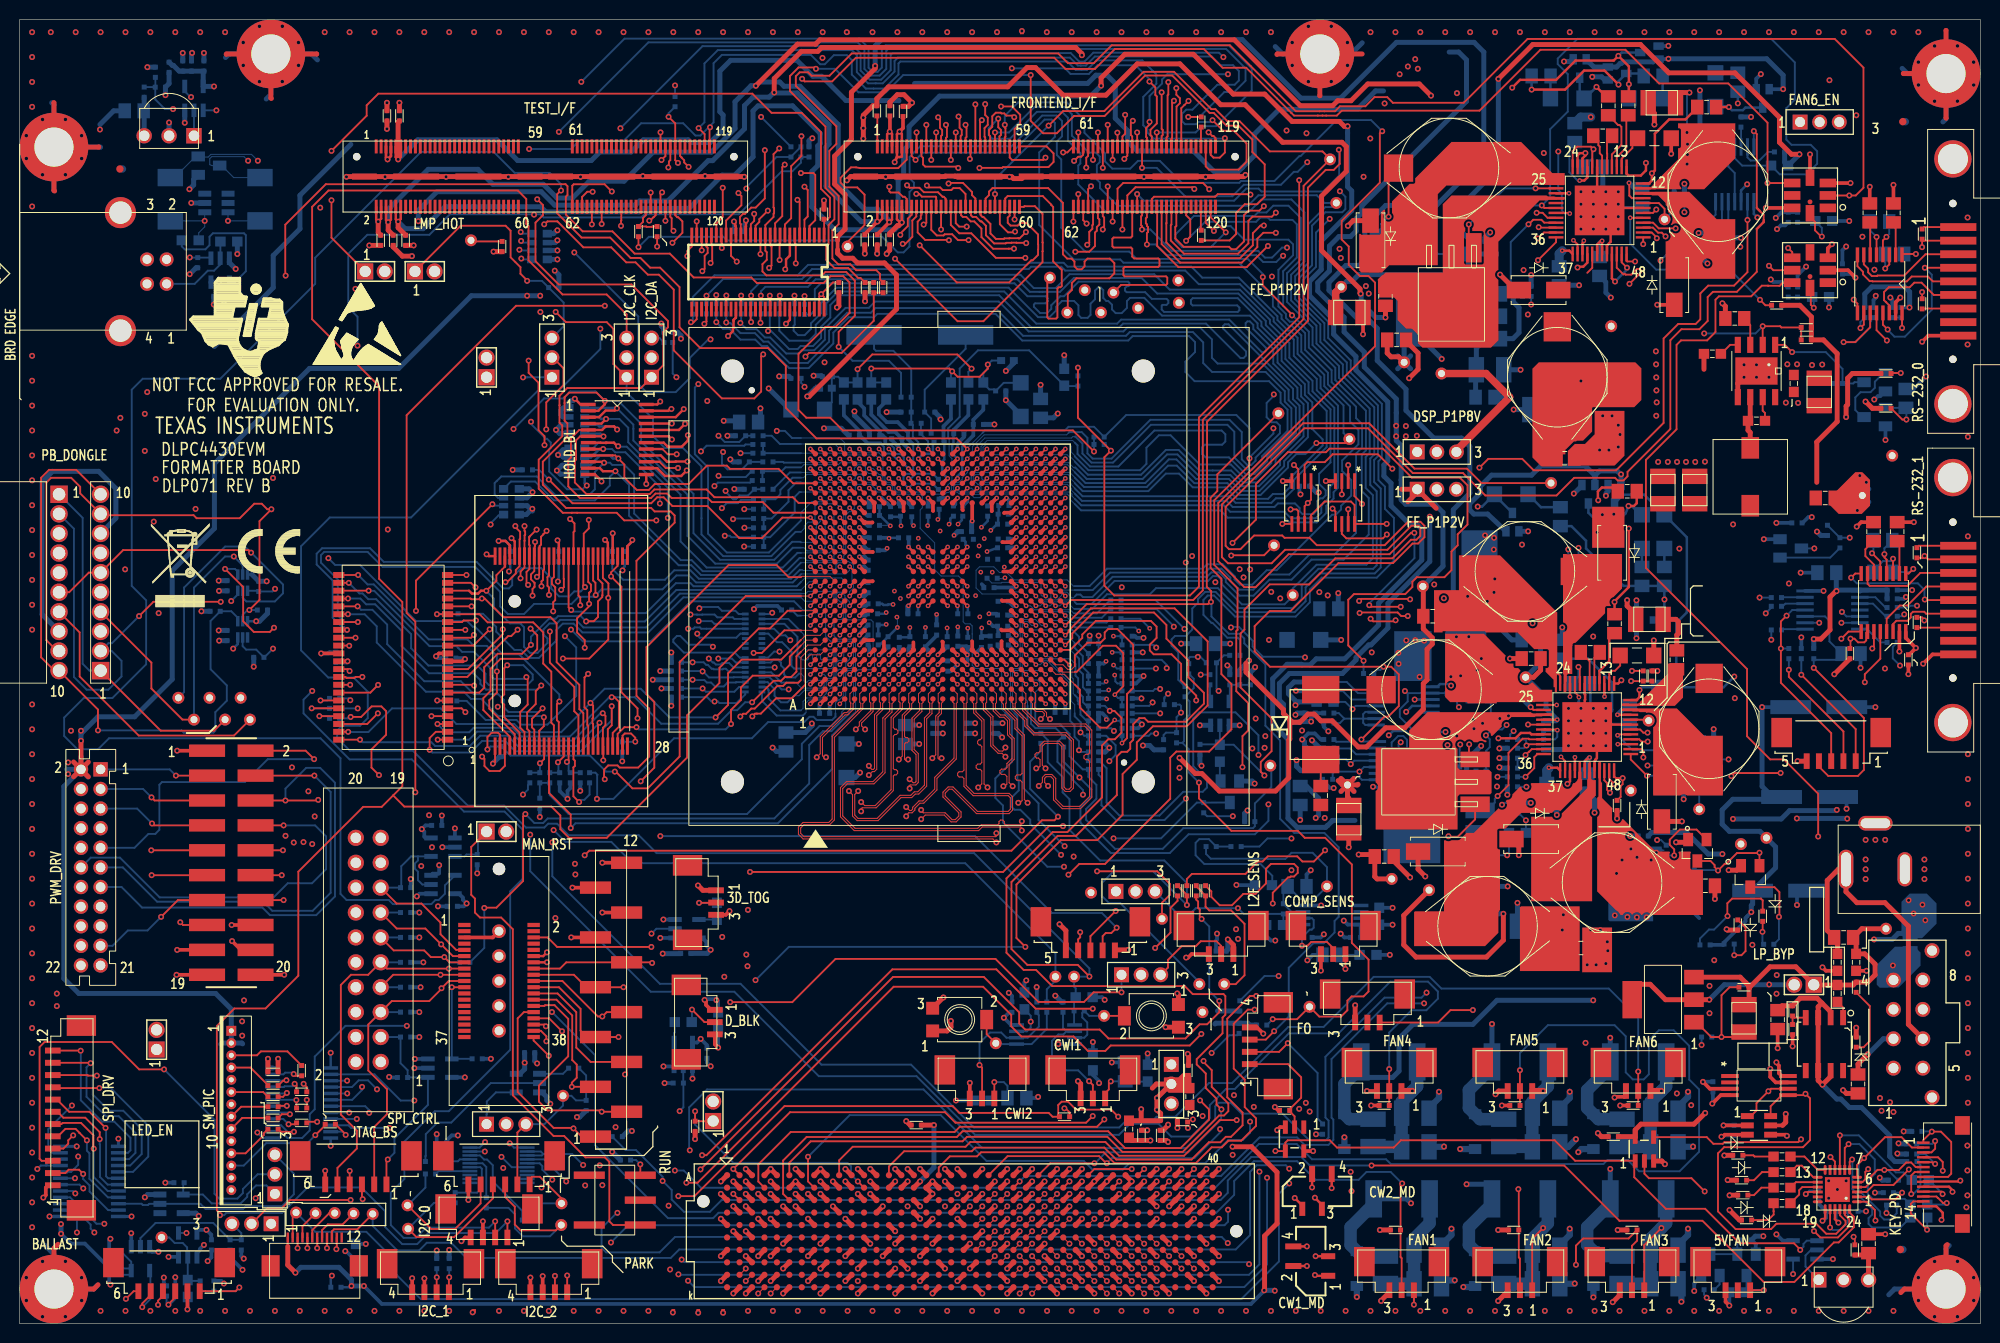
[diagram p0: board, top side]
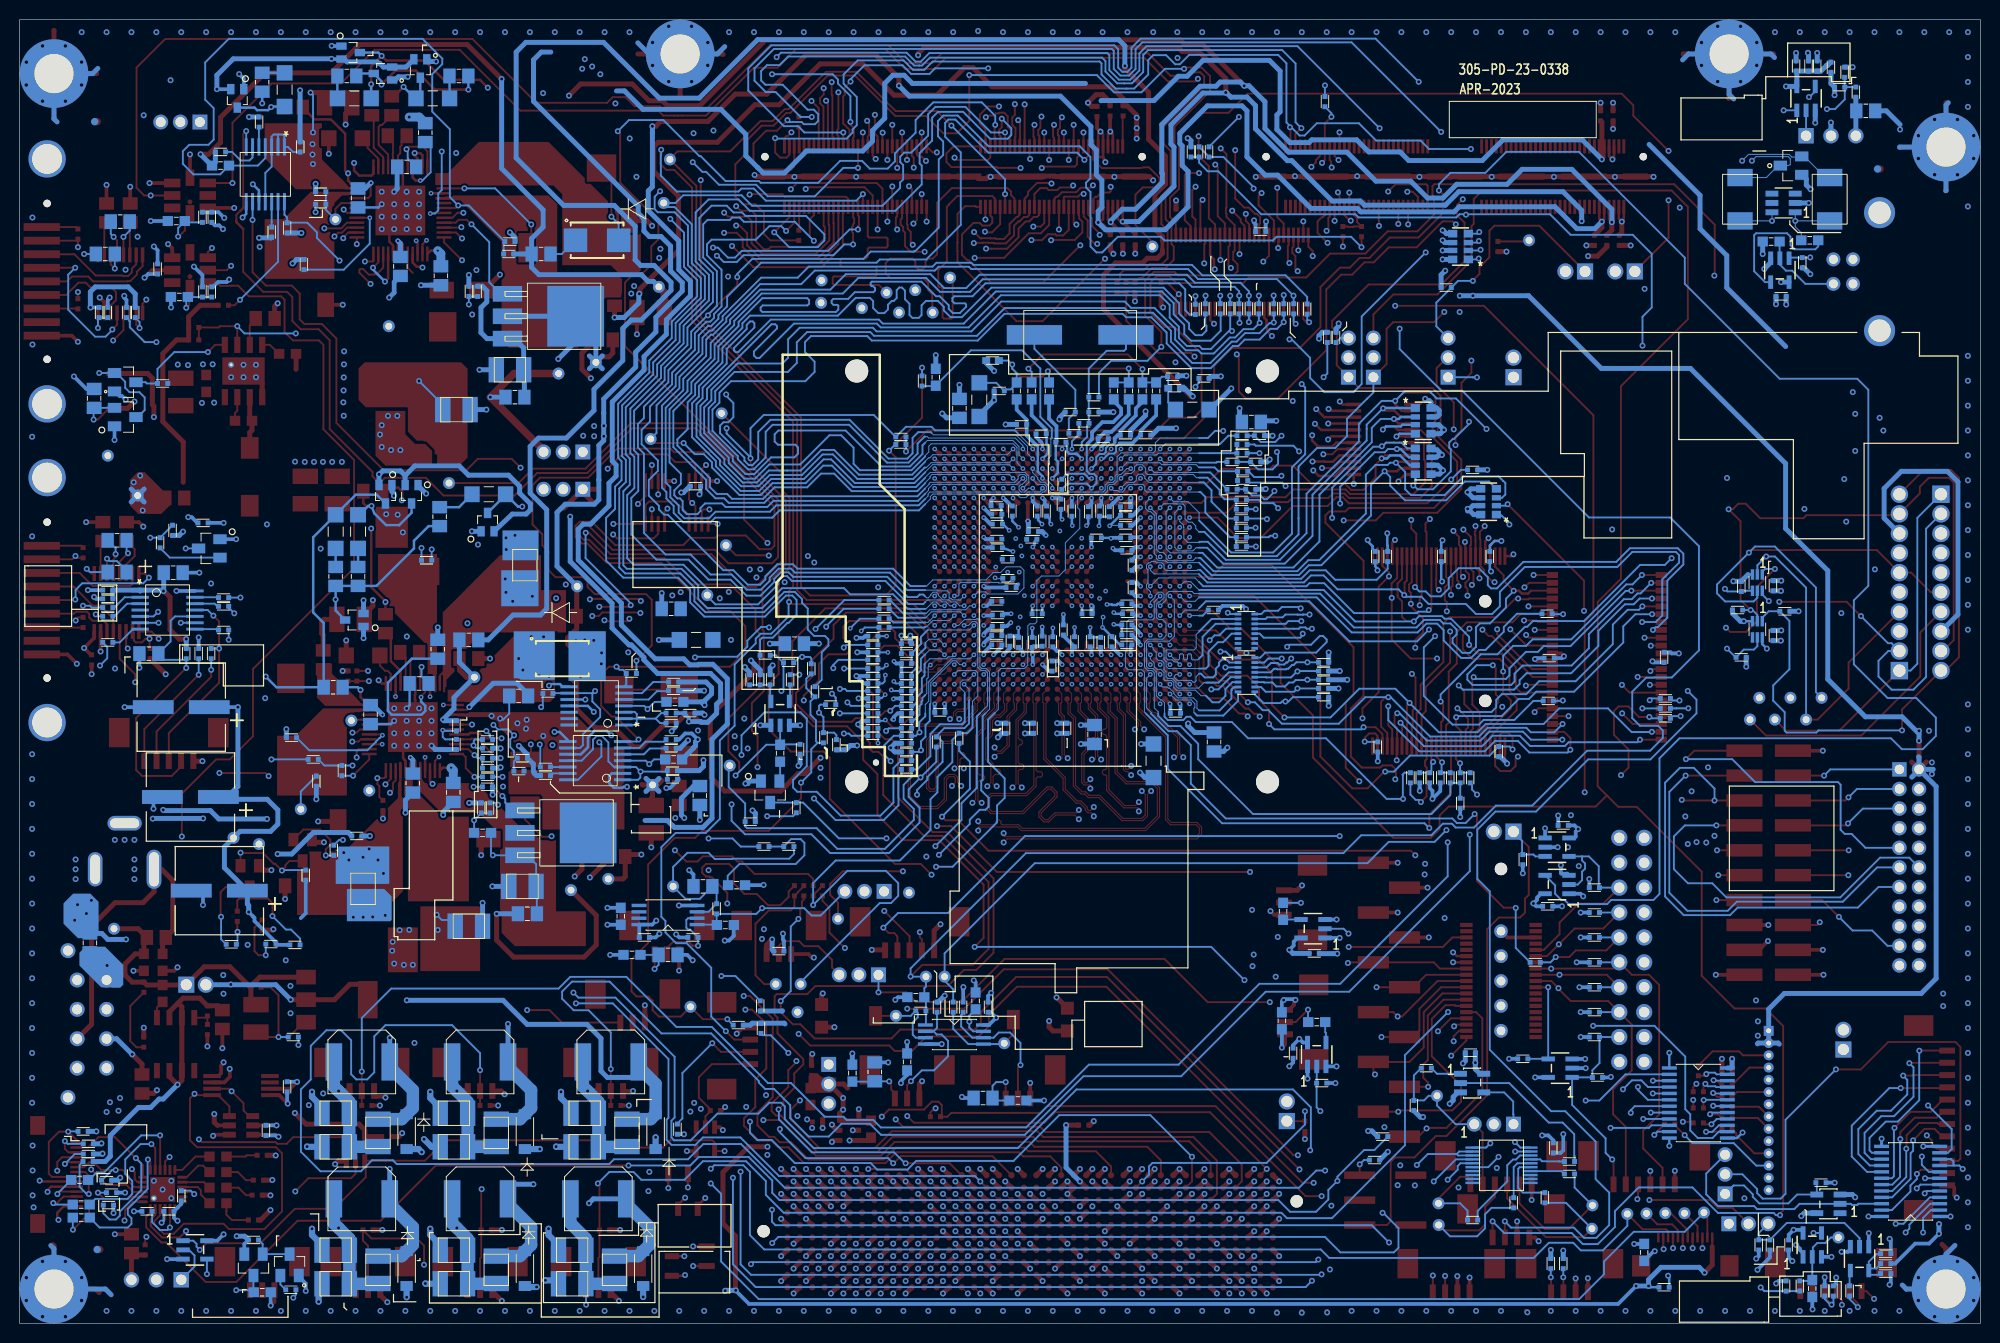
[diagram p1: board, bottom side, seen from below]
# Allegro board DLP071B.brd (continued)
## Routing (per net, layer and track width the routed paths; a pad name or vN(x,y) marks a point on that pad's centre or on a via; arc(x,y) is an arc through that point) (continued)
P5V_CONN:
  vias: v2(191.08,36.51)
P5V_IR: length 4
  BOTTOM w0.508: U1.3 12.7,123.65 C506.2 12.7,123.75 R508.1
P5V_IR_CONN: length 4.2
  TOP w0.508: U22.3 C42.2 188.4,6.97 R74.1
P12V: length 580.5
  TOP w0.203: U2.9 164.46,114.79 164.19,115.05 164.19,116.31 v1(164.16,116.34) ; U15.27 154.41,62.58 v2(154.13,62.87)
  TOP w0.254: U2.42 160.91,110.05 161.29,110.43 v1(161.42,110.43) 161.41,110.42 U2.43 ; U2.27 v1(158.04,115.29) ; U2.23 158.91,119.16 159.13,119.38 159.69,119.38 v2(159.71,119.4) 159.71,119.14 159.41,118.84 U2.22 ; U15.42 159.64,57.34 160.02,57.72 160.14,57.72 v1(160.14,57.72) ; U15.22 158.14,63.93 v1(158.14,63.93) ; U15.37 156.84,56.69 v1(155.99,56.69) ; U15.9 v1(162.98,62.08) ; U2.37 158.07,109.44 v1(157.35,109.44)
  TOP w0.381: J52.1 70.51,31.98 70.01,32.48 70.01,32.85 v2(69.87,33)
  TOP w0.508: R22.2 186.94,96.9 186.46,96.42 186.46,93.73 186.31,93.57 v2(186.31,92.46) ; v2(136.79,105.04) 136.72,105.11 136.72,105.53 132.8,109.45 132.8,115 135.32,117.53 135.32,120.04 134.88,120.49 128.83,120.49 125,124.32 122.52,124.32 118.35,128.49 114,128.49 110.81,125.3 106.43,125.3 103.62,128.11 103.27,128.11 103.26,128.11 102.75,128.11 100.79,126.15 88.64,126.15 87.44,124.95 R2.1 87.03,124.22 86.06,123.25 v2(86.06,123) v2(86.06,121.94) v2(86.06,120.87) ; v2(115.98,13.21) J63.C35 v2(115.98,11.94) ; J18.2 7.01,55.76 ; J18.2 5.5,57.27 ; J18.2 5.5,55.76 ; J18.2 7.01,57.27 ; J18.2 v2(6.26,59.44) ; v2(118.52,13.21) J63.C37 v2(117.25,11.94) ; Q5.4 164.71,33.24 164.71,34.23 165.07,34.59 166.32,34.59 167.89,33.02 Q5.2 v2(172.35,33.02) ; R16.2 v2(139.32,102.62)
  L03_SIG1 w0.508: J31.2 181.82,33.73 ; J31.2 181.82,35.36 ; J31.2 181.01,37.79 177.32,41.47 177.12,41.47 v2(176.64,41.96) ; J31.2 180.19,35.36 ; J31.2 180.19,33.73 ; v2(170.18,9.65) 170.18,15.32 169.06,16.44 169.06,22.5 v2(170.18,23.62) 170.18,30.85 v2(172.35,33.02)
  L05_SIG2 w0.508: v1(162.98,62.08) 164.38,62.08 166.21,63.91 173.17,63.91 174.22,62.87 v2(177.74,62.87) ; v2(170.18,23.62) 170.18,23.63 169.04,24.77 160.9,24.77 159.75,23.62 v2(158.12,23.62) 157.29,23.62 156.22,24.69 149.47,24.69 148.4,23.62 v2(144.78,23.62) 143.68,23.62 142.61,24.69 134.25,24.69 131.99,22.43 131.27,22.43 v2(131.2,22.5) ; 20.46,28.65 20.52,28.59 J35.2 ; J35.2 21.65,28.53 22.68,28.53 ; J35.2 J35.1 ; v2(170.18,9.65) 170.16,9.65 168.89,10.92 161.67,10.92 160.4,9.65 v2(158.12,9.65) 158.08,9.65 156.81,10.92 147.32,10.92 v2(146.05,9.65) ; v2(86.06,121.94) v2(86.06,120.87) 85.06,120.87 84.27,120.08 84.27,118.26 86.32,116.21 86.32,114.53 82.58,110.79 82.58,107.22 81.44,106.08 70.08,106.08 67.33,103.33 62.24,103.33 60.73,104.84 v2(53.1,104.84) v2(51.77,104.84)
  BOTTOM w0.381: C673.2 71.25,32.8 v2(71.07,32.98) 70.97,33.07 69.94,33.07 v2(69.87,33) ; C606.1 v2(177.74,62.87) ; DN500.2 v2(179.88,125.91) ; DN501.2 168.16,128.98 v2(168.19,129.01) ; 171.32,41.34 170.81,41.85 R691.1 ; R701.1 173.77,38.61 R700.1 173.85,38.85 176.05,41.05 176.05,41.35 176.2,41.5 176.2,41.52 v2(176.64,41.96)
  BOTTOM w0.508: 6.3,57.8 6.26,57.75 J18.2 ; v1(164.16,116.34) 164.19,116.34 164.76,115.77 C512.2 ; v2(179.88,125.91) 179.88,127.33 178.21,129.01 v2(168.19,129.01) ; v2(154.13,62.87) 151.7,65.3 149.26,65.3 148.13,64.17 R611.2 ; 178.44,54.08 177.82,53.46 174.74,53.46 173.66,52.38 173.66,50.93 174.4,50.19 177.52,50.19 TP43.1 179.11,48.6 179.11,46.48 C639.1 176.77,42.78 176.64,42.64 v2(176.64,41.96) ; 178.44,54.08 179.72,54.08 ; 178.44,54.08 177.74,54.78 v2(177.74,62.87) ; J18.2 6.26,56.45 6.98,55.72 ; J18.2 4.51,54.77 4.51,35.18 6.03,33.66 19.99,33.66 21.59,32.05 J35.1 J35.2 ; J18.2 4.83,56.52 4.83,56.52 ; C607.2 163.97,63.07 v1(162.98,62.08) ; 163.35,86.57 DN505.2 ; 163.35,86.57 v2(163.35,86.61) ; 163.35,86.57 162.95,86.96 161.16,86.96 160.68,86.49 ; 160.68,86.49 159.7,87.47 155.16,87.47 154.22,86.53 150.13,86.53 149,85.4 149,84.7 147.9,83.61 147.9,82.99 148.34,82.56 149.74,82.56 DN507.2 ; 160.68,86.49 DN506.2 ; DN508.2 v2(164.92,73.76) ; v1(161.42,110.43) 161.16,110.17 C518.2 ; DN503.2 160.58,128.17 DN502.2 162.89,128.17 163.27,128.54 163.39,128.54 163.54,128.69 166.62,128.69 166.91,128.98 DN501.2 ; v1(160.14,57.72) 160.14,57.72 159.89,57.47 C632.2 ; J31.2 173.88,34.54 v2(172.35,33.02) ; v2(139.32,102.62) 138.34,102.62 136.84,104.11 136.84,104.92 136.79,104.97 v2(136.79,105.04) ; v2(6.26,59.44) 6.26,60.15 7.98,61.88 11.73,61.88 15.56,65.71 15.56,76.79 19.87,81.09 19.87,87.72 29.57,97.42 38.66,97.42 46.08,104.84 v2(51.77,104.84) v2(53.1,104.84) ; C609.2 v2(157.35,71) ; 22.74,28.51 22.66,28.59 J35.2 ; J35.2 20.62,28.59 20.51,28.48
  BOTTOM w0.635: R747.2 169.16,8 170.18,9.02 v2(170.18,9.65) ; R749.2 145.03,8 146.05,9.02 v2(146.05,9.65) ; v2(158.12,23.62) 158.12,22.99 157.1,21.97 R719.2 ; R718.2 169.16,22.09 170.18,23.1 v2(170.18,23.62) ; v2(144.78,23.62) 144.78,22.99 143.76,21.97 R720.2 ; v2(158.12,9.65) 158.12,9.02 157.1,8 R748.2
  BOTTOM w0.914: C505.2 159.25,123.06 v2(160.26,123.06) ; v1(157.35,109.44) 157.04,109.12 C519.2 ; v1(155.99,56.69) 155.99,56.64 155.77,56.41 C633.2
  vias: v2(4.94,57.22) v2(4.94,56.04) v2(5.24,60.45) v2(6.26,60.45) v2(22.69,30.81) v2(22.7,29.35) v2(53.12,103.18) v2(130.52,21.88) v2(131.58,21.6) v2(137.32,105.82) v2(137.61,105.05) v2(166.91,99.16) v2(166.92,97.83) v2(166.94,96.5) v2(166.96,95.18) v2(166.94,92.59) v2(166.98,93.96) v2(169.04,23.46) v2(170.5,22.26) v2(172.38,34.43) v2(172.37,31.64) v2(178.46,34.57) v2(179.23,35.53) v2(179.21,33.63) v2(180.16,93.93) v2(181.41,93.9)
P12V_FIL: length 32
  TOP w0.508: R45.2 176.42,33.03 C36.1 ; R45.2 176.42,34.4 176.09,34.73 176.09,34.73 175.5,35.32 Q5.3 ; R45.2 176.47,34.29 178.55,36.38 181.18,36.38 J31.1 183.03,34.52 R47.1 187.03,34.52 R48.1 188.52,34.81 189.26,35.55 189.26,36.65 188.21,37.69 C33.2 187.32,39.07 FB1.2 187.91,40.26 TP45.1
P12V_IN: length 32.5
  TOP w0.508: J32.6 192.66,30.5 192.66,40.53 190.27,42.92 187.41,42.92 186.3,44.03 J22.P12V_IN 185.52,46.32 184.38,45.18 184.38,40.08 FB1.1 185.42,39.04 C32.2
VDD1_INDEX_SENSE: length 5.8
  TOP w0.193: v2(111.3,24.68) 111.2,24.68 111.1,24.59 111.1,23.86 110.72,23.48 J57.1
  BOTTOM w0.193: v2(111.3,24.68) 111.31,24.69 R771.1 112.8,24.66 C670.2
VDD2_INDEX_SENSE: length 6.2
  TOP w0.193: J55.1 v2(99.42,24.61)
  BOTTOM w0.193: C671.2 100.51,22.73 R772.1 100.76,24.23 100.38,24.61 v2(99.42,24.61)
VDD_TILT: length 6.6
  TOP w0.193: v2(183.83,110.87) 183.77,110.87 183.13,111.51 183.13,112.37 182.63,112.88 U3.8
  BOTTOM w0.193: v2(183.83,110.87) 183.83,111.76 183.16,112.43 R515.1 183.02,112.32 C508.2
3D_TOGGLE: length 238.3
  TOP w0.193: U11.E26 v1(84.66,89.2)
  L03_SIG1 w0.155: v2(12.76,89) 12.76,77.69 10.82,75.74 10.82,18.25 9.69,17.12 6.07,17.12 v2(5.97,17.02)
  L05_SIG2 w0.155: v2(64.45,39.76) 62.56,37.87 55.44,37.87 54.76,38.55 50.48,38.55 50.05,38.97 44.53,38.97 43.58,38.02 40.84,38.02 38.31,35.49 33.12,35.49 31.23,33.61 22.19,33.61 17.42,28.83 17.42,25.1 9.34,17.02 v2(5.97,17.02) ; v1(84.66,89.2) 84.66,90.03 82.03,92.67 78.97,92.67 77.7,93.94 71.33,93.94 70.55,93.15 69.7,93.15 67.85,95.01 64.12,95.01 63.86,94.75 60.51,94.75 59.92,95.34 55.28,95.34 54.79,94.84 15.23,94.84 14.12,95.95 12.62,95.95 12.07,95.4 12.07,89.7 v2(12.76,89)
  BOTTOM w0.193: U517.8 5.25,15.45 5.97,16.17 v2(5.97,17.02) ; U520.2 64.95,40.26 v2(64.45,39.76)
A1P8V: length 200.3
  TOP w0.381: 83.43,109.51 83.43,110.49
  TOP w0.508: 83.43,110.49 83.43,110.87 84.2,111.63 84.2,115.15 83.13,116.22 83.13,119.08 84.84,120.79 84.84,125.6 87.26,128.02 v2(87.26,128.29) ; v2(80.34,94.56) 80.53,94.56 89.44,103.47 89.44,106.96 88.21,108.18 85.45,108.18 84.98,108.66 83.95,108.66 83.43,109.17 83.43,109.51
  BOTTOM w0.508: v2(87.26,128.29) 87.26,130.33 87.9,130.96 124.71,130.96 130.68,124.99 134.75,124.99 140.44,130.68 148.36,130.68 149.35,129.69 149.35,118.9 144.5,114.05 139.34,114.05 137.22,111.92 137.22,108.49 136.65,107.93 135.28,107.93 133.56,106.2 133.56,105.39 136.6,102.35 137.63,102.35 138.48,101.5 138.48,98.22 141.41,95.29 141.41,93.13 144.23,90.31 147.07,90.31 147.93,89.46 147.93,84.7 146.24,83.01 146.24,72.9 146.88,72.26 149.67,72.26 152.21,69.72 R594.1 ; v2(80.34,94.56) 81.18,95.4 R558.1
A1P8V_SENSE: length 53.9
  TOP w0.254: U15.29 v1(156.83,61.58)
  TOP w0.508: C27.2 155.14,66.63 154.42,65.91 TP32.1
  L05_SIG2 w0.508: v2(130.14,63.07) 134.51,63.07 135.08,63.64 138.47,63.64 140.51,61.61 141.74,61.61 142.23,62.1 145.15,62.1 147.18,62.1 147.78,62.7 147.78,63.29 148.37,63.88 154.54,63.88 v1(156.83,61.58)
  BOTTOM w0.508: R610.1 156.73,61.48 v1(156.83,61.58) 155.7,62.72 155.7,63.83 TP32.1 155.14,67.44 R594.2 ; C610.2 130.47,63.4 v2(130.14,63.07) 130.14,63.51 129.42,64.23 129.42,64.86 129.99,65.43 R616.2
A_BLU_PWM: length 97
  TOP w0.193: v2(13.5,51) 13.7,50.8 J19.7
  TOP w0.254: U8.21 v2(66.52,91.8)
  L03_SIG1 w0.155: v2(30.1,51.71) 30.1,52.65 29.78,52.97 29.78,53.72 30.1,54.04 30.1,54.48 29.44,55.13 29.44,57.8 32.48,60.84 32.48,74.26 33.16,74.95 33.97,74.95 39.79,80.77 48.89,80.77 50.61,82.49 53.33,82.49 55,84.16 59.33,84.16 65.37,90.2 65.37,90.64 v2(66.52,91.8)
  L05_SIG2 w0.155: v2(13.5,51) 14.22,51.71 v2(30.1,51.71)
  BOTTOM w0.193: v2(13.5,51) 11.98,52.52 J18.5
A_GRN_PWM: length 97.5
  TOP w0.193: J19.5 13.76,53.34 v2(13.45,53.65)
  TOP w0.254: v2(67.74,93.27) 66.92,92.45 U8.22
  L03_SIG1 w0.155: v2(67.74,93.27) 66.92,92.45 66.33,92.45 64.94,91.05 64.94,90.26 59.2,84.52 54.14,84.52 53.31,83.69 51.06,83.69 49.46,82.09 40.31,82.09 37.73,79.52 36.7,79.52 32.07,74.88 32.07,60.92 29.09,57.95 29.09,54.64 v2(29.45,54.28)
  L05_SIG2 w0.155: v2(13.45,53.65) 24.36,53.65 24.98,54.28 v2(29.45,54.28)
  BOTTOM w0.193: J18.3 12.59,54.52 v2(13.45,53.65)
A_LED4_PWM: length 96.6
  TOP w0.193: J19.2 29.17,58.42 v2(30.04,57.56)
  TOP w0.254: U8.20 67.25,91.15 v2(67.88,91.77)
  L03_SIG1 w0.155: v2(30.04,57.56) 32.85,60.37 32.85,67.79 33.29,68.23 34.01,68.23 35.17,69.38 35.17,70.73 43.55,79.12 49.57,79.12 49.94,79.49 51.2,79.49 52.02,80.31 52.82,80.31 53.04,80.09 53.84,80.09 55.19,81.44 56.37,81.44 56.75,81.81 56.75,82.49 58.07,83.81 59.47,83.81 65.94,90.27 65.94,90.53 66.56,91.15 67.25,91.15 v2(67.88,91.77)
  BOTTOM w0.193: v2(30.04,57.56) 25.31,57.56 22.98,55.22 14.52,55.22 14.25,54.95 14.25,50.35 13.83,49.93 13.13,49.93 11.72,48.51 J18.9
A_LED5_PWM: length 105.2
  TOP w0.193: J19.4 v2(30.06,55.88)
  TOP w0.254: U8.19 66.21,90.5 v2(66.54,90.17)
  L03_SIG1 w0.155: v2(30.06,55.88) 35.07,60.89 35.07,64.98 34.36,65.69 34.36,67.71 35.71,69.06 35.71,70.78 43.26,78.34 46.88,78.34 47.35,77.86 48.25,77.86 48.85,78.46 49.54,78.46 50.14,79.06 54.88,79.06 57.1,81.28 57.1,82.35 58.09,83.33 59.52,83.33 66.36,90.17 v2(66.54,90.17)
  BOTTOM w0.193: v2(30.06,55.88) 31.72,54.22 31.72,43.92 29.89,42.09 25.77,42.09 24.84,43.02 14.02,43.02 10.52,46.51 J18.11
A_LED6_PWM: length 117.8
  TOP w0.193: J19.6 v2(27.11,53.34) 30.39,53.34 v2(30.46,53.4)
  TOP w0.254: U8.18 65.7,89.84 66.1,89.44 67.54,89.44 68.16,90.06 v2(68.16,90.6)
  L03_SIG1 w0.155: v2(30.46,53.4) 30.46,53.83 35.59,58.97 35.59,67.95 36.2,68.55 36.2,70.77 43.41,77.99 46.62,77.99 47.09,77.51 48.57,77.51 49.13,78.08 49.79,78.08 50.34,78.63 54.94,78.63 57.46,81.14 57.46,82.21 58.22,82.98 59.67,82.98 66.27,89.57 67.13,89.57 v2(68.16,90.6)
  BOTTOM w0.193: v2(27.11,53.34) 27.11,54.56 29.22,56.67 30.65,56.67 32.16,55.15 32.16,43.56 30.25,41.65 25.53,41.65 24.76,42.42 12.48,42.42 10.39,44.51 J18.13
A_LED7_PWM: length 114.6
  TOP w0.193: 65.57,89.19 66.1,88.66 v2(67.02,88.66) ; J19.11 v2(13.46,45.72)
  TOP w0.254: 65.57,89.19 U8.17
  L03_SIG1 w0.155: v2(67.02,88.66) 65.96,88.66 59.91,82.62 59.59,82.62 55.16,78.2 50.52,78.2 50.02,77.7 49.37,77.7 48.84,77.16 46.83,77.16 46.36,77.64 43.55,77.64 36.82,70.9 36.82,68.45 35.94,67.58 35.94,57.16 31.05,52.27 31.05,51.83 30.34,51.12 28.5,51.12 v2(27.12,49.74)
  L05_SIG2 w0.155: v2(27.12,49.74) 27.12,48.84 27.52,48.44 27.52,42.93 27.17,42.58 26.45,42.58 23.31,45.72 v2(13.46,45.72) 13.46,41.47 14.05,40.87 15.2,40.87 15.93,41.61 16.6,41.61 16.98,41.24 16.98,40.25 16.13,39.4 12.8,39.4 11.68,40.52 J18.17
A_LED8_PWM: length 102.3
  TOP w0.193: J19.13 16.14,43.18 v2(14.43,41.47)
  TOP w0.254: U8.16 65.39,88.54 66.04,87.89 66.89,87.89 66.92,87.92 v2(68.13,87.92)
  L03_SIG1 w0.155: v2(27.96,49.05) 29.47,50.56 30.28,50.56 31.41,51.69 31.41,52.12 37.17,57.89 37.17,70.76 43.7,77.29 46.1,77.29 46.75,76.63 48.91,76.63 49.6,77.32 50.25,77.32 50.7,77.76 55.3,77.76 58.05,80.51 58.05,80.59 59.73,82.27 60.06,82.27 62.7,84.9 64.11,84.9 66.51,87.3 66.51,87.5 66.93,87.92 v2(68.13,87.92)
  L05_SIG2 w0.155: v2(14.43,41.47) 15.19,42.23 27.32,42.23 27.96,42.87 v2(27.96,49.05)
  BOTTOM w0.193: v2(14.43,41.47) 13.04,40.08 11.04,40.08 9.47,38.52 J18.19
A_RED_PWM: length 91.1
  TOP w0.193: J19.3 v2(15.94,55.88)
  TOP w0.254: v2(66.48,93.28) 66.36,93.28 66.17,93.1 U8.23
  L03_SIG1 w0.155: v2(66.48,93.28) 61.96,93.28 60.17,91.49 59.73,91.49 58.45,90.21 58.45,85.23 58.09,84.87 53.82,84.87 53.07,84.12 50.88,84.12 49.3,82.55 40.16,82.55 37.55,79.95 36.64,79.95 31.71,75.01 31.71,61.2 27.77,57.27 v2(27.77,56.72)
  L05_SIG2 w0.155: v2(27.77,56.72) 26.94,55.88 v2(15.94,55.88)
  BOTTOM w0.193: v2(15.94,55.88) 15.3,56.52 J18.1
A_SPARE_1: length 37.4
  TOP w0.193: J33.2 4.65,15.33 4.99,15.67 6.06,15.67 6.39,15.34 6.39,15.33 v2(6.48,15.24)
  L03_SIG1 w0.155: J18.18 5.22,39.48 5.22,35.59 7.16,33.65 7.16,27.51 6.38,26.73 6.38,20.94 4.86,19.42 4.86,16.79 6.41,15.24 v2(6.48,15.24)
  BOTTOM w0.193: v2(6.48,15.24) 6.48,14.72 7.13,14.07 7.13,13.45 9.02,11.55 U517.23
A_SPARE_2: length 99.5
  TOP w0.193: 65.27,87.89 65.9,87.26 v2(67.15,87.26)
  TOP w0.254: 65.27,87.89 U8.15
  L03_SIG1 w0.155: v2(29.84,48.9) 31.76,50.82 31.76,51.98 37.53,57.74 37.53,70.62 43.84,76.94 45.83,76.94 46.66,76.12 48.06,76.12 49.15,75.02 49.8,75.02 50.35,75.57 50.35,76.31 51.39,77.35 55.5,77.35 58.4,80.25 58.4,80.45 59.87,81.91 60.21,81.91 62.85,84.55 64.25,84.55 66.96,87.26 v2(67.15,87.26)
  L05_SIG2 w0.155: J18.22 7.23,37.49 12.87,37.49 13.68,36.68 16.43,36.68 21.26,41.52 27.66,41.52 29.84,43.7 v2(29.84,48.9)
A_SPARE_3: length 105.8
  TOP w0.254: v2(68.04,87.01) 67.48,86.45 65.84,86.45 65.04,87.24 U8.14
  L03_SIG1 w0.155: v2(68.04,87.01) 65.89,84.86 65.07,84.86 64.26,84.05 62.93,84.05 60.43,81.55 60,81.55 58.76,80.31 58.76,80 55.75,76.99 52.76,76.99 52.18,76.4 52.18,75.91 52.47,75.61 52.47,75.11 52.91,74.67 52.91,73.99 51.47,72.56 49.67,72.56 48.45,73.79 48.45,74.74 47.5,75.68 45.06,75.68 37.97,68.59 37.97,56.14 30.13,48.31 29.43,48.31 28.95,48.79 v2(28.95,49.1)
  L05_SIG2 w0.155: J18.20 7.23,39.49 11.69,39.49 14,37.19 16.09,37.19 20.78,41.87 27.54,41.87 28.95,43.28 v2(28.95,49.1)
A_SSP0_CLK: length 66.4
  TOP w0.193: v2(119.06,42.68) R38.2 119.06,43.7 118.8,43.97 118.78,43.97 118.38,44.37 118.38,44.39 R37.2 ; U11.AD4 v1(104.66,66.2)
  BOTTOM w0.102: v1(104.66,66.2) 104.27,66.59 102.5,66.59 102.27,66.36 102.27,64 102.81,63.46 102.81,63
  BOTTOM w0.193: 102.81,63 102.81,60.75 103.35,60.21 R680.2 104.87,59.51 104.87,57.25 106.39,55.73 106.39,54.17 107.09,53.47 107.09,50.34 110.21,47.22 116.76,47.22 119.06,44.92 v2(119.06,42.68) 115.58,46.16 111.63,46.16 110.38,44.91 110.38,43.61 111.12,42.88 112.27,42.88 120.33,34.81 TP46.1
A_SSP0_RXD: length 24.3
  TOP w0.102: U11.AD5 v1(104.66,67.2)
  L05_SIG2 w0.102: 107.63,67.51 107.45,67.69 105.15,67.69 v1(104.66,67.2)
  L05_SIG2 w0.155: 107.63,67.51 108.01,67.13 108.01,66.25 110.31,63.96 110.31,63.47 110.62,63.16 112.42,63.16 113.64,64.39 115.8,64.39 117.88,62.31 v2(118.47,62.31)
  BOTTOM w0.193: R672.1 116.69,60.02 116.93,60.26 R671.1 118.01,61.85 v2(118.47,62.31) 118.47,62.99 118.34,63.12 R625.1
A_SSP0_TXD: length 52.3
  TOP w0.193: U11.AB7 v1(102.66,69.2)
  L03_SIG1 w0.155: v2(120.18,67.99) 120.55,67.99 122.47,66.07 122.82,66.07 123.85,65.04 123.85,59.56 124.7,58.71 124.7,58.24 125.65,57.28 125.65,57.17 125.69,57.14 125.69,56.46 125.66,56.44 125.66,56.21 125.02,55.57 125.02,54.31 126.31,53.02 126.31,51.55 129.73,48.14 v2(129.73,46.23)
  L05_SIG2 w0.102: 107.3,72.25 106.95,72.59 105.5,72.59 105.27,72.36 105.27,72.25 104.83,71.81 104.5,71.81 104.49,71.81 104.18,71.81 103.96,71.59 103.5,71.59 103.19,71.28 103.19,69.72 102.66,69.2 v1(102.66,69.2)
  L05_SIG2 w0.155: v2(120.18,67.99) 119.62,68.56 118.13,68.56 117.48,69.21 117.48,70.03 115.67,71.84 107.88,71.84 107.47,72.25 107.3,72.25
  BOTTOM w0.193: R623.1 119.25,67.84 119.4,67.99 v2(120.18,67.99) 120.44,67.99 R621.1
ADC_CSZ: length 196.2
  TOP w0.193: TP64.1 34.45,9.6 32.06,9.6 31.85,9.39 J54.10
  L03_SIG1 w0.155: v2(129.5,15.78) 133.42,15.78 141.04,23.39 141.04,24.13 141.83,24.92 141.83,40.39 140.54,41.68 139.77,41.68 134.21,47.24 130.5,47.24 130.33,47.07 130.33,45.98 129.98,45.63 129.48,45.63 129.13,45.98 129.13,47.76 129.13,47.76 129.13,48.12 126.14,51.12 125.88,51.37 125.88,52.84 124.66,54.06 124.66,55.83 125.31,56.47 125.31,56.58 125.33,56.61 125.33,56.99 124.34,57.98 124.34,58.34 123.49,59.19 123.49,64.78 122.64,65.64 122.15,65.64 121.01,66.78 120.51,66.78 119.21,68.08 119.21,69.59 v2(117.73,71.07)
  BOTTOM w0.193: TP64.1 36.01,9.94 38.51,7.44 40.75,7.44 41.53,8.22 44.01,8.22 45.56,6.67 66.41,6.67 67.28,7.54 124.05,7.54 125.5,9 125.5,15.45 126.18,16.13 129.15,16.13 v2(129.5,15.78) ; v2(117.73,71.07) 117.73,71.12 115.95,72.9 R597.1
ADC_RST/COMP_PWM: length 207.5
  TOP w0.193: J54.2 27.85,10.96 TP55.1
  L03_SIG1 w0.155: v2(129.5,14.27) 129.76,14.53 132.91,14.53 141.47,23.09 141.47,23.95 142.21,24.69 142.21,41.46 140.36,43.31 138.75,43.31 137.39,44.68 137.39,45.29 133.21,49.47 v2(129.73,49.47) 126.75,52.45 126.75,53.23 125.37,54.6 125.37,55.32 126.02,55.96 126.02,56.29 126.04,56.31 126.04,57.28 126.01,57.32 126.01,57.49 125.77,57.74 125.77,57.77 125.05,58.49 125.05,64.35 121.93,67.47 121.93,67.94 119.02,70.85 v2(118.82,70.85)
  BOTTOM w0.193: R694.2 126.45,48.64 127.28,49.47 v2(129.73,49.47) ; R596.1 115.87,73.79 118.81,70.85 v2(118.82,70.85) ; TP55.1 30.16,9.34 35.36,9.34 38.39,6.31 38.39,5 40.92,2.47 124.61,2.47 128.45,6.31 128.45,13.22 v2(129.5,14.27)
ADC_SCLK: length 162.5
  TOP w0.193: v2(120.54,29.52) 119.36,28.35 111.29,28.35 110.74,27.79 108.97,27.79 107.5,29.27 102.18,29.27 101.14,30.3 101.14,31.47 98.28,34.34 89.15,34.34 69.15,14.34 v2(68.01,14.34) ; J54.4 28.85,9.91 TP56.1
  L03_SIG1 w0.155: v1(115.27,70.91) 115.27,68.22 113.09,66.04 113.09,62.76 113.4,62.46 113.4,56.9 112.45,55.95 112.45,53.19 120.55,45.08 120.55,42.09 119.97,41.5 119.97,41.01 120.28,40.71 120.28,38.99 121.96,37.3 121.96,33.65 121.62,33.31 121.62,30.61 v2(120.54,29.52)
  L05_SIG2 w0.155: TP56.1 30.18,11.1 31.76,9.52 36.06,9.52 37.54,8.03 39.77,8.03 41.9,10.16 46.01,10.16 47.91,8.26 55.96,8.26 61.39,13.69 67.36,13.69 v2(68.01,14.34)
  BOTTOM w0.193: R598.1 114.3,71.88 v1(115.27,70.91)
ADC_SDIN: length 109.8
  TOP w0.193: v2(109.46,32.1) 103.64,32.1 99.62,36.12 89.02,36.12 70.06,17.15 v2(69.61,17.15) ; TP57.1 31.59,11.25 29.85,9.51 J54.6
  L03_SIG1 w0.155: J21.1 112.66,43.23 112.66,39.75 111.17,38.26 111.17,34.52 109.46,32.81 v2(109.46,32.1)
  L05_SIG2 w0.155: TP57.1 33.18,10.21 36.7,10.21 37.55,11.06 41.24,11.06 41.89,11.71 49.99,11.71 52.71,9 55.67,9 61.22,14.55 64.02,14.55 66.45,16.99 69.45,16.99 v2(69.61,17.15)
ADC_SDO: length 106
  TOP w0.193: J54.8 30.85,9.51 31.44,10.1 32.95,10.1 TP58.1 ; v2(112.39,33.77) 109.55,33.77 108.57,32.79 103.93,32.79 99.54,37.17 83.22,37.17 78.81,32.77 v2(72.48,32.77)
  L05_SIG2 w0.155: TP58.1 33.74,11.21 32.43,12.52 32.43,15.4 34.88,17.85 45.41,17.85 46.74,19.18 56.99,19.18 58.67,20.86 64.38,20.86 66.86,23.33 68.62,23.33 72.48,27.19 v2(72.48,32.77)
  BOTTOM w0.193: J29.1 v2(112.39,33.77)
AFE_CLK: length 8.1
  TOP w0.193: U11.AD12 v1(104.66,74.2)
  BOTTOM w0.102: R579.2 99.16,75.54 100.13,75.54 100.18,75.59 104.02,75.59 104.19,75.42 104.19,74.31 104.3,74.2 v1(104.66,74.2)
AFE_RSTZ: length 187.3
  TOP w0.193: R9.1 63.12,109.8 63.13,109.8 v2(63.13,109.79) ; v2(118.99,110.44) 119.4,110.86 119.4,112.62 118.99,113.04 J2.108 ; U11.AC12 v1(103.66,74.2) ; v2(126.81,106.74) 126.81,105.9 129.79,102.92 v2(129.79,102.83)
  BOTTOM w0.102: v1(103.66,74.2) 104.06,73.81 104.83,73.81 104.98,73.96 105.09,73.96 105.19,74.06 105.19,74.54 105.39,74.73 106.33,74.73 106.41,74.81 107.63,74.81
  BOTTOM w0.178: 129.84,102.83 v2(129.79,102.83)
  BOTTOM w0.193: v2(126.81,106.74) 126.81,107.06 125.27,108.59 113.93,108.59 113.19,109.34 108.79,109.34 108.73,109.39 108.64,109.39 106.25,111.78 106.25,118.74 105.8,119.19 105.8,120.57 106.33,121.1 106.33,122.66 105.77,123.22 104.3,123.22 101.17,120.09 91.87,120.09 90.78,119 90.78,116.82 91.22,116.37 91.22,115.88 90.77,115.43 90.77,109.86 90.16,109.26 89.57,109.26 87.98,110.85 83.59,110.85 83.22,110.47 72.16,110.47 71.79,110.85 64.18,110.85 v2(63.13,109.79) ; v2(118.99,110.44) 120.93,112.38 126.12,112.38 126.55,112.81 127.33,112.81 127.56,112.57 129.83,112.57 130.28,112.13 130.28,108.73 128.88,107.34 128.88,103.79 131.5,101.17 131.5,99.56 133.83,97.23 133.83,96.01 136.32,93.51 136.32,92.35 136.93,91.74 136.93,89.35 136.32,88.74 136.32,80.64 134.11,78.43 131.56,78.43 129.52,76.4 127.39,76.4 125.84,74.85 124.38,74.85 123.5,75.74 123.5,76.07 122.58,76.99 121.31,76.99 120.91,76.59 111.23,76.59 109.45,74.81 107.63,74.81
ALF_CLAMP: length 96.1
  TOP w0.193: v2(121.82,111.44) 120.99,112.27 J2.116 ; U11.AB12 v1(102.66,74.2)
  BOTTOM w0.102: v1(102.66,74.2) 102.24,74.62 101.47,74.62 101.26,74.41 98.18,74.41 97.56,75.02 97.56,76.83 97.91,77.18 99.36,77.18 99.94,76.6 100.68,76.6 101.43,75.84 106.86,75.84 107.48,75.22 107.63,75.22
  BOTTOM w0.193: 107.63,75.22 109.13,75.22 110.91,76.99 120.67,76.99 121.12,77.44 122.71,77.44 123.93,76.22 123.93,75.89 124.46,75.36 125.73,75.36 127.2,76.83 128.22,76.83 133.88,82.49 134.25,82.49 134.79,83.03 134.79,83.4 135.82,84.44 135.82,86.03 134.9,86.96 134.9,88.02 136.56,89.69 136.56,91.14 135.71,92 135.71,93.54 133.45,95.79 133.45,96.98 131.12,99.31 131.12,101.02 129.95,102.19 129.56,102.19 129.17,102.58 129.17,102.97 128.4,103.74 128.4,107.48 129.9,108.97 129.9,110.08 129.42,110.56 124.9,110.56 123.53,111.93 122.31,111.93 v2(121.82,111.44)
ALF_COAST: length 101.7
  TOP w0.193: J2.118 121.49,112.84 v2(123.03,111.3) ; U11.AC11 v1(103.66,73.2)
  BOTTOM w0.102: 107.63,74.16 107.49,74.02 107.32,74.02 107.06,74.28 107.06,74.36 106.83,74.59 106.5,74.59 106.27,74.36 106.27,74.25 105.83,73.81 105.22,73.81 105.02,73.6 104.51,73.6 104.11,73.2 v1(103.66,73.2)
  BOTTOM w0.193: 107.63,74.16 107.82,74.35 108.2,74.35 108.45,74.1 109.43,74.1 111.49,76.16 121.11,76.16 121.56,76.61 122.36,76.61 123.03,75.94 123.03,75.63 124.43,74.24 125.85,74.24 127.49,75.87 129.73,75.87 131.77,77.91 135.05,77.91 137.61,80.47 137.61,84.2 136.9,84.91 136.9,88.63 137.33,89.06 137.33,93.1 134.2,96.23 134.2,97.48 131.88,99.8 131.88,101.6 129.28,104.2 129.28,107.14 130.67,108.53 130.67,112.77 129.42,114.02 127.87,114.02 127.18,113.33 126.31,113.33 125.95,112.97 119.78,112.97 117.92,111.11 117.92,110.46 118.59,109.79 121.5,109.79 123.01,111.3 v2(123.03,111.3)
ALF_CSYNC: length 126.8
  TOP w0.193: J2.49 v2(99.49,121.49) ; U11.AE11 v1(105.66,73.2)
  BOTTOM w0.102: 107.63,72.89 107.54,72.89 106.84,73.59 106.5,73.59 106.11,73.2 v1(105.66,73.2)
  BOTTOM w0.193: 107.63,72.89 109.42,72.89 110.91,74.38 115.29,74.38 115.92,75 122.22,75 124.25,72.97 129.85,72.97 130.78,73.9 130.78,75.27 132.48,76.98 138.06,76.98 138.42,77.34 138.42,84.88 137.76,85.54 137.76,88.23 138.17,88.64 138.17,93.46 134.97,96.66 134.97,97.82 132.68,100.12 132.68,101.92 130.11,104.49 130.11,106.83 131.44,108.17 131.44,112.13 133.19,113.88 133.88,113.88 TP2.1 133.1,114.3 132.31,115.09 126.36,115.09 125.29,114.01 120.98,114.01 120.98,114.01 112,114.01 110.2,115.81 110.2,116.38 109.88,116.7 109.88,118.17 110.18,118.47 110.18,119.03 109.78,119.43 109.07,119.43 107.33,121.17 107.33,123.35 106.58,124.1 103.53,124.1 100.92,121.49 v2(99.49,121.49)
ALF_HSYNC: length 126.5
  TOP w0.193: U11.AD11 v1(104.66,73.2) ; v2(99.82,122.9) 99.82,122.02 100.1,121.74 100.1,121.24 99.94,121.09 99.94,120.12 J2.51
  BOTTOM w0.102: 107.63,73.58 107.41,73.8 106.1,73.8 105.91,73.6 105.51,73.6 105.11,73.2 v1(104.66,73.2)
  BOTTOM w0.193: 107.63,73.58 107.82,73.39 109.34,73.39 111.69,75.74 121.22,75.74 121.72,76.23 122.21,76.23 122.61,75.84 122.61,75.42 124.68,73.35 129.03,73.35 129.86,74.18 TP24.1 129.86,74.96 132.29,77.39 137.37,77.39 138.04,78.05 138.04,84.49 137.3,85.22 137.3,88.38 137.71,88.79 137.71,93.32 134.58,96.45 134.58,97.66 132.28,99.96 132.28,101.77 129.69,104.36 129.69,106.97 131.05,108.33 131.05,113.33 129.73,114.66 126.67,114.66 125.51,113.49 110.68,113.49 107.98,116.19 107.98,118.11 108.2,118.33 108.2,119.39 106.93,120.66 106.93,123 106.32,123.6 103.76,123.6 101.02,120.85 99.22,120.85 98.85,121.23 98.85,121.92 v2(99.82,122.9)
ALF_VSYNC: length 110
  TOP w0.193: U11.AF11 v1(106.66,73.2) 107.26,73.8 119.71,73.8 120.69,74.78 120.69,92.18 130.97,102.45 130.97,116.04 TP1.1 133.67,118.79 132.9,119.56 127.52,119.56 124.43,122.65 123.19,122.65 121.97,123.87 121.56,123.87 117.75,127.68 114.64,127.68 110.64,123.67 106.44,123.67 v2(104.96,122.19) ; J2.50 v2(99.49,115.21)
  BOTTOM w0.193: v2(104.96,122.19) 99.49,116.72 v2(99.49,115.21)
BLU_LED_EN: length 161
  L03_SIG1 w0.155: v2(30.66,113.82) 26.19,109.35 26.19,86.74 26.99,85.93 26.99,62.59 20.73,56.32 20.73,13.3 21.53,12.5 22.83,12.5 23.74,13.42 24.35,13.42 25.07,12.69 25.07,10.74 J40.1
  L05_SIG2 w0.155: v2(30.66,113.82) 36.16,113.82 36.54,114.2 40.36,114.2 45.08,109.47 46.96,109.47 47.91,110.42 v2(51.15,110.42) ; v2(5.64,14.8) 6.01,14.44 12.76,14.44 15.47,11.73 24.08,11.73 J40.1
  BOTTOM w0.193: RN500.3 51.32,110.25 v2(51.15,110.42) ; U517.7 v2(5.64,14.8)
BLU_PWM: length 43.3
  TOP w0.193: U11.C20 v1(82.66,83.2)
  TOP w0.254: U8.4 59.35,91.8 v2(59.82,92.27)
  BOTTOM w0.102: 79.69,78.6 82.62,78.6 83.06,79.04 83.06,82.81 v1(82.66,83.2)
  BOTTOM w0.193: v2(59.82,92.27) 61.17,92.27 62.08,91.36 62.08,89.88 67.41,84.55 67.41,79.77 70.07,77.11 77.85,77.11 79.34,78.6 79.69,78.6
  BOTTOM w0.254: v2(59.82,92.27) 59.31,92.27 59.1,92.47 RN501.2
BT656_A_CLK: length 100.3
  TOP w0.193: v2(125.55,115.15) 125.5,115.2 122.21,115.2 121.94,114.93 115.71,114.93 115.49,114.71 J2.94 ; U4.5 80.05,111.03 80.05,112.59 80.39,112.93 80.39,115.63 v2(80.05,115.96)
  L03_SIG1 w0.155: v2(80.05,115.96) 80.05,114.33 79.59,113.87 78.83,113.87 78.32,114.38 78.32,117.02 79,117.7 79,121.76 79.54,122.3 79.54,123.11 85.67,129.24 105.11,129.24 105.72,128.62 118.19,128.62 123.84,122.97 123.84,122.96 125.06,121.74 125.06,121.31 124.8,121.06 124.17,121.06 122.27,122.95 122.27,123.07 121.01,124.33 120.32,124.33 120.02,124.03 120.02,123.57 121.43,122.15 121.57,122.15 121.96,121.77 121.96,120.4 122.31,120.04 123.79,120.04 123.81,120.05 124.11,120.05 124.14,120.04 124.66,120.04 125.63,119.08 125.63,115.78 125.56,115.71 125.56,115.17 v2(125.55,115.15)
BT656_A_D0: length 100
  TOP w0.193: J2.105 118.49,123.97 118.81,124.29 118.81,124.29 v2(119.23,124.71) ; v2(68.11,108.88) 68.11,109.4 68.55,109.84 68.55,111.01 U4.28
  L03_SIG1 w0.155: v2(68.11,108.88) 68.59,108.88 68.8,108.68 70.04,108.68 70.3,108.94 70.88,108.94 71.14,108.68 72.05,108.68 72.72,109.35 73.57,109.35 74.17,108.74 74.17,107.89 73.23,106.95 71.77,106.95 70.59,105.77 67.91,105.77 67.37,105.23 67.37,104.44 68.11,103.71 72.5,103.71 72.76,103.96 72.76,105.38 73.09,105.71 74.43,105.71 75.01,106.29 75.01,108.18 74.54,108.66 74.54,109.55 75.1,110.11 77.18,110.11 77.4,110.33 77.4,110.72 76.71,111.4 76.71,111.79 76.99,112.07 77.38,112.07 78.06,111.38 78.45,111.38 80.99,113.92 80.99,117.02 81.46,117.49 81.46,123.63 85.1,127.28 88.11,127.28 89.48,128.65 104.27,128.65 104.83,128.09 117.39,128.09 119.23,126.26 v2(119.23,124.71)
BT656_A_D1: length 100.6
  TOP w0.193: v2(126.91,113.97) 126.46,113.52 125.35,113.52 124.88,113.04 124.88,110.37 124.09,109.58 123.61,109.58 123.37,109.83 118.73,109.83 117.88,110.69 117.88,111.85 117.99,111.96 J2.104 ; U4.26 69.57,111.01 v2(69.57,109.46)
  L03_SIG1 w0.155: v2(69.57,109.46) 71.02,109.46 71.38,109.11 71.87,109.11 72.22,109.46 72.22,109.9 73.7,111.38 75.47,111.38 77.28,113.18 77.28,118.16 76.85,118.59 76.85,121.77 85.05,129.97 118.17,129.97 126.91,121.23 v2(126.91,113.97)
BT656_A_D2: length 100.5
  TOP w0.193: U4.24 70.56,111.02 70.56,109.99 70.64,109.91 70.64,108.34 v2(70.48,108.18) ; v2(117.99,126.01) 117.99,125.35 118.35,124.98 118.35,124.48 118.01,124.14 118.01,120.76 117.99,120.73 J2.103
  L03_SIG1 w0.155: v2(117.99,126.01) 117.99,126.7 117.17,127.51 112.08,127.51 111.93,127.36 108.5,127.36 108.34,127.51 104.14,127.51 103.38,126.75 102.88,126.75 102.3,127.33 100.79,127.33 100.61,127.51 89.15,127.51 88.44,126.8 85.31,126.8 81.89,123.38 81.89,116.82 82.65,116.05 82.65,114.08 82.3,113.73 81.51,113.73 77.46,109.68 75.32,109.68 74.97,109.33 74.97,108.84 75.68,108.13 75.68,107.54 78.13,105.09 78.13,104.46 76.95,103.28 67.63,103.28 66.5,104.41 66.5,105.55 67.15,106.2 70.41,106.2 71.59,107.38 73.06,107.38 73.74,108.07 73.74,108.56 73.39,108.91 72.9,108.91 72.23,108.25 71.74,108.25 70.55,108.24 v2(70.48,108.18)
BT656_A_D3: length 100.4
  TOP w0.193: v2(128.14,113.31) 127.73,112.9 125.77,112.9 125.34,112.47 125.34,110.18 124.28,109.13 118.76,109.13 117.42,110.47 117.42,112.04 117.49,112.1 J2.102 ; v2(71.63,109.71) 71.63,110.12 71.6,110.14 71.6,110.98 U4.22
  L03_SIG1 w0.155: v2(128.14,113.31) 128.14,120.72 118.53,130.33 84.46,130.33 74.84,120.71 74.84,114.99 73.65,113.79 73.32,113.79 71.63,112.1 v2(71.63,109.71)
BT656_A_D4: length 101.1
  TOP w0.193: v2(73.15,108.32) 72.56,108.9 U4.20 ; J2.101 117.49,120.84 117.53,120.88 117.53,120.92 117.55,120.95 117.55,124.54 v2(117.74,124.73)
  L03_SIG1 w0.155: v2(117.74,124.73) 117.4,124.38 107.72,124.38 107.38,124.73 103.22,124.73 101.73,126.22 90.14,126.22 89.37,125.45 89.37,123.47 87.97,122.07 87.59,122.07 87.36,122.3 87.36,122.83 88.66,124.13 88.66,124.87 88.43,125.09 87.44,125.09 87.16,124.82 87.16,123.95 86.65,123.44 86.65,120.6 87.21,120.04 87.21,118.26 86.34,117.39 86.34,111.3 86.26,111.22 86.26,111.21 85.84,110.79 84.09,110.79 83.55,110.25 83.55,109.43 84.07,108.91 84.56,108.91 84.75,108.72 84.75,105.03 84.12,104.4 84.12,103.26 83.7,102.84 67.45,102.84 65.89,104.41 65.89,105.75 66.77,106.63 70.23,106.63 71.41,107.81 72.64,107.81 v2(73.15,108.32)
BT656_A_D5: length 100.6
  TOP w0.193: v2(126.91,112) 126.57,112 125.79,111.22 125.79,109.99 124.47,108.67 118.57,108.67 116.96,110.28 116.96,112.23 116.99,112.25 J2.100 ; U4.16 74.57,111.04 74.57,111.71 74.58,111.73 74.58,112.13 74.92,112.47 v2(74.92,113.18)
  L05_SIG2 w0.155: v2(126.91,112) 126.89,111.97 126.89,110.3 126.74,110.15 126.74,109.66 127.1,109.3 127.72,109.3 129.3,110.87 129.3,115.83 129.01,116.11 129.01,119.51 121.21,127.32 104.95,127.32 103.57,125.94 102.42,125.94 101.61,126.75 99.86,126.75 99.47,127.13 89.22,127.13 87.88,125.79 85.66,125.79 81.47,121.59 81.47,116.54 80.21,115.28 79.12,115.28 76.7,112.86 75.25,112.86 v2(74.92,113.18)
BT656_A_D6: length 101
  TOP w0.193: J2.99 116.99,120.98 117.1,121.09 117.1,125.28 117.17,125.36 v2(117.17,126.63) ; v2(75.57,109.08) 75.57,111.02 U4.14
  L03_SIG1 w0.155: v2(117.17,126.63) 116.38,126.63 115.38,125.63 115.07,125.63 114.74,125.96 114.36,125.96 114.03,125.63 113.77,125.63 113.49,125.9 113.49,126.82 113.22,127.1 112.83,127.1 112.55,126.82 112.55,125.9 112.28,125.63 108.13,125.63 107.85,125.9 107.85,126.82 107.58,127.1 107.19,127.1 106.91,126.82 106.91,125.9 106.64,125.63 106.25,125.63 105.97,125.9 105.97,126.82 105.7,127.1 105.31,127.1 105.03,126.82 105.03,125.9 104.76,125.63 104.15,125.63 103.39,126.39 102.74,126.39 102.15,126.98 100.64,126.98 100.46,127.16 89.53,127.16 88.66,126.29 88.66,126.26 85.53,126.26 84.23,124.96 84.23,118.58 84.98,117.83 84.98,115.93 84.49,115.44 84.06,115.44 83.6,115.9 83.6,123.29 83.25,123.65 82.82,123.65 82.38,123.22 82.38,121.9 83.05,121.24 83.05,113.98 82.45,113.37 81.81,113.37 78.66,110.22 78.66,109.99 78.88,109.78 79.21,109.78 82.36,112.93 82.66,112.93 82.82,112.78 82.82,112.4 79.5,109.08 v2(75.57,109.08)
BT656_A_D7: length 100.2
  TOP w0.193: v2(128.14,111.25) 126.85,111.25 126.25,110.65 126.25,109.8 124.66,108.21 118.38,108.21 116.49,110.11 J2.98 ; v2(76.45,107.68) 76.7,107.92 76.7,109.84 76.56,109.97 U4.12
  L05_SIG2 w0.155: v2(76.45,107.68) 76.45,109.45 76.91,109.91 78.4,109.91 82.81,114.32 82.81,122.37 85.88,125.44 88.02,125.44 89.34,126.76 99.35,126.76 99.7,126.41 101.45,126.41 102.28,125.59 103.72,125.59 105.1,126.97 113.12,126.97 115.1,124.99 116.73,124.99 117.07,125.33 122.49,125.33 128.66,119.15 128.66,115.97 128.82,115.81 128.82,112.56 128.14,111.88 v2(128.14,111.25)
BT656_A_D8: length 100.7
  TOP w0.193: v2(116.49,125.59) 116.49,121.85 116.6,121.74 116.6,121.24 116.49,121.13 J2.97 ; U4.10 77.55,111.02 77.55,110.17 77.52,110.14 v2(77.52,108.48)
  L03_SIG1 w0.155: v2(116.49,125.59) 116.1,125.2 103.43,125.2 102.01,126.62 100.49,126.62 100.46,126.65 89.71,126.65 88.79,125.73 85.81,125.73 84.92,124.84 84.92,123.16 85.44,122.65 85.44,120.64 86.58,119.51 86.58,118.44 85.91,117.77 85.91,115.12 85.63,114.85 84.44,114.85 84.16,114.57 84.16,114.18 84.44,113.91 85.63,113.91 85.91,113.63 85.91,113.24 85.63,112.97 84.44,112.97 84.16,112.69 84.16,112.3 84.44,112.03 85.63,112.03 85.91,111.75 85.91,111.35 85.7,111.14 83.94,111.14 83.2,110.4 83.2,109.28 84.32,108.16 84.32,107.43 84.04,107.16 83.18,107.16 82.9,107.43 82.9,108.28 82.63,108.56 82.24,108.56 81.96,108.28 81.96,107.43 81.69,107.16 81.3,107.16 81.02,107.43 81.02,108.28 80.75,108.56 80.36,108.56 80.08,108.28 80.08,107.43 79.81,107.16 79.1,107.16 78.83,106.88 78.83,106.49 79.1,106.22 84.04,106.22 84.32,105.94 84.32,105.21 83.6,104.5 82.67,104.5 81.45,103.28 79.31,103.28 79.16,103.43 79.16,103.89 79.39,104.11 80.22,104.11 80.66,104.55 80.66,105.04 80.22,105.49 78.42,105.49 77.7,106.21 77.7,106.73 77.9,106.93 78.34,106.93 78.69,107.28 78.69,107.78 78.31,108.15 77.84,108.15 v2(77.52,108.48)
BT656_A_D9: length 101
  TOP w0.193: v2(79.17,108.14) 79.17,110.08 79.09,110.15 79.09,111 U4.7 ; v2(127.33,109.91) 127.32,109.91 125.17,107.75 118.19,107.75 116.03,109.92 116.03,113.86 J2.96
  L05_SIG2 w0.155: v2(127.33,109.91) 127.33,111.57 127.51,111.75 127.51,119.14 122.55,124.1 115.43,124.1 114.16,125.37 104,125.37 103.86,125.24 102.13,125.24 101.29,126.08 89.16,126.08 88.17,125.09 87.81,125.09 87.64,124.91 86.04,124.91 83.44,122.32 83.44,116.26 83.72,115.99 85.46,115.99 85.74,115.71 85.74,115.32 85.46,115.05 83.72,115.05 83.44,114.77 83.44,113.61 80.68,110.85 80.68,110.46 81.62,109.53 81.62,109.14 81.34,108.86 80.95,108.86 80.01,109.8 79.62,109.8 79.17,109.34 v2(79.17,108.14)
BT656_B_CLK: length 27.3
  TOP w0.193: v2(79.69,117.35) 80.96,117.35 81.15,117.15 81.15,112.54 80.56,111.95 U4.4 ; J1.94 v2(64.37,115.36)
  L05_SIG2 w0.155: v2(79.69,117.35) 78.69,117.35 78.36,117.02 76.77,117.02 75.93,117.86 72.12,117.86 68.77,114.5 68.14,114.5 67.7,114.95 66.73,114.95 66.28,114.5 65.23,114.5 v2(64.37,115.36)
BT656_B_D0: length 27.5
  TOP w0.193: J1.105 67.37,119.1 67.51,118.96 67.51,118.93 67.79,118.66 67.79,118.43 v2(68.24,117.98) ; U4.27 v2(69.06,112.42)
  L03_SIG1 w0.155: v2(69.06,112.42) 69.06,115.72 68.05,116.74 64.52,116.74 63.32,115.54 63.32,114.53 62.74,113.94 62.1,113.94 61.29,114.76 61.29,116.21 63.47,118.39 64.85,118.39 65.97,117.27 67.53,117.27 v2(68.24,117.98)
BT656_B_D1: length 27.9
  TOP w0.193: U4.25 70.06,109.84 70.18,109.72 70.18,109.21 69.87,108.9 69.87,107.58 v2(69.63,107.34) ; J1.104 66.87,113.15 66.88,113.14 66.88,113.04 67.08,112.84 67.18,112.84 67.6,112.42 67.6,111.25 v2(66.59,110.24)
  L05_SIG2 w0.155: v2(69.63,107.34) 66.46,104.17 63.14,104.17 61.06,106.25 61.06,108.92 61.23,109.09 65.44,109.09 v2(66.59,110.24)
BT656_B_D2: length 33.2
  TOP w0.193: v2(71.72,115.85) 71.72,112.86 71.06,112.2 U4.23 ; J1.70 v2(58.37,112.12) ; v2(66.19,123.09) 66.87,122.41 J1.103 66.87,118.66 v2(67.14,118.39)
  L03_SIG1 w0.155: v2(71.72,115.85) 71.72,116.6 69.56,118.76 67.51,118.76 v2(67.14,118.39) 66.15,119.38 63.3,119.38 59.81,115.89 59.81,113.55 v2(58.37,112.12)
  BOTTOM w0.193: v2(66.19,123.09) 66.19,123.46 R503.1
BT656_B_D3: length 27.6
  TOP w0.193: U4.21 72.06,112.51 73.62,114.07 73.62,115.01 v2(73.32,115.31) ; J1.102 66.37,112.89 66.51,112.74 66.51,111.63 v2(66.69,111.46)
  L03_SIG1 w0.155: v2(66.69,111.46) 66.03,110.79 64.03,110.79 63.12,111.71 63.12,113.11 64.19,114.17 65.72,114.17 68.1,111.79 69.41,111.79 69.81,112.19 69.81,114.4 70.4,114.99 71.7,114.99 72.02,115.31 v2(73.32,115.31)
BT656_B_D4: length 27.2
  TOP w0.193: v2(76.01,119.68) 76.01,114.76 75.08,113.83 74.62,113.83 73.98,113.18 73.77,113.18 73.47,112.88 73.47,112.23 73.56,112.14 U4.18 ; J1.101 66.37,118.67 66.23,118.53 66.23,117.98 v2(66.17,117.92)
  L05_SIG2 w0.155: v2(76.01,119.68) 72.53,123.16 69.35,123.16 67.33,121.14 67.33,120.81 66.83,120.31 66.5,120.31 66.15,119.96 66.15,117.93 v2(66.17,117.92)
BT656_B_D5: length 27.2
  TOP w0.193: v2(76.31,113.51) 75.45,112.64 75.45,112.36 75.06,111.98 U4.15 ; J1.100 v2(65.87,112.48)
  L05_SIG2 w0.155: v2(65.87,112.48) 66.7,113.31 69.39,113.31 69.88,113.8 70.33,113.8 70.82,113.31 71.27,113.31 71.76,113.8 72.21,113.8 72.7,113.31 73.8,113.31 74.16,113.66 74.16,114.27 73.79,114.64 73.37,114.64 73.36,114.66 73.06,114.66 72.33,115.39 72.33,116.61 72.63,116.92 73.12,116.92 73.67,116.37 76.09,116.37 76.38,116.08 77.64,116.08 77.86,115.85 77.86,115.06 v2(76.31,113.51)
BT656_B_D6: length 59.2
  TOP w0.193: v2(83.54,99.62) 83.54,101.14 85.19,102.79 85.19,106.38 84.31,107.26 82.19,107.26 81.84,106.91 76.17,106.91 75.77,107.31 75.77,108.05 76.21,108.5 76.21,109.28 76.06,109.43 U4.13 76.06,112.04 76.9,112.88 76.9,113.19 76.96,113.25 76.96,113.78 76.9,113.84 76.9,119.28 v2(77.48,119.86) ; v2(65.47,118.68) 65.87,119.08 J1.99
  L05_SIG2 w0.155: v2(77.48,119.86) 73.66,123.69 68.63,123.69 65.47,120.52 v2(65.47,118.68)
  BOTTOM w0.193: R557.1 89.9,96.96 88.67,98.2 84.96,98.2 v2(83.54,99.62)
BT656_B_D7: length 28.1
  TOP w0.193: U4.11 77.06,112.23 77.79,112.95 77.79,117.96 v2(78.04,118.21) ; J1.98 65.37,115.22 v2(65.53,115.38)
  L05_SIG2 w0.155: v2(78.04,118.21) 76.91,118.21 76.32,118.8 75.91,118.8 74.02,120.69 71.54,120.69 71.26,120.41 71.26,119.93 70.99,119.65 70.6,119.65 70.32,119.93 70.32,120.41 70.05,120.69 69.63,120.69 68.92,119.98 68.92,117.58 68.47,117.12 66.61,117.12 65.53,116.04 v2(65.53,115.38)
BT656_B_D8: length 28.8
  TOP w0.193: v2(79.74,121.11) 79.74,119.1 78.7,118.05 78.7,116.93 78.7,116.93 78.7,112.75 78.06,112.11 U4.9 ; J1.97 v2(65.37,121.5)
  L05_SIG2 w0.155: v2(65.37,121.5) 66.36,122.49 66.5,122.49 68.04,124.03 76.77,124.03 77.4,123.4 77.45,123.4 v2(79.74,121.11)
BT656_B_D9: length 28.4
  TOP w0.193: J1.96 64.87,113.05 64.66,112.84 64.65,112.84 64.3,112.5 v2(64.22,112.5) ; v2(79.34,114.62) 79.56,114.4 U4.6
  L05_SIG2 w0.155: v2(64.22,112.5) 63.77,112.95 63.13,112.95 62.83,112.65 62.83,111.23 63.23,110.82 65.06,110.82 66.33,112.09 67.06,112.09 67.82,111.33 77.76,111.33 79.34,112.9 v2(79.34,114.62)
BT656_CLK: length 2.2
  TOP w0.193: U4.52 v2(80.06,104.8)
  BOTTOM w0.193: R537.2 80.07,104.79 v2(80.06,104.8)
BT656_D0: length 2.7
  TOP w0.193: v2(68.47,102.13) 68.75,102.13 69.06,102.44 U4.30
  BOTTOM w0.193: R547.2 68.67,102.32 v2(68.47,102.13)
BT656_D1: length 2.7
  TOP w0.193: U4.32 70.06,102.19 v2(69.84,101.97)
  BOTTOM w0.193: R546.2 70.04,102.17 v2(69.84,101.97)
BT656_D2: length 2.3
  TOP w0.193: U4.34 71.06,104.9 v2(71.06,104.9)
  BOTTOM w0.193: R545.2 v2(71.06,104.9)
BT656_D3: length 2.2
  TOP w0.193: v2(72.09,104.86) 72.06,104.83 U4.36
  BOTTOM w0.193: v2(72.09,104.86) 72.07,104.84 R544.2
BT656_D4: length 2.2
  TOP w0.193: U4.39 73.56,104.81 v2(73.6,104.84)
  BOTTOM w0.193: v2(73.6,104.84) 73.6,104.84 R543.2
BT656_D5: length 2.2
  TOP w0.193: v2(74.61,102.15) 74.56,102.2 U4.41
  BOTTOM w0.193: R542.2 v2(74.61,102.15)
BT656_D6: length 2.3
  TOP w0.193: v2(75.57,102.07) 75.57,103.47 U4.43
  BOTTOM w0.193: v2(75.57,102.07) 75.57,102.92 R541.2
BT656_D7: length 2.2
  TOP w0.193: U4.45 76.56,104.8 v2(76.52,104.84)
  BOTTOM w0.193: R540.2 v2(76.52,104.84)
BT656_D8: length 2.2
  TOP w0.193: U4.47 77.56,104.81 v2(77.53,104.84)
  BOTTOM w0.193: R539.2 v2(77.53,104.84)
BT656_D9: length 2.2
  TOP w0.193: v2(79.03,104.84) 79.06,104.81 U4.50
  BOTTOM w0.193: v2(79.03,104.84) 79.06,104.81 R538.2
BUS_SELECT: length 210.1
  TOP w0.193: v2(182.2,13.19) 182.41,13.4 U21.16 ; J2.89 v2(114.49,117.88)
  L03_SIG1 w0.155: v2(137.77,120.88) 137.15,121.5 134.38,121.5 v2(131.34,118.46) ; v2(187.35,123.25) 187.35,110.01 185.31,107.98 185.31,103.03 186.64,101.7 186.64,96.19 185.16,94.71 185.16,89.44 178.25,82.54 178.25,81.27 179.87,79.65 183.31,79.65 183.66,79.3 183.66,77.37 181.02,74.73 181.02,72.13 180.79,71.91 180.79,69.59 182.36,68.02 182.69,68.02 184.05,66.66 184.05,38.9 185.19,37.77 185.19,27.55 182.75,25.11 182.75,13.74 v2(182.2,13.19)
  L05_SIG2 w0.155: v2(187.35,123.25) 187.35,123.3 185.59,125.05 173.31,125.05 172.52,124.26 158.52,124.26 156.16,126.62 153.85,126.62 148.11,120.88 139.87,120.88 v2(137.77,120.88)
  BOTTOM w0.193: v2(131.34,118.46) 130.36,117.47 129.97,117.47 128.66,116.16 124.87,116.16 123.69,114.98 118.88,114.98 115.98,117.88 v2(114.49,117.88) ; v2(182.2,13.19) 182.55,13.54 R745.1
COMP_SENSE_INPUT: length 8.6
  TOP w0.193: v2(130.8,38.53) 131.37,38.53 131.75,38.91 133.35,38.91 133.98,38.28 J26.2
  BOTTOM w0.193: v2(130.8,38.53) 130.8,38.53 R704.1 131.59,40.17 131.8,40.17 132,40.36 132,41.15 131.82,41.33 U512.2
COMP_SENSE_VDD: length 5
  TOP w0.193: J26.1 v2(135.23,36.15)
  BOTTOM w0.193: v2(135.23,36.15) 134.82,36.57 R703.1 C649.2
COMP_SENSOR: length 17.8
  BOTTOM w0.193: J21.3 118.29,41.61 119.22,41.61 119.97,42.35 v2(124.27,42.35) 124.85,41.77 R705.1 128.91,40.67 ; 128.91,40.67 128.92,40.68 U512.1 ; 128.91,40.67 R706.1
CSZ5_DAD2: length 10.2
  TOP w0.193: R65.1 107.1,21.52 106.69,21.94 v2(106.57,21.94) ; J63.B28 v2(107.09,14.48)
  L03_SIG1 w0.155: v2(106.57,21.94) 106.86,21.64 106.86,16.94 107.7,16.11 107.7,15.09 v2(107.09,14.48)
CW_INDEX1: length 244.6
  TOP w0.193: U11.AF7 v1(106.66,69.2) 107.37,69.91 107.37,70.38 109.5,72.52 115.7,72.52 116.97,71.25 116.97,69.85 119.21,67.61 119.21,65.92 120.8,64.33 120.8,63.22 118.96,61.38 115.1,61.38 114.74,61.74 114.21,61.74 113.58,61.12 113.58,59.53 113.28,59.23 113.28,58.62 112.97,58.31 112.4,58.31 111.92,57.82 111.92,53.9 107.75,49.73 105.88,49.73 101.17,45.02 101.17,38.19 102.79,36.57 107.93,36.57 v2(109.12,35.38) ; v2(61.34,111.96) 61.34,112.48 61.37,112.51 J1.82
  L03_SIG1 w0.155: v2(59.23,101.47) 61.34,103.58 v2(61.34,111.96)
  BOTTOM w0.193: v2(59.23,101.47) 59.23,99.4 54.97,95.14 52.85,95.14 39.92,82.21 31.63,82.21 28.7,79.28 28.7,68.66 31.47,65.89 34.06,65.89 35.51,64.44 35.51,61.75 34.72,60.96 32.87,60.96 32.38,60.48 32.38,59.72 33.68,58.42 40.11,58.42 45.71,52.82 49.41,52.82 51.65,50.58 53.52,50.58 53.91,50.97 54.83,50.97 56.01,49.79 63.15,49.79 64.97,47.97 97.36,47.97 109.12,36.21 v2(109.12,35.38) 109.11,35.37 TP61.1 107.56,34.35 107.72,34.18 R750.1 107.56,33.11 R751.1 107.56,30.49 U519.1
CW_INDEX2: length 123.8
  L03_SIG1 w0.155: v2(54.47,50.32) 54.17,50.62 54.17,53.78 57.51,57.12 57.51,63.54 59.73,65.76 59.73,67.64 59.99,68.03 60.87,68.91 60.87,70.47 70,79.59 72.58,79.59 73.5,80.52 74.42,80.52 75.44,81.53 75.44,87 73.66,88.77 v2(73.53,88.77)
  L05_SIG2 w0.155: v2(103.13,30.78) 104.15,30.78 106.36,32.99 106.36,34.66 TP60.1
  BOTTOM w0.193: R753.1 104.78,34.08 105.65,34.95 TP60.1 105.65,37.74 96.45,46.94 62.52,46.94 60.35,49.12 55.67,49.12 v2(54.47,50.32) ; v2(73.53,88.77) R568.2 ; R755.1 103.13,31.39 v2(103.13,30.78) 103.13,30.18 102.74,29.79 U519.7
CW_PWM1: length 67.5
  TOP w0.193: U11.AD8 v1(104.66,70.2) ; R32.1 v2(164.46,66.56)
  L03_SIG1 w0.155: v1(104.66,70.2) 105.14,69.72 107.63,69.72 107.81,69.55 112.13,69.55 113.75,71.17 114.37,71.17 116.24,73.04 120.93,73.04 122.97,71 v2(123.56,71)
  L05_SIG2 w0.155: v2(131.11,67.94) 131.11,68 132.03,68.91 135.71,68.91 136,69.2 140.98,69.2 141.68,68.51 162.51,68.51 164.45,66.56 v2(164.46,66.56)
  BOTTOM w0.193: v2(123.56,71) 123.61,71.05 124.37,71.05 125.77,69.65 125.77,69.04 126.81,68.01 131.05,68.01 v2(131.11,67.94)
CW_PWM2/SPD4: length 250.7
  TOP w0.193: U11.H26 v1(87.66,89.2)
  L03_SIG1 w0.102: 79.85,81.81 84.83,81.81 85.27,82.25 85.27,83.36 85.5,83.59 85.61,83.59 86.06,84.04 86.06,85.44 86.42,85.8 86.82,85.8 87.07,86.05 87.07,86.45 87.27,86.65 87.27,87.36 87.5,87.59 87.61,87.59 88.06,88.04 88.06,88.36 87.66,88.76 v1(87.66,89.2)
  L03_SIG1 w0.155: v2(35.66,21.48) 40.53,21.48 45.36,26.31 45.36,31.01 48.11,33.75 49.16,33.75 50.52,35.12 50.52,40.12 53.81,43.4 53.81,46.04 60.16,52.39 60.16,54.04 59.09,55.11 59.09,55.2 59.09,55.2 59.09,55.75 59.44,56.1 59.98,56.1 60.39,55.69 60.96,55.69 61.31,56.04 61.31,56.54 60.87,56.97 60.87,61.19 61.82,62.13 61.82,66.77 62.08,67.04 62.08,67.17 63.05,68.14 63.05,69.69 70.51,77.16 73.75,77.16 78.41,81.82 79.84,81.82 79.85,81.81
  L05_SIG2 w0.155: v2(169.81,113.36) 169.81,111.19 169.39,110.77 168.83,110.77 168.48,111.12 168.48,111.13 168.13,111.48 167.01,111.48 163.66,114.83 158.72,114.83 158.2,114.31 157.13,114.31 156.67,114.77 154.9,114.77 150.47,110.34 134.16,110.34 132.07,108.25 127.64,108.25 126.32,109.57 126.32,119.39 122.04,123.67 115.36,123.67 114.17,124.86 99.29,124.86 98.5,125.66 89.23,125.66 88.31,124.74 88.08,124.74 87.6,124.27 87.6,123.78 87.28,123.46 87.28,113.99 83.5,110.2 83.5,104.72 82.73,103.96 82.73,103.55 81.51,102.33 81.51,97.8 81.65,97.65 81.65,95.21 v1(87.66,89.2)
  BOTTOM w0.193: R517.1 v2(169.81,113.36) ; U515.7 35.25,22.15 35.66,21.75 v2(35.66,21.48)
CWCTR1: length 141.3
  TOP w0.254: J58.1 132.2,4.85 v2(132.13,4.93) ; v2(163.38,65.6) 163.06,65.28 U15.13
  L03_SIG1 w0.254: v2(163.38,65.6) 163.38,67.27 166.22,70.1 166.22,72.29 v2(167.78,73.85) ; v2(132.13,4.93) 131.09,4.93 129.82,6.19 129.82,8.73 131.08,9.99 135.73,9.99 146.63,20.89 146.63,47.12 141.17,52.58 141.17,56.72 139.76,58.13 139.76,59.2 140.36,59.8 140.36,62.47 141.12,63.23 141.48,63.23 141.73,62.99 142.61,62.99 143.57,63.96 143.57,66.61 145.38,68.42 145.38,73.87 v2(145.28,73.97)
  L05_SIG2 w0.254: v2(167.78,73.85) 164.9,76.72 148.03,76.72 v2(145.28,73.97)
  BOTTOM w0.254: 167.77,73.86 C549.1 C550.1 163.6,75.23 159.78,79.06 159.78,79.84 158.29,81.33 C551.1 ; 167.77,73.86 v2(167.78,73.85) ; 167.77,73.86 167.77,72.72 DN508.3
CWCTR2: length 219
  TOP w0.254: v2(130.06,12.79) 130.83,12.02 J56.1 ; v2(165.89,118.39) 165.89,117.62 165.37,117.09 164.11,117.09 163.92,117.29 U2.13 ; v2(154.23,125.86) 157.64,125.86 159.58,127.8 161.67,127.8 v2(163.09,126.38)
  L03_SIG1 w0.254: v2(175.26,124.46) 175.26,123.82 173.9,122.46 167.9,122.46 165.82,124.54 164.93,124.54 v2(163.09,126.38) 162.75,126.03 162.75,121.53 v2(165.89,118.39) ; v2(130.06,12.79) 126.42,12.79 125.31,13.89 125.31,18.65 127.09,20.42 131.49,20.42 133.73,22.67 133.73,37.88 127.83,43.79 127.83,43.82 126.23,45.42 126.23,46.82 122.12,50.93 122.12,52.53 122.94,53.36 122.94,53.37 122.99,53.42 122.99,57.5 122.94,57.56 122.94,57.56 122.01,58.49 122.01,63.07 120.46,64.62 120.35,64.62 119.21,65.76 119.21,66.64 117.06,68.8 117.06,69.41 116.46,70.01 116.46,71.57 117.11,72.22 119.49,72.22 123,68.71 123.94,68.71 124.62,69.38 124.62,72.26 124.3,72.58 123.54,73.34 123.54,77.37 125.64,79.48 125.64,83.44 126.72,84.52 126.72,96.88 127.54,97.69 127.54,104.31 127.64,104.42 127.94,104.71 127.94,104.71 128.5,105.27 128.5,107.02 126.13,109.38 126.13,110.66 126.69,111.21 127.08,111.21 127.76,111.89 128.86,111.89 129.43,112.46 129.43,116.1 129.38,116.15 129.38,116.16 129.31,116.23 129.31,120.95 129.23,121.02 v2(129.23,121.69)
  L05_SIG2 w0.254: v2(154.23,125.86) 148.49,120.12 135.07,120.12 134.7,120.49 130.43,120.49 v2(129.23,121.69)
  BOTTOM w0.254: v2(163.09,126.38) 163.09,126.72 DN502.3 165.4,127.51 C501.1 ; C502.1 v2(154.23,125.86) ; C500.1 v2(175.26,124.46)
CWY1A: length 131.2
  TOP w0.254: J58.4 v2(131.31,7.85)
  L03_SIG1 w0.254: v2(131.31,7.85) 135.28,7.85 138.79,11.36 160.96,11.36 164.59,15 164.59,24.28 160.75,28.12 160.75,29.61 170.27,39.13 170.27,46.86 171.43,48.03 171.43,49.74 175.19,53.49 175.56,53.49 178.37,56.3 178.37,63.13 175.67,65.83 175.06,65.83 v2(174.9,65.98)
  BOTTOM w0.254: v2(174.9,65.98) 173.81,64.9 R609.2 168.99,71.45 170.06,72.52 170.06,80.2 R576.2 165.71,84.54 163.58,84.54 DN505.3
CWY1B: length 136.9
  TOP w0.254: v2(164.11,83.39) 164.67,83.39 164.95,83.67 R25.2 ; J58.3 v2(132.19,6.85)
  L03_SIG1 w0.254: v2(132.19,6.85) 135.17,6.85 139.18,10.86 161.17,10.86 165.1,14.79 165.1,24.55 161.26,28.39 161.26,29.4 170.78,38.91 170.78,46.5 171.94,47.67 171.94,49.53 175.22,52.81 175.6,52.81 178.88,56.09 178.88,63.34 174.78,67.44 v2(174.78,81.51)
  L05_SIG2 w0.254: v2(164.11,83.39) 172.9,83.39 v2(174.78,81.51)
  BOTTOM w0.254: R577.2 165.34,82.49 164.44,83.39 v2(164.11,83.39) 163.82,82.64 162.62,81.44 161.27,81.44 160.02,82.69 DN506.3
CWY1C: length 126.6
  TOP w0.254: J58.2 v2(131.31,5.85) ; v2(164.14,81.09) 164.14,75.12 162.69,73.66 v2(162.69,73.59) R28.2
  L03_SIG1 w0.254: v2(148.73,83.32) 148.54,83.32 146.82,81.61 146.82,74.55 145.88,73.62 145.88,68.21 144.34,66.66 144.34,63.73 141.8,61.2 141.8,54.39 145.11,51.08 145.11,49.43 145.48,49.06 146.75,49.06 147.52,48.29 147.52,19.27 140.35,12.1 138.55,12.1 135.45,9 131.1,9 130.46,8.36 130.46,6.69 v2(131.31,5.85)
  L05_SIG2 w0.254: v2(148.73,83.32) 148.76,83.35 159.13,83.35 161.01,81.47 163.76,81.47 v2(164.14,81.09)
  BOTTOM w0.254: DN507.3 150.43,84.52 R563.2 149.17,83.32 v2(148.73,83.32)
CWY2A: length 160
  TOP w0.254: v2(133.84,13.79) J56.4 ; R7.2 174.36,124.08 174.37,124.08 v2(174.35,124.08)
  L03_SIG1 w0.254: v2(133.84,13.79) 134.95,12.68 136.98,12.68 145.52,21.22 145.52,46.54 140,52.05 140,55.26 138.38,56.88 138.38,63.16 140.84,65.62 140.84,66.32 142.15,67.63 142.55,67.63 143.93,69.02 143.93,72.82 141.92,74.83 141.92,78.92 148.27,85.27 148.27,87.56 148.58,87.87 148.58,98.97 148.46,99.1 148.46,116.26 160.08,127.89 161.12,127.89 161.38,127.63 165.23,127.63 168.78,124.08 v2(174.35,124.08)
  BOTTOM w0.254: DN500.3 176.03,124.03 175.77,123.77 174.66,123.77 v2(174.35,124.08) 174.28,124.14 R500.2
CWY2B: length 192
  TOP w0.254: J56.3 132.83,12.1 v2(132.12,12.82) ; v2(152.25,126.06) 153.05,126.86 156.73,126.86 158.7,128.83 162.6,128.83 v2(163.08,129.3) 164.15,128.23 v2(164.15,126.41) 164.15,125.23 R5.2
  L03_SIG1 w0.254: v2(132.12,12.82) 131.49,12.82 130.78,13.52 126.4,13.52 125.82,14.1 125.82,18.25 126.58,19.01 130.87,19.01 134.24,22.39 134.24,38.75 133.68,39.31 133.68,40.17 133.24,40.61 131.75,40.61 126.73,45.63 126.73,47.03 122.62,51.14 122.62,52.32 123.44,53.15 123.44,53.16 123.5,53.21 123.5,57.71 123.44,57.77 123.44,57.77 122.52,58.7 122.52,63.28 120.67,65.13 120.59,65.13 119.84,65.88 119.84,66.76 117.56,69.03 117.56,69.62 116.99,70.19 116.99,71.23 117.47,71.7 119.05,71.7 122.56,68.2 124.15,68.2 125.13,69.18 125.13,75.11 126.38,76.35 126.38,83.34 127.23,84.19 127.23,96.63 128.15,97.56 128.15,104.21 129.14,105.2 129.14,107.14 126.64,109.63 126.64,110.23 127.02,110.61 128.63,110.61 130.31,112.29 130.31,115.97 130.28,115.99 130.26,115.99 129.89,116.36 129.89,120.03 v2(131.26,121.41)
  L05_SIG2 w0.254: v2(152.25,126.06) 148.78,122.59 137.32,122.59 136.14,121.41 v2(131.26,121.41)
  BOTTOM w0.254: DN501.3 163.42,129.64 v2(163.08,129.3) ; v2(164.15,126.41) R501.2
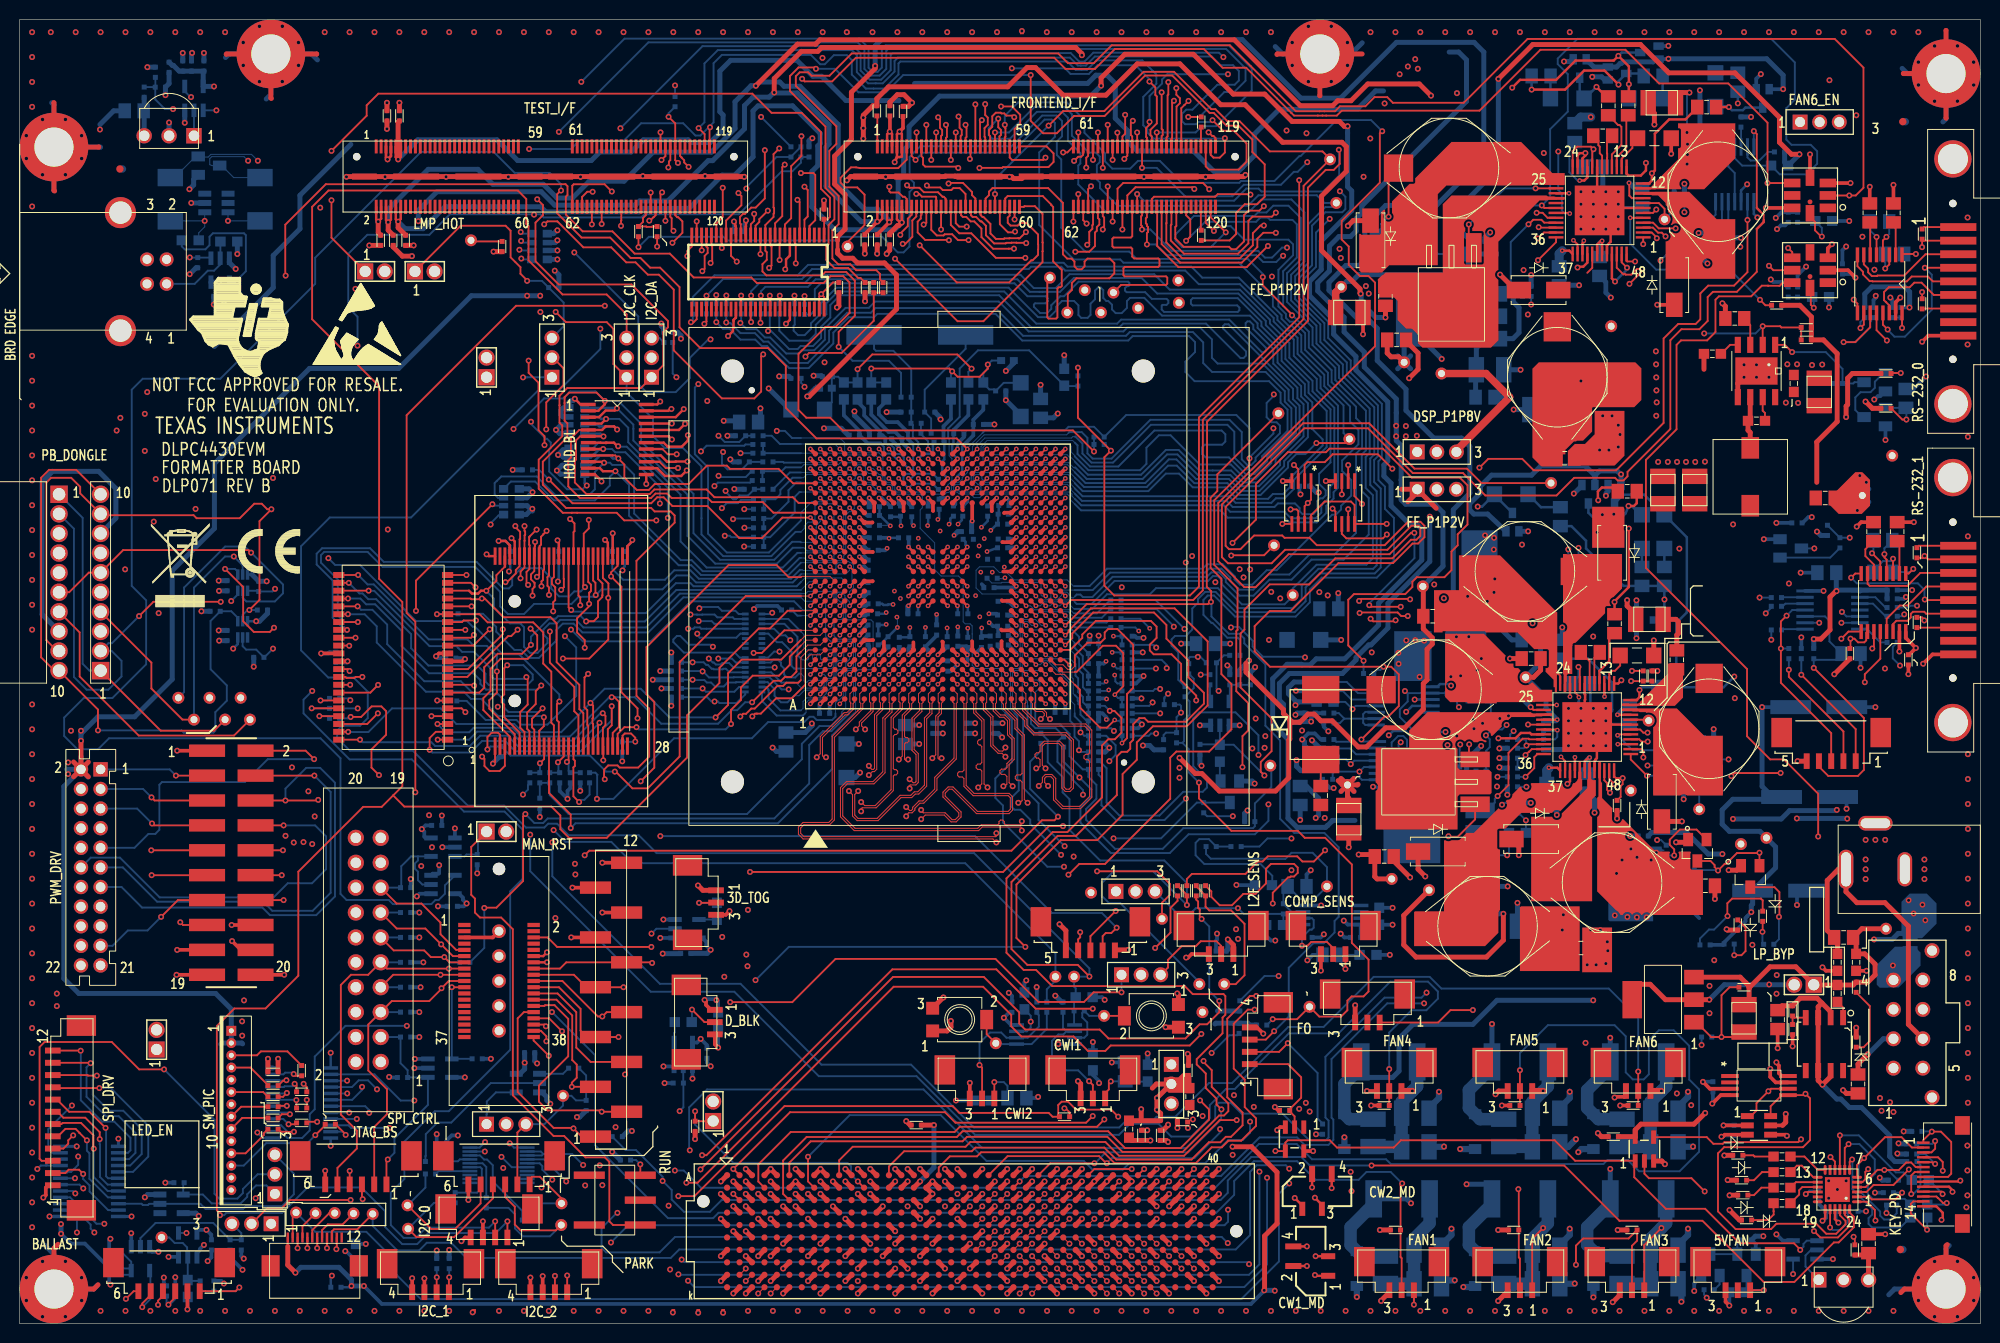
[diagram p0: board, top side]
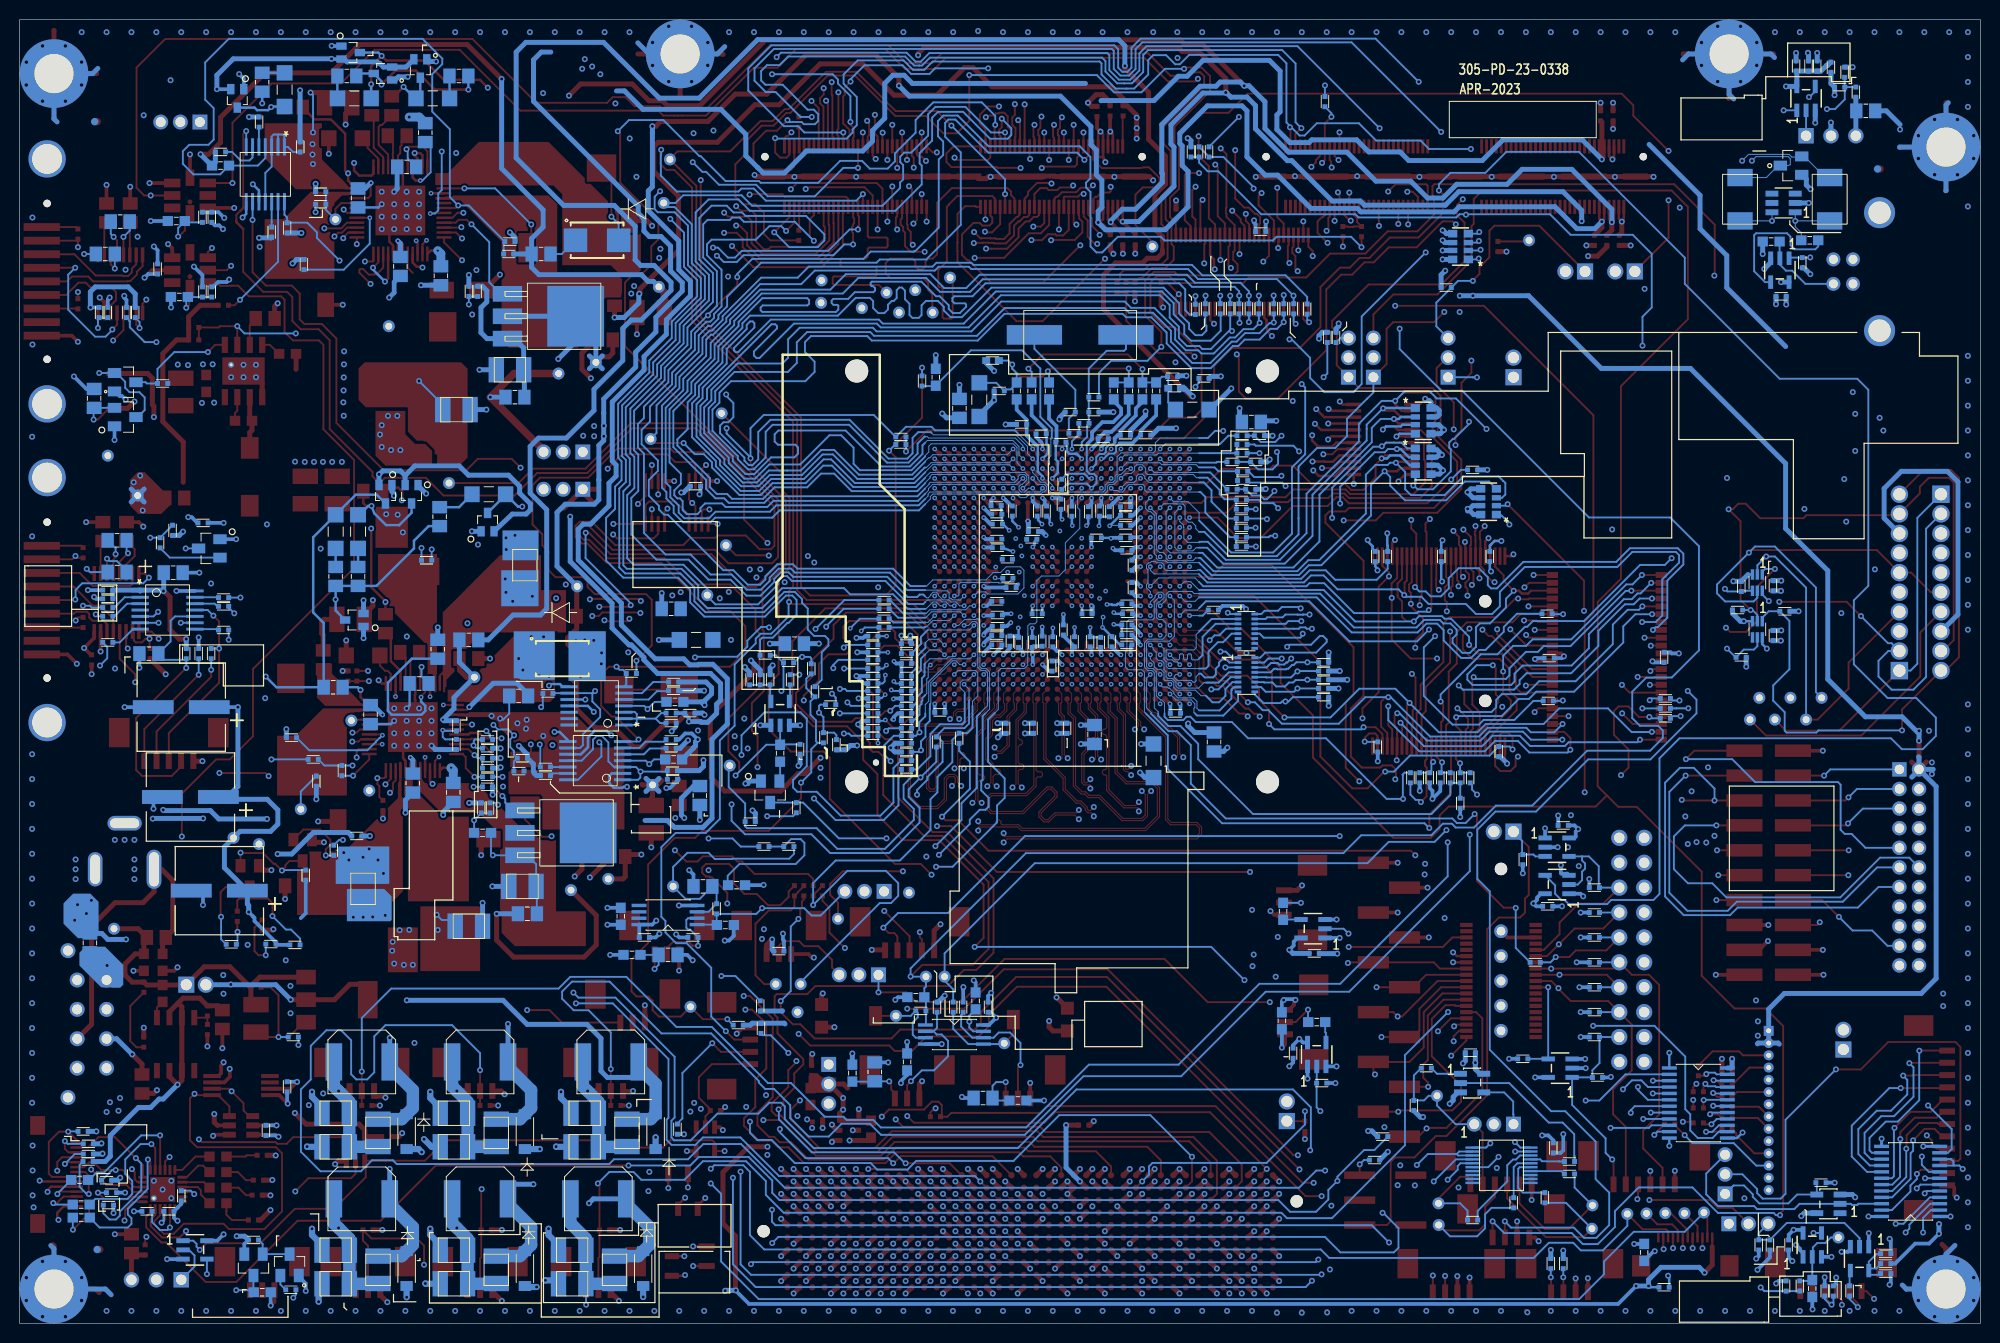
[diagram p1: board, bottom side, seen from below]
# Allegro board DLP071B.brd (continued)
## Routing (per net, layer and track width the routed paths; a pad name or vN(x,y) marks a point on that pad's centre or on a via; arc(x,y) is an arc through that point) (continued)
CWY2C: length 144.1
  TOP w0.254: v2(160.84,126.14) 161.81,125.17 R4.2 ; v2(131.83,13.87) J56.2
  L03_SIG1 w0.254: v2(131.83,13.87) 132.47,13.87 134.46,11.88 136.9,11.88 146.02,21 146.02,46.93 140.51,52.45 140.51,55.95 139.02,57.43 139.02,60.26 139.34,60.58 139.34,62.17 141.04,63.87 141.57,63.87 142.16,64.47 142.16,66.23 142.63,66.69 142.94,66.69 144.87,68.63 144.87,73.48 144.64,73.71 144.64,74.23 145.99,75.58 145.99,81.66 147.9,83.58 147.9,83.59 148.27,83.96 148.28,83.96 149.69,85.36 149.69,98.59 149.05,99.23 149.05,114.35 v2(160.84,126.14)
  BOTTOM w0.254: DN503.3 159.13,125.41 R502.2 159.67,124.97 v2(160.84,126.14)
DA0: length 17.6
  TOP w0.193: U11.AB8 v1(102.66,70.2)
  L05_SIG2 w0.102: 107.63,69.89 106.92,70.59 105.38,70.59 105.12,70.33 105.12,69 104.85,68.73 102.53,68.73 102.27,68.99 102.27,69.79 102.65,70.18 102.65,70.19 v1(102.66,70.2)
  L05_SIG2 w0.155: v1(111.7,66.13) 111.7,66.12 111.28,66.54 110.34,66.54 109.09,67.78 109.09,68.43 107.63,69.89
  BOTTOM w0.193: R628.1 C615.1 111.97,65.28 111.76,65.49 111.76,66.05 111.7,66.11 v1(111.7,66.13)
DA1: length 14.2
  TOP w0.102: U11.AF4 106.42,66.44 107.6,66.44 107.63,66.47
  TOP w0.193: 107.63,66.47 107.82,66.47 110.48,69.13 111.83,69.13 112.57,68.39 112.57,64.99 111.72,64.14 111.7,64.14 111.7,64.13 v1(111.71,64.13)
  BOTTOM w0.193: R629.1 C616.1 112.42,63.78 112.06,63.78 111.71,64.13 v1(111.71,64.13)
DA2: length 24.2
  TOP w0.102: 105.65,67.21 105.67,67.19 106.43,67.19 106.9,66.72 107.3,66.72 107.63,67.04
  TOP w0.193: U11.AE5 105.65,67.21 ; v1(112.45,59.19) 112.95,59.7 112.95,64.2 113.58,64.82 113.58,69.23 111.98,70.83 111.03,70.83 110.68,70.49 110.68,69.87 110.25,69.44 108.93,69.44 107.63,68.14 107.63,67.04
  BOTTOM w0.193: v1(112.45,59.19) R673.1 C618.1
DA3: length 9.8
  TOP w0.193: U11.AD6 v1(104.66,68.2)
  BOTTOM w0.102: 107.63,67.32 107.16,67.8 105.48,67.8 105.28,68 104.86,68 v1(104.66,68.2)
  BOTTOM w0.193: C621.1 R635.1 108.84,62.99 108.46,63.37 108.46,63.91 107.97,64.4 107.97,65.8 107.7,66.07 107.7,67.26 107.63,67.32
DADADD0: length 93.5
  TOP w0.193: v2(126.14,33.4) 125.5,33.4 123.18,31.08 123.18,23.07 124.74,21.5 124.74,20.21 123.56,19.03 123.03,19.03 122.48,18.47 121.31,18.47 119.54,16.71 111.86,16.71 110.64,17.93 97.5,17.93 97.12,17.56 90.22,17.56 88.67,16.01 J63.A14
  L03_SIG1 w0.155: v2(126.14,33.4) 126.14,41.35 123.51,43.98 123.51,46.78 120.12,50.18 120.12,54.44 119.51,55.05 119.51,57.9 117.42,59.99 117.42,63.11 116.33,64.2 v2(116.33,64.72)
  BOTTOM w0.193: v2(116.33,64.72) 115.81,64.72 115.61,64.52 R628.2
DADADD1: length 88.3
  TOP w0.193: J63.A18 93.75,15.91 94.88,17.04 97.65,17.04 98.07,17.45 110.58,17.45 111.68,16.35 119.98,16.35 121.58,17.96 122.62,17.96 123.29,18.63 124.6,18.63 126.11,20.14 126.11,20.91 124.96,22.06 124.96,24.87 123.84,25.99 123.84,30.57 125.27,32 v2(125.97,32)
  L03_SIG1 w0.155: v2(115.57,63.35) 116.41,63.35 116.93,62.82 116.93,59.97 119.04,57.86 119.04,54.85 119.71,54.18 119.71,50.09 123.13,46.68 123.13,43.24 123.64,42.73 123.64,41.95 125.54,40.05 125.54,32.43 v2(125.97,32)
  BOTTOM w0.193: R629.2 115.21,62.99 v2(115.57,63.35)
DADADD2: length 73.9
  TOP w0.193: J63.A22 100.78,17.06 110.11,17.06 110.83,16.33 v2(110.9,16.33)
  L03_SIG1 w0.155: v2(115.93,60.17) 115.93,58.17 117.12,56.97 117.12,50.05 121.58,45.6 121.58,42.06 121.85,41.79 121.85,40.38 121.45,39.98 121.45,39.58 123.78,37.25 123.78,25.5 121.85,23.57 121.85,20.97 122.45,20.37 v2(122.45,19.82)
  BOTTOM w0.193: v2(122.45,19.82) 122.48,19.79 122.48,19.5 119.83,16.86 111.42,16.86 v2(110.9,16.33) ; R673.2 115.18,59.94 115.4,60.17 v2(115.93,60.17)
DADADD3: length 92.9
  TOP w0.193: v2(122.59,21.83) 122.09,22.33 122.09,22.91 120.99,24.01 120.99,25.49 120.07,26.42 120.07,26.95 122.7,29.59 122.7,31.2 122.99,31.48 122.99,33.39 122.79,33.59 119.66,33.59 118.84,34.41 105.32,34.41 103.68,36.05 102.42,36.05 100.66,37.81 100.66,45.39 105.38,50.12 106.88,50.12 110.41,53.65 110.41,58.95 111.04,59.59 111.72,59.59 112.38,60.25 112.38,61.78 111.68,62.48 111.19,62.48 111.19,62.49 v2(111.19,62.49) ; J63.A26 105.13,16.33 v2(109.63,16.33)
  BOTTOM w0.193: R635.2 110.69,62.99 v2(111.19,62.49) ; v2(122.59,21.83) 122.56,21.8 122.56,20.81 119.19,17.44 110.8,17.44 109.69,16.33 v2(109.63,16.33)
DADINTZ: length 120.9
  TOP w0.193: v2(80.42,16.99) 80.42,14.48 J63.B08
  L03_SIG1 w0.155: v2(115.94,68.94) 115.94,68.43 116.93,67.44 117.25,67.44 117.6,67.09 117.6,66.17 119.35,64.43 119.35,63.1 119.55,62.9 119.55,59.7 122.17,57.07 122.17,53.76 121.21,52.8 121.21,50.63 125.41,46.43 125.41,43.84 129.14,40.11 129.14,36.16 v2(128.42,35.44) 128.24,35.26 128.24,33.59 129.79,32.05 129.79,29.03 130.22,28.6 130.22,25.2 125.6,20.58 v2(125.51,20.58)
  BOTTOM w0.193: R595.2 115.66,69.22 v2(115.94,68.94) ; v2(125.51,20.58) 125.51,19.44 124.78,18.71 123.29,18.71 120.92,16.35 113.2,16.35 112.52,15.68 109.44,15.68 108.54,16.57 98.62,16.57 93.95,21.24 84.67,21.24 v2(80.42,16.99) ; R713.2 126.99,35.44 v2(128.42,35.44)
DADMD0: length 101.7
  TOP w0.193: J63.A06 78.51,16.39 80.69,18.57 96.18,18.57 96.64,19.03 110.95,19.03 112.49,17.49 118.64,17.49 122.35,21.2 122.85,21.2 123.29,21.64 123.29,22.43 121.6,24.12 121.6,25.83 120.76,26.66 v2(120.76,26.76)
  L03_SIG1 w0.155: v1(111.09,64.62) 110.55,64.62 109.78,63.84 109.78,55.31 110.72,54.36 110.72,52.47 117.5,45.69 117.5,40.34 117.71,40.13 117.71,37.39 118.79,36.31 118.79,30.57 117.98,29.76 117.98,27.74 118.96,26.76 v2(120.76,26.76)
  BOTTOM w0.193: v1(111.09,64.62) 110.99,64.52 R634.2
DADMD1: length 100.8
  TOP w0.193: J63.A10 83.59,16.63 84.97,18.01 96.48,18.01 96.97,18.5 110.75,18.5 112.15,17.1 118.77,17.1 122.41,20.74 v2(124.14,20.74)
  L03_SIG1 w0.155: v2(115.91,66.8) 117.81,64.9 117.81,60.1 119.95,57.96 119.95,56.61 120.9,55.65 120.9,53.87 120.5,53.47 120.5,50.34 124.71,46.12 124.71,43.29 126.61,41.39 126.61,39.46 126.61,39.46 126.61,38.87 126.61,38.41 127.19,37.83 127.19,33.16 128.59,31.76 128.59,29.25 127.36,28.02 127.36,24.43 124.14,21.22 v2(124.14,20.74)
  BOTTOM w0.193: R627.2 v2(115.91,66.8)
DADOEZ: length 106.2
  TOP w0.193: v2(110.64,20.8) 109.89,20.05 95.9,20.05 95.37,19.52 78.65,19.52 75.34,16.21 75.34,14.47 J63.B04
  L03_SIG1 w0.155: v1(110.83,65.49) 111.56,65.49 112.37,64.68 112.37,63.73 111.83,63.19 111.06,63.19 110.31,62.45 110.31,56.3 111.07,55.55 111.07,52.61 118.02,45.66 118.02,40.42 118.06,40.38 118.06,39.25 119.63,37.68 119.63,36.49 119.14,36 119.14,30.2 118.73,29.79 118.73,28.77 119.91,27.59 v2(121.59,27.59)
  L05_SIG2 w0.155: v2(121.59,27.59) 120.87,28.31 117.01,28.31 114.05,25.34 114.05,24.37 110.64,20.96 v2(110.64,20.8)
  BOTTOM w0.193: R633.2 110.61,65.28 110.87,65.54 110.87,65.49 v1(110.83,65.49) ; R714.2 124.2,29.39 123.39,29.39 v2(121.59,27.59)
DADSEL0: length 83.1
  TOP w0.193: v2(113.44,15.75) 109.63,15.75 J63.A30
  L03_SIG1 w0.155: v2(125.89,22.08) 128.07,24.26 128.07,28.17 129.16,29.25 129.16,32.06 127.61,33.61 127.61,37.92 127.02,38.51 127.02,41.72 125.06,43.67 125.06,46.28 120.85,50.49 120.85,53.19 121.69,54.03 121.69,57.02 119.08,59.64 119.08,62.66 118.83,62.91 118.83,64.44 117.01,66.27 v2(117.01,66.84)
  L05_SIG2 w0.155: v2(125.89,22.08) 124.9,21.09 124.9,14.58 122.82,12.5 116.8,12.5 116.53,12.77 116.53,13.55 116.34,13.74 115.68,13.74 115.35,14.08 115.35,14.84 115.13,15.05 114.64,15.05 113.95,15.75 v2(113.44,15.75)
  BOTTOM w0.193: R626.2 116.48,67.69 117.01,67.17 v2(117.01,66.84)
DADSEL1: length 65.6
  TOP w0.193: J63.A34 v2(114.71,15.75)
  L03_SIG1 w0.155: v2(116.34,62.23) 116.34,61.71 116.54,61.52 116.54,58.13 117.5,57.16 117.5,50.22 121.93,45.79 121.93,42.21 122.32,41.82 122.32,40.85 122.73,40.44 122.73,39.5 122.65,39.41 122.65,38.92 122.99,38.57 123.11,38.57 124.14,37.54 124.14,25.17 123.95,24.98 123.95,23.37 v2(123.87,23.28)
  L05_SIG2 w0.155: v2(114.71,15.75) 115.42,16.46 116.06,16.46 116.55,15.97 116.55,14.24 116.89,13.9 121.31,13.9 122.95,15.53 122.95,19.06 123.38,19.5 123.38,21.28 123.87,21.76 v2(123.87,23.28)
  BOTTOM w0.193: R630.2 v2(116.34,62.23)
DADSTB: length 55.9
  TOP w0.193: J63.A38 v2(119.79,15.75)
  L03_SIG1 w0.155: v2(120.66,21.15) 120.66,21.17 121.15,21.65 121.15,24.95 122.81,26.61 122.81,28.04 121.97,28.88 120.2,28.88 119.92,29.16 119.92,31.02 TP47.1 120.65,33.55 121.28,34.18 121.28,37.02 119.6,38.71 119.6,39.17 119.12,39.65 119.12,41.62 119.8,42.3 119.8,44.87 111.77,52.9 111.77,59.77 111.62,59.91 v2(111.62,60.43)
  L05_SIG2 w0.155: v2(120.66,21.15) 120.56,21.05 120.56,19.15 119.79,18.37 v2(119.79,15.75)
  BOTTOM w0.193: v2(111.62,60.43) 111.35,60.71 R636.2
DB/RED_PWM: length 235.2
  TOP w0.193: v2(59.69,94.11) 58.84,94.95 56.05,94.95 55.59,94.49 55.59,94.41 55.59,94.41 55.59,93.88 55.59,93.88 55.59,92.09 55.87,91.81 55.87,90.41 53.37,87.9 53.37,85.55 55.73,83.19 64.41,83.19 64.77,82.83 66.4,82.83 66.81,82.41 66.81,81.68 62.92,77.79 62.92,64.02 64.21,62.72 64.21,57.82 63.09,56.7 61.2,56.7 60.98,56.92 60.04,56.92 59.61,56.49 59.61,55.54 59.65,55.51 v2(59.68,55.51) ; U11.B19 v1(81.66,82.2)
  TOP w0.254: U8.2 59.03,93.1 59.69,93.76 v2(59.69,94.11)
  L03_SIG1 w0.155: v2(50.38,91.24) 52.7,93.57 52.7,100.98 53.27,101.54 53.27,101.54 53.62,101.89 53.98,102.26 53.98,108.46 v2(51.11,111.34) ; v2(67.32,21.65) 67.32,18.51 63.86,15.05 63.86,10.63 60.48,7.25 56.26,7.25 51.7,11.81 44.93,11.81 37.13,19.61 37.13,20.18 37.89,20.95 42.11,20.95 46.76,25.6 46.76,31.68 48.47,33.39 49.35,33.39 51.21,35.25 51.21,40.3 54.16,43.26 54.16,45.82 60.51,52.16 60.51,54.2 59.68,55.02 v2(59.68,55.51)
  BOTTOM w0.102: 79.69,79.67 80.85,79.67 81.25,80.07 81.25,81.2 81.27,81.22 81.27,81.41 81.66,81.81 v1(81.66,82.2)
  BOTTOM w0.193: v2(50.38,91.24) 53.49,94.35 55.44,94.35 56.17,95.08 58.72,95.08 v2(59.69,94.11) 61.06,94.11 63.39,91.78 63.39,89.97 68.73,84.63 68.73,80.61 71.45,77.9 76.97,77.9 78.8,79.73 79.64,79.73 79.69,79.67 ; U521.2 67.69,24.52 R757.2 67.7,22.03 v2(67.32,21.65) ; v2(51.11,111.34) 51.12,111.34 51.29,111.17 RN500.4
DINTZ: length 12.1
  TOP w0.193: U11.AC8 v1(103.66,70.2)
  L05_SIG2 w0.102: 107.63,71.48 107.3,71.81 105.11,71.81 104.9,71.59 104.5,71.59 104.06,71.15 104.06,71.04 103.66,70.64 v1(103.66,70.2)
  L05_SIG2 w0.155: 107.63,71.48 107.7,71.4 110.27,71.4 v1(111.57,70.1)
  BOTTOM w0.193: R595.1 C578.1 v1(111.57,70.1)
DM0: length 8.2
  TOP w0.193: U11.AE6 v1(105.66,68.2)
  BOTTOM w0.102: 107.63,68.24 107.18,68.7 106.16,68.7 v1(105.66,68.2)
  BOTTOM w0.193: C620.1 R634.1 108.84,64.52 108.46,64.9 108.46,66.23 108.07,66.62 108.07,67.8 107.63,68.24
DM1: length 13.3
  TOP w0.193: U11.AD7 v1(104.66,69.2)
  L05_SIG2 w0.102: v1(104.66,69.2) 104.66,69.21 104.27,69.61 104.27,70.46 104.42,70.6 104.91,70.6 105.11,70.81 107.2,70.81 107.2,70.79 107.45,70.54 107.63,70.54
  L05_SIG2 w0.155: 107.63,70.54 108.08,70.1 108.08,70.05 110.28,67.85 110.28,67.32 110.6,67.01 111.44,67.01 v1(111.58,67.15)
  BOTTOM w0.193: v1(111.58,67.15) 111.93,66.8 R627.1 C614.1
DMD_P3P3V: length 24.8
  TOP w0.508: v2(117.14,20.27) 117.14,20.21 116.64,19.7 C35.2 ; FB3.1 118.91,24.42 J46.2 117.43,24.42 ; R66.1 v2(68.9,18.8) ; 115.54,24 115.96,24.42 117.43,24.42 ; 117.43,24.42 v2(116,22.99) v2(116,21.79) 116.38,21.41 116.38,20.68 114.4,20.68 ; v2(114.4,21.84) 114.4,20.68 ; 114.4,20.68 FB2.1
  L07_PWR w0.508: 115.97,24.24 117.3,24.24 J46.2 118.66,23.23
  BOTTOM w0.508: R712.1 125.46,30.43 125.27,30.62 R714.1 122.01,30.62 121.93,30.54 ; 122.2,31.88 122.21,31.86 R713.1
DMDP3P3VA: length 0.9
  TOP w0.508: J63.C39 v2(121.06,13.21)
  vias: v2(119.16,19.93) v2(119.68,20.81)
DMDP3P3VB: length 3.2
  TOP w0.508: FB2.2 113.45,18.66 C34.2 v2(115.34,18.66) ; J63.D38 v2(119.79,11.94)
DMDSPARE0: length 8.5
  TOP w0.508: J63.B16 v2(91.85,14.48) ; R44.1 v2(93.26,20.22)
  BOTTOM w0.508: v2(91.85,14.48) 93.26,15.89 v2(93.26,20.22)
DOEZ: length 7.8
  TOP w0.193: U11.AE7 v1(105.66,69.2)
  BOTTOM w0.102: v1(105.66,69.2) 106.25,69.79 107.25,69.79 107.61,69.43
  BOTTOM w0.193: R633.1 C619.1 109.02,66.37 108.44,66.94 108.44,68.08 107.61,68.91 107.61,69.43
DRV_RST/SSP2_CSZ_1: length 109.2
  TOP w0.193: U11.K22 v1(89.66,85.2)
  L03_SIG1 w0.102: 79.69,77.63 79.83,77.77 85.79,77.77 86.06,78.04 86.06,78.46 87.6,80.01 87.6,82.44 88.53,83.36 89.01,83.36 89.25,83.6 89.91,83.6 90.26,83.95 90.26,84.45 89.66,85.04 v1(89.66,85.2)
  L03_SIG1 w0.155: 79.69,77.63 78.64,76.58 75.52,73.46 74.58,73.46 74.3,73.18 74.3,70.3 75.81,68.79 75.81,68 74.96,67.15 74.96,64.58 76.45,63.08 76.45,61.55 78.68,59.31 78.68,52.36 76.99,50.66 76.99,41.97 72.98,37.96 72.98,34.94 71.72,33.68 71.72,32.65 67.34,28.27 67.34,23.96 64.6,21.22 64.6,19.64 61.07,16.12 v2(59.17,16.12)
  L05_SIG2 w0.155: v2(59.17,16.12) 58.34,15.28 55.47,15.28 55.04,14.86 55.04,14.42 53.84,13.21 52.92,13.21 v2(49.15,16.98)
  BOTTOM w0.193: v2(49.15,16.98) 50.2,15.93 U516.6
DS0: length 13.9
  TOP w0.193: U11.AC7 v1(103.66,69.2)
  L05_SIG2 w0.102: 107.2,71.3 107.2,71.3 107.12,71.3 106.83,71.59 105.45,71.59 105.06,71.2 105.06,71.04 104.83,70.81 104.24,70.81 104.06,70.62 104.06,69.59 v1(103.66,69.2)
  L05_SIG2 w0.155: 107.2,71.3 107.53,70.97 110.09,70.97 111.04,70.03 111.04,69.71 111.44,69.3 v1(111.44,68.45)
  BOTTOM w0.193: v1(111.44,68.45) C613.1 R626.1
DS1: length 11.9
  TOP w0.102: U11.AE4 105.2,66.7 105.69,66.22 106.57,66.22 107.63,65.16
  TOP w0.193: v1(111.7,61.55) 110.92,60.77 110.21,60.77 108.15,62.83 108.15,64.64 107.63,65.16
  BOTTOM w0.193: R630.1 C617.1 111.79,61.47 111.7,61.55 v1(111.7,61.55)
DSP_P1P8V: length 194.7
  TOP w0.254: J1.6 37.37,112.55 v2(37.59,112.33) 37.87,112.61 J1.8 ; J2.8 88.99,112.61 v2(88.71,112.33) 88.49,112.55 J2.6
  TOP w0.381: v2(88.71,112.33) 87.48,111.1 C13.1
  TOP w0.508: v2(37.59,112.33) 37.59,111.52 C10.1 ; v2(75.09,126.25) 79.34,130.5 81.19,130.5 81.63,130.94 123.91,130.94 130.63,124.22 133.94,124.22 134.44,124.73 135.8,124.73 137.51,126.44 142.78,126.44 v2(143.97,125.25)
  L03_SIG1 w0.508: v2(143.97,125.25) 145.95,123.27 145.95,99 146.58,98.36 146.58,95.76 144.56,93.74 J12.2
  BOTTOM w0.508: v2(88.71,112.33) 88.71,112.47 87.52,113.66 86.18,113.66 83.44,116.4 83.44,117.28 83.5,117.35 83.5,122.3 79.59,126.2 77.97,126.2 77.53,126.64 75.48,126.64 v2(75.09,126.25) 74.6,126.25 72.97,124.63 72.97,121.9 70.56,119.48 64.61,119.48 61.65,116.52 58.1,116.52 56.38,114.8 54.81,114.8 53.41,116.21 48.27,116.21 46.74,117.73 41.67,117.73 37.59,113.65 v2(37.59,112.33)
DSTB: length 8.5
  TOP w0.193: U11.AF5 106.56,67.7 v1(107.1,67.17)
  BOTTOM w0.102: v1(107.1,67.17) 107.1,67.17 107.33,66.95 107.33,65.88 107.47,65.74 107.47,64.25 107.63,64.09
  BOTTOM w0.193: 107.63,64.09 107.92,63.8 107.92,63.51 108,63.43 108,63.18 108.21,62.97 108.21,62.1 108.84,61.47 C622.1 R636.1
DYN_BLK_BUF: length 2.1
  BOTTOM w0.193: R756.2 66.83,29.69 66.75,29.61 U521.4
EXT_ARSTZ: length 434.9
  TOP w0.193: TP4.1 46.15,110.38 R8.2 ; U11.T24 v1(96.66,87.2) ; J63.A02 v2(72.8,15.75) 78.59,21.54 94.38,21.54 95.46,20.47 108.78,20.47 v2(109.46,21.15) ; R10.1 v2(65.02,109.86)
  L03_SIG1 w0.155: TP4.1 46.04,90.53 29.13,73.63 29.13,61.53 28.55,60.95 24.32,56.72 24.32,22.25 30.13,16.43 30.13,14.74 31.06,13.81 31.06,10.28 31.81,9.53 37.23,9.53 38.08,8.68 40.31,8.68 41.3,9.66 45.77,9.66 46.55,8.89 53.19,8.89 56,6.08 61.65,6.08 66.2,10.63 v2(66.2,12) ; v2(65.02,109.86) 64.13,108.96 64.13,104.4 65.31,103.22 65.82,103.22 69.22,99.83 69.22,97.49 75.67,91.05 v2(77.23,91.05)
  L05_SIG2 w0.155: v2(109.46,21.15) 112.1,23.79 112.1,26.92 114.56,29.39 118.23,29.39 119.2,30.35 125.42,30.35 126.75,31.67 128.08,31.67 128.63,31.13 128.63,29.41 128.33,29.11 128.33,27.94 129.24,27.03 174.9,27.03 176.99,24.94 190.83,24.94 196.95,18.82 196.95,15.35 192.42,10.82 192.42,6.61 188.42,2.62 v2(172.09,2.62) ; v2(66.2,12) 67.27,12 68.61,13.33 68.61,15.77 69.19,16.36 72.18,16.36 v2(72.8,15.75) ; v2(65.02,109.86) 64.49,110.39 58.16,110.39 55.74,112.81 53.82,112.81 52.2,114.43 52.2,117.41 52.99,118.2 52.99,120.36 52.24,121.1 50.39,121.1 46.04,116.75 TP4.1
  BOTTOM w0.102: v1(96.66,87.2) 96.66,86.79 96.15,86.28 96.15,86.13 95.83,85.81 95.42,85.81 95.07,85.45 95.07,85.22 95.06,85.21 95.06,85.04 94.78,84.76 94.56,84.76 94.39,84.59 93.16,84.59 92.95,84.81 91.83,84.81 91.83,84.81 91.5,84.81 91.5,84.81 89.5,84.81 89.27,85.04 89.27,85.51 88.98,85.8 88.49,85.8 88.26,86.02 88.26,86.45 88.06,86.65 88.06,88.4 87.65,88.81 84.37,88.81 84.15,89.03 84.15,89.84 83.67,90.32 82.95,90.32 79.69,90.32
  BOTTOM w0.193: 79.69,90.32 78.79,90.32 78.06,91.05 v2(77.23,91.05) ; R767.1 171.82,2.93 172.09,2.67 v2(172.09,2.62)
EXT_CLK: length 69.5
  TOP w0.193: J2.52 99.99,112.13 100.82,111.3 101.46,111.3 v2(101.54,111.38)
  L03_SIG1 w0.102: 107.43,81.03 107.21,80.81 106.45,80.81 106.27,80.98 106.27,86.16 106.26,86.17 106.26,86.45 105.9,86.81 105.5,86.81 105.5,86.81 104.39,86.81 104.27,86.68 104.27,80.72 104.14,80.6 103.19,80.6 103.07,80.47 103.07,76.6 102.54,76.07 100.52,76.07 v1(100.51,76.06)
  L03_SIG1 w0.155: 107.43,81.03 109.08,81.03 114.24,86.19 114.24,93.74 114,93.98 113.55,93.98 113.12,94.4 112.08,94.4 111.9,94.58 111.9,95.62 111.54,95.99 111.54,99.58 110.28,100.83 109.26,100.83 108.56,101.53 107.82,102.27 106.52,102.27 106.02,102.77 106.02,102.97 105.92,103.07 105.92,104.16 104.22,105.87 104.22,107.58 104,107.8 104,108.55 103.13,109.42 102.42,109.42 102.05,109.78 102.05,110.87 v2(101.54,111.38)
  BOTTOM w0.102: R579.1 100.39,75.95 v1(100.51,76.06)
FAN1_LOCKD: length 309.9
  TOP w0.193: v2(53.51,112.12) 53.51,112.09 53.84,112.42 54.85,112.42 57.5,109.77 60.34,109.77 61.87,108.24 62.82,108.24 64.08,106.98 65.2,106.98 66.72,105.46 66.72,99.27 71.63,94.36 74.94,94.36 75.63,95.06 75.63,98.64 v2(75.85,98.86) ; J59.2 140.97,6.65 140.86,6.77 R71.1 140.86,14.1 v2(141.02,14.27) ; U11.B24 v1(81.66,87.2)
  L03_SIG1 w0.155: v2(53.51,112.12) 52.53,112.12 51.62,113.03 32.44,113.03 26.54,107.13 26.54,86.89 27.34,86.09 27.34,62.32 22.89,57.87 v2(22.89,32.95) ; v1(81.66,87.2) 81.16,87.71 81.16,89.39 75.81,94.74 75.81,98.82 v2(75.85,98.86)
  L05_SIG2 w0.155: v2(22.89,32.95) 25.19,30.64 37.61,30.64 39.8,28.45 50.46,28.45 53.77,31.76 v2(54.3,31.76)
  BOTTOM w0.193: v2(141.02,14.27) 139.85,15.45 137.39,15.45 136.58,14.65 132.19,14.65 130.3,16.54 125.9,16.54 123.89,14.52 123.89,13.11 122.06,11.28 71.29,11.28 70.74,10.73 66.13,10.73 58.69,18.17 58.69,27.36 v2(54.3,31.76)
FAN1_SW: length 86
  TOP w0.254: U15.40 v1(158.64,57.75)
  L03_SIG1 w0.508: v1(158.64,57.75) 158.62,57.73 158.68,57.73 159.96,56.45 159.96,53.02 159.51,52.58 159.51,45.34 155.96,41.78 155.96,30.73 161.42,25.27 161.42,20.96 163.7,18.67 163.7,15.37 160.59,12.25 v2(141.93,12.25)
  BOTTOM w0.508: v2(141.93,12.25) 141.48,12.7 L505.2
  BOTTOM w1.27: R770.1 136.91,6.86 D507.1 135.76,8 135.76,9.82 138.12,12.18 L505.2
FAN2_LOCKD: length 148.4
  TOP w0.193: v2(152.87,13.69) 152.92,13.65 R72.1 152.92,6.72 153.03,6.61 J60.2 ; U11.D21 v1(83.66,84.2)
  L03_SIG1 w0.155: v2(128.59,73.96) 128.54,73.96 128.54,57.89 131.37,55.06 131.58,55.06 134.95,51.69 135.88,51.69 139.09,48.48 139.09,48.02 141.24,45.87 141.24,44.83 144.54,41.53 144.54,32.39 143.09,30.95 143.09,22.79 v2(135.77,15.46)
  L05_SIG2 w0.102: v1(83.66,84.2) 84,84.2 84.61,83.59 84.83,83.59 85.06,83.36 85.06,83.14 85.61,82.59 85.83,82.59 86.06,82.36 86.06,82.07 88.49,79.63 88.6,79.63 89.38,78.85 89.38,78.64 90.34,77.69 96.73,77.69 97.06,77.36 97.06,76.65 98.67,75.04 99.2,75.04 99.43,74.81 107.15,74.81
  L05_SIG2 w0.155: v2(135.77,15.46) 136.05,15.46 136.11,15.39 151.17,15.39 v2(152.87,13.69) ; 107.15,74.81 107.93,74.81 108.49,74.25 121.84,74.25 122.12,73.96 v2(128.59,73.96)
FAN2_SW: length 60
  TOP w0.254: U15.39 158.14,55.3 v2(157.88,55.04)
  L03_SIG1 w0.508: v2(147.59,14.19) 153.8,20.4 153.8,45.21 154.56,45.97 154.56,51.72 v2(157.88,55.04)
  BOTTOM w0.508: v2(147.59,14.19) 149.61,14.19 150.19,13.61 L504.2
  BOTTOM w1.27: L504.2 150.19,12.18 147.83,9.82 147.83,8 D506.1 148.97,6.86 R769.1
FAN3_LOCKD: length 260.7
  TOP w0.102: U11.C23 v1(82.66,86.2)
  TOP w0.193: J61.2 164.47,7.91 164.99,8.44 R73.1 164.12,8.66 159.48,8.66 158.75,7.92 v2(158.75,5.98)
  L03_SIG1 w0.155: v2(40.96,46.65) 40.96,48.85 45.88,53.77 46.66,53.77 49.23,56.34 49.23,60.48 47.48,62.23 47.48,63.99 51.44,67.95 53.96,67.95 55.04,69.02 55.38,69.02 56.84,70.48 56.84,71.02 55.66,72.19 55.66,73.02 56.9,74.25 57.85,74.25 58.26,74.67 58.26,75.09 60.52,77.35 61.13,77.35 64.65,80.87 65.65,80.87 66.71,81.92 66.71,81.92 68.45,83.67 68.45,84.96 69.42,85.92 69.42,85.93 70.24,86.75 70.24,86.96 70.8,87.52 70.8,89.29 71.39,89.89 75.22,89.89 80.4,84.71 82.93,84.71 83.19,84.96 83.19,85.68 v1(82.66,86.2) ; v2(60.31,8.25) 56.35,12.21 56.35,14.77 55.87,15.26 47.38,15.26 45.8,16.84 45.8,22 49.43,25.63 49.43,27 51.24,28.81 51.24,33.44 54.65,36.85 v2(54.65,41.35)
  L05_SIG2 w0.155: v2(54.65,41.35) 54.65,42.95 53.34,44.25 47.33,44.25 46.21,45.37 42.24,45.37 v2(40.96,46.65) ; v2(158.75,5.98) 157.68,7.05 139.48,7.05 134.94,11.59 v2(123.26,11.59)
  BOTTOM w0.193: v2(60.31,8.25) 62.08,10.01 122.9,10.01 123.26,10.37 v2(123.26,11.59)
FAN3_SW: length 61.7
  TOP w0.203: v1(157.23,57.79) 157.64,57.37 U15.38
  L03_SIG1 w0.508: v2(162.25,15.75) 162.25,15.8 160.02,18.03 160.02,23.75 154.94,28.83 154.94,43.48 156.63,45.17 156.63,50.08 157.73,51.18 157.73,52.45 158.9,53.62 158.9,55.6 157.23,57.28 v1(157.23,57.79)
  BOTTOM w0.508: L503.2 v2(162.25,15.75)
  BOTTOM w1.27: R768.1 161.04,6.86 D505.1 159.89,8 159.89,9.82 162.25,12.18 L503.2
FAN4_LOCKD: length 174.9
  TOP w0.193: R57.1 139.7,22.24 J37.2 v2(139.7,25.94)
  L03_SIG1 w0.155: v2(52.08,49.86) 52.42,50.2 52.42,54.47 54.44,56.5 55.88,56.5 56.57,57.18 56.57,63.6 59.02,66.06 59.02,67.85 59.3,68.28 59.3,68.53 60.16,69.39 60.16,70.77 60.2,70.81 62.02,72.63 62.02,72.63 70.56,81.17 v2(73.93,81.17)
  BOTTOM w0.193: v2(73.93,81.17) 73.95,81.15 R581.2 ; v2(52.08,49.86) 52.08,46.13 64.38,33.83 72.9,33.83 81.52,25.21 91.48,25.21 97.46,19.23 112.14,19.23 113.26,20.36 116.17,20.36 117.47,19.06 119.51,19.06 121.4,20.95 121.4,22.26 123.05,23.91 123.96,23.91 124.61,24.57 124.61,24.73 129.46,29.58 134.53,29.58 139.81,34.86 143.66,34.86 144.67,33.85 144.67,33.12 143.48,31.94 141.97,31.94 139.7,29.67 v2(139.7,25.94)
FAN4_SW: length 145.7
  TOP w0.254: U2.40 159.91,108.21 159.49,107.8 159.06,107.8 159.05,107.79 158.98,107.79 v2(158.91,107.72)
  L03_SIG1 w0.508: v2(175.51,109.83) 174.47,108.79 174.47,86.62 173.68,85.82 173.68,65.54 174.31,64.9 174.91,64.9 176.64,63.18 176.64,61.64 177.19,61.09 177.19,56.38 175.2,54.38 174.82,54.38 170.55,50.11 170.55,48.41 168.55,46.41 168.55,40.99 v2(160.51,32.96)
  L05_SIG2 w0.508: v2(158.91,107.72) 158.94,107.68 162.56,107.68 163.44,106.81 171.99,106.81 175.01,109.83 v2(175.51,109.83)
  BOTTOM w0.508: v2(160.51,32.96) 150.69,32.96 148.24,30.5 142.13,30.5 140.7,29.07 140.7,25.74 140.05,25.09 137.33,25.09 136.85,25.57 136.85,26.15
  BOTTOM w1.27: R734.1 135.64,20.83 D504.1 135.13,24.43 136.85,26.15 L502.2
FAN5_LOCKD: length 302.2
  TOP w0.193: R58.1 153.03,22.24 J38.2 v2(153.03,25.83)
  L03_SIG1 w0.155: v2(66.84,15.59) 66.84,14.2 65.31,12.67 65.31,10.9 61.07,6.66 56.2,6.66 53.21,9.66 46.85,9.66 45.91,10.6 38.63,10.6 38.03,10.01 33.64,10.01 33.09,10.56 33.09,12.35 32.53,12.91 32.53,18.47 31.61,19.39 31.61,24.11 32.93,25.44 33.82,25.44 34.29,24.96 34.29,24.29 34.06,24.05 32.9,24.05 32.61,23.75 32.61,23.15 32.9,22.86 34.57,22.86 34.86,23.14 37.92,23.14 40.22,25.44 40.79,25.44 41.78,26.42 41.78,36.7 43.14,38.06 43.39,38.06 44.58,39.25 44.58,43.03 45.46,43.92 49.36,43.92 50.92,45.48 50.92,50.76 49.85,51.83 49.85,53.85 52.12,56.12 52.12,59.44 54.07,61.39 54.07,63.77 58.31,68.01 58.31,68.23 58.59,68.51 58.59,68.82 59.45,69.68 59.45,71.07 60.71,72.33 70.93,82.55 71.95,82.55 72.45,83.06 v2(73.91,83.06)
  BOTTOM w0.193: v2(153.03,25.83) 153.03,27.57 155.89,30.42 162.69,30.42 163.83,29.28 163.83,25.61 164.55,24.89 165.66,24.89 166.19,25.41 166.19,28.88 167.21,29.9 168.72,29.9 170.3,28.31 170.3,24.87 171.31,23.86 171.31,17.51 169.32,15.51 165.18,15.51 164.05,16.64 161.94,16.64 161.55,16.25 139.86,16.25 139.38,16.74 131.82,16.74 130.27,18.29 126.41,18.29 121.95,13.83 69.5,13.83 67.74,15.59 v2(66.84,15.59) ; R567.2 v2(73.91,83.06)
FAN5_SW: length 152.2
  TOP w0.254: U2.39 159.41,110.17 159.5,110.26 159.5,110.4 v1(159.55,110.45)
  L03_SIG1 w0.508: v2(153.41,107.45) 151.21,105.26 151.21,83.82 148.53,81.13 148.53,71.38 148.7,71.21 148.7,69.76 145.23,66.29 145.23,63.36 144.71,62.84 144.71,62.84 142.69,60.83 142.69,54.75 150.19,47.26 v2(150.19,30.54)
  L05_SIG2 w0.508: J3.1 181.2,122.56 175.11,116.46 175.11,112.33 176.53,110.91 176.53,109.52 172.53,105.52 164.76,105.52 164.52,105.29 163.89,105.29 163.66,105.52 160.53,105.52 159.38,106.67 158.75,106.67 158.13,106.05 153.81,106.05 153.33,106.53 153.33,107.37 v2(153.41,107.45) 153.33,107.53 153.33,108.82 154.09,109.58 154.81,109.58 155.17,109.22 155.19,109.22 155.76,108.65 157.91,108.65 159.55,110.29 v1(159.55,110.45)
  BOTTOM w0.508: L501.2 v2(150.19,30.54)
  BOTTOM w1.27: L501.2 150.19,26.15 147.83,23.79 147.83,21.97 D503.1 148.97,20.83 R733.1
FAN6_LOCKD: length 183.5
  TOP w0.193: v2(165.1,25.69) J39.2 165.1,22.24 R59.1
  L03_SIG1 w0.155: v2(54.33,49.07) 54.65,49.07 55.48,49.9 55.48,51.06 55.12,51.41 55.12,53.73 58.35,56.95 58.35,61.96 59.31,62.92 59.31,63.63 60.44,64.77 60.44,67.34 60.71,67.6 60.71,67.74 61.58,68.62 61.58,70.18 70.05,78.65 72.88,78.65 73.48,79.25 v2(73.9,79.25)
  BOTTOM w0.193: v2(54.33,49.07) 54.33,45.61 65.3,34.64 73.54,34.64 81.78,26.39 90.93,26.39 97.34,19.98 112.16,19.98 112.93,20.75 115.64,20.75 115.97,21.08 117.88,21.08 121.31,24.51 123.67,24.51 129.4,30.24 133.01,30.24 138.11,35.35 143.83,35.35 145.02,34.15 162.1,34.15 165.1,31.15 v2(165.1,25.69) ; R583.2 v2(73.9,79.25)
FAN6_SW: length 120.8
  L03_SIG1 w0.508: J3.3 185.61,119.2 183.07,116.66 183.07,109.66 183.77,108.96 183.77,100.43 184.76,99.44 184.76,97.16 183.56,95.96 183.56,91.39 175.91,83.74 175.91,67.56 180.39,63.09 180.39,55.39 175.65,50.66 174.94,50.66 172.83,48.55 172.83,47.14 172,46.32 172,38.88 162.25,29.13 v2(162.25,29.13)
  BOTTOM w0.508: L500.2 v2(162.25,29.13)
  BOTTOM w1.27: L500.2 162.25,26.15 159.89,23.79 159.89,21.97 D502.1 161.04,20.83 R732.1
FAN6_SW_JUMP: length 33.8
  TOP w0.203: U2.38 158.91,110.07 v1(158.5,110.49)
  L03_SIG1 w0.508: J3.2 182.44,123.72 180.4,123.72 173.9,117.22 168.77,117.22 165.2,113.66 165.2,112.69 162.24,109.73 159.26,109.73 v1(158.5,110.49)
FE_P1P2V: length 199.7
  TOP w0.254: J2.2 v2(87.49,112.4) 87.7,112.4 87.99,112.69 J2.4 ; J1.4 36.87,112.69 v2(36.58,112.4) 36.37,112.6 J1.2
  TOP w0.381: C12.1 86.21,111.12 v2(87.49,112.4)
  TOP w0.508: v2(108.35,129.37) 108.35,129.53 107.72,130.16 81.82,130.16 81.41,129.76 79.74,129.76 76.97,127 v2(76.97,125.57) ; C9.1 36.58,111.26 v2(36.58,112.4)
  L03_SIG1 w0.508: v2(146.61,125.5) 146.61,124.82 146.98,124.45 146.98,99.68 147.95,98.71 147.95,88.13 146.84,87.02 145.15,87.02 144.56,86.43 J13.2
  L05_SIG2 w0.508: v2(36.58,112.4) 36.58,112.51 37.37,113.3 39.8,113.3 v2(40.67,112.44) ; v2(108.35,129.37) 108.46,129.48 121.43,129.48 121.98,130.03 123.34,130.03 129.74,123.63 144.74,123.63 v2(146.61,125.5)
  BOTTOM w0.508: 76.93,125.57 76.45,125.09 74.8,125.09 73.94,124.23 73.94,121.87 70.69,118.62 70.23,118.62 66.12,114.5 63.25,114.5 62.82,114.07 54.57,114.07 53.2,115.45 42.57,115.45 40.67,113.55 v2(40.67,112.44) ; 76.93,125.57 v2(76.97,125.57) ; 76.93,125.57 76.98,125.52 79.31,125.52 82.56,122.27 82.56,120.3 82.25,120 82.25,116 85.85,112.4 v2(87.49,112.4)
FE_RST: length 11.6
  TOP w0.193: U18.2 130.05,21.12 129.55,21.62 R56.2 129.55,21.85 130.72,23.01 130.72,25.11 129.38,26.45 J36.1
FIELD: length 168.8
  TOP w0.193: U11.AF9 v1(106.66,71.2) 108.83,73.37 121.2,73.37 121.43,73.6 v2(121.52,73.6) 121.54,73.62 121.54,74.69 121.1,75.14 121.1,84.33 121.12,84.35 121.12,91.98 131.41,102.27 131.41,115.86 133.22,117.67 134.04,117.67 134.65,118.29 134.65,119.64 v2(134.56,119.73) ; J36.3 127.11,28.95 v2(127.97,29.8) ; v2(113.99,115.21) 113.99,114.24 J2.88
  L03_SIG1 w0.155: v1(106.66,71.2) 109.37,71.2 109.73,71.56 114.09,71.56 116.13,73.6 v2(121.52,73.6)
  BOTTOM w0.193: v2(127.97,29.8) 129.46,31.3 129.46,36.28 131.96,38.78 133.03,38.78 134.13,39.88 134.13,41.05 134.55,41.47 134.55,48.57 133.09,50.03 130.02,50.03 128.57,51.47 128.57,59.47 127.07,60.97 127.07,67.22 124.92,69.37 124.92,69.86 124.42,70.35 123.33,70.35 121.57,72.12 121.57,73.55 v2(121.52,73.6) ; v2(134.56,119.73) 134.56,119.21 134.59,119.18 134.59,117.09 132.97,115.47 126.67,115.47 126.37,115.77 125.11,115.77 123.88,114.53 114.66,114.53 v2(113.99,115.21)
FLASH_A19_A21: length 3.9
  TOP w0.193: U14.11 53.49,57.56 v2(53.07,57.14)
  BOTTOM w0.193: v2(53.07,57.14) 53.07,56.19 R687.2 R689.2
FLASH_A21_VPP: length 4.1
  TOP w0.193: v2(54.91,57.24) 55.49,57.82 U14.15
  BOTTOM w0.193: v2(54.91,57.24) 54.93,57.24 54.96,57.21 54.96,56.31 R685.1 R686.2
FLASH_CSSZ: length 4.2
  TOP w0.254: v2(60.49,80.6) 60.49,78.27
  BOTTOM w0.254: v2(60.49,80.6) 60.49,79.38 60.45,79.34 R585.2
FLASH_CSZ: length 31.9
  TOP w0.193: U11.E12 v1(84.66,74.2)
  BOTTOM w0.102: 79.69,76.87 79.86,76.87 79.92,76.81 83.05,76.81 83.27,77.03 83.27,77.36 83.5,77.59 84.01,77.59 84.15,77.73 84.55,77.73 84.69,77.59 84.83,77.59 85.06,77.36 85.06,77.04 84.9,76.88 84.9,75.52 85.06,75.36 85.06,75.04 84.66,74.64 v1(84.66,74.2)
  BOTTOM w0.193: R585.1 60.45,76.97 61.56,75.86 65.81,75.86 66.78,76.82 68.42,76.82 69.28,75.96 78.67,75.96 79.58,76.87 79.69,76.87
FLASH_RSTZ: length 192.3
  TOP w0.193: v2(55.05,63.44) 54.8,63.18 54.8,61.53 55,61.34 U14.14 ; v2(27.13,106.89) 27.09,106.93 27.09,112.08 31.23,116.21 55.68,116.21 55.88,116.01 55.88,115.1 55.71,114.94 55.71,113.12 57.43,111.4 60.46,111.4 62.74,109.13 66.32,109.13 68.76,106.7 74.63,106.7 75.2,106.13 82,106.13 82.71,106.83 84,106.83 84.66,106.18 84.66,103.09 83.22,101.65 82.2,101.65 79.44,98.89 79.44,93.19 80.24,92.39 82.68,92.39 83.97,91.1 107.44,91.1 v2(109.59,88.94)
  L03_SIG1 w0.155: v2(31.49,78.06) 31.49,100.62 34.84,103.97 34.84,105.78 33.74,106.89 v2(27.13,106.89)
  BOTTOM w0.193: v2(31.49,78.06) 32.18,77.37 34.71,77.37 40.43,71.65 45.64,71.65 46.22,71.07 46.44,71.07 49.26,68.25 50.95,68.25 55.05,64.15 v2(55.05,63.44) ; v2(109.59,88.94) R553.1 R552.1
FREQ_SENSOR: length 9.1
  TOP w0.193: J29.3 117.13,36.3 117.13,37.08 118.53,38.48 119.97,38.48 120.48,38.99 122.08,38.99 122.56,38.51 J25.2
GPIO_12: length 54.6
  TOP w0.193: U11.B22 v1(81.66,85.2)
  L03_SIG1 w0.102: 81.67,90.08 82.06,89.7 82.06,85.61 81.66,85.22 v1(81.66,85.2)
  L03_SIG1 w0.155: 81.67,90.08 77.43,94.32 77.43,95.31 76.57,96.17 76.57,99.05 76.16,99.45 70.1,99.45 65.97,103.58 65.46,103.58 64.77,104.27 64.77,107.05 68.08,110.36 68.99,110.36 73.05,114.43 73.66,114.43 74.13,114.9 v2(74.13,115.77)
  BOTTOM w0.193: R513.1 78.68,119.01 R514.1 77.2,118.99 74.13,115.91 v2(74.13,115.77)
GPIO_13: length 59
  TOP w0.193: R14.1 R13.1 87.12,102.28 83.84,99 80.53,99 v2(80.16,98.63) ; U11.C21 v1(82.66,84.2)
  L05_SIG2 w0.155: v2(69.23,95.82) 69.23,97.31 71.84,99.92 78.06,99.92 79.35,98.63 v2(80.16,98.63)
  BOTTOM w0.102: 79.69,81.91 79.69,82.71 80.8,83.82 81.49,83.82 81.5,83.81 81.83,83.81 81.84,83.82 82.28,83.82 v1(82.66,84.2)
  BOTTOM w0.193: 79.69,81.91 76.43,78.64 72.13,78.64 70.22,80.56 70.22,87.32 68.87,88.66 68.87,95.47 v2(69.23,95.82)
GPIO_21: length 56.4
  TOP w0.193: U11.E20 v1(84.66,83.2)
  TOP w0.254: U8.10 59.52,87.89 v2(59.62,87.8)
  BOTTOM w0.102: v1(84.66,83.2) 84.06,82.59 84.06,78.97 83.73,78.64 83.34,78.64 83.06,78.36 83.06,78.04 82.83,77.81 80.31,77.81 80.03,78.08 79.69,78.08
  BOTTOM w0.193: 79.69,78.08 79.56,78.08 78.21,76.73 69.67,76.73 68.54,77.86 67.43,77.86 62.68,82.61 62.68,86.58 61.69,87.57 60.45,87.57 60.22,87.8 v2(59.62,87.8) 58.67,86.86 58.67,85.09 58.08,84.5 54.65,84.5 52.74,86.4 49.13,86.4 48.68,85.95 48.67,85.95 48.45,85.73 48.45,84.55 48.79,84.22 RN503.3
GPIO_23: length 55
  TOP w0.193: U11.E21 v1(84.66,84.2)
  TOP w0.254: v2(60.77,86.93) 59.5,86.93 59.19,87.24 U8.11
  BOTTOM w0.102: v1(84.66,84.2) 85.14,83.72 85.14,83.12 84.83,82.81 84.62,82.81 84.26,82.45 84.26,78.51 84.06,78.3 84.06,78.04 83.83,77.81 83.11,77.81 82.91,77.6 79.69,77.6
  BOTTOM w0.193: 79.69,77.6 78.44,76.35 69.5,76.35 68.5,77.34 67.22,77.34 62.16,82.4 62.16,85.54 v2(60.77,86.93) 60.2,86.36 60.2,85.47 58.69,83.96 54.49,83.96 52.58,85.88 50.11,85.88 RN503.4
GPIO_24: length 40.3
  TOP w0.193: v2(53.72,91.2) 53.72,93.96 55.47,95.71 55.47,97.44 54.39,98.52 J9.2 ; U11.B26 v1(81.66,89.2)
  L05_SIG2 w0.155: v2(53.72,91.2) 54.56,92.04 58.49,92.04 58.9,91.63 60.13,91.63 60.37,91.87 61.11,91.87 61.78,91.19 66.53,91.19 67.72,90 68.41,90 68.84,90.44 69.99,90.44 70.71,91.15 72.89,91.15 73.39,91.65 77.64,91.65 78.77,90.52 80.34,90.52 v1(81.66,89.2)
GPIO_26: length 118.3
  TOP w0.193: J40.2 25.28,11.78 26.77,11.78 27.57,12.58 v2(33.76,12.58) ; U11.D24 v1(83.66,87.2)
  L03_SIG1 w0.102: 79.69,83.28 79.98,83.28 80.01,83.25 81.06,83.25 81.5,82.81 84.01,82.81 84.27,83.07 84.27,83.36 84.5,83.59 84.69,83.59 85.06,83.96 85.06,86.64 84.89,86.81 84.06,86.81 v1(83.66,87.2)
  L03_SIG1 w0.155: v2(33.76,12.58) 35.06,13.88 35.06,21.76 35.37,22.07 38.58,22.07 40.46,23.95 41.08,23.95 43.66,26.53 43.66,31.28 46.14,33.75 46.14,39.03 52.2,45.09 52.2,47.85 54.05,49.7 54.7,49.7 55.07,50.06 55.07,50.76 54.66,51.17 54.66,53.76 57.89,57 57.89,62.12 58.82,63.05 58.82,64.35 60.09,65.62 60.09,67.49 60.35,67.75 60.35,67.89 61.23,68.76 61.23,70.33 61.27,70.37 62.33,71.44 70.02,79.12 72.72,79.12 73.68,80.09 74.67,80.09 77.86,83.28 79.69,83.28
GPIO_30: length 7.7
  TOP w0.193: U11.D25 v1(83.66,88.2)
  BOTTOM w0.102: 79.69,87.81 83.27,87.81 v1(83.66,88.2)
  BOTTOM w0.193: 79.69,87.81 77.95,87.81 77.87,87.88 R564.2
GPIO_32: length 9.4
  TOP w0.193: U11.E24 v1(84.66,87.2)
  BOTTOM w0.102: v1(84.66,87.2) 84.27,86.81 79.69,86.81
  BOTTOM w0.193: 79.69,86.81 78.56,86.81 R565.2
GPIO_33: length 9.1
  TOP w0.193: U11.D26 v1(83.66,89.2)
  BOTTOM w0.102: v1(83.66,89.2) 83.15,89.71 79.69,89.71
  BOTTOM w0.193: 79.69,89.71 77.55,89.71 76.71,90.55 R560.2
GPIO_40: length 130.4
  TOP w0.193: U11.T23 v1(96.66,86.2)
  BOTTOM w0.102: v1(96.66,86.2) 96.66,86.07 96.19,85.59 95.5,85.59 95.27,85.36 95.27,85.04 95.5,84.81 95.64,84.81 95.83,84.62 96.4,84.62 96.42,84.6 97,84.6 97.36,84.24 97.94,84.24 98.3,84.6 99.41,84.6 101.28,84.6 101.28,84.6 106.86,84.6 107.11,84.35 107.11,84.1 107.63,83.57
  BOTTOM w0.193: R547.1 68.67,104.71 70.87,106.92 79.36,106.92 80.42,107.98 102.71,107.98 102.93,108.2 106.48,108.2 106.88,107.8 119.51,107.8 120.63,106.68 124.36,106.68 128.3,102.74 128.3,102.36 129.38,101.28 129.61,101.28 130.35,100.54 130.35,98.9 132.7,96.55 132.7,95.4 134.48,93.62 134.48,86.11 134.48,85.25 134.03,84.8 134.03,84.14 133.28,83.4 133.28,82.68 132.32,81.71 129.54,81.71 129.06,82.19 123.22,82.19 122.48,82.94 108.27,82.94 107.63,83.57
GPIO_41: length 124.9
  TOP w0.193: U11.R22 v1(95.66,85.2)
  BOTTOM w0.102: v1(95.66,85.2) 95.81,85.06 95.81,84.93 95.91,84.82 96.48,84.82 96.5,84.81 97.14,84.81 97.38,84.57 97.95,84.57 98.18,84.81 99.5,84.81 99.5,84.81 101.19,84.81 101.19,84.81 107.14,84.81 107.34,84.61 107.34,84.41 107.63,84.11
  BOTTOM w0.193: 107.63,84.11 108.29,83.46 122.82,83.46 123.48,82.8 129.01,82.8 129.67,82.14 132.2,82.14 132.77,82.71 132.77,83.43 133.63,84.29 133.63,85.31 134.1,85.79 134.1,93.4 132.31,95.19 132.31,96.36 129.97,98.7 129.97,100.37 129.86,100.48 129.5,100.85 129.28,100.85 127.91,102.21 127.91,102.57 124.47,106.02 120.28,106.02 118.89,107.4 106.65,107.4 106.26,107.79 103.17,107.79 102.93,107.55 80.82,107.55 79.8,106.53 71.76,106.53 v2(70.06,104.84) 70.04,104.82 R546.1
GPIO_42: length 116
  TOP w0.193: U11.U26 v1(97.66,89.2)
  BOTTOM w0.102: v1(97.66,89.2) 97.66,89.54 98.44,90.32 107.28,90.32 107.43,90.46 107.63,90.46
  BOTTOM w0.193: R545.1 71.06,102.15 v2(71.06,102.14) 71.74,101.46 72.43,101.46 73.53,100.36 75.03,100.36 75.69,99.7 76.24,99.7 78.49,97.45 80.49,97.45 83,99.96 83,101.07 84.57,102.64 87.14,102.64 87.49,102.99 99.54,102.99 102.27,100.26 113.08,100.26 113.53,100.72 119.28,100.72 119.89,100.11 119.89,99.09 118.91,98.11 118.91,97.06 119.85,96.12 127.44,96.12 128.62,94.94 128.62,93.93 129.33,93.22 129.33,91.05 126.74,88.46 126.74,88.14 125.72,87.12 125.12,87.12 123.9,88.34 123.9,90.96 123.19,91.67 115.39,91.67 111.53,87.81 109.33,87.81 108.41,88.74 108.41,89.76 107.7,90.46 107.63,90.46
GPIO_43: length 118.7
  TOP w0.193: U11.U25 v1(97.66,88.2)
  BOTTOM w0.102: v1(97.66,88.2) 98.07,88.6 98.07,89.45 98.68,90.06 107.41,90.06 107.63,89.84
  BOTTOM w0.193: 107.63,89.84 107.91,89.57 107.91,88.69 109.18,87.41 112.08,87.41 115.75,91.08 122.61,91.08 122.99,90.7 122.99,89.97 122.66,89.64 120.88,89.64 120.6,89.36 120.6,88.72 120.98,88.35 123.35,88.35 125.06,86.64 125.95,86.64 127.26,87.94 127.26,88.46 129.72,90.92 129.72,93.36 129.05,94.03 129.05,95.1 127.09,97.06 121.63,97.06 120.73,97.97 120.73,100.08 119.67,101.13 113.23,101.13 112.85,100.75 102.35,100.75 99.52,103.58 87.31,103.58 86.83,103.1 84.4,103.1 82.56,101.27 82.56,100.15 80.4,97.98 78.53,97.98 76.36,100.15 75.87,100.15 75,101.02 73.53,101.02 72.51,102.03 72.15,102.03 v2(72.07,102.11) R544.1
GPIO_44: length 114.1
  TOP w0.193: U11.U24 v1(97.66,87.2)
  BOTTOM w0.102: 107.63,88.43 107.63,88.52 107.26,88.89 107.26,89.48 107.02,89.72 98.63,89.72 98.27,89.36 98.27,87.81 v1(97.66,87.2)
  BOTTOM w0.193: R543.1 73.6,102.14 v2(73.52,102.06) 74.15,101.43 75.17,101.43 76.02,100.57 76.56,100.57 78.19,98.94 79.45,98.94 79.78,99.27 81.05,99.27 82.14,100.36 82.14,101.46 82.15,101.47 82.15,101.49 84.25,103.6 86.62,103.6 87.26,104.24 99.87,104.24 102.92,101.2 112.59,101.2 112.96,101.57 120.43,101.57 121.62,100.39 121.62,98.5 122.2,97.92 126.77,97.92 129.44,95.25 129.44,94.18 130.18,93.44 130.18,90.82 127.67,88.31 127.67,87.76 126.09,86.17 124.99,86.17 123.54,87.62 120.38,87.62 117.4,90.6 116.2,90.6 114.94,89.33 114.94,87.68 114.29,87.03 109.03,87.03 107.63,88.43
GPIO_45: length 118.9
  TOP w0.193: U11.U23 v1(97.66,86.2)
  BOTTOM w0.102: v1(97.66,86.2) 98.27,85.59 106.86,85.59 107.3,85.16 107.3,84.98 107.63,84.65 107.63,84.64
  BOTTOM w0.193: R542.1 v2(74.61,104.84) 74.61,105.29 75.48,106.16 80.11,106.16 80.92,106.97 102.09,106.97 103.44,105.62 105.68,105.62 107.1,107.03 115.73,107.03 117.3,105.46 124.47,105.46 127.53,102.39 127.53,102 129.51,100.02 129.51,98.51 131.88,96.15 131.88,95.08 133.71,93.25 133.71,87.83 132.55,86.67 132.55,85.65 133.22,84.97 133.22,84.47 132.91,84.16 132.65,84.16 132.37,83.88 132.37,82.97 131.96,82.55 130.87,82.55 130.56,82.86 130.56,83.17 130.09,83.65 128.35,83.65 127.99,83.29 123.74,83.29 123.11,83.91 108.36,83.91 107.63,84.64
GPIO_46: length 116.2
  TOP w0.193: U11.T22 v1(96.66,85.2)
  BOTTOM w0.102: v1(96.66,85.2) 97.1,85.2 97.4,84.9 97.4,84.9 97.5,84.81 97.83,84.81 98.06,85.04 98.06,85.36 97.83,85.59 97.73,85.59 97.51,85.81 97.5,85.81 97.27,86.04 97.27,86.36 97.5,86.59 97.95,86.59 98.15,86.39 98.15,86.16 98.27,86.04 98.27,86.04 98.5,85.81 98.5,85.81 98.51,85.8 107.12,85.8 107.22,85.7 107.22,85.61 107.63,85.2 107.63,85.17
  BOTTOM w0.193: R541.1 75.6,104.05 v2(75.6,104.84) 75.6,105.28 76.07,105.74 80.41,105.74 81.18,106.51 101.77,106.51 103.05,105.23 104.03,105.23 106.12,105.23 107.53,106.65 114.45,106.65 116.03,105.06 124.31,105.06 127.11,102.26 127.11,101.84 129.11,99.84 129.11,98.38 131.48,96.01 131.48,94.92 133.32,93.08 133.32,89.39 129.98,86.05 129.98,85.13 129.02,84.17 128.14,84.17 127.68,83.71 124.04,83.71 123.37,84.38 108.42,84.38 107.63,85.17
GPIO_47: length 115.5
  TOP w0.193: U11.V26 v1(98.66,89.2)
  BOTTOM w0.102: v1(98.66,89.2) 99.24,88.62 106.83,88.62 107.15,88.3 107.28,88.3 107.63,87.95 107.63,87.91
  BOTTOM w0.193: 107.63,87.91 108.96,86.58 114.39,86.58 116.92,89.1 118.22,89.1 120.32,87.01 121.7,87.01 123.57,87.01 124.79,85.79 126.25,85.79 128.11,87.65 128.11,88.18 130.56,90.62 130.56,93.61 129.89,94.28 129.89,95.34 123.31,101.92 122.92,101.92 122.75,101.74 122.75,101.5 125.1,99.15 125.1,98.74 124.85,98.48 124.53,98.48 121.01,101.99 112.55,101.99 112.16,101.6 103.19,101.6 99.92,104.88 83.68,104.88 82.69,103.89 82.69,102.61 81.75,101.68 81.75,100.53 80.93,99.7 79.66,99.7 79.36,99.4 78.48,99.4 76.65,101.23 v2(76.34,101.23) 76.52,101.41 R540.1
GPIO_48: length 114.9
  TOP w0.193: U11.V25 v1(98.66,88.2)
  BOTTOM w0.102: v1(98.66,88.2) 99.06,87.8 107.01,87.8 107.51,87.3 107.63,87.3
  BOTTOM w0.193: 107.63,87.3 107.69,87.3 108.85,86.14 114.54,86.14 117.04,88.65 118.1,88.65 120.2,86.55 123.49,86.55 124.64,85.4 126.41,85.4 128.57,87.55 128.57,88.09 130.96,90.48 130.96,93.76 130.34,94.39 130.34,95.45 127.88,97.91 127.88,99.4 125.84,101.44 125.84,101.86 125.49,102.22 125.23,102.22 125.06,102.04 125.06,101.59 127.13,99.51 127.13,99.26 126.95,99.08 126.7,99.08 123.39,102.4 112.36,102.4 111.95,101.99 103.7,101.99 100.43,105.27 83.48,105.27 82.29,104.08 82.29,102.94 81.21,101.86 81.21,100.94 80.52,100.25 78.5,100.25 77.49,101.26 77.49,102.94 R539.1
GPIO_49: length 115.2
  TOP w0.193: U11.V24 v1(98.66,87.2)
  BOTTOM w0.102: v1(98.66,87.2) 99.06,87.6 106.87,87.6 107.63,86.84 107.63,86.82
  BOTTOM w0.193: R538.1 79.06,101.88 78.95,101.77 78.95,101.26 79.4,100.81 80.07,100.81 80.72,101.46 80.72,102.02 81.73,103.03 81.73,104.07 83.31,105.66 100.87,105.66 103.89,102.65 105.04,102.65 105.73,103.34 105.73,103.7 106.33,104.31 107.55,104.31 108,103.86 108,102.86 108.29,102.58 108.93,102.58 109.23,102.87 109.23,104.02 109.69,104.48 109.69,105.36 110,105.67 110.28,105.67 110.54,105.41 110.54,104.6 110.83,104.31 111.04,104.31 111.43,103.92 111.43,103.44 111.8,103.06 112.41,103.06 112.94,103.59 112.94,104.3 113.27,104.62 114.72,104.62 116.53,102.8 125.49,102.8 126.28,102.02 126.28,101.56 128.31,99.53 128.31,98.02 130.72,95.61 130.72,94.56 131.41,93.86 131.41,90.4 128.98,87.98 128.98,87.44 126.46,84.92 124.57,84.92 123.35,86.14 119.99,86.14 117.99,88.14 117.22,88.14 114.81,85.73 108.72,85.73 107.63,86.82
GPIO_50: length 126.9
  TOP w0.193: U11.V23 v1(98.66,86.2)
  BOTTOM w0.102: 107.63,85.7 107.63,85.75 107.13,86.25 107.13,86.4 106.93,86.6 105.91,86.6 105.91,86.6 105.41,86.6 103.91,86.6 103.91,86.6 103.41,86.6 99.07,86.6 v1(98.66,86.2)
  BOTTOM w0.193: 107.63,85.7 108.44,84.9 115.13,84.9 116.92,86.69 118.26,86.69 119.66,85.29 122.99,85.29 124.16,84.12 127.34,84.12 127.83,84.61 128.88,84.61 129.58,85.31 129.58,86.22 132.91,89.55 132.91,90.18 131.86,91.23 131.86,93.95 131.1,94.71 131.1,95.82 128.73,98.19 128.73,99.68 126.66,101.74 126.66,102.17 124.24,104.59 119.66,104.59 119.47,104.4 119.47,104.02 119.65,103.85 124.2,103.85 124.42,103.63 124.42,103.36 124.24,103.18 116.74,103.18 116.49,103.43 116.49,103.81 116.58,103.9 116.99,103.9 117.17,104.09 117.17,104.34 117,104.51 115.49,104.51 114.81,105.2 112.91,105.2 112.75,105.36 112.75,105.61 112.95,105.81 113.09,105.81 113.2,105.91 113.2,106.15 113.07,106.27 108.02,106.27 106.52,104.78 106.14,104.78 105.23,103.86 105.23,103.49 104.81,103.08 104.09,103.08 103.45,103.71 103.45,103.94 103.58,104.06 104.64,104.06 104.86,104.28 104.86,104.58 104.66,104.78 102.8,104.78 101.48,106.1 81.72,106.1 81.11,105.49 81.11,103.35 80.68,102.92 R537.1
GPIO_54: length 185.8
  TOP w0.193: U11.F26 v1(85.66,89.2)
  L03_SIG1 w0.155: v2(57.85,85.47) 42.04,85.47 v2(37.55,80.99) ; v2(5.84,9.27) 6.61,10.04 7.9,10.04 8.46,9.48 8.96,9.48 9.58,10.1 9.58,10.95 15.34,16.72 15.34,76.15 17.95,78.75 v2(17.95,83.08)
  L05_SIG2 w0.102: v1(85.66,89.2) 85.62,89.2 85.23,88.81 84.5,88.81 84.26,89.05 84.26,89.53 83.62,90.17
  L05_SIG2 w0.155: v2(52.16,91.98) 52.52,92.35 52.53,92.35 54.15,93.96 55.2,93.96 56.18,94.94 59.81,94.94 60.36,94.39 64.46,94.39 64.72,94.64 67.71,94.64 69.56,92.79 70.69,92.79 71.35,93.46 73.78,93.46 74.49,92.74 78.28,92.74 78.79,92.24 81.96,92.24 83.62,90.58 83.62,90.17 ; v2(37.55,80.99) 26.84,80.99 25.08,82.74 25.08,84.36 26.44,85.71 26.44,86.49 26.09,86.83 21.7,86.83 v2(17.95,83.08)
  BOTTOM w0.193: v2(57.85,85.47) 57.78,85.47 57.4,85.09 55.83,85.09 54.02,86.9 54.02,89.17 54.18,89.33 54.18,89.86 53.8,90.24 53.67,90.24 52.16,91.75 v2(52.16,91.98) ; v2(5.84,9.27) 5.84,10.76 5.05,11.55 U517.2
  BOTTOM w0.254: RN502.4 57.63,85.69 v2(57.85,85.47)
GPIO_60: length 16.9
  TOP w0.193: U11.H22 v1(87.66,85.2)
  BOTTOM w0.102: v1(87.66,85.2) 87.07,85.8 86.32,85.8 86.09,86.02 86.09,86.38 85.84,86.63 85.48,86.63 85.23,86.38 85.23,86.21 84.82,85.8 79.69,85.8
  BOTTOM w0.193: R581.1 R580.1 76.71,82.11 78.43,83.82 78.43,85 79.22,85.8 79.69,85.8
GPIO_61: length 16.2
  TOP w0.193: U11.H23 v1(87.66,86.2)
  BOTTOM w0.102: v1(87.66,86.2) 87.16,86.7 86.61,86.7 86.27,87.04 86.27,87.37 86.05,87.59 85.5,87.59 85.15,87.24 85.15,86.79 84.96,86.6 80.29,86.6 79.96,86.27 79.69,86.27
  BOTTOM w0.193: 79.69,86.27 78.84,86.27 77.6,85.03 77.6,84.58 77.09,84.07 75.96,84.07 R566.1 R567.1
GPIO_62: length 14.2
  TOP w0.193: U11.H24 v1(87.66,87.2)
  BOTTOM w0.102: 79.69,87.33 79.72,87.33 80,87.6 83.51,87.6 83.71,87.8 87.07,87.8 v1(87.66,87.2)
  BOTTOM w0.193: 79.69,87.33 78.12,87.33 77.72,86.93 R569.1 R570.1
GPIO_63: length 13.7
  TOP w0.193: U11.H25 v1(87.66,88.2)
  BOTTOM w0.102: 79.69,88.77 83.85,88.77 84.02,88.59 87.27,88.59 v1(87.66,88.2)
  BOTTOM w0.193: 79.69,88.77 R568.1 R561.1
GPIO_65: length 18.4
  TOP w0.193: U11.J22 v1(88.66,85.2)
  BOTTOM w0.102: v1(88.66,85.2) 88.43,84.96 87.98,84.96 87.83,84.81 87.5,84.81 87.27,85.04 87.27,85.15 86.83,85.59 85.45,85.59 85.23,85.38 85.23,85 85.04,84.81 79.69,84.81
  BOTTOM w0.193: R583.1 R582.1 76.54,80.2 79.06,82.72 79.06,84.32 79.55,84.81 79.69,84.81
GPIO_74: length 40.5
  TOP w0.193: U11.AE10 v1(105.66,72.2)
  L03_SIG1 w0.102: 107.63,65.23 107.63,65.53 105.36,67.8 103.41,67.8 103.1,68.11 103.1,71.4 103.38,71.68 105.14,71.68 v1(105.66,72.2)
  L03_SIG1 w0.155: 107.63,65.23 108.19,64.67 108.19,61.69 106.7,60.2 106.7,59.43 106.41,59.15 106.41,53.92 108.62,51.72 108.62,48.73 v2(107.51,47.62)
  L05_SIG2 w0.155: v2(107.51,47.62) 110.27,47.62 J21.2
GPIO_75: length 50.8
  L03_SIG1 w0.155: J29.2 114.39,40.9 116.98,43.48 116.98,44.66 116.52,45.12 109.55,45.12 109.31,45.36 109.31,46.66 109.97,47.32 109.97,47.34 109.99,47.36 109.99,52.06 109.74,52.32 109.23,52.83 109.23,54.08 108.75,54.56 108.75,57.16 108.04,57.87 107.81,57.87 107.46,58.22 107.46,58.71 107.89,59.14 108.61,59.14 108.98,59.5 108.98,64.72 110.28,66.02 110.28,68.1 111.26,69.07 112.59,69.07 v1(114.15,70.63)
  BOTTOM w0.193: R599.1 113.79,70.99 v1(114.15,70.63)
GPIO_81: length 41.5
  TOP w0.102: U11.AB10 v1(102.66,72.2)
  TOP w0.193: J24.4 107.97,39.17 108.18,39.38 v2(108.18,39.9)
  L03_SIG1 w0.102: v1(102.66,72.2) 102.11,71.65 102.11,68.1 102.61,67.59 105.28,67.59 107.11,65.76 107.11,64.8 107.37,64.54
  L03_SIG1 w0.155: 107.37,64.54 107.37,61.54 106.35,60.53 106.35,59.58 106.06,59.29 106.06,53.07 107.98,51.16 107.98,48.92 106.92,47.86 106.92,47.19 107.62,46.48 107.62,45.03 107.29,44.7 107.29,40.79 v2(108.18,39.9)
GPIOX_11: length 4.1
  TOP w0.193: U21.12 183.42,15.65 182.05,17.02 R67.1
GPIOX_12: length 3.5
  TOP w0.193: R68.1 181.29,16.08 181.79,16.08 182.97,14.9 U21.13
GPIOX_13: length 3
  TOP w0.193: R69.1 181.19,14.4 U21.14
GPIOX_14: length 3.7
  TOP w0.193: R70.1 181.52,13.14 181.52,13.58 181.84,13.9 U21.15
GPIOX_INT: length 203.5
  TOP w0.193: v2(137.9,16.1) 157.55,16.1 163.19,10.46 171.65,10.46 177.9,4.22 181.03,4.22 185.06,8.26 185.55,8.26 187.1,9.8 187.1,10.87 186.67,11.3 U21.24 ; U11.E3 v1(84.66,65.2)
  L03_SIG1 w0.102: v1(84.66,65.2) 84.32,65.2 83.92,64.81 83.25,64.81 83.13,64.68 83.13,63.92 82.87,63.67 82.36,63.67 82.06,63.36 82.06,63.04 81.4,62.38 81.4,62.23
  L03_SIG1 w0.155: 81.4,62.23 81.4,60.86 80.67,60.13 80.67,50.01 79.16,48.5 79.16,39.95 74.4,35.19 74.4,30.24 71.2,27.05 71.2,25.12 68.3,22.22 68.3,18.59 65.58,15.87 v2(65.58,14.53)
  BOTTOM w0.193: v2(137.9,16.1) 131.59,16.1 130.73,16.97 125.63,16.97 123.23,14.57 123.23,13.31 122.5,12.58 71.61,12.58 70.41,11.38 67.76,11.38 66.51,12.63 66.51,13.6 v2(65.58,14.53) 65.58,14.96 62.87,17.68 61.81,17.68 R737.1
GPIOX_RST: length 177.5
  TOP w0.193: U21.20 v2(184.67,9.78) ; U11.G22 v1(86.66,85.2)
  L03_SIG1 w0.155: v2(127.67,74.62) 127.67,73.82 128.06,73.42 128.06,57.76 131.28,54.54 131.38,54.54 134.93,51 135.96,51 138.44,48.52 138.44,48.12 140.86,45.7 140.86,44.6 144.11,41.35 144.11,32.44 142.66,31 142.66,23.28 135.13,15.75 135.13,14.21 v2(135.86,13.49)
  L05_SIG2 w0.102: 106.83,75.59 101.14,75.59 100.83,75.28 98.72,75.28 97.5,76.51 97.5,77.63 97.12,78.01 97.12,78.01 97.12,78.39 96.85,78.66 96.78,78.66 96.64,78.79 90.26,78.79 89.14,79.91 89.14,80.28 88.87,80.54 88.51,80.54 86.98,82.08 86.98,83.96 87.06,84.04 87.06,84.36 86.66,84.76 v1(86.66,85.2)
  L05_SIG2 w0.155: 106.83,75.59 106.97,75.73 120.94,75.73 122.05,74.62 v2(127.67,74.62) ; v2(135.86,13.49) 135.95,13.39 143.71,13.39 144.77,12.33 180.96,12.33 183.51,9.78 v2(184.67,9.78)
  BOTTOM w0.193: v2(184.67,9.78) 184.67,9.77 184.91,9.53 185.69,9.53 186.49,10.32 R744.1
GRN_LED_EN: length 171.8
  TOP w0.193: U11.C25 v1(82.66,88.2) ; v2(53.54,89.6) 53.54,90.5 52.92,91.12 52.92,95.96 51.92,96.97 v2(51.92,98.21)
  L03_SIG1 w0.155: v2(50.98,109.52) 51.19,109.52 52.36,108.35 52.36,101.74 51.92,101.3 v2(51.92,98.21) ; v2(6.49,13.77) 6.57,13.84 6.91,13.84 11.24,18.17 11.24,75.4 13.68,77.85 v2(13.68,81.79)
  L05_SIG2 w0.155: v2(13.68,81.79) 21.22,89.33 53.27,89.33 v2(53.54,89.6) 53.73,89.79 59.74,89.79 60.01,90.07 64.77,90.07 66.77,88.07 67.39,88.07 67.98,88.65 68.3,88.65 69.37,89.73 70.87,89.73 71,89.86 77.45,89.86 78.64,88.67 82.19,88.67 82.66,88.2 v1(82.66,88.2)
  BOTTOM w0.193: v2(6.49,13.77) 6.1,14.15 U517.6 ; RN500.2 51.05,109.46 v2(50.98,109.52)
GRN_PWM: length 43.7
  TOP w0.193: U11.B20 v1(81.66,83.2)
  TOP w0.254: v2(60.92,93.34) 60.7,93.12 59.78,93.12 59.1,92.45 U8.3
  BOTTOM w0.102: v1(81.66,83.2) 82.16,82.7 82.16,79.14 81.83,78.81 80.31,78.81 79.99,79.13 79.84,79.13 79.84,79.13 79.69,79.13
  BOTTOM w0.193: v2(60.92,93.34) 60.94,93.34 62.6,91.68 62.6,91.25 62.6,90.07 68.12,84.54 68.12,80.33 70.95,77.51 77.24,77.51 78.86,79.13 79.69,79.13
  BOTTOM w0.254: RN501.1 60.88,93.39 v2(60.92,93.34)
HDMI_CEC: length 47.7
  TOP w0.193: J2.13 90.49,118.72 89.62,117.86 85.7,117.86 85.32,117.93 84.8,117.93 83.73,116.86 83.73,116.38 84.22,115.89 85.44,115.89 86.18,115.15 86.18,112.05 84.45,110.32 TP5.1 ; U11.G23 v1(86.66,86.2)
  L03_SIG1 w0.102: v1(86.66,86.2) 86.66,86.33 87.07,86.73 87.07,87.45 87.27,87.65 87.27,89.73 87.04,89.96 85.28,89.96 85.07,90.17
  L03_SIG1 w0.155: v2(82.1,98.04) 82.1,93.14 85.07,90.17
  L05_SIG2 w0.155: TP5.1 84.45,99.34 83.16,98.04 v2(82.1,98.04)
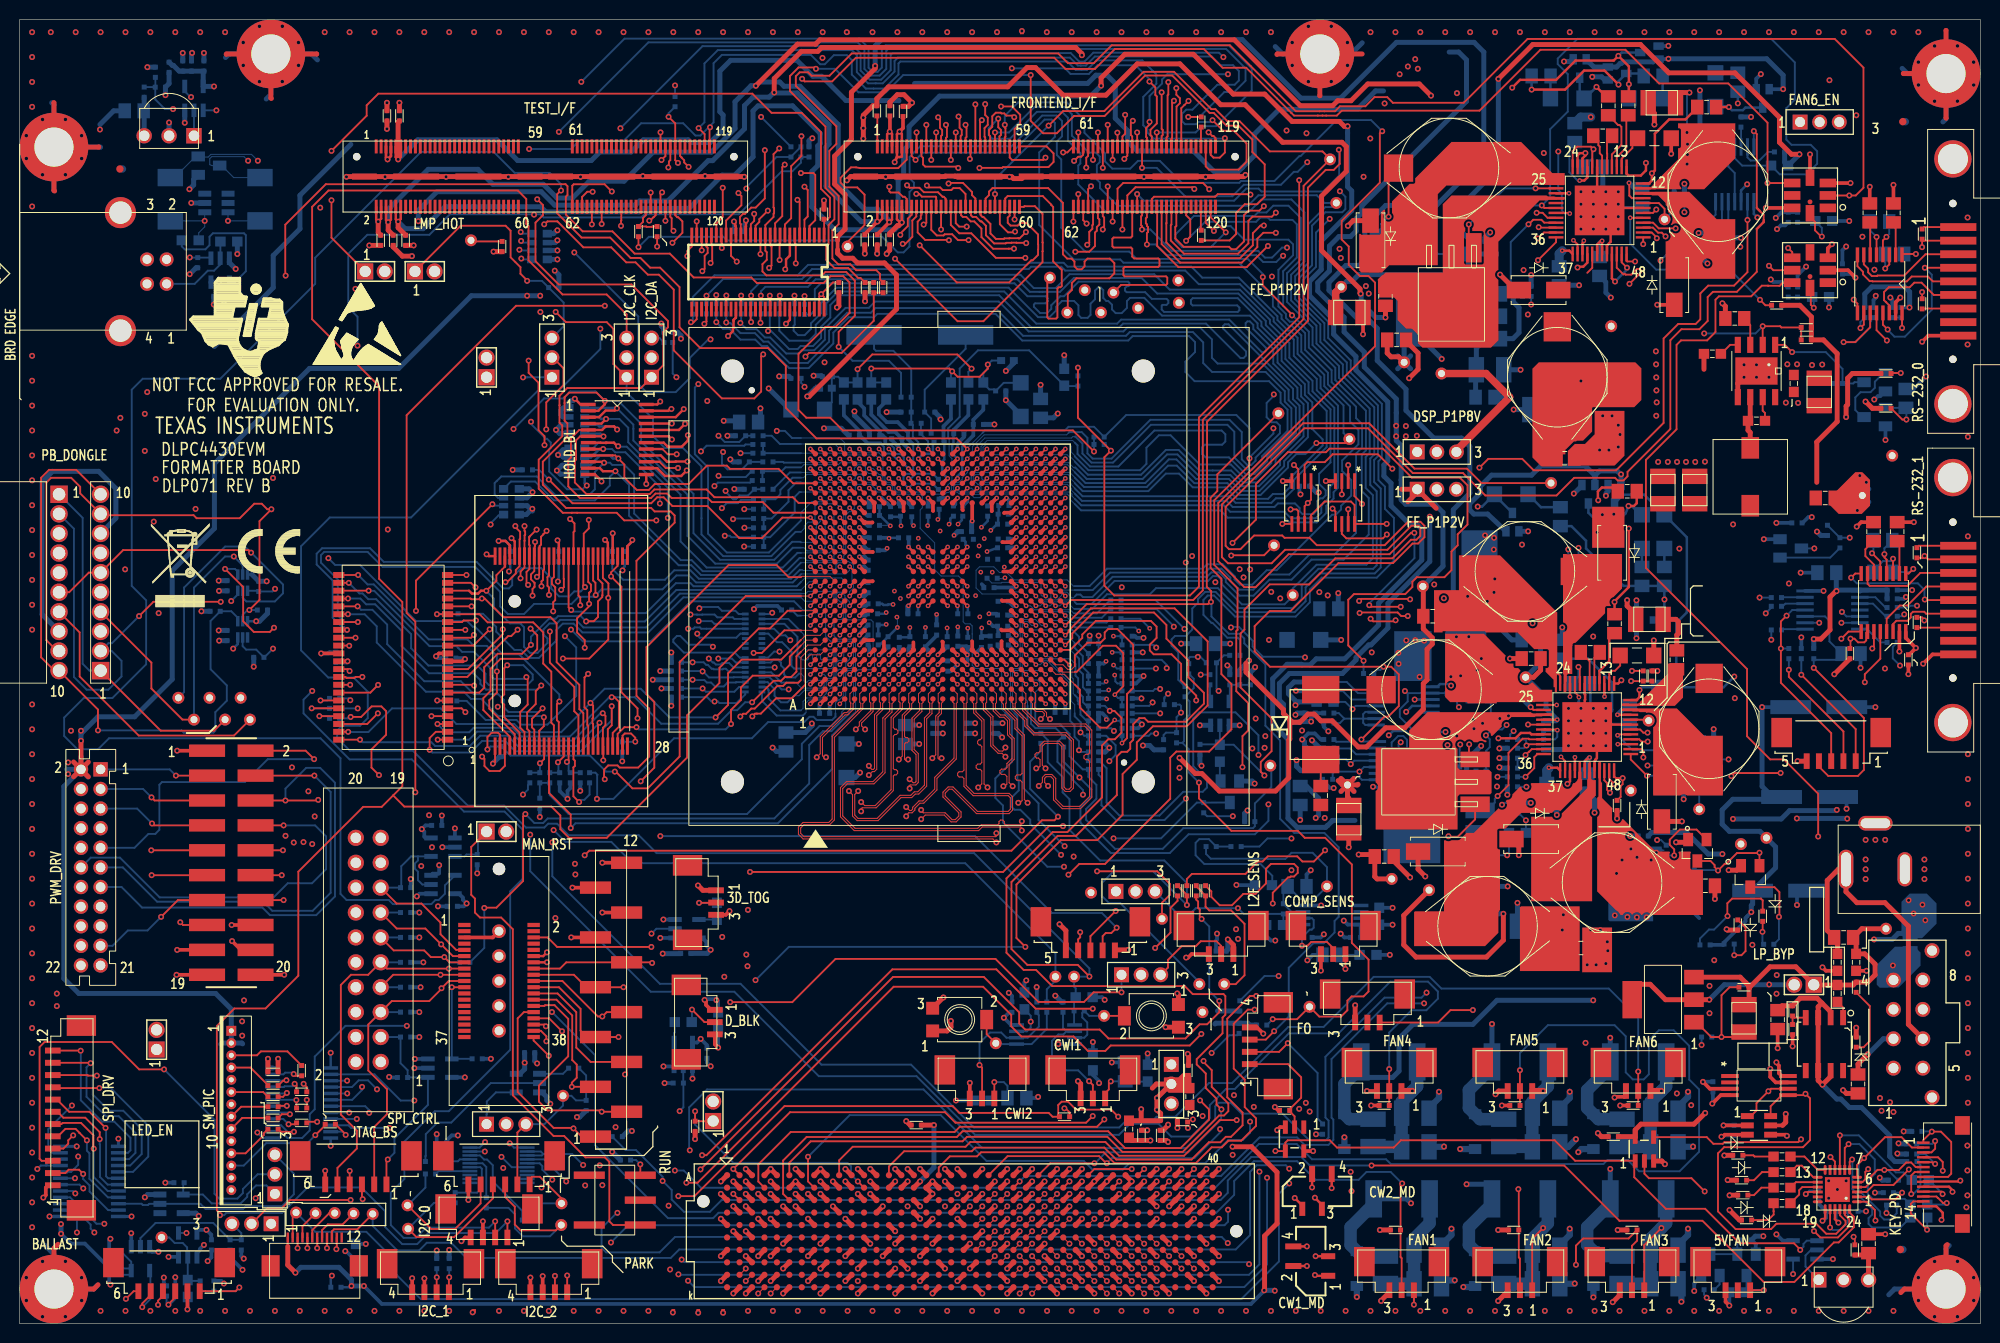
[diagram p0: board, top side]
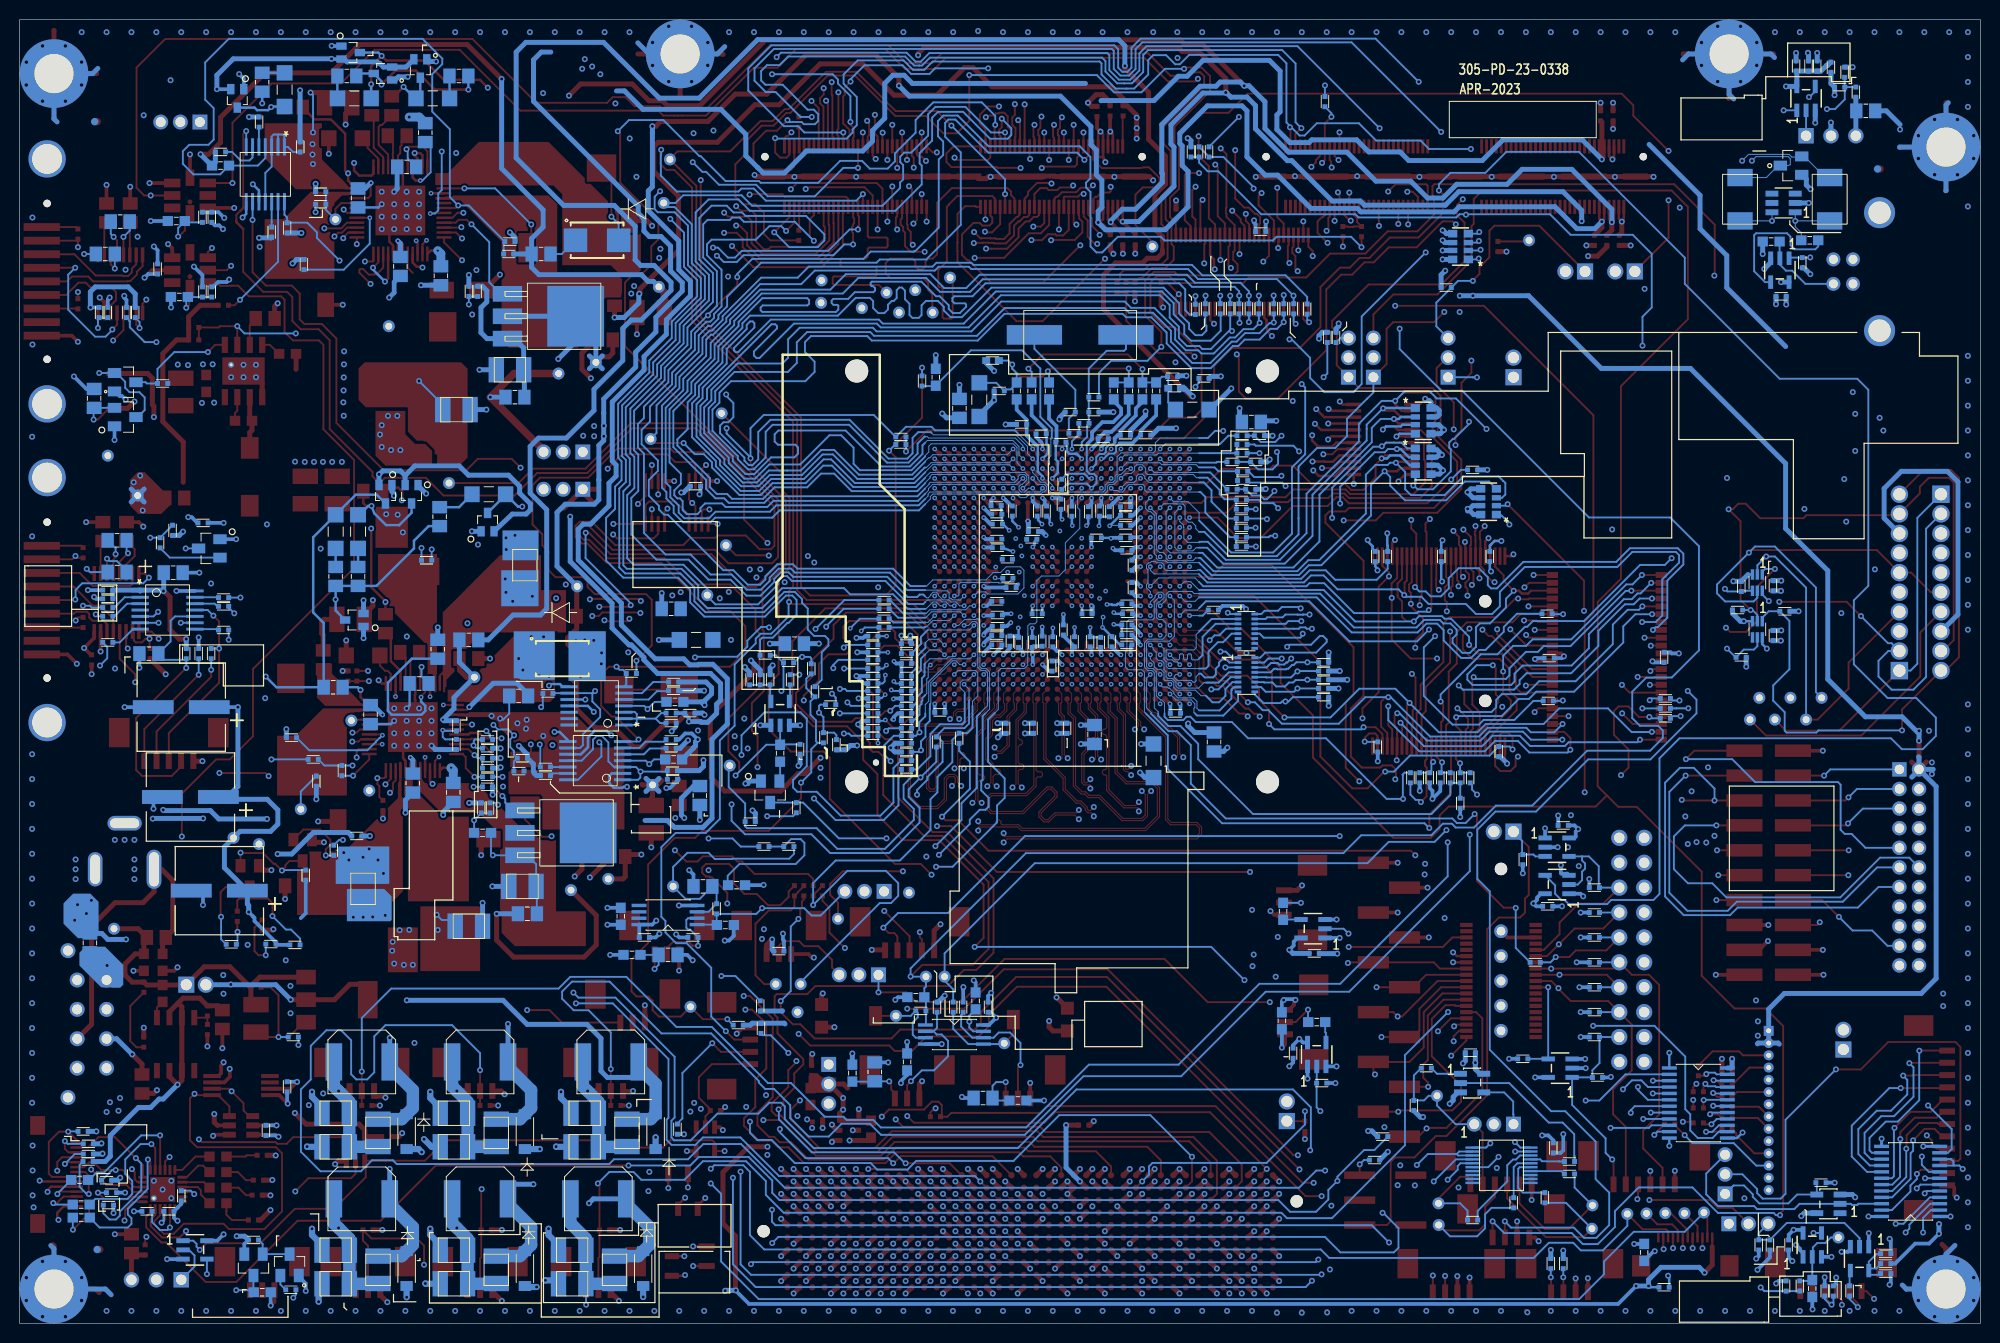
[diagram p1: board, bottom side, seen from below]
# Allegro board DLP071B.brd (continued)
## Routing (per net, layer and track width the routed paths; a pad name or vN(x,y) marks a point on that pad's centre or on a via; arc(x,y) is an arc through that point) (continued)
HDMI_HPD: length 194
  TOP w0.193: J2.90 114.49,113.03 114.39,112.93 114.39,112.02 114.49,111.92 v2(114.49,111.59) ; U21.10 185.17,16.51 v2(184.71,16.97)
  L03_SIG1 w0.155: v2(187.97,110.86) 187.97,110.03 185.74,107.79 185.74,103.65 186.99,102.39 186.99,95.55 185.67,94.23 185.67,89.34 178.6,82.27 178.6,81.42 179.93,80.09 183.37,80.09 184.01,79.45 184.01,76.92 181.43,74.34 181.43,71.93 181.14,71.64 181.14,69.73 182.42,68.45 183.71,68.45 185.7,66.46 185.7,56.15 184.5,54.95 184.5,39.07 185.54,38.03 185.54,27.26 183.3,25.02 183.3,18.37 v2(184.71,16.97) ; v2(134.64,109.62) 134.51,109.74 v2(129.28,109.74)
  L05_SIG2 w0.155: v2(187.97,110.86) 184.77,110.86 184.02,110.11 183.08,110.11 182.4,110.79 179,110.79 173.38,105.17 172.88,104.67 166.97,104.67 166.35,104.05 157.02,104.05 155.89,105.18 140.14,105.18 135.71,109.62 v2(134.64,109.62)
  BOTTOM w0.193: v2(129.28,109.74) 128.77,109.74 127.75,108.73 127.02,108.73 126.33,109.42 117.52,109.42 115.34,111.59 v2(114.49,111.59)
HDMI_INT: length 158
  TOP w0.193: v2(106.98,45.77) 108.08,46.87 110.71,46.87 117.36,53.52 117.36,57.71 117.99,58.33 121.33,58.33 123.61,60.61 123.61,65.21 122.58,66.24 122.58,75.98 121.48,77.08 121.48,84.22 122.17,84.91 122.17,86.61 TP18.1 ; v2(115.26,122.57) 115.26,122.3 114.9,121.94 114.9,121.04 114.99,120.96 J2.91 ; U11.AB13 v1(102.66,75.2)
  L03_SIG1 w0.155: v2(106.98,45.77) 106.23,45.77 105.64,46.36 105.64,48.7 107.11,50.17 107.11,51.36 105.52,52.95 105.52,59.43 105.94,59.85 105.94,62.61 106.22,62.89 106.22,65.89 105.4,66.71 101.42,66.71 101.13,67 101.13,68.51 101.05,68.59 101.05,74.34 101.37,74.66 102.24,74.66 102.66,75.08 v1(102.66,75.2) ; v2(123.25,127.43) 128.13,122.56 131.05,122.56 132.01,121.61 132.01,120.69 130.58,119.25 130.58,117.51 131.12,116.97 131.12,111.02 130.95,110.85 129.53,110.85 128.28,109.6 128.28,108.66 129.66,107.28 129.66,105.05 128.65,104.05 128.65,97.04 128.79,96.91 128.79,96.41 128.65,96.28 128.65,93.94 128.4,93.68 TP18.1
  BOTTOM w0.193: v2(115.26,122.57) 115.26,125.21 116.53,126.48 116.53,126.89 117.07,127.43 v2(123.25,127.43)
HOLD_BOOTZ: length 50.9
  TOP w0.193: U11.F24 v1(85.66,87.2)
  L05_SIG2 w0.102: 85.37,90.17 86.06,89.48 86.06,88.04 85.66,87.64 v1(85.66,87.2)
  L05_SIG2 w0.155: J8.1 48.23,97.13 51.82,97.13 53.59,95.35 54.72,95.35 55.06,95.69 60.19,95.69 60.8,95.08 63.58,95.08 63.9,95.4 65.87,95.4 v2(66.99,96.52) 66.99,96.41 69.9,93.5 70.39,93.5 71.22,94.33 77.92,94.33 78.78,93.46 79.15,93.1 82.44,93.1 85.37,90.17
  BOTTOM w0.193: R548.2 66.61,96.9 v2(66.99,96.52)
I2C_BUSY: length 104.9
  TOP w0.193: U11.G24 v1(86.66,87.2) ; v2(129.35,28.58) 128.47,27.7 J36.2
  L05_SIG2 w0.155: v2(106.53,46.58) 106.15,46.21 106.15,45.73 111.16,40.72 111.16,40.2 112.44,38.92 122.22,38.92 129.92,31.23 129.92,29.14 v2(129.35,28.58)
  BOTTOM w0.102: 100.52,62.28 100.18,62.63 100.18,66.56 99.93,66.81 97.5,66.81 97.17,67.14 97.17,69.29 97.16,69.29 97.16,69.65 97.17,69.65 97.17,70.33 97.16,70.33 97.16,71.15 96.95,71.37 96.45,71.37 96.24,71.57 96.24,75.76 95.76,76.24 93.99,76.24 93.33,76.9 93.33,79.63 92.37,80.59 91.86,81.09 91.86,81.14 91.86,81.14 91.86,82.99 92.08,83.21 92.08,84.4 91.89,84.59 89.33,84.59 89.06,84.86 89.06,85.36 88.83,85.59 88.37,85.59 88.06,85.9 88.06,86.36 87.83,86.59 87.66,86.59 87.06,87.2 v1(86.66,87.2)
  BOTTOM w0.193: 100.52,62.28 101.22,61.58 101.22,57.29 99.52,55.6 99.52,53.61 100.3,52.83 100.3,51.11 104.83,46.58 v2(106.53,46.58) ; R735.2 132.91,20.4 132.39,20.91 132.39,25.54 v2(129.35,28.58)
ICE_RSTZ: length 23.7
  TOP w0.193: J27.9 44.52,38.1 42.93,39.7 42.93,40.88 40.99,42.82 38.46,42.82 J23.15
  BOTTOM w0.193: 40.63,47.64 40.63,47.22 40.32,46.92 40.32,46.38 40.63,46.08 40.63,45.21 41.07,44.77 U510.2 ; 40.63,47.64 39.93,47.64 38.93,46.63 38.93,44.53 R697.1 J23.15 ; 40.63,47.64 U511.4
ICTSEN: length 24.2
  TOP w0.193: U11.M24 v1(91.66,87.2)
  L03_SIG1 w0.102: 91.07,90.17 91.27,89.97 91.27,87.59 v1(91.66,87.2)
  L03_SIG1 w0.155: v2(80.06,95.54) 80.06,96.84 81.86,98.64 82.48,98.64 82.7,98.42 82.7,93.83 86.21,90.32 90.93,90.32 91.07,90.17
  BOTTOM w0.193: R559.1 79.71,95.95 80.06,95.6 v2(80.06,95.54)
INDEX1_SENSE_INPUT: length 13.1
  TOP w0.193: J57.2 109.47,24.31 v2(109.09,24.7)
  BOTTOM w0.193: 106.78,29.79 106.46,29.47 105.95,29.47 105.3,28.82 105.3,27.24 106.74,25.81 107.98,25.81 v2(109.09,24.7) ; 106.78,29.79 U519.2 ; 106.78,29.79 106.43,30.14 R752.1
INDEX2_SENSE_INPUT: length 14.5
  TOP w0.193: v2(97.91,26.35) 98.17,26.09 J55.2
  BOTTOM w0.193: R754.1 103.76,31.63 103.96,31.43 103.96,30.27 102.83,29.14 U519.6 100.66,29.14 100.12,29.67 98.98,29.67 97.91,28.6 v2(97.91,26.35)
IR0: length 113.9
  TOP w0.193: U11.C26 v1(82.66,89.2)
  L03_SIG1 w0.155: v2(17.48,125.1) 15.96,125.1 14.05,123.19 14.05,120.33 7.45,113.73 7.45,100.56 v2(13.01,95.01)
  L05_SIG2 w0.155: v1(82.66,89.2) 80.91,90.95 78.85,90.95 77.78,92.02 73.82,92.02 73.18,92.67 71.57,92.67 70.99,92.09 68.82,92.09 68.35,92.56 60.37,92.56 60.07,92.86 54.45,92.86 52.24,90.65 17.37,90.65 v2(13.01,95.01)
  BOTTOM w0.193: U500.4 16.84,125.69 17.43,125.1 v2(17.48,125.1)
IR1: length 272.8
  TOP w0.193: U11.E23 v1(84.66,86.2)
  L03_SIG1 w0.155: v2(42.06,48.57) 42.06,49.24 46.1,53.28 47.06,53.28 49.61,55.83 49.61,60.88 48.13,62.36 48.13,64.01 51.56,67.44 54.01,67.44 55.24,68.67 55.5,68.67 57.19,70.36 57.19,71.17 57,71.36 57,72.02 57.55,72.56 58.14,72.56 59.35,73.78 59.35,74.19 59.98,74.82 60.45,74.82 68.8,83.16 68.8,84.8 70.59,86.6 70.59,86.81 71.15,87.37 71.15,89.15 71.5,89.49 74.9,89.49 80.64,83.75 83.86,83.75 84.12,84.01 84.12,85.66 v1(84.66,86.2) ; v2(60.98,11.28) 59.5,11.28 56.78,13.99 56.78,15.22 54.32,17.68 48.72,17.68 47.94,16.9 47.11,16.9 46.36,17.65 46.36,21.95 50,25.59 50,26.96 51.67,28.63 51.67,33.1 55.24,36.68 55.24,44.35 v2(56.69,45.8)
  L05_SIG2 w0.155: v2(123.23,8.19) 127.61,8.19 128.01,8.59 135.74,8.59 138.95,5.38 180.55,5.38 v2(180.9,5.03) ; v2(42.06,48.57) 42.77,47.87 43.38,47.87 43.91,48.39 49.91,48.39 52.5,45.8 v2(56.69,45.8)
  BOTTOM w0.193: v2(123.23,8.19) 122.61,8.82 66.85,8.82 65.28,7.24 59.82,7.24 59.35,7.71 59.35,9.72 60.91,11.28 v2(60.98,11.28) ; U518.4 v2(180.9,5.03)
KEYPD_DOWN: length 14
  TOP w0.193: J47.4 195.68,16.94 196.16,16.46 v2(196.16,15.57) ; v2(192.02,13.33) 191.33,12.64 188.92,12.64 188.66,12.9 U21.2
  L05_SIG2 w0.155: v2(192.02,13.33) 194.26,15.57 v2(196.16,15.57)
  BOTTOM w0.193: v2(192.02,13.33) 191.97,13.33 191.97,13.33 R731.1
KEYPD_LED_HOT: length 12.8
  TOP w0.193: U21.9 185.67,19.17 v2(185.67,19.18)
  BOTTOM w0.193: v2(185.67,19.18) 187.6,19.18 191.38,15.4 192.15,15.4 192.92,14.63 R725.2
KEYPD_LED_LMP: length 14.7
  TOP w0.193: v2(186.56,18.29) 186.17,17.9 U21.8
  BOTTOM w0.193: R741.2 192.28,12.7 189.01,12.7 188.52,13.19 188.52,14.53 189.23,15.24 189.23,16.72 187.67,18.29 v2(186.56,18.29)
KEYPD_LED_PWR: length 13.6
  TOP w0.193: U21.7 186.67,16.46 v2(186.92,16.71)
  BOTTOM w0.193: v2(186.92,16.71) 186.94,16.69 186.94,13.72 187.24,13.42 187.24,13.4 188.96,11.67 188.96,11.1 188.59,10.73 188.59,10.15 188.96,9.78 191.84,9.78 R742.2
KEYPD_LEFT: length 12.7
  TOP w0.193: v2(192.71,15.7) 191.13,14.11 189.1,14.11 188.39,13.4 U21.3 ; v2(195.39,16.27) 195.24,16.27 195.07,16.44 J47.5
  L05_SIG2 w0.155: v2(192.71,15.7) 193.28,16.27 195.35,16.27 195.35,16.27 v2(195.39,16.27)
  BOTTOM w0.193: R729.1 194.38,17.27 v2(195.39,16.27)
KEYPD_PWR: length 108.5
  TOP w0.193: v2(171.88,13.46) 170.54,14.81 166.19,14.81 165.73,15.27 U19.2 ; J47.7 193.31,15.44 192.95,15.08 v2(192.95,13.19)
  L03_SIG1 w0.155: v2(193.54,73.21) 193.27,72.94 193.27,70.29 192.58,69.6 192.58,68.42 192.01,67.85 191.54,67.85 191.09,67.4 191.09,66.71 193.98,63.82 193.98,60.25 198.02,56.21 198.02,20.35 196.39,18.72 196.39,18.71 194.01,16.33 194.01,14.25 v2(192.95,13.19)
  L05_SIG2 w0.155: v2(192.95,13.19) 192.95,12.5 190.33,9.88 188.25,9.88 184.22,13.92 172.34,13.92 v2(171.88,13.46)
  BOTTOM w0.193: v2(193.54,73.21) 192.84,73.21 192.65,73.03 R588.1 ; v2(192.95,13.19) 193.16,13.19 193.88,13.92 193.88,16.16 R727.1
KEYPD_PWR_BUF: length 30.9
  TOP w0.193: v2(189.3,10.49) 189.24,10.56 189.24,11.58 188.41,12.4 U21.1 ; v2(181.71,18.77) 181.43,18.49 173.9,18.49 173.72,18.32 172.77,18.32 172.09,19 U19.4
  L05_SIG2 w0.155: v2(181.71,18.77) 184.78,15.7 186.01,15.7 189.3,12.4 v2(189.3,10.49)
KEYPD_RIGHT: length 10.2
  TOP w0.193: J47.6 193.41,15.94 192.94,16.41 192.44,16.41 191.68,15.64 v2(190.21,15.64) 190.19,15.66 189.51,15.66 188.92,15.07 188.86,15.01 188.86,14.47 188.3,13.9 U21.4
  BOTTOM w0.193: v2(190.21,15.64) 190.56,15.64 191.6,14.61 R730.1
KEYPD_SEL: length 19.6
  TOP w0.193: U21.6 187.42,16.13 v2(188.14,16.86) 190.28,18.99 191.96,18.99 193.01,17.94 J47.2
  BOTTOM w0.193: R743.1 191.47,11.23 190.83,10.59 190.17,10.59 189.78,10.99 189.78,11.41 187.59,13.59 187.59,16.31 v2(188.14,16.86)
KEYPD_UP: length 14.8
  TOP w0.193: v2(195.39,18.59) 195.39,17.82 195.01,17.44 J47.3 ; U21.5 187.97,14.4 188.26,14.7 188.26,15.44 v2(188.55,15.73)
  L05_SIG2 w0.155: v2(188.55,15.73) 188.55,16.12 191.41,18.97 195.01,18.97 v2(195.39,18.59)
  BOTTOM w0.193: v2(195.39,18.59) 195.11,18.31 R728.1
LAMPLITZ: length 55.8
  TOP w0.193: v2(22.41,3.66) 22.03,3.28 18.96,3.28 J48.1 ; J33.4 4.46,17.83 4.95,18.33 4.95,18.67 v2(5.46,19.18)
  L03_SIG1 w0.155: v2(22.41,3.66) 22.39,3.66 21.39,4.66 17.57,4.66 16.99,4.08 12.35,4.08 8.6,7.82 6.45,7.82 5.08,9.19 5.08,13.5 5.78,14.21 5.89,14.21 6.33,14.64 6.72,14.64 7.07,14.99 7.07,15.49 6.19,16.36 5.78,16.36 5.23,16.92 5.23,18.95 v2(5.46,19.18)
  L05_SIG2 w0.155: v2(5.46,19.18) 13.97,27.69 J34.1
  BOTTOM w0.193: v2(22.41,3.66) 22.04,3.29 R774.1 R775.1
LAMPLITZ_FLTR: length 7.7
  BOTTOM w0.193: TP63.1 15.25,8.76 15.81,8.2 16.63,8.2 17.08,7.75 17.08,6.85 U522.2 C675.2 17.23,4.33 R775.2
LED1_GRN: length 3.1
  TOP w0.193: R68.2 177.74,15.43 176.91,14.61 D14.2
LED1_RED: length 3.2
  TOP w0.193: R67.2 176.97,17.02 176.84,17.15 D15.2
LED2_GRN: length 3.6
  TOP w0.193: D12.2 178.36,10.54 178.92,11.1 178.92,11.44 178.9,11.46 R70.2
LED2_RED: length 2.9
  TOP w0.193: D13.2 176.91,13.08 177.67,13.84 R69.2
LED4_PWM: length 40.6
  TOP w0.193: U11.A20 76.89,82.7 75.81,83.78 70.61,83.78 70.19,84.2 66.5,84.2 66.05,84.65 64.86,84.65 64.41,84.2 57.14,84.2 55.96,85.38 55.96,88.06 56.23,88.33 56.23,90.29 57.08,91.15 U8.5
  TOP w0.254: v2(60.94,91.19) 60.63,91.5 59.77,91.5 59.42,91.15 U8.5
  BOTTOM w0.254: v2(60.94,91.19) 60.63,91.5 59.12,91.5 58.95,91.68 RN501.3
LED5_PWM: length 35.2
  TOP w0.193: U8.6 58,90.49 57.17,90.49 56.75,90.08 56.75,88.12 56.63,88 56.63,85.78 57.81,84.61 64.28,84.61 64.75,85.07 70.08,85.07 70.87,84.28 78.86,84.28 79.44,83.7 U11.A21
  TOP w0.254: U8.6 59.54,90.5 v2(59.55,90.48)
  BOTTOM w0.254: v2(59.55,90.48) 59.55,90.45 59.24,90.76 RN501.4
LED6_PWM: length 34.3
  TOP w0.193: U11.B21 v1(81.66,84.2)
  TOP w0.254: v2(61.05,89.48) 60.98,89.48 60.62,89.84 59.84,89.84 59.82,89.82 59.8,89.82 59.79,89.83 59.28,89.83 59.26,89.84 U8.7
  L05_SIG2 w0.102: 79.69,83.49 80.95,83.49 v1(81.66,84.2)
  L05_SIG2 w0.155: 79.69,83.49 75.23,83.49 74.17,82.42 73.51,82.42 73.15,82.78 72.58,82.78 71.97,82.17 v2(66.12,82.17)
  BOTTOM w0.193: RN502.1 58.47,89.26 59.04,89.84 60.63,89.84 60.98,89.48 v2(61.05,89.48) 61.1,89.43 61.93,89.43 66.12,85.24 v2(66.12,82.17)
LED7_PWM: length 29.6
  TOP w0.193: U11.A22 v1(80.66,85.2)
  TOP w0.254: U8.8 v2(59.52,89.19)
  L05_SIG2 w0.102: 79.69,85.2 v1(80.66,85.2)
  L05_SIG2 w0.155: 79.69,85.2 74.06,85.2 73.24,84.38 72.31,84.38 72.06,84.13 71.02,84.13 70.53,83.64 v2(65.3,83.64)
  BOTTOM w0.193: v2(59.52,89.19) 60.42,89.19 60.75,88.86 61.78,88.86 65.3,85.34 v2(65.3,83.64)
  BOTTOM w0.254: RN502.2 58.28,88.35 59.13,89.19 v2(59.52,89.19)
LED8_PWM: length 31.2
  TOP w0.178: 61.07,88.22 v2(61.07,88.23)
  TOP w0.193: 60.49,88.54 60.75,88.54 61.07,88.22 61.07,88.22 61.68,87.6 61.68,86.28 62.94,85.03 64.18,85.03 64.78,85.63 68.23,85.63 70.11,87.5 72.14,87.5 72.47,87.17 77.42,87.17 78.89,85.7 U11.A23
  TOP w0.254: 60.49,88.54 U8.9
  BOTTOM w0.254: RN502.3 58.2,87.55 59.2,88.54 60.2,88.54 60.51,88.23 v2(61.07,88.23)
LED_DIN: length 18.2
  TOP w0.193: J44.3 50.77,19.47 J43.2
  BOTTOM w0.193: J44.3 53.52,20.32 55.42,22.22 TP50.1 56.27,23.22 56.74,22.75 R721.1 57.78,25.29 R722.2
LED_DIR: length 15.4
  TOP w0.193: J43.5 47.02,12.24 44.41,9.63 41.98,9.63 TP51.1
  BOTTOM w0.193: R739.2 41.39,13.86 TP51.1
LED_DOUT: length 19.9
  TOP w0.193: TP53.1 54.7,9.49 51.1,9.49 50.51,10.08 50.51,11.9 49.52,12.89 J43.3
  BOTTOM w0.193: R759.2 49.86,11.78 50.52,11.12 50.52,9.69 51.33,8.88 54.09,8.88 TP53.1
LED_EN: length 49.4
  TOP w0.193: J33.3 2.25,16.58 2.03,16.79 2.03,28.19 2.54,28.7 9.4,28.7 12.19,25.91 v2(14.73,25.91)
  BOTTOM w0.193: J41.2 24.28,15.21 22.77,13.7 22.77,13.29 22.21,12.73 20.36,12.73 19.87,13.22 19.87,20.77 v2(14.73,25.91)
LED_OE: length 18
  TOP w0.193: J43.4 48.27,12.75 44.32,8.8 40.48,8.8 TP52.1
  BOTTOM w0.193: R761.2 42.27,12.29 TP52.1
LED_SCLK: length 9.5
  TOP w0.193: J43.1 52.02,14.7 52.27,14.95 53.06,14.95 55.27,12.74 TP54.1
  BOTTOM w0.193: TP54.1 53.06,12.24 52.31,11.49 R758.2
LMP_HOT: length 26.5
  TOP w0.193: v2(51.76,106.35) 51.76,106.4 51.09,107.08 51.09,107.75 50.55,108.28 50.08,108.76 50.08,111.46 49.56,111.98 44.99,111.98 J6.1
  BOTTOM w0.193: v2(51.76,106.35) 53.27,106.35 R528.2 55.49,104.13 55.49,101.72 J9.3
LMP_TXD: length 14.5
  BOTTOM w0.193: J40.3 22.61,9.21 R763.1 R764.2 19.74,10.24 13.86,10.24 12.32,8.7 U524.2
LMP_TXD_BUF: length 3.5
  TOP w0.193: v2(12.5,1.65) 12.5,2.03 13.37,2.89 J48.5
  BOTTOM w0.193: v2(12.5,1.65) 12.51,1.65 12.51,1.65 13.34,2.48 R778.1
LMPCTRL: length 380.2
  TOP w0.193: U11.AC9 v1(103.66,71.2) ; v2(126.97,55.89) 126.6,56.27 126.6,57.27 127.7,58.37 127.7,61.71 124.53,64.88 124.53,66.67 124.53,66.89 124.53,70.37 124.94,70.78 124.94,72.81 127.51,75.39 131.54,75.39 134.2,78.04 140.02,78.04 141.92,79.94 142.47,79.94 142.87,80.34 142.87,81.18 142.68,81.37 141.97,81.37 139.51,78.92 129.08,78.92 127.71,77.55 123.25,77.55 122.64,78.16 122.64,83.54 130.92,91.83 137.65,91.83 142.28,87.19 147.64,87.19 149.11,85.72 TP22.1
  L03_SIG1 w0.155: v2(143.51,33.74) 143.51,41.34 140.74,44.11 139.51,44.11 139.1,44.52 139.1,44.94 138.1,45.95 138.1,47.9 138.01,47.99 138.01,48.35 135.79,50.57 131.7,50.57 131.22,51.05 131.22,51.61 130.87,51.96 130.86,51.96 126.97,55.85 v2(126.97,55.89) ; v2(68.36,17.66) 68.66,17.35 68.66,13.49 67.72,12.55 67.72,10.6 60.18,3.06 28.78,3.06 27.22,4.63 22.37,4.63 21.63,5.37 11.67,5.37 7.77,9.27 v2(7.62,9.27)
  L05_SIG2 w0.155: v2(126.97,55.89) 126.97,55.22 126.55,54.8 126.55,52.08 123.16,48.68 v2(106.59,48.68)
  BOTTOM w0.102: v1(103.66,71.2) 103.22,71.2 102.83,71.59 102.5,71.59 102.27,71.36 102.27,66.94 101.92,66.59 101.5,66.59 101.27,66.36 101.27,63.01 102.05,62.23
  BOTTOM w0.193: v2(126.97,55.89) 123.83,59.03 R668.2 ; v2(7.62,9.27) 7.24,9.65 7.24,10.07 5.11,12.2 U517.3 ; v2(143.51,33.74) 143,33.23 139.22,33.23 133.19,27.2 133.19,21 133.52,20.68 133.52,18.96 133.23,18.67 131.55,18.67 128.82,21.39 124.65,21.39 123.53,22.51 122.32,22.51 121.95,22.14 121.95,20.83 119,17.88 98.18,17.88 92.2,23.86 70.12,23.86 68.29,22.03 68.29,17.72 v2(68.36,17.66) ; R668.2 122.39,59.07 R670.1 ; R668.2 U508.2 ; 102.05,62.23 102.36,61.92 102.36,54.62 103.93,53.05 103.93,51.34 v2(106.59,48.68)
LMPCTRL_BUF: length 195.8
  TOP w0.193: J48.6 11.62,3.28 10.84,2.5 v2(10.84,2.5)
  L03_SIG1 w0.155: v2(126.46,15.48) 126.46,17.51 127.5,18.54 132.83,18.54 134.71,20.43 134.71,34.79 135.83,35.91 135.83,36.4 134.71,37.52 134.71,38.94 134.15,39.5 134.15,40.36 133.43,41.08 131.95,41.08 127.2,45.83 127.2,47.23 123.1,51.33 123.1,52.14 123.91,52.95 123.91,52.96 123.96,53.02 123.96,57.91 123.91,57.96 123.91,57.96 123.1,58.78 123.1,58.78 122.99,58.89 122.99,64.68 122.46,65.21 121.44,65.21 v2(120.47,66.18)
  L05_SIG2 w0.155: v2(10.84,2.5) 11.54,3.21 16.34,3.21 16.83,2.72 64.92,2.72 v2(67.2,5)
  BOTTOM w0.193: v2(126.46,15.48) 126.46,6.02 125.39,4.95 67.24,4.95 v2(67.2,5) ; R622.1 v2(120.47,66.18)
LMPCTRL_Z: length 179
  TOP w0.193: J48.4 14.61,2.82 14.12,2.32 v2(14.12,1.89)
  L03_SIG1 w0.155: v2(127.24,14.85) 127.24,17.56 127.87,18.19 133.14,18.19 135.14,20.19 135.14,34.61 136.26,35.73 136.26,39.08 134.99,40.35 134.78,40.35 133.61,41.51 132.37,41.51 128.37,45.52 128.37,47.12 v2(123.75,51.74)
  L05_SIG2 w0.155: v2(14.12,1.89) 14.82,2.6 15.82,2.6 16.29,2.14 65.97,2.14 v2(68.18,4.34)
  BOTTOM w0.193: R669.1 121.12,51.74 v2(123.75,51.74) ; v2(127.24,14.85) 127.24,6.02 124.92,3.7 68.82,3.7 v2(68.18,4.34)
LMPSTAT: length 177.4
  TOP w0.193: v2(102.59,38.41) 101.68,39.32 101.68,44.77 106.21,49.3 109.93,49.3 112.51,51.88 112.51,56.04 113.96,57.49 113.96,59.27 115.6,60.91 119.05,60.91 121.18,63.04 121.18,69.57 117.81,72.94 109.27,72.94 107,70.67 107,70.54 v1(106.66,70.2) U11.AF8
  L03_SIG1 w0.155: v2(75.06,35.01) 75.06,30.3 72.06,27.3 72.06,20 70.39,18.33 70.39,13.54 71.02,12.91 71.02,11.99 66.35,7.33 v2(66.35,5.5)
  L05_SIG2 w0.155: v2(66.35,5.5) 64.57,3.72 51.45,3.72 49.29,5.88 26.24,5.88 23.4,8.71 17.52,8.71 v2(17.02,9.22)
  BOTTOM w0.193: v2(75.06,35.01) 78.46,38.41 v2(102.59,38.41) ; U522.4 v2(17.02,9.22)
LP_DRIVE: length 12.9
  L03_SIG1 w0.155: v2(186.68,80.15) 186.68,76.85 186.06,76.23 186.06,75.66 186.31,75.41 186.31,73.01 v2(185.88,72.59)
  BOTTOM w0.193: R575.1 R574.1 v2(186.68,80.15) ; U505.5 186.34,72.12 v2(185.88,72.59)
LP_IR0: length 251.8
  L03_SIG1 w0.155: v2(191.81,67.1) 192.73,67.1 194.16,68.53 194.16,69.81 193.7,70.27 193.7,72.25 195.06,73.61 195.06,76.53 193.67,77.93 193.67,80.59 194.35,81.27 194.35,94.14 193.83,94.67 193.83,98.79 195.09,100.04 195.09,109.89 194.3,110.68 194.3,120.07 187.54,126.82 v2(184.61,126.82)
  L05_SIG2 w0.155: v2(184.61,126.82) 179.6,126.82 178.36,125.58 172.72,125.58 171.91,124.76 158.98,124.76 156.64,127.1 151.92,127.1 147.88,123.06 129.28,123.06 123.9,128.44 103.38,128.44 102.02,129.79 37.66,129.79 29.03,121.16 U1.1
  BOTTOM w0.193: v2(191.81,67.1) 191.07,67.84 191.07,69.01 R590.1 ; U500.2 U1.1
LP_IR1: length 78.7
  L03_SIG1 w0.155: v2(178.68,69.74) 178.68,68.98 179.41,68.25 180.08,68.25 181.14,67.19 181.14,65.92 182.85,64.21 182.85,50.93 182.52,50.6 182.52,36.82 184.13,35.2 184.13,30.46 177.79,24.11 177.79,13.06 180.8,10.04 180.8,7.16 U22.1
  BOTTOM w0.193: U518.2 182.73,7.49 182.16,6.93 182.16,5.8 U22.1 ; R593.1 v2(178.68,69.74)
LP_P1_0: length 3.2
  BOTTOM w0.193: U505.2 189.29,74.07 190.33,73.03 R588.2
LP_P1_5: length 3.3
  BOTTOM w0.193: R590.2 189.79,69.47 188.44,70.82 U505.7
LP_P1_6: length 2.4
  BOTTOM w0.193: U505.8 179.8,70.82 R593.2
LP_P2_6: length 2.4
  BOTTOM w0.193: U505.13 179.75,74.07 R591.2
LP_P2_7: length 2.5
  BOTTOM w0.193: U505.12 180.12,73.42 179.85,73.15 R592.2
LP_P3P3V: length 322.3
  L03_SIG1 w0.508: v2(19.82,126.19) 19.57,126.44 12.91,126.44 10.19,123.73 10.19,118.1 2.54,110.45 2.54,23.07 3.17,22.43 3.17,12.4 2.27,11.49 2.27,9.49 3.63,8.13 5.08,8.13 6.05,7.16 8.37,7.16 12.39,3.14 21.02,3.14 22.13,2.04 133.68,2.04 137.12,5.48 153.84,5.48 156.15,3.18 159.3,3.18 160.79,4.67 174.78,4.67 v2(179.2,9.08)
  BOTTOM w0.381: v2(179.2,9.08) 179.84,8.43 U518.5
  BOTTOM w0.508: R505.1 15.57,128.33 15.68,128.33 16.27,127.75 C504.2 R504.1 C503.2 18.72,127.67 U500.5 v2(19.82,126.19)
LP_TA0: length 3.3
  BOTTOM w0.193: R589.2 190.33,72.14 189.04,73.42 U505.3
LP_TCK: length 12.8
  TOP w0.193: J17.2 186.03,60.38 180.47,65.95 v2(180.47,66.68)
  BOTTOM w0.193: R608.1 v2(180.47,66.68)
LP_TDO_TDI: length 29
  TOP w0.193: J17.4 183.53,56.8 184.49,55.85 187.51,55.85 188.12,56.46 188.12,61.76 183.02,66.87 v2(183.01,66.87)
  BOTTOM w0.193: v2(183.01,66.87) R606.1 183.12,67.69 185.29,67.69 185.85,68.25 C605.2 184.6,69.57 184.6,71.67 184.16,72.12 U505.10
LP_TEST_VPP: length 20.1
  TOP w0.193: J17.3 184.78,60.22 179.65,65.35 v2(179.65,68.85) 179.65,71.61 v2(180.24,72.19)
  BOTTOM w0.193: v2(180.24,72.19) 180.81,72.77 U505.11 ; R608.2 v2(179.65,68.85)
M_DCLKA_N: length 99.1
  TOP w0.108: J63.K05 v2(76.61,3.05)
  TOP w0.193: U11.V3 v1(98.66,65.2)
  L05_SIG2 w0.102: 82.29,62.54 82.29,62.57 82.26,62.6 82.26,66.4 82.46,66.6 83.91,66.6 84.26,66.95 84.26,67.41 84.45,67.6 93.93,67.6 94.93,66.6 97.84,66.6 98.06,66.37 98.06,65.84 98.3,65.6 98.67,65.6 98.78,65.5 98.78,65.31 v1(98.66,65.2)
  L05_SIG2 w0.105: v2(76.61,3.05) 76.48,2.92 76.24,2.92 76.1,3.06 76.1,3.5 75.78,3.81 73.57,3.81 72.65,4.72 72.65,7.48 73.55,8.38 74.88,8.38 76.1,9.6 76.1,16.39 77.4,17.69 77.4,31.25 77.68,31.53 78.08,31.53 78.33,31.28 78.33,28.53 78.68,28.18 79.2,28.18 79.58,28.56 79.58,58.74 82.29,61.44 82.29,62.54
M_DCLKA_P: length 99.1
  TOP w0.108: J63.K04 v2(75.34,3.05)
  TOP w0.193: U11.V4 v1(98.66,66.2)
  L05_SIG2 w0.102: v1(98.66,66.2) 98.66,65.9 98.56,65.8 98.39,65.8 98.27,65.92 98.27,66.45 97.92,66.8 95.01,66.8 94.01,67.81 84.37,67.81 84.06,67.49 84.06,67.03 83.82,66.8 82.38,66.8 82.06,66.48 82.06,62.6 82.03,62.57 82.03,62.54
  L05_SIG2 w0.105: v2(75.34,3.05) 75.74,3.05 75.84,3.15 75.84,3.39 75.68,3.56 73.46,3.56 72.4,4.62 72.4,7.59 73.45,8.64 74.78,8.64 75.84,9.71 75.84,16.5 77.14,17.8 77.14,31.35 77.58,31.79 78.18,31.79 78.58,31.39 78.58,28.64 78.78,28.44 79.1,28.44 79.33,28.67 79.33,58.84 82.03,61.55 82.03,62.54
M_DCLKB_N: length 95.8
  TOP w0.108: J63.J03 v2(74.07,4.32) ; U11.J4 v1(88.66,66.2)
  L05_SIG2 w0.102: v1(88.66,66.2) 88.66,65.9 88.56,65.8 88.42,65.8 88.26,65.96 88.26,66.58 88.04,66.8 84.42,66.8 84.06,66.45 84.06,66 83.86,65.8 83.4,65.8 83.06,65.46 83.06,62.49 83.04,62.47 83.04,62.44
  L05_SIG2 w0.105: v2(74.07,4.32) 74.07,4.66 73.96,4.76 73.61,4.76 73.16,5.21 73.16,7.27 73.7,7.8 76.16,7.8 77.67,9.32 77.67,10.61 77.06,11.22 77.06,12.49 78.38,13.81 78.38,26.8 78.77,27.2 79.44,27.2 79.83,26.81 79.83,18.18 79.98,18.03 80.27,18.03 80.48,18.24 80.48,58.39 83.04,60.95 83.04,62.44
M_DCLKB_P: length 95.8
  TOP w0.108: J63.J02 v2(74.07,5.59) ; U11.J3 v1(88.66,65.2)
  L05_SIG2 w0.102: v1(88.66,65.2) 88.77,65.2 88.88,65.3 88.88,65.46 88.74,65.6 88.33,65.6 88.06,65.87 88.06,66.5 87.96,66.6 84.5,66.6 84.27,66.36 84.27,65.92 83.95,65.6 83.48,65.6 83.27,65.38 83.27,62.49 83.29,62.47 83.29,62.44
  L05_SIG2 w0.105: 83.29,62.44 83.29,60.85 80.73,58.29 80.73,18.13 80.38,17.78 79.88,17.78 79.58,18.08 79.58,26.7 79.34,26.94 78.88,26.94 78.63,26.7 78.63,13.71 77.31,12.39 77.31,11.33 77.92,10.72 77.92,9.21 76.26,7.55 73.8,7.55 73.41,7.16 73.41,5.31 73.71,5.01 74.09,5.01 74.26,5.18 74.26,5.42 74.1,5.59 v2(74.07,5.59)
M_DDA00_N: length 99.1
  TOP w0.108: J63.D21 v2(98.2,11.94)
  TOP w0.193: U11.P3 v1(93.66,65.2)
  L05_SIG2 w0.102: v1(93.66,65.2) 93.71,65.25 93.71,65.51 93.56,65.67 93.42,65.67 93.26,65.51 93.26,64.72 93.29,64.7 93.29,64.67
  L05_SIG2 w0.105: v2(98.2,11.94) 97.79,11.94 97.69,12.04 97.69,16.68 95.79,18.58 95.79,20.67 94.25,22.21 94.25,25.68 93.46,26.46 93.46,32.55 93.12,32.89 92.6,32.89 92.3,32.59 92.3,27.34 92.1,27.14 91.74,27.14 91.59,27.29 91.59,33.16 91.96,33.52 92.89,33.52 93.2,33.83 94.62,33.83 95.47,34.68 95.47,45.95 95.22,46.21 94.57,46.21 94.32,45.95 94.32,35.13 94.15,34.96 93.8,34.96 93.68,35.08 93.68,55.63 94.92,56.88 94.92,58.17 93.62,59.48 93.62,63.13 93.29,63.47 93.29,64.67
M_DDA00_P: length 99.1
  TOP w0.108: J63.D20 v2(96.93,11.94)
  TOP w0.193: U11.P4 v1(93.66,66.2)
  L05_SIG2 w0.102: v1(93.66,66.2) 93.06,65.6 93.06,64.72 93.03,64.7 93.03,64.67
  L05_SIG2 w0.105: 93.03,64.67 93.03,63.36 93.37,63.02 93.37,59.37 94.67,58.07 94.67,56.98 93.42,55.74 93.42,34.97 93.69,34.7 94.25,34.7 94.57,35.02 94.57,45.85 94.68,45.95 95.11,45.95 95.22,45.85 95.22,34.79 94.52,34.09 93.1,34.09 92.79,33.78 91.85,33.78 91.34,33.26 91.34,27.19 91.64,26.89 92.2,26.89 92.55,27.23 92.55,32.48 92.71,32.64 93.02,32.64 93.21,32.45 93.21,26.36 94,25.57 94,22.11 95.54,20.57 95.54,18.47 97.43,16.58 97.43,12.04 97.33,11.94 v2(96.93,11.94)
M_DDA01_N: length 100.1
  TOP w0.102: 94.03,63.26 94.16,63.4 U11.P1
  TOP w0.108: J63.C23 v2(100.74,13.21) ; v2(94.04,57.66) 93.94,57.55 93.79,57.55 93.68,57.67 93.68,61.86 94.03,62.21 94.03,63.26
  L03_SIG1 w0.105: v2(100.74,13.21) 100.74,13.17 100.63,13.07 100.24,13.07 100.08,13.22 100.08,13.46 100.23,13.61 100.23,19.17 95.37,24.03 95.37,29.99 95.08,30.28 94.58,30.28 94.22,29.92 94.22,23.19 94.08,23.05 93.73,23.05 93.57,23.21 93.57,33.54 94.67,34.64 94.67,37.37 96.23,38.94 96.23,40.75 97.15,41.67 97.15,44.27 95.9,45.53 95.48,45.53 95.08,45.13 95.08,44.74 96.03,43.79 96.03,42.15 95.08,41.21 95.08,39.42 93.95,38.29 93.73,38.29 93.5,38.53 93.5,38.76 94.47,39.73 94.47,41.46 95.25,42.24 95.25,43.69 94.91,44.03 94.41,44.03 94.08,43.71 94.08,42.68 93.91,42.5 93.62,42.5 93.47,42.65 93.47,44.41 95.38,46.32 95.38,55.57 95.6,55.79 96.84,55.79 97.19,56.14 97.19,56.67 96.86,57.01 93.85,57.01 93.7,57.16 93.7,57.6 93.83,57.72 93.97,57.72 v2(94.04,57.66)
M_DDA01_P: length 100.1
  TOP w0.102: 93.8,63.26 93.8,63.27 93.8,63.28 ; 93.8,63.29 93.7,63.39 93.7,64.24 U11.P2
  TOP w0.108: 93.8,63.28 93.8,63.29 ; v2(93.1,57.66) 93.45,58 93.45,61.95 93.8,62.3 93.8,63.26 ; J63.C22 v2(99.47,13.21)
  L03_SIG1 w0.105: v2(99.47,13.21) 99.97,13.72 99.97,19.07 95.12,23.92 95.12,29.88 94.98,30.02 94.68,30.02 94.47,29.82 94.47,23.09 94.18,22.79 93.62,22.79 93.31,23.11 93.31,33.65 94.41,34.75 94.41,37.48 95.97,39.04 95.97,40.85 96.9,41.78 96.9,44.16 95.79,45.27 95.59,45.27 95.34,45.02 95.34,44.84 96.28,43.9 96.28,42.04 95.34,41.1 95.34,39.32 94.06,38.04 93.63,38.04 93.24,38.42 93.24,38.87 94.21,39.84 94.21,41.57 94.99,42.35 94.99,43.59 94.8,43.78 94.51,43.78 94.34,43.6 94.34,42.57 94.01,42.25 93.51,42.25 93.22,42.54 93.22,44.51 95.13,46.43 95.13,55.68 95.49,56.04 96.74,56.04 96.94,56.24 96.94,56.57 96.75,56.75 93.74,56.75 93.44,57.05 93.44,57.31 v2(93.1,57.66)
M_DDA02_N: length 100.1
  TOP w0.108: J63.H23 v2(100.74,6.86)
  TOP w0.193: U11.R3 v1(95.66,65.2)
  L03_SIG1 w0.102: v1(95.66,65.2) 96.26,65.8 96.26,66.44 95.9,66.8 95.04,66.8 94.04,67.8 86.4,67.8 86.06,67.46 86.06,64.66
  L03_SIG1 w0.105: v2(100.74,6.86) 100.34,6.86 100.23,6.75 100.23,6.57 99.76,6.1 94.93,6.1 93.66,7.37 88.39,7.37 84.73,11.02 84.73,48.16 87.36,50.78 87.36,59.94 87.84,60.42 88.67,60.42 88.98,60.74 88.98,64.26 88.79,64.46 87.95,64.46 87.7,64.21 87.7,61.54 87.29,61.13 86.35,61.13 86.03,61.45 86.03,64.64 86.06,64.66
M_DDA02_P: length 100.1
  TOP w0.108: J63.H22 v2(99.47,6.86)
  TOP w0.193: U11.R4 v1(95.66,66.2)
  L03_SIG1 w0.102: 86.26,64.74 86.26,64.74 86.26,67.38 86.48,67.6 93.96,67.6 94.95,66.6 95.82,66.6 96.06,66.36 96.06,65.95 95.91,65.8 95.58,65.8 95.48,65.9 95.48,66.07 95.6,66.2 v1(95.66,66.2)
  L03_SIG1 w0.105: 86.26,64.74 86.28,64.72 86.29,64.64 86.29,64.22 86.44,64.07 86.64,64.07 86.79,63.91 86.79,63.69 86.64,63.54 86.44,63.54 86.29,63.39 86.29,61.55 86.45,61.38 87.18,61.38 87.45,61.65 87.45,64.32 87.84,64.71 88.89,64.71 89.24,64.37 89.24,60.63 88.78,60.17 87.95,60.17 87.61,59.84 87.61,50.67 84.99,48.05 84.99,11.12 88.49,7.62 90.68,7.62 90.83,7.77 90.83,7.93 90.99,8.08 91.29,8.08 91.46,7.92 91.46,7.72 91.56,7.62 93.77,7.62 95.03,6.35 99.66,6.35 99.89,6.59 99.89,6.93 99.79,7.04 99.57,7.04 99.47,6.93 v2(99.47,6.86)
M_DDA03_N: length 100.1
  TOP w0.102: U11.R1 95.16,63.39 95.31,63.25
  TOP w0.108: J63.G22 v2(99.47,8.13) ; v2(90.43,52.67) 90.79,52.32 90.94,52.32 91.09,52.46 91.09,52.64 91.74,53.3 92.13,53.3 93.34,54.51 93.34,55.7 95.31,57.67 95.31,63.25
  L03_SIG1 w0.105: v2(90.43,52.67) 90.06,52.3 89.62,52.3 89.31,51.99 89.31,49.72 86.92,47.33 86.92,17.81 87.27,17.45 87.71,17.45 88.05,17.78 88.05,30.05 88.18,30.19 88.51,30.19 88.67,30.02 88.67,17.48 87.27,16.08 87.27,11.3 88.67,9.91 90.65,9.91 90.76,9.8 90.76,9.69 90.86,9.58 91.19,9.58 91.31,9.7 91.31,9.8 91.42,9.91 93.46,9.91 96.05,7.31 98.47,7.31 98.96,7.8 98.96,8.02 99.06,8.13 v2(99.47,8.13)
M_DDA03_P: length 100.1
  TOP w0.102: U11.R2 95.64,64.22 95.64,63.35 95.54,63.25
  TOP w0.108: v2(90.43,51.73) 90.43,51.82 90.7,52.09 91.04,52.09 91.32,52.37 91.32,52.55 91.84,53.07 92.22,53.07 93.57,54.41 93.57,55.6 95.54,57.57 95.54,63.25 ; J63.G21 v2(98.2,8.13)
  L03_SIG1 w0.105: v2(90.43,51.73) 90.43,51.89 90.27,52.05 89.72,52.05 89.56,51.89 89.56,49.61 87.17,47.22 87.17,17.91 87.38,17.7 87.61,17.7 87.79,17.89 87.79,30.16 88.07,30.44 88.61,30.44 88.93,30.12 88.93,17.37 87.53,15.98 87.53,11.41 88.78,10.16 93.56,10.16 96.15,7.57 98.37,7.57 98.7,7.9 98.7,8.02 98.6,8.13 v2(98.2,8.13)
M_DDA04_N: length 100.1
  TOP w0.108: J63.H26 v2(103.28,6.86)
  TOP w0.193: U11.T3 v1(96.66,65.2)
  L03_SIG1 w0.102: v1(96.66,65.2) 97.26,65.8 97.26,66.47 96.93,66.8 96.48,66.8 96.26,67.02 96.26,67.46 95.92,67.8 95.24,67.8 94.23,68.81 85.39,68.81 85.06,68.47 85.06,64.64 85.04,64.62 85.04,64.59
  L03_SIG1 w0.105: v2(103.28,6.86) 102.51,6.1 100.52,6.1 99.25,4.83 93.97,4.83 92.7,6.1 87.65,6.1 83.46,10.29 83.46,48.14 86.48,51.16 86.48,54.18 84.54,56.13 84.54,61.73 85.04,62.23 85.04,64.59
M_DDA04_P: length 100.1
  TOP w0.108: J63.H25 v2(102.01,6.86)
  TOP w0.193: U11.T4 v1(96.66,66.2)
  L03_SIG1 w0.102: v1(96.66,66.2) 96.53,66.07 96.53,65.9 96.63,65.8 96.91,65.8 97.06,65.95 97.06,66.39 96.85,66.6 96.4,66.6 96.06,66.94 96.06,67.37 95.84,67.6 95.15,67.6 94.15,68.6 85.48,68.6 85.27,68.39 85.27,64.64 85.29,64.62 85.29,64.59
  L03_SIG1 w0.105: 85.29,64.59 85.29,62.12 84.8,61.63 84.8,58.52 84.9,58.41 85.09,58.41 85.28,58.23 85.28,57.97 85.09,57.79 84.92,57.79 84.8,57.67 84.8,56.23 86.74,54.29 86.74,51.05 83.72,48.03 83.72,10.39 87.76,6.35 92.81,6.35 94.08,5.08 97.89,5.08 98,5.18 98,5.33 98.19,5.52 98.45,5.52 98.62,5.35 98.62,5.18 98.73,5.08 99.15,5.08 100.42,6.35 102.28,6.35 102.52,6.59 102.52,6.86 102.36,7.03 102.14,7.03 102.01,6.9 v2(102.01,6.86)
M_DDA05_N: length 100.1
  TOP w0.102: 96.32,63.23 96.16,63.39 U11.T1
  TOP w0.108: 96.32,63.23 96.32,56.43 96.16,56.28 95.83,56.28 95.67,56.12 95.67,55.89 95.83,55.74 96.16,55.74 96.32,55.58 96.32,54.78 97.26,53.84 100.84,53.84 101.05,53.62 101.05,52.45 100.83,52.23 97.7,52.23 95.21,54.72 94.71,54.72 94.18,54.19 94.18,53.7 95.8,52.08 95.8,51.75 95.43,51.39 95.11,51.39 94.41,52.08 92.17,52.08 91.96,52.3 v2(91.96,52.38) ; J63.G25 v2(103.28,8.13)
  L03_SIG1 w0.105: v2(103.28,8.13) 103.13,7.98 102.93,7.98 102.77,8.14 102.77,8.45 102.35,8.87 101.74,8.87 101.5,9.11 101.5,9.78 101.12,10.16 96.89,10.16 96.42,10.64 96.42,12.26 95.98,12.7 90.56,12.7 90.07,13.19 90.07,16.09 91.26,17.29 91.26,21.2 90.83,21.63 90.83,45.54 91.89,46.6 91.89,47.11 91.59,47.41 91.08,47.41 89.69,46.02 89.69,44.61 89.48,44.4 89.17,44.4 88.96,44.61 88.96,46.41 92.77,50.22 92.77,51.71 92.44,52.04 92.06,52.04 91.96,52.14 v2(91.96,52.38)
M_DDA05_P: length 100.1
  TOP w0.102: 96.55,63.25 96.64,63.34 96.64,64.22 U11.T2
  TOP w0.108: v2(91.96,51.43) 92.38,51.85 94.32,51.85 95.01,51.16 95.53,51.16 96.03,51.66 96.03,52.17 94.41,53.79 94.41,54.1 94.81,54.49 95.11,54.49 97.61,52 100.93,52 101.28,52.36 101.28,53.71 100.93,54.06 97.36,54.06 96.55,54.87 96.55,63.25 ; J63.G24 v2(102.01,8.13)
  L03_SIG1 w0.105: v2(102.01,8.13) 102.41,8.13 102.51,8.23 102.51,8.34 102.24,8.61 101.64,8.61 101.24,9 101.24,9.68 101.02,9.91 96.79,9.91 96.16,10.53 96.16,12.16 95.88,12.45 90.45,12.45 89.81,13.09 89.81,16.2 91.01,17.39 91.01,21.09 90.58,21.52 90.58,45.65 91.64,46.71 91.64,47 91.49,47.16 91.19,47.16 89.95,45.91 89.95,44.51 89.59,44.15 89.06,44.15 88.7,44.51 88.7,46.52 92.51,50.33 92.51,51.61 92.34,51.79 92.1,51.79 91.96,51.64 v2(91.96,51.43)
M_DDA06_N: length 99.1
  TOP w0.108: J63.D24 v2(102.01,11.94)
  TOP w0.193: U11.U3 v1(97.66,65.2)
  L05_SIG2 w0.102: v1(97.66,65.2) 97.7,65.24 97.7,65.57 97.6,65.67 97.42,65.67 97.26,65.51 97.26,64.77 97.29,64.75 97.29,64.72
  L05_SIG2 w0.105: v2(102.01,11.94) 101.6,11.94 101.5,12.04 101.5,12.37 101.17,12.7 99.22,12.7 98.96,12.96 98.96,16.26 99.83,17.13 99.83,18.65 98.52,19.96 98.52,23.46 98.19,23.79 97.64,23.79 97.37,23.52 97.37,19.46 98.69,18.13 98.69,17.83 98.51,17.65 98.2,17.65 96.69,19.15 96.69,22.78 96.21,23.26 96.21,29.92 95.89,30.25 95.4,30.25 95.08,29.93 95.08,26.85 94.88,26.64 94.54,26.64 94.33,26.85 94.33,31.66 96.35,33.68 96.35,51.14 96.03,51.46 95.53,51.46 95.18,51.11 95.18,47.62 94.94,47.37 94.71,47.37 94.55,47.53 94.55,55.19 95.88,56.52 95.88,60.03 95.44,60.47 95.19,60.47 94.93,60.73 94.93,61.51 95.14,61.72 95.67,61.72 96.04,62.09 96.04,62.89 95.64,63.28 94.49,63.28 94.27,63.5 94.27,63.87 94.47,64.07 96.9,64.07 97.29,64.46 97.29,64.72
M_DDA06_P: length 99.1
  TOP w0.108: J63.D23 v2(100.74,11.94)
  TOP w0.193: U11.U4 v1(97.66,66.2)
  L05_SIG2 w0.102: v1(97.66,66.2) 97.06,65.6 97.06,64.77 97.03,64.75 97.03,64.72
  L05_SIG2 w0.105: v2(100.74,11.94) 101.14,11.94 101.24,12.04 101.24,12.27 101.07,12.45 99.11,12.45 98.7,12.86 98.7,16.36 99.57,17.23 99.57,18.54 98.27,19.85 98.27,23.35 98.08,23.54 97.74,23.54 97.62,23.42 97.62,19.56 98.95,18.23 98.95,17.73 98.61,17.39 98.09,17.39 96.44,19.05 96.44,22.67 95.96,23.15 95.96,29.82 95.78,29.99 95.5,29.99 95.33,29.82 95.33,26.74 94.98,26.39 94.43,26.39 94.08,26.74 94.08,31.77 96.09,33.78 96.09,51.03 95.92,51.21 95.63,51.21 95.43,51 95.43,47.51 95.04,47.12 94.61,47.12 94.3,47.43 94.3,55.3 95.63,56.63 95.63,59.93 95.34,60.22 95.08,60.22 94.67,60.62 94.67,61.62 95.03,61.97 95.57,61.97 95.79,62.19 95.79,62.78 95.54,63.03 94.38,63.03 94.02,63.39 94.02,63.98 94.37,64.33 96.79,64.33 97.03,64.57 97.03,64.72
M_DDA07_N: length 99.1
  TOP w0.102: 97.31,63.22 97.16,63.37 U11.U1
  TOP w0.108: 97.31,63.22 97.31,62.28 98.14,61.46 98.14,59.7 97.98,59.54 97.87,59.54 97.71,59.38 97.71,59.16 97.87,59 97.98,59 98.14,58.84 98.14,57.21 97.98,57.05 97.73,57.05 97.57,56.9 97.57,56.67 97.73,56.52 97.98,56.52 98.14,56.36 98.14,55.03 v2(97.78,54.67) ; J63.H29 v2(108.36,5.59)
  L05_SIG2 w0.105: v2(108.36,5.59) 108.18,5.42 107.89,5.42 107.76,5.55 107.76,5.9 107.95,6.1 111.23,6.1 111.66,6.52 111.66,8.58 113,9.92 113,10.93 111.78,12.16 110.35,12.16 109.81,12.7 104.27,12.7 104.04,12.93 104.04,16.11 103.47,16.68 103.47,20.23 102.23,21.47 102.23,23.45 98.1,27.59 98.1,37.16 99.96,39.03 99.96,47.87 99.63,48.2 99.16,48.2 98.82,47.86 98.82,39.47 98.6,39.25 98.31,39.25 98.12,39.44 98.12,52.18 96.54,53.76 96.54,54.64 97.18,55.28 97.97,55.28 98.11,55.15 98.11,54.72 98,54.62 97.84,54.62 v2(97.78,54.67)
M_DDA07_P: length 99.1
  TOP w0.102: U11.U2 97.64,64.22 97.64,63.34 97.54,63.24
  TOP w0.108: 97.54,63.24 97.54,62.38 98.37,61.55 98.37,55.03 v2(98.72,54.67) ; J63.H28 v2(107.09,5.59)
  L05_SIG2 w0.105: v2(98.72,54.67) 98.36,55.04 98.36,55.25 98.08,55.54 97.08,55.54 96.28,54.74 96.28,53.66 97.87,52.07 97.87,39.34 98.21,39 98.7,39 99.07,39.37 99.07,47.75 99.26,47.94 99.53,47.94 99.71,47.76 99.71,39.13 97.84,37.27 97.84,27.48 101.98,23.35 101.98,21.36 103.21,20.13 103.21,16.57 103.78,16 103.78,12.82 104.16,12.45 109.7,12.45 110.24,11.9 111.67,11.9 112.75,10.83 112.75,10.03 111.4,8.68 111.4,6.63 111.13,6.35 107.85,6.35 v2(107.09,5.59)
M_DDA08_N: length 99.1
  TOP w0.108: J63.G28 v2(107.09,6.86)
  TOP w0.193: U11.W3 v1(99.66,65.2)
  L05_SIG2 w0.102: v1(99.66,65.2) 99.69,65.23 99.69,65.57 99.58,65.68 99.43,65.68 99.27,65.52 99.27,64.76 99.29,64.73 99.29,64.71
  L05_SIG2 w0.105: 99.29,64.71 99.29,64.46 98.06,63.22 97.58,63.22 96.91,62.56 96.91,59.68 97.66,58.93 97.66,57.73 96.77,56.84 96.77,56.11 95.42,54.76 95.42,52.66 95.71,52.37 96.39,52.37 97.23,51.54 97.23,33.23 96.05,32.05 96.05,31.36 97.23,30.19 97.23,26 99.4,23.83 99.4,20.33 100.75,18.97 100.75,17.54 100.91,17.39 101.29,17.39 101.4,17.5 101.4,19.2 100.04,20.56 100.04,23.28 100.34,23.58 100.87,23.58 101.19,23.26 101.19,21.01 102.56,19.65 102.56,16.76 102.06,16.27 100.44,16.27 100.23,16.05 100.23,14.21 100.47,13.97 102.37,13.97 102.77,13.57 102.77,11.69 103.03,11.43 111.33,11.43 111.66,11.1 111.66,9.89 110.39,8.62 110.39,7.75 110.01,7.37 106.83,7.37 106.58,7.11 106.58,6.96 106.68,6.86 v2(107.09,6.86)
M_DDA08_P: length 99.1
  TOP w0.108: J63.G27 v2(105.82,6.86)
  TOP w0.193: U11.W4 v1(99.66,66.2)
  L05_SIG2 w0.102: 99.04,64.71 99.04,64.73 99.06,64.76 99.06,65.6 v1(99.66,66.2)
  L05_SIG2 w0.105: v2(105.82,6.86) 106.22,6.86 106.32,6.96 106.32,7.22 106.73,7.62 109.9,7.62 110.13,7.85 110.13,8.73 111.4,10 111.4,10.99 111.22,11.18 102.92,11.18 102.51,11.58 102.51,13.46 102.26,13.72 100.37,13.72 99.97,14.11 99.97,16.16 100.34,16.52 101.96,16.52 102.3,16.86 102.3,19.55 100.94,20.91 100.94,23.15 100.76,23.32 100.44,23.32 100.3,23.18 100.3,20.67 101.66,19.31 101.66,17.4 101.4,17.13 100.8,17.13 100.5,17.43 100.5,18.87 99.14,20.23 99.14,23.72 96.97,25.89 96.97,30.09 95.8,31.26 95.8,32.16 96.97,33.33 96.97,51.43 96.29,52.12 95.61,52.12 95.17,52.56 95.17,54.86 96.52,56.21 96.52,56.95 97.41,57.84 97.41,58.83 96.66,59.57 96.66,62.66 97.47,63.48 97.95,63.48 99.04,64.56 99.04,64.71
M_DDA09_N: length 100.1
  TOP w0.102: U11.W1 99.16,63.37 99.31,63.22
  TOP w0.108: 99.31,63.22 99.31,62.48 99.96,61.83 100.4,61.83 100.77,61.47 100.77,60.03 101.22,59.58 101.22,57.62 100.7,57.11 100.7,56.7 100.54,56.54 100.15,56.54 99.99,56.38 99.99,56.16 100.15,56 100.49,56 100.7,55.79 100.7,55.01 100.49,54.8 v2(100.34,54.8) ; J63.D27 v2(105.82,11.94)
  L03_SIG1 w0.105: v2(105.82,11.94) 105.68,11.8 105.42,11.8 105.31,11.9 105.31,12.3 104.91,12.69 104.33,12.69 104.04,12.99 104.04,13.53 103.6,13.97 103.06,13.97 102.77,14.26 102.77,16.55 102.88,16.66 102.98,16.66 103.09,16.77 103.09,17.07 102.97,17.19 102.87,17.19 102.77,17.29 102.77,19.9 97.18,25.49 97.18,31.06 96.51,31.72 96.51,36.43 98.22,38.14 98.22,40.12 98.98,40.88 98.98,43.23 99.17,43.41 99.54,43.41 99.83,43.12 99.83,40.77 98.92,39.86 98.92,37.91 97.14,36.12 97.14,32.07 98.65,30.56 99.14,30.56 99.55,30.97 99.55,31.47 98.33,32.69 98.33,35.6 100.2,37.48 100.2,39.53 101,40.32 101,43.57 99.59,44.98 99.59,45.61 99.1,46.1 97.87,46.1 97.27,46.7 97.27,53.32 97.61,53.66 99.26,53.66 99.64,54.04 99.64,54.93 99.28,55.29 99.28,55.69 99.48,55.89 100.52,55.89 100.73,55.69 100.73,54.82 100.61,54.7 100.44,54.7 v2(100.34,54.8)
M_DDA09_P: length 100.1
  TOP w0.102: 99.64,63.32 99.64,64.22 U11.W2
  TOP w0.108: J63.D26 v2(104.55,11.94) ; 99.64,63.32 99.53,63.22 99.53,62.58 100.05,62.06 100.5,62.06 101,61.56 101,60.13 101.45,59.68 101.45,57.53 100.93,57.01 100.93,55.16 v2(101.29,54.8)
  L03_SIG1 w0.105: v2(101.29,54.8) 100.98,55.11 100.98,55.79 100.63,56.14 99.37,56.14 99.02,55.8 99.02,55.19 99.38,54.82 99.38,54.15 99.15,53.91 97.51,53.91 97.02,53.42 97.02,46.6 97.77,45.84 98.99,45.84 99.33,45.51 99.33,44.87 100.74,43.46 100.74,40.43 99.95,39.63 99.95,37.58 98.07,35.71 98.07,32.59 99.29,31.37 99.29,31.07 99.04,30.82 98.75,30.82 97.39,32.18 97.39,36.02 99.17,37.8 99.17,39.75 100.08,40.66 100.08,43.23 99.64,43.67 99.06,43.67 98.73,43.34 98.73,40.99 97.97,40.23 97.97,38.25 96.26,36.54 96.26,31.62 96.92,30.96 96.92,25.39 102.51,19.79 102.51,14.16 102.96,13.72 103.49,13.72 103.78,13.43 103.78,12.88 104.23,12.44 104.8,12.44 105.05,12.19 105.05,12.04 104.95,11.94 v2(104.55,11.94)
M_DDA10_N: length 100.1
  TOP w0.102: 100.35,63.17 100.16,63.36 U11.Y1
  TOP w0.108: v2(101.87,53.11) 102.04,53.11 102.25,53.32 102.25,55.21 102.06,55.41 101.72,55.41 101.56,55.57 101.56,55.79 101.72,55.95 102.09,55.95 102.25,56.11 102.25,59.93 101.52,60.67 101.52,61.52 100.35,62.69 100.35,63.17 ; J63.C27 v2(105.82,13.21)
  L03_SIG1 w0.105: v2(101.87,53.11) 101.95,53.03 102.11,53.03 102.21,53.13 102.21,53.77 102.04,53.94 101.26,53.94 100.97,53.65 100.97,52.48 100.47,51.99 98.25,51.99 98.15,51.88 98.15,51.49 98.28,51.36 99.1,51.36 99.41,51.05 99.41,50.62 99.02,50.23 98.29,50.23 98.15,50.08 98.15,47.17 98.34,46.97 99.04,46.97 99.22,47.15 100.03,47.15 100.67,46.51 100.67,46.05 100.47,45.85 100.47,45.32 101.95,43.85 101.95,39.98 101.11,39.15 101.11,37.03 99.26,35.17 99.26,33.01 100.21,32.05 100.94,32.05 101.34,31.64 101.34,31.42 101.55,31.21 101.85,31.21 102.29,31.65 103.84,31.65 104.34,31.15 104.34,27.85 103.93,27.44 103.31,27.44 102.94,27.82 102.94,29.69 102.73,29.9 102.25,29.9 102.1,29.75 102.1,23.9 101.76,23.56 101.27,23.56 100.91,23.92 100.91,29.86 100.7,30.07 100.19,30.07 99.57,29.45 98.91,29.45 98.68,29.69 98.26,29.69 98.05,29.48 98.05,27.8 98.26,27.59 99.89,27.59 100.25,27.23 100.25,26.72 99.89,26.36 98.95,26.36 98.74,26.15 98.74,25.86 98.95,25.65 99.81,25.65 100.24,25.22 100.24,23.71 104.04,19.91 104.04,17.64 104.14,17.53 104.24,17.53 104.4,17.37 104.4,17.1 104.23,16.93 104.14,16.93 104.04,16.82 104.04,14.26 104.33,13.96 104.86,13.96 105.31,13.51 105.31,13.16 105.43,13.04 105.65,13.04 v2(105.82,13.21)
M_DDA10_P: length 100.1
  TOP w0.102: 100.64,63.3 100.64,64.22 U11.Y2
  TOP w0.108: v2(102.81,53.11) 102.48,53.44 102.48,60.03 101.75,60.76 101.75,61.62 100.58,62.79 100.58,63.24 100.64,63.3 ; J63.C26 v2(104.55,13.21)
  L03_SIG1 w0.105: v2(104.55,13.21) 104.95,13.21 105.05,13.31 105.05,13.41 104.75,13.71 104.23,13.71 103.78,14.15 103.78,19.8 99.98,23.6 99.98,25.12 99.71,25.39 98.85,25.39 98.49,25.75 98.49,26.26 98.85,26.62 99.78,26.62 99.99,26.83 99.99,27.13 99.78,27.34 98.15,27.34 97.79,27.7 97.79,29.58 98.15,29.94 98.78,29.94 99.02,29.71 99.47,29.71 100.08,30.32 100.81,30.32 101.17,29.96 101.17,24.02 101.38,23.81 101.65,23.81 101.85,24.01 101.85,29.86 102.15,30.16 102.83,30.16 103.19,29.8 103.19,27.92 103.41,27.7 103.83,27.7 104.09,27.96 104.09,31.05 103.73,31.4 102.4,31.4 101.95,30.96 101.45,30.96 101.09,31.32 101.09,31.54 100.83,31.8 100.11,31.8 99,32.9 99,35.27 100.86,37.13 100.86,39.25 101.69,40.08 101.69,43.74 100.22,45.22 100.22,45.96 100.41,46.15 100.41,46.4 99.92,46.9 99.32,46.9 99.15,46.72 98.24,46.72 97.9,47.06 97.9,50.19 98.19,50.48 98.91,50.48 99.15,50.72 99.15,50.94 99,51.1 98.18,51.1 97.89,51.39 97.89,51.99 98.15,52.25 100.37,52.25 100.71,52.59 100.71,53.75 101.16,54.2 102.14,54.2 102.47,53.87 102.47,53.45 v2(102.81,53.11)
M_DDA11_N: length 99.1
  TOP w0.108: J63.H32 v2(112.17,5.59)
  TOP w0.193: U11.Y3 v1(100.66,65.2)
  L05_SIG2 w0.102: v1(100.66,65.2) 100.7,65.23 100.7,65.56 100.59,65.67 100.42,65.67 100.26,65.51 100.26,64.8 100.29,64.78 100.29,64.75
  L05_SIG2 w0.105: 100.29,64.75 100.29,63.48 100.57,63.2 102.33,63.2 102.68,62.85 102.68,62.14 102.32,61.78 99.05,61.78 98.6,61.32 98.6,57.09 99.72,55.96 99.72,53.76 100.19,53.3 100.19,50.81 100.96,50.04 100.96,38.71 99.03,36.79 99.03,33.65 99.23,33.46 99.86,33.46 100.04,33.64 100.04,36.57 101.61,38.15 101.61,39.41 102.07,39.87 102.94,39.87 103.4,39.41 103.4,38.03 101.73,36.35 101.73,32.9 101.05,32.21 99.44,32.21 98.99,31.77 98.99,30.59 99.47,30.11 99.98,30.11 100.67,29.42 100.67,26.31 103.22,23.76 103.22,21.76 104.35,20.63 104.35,17.31 105.31,16.36 105.31,14.26 105.6,13.97 109.76,13.97 111.04,12.69 112.05,12.69 113.58,11.15 113.58,9.24 112.93,8.58 112.93,6.43 112.59,6.09 111.98,6.09 111.66,5.77 111.66,5.69 111.76,5.59 v2(112.17,5.59)
M_DDA11_P: length 99.1
  TOP w0.108: J63.H31 v2(110.9,5.59)
  TOP w0.193: U11.Y4 v1(100.66,66.2)
  L05_SIG2 w0.102: 100.04,64.75 100.04,64.78 100.06,64.8 100.06,65.6 v1(100.66,66.2)
  L05_SIG2 w0.105: 100.04,64.75 100.04,63.38 100.46,62.95 102.23,62.95 102.43,62.74 102.43,62.24 102.22,62.03 98.95,62.03 98.34,61.42 98.34,56.98 99.47,55.86 99.47,53.66 99.93,53.19 99.93,50.71 100.71,49.94 100.71,38.82 98.78,36.89 98.78,33.55 99.12,33.21 99.96,33.21 100.29,33.54 100.29,36.47 101.87,38.04 101.87,39.31 102.18,39.62 102.83,39.62 103.15,39.3 103.15,38.14 101.47,36.46 101.47,33 100.94,32.47 99.34,32.47 98.74,31.87 98.74,30.49 99.36,29.86 99.88,29.86 100.42,29.32 100.42,26.2 102.96,23.66 102.96,21.66 104.1,20.53 104.1,17.21 105.05,16.25 105.05,14.16 105.49,13.72 109.65,13.72 110.94,12.43 111.94,12.43 113.33,11.05 113.33,9.34 112.67,8.69 112.67,6.54 112.48,6.34 111.87,6.34 111.4,5.87 111.4,5.69 111.3,5.59 v2(110.9,5.59)
M_DDA12_N: length 100.1
  TOP w0.102: U11.AA1 101.16,63.38 101.32,63.23
  TOP w0.108: 101.32,63.23 101.32,62.67 102.52,61.47 102.52,60.93 103.43,60.03 106.67,60.03 107.26,59.44 107.26,54.7 107.05,54.49 106.75,54.49 106.53,54.71 106.53,58.94 106.09,59.39 104.5,59.39 104.08,58.97 104.08,58.37 103.93,58.21 103.73,58.21 103.57,58.05 103.57,57.83 103.73,57.67 103.93,57.67 104.08,57.51 104.08,56.83 103.87,56.62 v2(103.7,56.62) ; J63.G31 v2(110.9,6.86)
  L03_SIG1 w0.105: v2(110.9,6.86) 110.89,6.86 110.89,6.97 110.79,7.08 110.49,7.08 110.38,6.97 110.38,6.56 110.6,6.35 112.43,6.35 112.67,6.59 112.67,9.28 112.57,9.39 112.46,9.39 112.32,9.53 112.32,9.68 112.47,9.83 112.57,9.83 112.67,9.93 112.67,10.88 110.9,12.66 109.84,12.66 108.78,13.72 106.76,13.72 106.32,14.15 106.32,16.29 105.96,16.65 105.96,20.8 104.84,21.92 104.84,22.37 105.36,22.9 105.36,23.42 104.87,23.91 104.87,26.19 106.19,27.52 108.43,27.52 108.72,27.8 108.72,28.24 108.42,28.53 107.03,28.53 106.46,29.1 106.46,31.33 104.64,33.15 102.44,33.15 101.78,33.81 101.78,35.48 102.36,36.07 103.3,36.07 104.52,37.29 104.52,38.46 103.44,39.54 103.44,42.28 104.17,43 104.17,43.8 102.33,45.64 102.33,47.31 100.33,49.31 100.33,50.88 101.71,52.26 102.81,52.26 103.39,52.84 103.39,53.71 103.09,54.01 103.09,55.4 103.44,55.75 103.94,55.75 104.04,55.85 104.04,56.6 103.94,56.71 103.79,56.71 v2(103.7,56.62)
M_DDA12_P: length 100.1
  TOP w0.102: U11.AA2 101.64,64.22 101.64,63.33 101.55,63.24
  TOP w0.108: 101.55,63.24 101.55,62.77 102.75,61.56 102.75,61.03 103.52,60.26 106.76,60.26 107.49,59.53 107.49,54.61 107.15,54.26 106.65,54.26 106.3,54.61 106.3,58.84 105.99,59.16 104.6,59.16 104.31,58.87 104.31,56.95 v2(104.64,56.62) ; J63.G30 v2(109.63,6.86)
  L03_SIG1 w0.105: v2(104.64,56.62) 104.3,56.27 104.3,55.75 104.04,55.49 103.54,55.49 103.34,55.29 103.34,54.12 103.64,53.81 103.64,52.74 102.91,52 101.81,52 100.59,50.78 100.59,49.41 102.58,47.42 102.58,45.75 104.42,43.91 104.42,42.89 103.7,42.17 103.7,39.65 104.78,38.57 104.78,37.18 103.41,35.81 102.47,35.81 102.03,35.38 102.03,33.92 102.54,33.41 104.74,33.41 106.71,31.44 106.71,29.21 107.14,28.79 108.53,28.79 108.97,28.34 108.97,27.7 108.53,27.26 106.3,27.26 105.12,26.08 105.12,24.02 105.61,23.52 105.61,22.79 105.09,22.27 105.09,22.03 106.22,20.9 106.22,16.75 106.58,16.39 106.58,14.25 106.86,13.97 108.89,13.97 109.95,12.91 111,12.91 112.93,10.99 112.93,6.49 112.53,6.1 110.39,6.1 v2(109.63,6.86)
M_DDA13_N: length 99.1
  TOP w0.108: J63.H35 v2(115.98,5.59)
  TOP w0.193: U11.AA3 v1(101.66,65.2)
  L05_SIG2 w0.102: v1(101.66,65.2) 101.7,65.23 101.7,65.56 101.59,65.67 101.42,65.67 101.26,65.51 101.26,64.66 101.29,64.63 101.29,64.61
  L05_SIG2 w0.105: v2(115.98,5.59) 115.57,5.59 115.47,5.69 115.47,9.09 114.23,10.33 114.23,11.41 112.93,12.71 112.93,13.52 112.48,13.97 111.79,13.97 111.66,14.1 111.66,14.87 111.29,15.24 106.74,15.24 106.58,15.4 106.58,16.63 105.31,17.9 105.31,20.93 104.78,21.46 104.78,23.9 101.74,26.93 101.74,30.91 102.83,32 103.3,32 104.58,33.28 104.58,39.75 103.59,40.74 103.59,48.46 103.25,48.8 102.8,48.8 102.46,48.45 102.46,41.03 102.25,40.83 102,40.83 101.83,40.99 101.83,48.72 103.24,50.13 103.24,51.65 102.76,52.13 101.89,52.13 101.29,52.73 101.29,53.44 102.15,54.3 102.15,55.31 99.75,57.71 99.75,60.11 99.99,60.34 103.14,60.34 103.6,60.79 103.6,63.6 103.05,64.15 101.58,64.15 101.29,64.45 101.29,64.61
M_DDA13_P: length 99.1
  TOP w0.108: J63.H34 v2(114.71,5.59)
  TOP w0.193: U11.AA4 v1(101.66,66.2)
  L05_SIG2 w0.102: 101.04,64.61 101.04,64.63 101.06,64.66 101.06,65.6 v1(101.66,66.2)
  L05_SIG2 w0.105: 101.04,64.61 101.04,64.34 101.48,63.9 102.94,63.9 103.34,63.5 103.34,60.9 103.04,60.6 99.89,60.6 99.5,60.21 99.5,57.6 101.89,55.21 101.89,54.4 101.03,53.54 101.03,52.63 101.78,51.88 102.65,51.88 102.99,51.54 102.99,50.23 101.58,48.82 101.58,40.89 101.9,40.57 102.35,40.57 102.71,40.93 102.71,48.35 102.91,48.55 103.14,48.55 103.34,48.35 103.34,40.64 104.33,39.65 104.33,33.39 103.19,32.25 102.72,32.25 101.49,31.02 101.49,26.83 104.52,23.79 104.52,21.36 105.05,20.83 105.05,17.8 106.32,16.52 106.32,15.29 106.63,14.99 111.18,14.99 111.4,14.76 111.4,14 111.69,13.72 112.38,13.72 112.67,13.42 112.67,12.61 113.97,11.31 113.97,10.22 115.21,8.98 115.21,5.69 115.11,5.59 v2(114.71,5.59)
M_DDA14_N: length 100.1
  TOP w0.102: U11.AB1 102.16,63.38 102.32,63.23
  TOP w0.108: J63.G34 v2(114.71,6.86) ; v2(103.96,54.83) 104.33,55.2 104.33,55.7 104.62,56 105.29,56 105.68,55.6 105.68,53.49 106.44,52.74 108.12,52.74 109.13,53.75 109.13,57.35 108.98,57.51 108.72,57.51 108.56,57.66 108.56,57.89 108.72,58.05 108.98,58.05 109.13,58.2 109.13,60.43 108.64,60.92 103.91,60.92 102.32,62.51 102.32,63.23
  L03_SIG1 w0.105: v2(103.96,54.83) 104.2,54.83 104.3,54.72 104.3,52.32 104.18,52.2 104.06,52.2 103.91,52.05 103.91,51.83 104.06,51.68 104.2,51.68 104.3,51.57 104.3,46.36 106.25,44.42 106.25,42.2 105.21,41.16 105.21,40.3 106.67,38.85 108.85,38.85 109.14,38.56 109.14,38.1 108.75,37.71 107.92,37.71 107.58,37.37 107.58,36.7 107.92,36.35 109.05,36.35 109.79,35.61 109.79,34.54 108.34,33.09 108.34,31.43 109.49,30.28 111.32,30.28 112.12,29.48 112.12,26.17 111.69,25.74 107.61,25.74 107.08,25.21 107.08,24.25 107.69,23.65 109.4,23.65 109.72,23.33 109.72,22.29 109.47,22.04 108.91,22.04 108.48,21.6 108.48,20.34 111.4,17.41 111.4,14.1 111.79,13.72 112.41,13.72 112.67,13.45 112.67,12.84 116.48,9.03 116.48,6.62 116.22,6.35 114.29,6.35 114.17,6.47 114.17,6.97 114.28,7.07 114.57,7.07 114.71,6.93 v2(114.71,6.86)
M_DDA14_P: length 100.1
  TOP w0.102: 102.55,63.24 102.64,63.33 102.64,64.22 U11.AB2
  TOP w0.108: 102.55,63.24 102.55,62.6 104,61.15 108.74,61.15 109.36,60.52 109.36,53.66 108.21,52.51 106.35,52.51 105.46,53.4 105.46,55.5 105.19,55.77 104.72,55.77 104.56,55.61 104.56,55.17 v2(104.9,54.83) ; J63.G33 v2(113.44,6.86)
  L03_SIG1 w0.105: v2(113.44,6.86) 113.93,6.36 113.93,6.35 114.19,6.1 116.32,6.1 116.74,6.51 116.74,9.13 112.93,12.94 112.93,13.55 112.51,13.97 111.89,13.97 111.66,14.2 111.66,17.51 108.73,20.44 108.73,21.49 109.02,21.78 109.58,21.78 109.98,22.18 109.98,23.43 109.5,23.9 107.79,23.9 107.34,24.36 107.34,25.1 107.72,25.48 111.79,25.48 112.37,26.06 112.37,29.58 111.43,30.53 109.59,30.53 108.59,31.53 108.59,32.98 110.04,34.43 110.04,35.72 109.16,36.61 108.03,36.61 107.83,36.8 107.83,37.26 108.03,37.46 108.85,37.46 109.39,38 109.39,38.66 108.95,39.1 106.77,39.1 105.46,40.41 105.46,41.06 106.51,42.1 106.51,44.52 104.56,46.47 104.56,54.48 v2(104.9,54.83)
M_DDA15_N: length 99.1
  TOP w0.102: U11.AC1 103.16,63.38 103.31,63.23
  TOP w0.108: v2(104.16,61.65) 104.52,62.01 104.52,62.21 104.3,62.43 103.65,62.43 103.31,62.76 103.31,63.23 ; J63.H38 v2(119.79,5.59)
  L05_SIG2 w0.105: v2(119.79,5.59) 119.56,5.82 119.29,5.82 119.15,5.67 119.15,5.32 119.27,5.19 119.27,5.19 119.38,5.09 120.13,5.09 120.29,5.24 120.29,7.78 116.89,11.18 115.66,11.18 114.58,12.26 114.58,13.52 113.94,14.16 113.94,14.79 113.75,14.99 113.12,14.99 112.65,15.45 112.65,16.94 111.98,17.6 107.74,17.6 107.28,18.06 107.28,18.68 107.68,19.08 111.45,19.08 111.69,19.32 111.69,19.66 111.46,19.9 108.12,19.9 107.25,20.76 107.25,23.7 103.62,27.33 103.62,28.54 104.3,29.23 105.36,29.23 111.08,34.96 111.08,38.66 110.09,39.65 110.09,40.51 105.1,45.5 105.1,53.72 105.51,54.13 105.51,55.63 105.4,55.73 105.22,55.73 105.09,55.86 105.09,56.06 105.22,56.19 105.4,56.19 105.51,56.29 105.51,57.46 106.53,58.49 106.53,60.58 106.32,60.79 105.93,60.79 105.73,60.6 105.73,58.71 104.67,57.65 103.5,57.65 103.11,58.04 103.11,58.62 103.5,59.01 104.26,59.01 104.51,59.26 104.51,59.94 104.4,60.04 104.22,60.04 104.07,60.19 104.07,60.41 104.22,60.56 104.4,60.56 104.51,60.67 104.51,61.58 104.4,61.69 104.2,61.69 v2(104.16,61.65)
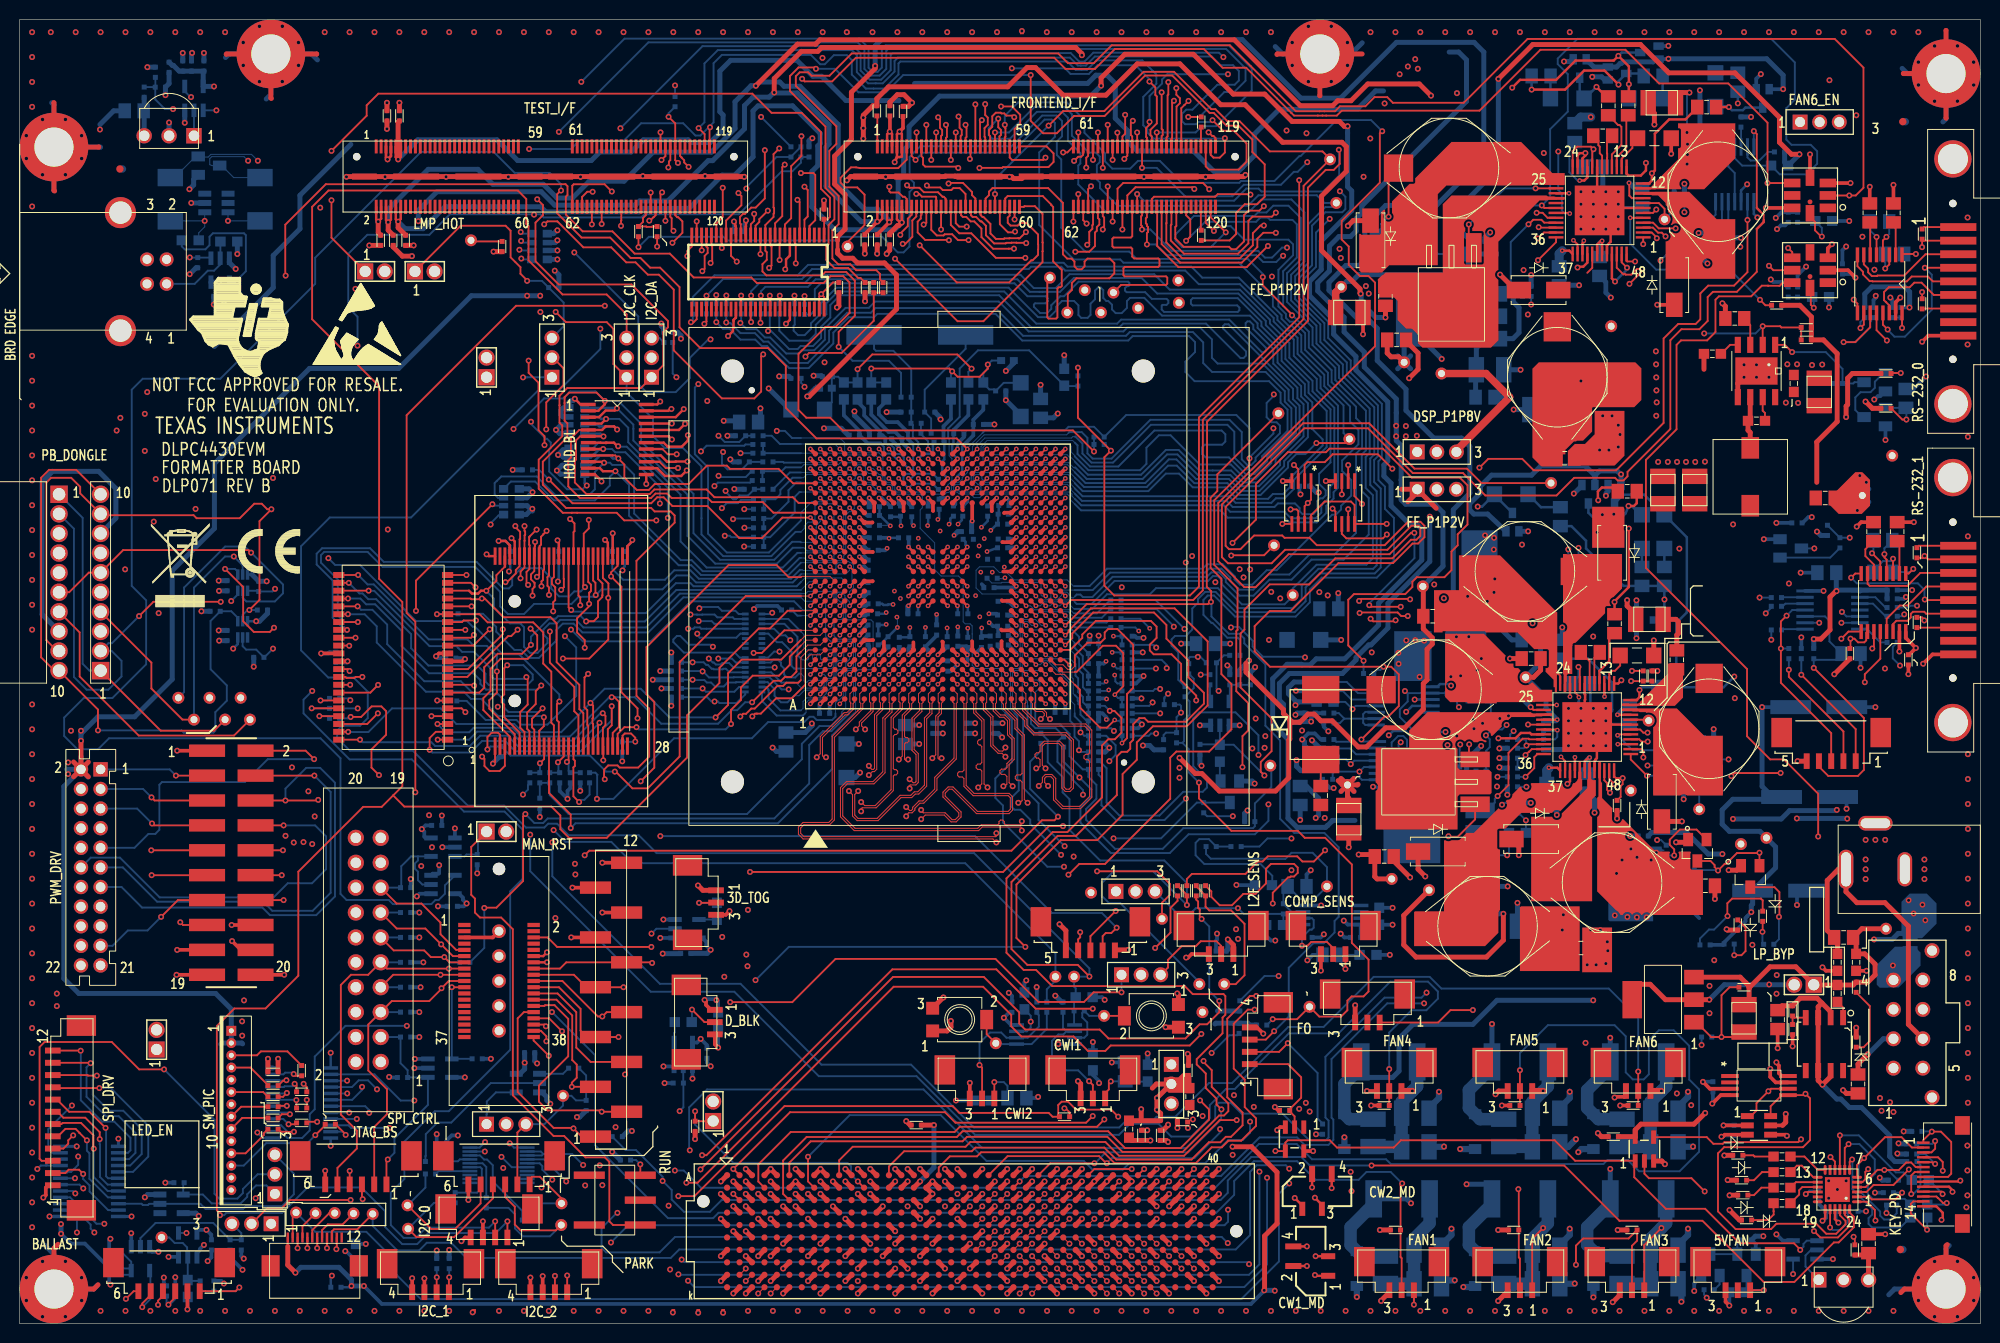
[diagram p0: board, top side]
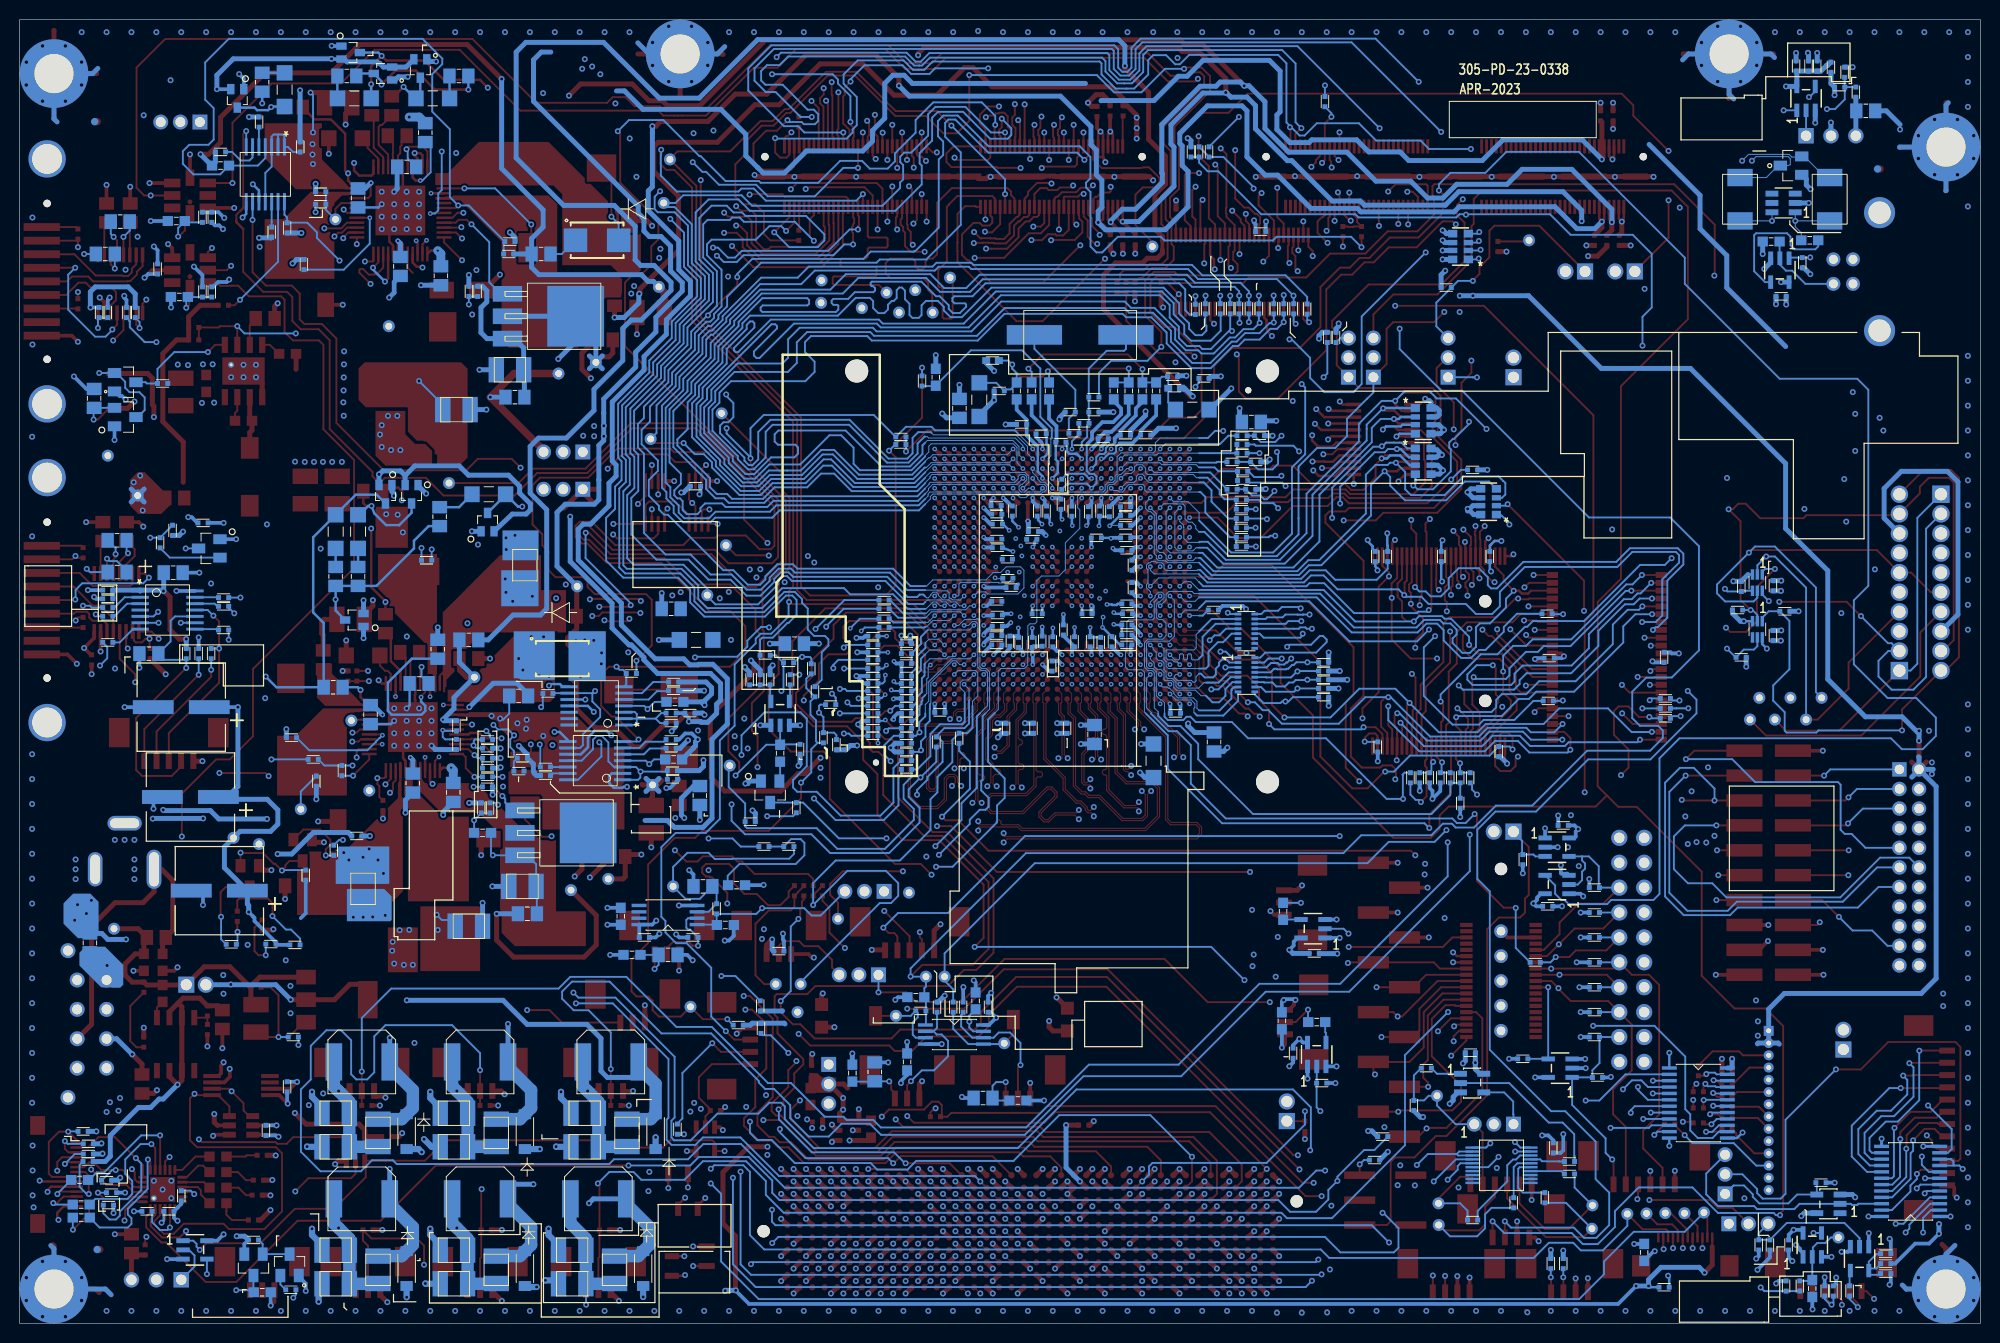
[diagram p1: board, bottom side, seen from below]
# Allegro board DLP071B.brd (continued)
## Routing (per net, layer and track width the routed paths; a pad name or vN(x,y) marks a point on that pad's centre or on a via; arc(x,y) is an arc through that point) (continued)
M_DDA15_P: length 99.1
  TOP w0.102: U11.AC2 103.64,64.22 103.64,63.37 103.55,63.28
  TOP w0.108: v2(105.11,61.65) 105,61.65 104.75,61.91 104.75,62.3 104.4,62.65 103.74,62.65 103.55,62.85 103.55,63.28 ; J63.H37 v2(118.52,5.59)
  L05_SIG2 w0.105: v2(105.11,61.65) 104.76,61.3 104.76,59.15 104.36,58.76 103.61,58.76 103.37,58.51 103.37,58.14 103.61,57.9 104.56,57.9 105.48,58.81 105.48,60.7 105.82,61.05 106.42,61.05 106.79,60.68 106.79,58.38 105.76,57.35 105.76,54.02 105.35,53.62 105.35,45.61 110.35,40.61 110.35,39.75 111.34,38.76 111.34,34.85 105.46,28.97 104.41,28.97 103.87,28.44 103.87,27.44 107.5,23.81 107.5,20.87 108.22,20.15 111.56,20.15 111.95,19.77 111.95,19.22 111.56,18.83 107.78,18.83 107.54,18.58 107.54,18.16 107.84,17.86 112.07,17.86 112.91,17.03 112.91,15.56 113.22,15.24 113.85,15.24 114.2,14.89 114.2,14.26 114.83,13.63 114.83,12.36 115.76,11.43 117,11.43 120.55,7.88 120.55,5.14 120.24,4.83 119.27,4.83 119.02,5.08 119.02,5.09 v2(118.52,5.59)
M_DDB00_N: length 96.8
  TOP w0.102: U11.N2 92.69,64.23 92.69,63.41 92.83,63.27 92.83,63.27
  TOP w0.108: v2(85.53,54.31) 85.18,53.96 85.18,51.85 85.52,51.52 87.46,51.52 89.81,53.87 90.9,53.87 91.26,54.23 91.62,54.23 92.29,54.9 92.29,61.77 92.83,62.31 92.83,63.27 ; J63.K26 v2(103.28,3.05)
  L03_SIG1 w0.105: v2(85.53,54.31) 85.2,53.97 85.2,53.77 83.22,51.79 83.22,50.87 81.94,49.59 81.94,23.86 81.44,23.36 80.46,23.36 79.95,22.85 79.95,19.14 81.18,17.91 81.18,10.18 83.07,8.28 83.07,6.74 84.74,5.08 86.11,5.08 87.38,3.81 93.68,3.81 94.53,2.96 96.41,2.96 97.26,3.81 102.42,3.81 102.79,3.44 102.79,3.15 102.89,3.05 v2(103.28,3.05)
M_DDB00_P: length 96.8
  TOP w0.102: U11.N1 93.16,63.37 93.06,63.27
  TOP w0.108: 93.06,63.27 93.06,62.21 92.52,61.67 92.52,54.81 91.71,54 91.36,54 90.99,53.64 89.91,53.64 87.56,51.29 85.42,51.29 84.96,51.76 84.96,53.94 v2(84.59,54.31) ; J63.K25 v2(102.01,3.05)
  L03_SIG1 w0.105: v2(84.59,54.31) 84.65,54.37 84.84,54.37 84.95,54.26 84.95,53.87 82.97,51.9 82.97,50.97 81.69,49.69 81.69,23.96 81.34,23.61 80.35,23.61 79.69,22.95 79.69,19.03 80.92,17.8 80.92,10.07 82.82,8.18 82.82,6.64 84.63,4.83 86,4.83 87.27,3.56 93.57,3.56 94.43,2.7 96.51,2.7 97.37,3.56 102.31,3.56 102.53,3.33 102.53,3.06 102.38,2.91 102.15,2.91 v2(102.01,3.05)
M_DDB01_N: length 96.8
  TOP w0.108: J63.J25 v2(103.28,5.59) ; U11.N4 v1(92.66,66.2)
  L03_SIG1 w0.102: 92.04,64.59 92.04,64.61 92.06,64.64 92.06,65.53 92.33,65.8 92.69,65.8 92.79,65.9 92.79,66.07 v1(92.66,66.2)
  L03_SIG1 w0.105: 92.04,64.59 92.04,64.2 93.19,63.06 98.37,63.06 98.98,62.45 98.98,58.75 98.12,57.89 96,57.89 95.2,58.69 92.55,58.69 92.04,58.18 92.04,57.21 94.26,54.99 94.26,46.79 92.33,44.86 92.33,42.16 93.08,41.41 93.08,40.09 92.34,39.35 92.34,38.08 93.49,36.93 93.49,35.13 92.33,33.98 92.33,22.85 93.29,21.89 95.06,21.89 98.7,18.24 98.7,12.75 99.01,12.45 102.22,12.45 102.51,12.15 102.51,11.62 102.96,11.18 103.51,11.18 103.78,10.9 103.78,10.19 104.07,9.91 107.06,9.91 107.59,9.37 107.59,5.28 107.4,5.08 102.85,5.08 102.74,5.19 102.74,5.51 102.82,5.59 v2(103.28,5.59)
M_DDB01_P: length 96.8
  TOP w0.108: J63.J24 v2(102.01,5.59) ; U11.N3 v1(92.66,65.2)
  L03_SIG1 w0.102: v1(92.66,65.2) 92.66,65.5 92.56,65.6 92.42,65.6 92.27,65.45 92.27,64.64 92.29,64.61 92.29,64.59
  L03_SIG1 w0.105: v2(102.01,5.59) 102.77,4.83 107.5,4.83 107.85,5.17 107.85,9.47 107.16,10.16 104.17,10.16 104.04,10.29 104.04,11.01 103.61,11.43 103.06,11.43 102.77,11.72 102.77,12.26 102.33,12.7 99.12,12.7 98.96,12.86 98.96,18.35 95.16,22.14 93.4,22.14 92.59,22.96 92.59,33.87 93.74,35.03 93.74,37.03 92.59,38.18 92.59,39.24 93.33,39.99 93.33,41.52 92.59,42.27 92.59,44.76 94.52,46.69 94.52,55.1 92.29,57.32 92.29,58.07 92.66,58.44 95.09,58.44 95.89,57.64 98.22,57.64 99.24,58.65 99.24,62.56 98.48,63.31 93.29,63.31 92.29,64.31 92.29,64.59
M_DDB02_N: length 96.8
  TOP w0.102: U11.M1 92.16,63.37 92.03,63.24
  TOP w0.108: J63.F23 v2(100.74,9.4) ; 92.03,63.24 92.03,62.43 91.24,61.64 91.24,58.55 91.66,58.13 91.66,55.17 91.42,54.92 90.84,54.92 90.71,54.79 90.71,54.64 v2(90.78,54.57)
  L03_SIG1 w0.105: v2(90.78,54.57) 90.78,54.8 90.89,54.9 91.23,54.9 91.71,54.42 91.71,53.48 91.05,52.81 91.05,50.13 87.8,46.88 87.8,31.35 88.08,31.06 88.66,31.06 88.94,31.34 88.94,43.08 89.12,43.26 89.4,43.26 89.57,43.09 89.57,17.1 88.36,15.88 88.36,12.76 89.94,11.18 93.67,11.18 96.21,8.64 99.89,8.64 100.23,8.98 100.23,9.29 100.33,9.4 v2(100.74,9.4)
M_DDB02_P: length 96.8
  TOP w0.102: 91.8,63.24 91.8,63.25 91.69,63.36 91.69,64.22 U11.M2
  TOP w0.108: v2(90.78,55.51) 91.14,55.15 91.32,55.15 91.43,55.26 91.43,58.03 91.02,58.45 91.02,61.73 91.8,62.52 91.8,63.24 ; J63.F22 v2(99.47,9.4)
  L03_SIG1 w0.105: v2(99.47,9.4) 99.87,9.4 99.97,9.29 99.97,9.08 99.78,8.89 96.31,8.89 93.77,11.43 90.05,11.43 88.61,12.86 88.61,15.78 89.82,16.99 89.82,43.19 89.5,43.52 89.02,43.52 88.68,43.18 88.68,31.44 88.56,31.32 88.19,31.32 88.05,31.45 88.05,46.78 91.3,50.03 91.3,52.71 91.97,53.37 91.97,54.53 91.34,55.16 91.14,55.16 v2(90.78,55.51)
M_DDB03_N: length 95.8
  TOP w0.108: U11.M4 v1(91.66,66.2) ; J63.E22 v2(99.47,10.67)
  L05_SIG2 w0.102: 92.29,64.67 92.29,64.7 92.26,64.72 92.26,65.6 v1(91.66,66.2)
  L05_SIG2 w0.105: v2(99.47,10.67) 99.06,10.67 98.96,10.77 98.96,11.09 98.63,11.42 96.66,11.42 96.42,11.66 96.42,16.34 95.89,16.87 95.13,16.87 94.8,17.2 94.8,20.12 93.22,21.7 93.22,25.46 92.61,26.08 91.22,26.08 90.7,26.6 90.7,49.39 90.9,49.59 91.28,49.59 91.5,49.38 91.5,34.77 91.86,34.41 92.43,34.41 92.78,34.77 92.78,56.64 92.4,57.02 92.4,58.42 92.61,58.62 92.61,61.79 92.29,62.11 92.29,64.67
M_DDB03_P: length 95.8
  TOP w0.108: U11.M3 v1(91.66,65.2) ; J63.E21 v2(98.2,10.67)
  L05_SIG2 w0.102: 92.03,64.67 92.03,64.7 92.06,64.72 92.06,65.52 91.98,65.6 91.67,65.6 91.55,65.48 91.55,65.31 v1(91.66,65.2)
  L05_SIG2 w0.105: 92.03,64.67 92.03,62.01 92.35,61.69 92.35,58.73 92.15,58.52 92.15,56.92 92.53,56.53 92.53,34.88 92.32,34.67 91.96,34.67 91.75,34.87 91.75,49.48 91.39,49.84 90.79,49.84 90.45,49.5 90.45,26.5 91.12,25.82 92.5,25.82 92.97,25.36 92.97,21.59 94.54,20.02 94.54,17.09 95.02,16.61 95.79,16.61 96.16,16.24 96.16,11.56 96.56,11.16 98.52,11.16 98.7,10.98 98.7,10.77 98.6,10.67 v2(98.2,10.67)
M_DDB04_N: length 96.8
  TOP w0.102: U11.L2 90.69,64.22 90.69,63.32 90.78,63.23
  TOP w0.108: v2(89.68,57.52) 90.03,57.87 90.03,62.05 90.78,62.8 90.78,63.23 ; J63.F26 v2(104.55,9.4)
  L03_SIG1 w0.105: v2(89.68,57.52) 90.07,57.14 90.07,56.81 90.69,56.2 91.81,56.2 92.61,55.4 92.61,52.75 93.38,51.97 93.38,49.74 92.06,48.42 92.06,47.83 92.37,47.52 93.15,47.52 93.33,47.34 93.33,47.13 91.46,45.25 91.46,41.79 92.17,41.08 92.17,40.6 91.45,39.89 91.45,37.63 92.51,36.57 92.51,35.51 91.46,34.45 91.46,21.92 92.36,21.01 93.77,21.01 94.16,20.63 94.16,19.63 94.69,19.1 96.53,19.1 96.74,18.89 96.74,18.59 96.6,18.45 92.36,18.45 92,18.09 92,17.59 92.31,17.28 97.67,17.28 97.82,17.13 97.82,16.79 97.61,16.58 91.58,16.58 91.08,16.09 91.08,14.08 91.45,13.72 97.22,13.72 97.43,13.5 97.43,11.59 97.85,11.18 102.23,11.18 102.51,10.9 102.51,9.08 102.95,8.65 103.79,8.65 v2(104.55,9.4)
M_DDB04_P: length 96.8
  TOP w0.102: U11.L1 91.16,63.39 90.99,63.21 90.99,62.69 90.96,62.66
  TOP w0.108: J63.F25 v2(103.28,9.4) ; 90.96,62.66 90.26,61.96 90.26,59.87 90.37,59.77 90.54,59.77 90.7,59.61 90.7,59.38 90.55,59.23 90.37,59.23 90.26,59.12 90.26,57.55 90.37,57.45 90.55,57.45 v2(90.63,57.52)
  L03_SIG1 w0.105: v2(90.63,57.52) 90.58,57.57 90.43,57.57 90.33,57.47 90.33,56.91 90.79,56.45 91.91,56.45 92.86,55.5 92.86,54.64 93.01,54.48 93.15,54.48 93.31,54.33 93.31,54.11 93.15,53.96 93.01,53.96 92.86,53.8 92.86,52.85 93.64,52.08 93.64,49.63 92.32,48.31 92.32,47.94 92.48,47.78 93.26,47.78 93.59,47.45 93.59,47.02 91.71,45.14 91.71,41.89 92.42,41.18 92.42,40.5 91.71,39.78 91.71,37.74 92.76,36.68 92.76,35.4 91.71,34.35 91.71,22.03 92.47,21.27 93.88,21.27 94.41,20.73 94.41,19.73 94.8,19.35 96.64,19.35 96.99,18.99 96.99,18.48 96.7,18.19 92.47,18.19 92.26,17.98 92.26,17.69 92.42,17.53 97.78,17.53 98.07,17.24 98.07,16.69 97.71,16.33 91.69,16.33 91.34,15.98 91.34,14.19 91.56,13.97 97.32,13.97 97.69,13.6 97.69,11.7 97.96,11.43 102.34,11.43 102.77,11 102.77,9.18 103.05,8.9 103.69,8.9 103.84,9.05 103.84,9.38 103.66,9.55 103.43,9.55 v2(103.28,9.4)
M_DDB05_N: length 95.8
  TOP w0.108: U11.L4 v1(90.66,66.2) ; J63.E25 v2(103.28,10.67)
  L05_SIG2 w0.102: v1(90.66,66.2) 90.06,65.6 90.06,64.78 90.03,64.75 90.03,64.73
  L05_SIG2 w0.105: v2(103.28,10.67) 102.51,9.91 95.34,9.91 94.89,10.35 94.89,12.57 93.62,13.84 93.62,18.1 93.32,18.41 92.7,18.41 92.42,18.13 92.42,16.79 92.05,16.42 91.29,16.42 90.94,16.76 90.94,18.42 91.97,19.45 91.97,24.63 91.76,24.84 91.46,24.84 91.25,24.63 91.25,19.76 90.78,19.28 89.97,19.28 89.55,19.7 89.55,47.04 89.34,47.25 88.91,47.25 88.66,47 88.66,44.73 88.3,44.38 87.67,44.38 87.3,44.74 87.3,47.76 91.03,51.49 91.03,52.96 91.44,53.37 91.44,56.03 91.25,56.22 91.25,57.79 90.03,59 90.03,64.73
M_DDB05_P: length 95.8
  TOP w0.108: J63.E24 v2(102.01,10.67) ; U11.L3 v1(90.66,65.2)
  L05_SIG2 w0.102: v1(90.66,65.2) 90.77,65.2 90.87,65.3 90.87,65.54 90.71,65.7 90.45,65.7 90.26,65.51 90.26,64.78 90.29,64.75 90.29,64.73
  L05_SIG2 w0.105: 90.29,64.73 90.29,59.11 91.5,57.89 91.5,56.33 91.69,56.13 91.69,53.26 91.29,52.85 91.29,51.38 87.56,47.66 87.56,44.85 87.78,44.63 88.19,44.63 88.4,44.84 88.4,47.11 88.8,47.51 89.45,47.51 89.8,47.15 89.8,19.81 90.07,19.54 90.68,19.54 91,19.86 91,24.74 91.36,25.1 91.87,25.1 92.22,24.74 92.22,19.34 91.2,18.32 91.2,16.87 91.39,16.68 91.94,16.68 92.17,16.9 92.17,18.24 92.59,18.66 93.42,18.66 93.88,18.21 93.88,13.94 95.15,12.67 95.15,10.45 95.44,10.16 102.41,10.16 102.64,10.39 102.64,10.56 102.4,10.8 102.14,10.8 v2(102.01,10.67)
M_DDB06_N: length 96.8
  TOP w0.102: U11.K2 89.69,64.22 89.69,63.42
  TOP w0.108: v2(85.84,53.18) 86.2,52.82 87.27,52.82 88.89,54.44 88.89,61.83 89.81,62.75 89.81,63.3 89.69,63.42 ; J63.K29 v2(107.09,4.32)
  L03_SIG1 w0.105: v2(85.84,53.18) 85.51,52.85 85.2,52.85 84.09,51.73 84.09,50.42 82.59,48.91 82.59,20.25 82.38,20.04 82.03,20.04 81.8,20.27 81.8,22.35 81.44,22.71 80.94,22.71 80.58,22.35 80.58,19.75 82.19,18.14 82.19,9.84 87.21,4.83 92.64,4.83 93.28,4.18 94,4.18 94.69,3.49 96.18,3.49 96.88,4.18 99.71,4.18 100.36,4.83 101.15,4.83 101.77,4.21 103.09,4.21 103.74,3.56 106.3,3.56 107.06,4.32 v2(107.09,4.32)
M_DDB06_P: length 96.8
  TOP w0.102: U11.K1 90.16,63.39 90.04,63.27
  TOP w0.108: 90.04,63.27 90.04,62.65 89.12,61.73 89.12,60.77 89.28,60.61 89.43,60.61 89.59,60.45 89.59,60.23 89.43,60.07 89.28,60.07 89.12,59.91 89.12,56.6 89.23,56.49 89.4,56.49 89.56,56.33 89.56,56.11 89.4,55.95 89.23,55.95 89.12,55.84 89.12,54.35 87.36,52.59 85.95,52.59 85.8,52.45 85.8,52.27 v2(85.84,52.24) ; J63.K28 v2(105.82,4.32)
  L03_SIG1 w0.105: v2(85.84,52.24) 85.86,52.26 85.86,52.49 85.76,52.6 85.31,52.6 84.34,51.63 84.34,50.31 82.84,48.81 82.84,20.14 82.48,19.79 81.92,19.79 81.55,20.16 81.55,22.25 81.34,22.46 81.04,22.46 80.83,22.25 80.83,19.86 82.45,18.24 82.45,9.94 87.31,5.08 92.74,5.08 93.39,4.43 94.1,4.43 94.79,3.74 96.08,3.74 96.77,4.43 99.61,4.43 100.25,5.08 101.25,5.08 101.87,4.46 103.19,4.46 103.84,3.81 106.19,3.81 106.39,4 106.39,4.34 106.24,4.49 105.92,4.49 105.82,4.38 v2(105.82,4.32)
M_DDB07_N: length 96.8
  TOP w0.108: J63.J28 v2(105.82,5.59) ; U11.K4 v1(89.66,66.2)
  L03_SIG1 w0.102: 90.29,64.73 90.29,64.75 90.27,64.78 90.27,65.53 89.99,65.8 89.76,65.8 89.66,65.9 v1(89.66,66.2)
  L03_SIG1 w0.105: v2(105.82,5.59) 105.31,6.1 105.31,7.19 104.88,7.62 99.15,7.62 98.42,6.9 95.8,6.9 93.8,8.89 88.88,8.89 86.26,11.51 86.26,47.79 88.56,50.09 88.56,57.23 90.91,59.59 92.77,59.59 92.95,59.41 95.58,59.41 96.16,58.83 97.95,58.83 98.5,59.38 98.5,61.7 97.79,62.41 92.37,62.41 90.29,64.49 90.29,64.73
M_DDB07_P: length 96.8
  TOP w0.108: U11.K3 v1(89.66,65.2) ; J63.J27 v2(104.55,5.59)
  L03_SIG1 w0.102: 90.04,64.73 90.04,64.75 90.06,64.78 90.06,65.44 89.91,65.6 89.66,65.6 89.53,65.46 89.53,65.3 89.63,65.2 v1(89.66,65.2)
  L03_SIG1 w0.105: v2(104.55,5.59) 104.82,5.59 105.05,5.82 105.05,7.08 104.77,7.37 99.25,7.37 98.53,6.64 95.69,6.64 93.7,8.64 88.77,8.64 86,11.4 86,47.9 88.3,50.2 88.3,57.33 90.81,59.84 92.87,59.84 93.05,59.66 95.69,59.66 96.26,59.09 97.84,59.09 98.24,59.49 98.24,61.59 97.68,62.15 92.27,62.15 90.04,64.38 90.04,64.73
M_DDB08_N: length 95.8
  TOP w0.102: U11.H2 87.7,64.23 87.7,63.41 87.8,63.31
  TOP w0.108: v2(86.62,56.87) 86.62,56.82 86.92,56.52 87.09,56.52 87.2,56.62 87.2,62.09 87.8,62.69 87.8,63.31 ; J63.F29 v2(108.36,8.13)
  L05_SIG2 w0.105: v2(108.36,8.13) 107.6,8.88 106.75,8.88 105.05,7.18 105.05,6.61 104.79,6.35 93.88,6.35 89.48,10.75 88.14,10.75 87.53,11.37 87.53,16.92 86.8,17.65 86.8,28.61 86.44,28.96 85.93,28.96 85.58,28.61 85.58,23.28 85.34,23.05 84.94,23.05 84.74,23.25 84.74,49.97 86.68,51.91 86.68,54.55 87.71,55.58 87.71,56.2 87.33,56.58 86.92,56.58 v2(86.62,56.87)
M_DDB08_P: length 95.8
  TOP w0.102: U11.H1 88.16,63.38 88.03,63.25
  TOP w0.108: v2(86.62,55.93) 86.98,56.29 87.19,56.29 87.43,56.53 87.43,62 88.03,62.6 88.03,63.25 ; J63.F28 v2(107.09,8.13)
  L05_SIG2 w0.105: v2(107.09,8.13) 107.09,8.03 107.19,7.92 107.48,7.92 107.59,8.03 107.59,8.49 107.46,8.63 106.86,8.63 105.31,7.08 105.31,6.51 104.9,6.1 99,6.1 98.9,5.99 98.9,5.88 98.73,5.72 98.4,5.72 98.24,5.88 98.24,5.99 98.14,6.1 93.77,6.1 89.37,10.5 88.04,10.5 87.27,11.26 87.27,16.81 86.55,17.54 86.55,28.5 86.34,28.71 86.04,28.71 85.83,28.5 85.83,23.17 85.45,22.79 84.84,22.79 84.48,23.15 84.48,50.07 86.43,52.01 86.43,54.65 87.46,55.68 87.46,56.09 87.23,56.32 86.72,56.32 86.58,56.18 86.58,55.97 v2(86.62,55.93)
M_DDB09_N: length 95.8
  TOP w0.108: U11.H4 v1(87.66,66.2) ; J63.E28 v2(107.09,10.67)
  L05_SIG2 w0.102: 87.03,64.56 87.03,64.58 87.06,64.61 87.06,65.6 v1(87.66,66.2)
  L05_SIG2 w0.105: v2(107.09,10.67) 106.58,10.17 106.58,10.16 106.33,9.91 104.25,9.91 104.04,9.69 104.04,9.08 103.59,8.64 95.2,8.64 93.62,10.21 93.62,10.99 91.99,12.62 91.25,12.62 89.81,14.06 89.81,17.45 88.57,18.69 88.57,43.26 88.37,43.46 87.93,43.46 87.67,43.21 87.67,35.74 87.32,35.39 86.69,35.39 86.3,35.78 86.3,48.88 89.56,52.15 89.56,56.46 88.84,57.17 88.84,62.18 87.03,63.99 87.03,64.56
M_DDB09_P: length 95.8
  TOP w0.108: U11.H3 v1(87.66,65.2) ; J63.E27 v2(105.82,10.67)
  L05_SIG2 w0.102: v1(87.66,65.2) 87.76,65.2 87.86,65.3 87.86,65.55 87.72,65.69 87.44,65.69 87.26,65.51 87.26,64.61 87.29,64.58 87.29,64.56
  L05_SIG2 w0.105: 87.29,64.56 87.29,64.1 89.1,62.29 89.1,57.28 89.81,56.56 89.81,52.04 86.55,48.78 86.55,35.88 86.79,35.64 87.22,35.64 87.42,35.84 87.42,43.32 87.82,43.72 88.47,43.72 88.83,43.36 88.83,18.79 90.07,17.55 90.07,14.16 91.36,12.87 92.1,12.87 93.88,11.09 93.88,10.32 95.31,8.89 103.49,8.89 103.78,9.19 103.78,9.8 104.15,10.16 106.22,10.16 106.33,10.26 106.33,10.67 106.11,10.89 105.92,10.89 105.82,10.78 v2(105.82,10.67)
M_DDB10_N: length 95.8
  TOP w0.102: 86.82,63.28 86.69,63.42 86.69,64.22 U11.G2
  TOP w0.108: v2(85.29,60.6) 85.65,60.95 85.65,61.34 86.82,62.51 86.82,63.28 ; J63.K32 v2(112.17,3.05)
  L05_SIG2 w0.105: v2(85.29,60.6) 85.49,60.6 85.61,60.72 85.61,61.06 85.41,61.26 84.58,61.26 84.18,60.86 84.18,58.21 82.79,56.83 82.79,17.31 82.96,17.15 83.24,17.15 83.43,17.33 83.43,18.34 83.77,18.68 84.23,18.68 84.56,18.35 84.56,16.8 83.72,15.96 83.72,10.06 89.96,3.81 111.32,3.81 111.64,3.5 111.64,3.12 111.7,3.05 v2(112.17,3.05)
M_DDB10_P: length 95.8
  TOP w0.102: U11.G1 87.16,63.38 87.05,63.27
  TOP w0.108: J63.K31 v2(110.9,3.05) ; v2(86.24,60.6) 85.88,60.95 85.88,61.25 87.05,62.42 87.05,63.27
  L05_SIG2 w0.105: v2(110.9,3.05) 110.9,2.99 111.02,2.87 111.27,2.87 111.38,2.98 111.38,3.39 111.22,3.56 89.86,3.56 83.46,9.95 83.46,16.06 84.31,16.91 84.31,18.24 84.13,18.43 83.88,18.43 83.68,18.23 83.68,17.23 83.35,16.89 82.85,16.89 82.54,17.2 82.54,56.93 83.93,58.32 83.93,60.96 84.48,61.51 85.51,61.51 85.86,61.16 85.86,60.63 85.97,60.53 86.17,60.53 v2(86.24,60.6)
M_DDB11_N: length 96.8
  TOP w0.108: U11.G4 v1(86.66,66.2) ; J63.J31 v2(110.9,4.32)
  L03_SIG1 w0.102: 94.37,64.76 94.37,64.78 94.35,64.81 94.35,66.38 93.92,66.8 87.36,66.8 87.06,66.51 87.06,65.95 86.91,65.8 86.76,65.8 86.66,65.9 v1(86.66,66.2)
  L03_SIG1 w0.105: 94.37,64.76 94.37,64.61 94.54,64.44 101.05,64.44 101.69,63.8 101.69,57.43 101.03,56.77 99.08,56.77 96.3,53.99 96.3,46.39 98.11,44.58 98.11,41.35 97.34,40.58 97.34,38.66 95.63,36.95 95.63,31.36 96.24,30.75 96.24,24.39 101.5,19.13 101.5,14.25 101.78,13.97 102.33,13.97 102.77,13.53 102.77,13 103.07,12.7 103.59,12.7 104.04,12.25 104.04,11.73 104.33,11.43 109.97,11.43 110.39,11.02 110.39,7.79 109.97,7.37 109.3,7.37 109.12,7.18 109.12,5.32 109.37,5.07 110.15,5.07 v2(110.9,4.32)
M_DDB11_P: length 96.8
  TOP w0.108: U11.G3 v1(86.66,65.2) ; J63.J30 v2(109.63,4.32)
  L03_SIG1 w0.102: 94.12,64.76 94.12,64.78 94.14,64.81 94.14,66.3 93.84,66.6 87.44,66.6 87.26,66.42 87.26,65.87 86.99,65.6 86.66,65.6 86.56,65.5 86.56,65.3 v1(86.66,65.2)
  L03_SIG1 w0.105: 94.12,64.76 94.12,64.5 94.43,64.19 100.95,64.19 101.44,63.7 101.44,57.54 100.92,57.02 98.97,57.02 96.04,54.1 96.04,46.29 97.86,44.48 97.86,41.46 97.09,40.68 97.09,38.77 95.38,37.06 95.38,31.25 95.99,30.64 95.99,24.28 101.24,19.02 101.24,14.14 101.67,13.72 102.22,13.72 102.51,13.42 102.51,12.89 102.96,12.45 103.49,12.45 103.78,12.15 103.78,11.62 104.23,11.18 109.87,11.18 110.13,10.91 110.13,7.89 109.86,7.62 109.19,7.62 108.86,7.29 108.86,5.21 109.26,4.81 109.93,4.81 110.13,4.61 110.13,4.42 110.03,4.32 v2(109.63,4.32)
M_DDB12_N: length 96.8
  TOP w0.102: 85.46,62.46 85.48,62.48 85.5,62.48 85.8,62.78 85.8,63.25 85.69,63.37 85.69,64.22 U11.F2
  TOP w0.108: 85.46,62.46 82.88,59.88 82.88,51.45 82.53,51.1 79.9,51.1 79.44,50.63 79.44,49.9 79.92,49.42 99.27,49.42 v2(99.63,49.06) ; J63.F32 v2(112.17,8.13)
  L03_SIG1 w0.105: v2(99.63,49.06) 99.63,49.19 99.45,49.37 99.29,49.37 99.02,49.11 99.02,48.66 99.66,48.02 100.67,48.02 101.58,47.11 101.58,45.52 102.82,44.28 102.82,39.55 101.98,38.71 101.98,36.57 100.21,34.79 100.21,33.37 100.55,33.03 101.67,33.03 102.16,32.53 104.35,32.53 105.32,31.56 105.32,27.6 103,25.28 103,22.74 105.31,20.43 105.31,14.26 105.6,13.97 106.14,13.97 106.58,13.53 106.58,12.95 106.83,12.7 108.2,12.7 108.76,12.14 110.54,12.14 111.66,11.02 111.66,8.64 v2(112.17,8.13)
M_DDB12_P: length 96.8
  TOP w0.102: U11.F1 86.16,63.38 86.01,63.22 86.01,62.7 85.64,62.33 85.64,62.31 85.62,62.3
  TOP w0.108: J63.F31 v2(110.9,8.13) ; 85.62,62.3 83.11,59.78 83.11,51.35 82.62,50.87 80,50.87 79.67,50.54 79.67,49.99 80.01,49.65 99.57,49.65 99.68,49.76 99.68,49.96 v2(99.63,50.01)
  L03_SIG1 w0.105: v2(110.9,8.13) 110.9,8.01 111,7.9 111.36,7.9 111.48,8.02 111.48,8.46 111.4,8.53 111.4,10.92 110.44,11.88 108.66,11.88 108.1,12.45 106.72,12.45 106.32,12.85 106.32,13.43 106.03,13.72 105.49,13.72 105.05,14.16 105.05,20.33 102.75,22.64 102.75,25.38 105.07,27.7 105.07,31.45 104.25,32.28 102.06,32.28 101.56,32.77 100.45,32.77 99.96,33.26 99.96,34.9 101.73,36.67 101.73,38.82 102.57,39.65 102.57,44.17 101.33,45.41 101.33,47.01 100.56,47.77 99.55,47.77 98.77,48.55 98.77,49.21 99.18,49.63 99.57,49.63 99.7,49.76 99.7,49.94 v2(99.63,50.01)
M_DDB13_N: length 95.8
  TOP w0.108: U11.F4 v1(85.66,66.2) ; J63.E31 v2(110.9,10.67)
  L05_SIG2 w0.102: v1(85.66,66.2) 85.06,65.6 85.06,64.65 85.04,64.63 85.04,64.6
  L05_SIG2 w0.105: v2(110.9,10.67) 109.76,9.54 107.04,9.54 106.14,8.64 104.33,8.64 104.04,8.34 104.04,7.7 103.7,7.37 94.9,7.37 92.61,9.65 91.52,9.65 88.08,13.09 88.08,17.24 87.61,17.71 87.61,34.19 87.4,34.4 86.99,34.4 86.75,34.16 86.75,30.08 86.33,29.66 85.74,29.66 85.37,30.03 85.37,49.45 88.48,52.56 88.48,56.3 87.75,57.03 87.75,61.31 85.04,64.02 85.04,64.6
M_DDB13_P: length 95.8
  TOP w0.108: J63.E30 v2(109.63,10.67) ; U11.F3 v1(85.66,65.2)
  L05_SIG2 w0.102: 85.29,64.6 85.29,64.63 85.27,64.65 85.27,65.52 85.42,65.67 85.75,65.67 85.87,65.55 85.87,65.3 85.76,65.2 v1(85.66,65.2)
  L05_SIG2 w0.105: v2(109.63,10.67) 109.8,10.84 110.06,10.84 110.22,10.68 110.22,10.35 109.66,9.79 106.93,9.79 106.03,8.89 104.23,8.89 103.78,8.45 103.78,7.81 103.6,7.62 95,7.62 92.72,9.91 91.62,9.91 88.33,13.2 88.33,17.35 87.87,17.82 87.87,34.29 87.51,34.65 86.88,34.65 86.5,34.27 86.5,30.18 86.23,29.91 85.85,29.91 85.62,30.14 85.62,49.35 88.73,52.46 88.73,56.4 88,57.13 88,61.42 85.29,64.13 85.29,64.6
M_DDB14_N: length 95.8
  TOP w0.102: U11.E2 84.69,64.22 84.69,63.41 84.78,63.32 ; 84.78,63.23 84.78,63.24
  TOP w0.108: v2(81.31,57.75) 81.66,58.11 81.66,59.86 84.11,62.3 84.37,62.3 84.78,62.71 84.78,63.23 ; 84.78,63.24 84.78,63.32 ; J63.K35 v2(115.98,3.05)
  L05_SIG2 w0.105: v2(115.98,3.05) 115.2,2.27 88.69,2.27 86.17,4.79 86.17,5.9 82.19,9.87 82.19,16.06 81.65,16.6 81.65,57.41 v2(81.31,57.75)
M_DDB14_P: length 95.8
  TOP w0.102: U11.E1 85.16,63.38 85.01,63.23
  TOP w0.108: 85.01,63.23 85.01,62.61 84.47,62.08 84.2,62.08 81.89,59.77 81.89,57.9 82.04,57.75 v2(82.25,57.75) ; J63.K34 v2(114.71,3.05)
  L05_SIG2 w0.105: v2(82.25,57.75) 82.16,57.84 82.01,57.84 81.9,57.74 81.9,16.71 82.45,16.16 82.45,9.98 86.43,6 86.43,4.89 88.79,2.52 94.62,2.52 94.74,2.65 94.74,2.78 94.87,2.91 95.27,2.91 95.39,2.79 95.39,2.65 95.51,2.53 106.79,2.53 106.91,2.65 106.91,2.81 107.04,2.93 107.4,2.93 107.55,2.77 107.55,2.63 107.66,2.52 115.09,2.52 115.22,2.65 115.22,3.14 115.09,3.27 114.81,3.27 114.71,3.17 v2(114.71,3.05)
M_DDB15_N: length 95.8
  TOP w0.108: J63.J34 v2(114.71,4.32) ; U11.D2 v1(83.66,64.2)
  L05_SIG2 w0.105: v1(83.66,64.2) 83.66,63.93 83.77,63.83 84.29,63.83 87.12,60.99 87.12,59.01 83.82,55.71 83.82,19.72 83.99,19.55 84.38,19.55 84.59,19.76 84.59,21.52 84.94,21.87 85.43,21.87 85.77,21.53 85.77,17.15 86.26,16.66 86.26,10.08 89.86,6.48 91.12,6.48 92.52,5.08 113.94,5.08 114.7,4.32 v2(114.71,4.32)
M_DDB15_P: length 95.8
  TOP w0.108: J63.J33 v2(113.44,4.32) ; U11.D1 v1(83.66,63.2)
  L05_SIG2 w0.105: v1(83.66,63.2) 83.66,63.47 83.77,63.57 84.18,63.57 86.87,60.89 86.87,59.12 83.56,55.81 83.56,19.62 83.88,19.3 84.49,19.3 84.84,19.65 84.84,21.41 85.05,21.61 85.32,21.61 85.52,21.42 85.52,17.04 86,16.55 86,9.98 89.75,6.23 91.02,6.23 92.42,4.83 113.83,4.83 114,4.65 114,4.37 113.87,4.24 113.51,4.24 v2(113.44,4.32)
M_SCTRLA_N: length 99.1
  TOP w0.102: U11.V1 98.16,63.37 98.31,63.23
  TOP w0.108: v2(100.55,57.8) 100.2,58.15 99.81,58.15 99.05,58.91 99.05,61.82 98.31,62.57 98.31,63.23 ; J63.G37 v2(118.52,6.86)
  L05_SIG2 w0.105: v2(118.52,6.86) 118.41,6.96 118.12,6.96 117.99,6.83 117.99,6.42 117.67,6.11 116.88,6.11 116.48,6.5 116.48,8.74 114.95,10.27 114.95,11.07 113.96,12.06 113.96,13.41 113.66,13.72 113.11,13.72 112.67,14.15 112.67,14.7 112.37,15 112.04,15 111.51,15.53 109.33,15.53 108.52,16.34 107.77,16.34 105.95,18.15 105.95,21.25 105.6,21.6 105.6,24.01 102.36,27.25 102.36,29.37 103.1,30.11 104.9,30.11 110.13,35.34 110.13,38.14 109.02,39.25 109.02,40.3 105.96,43.37 105.63,43.37 105.34,43.08 105.34,42.68 107.43,40.59 107.43,38.3 107.88,37.85 109.04,37.85 109.5,37.4 109.5,36.89 108.88,36.27 107.53,36.27 106.03,37.77 106.03,39.54 104.21,41.37 104.21,53.21 103.1,54.32 103.1,55.32 102.32,56.11 102.32,57.48 101.65,58.15 100.61,58.15 100.51,58.04 100.51,57.85 v2(100.55,57.8)
M_SCTRLA_P: length 99.1
  TOP w0.102: U11.V2 98.64,64.22 98.64,63.36 98.53,63.26
  TOP w0.108: 98.53,63.26 98.53,62.66 99.28,61.91 99.28,59 99.91,58.38 100.26,58.38 100.55,58.67 v2(100.55,58.75) ; J63.G36 v2(117.25,6.86)
  L05_SIG2 w0.105: v2(100.55,58.75) 100.9,58.4 101.75,58.4 102.57,57.59 102.57,56.21 103.36,55.43 103.36,54.43 104.47,53.32 104.47,41.47 106.29,39.65 106.29,37.87 107.63,36.53 108.77,36.53 109.24,36.99 109.24,37.29 108.94,37.6 107.77,37.6 107.17,38.2 107.17,40.49 105.09,42.57 105.09,43.18 105.52,43.62 106.07,43.62 109.28,40.41 109.28,39.35 110.39,38.24 110.39,35.23 105.01,29.86 103.21,29.86 102.62,29.26 102.62,27.36 105.86,24.12 105.86,21.71 106.21,21.35 106.21,18.26 107.87,16.59 108.63,16.59 109.43,15.79 111.62,15.79 112.15,15.26 112.48,15.26 112.93,14.8 112.93,14.26 113.22,13.97 113.76,13.97 114.22,13.52 114.22,12.17 115.21,11.18 115.21,10.37 116.74,8.84 116.74,6.61 116.98,6.36 117.57,6.36 117.73,6.53 117.73,6.69 117.57,6.86 v2(117.25,6.86)
M_SCTRLB_N: length 96.8
  TOP w0.102: 88.75,63.27 88.69,63.33 88.69,64.22 U11.J2
  TOP w0.108: 88.75,63.27 88.75,62.46 88.04,61.75 88.04,56.27 87.04,55.27 84.33,55.27 83.73,54.66 83.73,51.67 85.13,50.27 97.82,50.27 98.19,50.63 102.12,50.63 102.22,50.53 v2(102.22,50.28) ; J63.F35 v2(115.98,8.13)
  L03_SIG1 w0.105: v2(115.98,8.13) 115.47,8.64 115.47,9.18 110.95,13.7 110.64,13.7 110.39,13.95 110.39,17.38 107.76,20 107.76,22.62 106.3,24.08 106.3,25.72 106.95,26.37 110.06,26.37 110.99,27.3 110.99,28.8 110.13,29.66 108.46,29.66 107.7,30.42 107.7,32.63 106.07,34.26 105.5,34.26 104.74,35.01 104.74,35.89 105.2,36.35 106.15,36.35 106.7,36.89 106.7,37.93 104.58,40.04 104.58,41.43 105.53,42.38 105.53,44.26 103.66,46.13 103.66,47.62 101.48,49.8 101.48,50.41 101.69,50.62 101.88,50.62 v2(102.22,50.28)
M_SCTRLB_P: length 96.8
  TOP w0.102: U11.J1 89.16,63.4 88.98,63.22
  TOP w0.108: 88.98,63.22 88.98,62.36 88.27,61.65 88.27,56.17 87.13,55.04 84.43,55.04 83.95,54.56 83.95,51.77 85.22,50.5 97.73,50.5 98.09,50.86 99.79,50.86 99.9,50.97 99.9,51.19 100.05,51.34 100.28,51.34 100.44,51.19 100.44,50.97 100.54,50.86 102.12,50.86 102.22,50.97 v2(102.22,51.22) ; J63.F34 v2(114.71,8.13)
  L03_SIG1 w0.105: v2(114.71,8.13) 114.79,8.05 115.09,8.05 115.19,8.15 115.19,9.09 110.85,13.44 110.53,13.44 110.13,13.84 110.13,17.28 107.51,19.9 107.51,22.52 106.05,23.98 106.05,25.83 106.84,26.62 109.96,26.62 110.74,27.41 110.74,28.69 110.03,29.41 108.36,29.41 107.44,30.32 107.44,32.52 105.96,34.01 105.39,34.01 104.49,34.91 104.49,35.99 105.1,36.6 106.05,36.6 106.44,37 106.44,37.82 104.33,39.94 104.33,41.54 105.28,42.48 105.28,44.16 103.4,46.03 103.4,47.52 101.22,49.7 101.22,50.51 101.58,50.87 102.12,50.87 102.22,50.98 v2(102.22,51.22)
MAN_RSTZ: length 57.7
  TOP w0.193: J20.1 46.06,48.6 46.06,43.72 46.44,43.33 46.44,41.91 46.95,41.4 49.11,41.4 50.31,40.21 50.31,23.27 54.46,19.11 55.54,19.11 57.72,16.93 59.69,16.93 60.15,16.47 60.15,10.41 60.53,10.03 SW1.3
  BOTTOM w0.193: J20.1 47.62,50.1 46.75,49.23 46.75,47.9 R696.1 45.58,47.83 45.39,47.64 U511.3
MC_VCC: length 15.4
  TOP w0.508: v2(183.01,69.81) 183.73,69.81 184.66,70.75 184.66,74.1 185.33,74.76 v2(185.33,74.7)
  BOTTOM w0.508: R587.2 C574.2 187.79,74.8 U505.1 187.62,74.8 185.43,74.8 v2(185.33,74.7) 185.31,74.72 C547.1 ; R606.2 v2(183.01,69.81)
MODEB: length 24.6
  TOP w0.193: J45.1 70.73,20.62 R66.2 v2(68.9,21.63) ; J63.B12 v2(85.5,14.48)
  BOTTOM w0.193: v2(85.5,14.48) 84.8,15.17 84.8,16.01 84.44,16.37 72.8,16.37 68.9,20.28 v2(68.9,21.63)
MTR_ARSTZ: length 156.4
  TOP w0.193: v2(164.78,108.33) 163.98,108.33 163.92,108.39 U2.48 ; U15.48 162.65,55.81 162.83,55.63 v2(163.51,55.63) 163.51,55.01 163.31,54.81 163.31,53.71 162.95,53.35 R36.2 ; U11.T25 v1(96.66,88.2)
  L03_SIG1 w0.155: v2(164.78,108.33) 164.9,108.21 164.9,104.28 TP15.1 163.94,100.13 163.94,85.57 163.37,85 163.37,68.38 162.79,67.79 162.79,65.35 164.18,63.96 164.18,56.3 v2(163.51,55.63)
  L05_SIG2 w0.155: v2(127.93,94.77) 127.93,94.91 128.57,95.55 128.57,103.22 132.13,106.78 135.42,106.78 135.8,106.41 135.8,105.02 139.09,101.73 TP15.1
  BOTTOM w0.102: 106.98,90.83 106.79,90.65 98.38,90.65 97.2,89.46 97.2,88.74 v1(96.66,88.2)
  BOTTOM w0.193: v2(127.93,94.77) 127.93,94.63 127.2,93.9 127.2,92.44 127.71,91.93 128.21,91.93 128.55,91.59 128.55,90.8 126.07,88.32 126.07,88 125.63,87.56 125.24,87.56 124.66,88.14 124.66,90.93 123.41,92.18 115.34,92.18 111.38,88.22 109.45,88.22 108.92,88.75 108.92,90.34 108.34,90.92 107.07,90.92 106.98,90.83
Net_305: length 0.7
  TOP w0.193: 81.16,75.7 v1(80.66,75.2)
OCLKA: length 74.3
  TOP w0.193: v2(166.05,60.26) 165.62,60.26 165.3,60.58 U15.6 ; U2.6 166.6,113.29 v2(166.94,113.63)
  L03_SIG1 w0.155: v2(169.3,79.03) 169.3,63.37 166.19,60.26 v2(166.05,60.26) ; v2(159.01,79.11) 160.01,80.11 160.01,93.99 158.37,95.63 158.37,104.24 166.35,112.21 166.35,113.03 v2(166.94,113.63)
  L05_SIG2 w0.155: v2(159.01,79.11) 169.22,79.11 v2(169.3,79.03)
  BOTTOM w0.193: R578.1 v2(159.01,79.11)
OCLKA_RES: length 77.4
  TOP w0.193: v2(120.01,63.55) 120.01,64.04 118.47,65.59 118.47,67.28 117.5,68.25 115.67,68.25 115.28,68.65 115.28,69.24 115.97,69.93 115.97,71.08 115.39,71.66 109.77,71.66 108.39,70.28 108.39,69.93 107.16,68.7 U11.AF6
  L03_SIG1 w0.155: v2(157.97,78.95) 157.97,72.61 v2(160.51,70.07)
  L05_SIG2 w0.155: v2(160.51,70.07) 160.3,70.28 148.43,70.28 148.06,70.66 146.33,70.66 145.98,70.31 138.55,70.31 138.25,70.01 137.36,70.01 136.96,70.41 133.32,70.41 133.07,70.15 131.81,70.15 128.82,67.16 127.08,67.16 123.47,63.55 v2(120.01,63.55)
  BOTTOM w0.193: R578.2 v2(157.97,78.95)
OUT1A: length 3.7
  TOP w0.254: U15.12 164.93,63.59 165.23,63.88 v2(165.23,64.62)
  BOTTOM w0.254: R609.1 165.51,64.9 v2(165.23,64.62)
OUT1A_SNUB: length 1.9
  BOTTOM w0.254: R576.1 C549.2
OUT1B: length 25.2
  TOP w0.254: v1(161.66,63.94) 161.64,63.96 U15.15 ; R25.1 162.99,84.89 162.61,85.27 161.39,85.27 160.99,84.86 160.99,84 v2(161.02,83.97)
  L03_SIG1 w0.254: v2(161.02,83.97) 161.05,83.97 160.74,83.6 160.74,82.01 161.66,81.08 v1(161.66,63.94)
OUT1B_SNUB: length 1.9
  BOTTOM w0.254: R577.1 C550.2
OUT1C: length 5.8
  TOP w0.254: U15.16 161.14,66.56 162.14,67.55 162.14,69.86 R28.1
OUT1C_SNUB: length 3.8
  BOTTOM w0.254: R563.1 155.18,83.26 157.16,83.26 C551.2
OUT2A: length 11.4
  TOP w0.254: U2.12 166.2,116.29 166.5,116.59 v2(166.5,117.32) 166.8,117.62 166.8,121.37 168.26,122.82 169.92,122.82 171.12,124.02 R7.1
OUT2A_SNUB: length 2.3
  BOTTOM w0.254: R500.1 175.25,127.57 C500.2
OUT2B: length 5.7
  TOP w0.193: R5.1 163.89,123.04 163.89,119.94 162.91,118.97 U2.15
OUT2B_SNUB: length 2.3
  BOTTOM w0.254: C501.2 167.59,124.98 R501.1
OUT2C: length 6.3
  TOP w0.193: R4.1 163.04,122.26 163.19,122.26 163.39,122.06 163.39,120.22 162.41,119.25 U2.16
OUT2C_SNUB: length 2.3
  BOTTOM w0.254: R502.1 156.15,127.24 C502.2
P1_A0: length 77.8
  TOP w0.193: J2.85 113.49,121.09 113.35,121.23 113.35,122.48 v2(113.55,122.68) ; U11.AE12 v1(105.66,74.2)
  L03_SIG1 w0.102: v1(105.66,74.2) 106.2,73.66 106.82,73.66 107.15,73.33 107.63,73.33
  L03_SIG1 w0.155: 107.63,73.33 113.28,73.33 124.52,84.58 124.52,91.8 123.94,92.38 123.94,94.05 125.62,95.73 125.62,102.01 124.57,103.06 124.57,114.25 124.19,114.63 124.19,114.69 123.97,114.91 123.97,116.64 123.08,117.53 122.04,117.53 121.69,117.88 121.69,118.07 121.56,118.19 121.56,118.86 118.49,121.93 116.4,121.93 116.27,122.06 116.27,122.38 116.4,122.51 117.43,122.51 117.56,122.64 117.56,122.86 117.23,123.19 114.49,123.19 113.98,122.68 v2(113.55,122.68)
P1_A1: length 78.5
  TOP w0.193: J2.84 112.99,115.07 113.82,115.9 119.65,115.9 v2(119.82,115.73) ; U11.AF12 v1(106.66,74.2)
  L03_SIG1 w0.102: 107.63,73.76 107.1,73.76 v1(106.66,74.2)
  L03_SIG1 w0.155: 107.63,73.76 113.21,73.76 124.17,84.72 124.17,91.47 123.51,92.13 123.51,94.23 125.26,95.98 125.26,101.86 124.13,102.99 124.13,109.2 123.28,110.06 123.28,110.55 124.13,111.41 124.13,114.08 123.92,114.29 123.75,114.29 123.53,114.07 123.53,112.31 123.41,112.19 123.15,112.19 123.02,112.31 123.02,114.42 123.54,114.94 123.54,116.46 122.9,117.1 121.86,117.1 121.13,117.83 121.13,118.56 120.77,118.92 120.25,118.92 119.87,118.54 119.87,115.78 v2(119.82,115.73)
P1_A2: length 78
  TOP w0.193: U11.AF13 v1(106.66,75.2) ; v2(112.68,118.79) 112.68,118.8 112.67,118.8 112.99,119.12 J2.83
  L03_SIG1 w0.102: v1(106.66,75.2) 107.08,75.2 107.45,74.83
  L03_SIG1 w0.155: 107.45,74.83 110.5,74.83 111.37,75.69 113.63,75.69 120.05,82.12 120.05,82.12 121.66,83.72 123.1,85.17 123.1,90.66 121.38,92.39 121.38,93.29 122.21,94.12 122.21,94.81 123.02,95.62 123.02,100.38 122.36,101.04 122.36,101.54 122.97,102.14 122.97,102.65 122.68,102.94 121.94,102.94 121.78,103.1 121.78,103.33 121.94,103.5 122.68,103.5 122.84,103.66 122.84,103.89 122.68,104.06 121.94,104.06 121.78,104.22 121.78,104.45 121.94,104.61 122.68,104.61 122.84,104.78 122.84,105.29 121.82,106.31 121.82,109.99 120.79,111.02 120.79,112.32 121.4,112.93 121.4,114.12 120.97,114.54 119.55,114.54 118.79,115.3 118.79,119.08 119.12,119.41 119.12,119.99 118.65,120.46 115.13,120.46 114.74,120.85 113.59,120.85 113.29,121.15 113.29,121.45 113.11,121.63 112.85,121.63 112.7,121.47 112.7,121.17 112.53,121 112.53,120.38 112.7,120.21 113.29,120.21 113.45,120.05 113.45,119.82 113.29,119.65 112.7,119.65 112.53,119.49 112.53,118.94 v2(112.68,118.79)
P1_A3: length 77.9
  TOP w0.193: U11.AF14 v1(106.66,77.2) ; J2.82 v2(112.49,111.59)
  L03_SIG1 w0.102: 107.63,76.56 107.41,76.33 106,76.33 105.83,76.5 105.83,76.65 106.38,77.2 v1(106.66,77.2)
  L03_SIG1 w0.155: v2(112.49,111.59) 112.08,112 112.08,112.65 112.41,112.97 113.21,112.97 113.24,113 113.62,113 113.72,113.1 113.72,113.38 113.59,113.51 112.22,113.51 112.05,113.68 112.05,114.9 112.98,115.83 116.94,115.83 117.07,115.7 117.07,115.26 116.8,115 114.63,115 114.23,114.61 113.74,114.61 113.74,114.61 112.83,114.61 112.7,114.49 112.7,114.15 112.83,114.03 114.53,114.03 114.76,114.26 114.78,114.26 114.94,114.42 117.12,114.42 117.29,114.26 118.42,113.12 118.42,112.37 117.89,111.84 117.89,109.98 118.55,109.32 119.58,109.32 120.05,108.85 120.05,102.39 120.94,101.5 120.94,100.45 121.11,100.28 121.11,96.27 120.47,95.63 120.47,94.82 119.65,94 119.65,91.67 120.47,90.85 120.47,85.79 120.13,85.45 119.69,85.45 118.33,84.09 118.33,82.59 112.85,77.11 110.22,77.11 109.66,76.56 107.63,76.56
P1_A4: length 79.6
  TOP w0.193: U11.AC13 v1(103.66,75.2) ; J2.81 112.49,121.08 112.76,121.36 v2(112.76,123.29)
  L03_SIG1 w0.102: 107.61,72.8 105.51,72.8 105.27,73.04 105.27,73.14 105.06,73.35 105.06,73.36 104.83,73.59 104.82,73.59 104.6,73.81 104.5,73.81 104.27,74.04 104.27,74.53 103.66,75.14 v1(103.66,75.2)
  L03_SIG1 w0.155: v2(112.76,123.29) 113.98,123.29 114.29,123.6 117.44,123.6 121.02,120.02 121.02,120.01 121.92,119.1 122.16,119.1 124.43,116.82 124.43,116.78 124.63,116.59 124.63,114.81 125,114.43 125,107.75 126.04,106.71 126.04,85.6 113.22,72.77 107.63,72.77 107.61,72.8
P1_A5: length 78.6
  TOP w0.193: U11.AD13 v1(104.66,75.2) ; J2.80 111.99,115.76 112.57,116.34 120.7,116.34 v2(121.34,115.7)
  L03_SIG1 w0.102: v1(104.66,75.2) 104.9,75.2 105.5,74.6 106.95,74.6 107.32,74.23 107.35,74.23 107.47,74.12
  L03_SIG1 w0.155: v2(121.34,115.7) 121.27,115.76 121.27,116.27 121.54,116.53 122.85,116.53 123.11,116.28 123.11,115.2 122.59,114.68 122.59,112.22 122.42,112.05 122.42,110.91 122.84,110.49 122.84,109.88 122.68,109.72 122.68,106.67 122.81,106.54 123.07,106.54 123.2,106.67 123.2,109.02 123.38,109.21 123.52,109.21 123.7,109.02 123.7,102.92 124.91,101.71 124.91,96.28 123.08,94.45 123.08,92.02 123.81,91.29 123.81,84.87 113.06,74.12 107.47,74.12
P1_A6: length 78.4
  TOP w0.193: U11.AE13 v1(105.66,75.2) ; J2.79 111.99,121.46 v2(111.97,121.47)
  L03_SIG1 w0.102: v1(105.66,75.2) 105.66,75.12 105.98,74.8 107.08,74.8 107.41,74.47
  L03_SIG1 w0.155: 107.41,74.47 112.91,74.47 123.46,85.02 123.46,90.92 121.81,92.56 121.81,93.11 122.64,93.94 122.64,94.63 123.38,95.36 123.38,100.46 123.91,100.99 123.91,102.2 123.27,102.84 123.27,105.86 123.14,106 122.74,106 122.25,106.49 122.25,109.9 122.28,109.93 122.28,110.13 121.22,111.2 121.22,112.14 121.43,112.35 121.94,112.35 122.15,112.56 122.15,114.78 121.85,115.08 119.63,115.08 119.23,115.48 119.23,115.97 119.23,115.98 119.23,118.77 119.69,119.23 119.69,120.1 118.89,120.9 115.74,120.9 115.53,121.11 115.25,121.11 114.27,122.09 113.74,122.09 113.72,122.07 112.78,122.07 112.17,122.69 112.17,123.52 111.99,123.69 111.74,123.69 111.57,123.52 111.57,122.53 111.58,122.52 111.58,122.37 111.89,122.07 111.89,121.55 v2(111.97,121.47)
P1_A7: length 77.8
  TOP w0.193: J2.78 v2(111.49,112.4) ; U11.AE14 v1(105.66,77.2)
  L03_SIG1 w0.102: v1(105.66,77.2) 105.66,77.02 105.44,76.8 104.89,76.8 104.74,76.64 104.74,76.28 104.9,76.12 107.63,76.12
  L03_SIG1 w0.155: 107.63,76.12 109.87,76.12 110.5,76.76 113.11,76.76 118.76,82.41 118.76,83.91 119.87,85.02 120.45,85.02 120.91,85.47 120.91,91.03 120.08,91.85 120.08,93.82 120.91,94.64 120.91,95.45 121.54,96.09 121.54,100.35 121.3,100.6 121.3,101.75 120.48,102.56 120.48,109.03 119.76,109.75 118.73,109.75 118.39,110.09 118.39,110.69 118.75,111.05 119.11,111.05 119.47,111.41 119.47,112.68 117.97,114.18 117.5,114.66 117.5,116.1 117.33,116.26 116.12,116.26 115.99,116.39 115.99,116.69 116.12,116.82 117.33,116.82 117.5,116.98 117.5,117.21 117.33,117.38 116.49,117.38 116.33,117.54 116.33,117.77 116.49,117.94 117.33,117.94 117.5,118.1 117.5,118.55 117.12,118.92 116.56,118.92 116.08,118.45 116.08,118.44 115.73,118.09 115.73,118.09 115.28,117.64 115.28,116.72 114.93,116.37 114.43,116.37 114.43,116.38 112.88,116.38 111.62,115.11 111.62,113.13 111.49,113 v2(111.49,112.4)
P1_A8: length 77.4
  TOP w0.193: J2.77 v2(111.49,118.69) ; U11.AE15 v1(105.66,78.2)
  L03_SIG1 w0.102: v1(105.66,78.2) 105.68,78.2 106.08,77.81 107.42,77.81 107.47,77.85 107.63,77.85
  L03_SIG1 w0.155: 107.63,77.85 112.32,77.85 117.46,82.99 117.46,84.45 119.61,86.6 119.61,90.49 119.44,90.66 119.2,90.66 119.05,90.51 119.05,87.59 118.92,87.46 118.62,87.46 118.49,87.59 118.49,91.02 118.79,91.31 118.79,94.36 119.61,95.18 119.61,95.99 120.25,96.62 120.25,100.14 120.23,100.16 120.23,100.99 119.19,102.03 119.19,107.46 117.03,109.62 117.03,110.5 116.58,110.95 115.4,110.95 115.35,111 113.88,111 112.89,110.01 112.48,110.01 112.36,109.88 110.6,109.88 109.18,111.3 109.18,111.69 109.46,111.97 109.46,112.96 109.18,113.23 109.18,114.94 108.3,115.81 108.3,116.06 108.9,116.66 110.53,116.66 111.32,117.45 111.32,117.94 110.84,118.42 110.84,120.22 111.05,120.43 111.4,120.43 111.65,120.19 111.65,118.85 v2(111.49,118.69)
P1_A9: length 78.6
  TOP w0.102: U11.AD15 v1(104.66,78.2)
  TOP w0.193: v2(110.99,115.98) 110.99,114.17 J2.76
  L05_SIG2 w0.102: 107.63,77.6 107.11,77.6 106.91,77.8 104.99,77.8 104.66,78.13 v1(104.66,78.2)
  L05_SIG2 w0.155: 107.63,77.6 116.28,77.6 124.85,86.17 124.85,88.72 125.36,89.23 125.36,91.31 124.37,92.3 124.37,94.6 125.97,96.2 125.97,101.23 125.84,101.36 125.84,105.55 125.84,105.85 125.5,106.2 125.5,106.98 125.5,108.89 125.25,109.13 125.25,110.74 125.25,111.31 125.25,111.45 122.03,114.67 120.91,114.67 120.45,115.13 119.57,115.13 119.23,115.48 119.23,116.58 115.9,119.9 111.42,119.9 110.93,120.39 110.15,120.39 109.89,120.13 109.89,119.5 110.15,119.25 110.15,118.51 109.88,118.24 109.88,117.65 110.24,117.28 110.76,117.28 110.99,117.06 v2(110.99,115.98)
P1_B0: length 79.6
  TOP w0.193: U11.AD14 v1(104.66,77.2) ; J2.75 v2(110.99,122.27)
  L03_SIG1 w0.102: 107.45,75.26 107,75.72 104.51,75.72 104.36,75.87 103.8,75.87 103.27,76.4 103.27,77.36 103.5,77.59 103.83,77.59 104.22,77.2 v1(104.66,77.2)
  L03_SIG1 w0.155: 107.45,75.26 110.35,75.26 111.14,76.05 113.48,76.05 119.62,82.19 119.62,82.19 122.75,85.32 122.75,90.41 120.95,92.21 120.95,93.46 121.77,94.29 121.77,95.09 122.36,95.68 122.36,100.54 122.01,100.9 122.01,102.26 121.76,102.51 121.76,102.51 121.35,102.92 121.35,109.85 120.36,110.84 120.36,112.5 120.88,113.02 120.88,113.82 120.59,114.11 119.37,114.11 118.36,115.12 118.36,119.3 117.65,120.01 114.54,120.01 113.6,119.08 113.58,119.08 113.28,118.78 113.28,118.54 112.93,118.19 112.33,118.19 112.08,118.44 112.08,120.51 111.37,121.22 111.37,121.28 111.34,121.31 111.34,121.92 v2(110.99,122.27)
P1_B1: length 78.3
  TOP w0.193: U11.AC14 v1(103.66,77.2) ; J2.74 110.49,112.95 110.62,112.81 110.62,111.9 110.49,111.76 v2(110.49,111.59)
  L03_SIG1 w0.102: 107.49,75.69 107.33,75.85 107.15,75.85 107.08,75.92 104.61,75.92 104.43,76.1 104.13,76.1 103.66,76.56 v1(103.66,77.2)
  L03_SIG1 w0.155: 107.49,75.69 110.1,75.69 110.81,76.4 113.33,76.4 119.19,82.26 119.19,83.73 120.04,84.58 120.89,84.58 122.39,86.08 122.39,90.15 120.52,92.03 120.52,93.64 121.34,94.47 121.34,95.27 121.98,95.91 121.98,100.42 121.65,100.75 121.65,102.01 120.91,102.74 120.91,109.67 119.93,110.66 119.93,112.68 120.35,113.1 120.35,113.5 120.17,113.68 119.19,113.68 119,113.87 118.97,113.87 118.27,114.57 118.27,114.6 117.93,114.94 117.93,118.94 117.44,119.43 114.78,119.43 113.11,117.76 112.25,117.76 111.71,117.22 111.71,115.83 111.19,115.31 111.19,113.77 110.58,113.16 110.58,112.04 110.49,111.95 v2(110.49,111.59)
P1_B2: length 77.4
  TOP w0.193: U11.AF15 v1(106.66,78.2) ; J2.73 v2(110.49,117.88)
  L03_SIG1 w0.155: v2(110.49,117.88) 110.49,118.11 110.27,118.33 110.27,120.51 110.64,120.88 110.64,121.78 110.39,122.02 110.39,123.56 110.26,123.69 109.8,123.69 109.43,123.31 109.43,122.83 109.68,122.59 109.68,122.05 109.31,121.69 109.31,121.18 108.85,120.72 108.85,118.96 108.03,118.13 108.03,117.56 107.39,116.93 107.39,114.96 108.08,114.26 108.08,112.16 107.88,111.95 107.88,111.16 108.37,110.67 108.9,110.67 108.94,110.63 109.15,110.63 109.5,110.28 109.5,110.07 110.12,109.45 110.99,109.45 112.54,109.45 112.56,109.48 113.31,109.48 113.62,109.79 113.62,110.09 113.94,110.41 114.19,110.41 114.33,110.27 114.33,109.66 114.52,109.48 114.74,109.48 114.74,109.47 115.4,109.47 115.62,109.7 115.62,110.28 115.77,110.43 116.33,110.43 116.59,110.17 116.59,109.44 117.29,108.75 117.29,103.64 118.44,102.49 118.44,102.16 119.82,100.79 119.82,96.8 119.18,96.17 119.18,95.36 118.36,94.54 118.36,91.49 118.06,91.19 118.06,87.41 118.19,87.28 118.19,85.79 117.03,84.63 117.03,83.21 112.02,78.2 v1(106.66,78.2)
P1_B3: length 79
  TOP w0.193: J2.72 109.99,112.76 110.13,112.61 110.13,112.1 109.88,111.85 109.88,111.47 109.69,111.28 109.69,109.91 109.11,109.32 v2(107.68,109.32) ; U11.AF16 v1(106.66,79.2)
  L03_SIG1 w0.155: v1(106.66,79.2) 111.59,79.2 111.59,79.22 116.02,83.66 116.02,83.99 115.85,84.17 115.59,84.17 111.05,79.63 110.73,79.63 110.58,79.78 110.58,79.98 115.55,84.96 116.04,84.96 117.12,86.04 117.12,91.32 116.97,91.47 116.79,91.47 116.61,91.29 116.61,87.54 116.48,87.41 116.17,87.41 116.04,87.54 116.04,91.8 116.34,92.1 116.34,95.43 117.21,96.3 117.21,97.22 117.64,97.65 117.64,101.69 117.58,101.74 117.58,102.12 116.48,103.22 116.48,108.22 116.12,108.59 112.9,108.59 112.89,108.59 110.96,108.59 110.5,108.13 110.5,107.57 109.97,107.04 109.23,107.04 108.8,107.47 108.8,108.2 v2(107.68,109.32)
P1_B4: length 79.9
  TOP w0.193: J2.71 v2(109.99,121.49) ; U11.AE16 v1(105.66,79.2)
  L05_SIG2 w0.102: v1(105.66,79.2) 105.37,79.2 104.98,79.59 103.48,79.59 103.21,79.32 103.21,78.09 103.5,77.81 103.66,77.81 104.27,77.2 104.27,77.04 104.5,76.81 104.66,76.81 104.74,76.73 107.22,76.73
  L05_SIG2 w0.155: 107.22,76.73 116.42,76.73 126.43,86.74 126.43,88.86 126.17,89.12 126.17,95.06 126.68,95.57 126.68,101.53 126.56,101.65 126.56,105.26 126.56,106.14 126.21,106.49 126.21,109.18 125.96,109.43 125.96,111.96 121.56,116.36 120.66,116.36 116.14,120.88 112.22,120.88 112.22,120.88 111.72,120.88 111.11,121.49 v2(109.99,121.49)
P1_B5: length 78.8
  TOP w0.193: J2.70 109.49,112.1 109.42,112.04 109.42,111.67 109.11,111.35 109.11,110.24 v2(108.9,110.03) ; U11.AD16 v1(104.66,79.2)
  L03_SIG1 w0.102: 107.28,78.64 105.39,78.64 105.21,78.46 105.21,77.95 105.06,77.8 104.34,77.8 104.17,77.98 104.17,78.55 104.04,78.67 103.4,78.67 103.27,78.8 103.27,79.49 103.44,79.67 104.2,79.67 v1(104.66,79.2)
  L03_SIG1 w0.155: 107.28,78.64 111.85,78.64 116.6,83.39 116.6,84.81 117.76,85.97 117.76,87.1 117.63,87.23 117.63,91.39 117.92,91.69 117.92,94.72 118.75,95.54 118.75,96.34 119.39,96.98 119.39,100.55 119.15,100.79 118.92,100.79 118.67,100.54 118.67,97.2 118.21,96.74 118.21,95.88 117.4,95.07 117.4,92.28 117.27,92.16 116.9,92.16 116.77,92.28 116.77,95.26 117.64,96.12 117.64,97.04 118.07,97.47 118.07,101.86 118.01,101.92 118.01,102.3 116.92,103.39 116.92,108.42 116.31,109.02 112.72,109.02 112.71,109.02 109.57,109.02 108.9,109.69 v2(108.9,110.03)
P1_B6: length 77.7
  TOP w0.193: J2.69 v2(109.49,118.69) ; U11.AC16 v1(103.66,79.2)
  L05_SIG2 w0.102: v1(103.66,79.2) 103.66,78.78 104.01,78.44 104.01,78.41 104.06,78.36 104.06,77.84 104.3,77.59 106.83,77.59 107.25,77.17 107.63,77.17
  L05_SIG2 w0.155: v2(109.49,118.69) 109.29,118.89 109.29,120.6 109.58,120.89 111.08,120.89 111.64,120.33 116.08,120.33 120.74,115.67 120.74,115.45 121.09,115.1 122.21,115.1 125.61,111.71 125.61,111.46 125.61,109.28 125.85,109.03 125.85,106.34 126.2,106 126.2,105.41 126.2,101.51 126.33,101.38 126.33,96.01 125.82,95.5 125.82,89.27 125.82,88.94 126.05,88.71 126.05,86.86 116.35,77.17 107.63,77.17
P1_B7: length 77.3
  TOP w0.193: v2(109.28,116) 108.99,115.71 J2.68 ; U11.AC15 v1(103.66,78.2)
  L03_SIG1 w0.102: v1(103.66,78.2) 103.66,78.09 104.15,77.6 106.98,77.6 107.15,77.43 107.63,77.43
  L03_SIG1 w0.155: v2(109.28,116) 109.46,115.82 110.21,115.82 110.58,115.45 110.58,114.96 110.15,114.52 110.15,112.22 110.06,112.13 110.06,112.01 109.89,111.84 109.89,111.35 110.8,110.44 112.71,110.44 113.58,111.31 113.58,111.58 114.66,112.66 116.75,112.66 116.88,112.79 116.88,113.07 116.75,113.2 114.9,113.2 114.77,113.34 114.77,113.65 114.94,113.83 117.11,113.83 117.85,113.08 117.85,112.41 117.46,112.02 115.84,112.02 115.71,111.89 115.71,111.51 115.84,111.38 117.28,111.38 117.46,111.21 117.46,109.8 119.62,107.64 119.62,102.21 120.58,101.24 120.58,100.31 120.68,100.21 120.68,96.45 120.04,95.81 120.04,95 119.22,94.18 119.22,91.49 120.04,90.67 120.04,86.42 117.89,84.27 117.89,82.79 112.59,77.48 107.68,77.48 107.63,77.43
P1_B8: length 79.7
  TOP w0.193: v2(108.8,117.91) 108.8,118.91 108.99,119.1 J2.67 ; U11.AB18 v1(102.66,81.2)
  L05_SIG2 w0.102: 107.63,78.03 107.39,78.03 106.83,78.59 106.28,78.59 106.06,78.82 106.06,79.36 105.83,79.59 105.69,79.59 105.68,79.6 105.42,79.6 105.22,79.8 103.51,79.8 103.27,80.04 103.27,80.31 102.66,80.92 v1(102.66,81.2)
  L05_SIG2 w0.155: v2(108.8,117.91) 109.26,117.45 109.26,117.09 110.39,115.96 110.39,115.74 110.74,115.39 111.23,115.39 111.58,115.74 111.58,115.75 111.88,116.04 111.88,117.46 112.4,117.99 112.95,117.99 113.51,118.54 116.65,118.54 118.79,116.4 118.79,115.3 119.4,114.7 120.27,114.7 120.74,114.24 121.62,114.24 124.85,111 124.85,108.99 125.14,108.7 125.14,106.84 125.14,106.05 125.35,105.84 125.49,105.7 125.49,101.21 125.62,101.08 125.62,96.37 123.94,94.69 123.94,92.12 124.83,91.23 124.83,89.41 124.5,89.08 124.5,86.32 116.21,78.03 107.63,78.03
P1_B9: length 78.1
  TOP w0.193: U11.AF18 v1(106.66,81.2) ; v2(108.83,112.2) 108.49,112.54 J2.66
  L05_SIG2 w0.102: 107.57,79.33 107.36,79.54 107.36,80.99 107.15,81.2 v1(106.66,81.2)
  L05_SIG2 w0.155: 107.57,79.33 116,79.33 119.19,82.52 119.19,83.73 120.07,84.61 121.28,84.61 123.43,86.76 123.43,89.71 123.51,89.79 123.51,90.72 123.39,90.83 123.19,90.83 122.87,90.51 122.87,87.17 122.69,87 122.42,87 122.24,87.17 122.24,89.03 122.39,89.19 122.39,89.68 122.24,89.83 122.24,91.99 121.81,92.41 121.81,93.07 122.64,93.91 122.64,95.1 123.56,96.01 123.56,96.33 123.94,96.72 123.94,108.18 122.41,109.7 122.41,109.81 121.89,110.33 121.89,110.49 121.22,111.16 121.22,111.29 121.21,111.29 121.21,112.64 120.91,112.94 120.2,112.94 119.78,113.36 118.88,113.36 117.51,114.73 117.51,114.76 117.5,114.76 117.5,115.67 117.13,116.04 115.96,116.04 115.42,115.51 115.16,115.51 114.19,114.54 112.62,114.54 112.17,114.09 112.1,114.09 112.06,114.05 110.93,114.05 110.73,113.84 109.19,113.84 108.83,113.48 v2(108.83,112.2)
P1_C0: length 78.8
  TOP w0.193: J2.65 108.49,119.52 108.48,119.51 108.48,119.21 108.28,119.01 107.98,119.01 v2(107.56,118.59) ; U11.AE18 v1(105.66,81.2)
  L05_SIG2 w0.102: 107.63,78.89 107.33,78.89 107.08,79.14 107.08,80.41 106.9,80.59 105.98,80.59 105.66,80.91 v1(105.66,81.2)
  L05_SIG2 w0.155: 107.63,78.89 116.07,78.89 119.62,82.45 119.62,83.55 120.25,84.18 121.35,84.18 123.78,86.61 123.78,89.58 123.99,89.78 123.99,90.85 123.08,91.76 123.08,94.92 124.42,96.26 124.42,96.26 124.91,96.75 124.91,100.79 124.43,101.27 124.43,108.24 124.4,108.27 124.4,108.33 122.42,110.3 122.42,112.42 121.47,113.37 120.38,113.37 119.96,113.79 119.08,113.79 117.93,114.94 117.93,115.97 116.93,116.97 116.22,116.97 115.19,115.94 114.1,115.94 113.74,116.3 113.74,116.32 113.53,116.53 113.04,116.53 112.86,116.34 112.86,115.39 111.99,114.52 110.8,114.52 110.65,114.37 107.89,114.37 107.39,114.87 107.39,115.53 108.18,116.32 108.18,117.96 107.56,118.59 v2(107.56,118.59)
P1_C1: length 79
  TOP w0.193: U11.AC19 v1(103.66,82.2) ; J2.64 v2(107.99,115.21)
  L05_SIG2 w0.102: 107.63,78.46 107.24,78.46 106.91,78.8 106.46,78.8 106.26,79 106.26,79.59 106.04,79.81 105.5,79.81 105.27,80.04 105.27,80.16 104.81,80.62 104.33,80.62 104.06,80.89 104.06,81.68 103.66,82.08 v1(103.66,82.2)
  L05_SIG2 w0.155: v2(107.99,115.21) 110.31,115.21 110.56,114.95 111.81,114.95 112.43,115.57 112.43,117.23 112.7,117.51 113.72,117.51 113.96,117.26 113.96,116.73 114.32,116.37 115.01,116.37 115.35,116.71 115.35,117.47 115.53,117.65 116.93,117.65 118.36,116.22 118.36,115.12 119.22,114.27 120.09,114.27 120.56,113.8 121.54,113.8 123.72,111.63 123.72,110.99 123.28,110.55 123.28,109.95 124.75,108.48 124.75,108.43 124.79,108.4 124.79,106.69 124.79,101.41 125.26,100.94 125.26,96.57 124.7,96.01 123.58,94.89 123.58,94.82 123.51,94.74 123.51,91.94 124.42,91.03 124.42,89.62 124.14,89.34 124.14,86.46 121.42,83.75 120.43,83.75 120.05,83.37 120.05,82.38 116.14,78.46 107.63,78.46
P1_C2: length 77.8
  TOP w0.193: U11.AF20 v1(106.66,83.2) ; J2.63 v2(107.99,121.49)
  L05_SIG2 w0.155: v1(106.66,83.2) 106.66,82.89 107.01,82.54 107.94,82.54 108.71,81.77 108.71,80.97 108.93,80.76 109.9,80.76 110.1,80.96 110.1,81.41 110.57,81.87 116.93,81.87 117.89,82.83 117.89,84.27 120.83,87.21 120.83,88.54 120.48,88.89 120.48,89.19 120.48,89.98 120.83,90.33 120.83,91.56 120.52,91.88 120.52,93.61 121.35,94.44 121.35,96.11 122.87,97.64 122.87,99.53 121.65,100.75 121.65,101.83 122.11,102.29 122.11,108.17 119.92,110.36 119.92,111.35 119.65,111.62 119.35,111.62 118.73,111 118.24,111 117.89,111.35 117.89,111.84 117.92,111.87 117.92,112.49 116.37,114.03 115.51,114.03 114.73,113.25 113.3,113.25 112.34,112.29 112.33,112.29 110.77,110.74 107.31,110.74 106.54,111.51 106.54,112.32 106.53,112.33 106.53,117.98 106.01,118.5 106.01,119.04 105.84,119.21 105.84,119.7 106.19,120.05 106.75,120.05 107.99,121.29 v2(107.99,121.49)
P1_C3: length 78.1
  TOP w0.193: J2.62 v2(107.49,112.4) ; U11.AF19 v1(106.66,82.2)
  L05_SIG2 w0.155: v2(107.49,112.4) 107.49,111.96 108.28,111.17 109.28,111.17 109.94,111.83 109.94,112.74 110.11,112.91 111.02,112.91 111.29,113.18 112.33,113.18 112.33,113.18 112.48,113.18 112.98,113.68 114.55,113.68 115.38,114.51 116.51,114.51 118.52,112.5 119.41,112.5 120.35,111.56 120.35,110.54 122.52,108.38 122.52,102.2 122.01,101.69 122.01,100.9 123.23,99.67 123.23,97.01 122.52,96.3 122.52,96.29 121.78,95.55 121.78,94.26 120.95,93.43 120.95,92.05 121.19,91.81 121.19,90.18 120.84,89.83 120.84,89.04 121.19,88.69 121.19,85.82 120.85,85.48 119.72,85.48 118.33,84.09 118.33,82.66 117.1,81.44 110.75,81.44 110.62,81.31 110.62,80.91 110.75,80.79 115.9,80.79 116.1,80.59 116.1,80.43 115.85,80.19 108.5,80.19 108.26,80.43 108.26,81.41 107.63,82.04 107.63,82.09 107.52,82.2 v1(106.66,82.2)
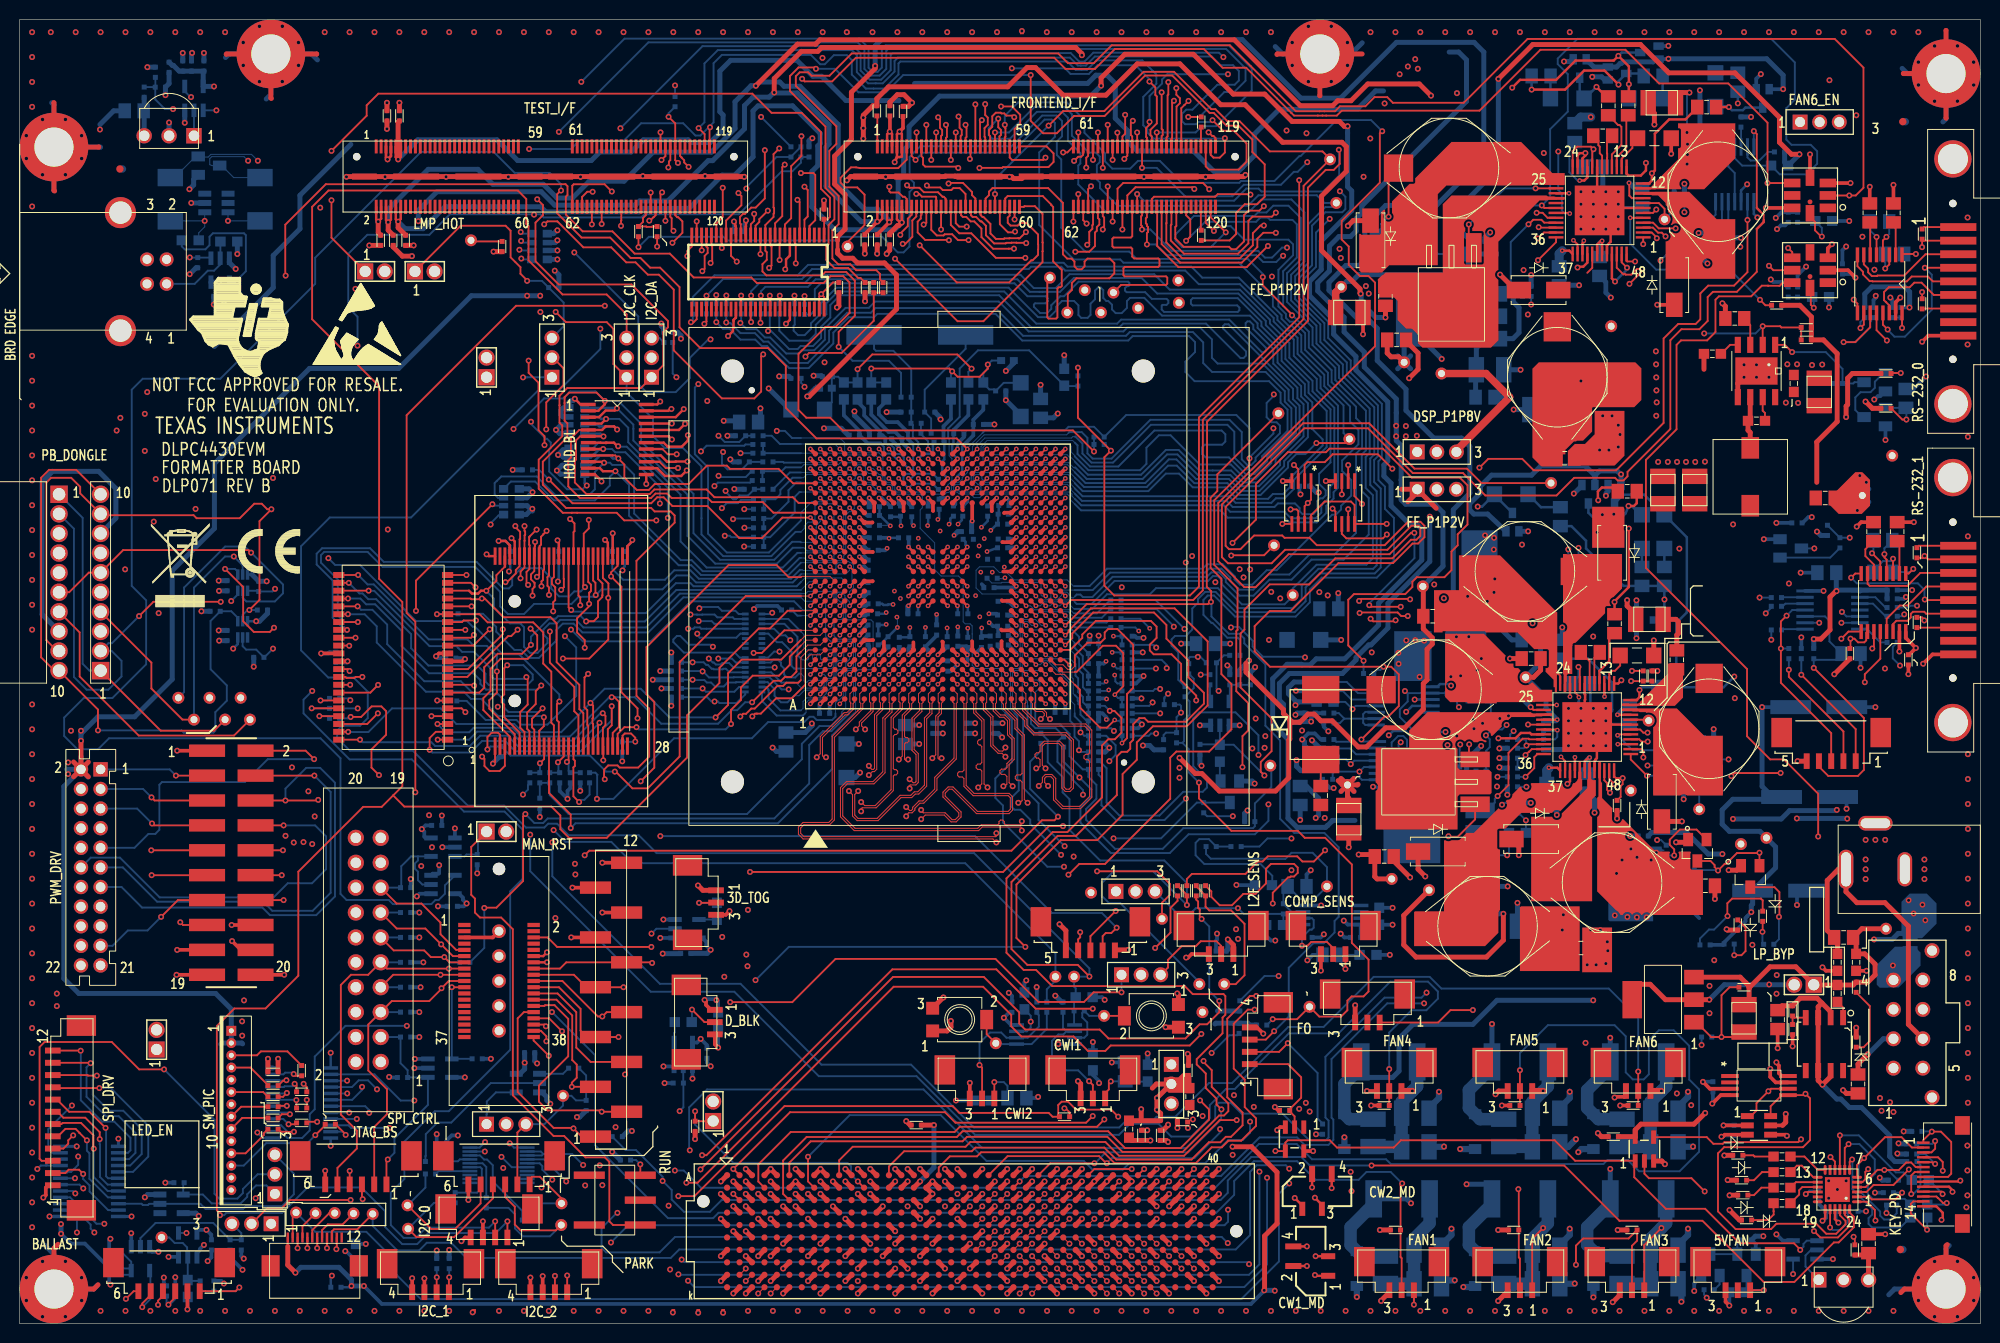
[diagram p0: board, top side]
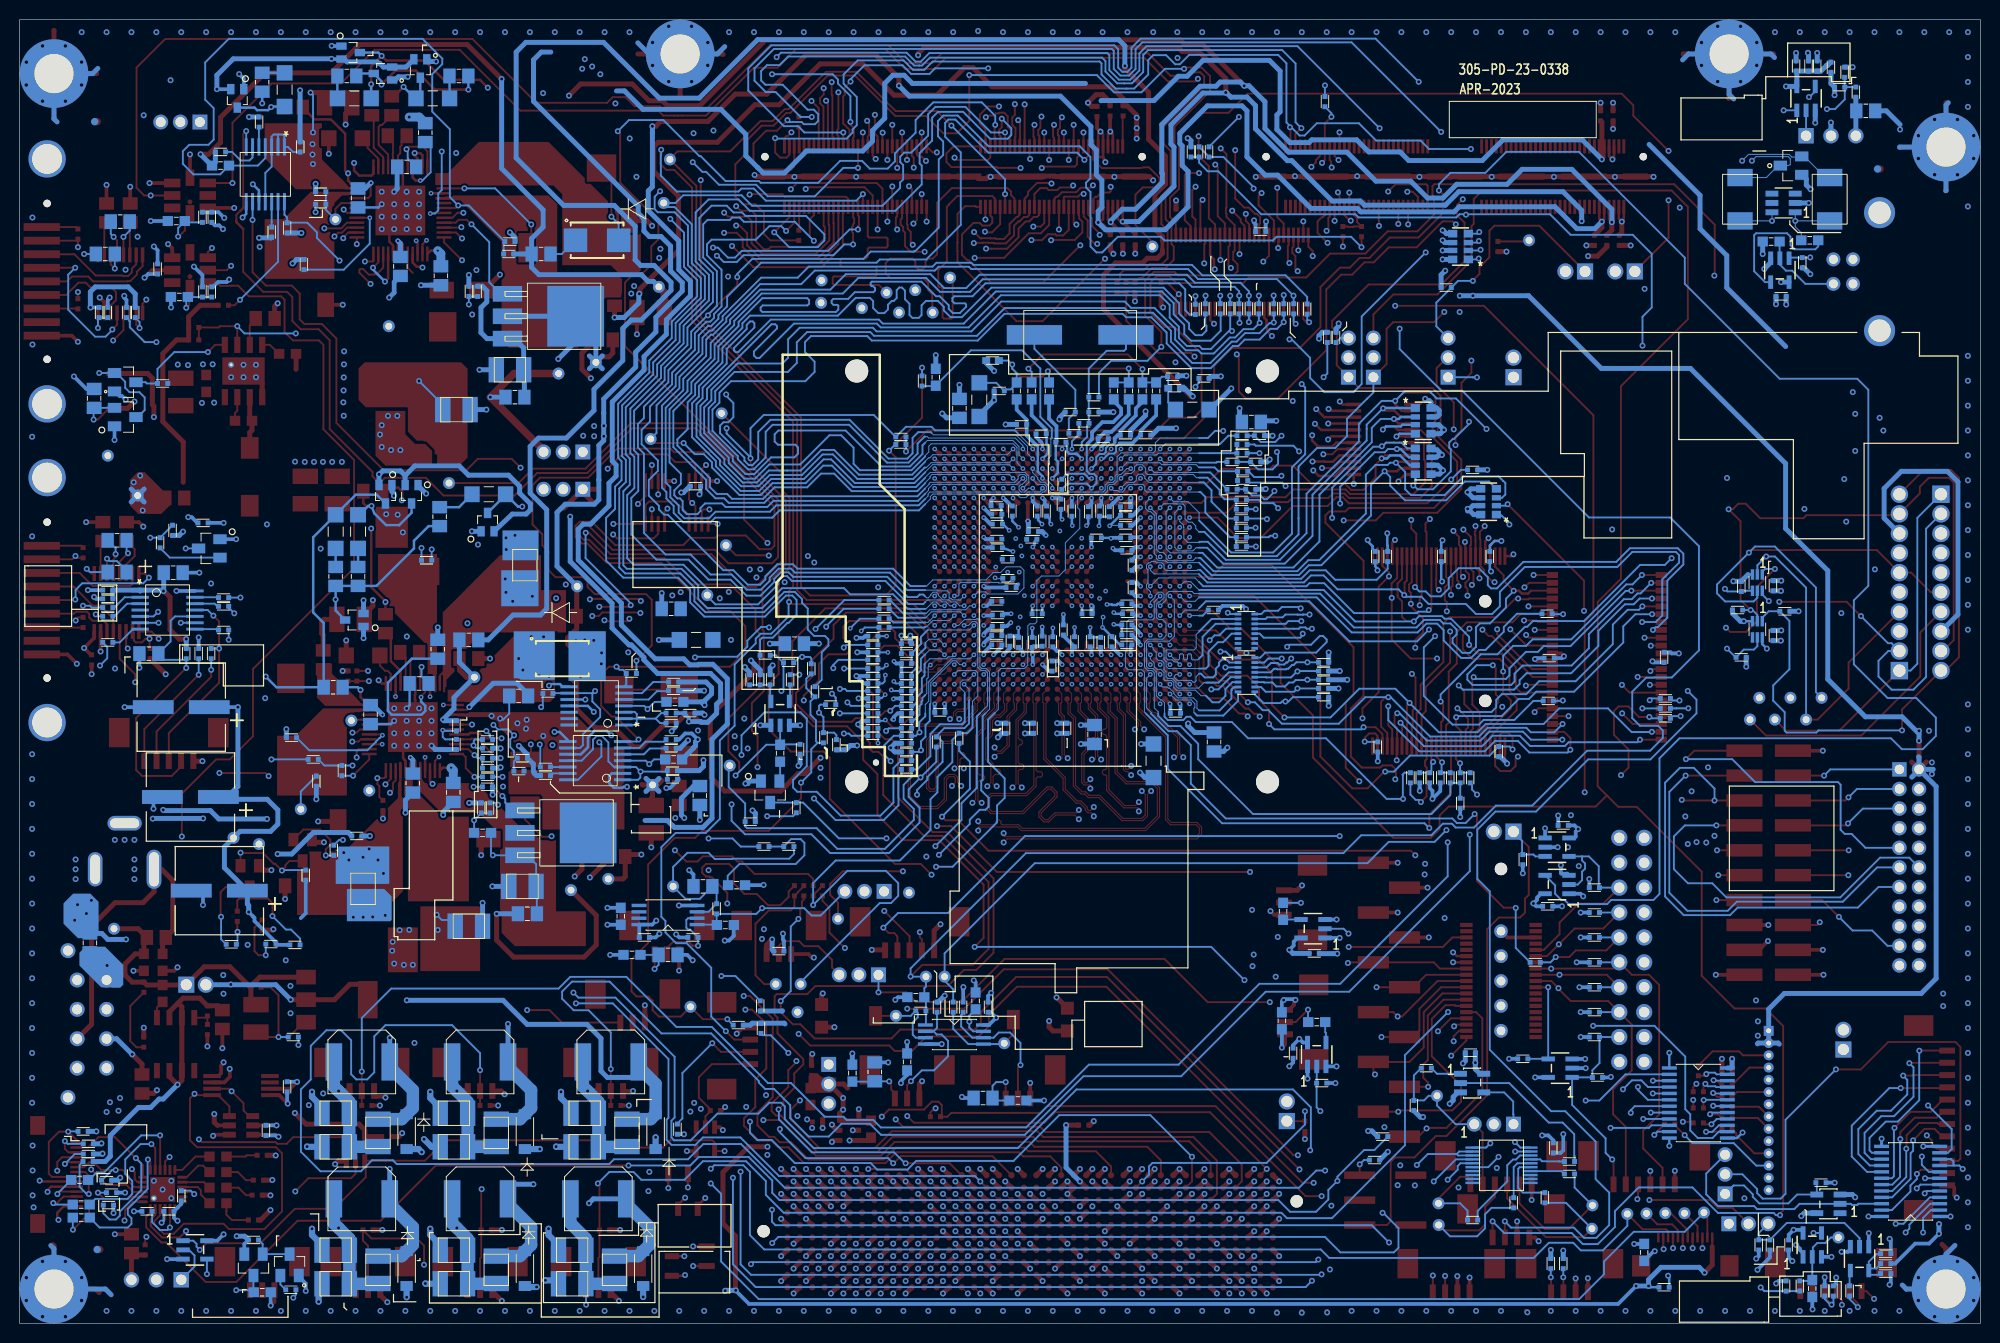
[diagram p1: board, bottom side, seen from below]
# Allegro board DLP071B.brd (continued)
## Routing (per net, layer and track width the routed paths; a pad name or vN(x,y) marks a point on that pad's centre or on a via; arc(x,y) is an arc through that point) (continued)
P1_C4: length 78.4
  TOP w0.193: v2(106.44,119.46) 106.87,119.46 J2.61 ; U11.AE19 v1(105.66,82.2)
  L05_SIG2 w0.155: v2(106.44,119.46) 106.44,118.68 107.75,117.37 107.75,116.5 106.96,115.71 106.96,114.42 107.53,113.84 107.84,113.84 108.23,113.45 108.23,111.95 108.58,111.6 109.08,111.6 109.46,111.98 109.46,113.25 109.62,113.41 110.91,113.41 111.11,113.61 112.3,113.61 112.8,114.11 114.37,114.11 115.33,115.07 115.6,115.07 116.13,115.61 116.76,115.61 117.07,115.3 117.07,114.56 118.7,112.93 119.59,112.93 120.01,112.51 120.51,112.51 120.78,112.24 120.78,110.72 122.87,108.63 122.87,102.05 122.36,101.54 122.36,101.04 123.57,99.84 123.57,96.85 122.87,96.15 122.87,95.94 122.21,95.28 122.21,94.09 121.38,93.25 121.38,92.3 121.6,92.08 121.6,90.09 121.2,89.68 121.2,89.19 121.55,88.84 121.55,85.67 120.97,85.09 119.94,85.09 118.76,83.91 118.76,82.59 115.92,79.76 108.01,79.76 107.83,79.94 107.83,81.23 107.43,81.64 106.08,81.64 105.66,82.06 v1(105.66,82.2)
P1_C5: length 77.6
  TOP w0.193: U11.AD19 v1(104.66,82.2) ; v2(89.29,108.61) 95.67,102.23 98.31,102.23 104.34,108.27 104.34,109.36 104.35,109.37 104.35,110.26 104.34,110.27 104.34,113.19 103.56,113.97 102.5,113.97 102.43,113.9 J2.60
  L05_SIG2 w0.102: 89.02,90.17 89.26,89.93 89.26,89.04 89.5,88.81 89.92,88.81 90.27,88.46 90.27,88.04 90.5,87.81 90.92,87.81 91.27,87.46 91.27,87.04 91.5,86.81 92.83,86.81 92.93,86.91 93.25,86.91 93.86,86.29 93.86,85.44 94.5,84.81 94.92,84.81 95.27,84.46 95.27,84.04 95.5,83.81 96.21,83.81 96.42,83.6 96.98,83.6 98.2,82.38 100.81,82.38 101.38,81.81 101.86,81.81 102.27,82.22 102.27,82.36 102.5,82.59 103.83,82.59 104.22,82.2 v1(104.66,82.2)
  L05_SIG2 w0.155: v2(89.29,108.61) 88.66,107.98 86.5,107.98 85.52,106.99 85.52,106.37 85.8,106.1 86.89,106.1 87.17,105.82 87.17,105.43 86.89,105.16 85.8,105.16 85.52,104.88 85.52,101.82 85.8,101.54 86.49,101.54 86.77,101.27 86.77,98.63 86.18,98.04 86.18,94.7 87.31,93.57 87.31,93.49 87.31,93.49 87.31,92.18 86.71,91.58 86.71,91.16 87.17,90.7 88.49,90.7 89.02,90.17
P1_C6: length 77.6
  TOP w0.193: v2(97.9,117.87) 98.01,117.87 98.02,117.88 100.24,117.88 100.32,117.96 104.95,117.96 105.47,118.48 105.47,119.35 104.75,120.07 J2.59 ; U11.AF21 v1(106.66,84.2)
  L05_SIG2 w0.102: v1(106.66,84.2) 106.36,84.2 105.76,83.6 104.42,83.6 104.06,83.96 104.06,84.36 103.62,84.8 101.39,84.8 101.06,84.46 101.06,84.04 100.83,83.81 100.2,83.81 100,83.6 98.7,83.6 98.27,84.04 98.27,84.17 98.07,84.38 98.07,85.38 97.84,85.6 97.42,85.6 97.07,85.95 97.07,86.38 96.84,86.6 96.42,86.6 96.19,86.83 95.85,86.83 95.83,86.81 95.5,86.81 95.27,87.04 95.27,87.46 94.84,87.89 94.84,88.99 94.22,89.61 94.1,89.61 94.05,89.67 94.04,89.67 93.89,89.81 93.73,89.81 93.58,89.96 93.53,89.96 93.32,90.17
  L05_SIG2 w0.155: 93.32,90.17 92.69,90.17 92.38,90.48 92.38,92.85 93.33,93.8 93.33,95.07 93.84,95.58 93.84,98.31 94.28,98.75 95.83,98.75 97.38,100.3 97.38,100.84 97.65,101.11 98.87,101.11 99.14,101.39 99.14,101.77 98.87,102.05 97.65,102.05 97.38,102.33 97.38,102.71 97.65,102.99 98.87,102.99 99.14,103.27 99.14,103.65 98.87,103.93 97.65,103.93 97.38,104.21 97.38,104.59 97.65,104.87 98.87,104.87 99.14,105.14 99.14,105.53 98.87,105.81 97.65,105.81 97.38,106.08 97.38,106.62 96.89,107.1 96.49,107.1 96.49,107.13 96.2,107.41 96.2,108.49 96.12,108.57 96.12,108.61 95.29,109.44 94.38,109.44 93.76,110.07 93.76,110.66 93.27,111.15 93.27,112.01 94.15,112.89 94.15,113.37 94.91,114.12 95.46,114.12 96.71,115.37 96.71,116.67 v2(97.9,117.87)
P1_C7: length 77.5
  TOP w0.193: U11.AE21 v1(105.66,84.2) ; J2.58 v2(101.49,112.62)
  L05_SIG2 w0.102: 95.38,89.74 95.7,89.74 96.07,89.37 96.07,88.48 96.27,88.27 96.27,88.04 96.5,87.81 96.92,87.81 97.27,87.46 97.27,87.04 97.5,86.81 97.92,86.81 98.27,86.46 98.27,86.04 98.5,85.81 98.92,85.81 99.27,85.46 99.27,85.04 99.5,84.81 99.83,84.81 100.27,85.25 100.27,85.36 100.51,85.6 100.91,85.6 101.26,85.95 101.26,86.35 101.5,86.59 105.16,86.59 105.26,86.49 105.26,85.76 105.06,85.56 105.06,85.04 104.83,84.81 104.5,84.81 104.27,84.58 104.27,84.04 104.5,83.81 104.83,83.81 105.22,84.2 v1(105.66,84.2)
  L05_SIG2 w0.155: v2(101.49,112.62) 102.18,113.31 102.18,115.57 102.05,115.7 100.54,115.7 100.41,115.57 100.41,115.21 100.58,115.04 101.43,115.04 101.6,114.88 101.6,114.65 101.43,114.49 100.58,114.49 100.41,114.32 100.41,114.09 100.58,113.93 101.43,113.93 101.6,113.76 101.6,113.53 101.43,113.37 100.58,113.37 100.41,113.2 100.41,111.41 100.24,111.23 100.24,111.22 99.48,110.46 99.48,109.15 100.04,108.59 100.51,108.59 100.98,108.12 100.98,106.03 102.92,104.09 102.92,103.06 102.84,102.98 102.84,102.34 102.98,102.19 102.98,97.43 103.11,97.3 103.39,97.3 103.51,97.43 103.51,101.1 103.66,101.25 103.93,101.25 104.1,101.08 104.1,97.58 104.34,97.34 104.34,96.54 104.18,96.39 103.7,96.39 103.47,96.15 103.47,95.06 103.24,94.83 101.29,94.83 100.99,95.13 100.83,95.13 100.43,95.13 99.41,96.15 98.21,96.15 97.97,95.91 97.97,95.62 97.74,95.39 96.5,95.39 95.42,94.31 95.42,93.79 95.06,93.43 94.75,93.43 94.4,93.08 94.4,92.66 94.74,92.32 94.74,90.38 95.38,89.74
P1_C8: length 78.4
  TOP w0.193: v2(100.1,124.15) 101.22,124.15 102.06,123.3 102.06,122.41 101.49,121.84 J2.57 ; U11.AE20 v1(105.66,83.2)
  L05_SIG2 w0.102: v1(105.66,83.2) 105.31,83.2 104.91,82.8 104.36,82.8 104.2,82.95 104.2,83.22 103.83,83.59 102.5,83.59 102.06,83.15 102.06,83.04 101.83,82.81 100.35,82.81 100.34,82.79 98.37,82.79 97.25,83.9 97.25,84.19 96.84,84.6 96.42,84.6 96.21,84.81 95.5,84.81 95.27,85.04 95.27,85.46 94.92,85.81 94.5,85.81 94.27,86.04 94.27,86.46 93.25,87.48 93.25,87.7 93.15,87.81 91.5,87.81 91.27,88.04 91.27,88.65 91.11,88.81 90.5,88.81 90.27,89.04 90.27,89.66
  L05_SIG2 w0.155: 90.27,89.66 90.27,92.46 89.74,93 89.74,95.7 90.6,96.57 90.6,97.03 90.33,97.31 89.86,97.31 89.58,97.58 89.58,97.97 89.86,98.25 90.33,98.25 90.6,98.52 90.6,98.91 90.33,99.19 89.86,99.19 89.58,99.46 89.58,99.85 89.86,100.13 90.33,100.13 90.6,100.4 90.6,100.79 90.33,101.07 89.86,101.07 89.58,101.34 89.58,101.73 89.86,102.01 90.33,102.01 90.6,102.28 90.6,103.97 90.33,104.24 90.1,104.24 89.82,104.52 89.82,104.91 90.1,105.18 90.33,105.18 90.6,105.46 90.6,105.85 90.33,106.12 90.1,106.12 89.82,106.4 89.82,106.79 90.1,107.06 90.33,107.06 90.6,107.34 90.6,107.75 90.87,108.01 90.87,115.6 91.12,115.85 91.12,115.98 91.24,116.1 91.24,117.15 90.31,118.08 90.31,121.3 90.35,121.33 90.35,122.92 90.92,123.49 91.45,123.49 91.91,123.95 96.48,123.95 96.51,123.93 96.84,123.6 97.54,123.6 97.72,123.78 98.82,123.78 99.17,124.13 100.1,124.13 100.1,124.14 v2(100.1,124.15)
P1_C9: length 78.8
  TOP w0.193: U11.AD20 v1(104.66,83.2) ; J2.56 100.99,113.01 100.79,112.81 100.79,112.28 101.07,111.99 101.81,111.99 102.08,112.26 102.08,112.27 102.7,112.27 103.88,111.09 103.88,110.08 103.89,110.07 103.89,109.56 103.88,109.55 103.88,109 103.33,108.45 103.2,108.45 100.95,106.2 95.59,106.2 v2(91.81,109.98)
  L05_SIG2 w0.102: v1(104.66,83.2) 104.53,83.2 103.92,83.81 102.24,83.81 102.04,83.6 101.48,83.6 101.04,83.16 100.42,83.16 100.25,82.99 98.45,82.99 97.46,83.99 97.46,84.27 96.92,84.81 96.5,84.81 96.27,85.04 96.27,85.38 96.05,85.6 95.42,85.6 95.07,85.95 95.07,86.38 94.84,86.6 94.42,86.6 93.92,87.1 93.92,87.86 94.06,88 94.06,88.36 93.82,88.6 92.42,88.6 92.21,88.81 91.5,88.81 91.27,89.04 91.27,89.15 90.7,89.72
  L05_SIG2 w0.155: 90.7,89.72 90.7,92.78 90.31,93.17 90.31,95.16 91.25,96.1 91.25,96.27 91.53,96.55 92.42,96.55 92.69,96.83 92.69,97.21 92.42,97.49 91.53,97.49 91.25,97.76 91.25,98.15 91.53,98.43 92.42,98.43 92.69,98.7 92.69,99.09 92.42,99.37 91.53,99.37 91.25,99.64 91.25,100.03 91.53,100.31 92.42,100.31 92.69,100.58 92.69,100.97 92.42,101.25 91.53,101.25 91.25,101.52 91.25,101.91 91.53,102.19 92.42,102.19 92.69,102.46 92.69,102.85 92.42,103.13 91.53,103.13 91.25,103.4 91.25,103.79 91.53,104.07 92.42,104.07 92.69,104.34 92.69,104.73 92.42,105.01 91.53,105.01 91.25,105.28 91.25,105.67 91.53,105.95 92.42,105.95 92.69,106.22 92.69,106.61 92.42,106.89 91.53,106.89 91.25,107.16 91.25,107.55 91.53,107.83 92.42,107.83 92.69,108.1 92.69,108.49 92.42,108.77 91.53,108.77 91.25,109.04 91.25,109.43 v2(91.81,109.98)
P1_HSYNC: length 78.8
  TOP w0.193: U11.AD21 v1(104.66,84.2) ; TP10.1 112.35,105.94 116.94,105.94 117.06,106.07 117.06,106.68 116.94,106.81 112.72,106.81 112.59,106.93 112.59,107.64 112.72,107.77 116.14,107.77 116.27,107.9 116.27,108.51 116.14,108.64 113.68,108.64 113.49,108.83 113.49,109.63 113.36,109.75 111.59,109.75 111.46,109.88 111.46,110.65 111.59,110.77 113.36,110.77 113.49,110.9 J2.86
  L05_SIG2 w0.102: v1(104.66,84.2) 105.26,84.8 105.26,85.47 105.39,85.6 105.93,85.6 106.06,85.72 106.06,86.44 106.16,86.54 106.16,87.27 106.48,87.59 106.83,87.59 106.85,87.57 107.45,87.57
  L05_SIG2 w0.155: 107.45,87.57 107.63,87.75 108.41,87.75 109.22,86.94 113.09,86.94 113.34,87.18 113.34,91.94 113.63,92.23 113.91,92.23 114.16,91.97 114.16,88.11 114.54,87.73 114.77,87.73 114.93,87.89 114.93,94.88 115.35,95.3 116.5,95.3 116.83,95.63 116.83,100.1 115.3,101.63 113.21,101.63 112.22,102.62 112.22,103.69 111.87,104.04 109.81,104.04 109.64,104.21 109.64,105.6 109.76,105.72 110.22,105.72 110.35,105.6 110.35,104.81 110.47,104.69 111.1,104.69 TP10.1
P1_VSYNC: length 77.7
  TOP w0.193: v2(104.64,118.92) 104.41,118.69 101.23,118.69 100.99,118.94 J2.55 ; U11.AC20 v1(103.66,83.2)
  L05_SIG2 w0.102: 107.63,83.31 107.29,83.31 106.95,83.66 106.56,83.66 106.27,83.36 106.27,83.22 105.64,82.59 104.27,82.59 104,82.87 104,82.88 103.68,83.2 v1(103.66,83.2)
  L05_SIG2 w0.155: v2(104.64,118.92) 106.01,117.56 106.01,117.02 106.11,116.92 106.11,111.21 107.34,109.97 108.12,109.97 108.66,109.44 110.08,109.44 111.65,111 114.73,111 114.74,111 116.79,111 117.16,110.63 117.16,107.44 TP12.1 118.82,107.02 118.82,109.15 119.21,109.55 120,109.55 120.87,108.69 120.87,101.55 120.1,100.79 120.1,87.09 116.33,83.31 107.63,83.31
P1P1V: length 98.4
  TOP w0.254: 97.11,69.63 97.16,69.58 ; U11.L11 v1(90.66,73.2) ; 91.17,69.48 91.16,69.47 ; U11.T11 v1(96.66,73.2) ; U11.T16 v1(96.66,79.2) ; U11.L16 v1(90.66,79.2)
  TOP w0.381: v1(92.66,84.2) U11.N21 93.16,82.9 93.18,82.88 ; v1(85.66,72.2) U11.F10 86.94,72.7 86.94,72.7 ; 90.17,82.86 90.16,82.86 U11.K21 v1(89.66,84.2) ; 91.16,69.47 U11.L6 v1(90.66,68.2) ; 100.16,69.58 U11.Y6 v1(100.66,68.2) ; 94.11,69.56 94.16,69.51 U11.P6 v1(93.66,68.2) ; v1(97.66,68.2) U11.U6 97.16,69.58 ; 96.22,82.95 96.16,83.01 U11.T21 v1(96.66,84.2) ; 100.24,79.71 100.25,79.7 U11.AA17 v1(101.66,80.2) ; v1(85.66,82.2) U11.F19 86.97,81.7 86.99,81.71 ; 99.15,82.86 99.16,82.87 U11.W21 v1(99.66,84.2) ; 100.11,70.78 100.19,70.7 U11.AA8 v1(101.66,70.2) ; v1(87.66,68.2) U11.H6 88.16,69.54 ; v1(85.66,79.2) U11.F16 87.01,78.7 87.02,78.69 ; 87.04,69.7 87.04,69.7 U11.F7 v1(85.66,69.2) ; v1(101.66,73.2) U11.AA11 100.25,73.7 100.18,73.77 ; 100.41,82.66 100.45,82.7 U11.AA20 v1(101.66,83.2) ; v1(101.66,77.2) U11.AA14 100.33,76.7 ; v1(85.66,75.2) U11.F13 86.99,75.7 87.02,75.72 ; v1(86.66,84.2) U11.G21 87.16,82.83 87.15,82.82
  TOP w0.508: 134.78,54.27 TP35.1 ; TP35.1 136.11,55.59 ; TP35.1 136.11,54.27 ; TP35.1 136.46,54.93 136.53,54.99 ; TP35.1 134.78,55.59 ; TP35.1 135.45,53.72 135.57,53.59 ; TP35.1 134.94,54.93 134.49,55.37 ; 140.97,85.09 J13.1 ; J13.1 142.56,84.77 141.6,83.82 ; J13.1 144.49,83.16
  L07_PWR w0.508: 133.87,56.49 133.88,56.49 TP35.1 ; 141.74,84.28 J13.1 ; J13.1 141.74,85.9 ; J13.1 143.37,84.28 ; J13.1 143.37,85.9 ; TP35.1 136.18,55.66 136.2,55.66 ; TP35.1 136.67,53.7 136.71,53.7 ; TP35.1 134.18,53.67 134.15,53.67
  BOTTOM w0.254: C588.1 96.72,73.14 v1(96.66,73.2) ; v1(96.66,79.2) 96.48,79.38 96.48,79.73 96.24,79.97 C559.1
  BOTTOM w0.381: v1(90.66,68.2) 90.66,68.87 C594.1 ; v1(93.66,68.2) 94.04,68.58 94.18,68.58 C590.1 ; C566.1 89.66,83.58 v1(89.66,84.2) ; C601.1 86.28,72.2 v1(85.66,72.2) ; C563.1 92.67,84.12 92.66,84.13 v1(92.66,84.2) ; v1(87.66,68.2) 87.77,68.2 C596.1 ; v1(85.66,69.2) 85.85,69.39 85.85,69.55 C599.1 ; v1(101.66,83.2) 101.51,83.05 101.51,83.04 101.02,82.55 C553.1 ; C583.1 101.14,70.76 101.25,70.76 101.66,70.35 v1(101.66,70.2) ; C565.1 90.69,79.23 v1(90.66,79.2) ; C581.1 99.81,69.05 v1(100.66,68.2) ; C571.1 86.2,79.2 v1(85.66,79.2) ; v1(97.66,68.2) 97.66,68.5 C586.1 ; v1(99.66,84.2) 99.5,84.04 99.48,84.04 98.83,83.39 C558.1 ; C569.1 86.46,81.41 v1(85.66,82.2) ; v1(101.66,73.2) 101.31,73.2 C579.1 ; C554.1 101.47,80.01 v1(101.66,80.2) ; v1(85.66,75.2) 86.04,75.58 C602.1 ; R664.2 132.73,59.56 132.11,60.18 131.44,60.18 v2(130.82,59.56) ; v1(96.66,84.2) 96.66,83.85 C561.1
  BOTTOM w0.508: 134.78,55.59 TP35.1 ; TP35.1 136.11,54.27 ; TP35.1 136.11,55.59 ; TP35.1 134.78,54.27 ; C635.1 131.25,54.81 132.5,53.57 132.5,51.85 v2(132.21,51.56) ; v1(90.66,73.2) 90.6,73.14 C593.1 ; C544.1 86.66,84.2 v1(86.66,84.2) ; C634.2 131.25,58.7 131.25,58.74 131.06,58.93 131.06,59.32 v2(130.82,59.56) ; v2(100.6,97.16) 101.41,97.97 R536.1
  vias: v1(100.44,77.15) v2(112.42,75.1) v2(118.95,77.62) v2(119.59,78.28) v2(124.44,76.94) v2(124.84,76.1) v2(125.52,76.91) v2(127.44,69.72) v2(130.81,60.48) v2(132.58,74.6) v2(133.12,51.56) v2(133.43,74.26) v2(150.7,54.76)
P1P2V_PMD2: length 112.9
  TOP w0.508: v2(150.84,126.95) 154.35,130.46 165.33,130.46 168.22,127.57 174.97,127.57 179.51,123.03 179.51,120.48 180.72,119.27 v2(181.55,119.27)
  TOP w0.762: C15.2 134.24,105.18 TP14.1
  L05_SIG2 w0.508: TP14.1 134.8,104.72 134.24,104.17 134.24,95.48 137.67,92.05 137.67,86.96 141.22,83.41 144.88,83.41 J13.3
  BOTTOM w0.508: R527.2 R525.2 ; R527.2 147.78,107.73 147.03,106.98 136.59,106.98 135.9,106.3 135.36,106.3 TP14.1 ; R527.2 147.78,110.67 146.6,111.84 146.6,113.58 150.84,117.82 v2(150.84,126.95) ; v2(181.55,119.27) 180.39,118.11 C510.2 180.04,118.45 R509.2
P1P8V: length 118.9
  TOP w0.193: 85.66,67.23 v1(85.66,67.2)
  TOP w0.381: U11.M5 v1(91.66,67.2) ; U11.W6 v1(99.66,68.2) ; U11.C1 v1(82.66,63.2) ; v1(96.66,68.2) U11.T6 ; v1(101.66,67.2) U11.AA5 ; v1(105.66,63.2) U11.AE1 ; v1(92.66,68.2) U11.N6 ; U11.H5 v1(87.66,67.2) ; U11.G6 v1(86.66,68.2) ; U11.F5 86.14,67.7 85.66,67.23 ; U11.AA13 v1(101.66,75.2) ; U11.F14 v1(85.66,77.2) ; U11.U21 v1(97.16,81.84) ; v1(96.66,67.2) U11.T5 ; U11.P21 v1(94.66,84.2) ; U11.P5 v1(93.66,67.2) ; U11.K6 v1(89.66,68.2) ; U11.H21 v1(87.66,84.2)
  TOP w0.508: TP40.1 141.19,41.62 141.19,38.61 142.43,37.36 149.62,37.36 151.35,39.09 v2(151.35,41.78)
  L03_SIG1 w0.508: TP40.1 143.76,44.24 144.38,44.86 144.38,46.49 137.29,53.59 137.29,55.06 137.43,55.2 137.43,59.04 137.63,59.25 137.63,64.22 139.9,66.5 139.9,68.06 139.52,68.45 139.52,74.1 140.63,75.2 140.63,85.5 142.56,87.43 J12.1
  L07_PWR w0.508: J12.1 143.37,88.09 ; J12.1 141.74,89.71 ; J12.1 143.37,89.71 ; J12.1 141.74,88.09
  BOTTOM w0.381: v1(96.66,67.2) v1(96.66,68.2) 96.71,68.25 C587.1 96.58,69.08 C589.1 ; v1(85.66,77.2) 86.17,77.2 C572.1 ; v1(93.66,67.2) 94.04,67.58 C626.1 ; v1(99.66,68.2) 99,68.87 C584.1 ; C600.1 86.66,69.09 v1(86.66,68.2) ; v1(82.66,63.2) 82.63,63.16 C628.1 ; C585.1 99.4,75.07 101.53,75.07 v1(101.66,75.2) ; C623.1 105.61,63.15 v1(105.66,63.2) ; v1(89.66,68.2) 89.73,68.26 C595.1 ; v1(92.66,68.2) 92.66,68.74 C592.1 93.54,70.15 C591.1 ; v1(94.66,84.2) 93.9,84.2 C542.1 ; v1(87.66,84.2) 87.91,84.2 88.44,83.67 88.49,83.67 C567.1
  BOTTOM w0.508: C627.1 v2(94.17,61.23) ; C624.1 v2(100.25,61.23) ; C637.1 v2(85.61,59.11) ; C560.1 97.1,81.79 v1(97.16,81.84) ; v2(80.8,61.19) 80.81,61.19 80.8,61.2 80.84,61.2 80.84,60.98 80.13,60.27 C638.1 ; R702.1 v2(151.35,41.78) ; C636.1 v2(91.76,61.04) ; C625.1 v2(97.46,61.23)
P1P8V_PMD2: length 17.3
  TOP w0.762: J12.3 146.56,89.06 v2(151.99,94.49) 149.57,96.9 TP17.1
  BOTTOM w0.508: R551.1 v2(151.99,94.49)
P2_A0: length 78
  TOP w0.193: J2.45 98.49,120.98 98.42,121.05 98.42,121.93 98.76,122.27 98.76,123.01 98.49,123.28 v2(98.49,124.38) ; U11.AB19 v1(102.66,82.2)
  L05_SIG2 w0.102: 88.39,90.17 89.06,89.51 89.06,88.96 89.42,88.6 89.84,88.6 90.07,88.38 90.07,87.95 90.42,87.6 90.84,87.6 91.07,87.38 91.07,86.95 91.42,86.6 92.91,86.6 93.01,86.7 93.17,86.7 93.66,86.21 93.66,85.36 94.42,84.6 94.84,84.6 95.07,84.38 95.07,83.95 95.42,83.6 96.13,83.6 96.33,83.4 96.89,83.4 98.11,82.18 100.72,82.18 101.3,81.6 101.94,81.6 102.54,82.2 v1(102.66,82.2)
  L05_SIG2 w0.155: 88.39,90.17 88.23,90.34 87.03,90.34 86.63,90.74 85.9,91.47 85.9,92.08 86.07,92.26 86.65,92.26 86.95,92.56 86.95,92.84 86.96,92.84 86.96,93.34 86.95,93.34 86.95,93.42 86.53,93.85 83.98,93.85 83.41,94.41 83.41,96.29 85,97.88 85.16,97.88 85.97,98.7 85.97,99.09 85.17,99.9 85.17,107.14 86.87,108.84 86.87,112.63 87.7,113.47 87.7,123.33 88.97,124.6 89.02,124.6 89.54,125.12 97.57,125.12 98.31,124.38 v2(98.49,124.38)
P2_A1: length 78.3
  TOP w0.193: U11.AE23 v1(105.66,86.2) ; v2(102.64,111.33) 102,110.69 101.88,110.69 101.87,110.71 100.98,110.71 100.97,110.69 100.45,110.69 100.39,110.63 99.59,110.63 99.02,111.19 99.02,112.16 98.31,112.87 98.21,112.87 98.03,113.05 98.03,113.15 97.99,113.2 J2.44
  L03_SIG1 w0.102: 107.15,79.61 105.37,79.61 105.06,79.93 105.06,85.57 105.66,86.17 v1(105.66,86.2)
  L03_SIG1 w0.155: 107.15,79.61 109.6,79.61 115.37,85.39 115.86,85.39 116.39,85.91 116.39,86.58 115.61,87.36 115.61,91.98 115.91,92.28 115.91,95.61 116.78,96.48 116.78,97.4 117.15,97.77 117.15,101.94 115.75,103.34 115.75,105.87 116.05,106.17 116.05,107.76 115.66,108.16 113.07,108.16 113.07,108.15 111.75,108.15 111.54,107.95 111.54,106.78 112.47,105.85 112.47,104.51 111.31,103.35 111.31,102.58 110.93,102.2 109.87,102.2 108.87,103.2 108.87,103.29 108.17,103.99 108.05,103.99 107.48,104.56 107.47,104.56 106.67,105.36 106.67,105.38 106.4,105.64 106.4,107.33 105.37,108.36 105.37,109.5 105.37,109.5 105.37,110.82 104.86,111.33 v2(102.64,111.33)
P2_A2: length 79.5
  TOP w0.193: v2(98.15,122.75) 98.15,122.74 97.96,122.56 97.96,120.86 97.99,120.84 J2.43 ; U11.AD22 v1(104.66,85.2)
  L05_SIG2 w0.102: 94.34,90.17 95.27,89.24 95.27,88.04 95.5,87.81 96.21,87.81 96.42,87.6 96.84,87.6 97.07,87.38 97.07,86.95 97.42,86.6 97.84,86.6 98.07,86.38 98.07,85.95 98.42,85.6 98.84,85.6 99.07,85.38 99.07,84.95 99.41,84.6 99.91,84.6 100.11,84.81 100.83,84.81 101.06,85.04 101.06,85.46 101.4,85.81 102.83,85.81 102.85,85.83 103.19,85.83 103.42,85.59 103.83,85.59 104.22,85.2 v1(104.66,85.2)
  L05_SIG2 w0.155: 94.34,90.17 94.31,90.2 94.31,90.83 93.33,91.81 93.33,92.52 94.91,94.1 94.91,94.52 96.3,95.91 97.18,95.91 97.35,96.09 97.64,96.09 98.06,96.51 99.67,96.51 100.69,95.49 101.14,95.49 101.37,95.26 102.83,95.26 103.04,95.47 103.04,96.77 102.55,97.25 102.55,102.01 102.41,102.16 102.41,103.99 100.44,105.96 100.44,107.57 99.05,108.97 99.05,110.73 99.98,111.66 99.98,114.24 99.79,114.43 99.07,114.43 98.86,114.23 98.86,113.54 97.3,111.97 97.3,110.85 97.39,110.76 97.39,110.09 97.19,109.89 96.57,109.89 95.58,110.89 95.58,113.02 97.57,115.01 97.57,116.08 98.93,117.44 98.93,120.23 99.58,120.88 99.75,120.88 99.91,121.05 100.8,121.05 100.92,121.17 100.92,121.54 100.8,121.66 100.22,121.66 99.74,122.14 98.83,122.14 98.22,122.75 v2(98.15,122.75)
P2_A3: length 77.3
  TOP w0.193: J2.42 97.49,114.76 97.15,115.1 97.15,115.42 96.22,116.34 94.81,116.34 v2(94.75,116.28) ; U11.AC21 v1(103.66,84.2)
  L05_SIG2 w0.102: 92.51,89.74 92.64,89.61 93.81,89.61 94.5,88.92 94.5,87.83 94.73,87.6 94.84,87.6 95.07,87.38 95.07,86.95 95.42,86.6 95.93,86.6 96.27,86.27 96.27,86.04 96.5,85.81 96.92,85.81 97.27,85.46 97.27,85.04 97.86,84.44 97.86,84.16 98.62,83.4 100.08,83.4 100.29,83.6 100.91,83.6 101.26,83.95 101.26,84.35 101.5,84.59 102.3,84.59 102.32,84.58 102.49,84.58 102.5,84.59 102.83,84.59 103.22,84.2 v1(103.66,84.2)
  L05_SIG2 w0.155: v2(94.75,116.28) 94.75,117.55 93.61,118.69 93.61,118.92 93.83,119.14 94.49,119.14 94.71,119.35 95.69,119.35 95.82,119.48 95.82,119.91 95.69,120.04 94.54,120.04 94.23,119.73 93.81,119.73 93.61,119.93 93.61,120.18 93.87,120.43 94.23,120.43 94.52,120.72 95.85,120.72 95.98,120.85 96.23,120.85 96.48,120.6 96.48,119.38 96.27,119.18 96.27,118.18 96.34,118.12 96.34,117.62 96.27,117.55 96.27,115.55 95.33,114.6 94.78,114.6 93.72,113.54 93.72,113.07 92.81,112.16 92.81,110.97 93.33,110.45 93.33,109.89 94.2,109.01 95.18,109.01 95.85,108.34 95.85,107.02 96.12,106.75 96.75,106.75 97.02,106.47 97.02,106.08 96.75,105.81 96.12,105.81 95.85,105.53 95.85,105.14 96.12,104.87 96.75,104.87 97.02,104.59 97.02,104.2 96.75,103.93 96.12,103.93 95.85,103.65 95.85,103.26 96.12,102.99 96.75,102.99 97.02,102.71 97.02,102.32 96.75,102.05 96.12,102.05 95.85,101.77 95.85,101.38 96.12,101.11 96.75,101.11 97.02,100.83 97.02,100.44 96.75,100.17 96.12,100.17 95.85,99.89 95.85,99.59 95.37,99.1 93.88,99.1 93.48,98.71 93.48,95.73 92.98,95.22 92.98,94.25 91.95,93.22 91.95,90.3 92.51,89.74
P2_A4: length 79.6
  TOP w0.193: U11.AB20 v1(102.66,83.2) ; J2.41 v2(97.49,124.36)
  L05_SIG2 w0.102: 89.73,89.94 89.73,89.7 90.06,89.37 90.06,88.96 90.42,88.6 90.82,88.6 91.07,88.35 91.07,87.95 91.42,87.6 92.84,87.6 94.07,86.38 94.07,85.95 94.42,85.6 94.82,85.6 95.07,85.35 95.07,84.95 95.42,84.6 96.09,84.6 96.27,84.42 96.27,84.04 96.5,83.81 97.06,83.81 98.28,82.59 100.42,82.59 100.44,82.6 101.92,82.6 102.52,83.2 v1(102.66,83.2)
  L05_SIG2 w0.155: 89.73,89.94 89.73,91.91 89.13,92.5 89.13,94.56 88.86,94.84 87.78,94.84 87.51,95.11 87.51,95.5 87.78,95.78 88.86,95.78 89.13,96.05 89.13,96.44 88.86,96.72 87.78,96.72 87.51,96.99 87.51,97.38 87.78,97.66 88.86,97.66 89.13,97.93 89.13,98.32 88.86,98.6 87.78,98.6 87.51,98.87 87.51,99.26 87.78,99.54 88.86,99.54 89.13,99.81 89.13,107.15 89.94,107.97 89.94,109.42 89.24,110.13 89.24,111.29 89.39,111.44 89.39,112.74 89.93,113.28 89.93,115.85 89.88,115.9 89.88,120.63 89.58,120.94 89.3,120.94 89.09,120.72 89.09,119.16 88.96,119.03 88.67,119.03 88.54,119.16 88.54,120.94 88.15,121.33 88.15,121.83 88.81,122.49 88.81,123.34 89.71,124.24 90.47,124.24 90.78,123.93 91.28,123.93 91.81,124.46 96.58,124.46 96.69,124.36 v2(97.49,124.36)
P2_A5: length 77.7
  TOP w0.193: U11.AD23 v1(104.66,86.2) ; J2.40 96.99,113.55 97.03,113.51 97.03,113.05 97.21,112.87 97.56,112.87 98.02,112.42 98.12,112.42 98.56,111.97 98.56,111.01 99.4,110.17 100.58,110.17 100.64,110.23 101.15,110.23 101.17,110.25 101.68,110.25 101.7,110.23 102.64,110.23 v2(102.67,110.2)
  L03_SIG1 w0.102: v1(104.66,86.2) 105.06,86.59 105.83,86.59 106.06,86.36 106.06,80.83 106.29,80.6 106.94,80.6 107.06,80.48 107.06,80.33 107.35,80.05
  L03_SIG1 w0.155: 107.35,80.05 109.42,80.05 115.37,85.99 115.37,86.99 115.18,87.18 115.18,92.16 115.48,92.46 115.48,94.7 115.26,94.92 113.93,94.92 112.48,96.38 112.48,98.18 113.54,99.24 116.44,99.24 116.72,99.51 116.72,101.76 115.32,103.16 115.32,107.02 115.19,107.14 112.98,107.14 112.85,107.02 112.85,104.28 111.74,103.17 111.74,102.4 111.11,101.77 109.65,101.77 108.19,103.23 108.19,103.24 107.3,104.13 107.29,104.13 106.24,105.18 106.24,105.2 105.97,105.46 105.97,107 105.83,107.15 105.83,107.19 105.18,107.83 105.18,107.94 104.94,108.19 104.94,109 104.48,109.46 104.48,109.6 103.88,110.2 v2(102.67,110.2)
P2_A6: length 78.4
  TOP w0.193: v2(96.93,118.79) 96.93,118.86 96.99,118.92 J2.39 ; U11.AC22 v1(103.66,85.2)
  L05_SIG2 w0.102: 93.88,90.15 94.16,89.86 94.16,89.84 94.19,89.81 94.35,89.81 95.07,89.09 95.07,87.95 95.42,87.6 96.1,87.6 96.27,87.44 96.27,87.04 96.5,86.81 96.92,86.81 97.27,86.46 97.27,86.04 97.5,85.81 97.92,85.81 98.27,85.46 98.27,85.04 98.5,84.81 98.92,84.81 99.27,84.46 99.27,84.04 99.5,83.81 99.83,83.81 100.06,84.04 100.06,84.35 100.31,84.6 100.91,84.6 101.27,84.96 101.27,85.36 101.5,85.59 102.83,85.59 103.22,85.2 v1(103.66,85.2)
  L05_SIG2 w0.155: v2(96.93,118.79) 96.93,121.18 97.05,121.31 97.37,121.31 97.5,121.43 97.5,121.83 97.63,121.96 98.37,121.96 98.5,121.83 98.5,117.62 97.14,116.26 97.14,115.19 95.64,113.69 95.09,113.69 94.58,113.19 94.58,111.14 94.19,110.74 94.19,110.25 94.54,109.9 95.95,109.9 96.39,109.46 97.37,109.46 97.82,109.91 97.82,111.88 98.3,112.36 99.01,112.36 99.35,112.02 99.35,111.66 98.54,110.85 98.54,108.91 98.62,108.83 98.62,108.74 100.01,107.35 100.01,105.78 101.97,103.81 101.97,101.98 102.12,101.83 102.12,98.2 101.81,97.89 101.47,97.89 101.26,97.68 101.26,97 101.69,96.57 102.29,96.57 102.46,96.4 102.46,95.96 102.25,95.75 101.38,95.75 101.29,95.84 100.94,95.84 99.92,96.86 97.92,96.86 97.49,96.44 97.1,96.44 97.08,96.42 96.27,96.42 95.66,95.81 94.83,95.81 94.34,95.33 94.34,94.03 92.92,92.61 92.92,91.55 93.88,90.59 93.88,90.15
P2_A7: length 77.4
  TOP w0.193: U11.AB21 v1(102.66,84.2) ; J2.38 96.49,115.21 95.88,115.82 95.23,115.82 95.04,115.62 94.16,115.62 93.9,115.88 92.74,115.88 v2(92.54,116.08)
  L05_SIG2 w0.102: v1(102.66,84.2) 102.22,84.2 101.83,83.81 101.4,83.81 100.99,83.4 100.37,83.4 100.17,83.2 98.53,83.2 97.66,84.07 97.66,84.36 97.07,84.95 97.07,85.38 96.84,85.6 96.42,85.6 96.21,85.81 95.5,85.81 95.27,86.04 95.27,86.46 94.92,86.81 94.5,86.81 94.2,87.1 94.2,87.86 94.26,87.92 94.26,88.45 93.9,88.81 92.5,88.81 92.27,89.04 92.27,89.42 91.52,90.17
  L05_SIG2 w0.155: 91.52,90.17 91.52,93.54 92.48,94.51 92.48,95.55 93.11,96.18 93.11,99.18 93.38,99.46 95.22,99.46 95.49,99.74 95.49,100.12 95.22,100.4 93.38,100.4 93.11,100.67 93.11,101.06 93.38,101.34 95.27,101.34 95.49,101.56 95.49,102 95.22,102.28 93.38,102.28 93.11,102.55 93.11,102.94 93.38,103.22 95.22,103.22 95.49,103.49 95.49,103.88 95.22,104.16 93.38,104.16 93.11,104.43 93.11,104.82 93.38,105.1 95.22,105.1 95.49,105.37 95.49,105.76 95.22,106.04 93.38,106.04 93.11,106.31 93.11,106.7 93.38,106.98 95.22,106.98 95.49,107.25 95.49,107.64 95.22,107.92 93.38,107.92 93.11,108.19 93.11,109.5 92.89,109.71 92.89,110.27 92.37,110.79 92.37,111.09 91.61,111.85 91.61,112.56 91.84,112.79 92.74,112.79 93.18,113.23 93.18,113.72 94.52,115.06 94.52,115.58 94.16,115.95 94.16,116.53 94.23,116.6 94.23,117.44 93.7,117.96 92.8,117.96 92.59,117.75 92.59,116.12 v2(92.54,116.08)
P2_A8: length 77.4
  TOP w0.193: J2.37 96.49,120.94 96.59,121.04 96.59,121.95 96.49,122.05 v2(96.49,122.27) ; U11.AD25 v1(104.66,88.2)
  L03_SIG1 w0.102: 101.45,90.02 101.27,89.84 101.27,89.04 101.5,88.81 101.64,88.81 102.06,88.39 102.06,87.94 102.39,87.6 103.54,87.6 103.75,87.81 104.27,87.81 v1(104.66,88.2)
  L03_SIG1 w0.155: 101.45,90.02 101.45,90.09 101.57,90.22 101.57,90.49 102.17,91.09 102.17,91.46 102.41,91.7 104.58,91.7 105.21,91.07 105.21,90.99 105.61,90.59 107.1,90.59 108.11,89.58 108.11,87.13 108.39,86.85 111.39,86.85 111.91,87.37 111.91,89.69 111.83,89.78 111.25,89.78 110.85,90.18 110.85,92.27 109.3,93.82 109.3,98.2 108.91,98.59 108.15,98.59 107.99,98.76 106.71,100.04 105.59,100.04 103.69,101.94 103.69,103.23 101.04,105.88 101.04,106.92 99.48,108.49 99.48,109.19 99.04,109.63 99.04,111.13 99.59,111.67 99.59,112.24 100.03,112.68 100.03,113.22 100.93,114.12 103.07,114.12 103.32,114.38 103.32,116.3 102.43,117.2 102.43,119.03 102.3,119.16 100.82,119.16 100.69,119.29 100.69,119.66 100.82,119.79 102.3,119.79 102.43,119.91 102.43,120.28 102.03,120.68 100.32,120.68 100.11,120.46 99.03,120.46 98.21,121.28 96.83,121.28 96.58,121.53 96.58,122.17 v2(96.49,122.27)
P2_A9: length 77.8
  TOP w0.193: v2(101.42,109.64) 100.9,109.64 100.89,109.63 99.3,109.63 98.11,110.82 98.11,111.68 97.37,112.42 97.02,112.42 96.56,112.87 96.21,112.87 96.03,113.05 96.03,113.86 J2.36 ; U11.AD26 v1(104.66,89.2)
  L05_SIG2 w0.102: v1(104.66,89.2) 104.68,89.2 105.06,88.83 105.06,87.93 104.93,87.8 104.27,87.8 104.15,87.93 104.15,88.65 104.02,88.78 103.4,88.78 103.27,88.65 103.27,88.24 103.19,88.16 103.19,88.04 102.74,87.59 101.5,87.59 101.27,87.36 101.27,86.94 100.92,86.59 100.5,86.59 100.27,86.36 100.27,86.08 99.99,85.81 99.5,85.81 99.27,86.04 99.27,86.46 98.92,86.81 98.5,86.81 98.27,87.04 98.27,87.46 97.92,87.81 97.5,87.81 97.27,88.04 97.27,89.5 97.05,89.72 96.62,89.72
  L05_SIG2 w0.155: 96.62,89.72 95.76,90.58 95.76,91.75 95.95,91.94 95.95,92.85 96.59,93.49 96.59,93.87 97,94.29 97.36,94.29 97.57,94.5 99.66,94.5 100,94.16 100,93.93 100.35,93.58 101.17,93.58 101.33,93.42 101.89,93.42 102.38,93.92 103.26,93.92 103.85,93.34 105.57,93.34 105.64,93.41 105.94,93.41 106.05,93.52 106.05,94.04 105.96,94.13 105.96,94.62 106.51,95.18 106.51,97.96 105.96,98.52 105.96,99.02 106.31,99.36 106.34,99.36 106.52,99.54 106.52,100.41 106.29,100.64 105.94,100.64 105.82,100.52 105.82,99.66 105.47,99.31 105.47,98.23 106,97.7 106,95.47 105.47,94.94 105.47,94.08 105.33,93.94 105.08,93.94 104.95,94.08 104.95,95.1 105.42,95.57 105.42,97.48 104.96,97.94 104.96,99.65 105.25,99.94 105.25,101.39 104.72,101.92 104.72,103.52 102.81,105.43 102.81,107.69 102.55,107.95 102.02,107.95 101.83,108.14 101.83,108.94 102.12,109.23 102.12,109.91 102.07,109.96 102.07,110.49 101.85,110.71 101.11,110.71 100.92,110.52 100.92,109.86 101.14,109.64 v2(101.42,109.64)
P2_B0: length 78.1
  TOP w0.193: U11.AC24 v1(103.66,87.2) ; v2(95.77,123.11) 95.88,123.01 95.88,121.96 96.1,121.74 96.1,121.24 95.99,121.13 J2.35
  L03_SIG1 w0.102: 102.51,90.16 102.06,89.71 102.06,88.85 102.27,88.64 102.27,88.04 102.5,87.81 102.83,87.81 103.09,88.06 103.09,88.23 103.45,88.6 104.84,88.6 105.08,88.35 105.08,87.94 104.75,87.6 104.07,87.6 v1(103.66,87.2)
  L03_SIG1 w0.155: v2(95.77,123.11) 96.49,123.11 97.08,122.52 97.08,122.3 97.67,121.72 98.49,121.72 98.89,121.32 98.89,121.24 99.24,120.9 99.93,120.9 100.14,121.11 102.57,121.11 102.86,120.82 102.86,117.38 103.76,116.48 103.76,113.93 103.51,113.69 102.05,113.69 102.04,113.69 101.11,113.69 100.46,113.05 100.46,112.5 100.02,112.06 100.02,111.49 99.48,110.95 99.48,109.81 99.91,109.37 99.91,108.78 100.66,108.03 101.18,108.03 102.41,106.8 102.41,105.12 104.12,103.41 104.12,102.12 105.77,100.47 106.89,100.47 108.21,99.15 108.33,99.02 109.36,99.02 109.73,98.65 109.73,95.21 110.06,94.89 110.06,93.67 111.21,92.52 111.91,92.52 112.34,92.08 112.34,86.96 111.74,86.36 108.21,86.36 107.68,86.89 107.68,89.4 106.92,90.16 102.51,90.16
P2_B1: length 77.6
  TOP w0.193: J2.34 95.49,112.24 95.84,111.89 v2(96.6,111.89) ; U11.AC25 v1(103.66,88.2)
  L05_SIG2 w0.102: 95.56,90.17 96.27,89.46 96.27,89.04 96.5,88.81 96.83,88.81 97.07,88.57 97.07,87.95 97.42,87.6 97.84,87.6 98.07,87.37 98.07,86.95 98.42,86.6 98.84,86.6 99.07,86.38 99.07,85.95 99.42,85.6 99.72,85.6 99.73,85.59 100.08,85.59 100.3,85.81 100.83,85.81 101.06,86.04 101.06,86.44 101.42,86.8 105.13,86.8 105.26,86.92 105.26,87.47 105.13,87.59 103.83,87.59 103.7,87.73 103.7,88.17 v1(103.66,88.2)
  L05_SIG2 w0.155: v2(96.6,111.89) 97.95,113.23 97.95,113.53 98.43,114.01 98.43,115.54 99.26,116.37 99.26,116.55 99.79,117.08 99.79,119.67 100.24,120.11 100.75,120.11 101.19,119.67 101.19,118.03 100.37,117.21 100.37,116.71 100.7,116.37 102.02,116.37 102.66,115.74 102.66,112.38 102.21,111.94 101.82,111.94 101.78,111.98 101.29,111.98 100.94,111.63 100.94,111.31 99.91,110.28 99.91,109.32 100.22,109.02 101.07,109.02 101.4,108.69 101.4,107.96 102.38,106.98 102.38,105.24 104.17,103.45 104.17,103.13 104,102.97 103.43,102.97 103.27,102.8 103.27,102.57 103.43,102.41 104,102.41 104.17,102.24 104.17,101.62 104.53,101.26 104.53,97.76 104.99,97.3 104.99,95.75 104.51,95.27 104.51,94.44 104.18,94.11 103.68,94.11 103.32,94.47 101.15,94.47 100.84,94.78 100.39,94.78 100,94.78 99.81,94.96 96.95,94.96 96,94.01 96,93.41 95.59,93 95.59,92.09 95.27,91.76 95.27,90.46 95.56,90.17
P2_B2: length 79.9
  TOP w0.193: U11.AB23 v1(102.66,86.2) ; J2.33 v2(95.49,121.49)
  L03_SIG1 w0.102: v1(102.66,86.2) 102.41,86.2 101.97,86.64 101.31,86.64 101.1,86.84 101.1,87.33 100.84,87.6 100.29,87.6 100.1,87.8 99.5,87.8 99.27,88.03 99.27,88.04 99.27,88.36 99.27,88.36 99.27,89.04 99.27,89.04 99.27,89.36 99.27,89.36 99.27,89.96 99.06,90.17
  L03_SIG1 w0.155: v2(95.49,121.49) 95.53,121.45 95.53,120.1 95.29,119.86 93.56,119.86 93.21,119.51 93.21,119.31 93.58,118.94 93.58,118.44 93.39,118.25 93.39,117.68 94.19,116.88 95,116.88 95.05,116.83 96.86,116.83 97.19,116.5 97.19,114.53 97.43,114.28 98.07,114.28 98.22,114.14 98.22,113.31 97.42,112.51 97.03,112.51 97,112.48 96.36,112.48 96.01,112.13 96.01,110.45 96.55,109.91 96.95,109.91 97.23,109.63 97.23,109.07 97.38,108.91 97.38,108.68 97.16,108.46 96.88,108.46 96.75,108.59 96.75,108.75 96.52,108.98 96.21,108.98 95.98,108.76 95.98,108.21 96.4,107.79 97.73,107.79 99.24,106.28 99.24,105.24 101.96,102.52 101.96,101.23 101.63,100.9 101.63,98.04 101.76,97.92 101.99,97.92 102.12,98.04 102.12,100.16 102.36,100.41 102.78,100.41 103.51,99.68 103.51,96.7 103.66,96.55 103.91,96.55 104.05,96.69 104.05,98.54 104.24,98.73 104.46,98.73 104.66,98.53 104.66,97.99 104.84,97.81 104.84,95.1 104.46,94.72 103.51,94.72 103.22,95.01 103.22,96.03 103.08,96.17 103.08,99.35 102.96,99.48 102.68,99.48 102.55,99.35 102.55,94.91 100.86,93.21 98.55,93.21 98.34,92.99 98.34,92.21 98.83,91.71 98.83,91.46 99.01,91.28 99.01,90.22 99.06,90.17
P2_B3: length 77.7
  TOP w0.193: U11.AC26 v1(103.66,89.2) ; J2.32 94.99,112.06 95.84,111.2 97.07,111.2 99.58,108.7 v2(102.59,108.7)
  L05_SIG2 w0.102: v1(103.66,89.2) 103.39,89.2 102.79,88.59 102.5,88.59 102.27,88.36 102.27,88.24 101.84,87.81 101.42,87.81 101.06,87.44 101.06,87.01 100.84,86.8 100.42,86.8 100.21,86.59 99.42,86.59 99.07,86.95 99.07,87.47 98.93,87.6 98.42,87.6 98.06,87.96 98.06,89.36 97.5,89.92 97.03,89.92 96.78,90.17
  L05_SIG2 w0.155: v2(102.59,108.7) 102.55,108.73 102.55,109.4 102.69,109.54 103.25,109.54 103.4,109.39 103.4,108.71 103.53,108.59 103.53,107.85 103.24,107.56 103.24,105.61 104.06,104.8 104.79,104.8 105.16,104.43 105.16,102.1 106.04,101.21 107.65,101.21 108.15,100.72 108.15,98.34 107.92,98.11 107.82,98.11 107.63,98.29 107.63,100.48 107.51,100.61 107.14,100.61 107.02,100.48 107.02,99.15 107.15,99.02 107.15,98.52 107.06,98.43 107.06,98.13 107.3,97.89 107.3,96.98 106.95,96.63 106.95,94.82 107.15,94.62 107.15,94.13 106.95,93.92 106.95,92.92 107.11,92.75 107.34,92.75 107.53,92.94 107.53,96.57 107.74,96.78 107.85,96.78 108.09,96.54 108.09,93.86 108.96,92.99 108.96,92.38 108.74,92.17 105.71,92.17 105.66,92.22 105.64,92.22 105.3,92.57 105.3,92.59 104.98,92.9 103.67,92.9 103.09,93.48 102.56,93.48 101.79,92.72 101.33,92.72 100.82,93.23 100.2,93.23 99.64,93.78 99.64,93.91 99.48,94.07 98.39,94.07 98.38,94.06 97.74,94.06 97.11,93.43 97.11,93.28 96.88,93.05 96.65,93.05 96.3,92.7 96.3,91.79 96.27,91.76 96.27,90.68 96.78,90.17
P2_B4: length 77.5
  TOP w0.193: J2.31 v2(94.99,118.69) ; U11.AB24 v1(102.66,87.2)
  L03_SIG1 w0.102: 101.06,90.13 101.06,88.91 101.27,88.7 101.27,88.04 101.5,87.81 101.9,87.81 102.51,87.2 v1(102.66,87.2)
  L03_SIG1 w0.155: v2(94.99,118.69) 95.68,118.69 96.61,119.63 96.61,120.69 96.78,120.85 98.03,120.85 99.02,119.85 99.5,119.85 100.22,119.13 100.22,119.11 100.66,118.68 101.7,118.68 102,118.38 102,117.02 102.85,116.16 102.85,114.8 102.61,114.56 100.75,114.56 99.59,113.4 99.59,112.86 99.15,112.41 99.15,111.85 98.51,111.2 98.51,109.55 99.05,109.01 99.05,108.31 100.61,106.74 100.61,105.7 103.26,103.06 103.26,101.76 105.95,99.07 105.95,98.54 105.96,98.53 105.96,98.52 106.32,98.16 108.67,98.16 108.87,97.96 108.87,96.9 108.71,96.74 107.4,96.74 107.24,96.57 107.24,96.34 107.4,96.18 108.71,96.18 108.87,96.01 108.87,95.78 108.71,95.62 107.4,95.62 107.24,95.46 107.24,95.22 107.4,95.06 108.71,95.06 108.87,94.9 108.87,93.64 110.32,92.18 110.32,90.07 110.64,89.76 110.64,88.52 110.85,88.31 111.3,88.31 111.43,88.17 111.43,87.67 111.04,87.28 108.87,87.28 108.54,87.61 108.54,89.76 107.28,91.02 105.76,91.02 104.57,92.21 102.27,92.21 101.09,91.03 101.09,90.17 101.06,90.13
P2_B5: length 79.4
  TOP w0.193: v2(90.52,116.1) 90.77,115.85 91.78,115.85 92.23,115.4 93.67,115.4 94.14,114.93 94.27,114.93 94.44,114.75 94.44,114.62 94.49,114.58 J2.30 ; U11.AA22 v1(101.66,85.2)
  L03_SIG1 w0.102: v1(101.66,85.2) 101.66,85.09 101.23,84.66 101.23,84.42 101.06,84.25 101.06,84.04 100.83,83.81 94.3,83.81 94.01,84.1 94.01,86.37 94.23,86.59 95.83,86.59 96.06,86.82 96.06,87.6 95.85,87.81 94.7,87.81 94.54,87.97 94.54,88.91 94.67,89.03 94.75,89.03 94.88,89.16 94.88,89.45 94.22,90.11
  L03_SIG1 w0.155: 94.22,90.11 94.12,90.11 92.85,91.38 87.79,91.38 87.37,91.81 87.37,93.55 87.66,93.85 89.51,93.85 89.78,94.11 89.78,94.28 89.61,94.44 88.77,94.44 88.6,94.6 88.6,94.84 88.77,95 89.61,95 89.78,95.16 89.78,95.4 89.61,95.56 88.77,95.56 88.6,95.72 88.6,95.95 88.77,96.12 89.61,96.12 89.78,96.28 89.78,96.51 89.61,96.68 88.77,96.68 88.6,96.84 88.6,97.07 88.77,97.24 89.61,97.24 89.78,97.4 89.78,97.63 89.61,97.79 88.77,97.79 88.6,97.96 88.6,98.19 88.77,98.35 89.61,98.35 89.78,98.52 89.78,98.82 89.56,99.04 88.88,99.04 88.66,99.25 88.66,102.61 88.92,102.87 89.29,102.87 89.52,103.1 89.52,107.66 89.69,107.66 90.25,108.22 90.25,108.48 90.34,108.58 90.34,108.73 91.21,109.6 91.21,110.23 91.22,110.24 91.22,110.55 90.83,110.93 90.83,111.17 90.36,111.64 86.9,111.64 86.77,111.77 86.77,117.09 86.9,117.22 87.51,117.22 87.64,117.09 87.64,115.4 87.77,115.28 89.94,115.28 90.07,115.4 90.07,115.97 90.2,116.1 v2(90.52,116.1)
P2_B6: length 78
  TOP w0.193: v2(94.49,122.27) 94.49,122.05 94.59,121.95 94.59,121.04 94.49,120.94 J2.29 ; U11.AB25 v1(102.66,88.2)
  L03_SIG1 w0.102: v1(102.66,88.2) 102.47,88.39 102.47,88.83 102.27,89.04 102.27,89.47 102.5,89.7 106.76,89.7 107.08,89.38 107.08,88.94 107.26,88.76 107.26,86.52 107.63,86.14
  L03_SIG1 w0.155: v2(94.49,122.27) 94.49,123.35 95.04,123.91 96.48,123.91 97.06,123.33 97.1,123.33 97.55,122.89 97.55,122.5 97.9,122.15 98.5,122.15 98.75,122.4 99.42,122.4 100.28,121.54 102.89,121.54 103.29,121.14 103.29,117.69 104.26,116.72 104.26,113.84 104.72,113.39 104.72,112.56 104.5,112.35 103.27,112.35 103.19,112.43 102.32,112.43 102.11,112.64 102.11,113.02 101.86,113.26 101.28,113.26 100.89,112.87 100.89,112.19 100.51,111.81 100.51,111.31 100.22,111.02 99.95,110.75 99.95,109.94 100.34,109.55 100.34,109.01 100.79,108.56 101.26,108.56 102.85,106.98 102.85,105.3 104.55,103.59 104.55,102.3 105.95,100.9 107.06,100.9 108.13,99.83 108.51,99.46 109.69,99.46 110.16,98.98 110.16,95.42 110.53,95.05 110.53,94.01 111.51,93.03 112.32,93.03 112.78,92.57 112.78,86.67 112.02,85.92 107.86,85.92 107.63,86.14
P2_B7: length 79.1
  TOP w0.193: U11.AA23 v1(101.66,86.2) ; J2.28 v2(93.99,111.59)
  L03_SIG1 w0.102: v1(101.66,86.2) 101.26,86.2 100.66,86.81 99.5,86.81 99.27,87.04 99.27,87.45 98.92,87.81 98.5,87.81 98.27,88.04 98.27,89.92 98.02,90.17
  L03_SIG1 w0.155: 98.02,90.17 97.79,90.4 97.21,90.4 96.79,90.83 96.79,91.49 97.25,91.95 97.25,91.96 97.5,92.21 97.5,92.7 97.25,92.95 97.25,93.76 96.92,94.1 96.92,96.73 96.5,97.15 96.5,97.64 96.85,97.99 97.16,97.99 97.16,99.33 96.43,100.06 96.43,100.69 95.96,101.16 95.96,101.66 96.99,102.69 96.99,104.44 97.12,104.56 97.4,104.56 97.53,104.44 97.53,102.53 97.16,102.16 97.16,101.16 97.12,101.12 97.12,100.31 97.36,100.06 97.68,100.06 97.81,99.94 97.81,97.13 97.47,96.8 97.47,94.45 97.75,94.17 99.02,94.17 99.21,94.36 99.21,94.89 99.07,95.03 98.37,95.03 98.02,95.38 98.02,96.22 98.26,96.46 98.95,96.46 99.21,96.72 99.21,97 98.99,97.22 98.5,97.22 98.15,97.57 98.15,98.06 98.6,98.51 98.6,100.4 98.38,100.61 97.77,100.61 97.55,100.84 97.55,101.83 97.79,102.08 98.37,102.08 98.6,102.31 98.6,102.96 98.96,103.33 98.96,104.27 98.4,104.84 97.96,104.84 97.36,105.44 97.36,106.58 97.03,106.91 96.65,106.91 96.52,106.79 96.52,104.46 96.4,104.34 95.99,104.34 95.87,104.46 95.87,106.79 95.74,106.91 95.17,106.91 94.39,107.7 94.39,110.05 94.19,110.25 94.19,110.74 94.63,111.18 94.63,112.66 95.18,113.22 95.18,114.67 94.89,114.96 94.89,115.4 94.69,115.6 94.44,115.6 94.25,115.42 94.25,113.44 94.02,113.21 94.02,111.62 v2(93.99,111.59)
P2_B8: length 79.7
  TOP w0.193: v2(93.69,123.04) 93.88,122.85 93.88,121.96 94.1,121.74 94.1,121.24 93.99,121.13 J2.27 ; U11.AB26 v1(102.66,89.2)
  L03_SIG1 w0.102: 107.58,83.8 107.06,84.33 107.06,88.63 106.88,88.81 103.5,88.81 103.11,89.2 v1(102.66,89.2)
  L03_SIG1 w0.155: v2(93.69,123.04) 93.69,123.6 94.43,124.34 96.66,124.34 97.24,123.76 99.64,123.76 99.86,123.55 100.13,123.55 100.85,122.83 100.85,122.75 101.08,122.52 101.08,122.33 101.44,121.98 103.31,121.98 103.73,121.56 103.73,117.87 104.7,116.89 104.7,114.23 105.24,113.69 105.24,112.11 104.98,111.84 103.16,111.84 103.01,112 101.56,112 101.54,111.98 101.29,111.98 100.94,111.63 100.94,111.13 100.77,110.96 100.77,109.28 101.06,108.99 101.44,108.99 103.28,107.16 103.28,105.48 104.98,103.77 104.98,102.48 106.13,101.33 107.24,101.33 108.44,100.14 108.69,99.89 109.9,99.89 110.6,99.19 110.6,95.6 110.96,95.23 110.96,94.19 111.69,93.46 112.53,93.46 113.3,92.7 113.3,86.58 110.52,83.8 107.58,83.8
P2_B9: length 77.4
  TOP w0.193: U11.Y22 v1(100.66,85.2) ; J2.26 93.49,114.88 93.43,114.94 92.04,114.94 91.76,115.22 v2(91.47,115.22)
  L03_SIG1 w0.102: v1(100.66,85.2) 100.22,85.2 99.62,84.6 94.65,84.6 94.25,85 94.25,85.69 94.37,85.81 97.04,85.81 97.21,85.98 97.21,86.7 97.12,86.79 96.43,86.79 96.26,86.95 96.26,87.74 96.06,87.95 96.06,88.64 95.91,88.79 95.47,88.79 95.27,88.59 95.27,88.34 95.14,88.21 94.94,88.21 94.81,88.34 94.81,88.68 95.11,88.99 95.12,88.99 95.12,89.7 94.42,90.4
  L03_SIG1 w0.155: v2(91.47,115.22) 91.73,115.49 91.73,117.65 91.35,118.03 90.11,118.03 89.92,117.85 89.92,117.35 90.12,117.15 91.02,117.15 91.15,117.03 91.15,115.89 90.75,115.48 90.75,114.71 87.52,114.71 87.4,114.58 87.4,114.27 87.52,114.15 90.6,114.15 90.72,114.02 90.72,113.73 90.6,113.6 87.51,113.6 87.38,113.47 87.38,113.23 87.61,113 90.39,113 90.75,112.64 90.75,111.86 91.26,111.34 91.26,111.11 91.8,110.58 92.06,110.58 92.41,110.23 92.41,109.73 92.3,109.63 92.3,109.61 91.77,109.07 91.46,109.07 91.11,108.72 91.11,108.69 90.6,108.18 90.6,108.07 90.01,107.47 90.01,102.42 89.83,102.25 89.35,102.25 89.12,102.02 89.12,100.99 89.38,100.73 90.36,100.73 90.54,100.56 90.54,100.23 90.37,100.07 89.42,100.07 89.26,99.9 89.26,99.67 89.42,99.51 90.37,99.51 90.54,99.34 90.54,93.89 90.18,93.53 90.18,92.36 90.81,91.74 93.06,91.74 94.4,90.4 94.42,90.4
P2_C0: length 78
  TOP w0.193: J2.25 v2(93.49,121.49) ; U11.AA24 v1(101.66,87.2)
  L03_SIG1 w0.102: v1(101.66,87.2) 101.53,87.2 100.92,87.81 100.45,87.81 100.06,88.2 100.06,89.73 99.71,90.07
  L03_SIG1 w0.155: 99.71,90.07 99.71,90.77 100.23,91.28 100.23,91.94 102.58,94.29 103.92,94.29 104.21,94 104.21,93.26 104.4,93.07 104.8,93.07 105.3,92.58 105.3,92.57 105.64,92.22 105.65,92.22 105.99,91.88 107.64,91.88 108.82,90.7 109.08,90.7 109.44,91.07 109.44,91.84 108.26,93.03 108.21,93.03 107.46,93.78 107.24,93.78 107.05,93.59 107.05,92.62 106.9,92.46 106.65,92.46 106.51,92.6 106.51,93.57 106.27,93.81 105.01,93.81 104.84,93.99 104.84,94.25 105.08,94.49 105.79,94.49 106.37,95.08 106.37,96.88 106.18,97.08 105.98,97.08 105.83,96.93 105.83,95.38 105.7,95.26 105.47,95.26 105.34,95.38 105.34,97.91 105.09,98.17 105.09,98.71 102.39,101.41 102.39,102.7 99.72,105.37 99.72,106.41 98.18,107.95 98.18,108.65 97.58,109.26 97.58,111.5 98.29,112.21 98.29,112.77 98.73,113.21 98.73,113.76 98.84,113.87 98.84,117.08 98.66,117.26 98.35,117.26 98.19,117.1 98.19,115.06 98.03,114.89 97.8,114.89 97.63,115.06 97.63,117.1 97.47,117.26 95.49,117.26 95.15,117.6 95.15,117.68 94.39,118.44 94.39,118.94 94.74,119.29 95.47,119.29 96.08,119.9 96.08,121.74 95.73,122.09 95.15,122.09 94.73,121.67 93.67,121.67 v2(93.49,121.49)
P2_C1: length 79.1
  TOP w0.193: J2.24 92.99,111.55 93.55,110.98 94.24,110.98 94.36,111.11 95.11,111.11 95.71,110.51 v2(96.79,110.51) ; U11.AA25 v1(101.66,88.2)
  L05_SIG2 w0.102: v1(101.66,88.2) 101.47,88.01 101.34,88.01 100.92,87.59 100.5,87.59 100.27,87.36 100.27,87.07 99.99,86.8 99.76,86.8 99.75,86.81 99.5,86.81 99.27,87.04 99.27,87.55 99.01,87.81 98.5,87.81 98.27,88.04 98.27,89.54 97.64,90.17
  L05_SIG2 w0.155: 97.64,90.17 97.64,90.17 97.46,90.35 97.21,90.35 96.79,90.77 96.79,91.32 97.14,91.67 97.15,91.67 97.9,92.42 97.9,92.97 98.57,93.63 99.29,93.63 100.05,92.87 100.57,92.87 101.32,92.11 103.65,92.11 104.01,92.47 104.9,92.47 104.94,92.44 104.94,92.42 105.5,91.86 105.51,91.86 105.64,91.73 109.16,91.73 109.57,92.14 109.57,93.32 109.34,93.55 109.02,93.55 108.59,93.97 108.59,100.89 107.83,101.65 106.22,101.65 105.59,102.27 105.59,104.99 105.34,105.23 104.27,105.23 103.68,105.83 103.68,107.25 104.18,107.75 104.18,108.55 103.84,108.89 103.84,109.6 103.44,109.99 103.44,115.82 101.62,117.64 101.62,120.25 101.29,120.59 100.09,120.59 99.36,119.86 99.36,117.26 98,115.9 98,114.83 96.01,112.84 96.01,111.3 v2(96.79,110.51)
P2_C2: length 78.1
  TOP w0.193: J2.23 v2(92.99,118.69) ; U11.AA26 v1(101.66,89.2)
  L05_SIG2 w0.102: v1(101.66,89.2) 101.66,89.21 101.28,89.59 100.5,89.59 100.26,89.35 100.26,88.03 100.04,87.81 99.3,87.81 99.06,88.05 99.06,89.36 98.54,89.88
  L05_SIG2 w0.155: 98.54,89.88 98.54,92.05 98.34,92.25 98.34,92.79 98.69,93.14 98.73,93.14 98.8,93.2 99.13,93.2 99.81,92.52 100.31,92.52 100.7,92.13 100.7,91.72 101,91.41 101.37,91.41 101.71,91.76 102.5,91.76 102.77,91.49 103.64,91.49 104.19,92.04 104.8,92.04 105.54,91.3 109.52,91.3 110.11,91.89 110.11,94.02 109.94,94.19 109.24,94.19 109.02,94.4 109.02,101.11 108.06,102.08 106.4,102.08 105.97,102.5 105.97,103.43 106.03,103.49 106.03,105.33 105.69,105.66 104.45,105.66 104.15,105.96 104.15,107.07 104.7,107.62 104.7,107.62 104.88,107.8 104.88,108.45 104.27,109.07 104.27,109.78 103.87,110.17 103.87,116 102.05,117.82 102.05,119.86 103.59,121.4 103.59,123.2 102.97,123.82 100.65,123.82 100.32,123.49 99.57,123.49 99.42,123.34 97.9,123.34 97.08,122.53 97.08,122.02 96.73,121.67 96.15,121.67 95.73,122.09 95.15,122.09 93.96,120.9 93.5,120.9 92.98,120.37 92.98,118.7 v2(92.99,118.69)
P2_C3: length 77.8
  TOP w0.193: U11.W22 v1(99.66,85.2) ; v2(92.21,112.1) 92.27,112.15 92.36,112.15 92.49,112.28 J2.22
  L03_SIG1 w0.102: 95.28,90.17 96.27,89.18 96.27,88.04 96.5,87.81 96.92,87.81 97.27,87.46 97.27,86.98 97.47,86.78 97.88,86.78 98.07,86.59 98.07,85.76 97.89,85.59 95.2,85.59 95.07,85.47 95.07,84.93 95.2,84.81 98.93,84.81 99.07,84.95 99.07,85.59 99.2,85.72 99.51,85.72 99.64,85.59 99.64,85.22 v1(99.66,85.2)
  L03_SIG1 w0.155: v2(92.21,112.1) 92.61,112.49 92.61,114.79 92.49,114.91 92.32,114.91 92.2,114.79 92.2,112.98 92.08,112.86 91.87,112.86 91.74,112.98 91.74,114.38 91.61,114.5 91.41,114.5 91.2,114.28 91.2,112.24 92.21,111.23 92.21,111.04 92.84,110.41 92.84,110.22 92.89,110.17 92.89,109.71 92.98,109.63 92.98,107.92 92.74,107.68 91.9,107.68 91.78,107.55 91.78,106.71 91.65,106.58 91.34,106.58 91.21,106.71 91.21,107.55 91.08,107.68 90.79,107.68 90.48,107.37 90.48,102.71 90.61,102.58 91.04,102.58 91.17,102.71 91.17,105.55 91.29,105.67 91.65,105.67 91.85,105.47 91.85,102.21 91.7,102.06 91.23,102.06 91.04,101.88 91.04,95.09 91.17,94.97 91.5,94.97 91.62,95.09 91.62,98.83 91.78,98.98 91.78,98.99 92.02,98.99 92.25,98.77 92.25,95.23 92.52,94.95 93.17,94.95 93.3,94.82 93.3,94.56 93.17,94.43 91.09,94.43 90.97,94.31 90.97,94.07 91.09,93.94 93.23,93.94 93.36,93.81 93.36,91.93 95.11,90.17 95.28,90.17
P2_C4: length 77.9
  TOP w0.193: U11.Y23 v1(100.66,86.2) ; J2.21 v2(92.49,122.27)
  L03_SIG1 w0.102: 96.28,90.17 96.72,90.17 97.05,89.84 97.83,89.84 98.07,89.6 98.07,89.31 98.06,89.3 98.06,88.88 97.88,88.71 97.45,88.71 97.27,88.52 97.27,88.04 97.5,87.81 97.91,87.81 98.27,87.45 98.27,87.04 98.71,86.59 99.83,86.59 99.83,86.59 100.01,86.59 100.4,86.2 v1(100.66,86.2)
  L03_SIG1 w0.155: v2(92.49,122.27) 91.83,122.27 91.67,122.43 91.67,122.66 92.66,123.66 92.9,123.66 93.09,123.47 93.09,122.79 93.18,122.7 93.18,122.04 92.69,121.55 92.69,121.17 92.97,120.9 93.73,120.9 93.84,121 94.86,121 95.06,120.8 95.06,120.48 94.8,120.23 93,120.23 92.38,119.6 92.38,118.4 92.75,118.03 92.75,117.67 93.75,116.67 93.75,113.89 93.58,113.73 93.58,112.04 93.39,111.84 93.39,111.17 93.76,110.81 93.76,110.07 93.84,109.99 93.84,106.56 94.2,106.2 94.2,102.36 93.72,101.88 93.72,100.64 94.58,99.77 94.58,98.87 94.21,98.49 94.21,97.97 94.46,97.72 94.65,97.72 94.91,97.98 95.17,97.98 95.44,97.72 95.65,97.72 95.82,97.89 95.82,99.04 95.22,99.64 95.22,100.06 94.34,100.95 94.34,101.59 94.87,102.13 94.87,106.23 95.06,106.41 95.24,106.41 95.42,106.23 95.42,104.22 96.47,103.17 96.47,102.77 95.53,101.84 95.53,100.98 96,100.51 96,99.88 96.61,99.27 96.61,98.25 96.15,97.79 96.15,97 96.49,96.66 96.49,93.97 95.95,93.43 95.95,92.29 95.46,91.8 95.46,91.6 95.62,91.44 95.74,91.44 96.05,91.75 96.26,91.75 96.43,91.57 96.43,91.39 95.91,90.86 95.91,90.55 96.28,90.17
P2_C5: length 78.8
  TOP w0.193: v2(94.79,110.5) 94.75,110.53 92.36,110.53 91.6,111.29 91.6,112.39 91.92,112.71 91.92,113.01 91.99,113.08 J2.20 ; U11.Y24 v1(100.66,87.2)
  L03_SIG1 w0.102: v1(100.66,87.2) 100.24,87.2 99.85,87.59 99.42,87.59 99.07,87.95 99.07,89.68 98.58,90.17
  L03_SIG1 w0.155: 98.58,90.17 98.58,90.25 98.25,90.57 98.25,91.72 97.85,92.12 97.85,92.85 97.83,92.87 97.83,93.53 98,93.7 99.49,93.7 99.65,93.86 99.65,96.67 99.78,96.8 100.09,96.8 100.21,96.67 100.21,94.96 100.39,94.78 100.86,94.78 101.17,94.46 101.44,94.46 102.07,95.09 102.07,96.32 101.84,96.55 101.67,96.55 101.53,96.42 101.53,95.26 101.4,95.14 101.15,95.14 101.05,95.24 101.05,96.59 101.2,96.74 101.2,96.99 101.2,96.99 101.2,97.57 101.2,99.69 101.04,99.86 100.8,99.86 100.64,99.69 100.64,98.04 100.48,97.88 100.25,97.88 100.08,98.04 100.08,100.25 100.25,100.42 101.04,100.42 101.2,100.58 101.2,101.1 101.4,101.3 101.4,102.47 100.92,102.95 100.15,102.95 99.64,102.44 99.64,98.57 99.52,98.45 99.26,98.45 99.13,98.57 99.13,102.78 99.51,103.16 99.51,104.36 98.81,105.06 98.81,106.11 97.55,107.36 95.23,107.36 94.74,107.85 94.74,108.09 94.99,108.34 95.42,108.34 95.61,108.52 95.61,108.93 95.47,109.07 94.93,109.07 94.74,109.25 94.74,109.41 95.55,110.22 95.55,112.29 96.23,112.97 96.87,112.97 97.21,113.31 97.21,113.9 96.75,114.35 96.75,116.2 96.55,116.4 96.3,116.4 96.17,116.27 96.17,113.6 95.06,112.48 95.06,110.77 v2(94.79,110.5)
P2_C6: length 77.5
  TOP w0.193: U11.Y25 v1(100.66,88.2) ; v2(95.75,117.87) 95.66,117.87 95.52,118.01 92.37,118.01 92.15,118.23 92.15,118.91 91.99,119.07 J2.19
  L03_SIG1 w0.102: 100.66,90.05 100.3,89.69 100.3,89.39 100.27,89.36 100.27,89.04 100.3,89.01 100.3,88.54 100.64,88.2 v1(100.66,88.2)
  L03_SIG1 w0.155: 100.66,90.05 100.66,91.66 102.74,93.74 103.5,93.74 103.76,93.48 103.76,92.95 104.06,92.64 104.67,92.64 105.86,91.45 107.46,91.45 108.97,89.94 108.97,87.96 109.22,87.71 109.92,87.71 110.21,88 110.21,89.58 109.89,89.89 109.89,92 108.44,93.46 108.39,93.46 106.8,95.05 106.8,97.06 105.52,98.34 105.52,98.89 102.82,101.58 102.82,102.88 100.18,105.52 100.18,106.56 100.15,106.59 98.62,108.13 98.62,108.83 98.01,109.44 98.01,111.32 98.72,112.03 98.72,112.59 99.16,113.03 99.16,113.58 100.57,114.99 102.19,114.99 102.41,115.21 102.41,115.93 101.57,116.78 101.57,117.93 101.25,118.25 100.73,118.25 100.37,117.89 100.37,116.43 100.5,116.3 101.33,116.3 101.45,116.17 101.45,115.82 101.33,115.69 99.92,115.69 99.79,115.82 99.79,118.95 99.32,119.42 97.83,119.42 97.61,119.2 97.61,118.51 97.22,118.13 96.01,118.13 v2(95.75,117.87)
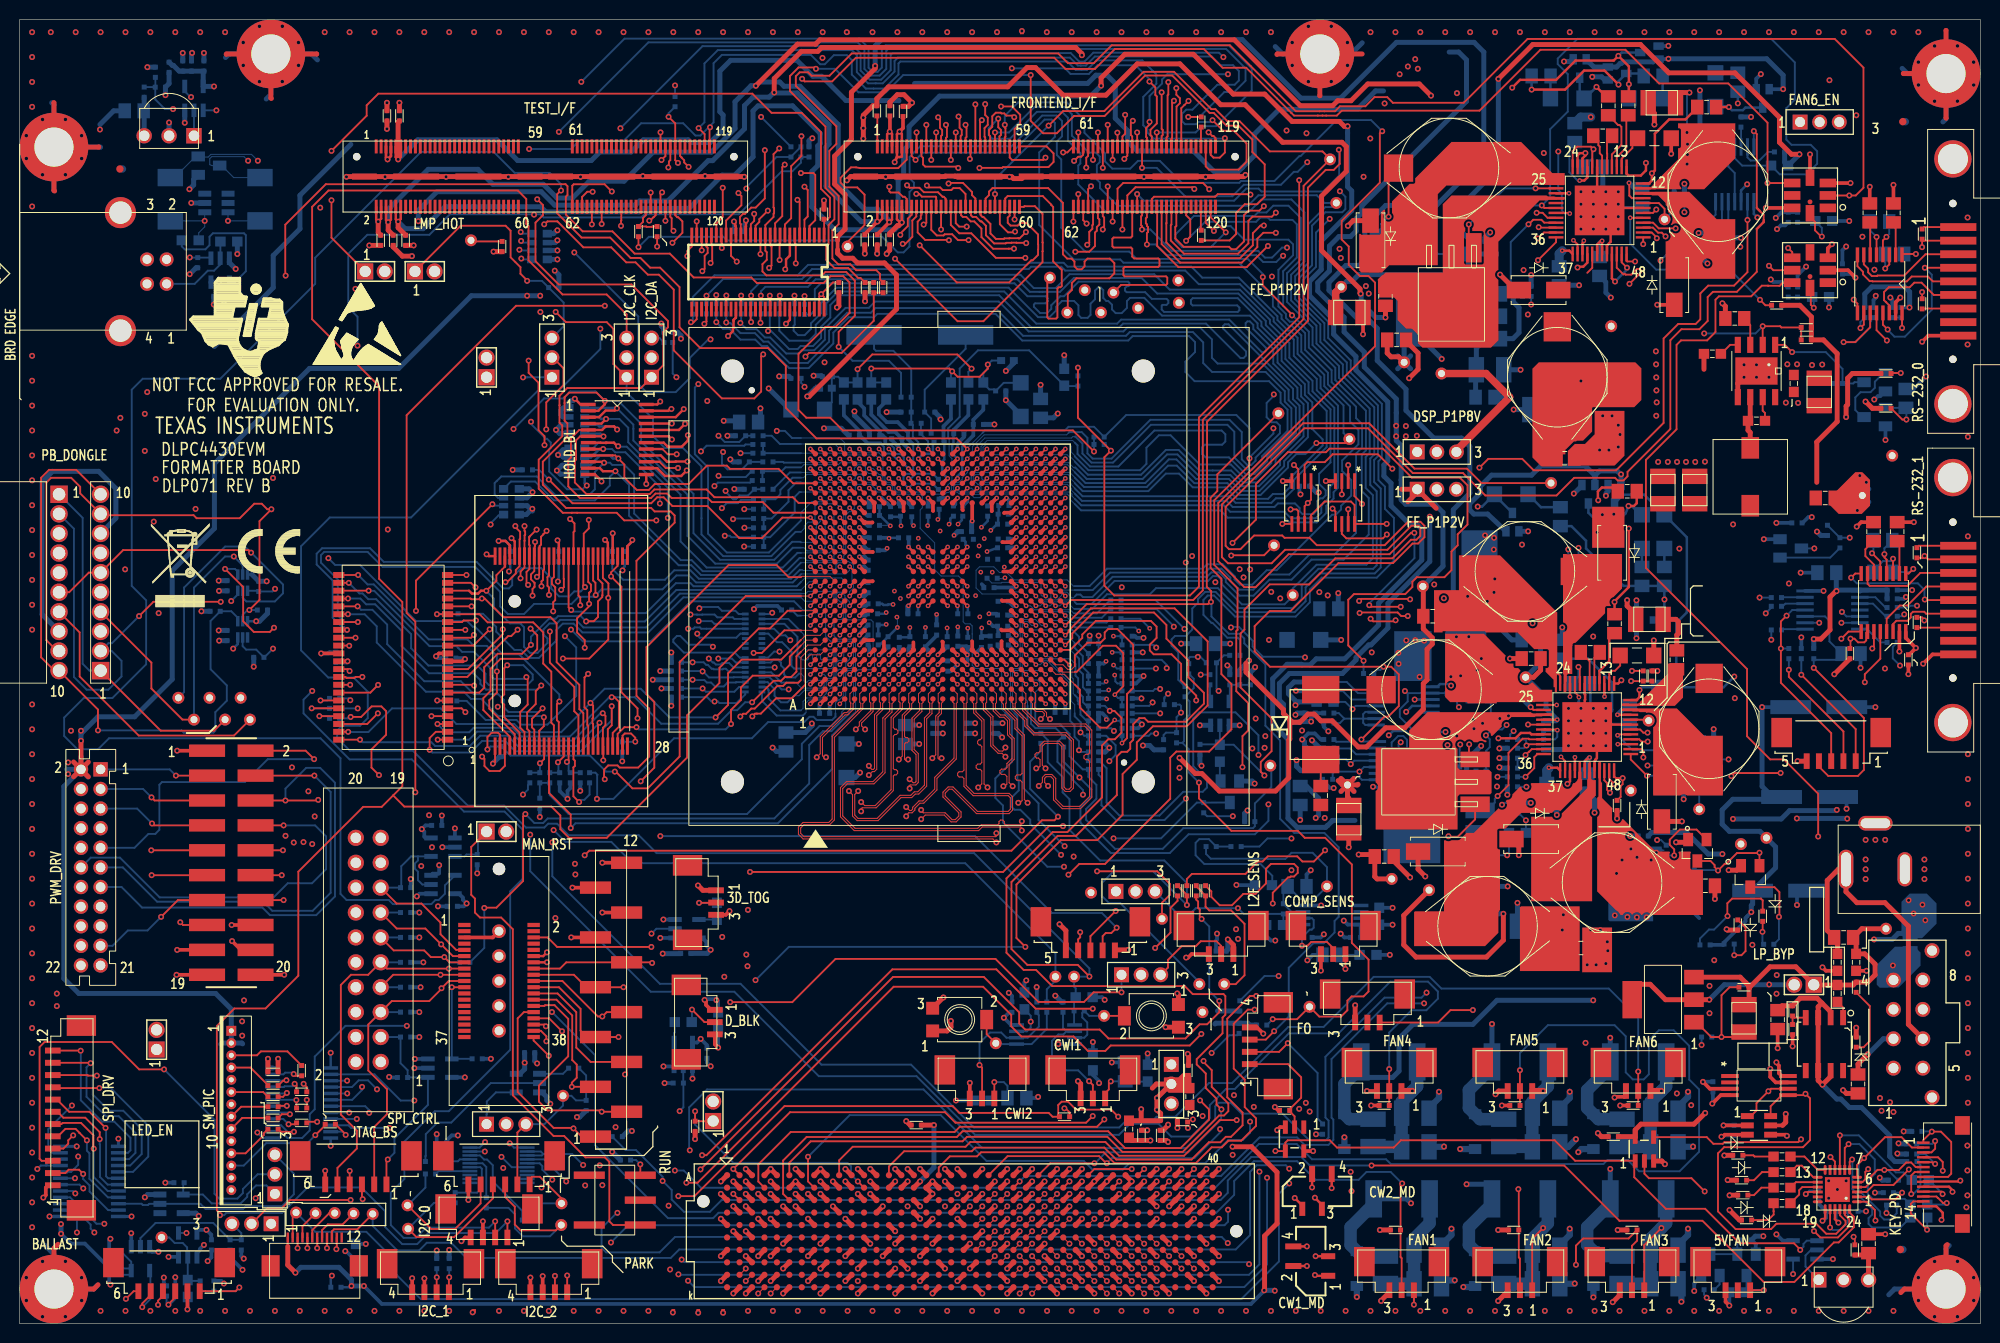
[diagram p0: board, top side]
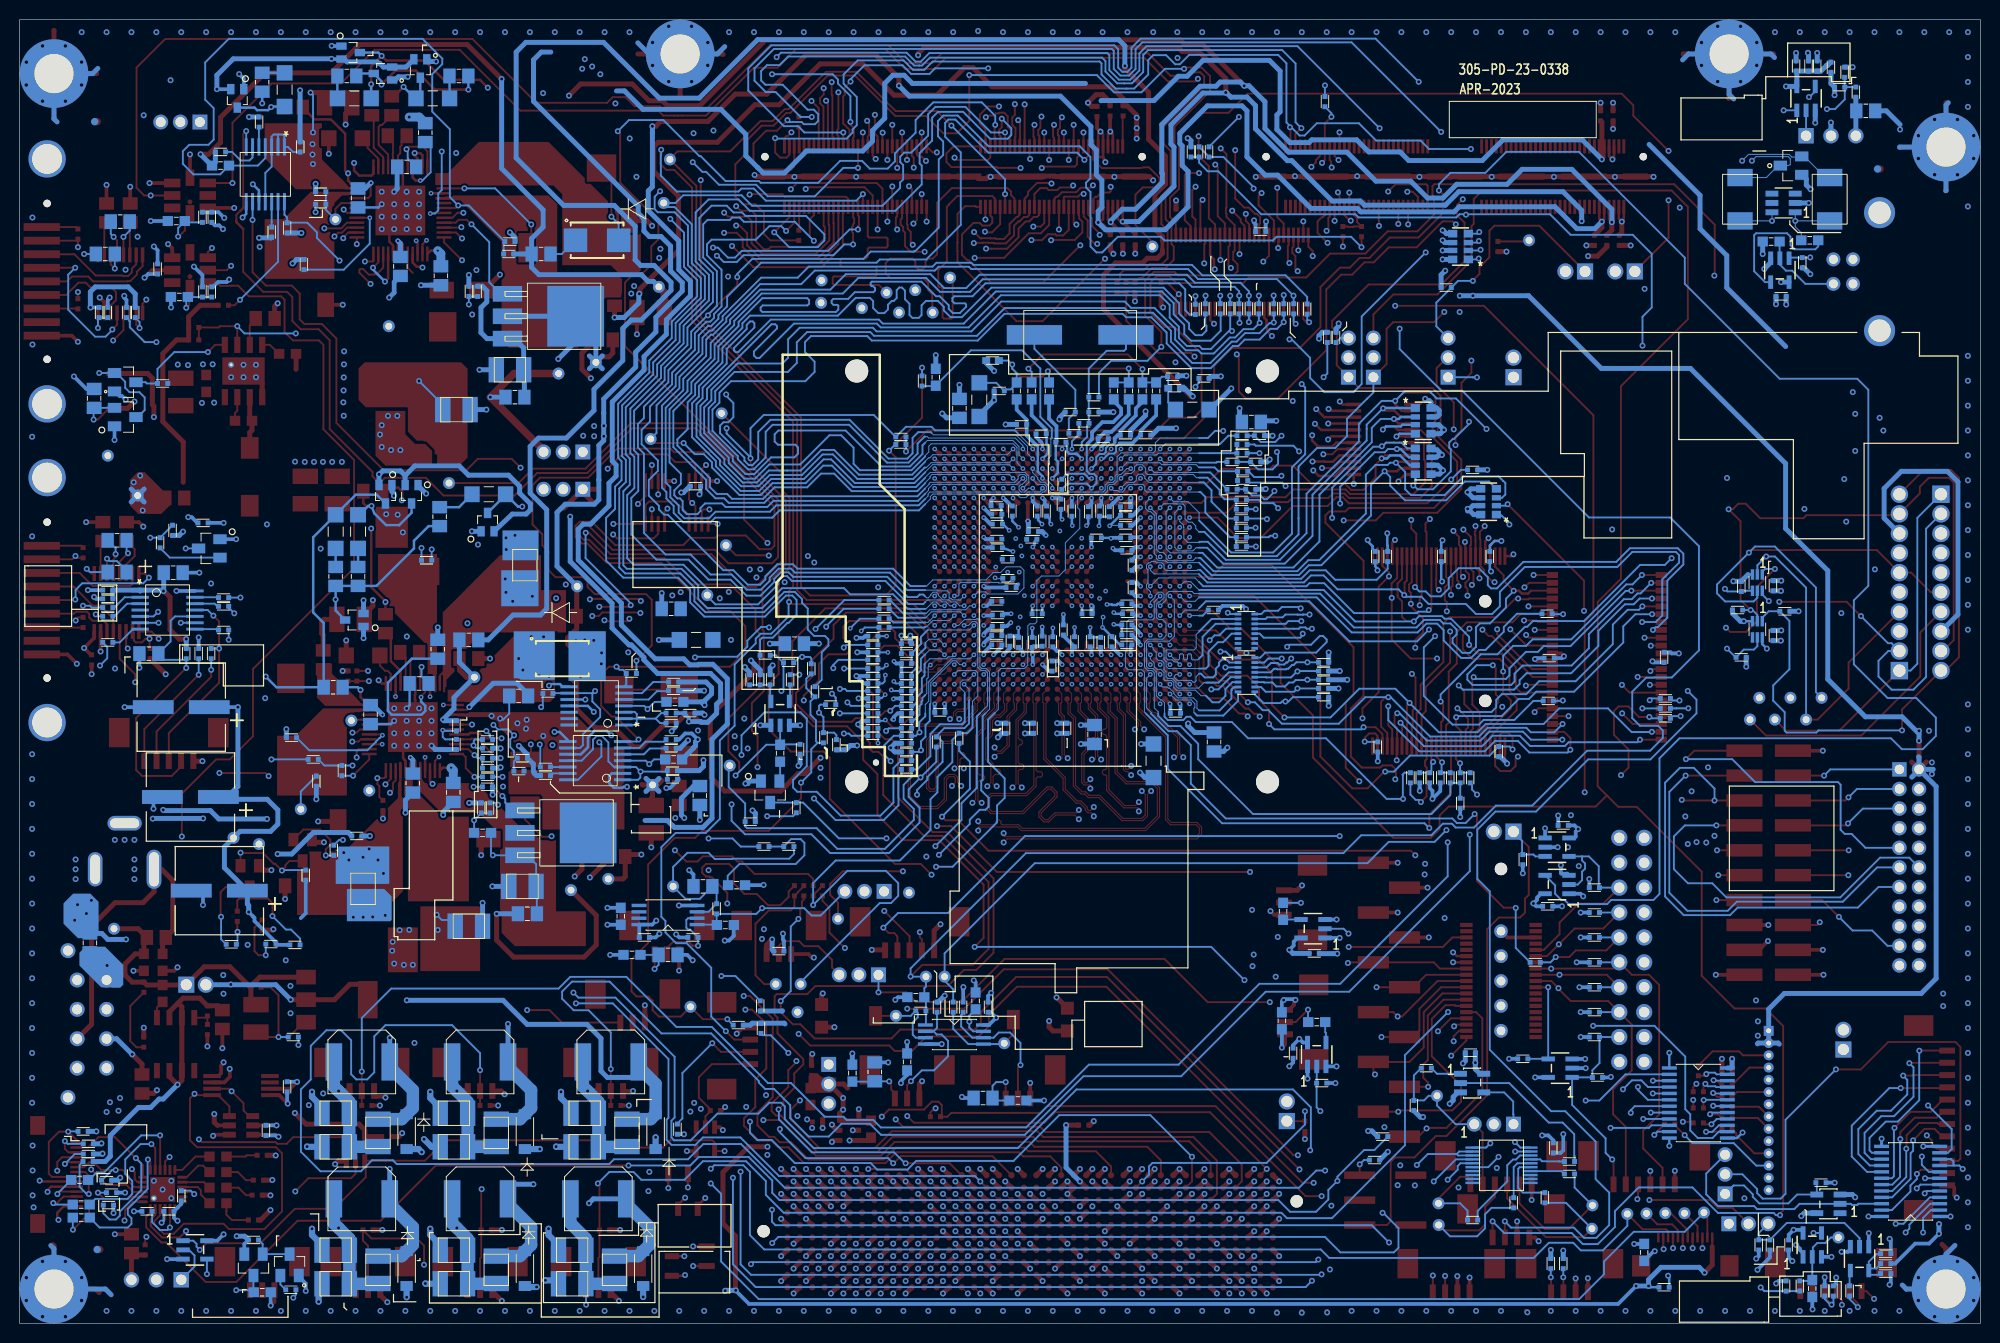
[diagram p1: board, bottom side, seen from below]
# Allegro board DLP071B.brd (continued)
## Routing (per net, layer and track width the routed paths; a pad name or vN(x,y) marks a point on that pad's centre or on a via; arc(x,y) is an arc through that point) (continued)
P2_C7: length 77.4
  TOP w0.193: U11.Y26 v1(100.66,89.2) ; v2(90.08,110.13) 90.34,110.13 91.05,110.84 91.05,112.51 91.46,112.92 91.46,113.2 91.49,113.23 J2.18
  L03_SIG1 w0.102: 92.69,90.17 93.11,89.76 93.69,89.76 94.06,89.39 94.06,87.33 93.59,86.86 93.59,83.64 94.12,83.11 100.7,83.11 101.19,83.59 102.1,83.59 102.27,83.76 102.27,85.36 102.5,85.59 102.61,85.59 103.06,86.04 103.06,86.36 102.83,86.59 102.71,86.59 102.06,87.25 102.06,87.36 101.83,87.59 101.42,87.59 101.06,87.96 101.06,88.36 100.66,88.76 v1(100.66,89.2)
  L03_SIG1 w0.155: 92.69,90.17 92.38,90.48 91.31,90.48 91.12,90.67 86.36,90.67 83.05,93.98 83.05,98.57 82.63,99 82.15,99 81.92,99.23 80.97,99.23 80.69,99.51 80.69,99.88 80.42,100.15 80.03,100.15 79.75,99.88 79.75,99.51 79.48,99.23 78.41,99.23 78.28,99.36 77.99,99.36 77.61,99.74 77.61,100.68 78.03,101.1 78.9,101.1 79.25,101.45 79.25,102.14 79.6,102.49 80.03,102.49 80.31,102.21 80.31,101.69 80.58,101.41 80.97,101.41 81.25,101.69 81.25,102.21 81.52,102.49 81.91,102.49 82.19,102.21 82.19,101.69 82.46,101.41 82.85,101.41 83.13,101.69 83.13,102.21 83.4,102.49 83.85,102.49 84.48,103.11 84.48,104.25 85.1,104.88 85.1,108.65 85.37,108.92 85.37,109.71 86.83,111.17 88.85,111.17 89.04,110.97 89.04,110.32 89.27,110.09 90.04,110.09 v2(90.08,110.13)
P2_C8: length 77.4
  TOP w0.193: J2.17 v2(91.49,121.49) ; U11.V22 v1(98.66,85.2)
  L03_SIG1 w0.102: v1(98.66,85.2) 98.66,85.64 98.27,86.04 98.27,86.36 98.27,86.36 98.27,86.73 98.06,86.94 98.06,87.36 97.82,87.6 97.42,87.6 97.07,87.95 97.07,89.35 96.78,89.64 96.31,89.64 95.78,90.17
  L03_SIG1 w0.155: v2(91.49,121.49) 92,120.98 92,118.07 92.14,117.93 92.14,117.85 92.16,117.83 92.16,117.47 93.15,116.48 93.15,112.24 92.81,111.9 92.81,111.15 93.33,110.63 93.33,109.89 93.41,109.81 93.41,107.25 93.24,107.08 92.45,107.08 92.29,106.92 92.29,99.43 92.68,99.04 92.68,95.66 92.8,95.53 93.13,95.53 93.26,95.66 93.26,99.48 92.85,99.89 92.85,106.36 93.01,106.52 93.24,106.52 93.41,106.36 93.41,106.16 93.64,105.93 93.64,102.41 93.28,102.06 93.28,100.57 94.23,99.63 94.23,99.01 93.79,98.57 93.79,93.06 93.99,92.86 94.24,92.86 94.4,93.01 94.4,93.29 94.64,93.53 95.03,93.53 95.39,93.89 95.39,94.37 95.13,94.62 94.55,94.62 94.32,94.85 94.32,95.22 94.6,95.49 95.24,95.49 95.39,95.65 95.39,96.38 95.59,96.58 95.95,96.58 96.13,96.4 96.13,94.12 95.59,93.58 95.59,92.43 95.11,91.95 95.11,90.84 95.78,90.17
P2_C9: length 77.4
  TOP w0.193: U11.W23 v1(99.66,86.2) ; J2.16 90.99,113.09 90.6,112.7 90.6,111.95 89.83,111.18 v2(89.83,111.04)
  L03_SIG1 w0.102: 93.19,90.17 93.69,90.17 93.79,90.07 93.79,90 94.3,89.49 94.3,87.76 94.47,87.59 95.08,87.59 95.2,87.47 95.2,86.93 95.08,86.8 94.12,86.8 93.8,86.47 93.8,83.89 94.37,83.32 100.63,83.32 101.1,83.8 101.91,83.8 102.07,83.95 102.07,85.45 101.86,85.65 99.89,85.65 99.66,85.87 v1(99.66,86.2)
  L03_SIG1 w0.155: 93.19,90.17 92.34,91.03 86.68,91.03 85.81,91.9 85.81,92.8 85.96,92.94 85.96,93.47 85.48,93.95 84.35,93.95 83.41,94.89 83.41,95.32 83.69,95.59 84.6,95.59 84.87,95.87 84.87,96.26 84.6,96.53 83.69,96.53 83.41,96.81 83.41,98.71 82.77,99.35 82.3,99.35 82.06,99.59 81.68,99.59 81.36,99.9 81.36,100.37 81.5,100.5 81.5,100.86 81.81,101.17 82.2,101.17 82.31,101.06 83.04,101.06 84.2,99.9 84.2,97.86 84.37,97.69 84.77,97.69 84.96,97.88 85.16,97.88 85.49,98.22 86.03,98.22 86.3,98.49 86.3,98.88 86.03,99.16 85.28,99.16 85,99.43 85,100.65 84.73,100.92 84.12,100.92 83.84,101.2 83.84,101.59 84.11,101.86 84.73,101.86 85,102.14 85,104.28 85.46,104.73 85.46,107.22 86.87,108.63 86.87,109.75 87.35,110.24 88.39,110.24 89.1,109.53 90.33,109.53 90.68,109.88 90.68,110.37 90.23,110.82 89.96,110.82 89.83,110.95 v2(89.83,111.04)
P2_HSYNC: length 77.4
  TOP w0.193: TP7.1 106.91,103.17 106.91,105 107.33,105.42 107.33,106.14 107.8,106.61 111.15,106.61 111.66,107.12 111.66,108.17 111.21,108.62 108.93,108.62 108.62,108.32 108.62,107.83 108.32,107.53 107.9,107.53 107.6,107.83 107.6,108.32 107.29,108.62 106.85,108.62 106.42,109.06 106.42,114.31 104.91,115.82 99.23,115.82 98.88,115.46 98.88,115.1 98.53,114.75 98.53,113.95 J2.46 ; U11.W26 v1(99.66,89.2)
  L05_SIG2 w0.102: 99.66,89.6 v1(99.66,89.2)
  L05_SIG2 w0.155: TP7.1 106.87,103.13 106.87,105.47 106.99,105.6 107.59,105.6 107.71,105.47 107.71,105.02 107.71,105.02 107.71,103.47 108.42,102.77 108.42,102.35 109.46,101.3 109.46,94.88 109.59,94.75 109.84,94.75 109.97,94.88 109.97,100.25 110.15,100.43 110.33,100.43 110.54,100.23 110.54,91.71 109.66,90.82 105.47,90.82 104.68,91.61 104.37,91.61 103.5,90.74 103.01,90.74 102.36,91.4 101.86,91.4 101.31,90.85 100.8,90.85 100.69,90.96 100.69,91.16 100.39,91.46 100.07,91.46 99.57,90.96 99.24,90.96 99.01,90.73 99.01,90.25 99.66,89.6
P2_VSYNC: length 119.9
  TOP w0.193: J2.15 90.99,119.1 v2(91.39,118.69) ; v2(132.28,89.81) 135.23,89.81 TP19.1 ; U11.U22 v1(97.66,85.2)
  BOTTOM w0.102: 107.63,86.26 107.63,86.3 107.12,86.81 105.83,86.81 105.83,86.81 105.5,86.81 105.5,86.81 103.83,86.81 103.83,86.81 103.5,86.81 103.5,86.81 97.42,86.81 97.07,86.45 97.07,86.24 97.06,86.24 97.06,85.8 v1(97.66,85.2)
  BOTTOM w0.193: TP19.1 135.04,90.83 135.04,93.65 133.08,95.61 133.08,96.77 130.73,99.11 130.73,100.8 129.77,101.76 129.45,101.76 128.72,102.49 128.72,102.86 127.83,103.75 127.83,104.73 124.36,108.21 112.59,108.21 112.27,108.53 107.52,108.53 104,112.06 104,119.45 105.6,121.05 105.6,122.48 105.27,122.81 104.55,122.81 101.18,119.43 92.13,119.43 v2(91.39,118.69) ; 107.63,86.26 108.57,85.32 114.97,85.32 117.14,87.5 118.03,87.5 119.82,85.71 123.2,85.71 124.4,84.51 126.58,84.51 129.38,87.31 129.38,87.84 130.21,88.68 131.14,88.68 v2(132.28,89.81)
P2P5V: length 244.4
  TOP w0.254: J2.10 89.49,112.63 89.81,112.31 v2(89.99,112.31) J2.12 ; J1.10 38.37,112.63 v2(38.61,112.4) 38.87,112.66 J1.12
  TOP w0.508: C11.1 38.61,111.77 v2(38.61,112.4) ; TP39.1 138.47,45.34 138.23,45.58 R41.1 138.02,47.83 v2(136.58,47.83) ; v2(110.31,126.26) 110.31,127.05 112.73,129.47 119.73,129.47 123.79,125.41 127,125.41 129.79,122.62 134.62,122.62 135.12,122.12 v2(135.46,122.12) ; v2(89.99,112.31) 89.66,111.99 89.54,111.99 88.75,111.19 C14.1
  BOTTOM w0.508: v2(135.46,122.12) 135.46,121.44 135.46,121.44 135.46,115.95 135.87,115.53 135.87,113.52 132.77,110.42 132.77,107.5 131.58,106.31 131.58,104.84 134.03,102.38 134.03,101.95 134.03,100.9 136.31,98.63 136.31,97.25 139.55,94 139.55,87.96 139.16,87.57 139.16,86.44 139.89,85.71 139.89,83.41 141.76,81.53 142.51,81.53 143.02,81.03 143.02,77.88 138.62,73.47 138.62,71.25 135.17,67.79 132.26,67.79 131.65,67.18 130.8,67.18 130.75,67.23 129.29,67.23 127.81,65.76 127.81,61.14 129.37,59.58 129.37,51.53 130.3,50.6 133.21,50.6 133.41,50.8 133.44,50.8 133.88,51.25 133.88,51.27 133.92,51.31 136.21,51.31 ; v2(110.31,126.26) 109.25,125.2 93.83,125.2 90.72,122.09 90.72,120.24 90.17,119.68 90.17,117.17 89.61,116.61 89.61,113.83 89.99,113.45 v2(89.99,112.31) 89.25,111.57 83.15,111.57 80.82,113.9 80.82,117.52 81.41,118.11 81.41,120.12 81.66,120.37 81.66,121.39 78.84,124.21 75.32,124.21 74.81,123.7 74.81,119 72.94,117.14 71.67,117.14 68.28,113.74 63.53,113.74 63.17,113.39 53.68,113.39 53.16,113.91 43.39,113.91 41.16,111.68 39.33,111.68 v2(38.61,112.4)
  vias: v2(159.89,36.58) v2(160.26,40.14) v2(160.81,36.58) v2(161.24,40.11) v2(161.8,36.7) v2(161.95,38.93) v2(162,38.01)
P2P5V_CONN: length 137.5
  TOP w0.508: R20.2 141.43,100.2 142.65,98.98 142.65,97.33 v2(141.73,96.42) ; R41.2 140.16,47.17 v2(141.83,45.49)
  L03_SIG1 w0.508: v2(141.83,45.49) 141.83,46.12 140.95,47 140.95,47.58 136.01,52.51 135.06,52.51 133.27,54.29 133.27,58.03 136.78,61.53 136.78,64.64 138.04,65.91 138.04,66.99 138.76,67.7 138.76,73.92 138.15,74.53 138.15,94.61 139.96,96.42 v2(141.73,96.42)
  L05_SIG2 w0.508: v2(141.83,45.49) 141.83,45.44 141.1,44.7 141.1,41.63 150.54,32.19 166.58,32.19 172.92,38.53 174.33,38.53 176.77,40.98 178.35,40.98 178.77,40.56 186.64,40.56 187.5,41.41 190.97,41.41 192.86,39.52 192.86,36.31 194.13,35.04 J32.8
P2P5V_PMD2: length 24.8
  TOP w0.508: R20.1 139.5,98.99 139.88,98.6 140.67,98.6 TP16.1
  BOTTOM w0.508: Q500.4 141.22,100.69 TP16.1 ; Q500.4 143.28,100.16 v2(145.06,98.38) ; Q500.4 Q500.2 ; TP16.1 141.89,97.38 ; TP16.1 140.56,97.38 ; TP16.1 141.89,98.71 ; TP16.1 140.56,98.71
  vias: v2(161.16,89.09) v2(161.48,92.58) v2(162.12,89.09) v2(162.43,92.58) v2(163.07,91.63) v2(163.07,89.41) v2(163.25,90.68)
P3P3V: length 263
  TOP w0.254: J2.7 88.99,121.34 v2(88.75,121.58) 88.49,121.32 J2.5 ; 55,78.27 55,79.75 v2(54.86,79.88) ; v2(74.08,112.52) 74.08,111.91 74.06,111.89 U4.17 ; v2(65.34,94.04) 65.04,93.74 U8.24 ; J27.14 53.78,36.83 v2(53.78,36.84) ; v2(185.52,10.27) 185.17,10.63 U21.21 ; J27.12 53.4,37.47 v2(53.78,37.85) ; U11.AE26 v1(105.66,89.2)
  TOP w0.279: J1.7 37.87,119.09 v2(37.53,118.75) 37.37,118.9 J1.5
  TOP w0.381: v2(180.27,19.13) 180.15,19.24 U20.4 ; U11.L21 v1(90.66,84.2) ; J49.3 v2(47.25,10.4) ; v2(128.04,22.07) 128.39,21.72 R56.1 ; R58.2 v2(151.19,22.23) ; U16.8 179.75,25.23 179.45,25.53 179.45,26.29 179.2,26.54 v2(179.2,26.63) ; U13.33 v2(30.75,68.34) ; U11.F20 v1(85.66,83.2) ; U13.11 45.21,67.55 v2(45.43,67.77) ; U12.16 192.39,69.92 v2(193.42,68.9) 192.74,68.21 C30.2 ; v2(171.7,24.64) 172.41,23.93 U16.3 ; U3.4 v2(182.63,119.25) ; v1(85.66,80.2) U11.F17 ; U11.AA16 v1(101.66,79.2) ; v1(101.66,72.2) U11.AA10 ; C4.1 88.77,121.6 v2(88.75,121.58) ; R59.2 v2(163.26,22.23) ; J51.3 v2(53.35,4.82) ; U18.5 v2(131.94,17.58) ; R57.2 v2(137.86,22.23) ; U11.F8 v1(85.66,70.2) ; U20.3 173.93,19.24 173.73,19.04 v2(173.59,19.04) ; v1(101.66,82.2) U11.AA19 ; U11.AA7 v1(101.66,69.2) ; U20.5 179.83,20.19 ; v1(100.66,84.2) U11.Y21 ; v1(85.66,73.2) U11.F11 ; U11.R21 v1(95.66,84.2) ; J50.3 v2(41.28,4.58)
  TOP w0.508: v2(94.23,33.25) 94.21,33.25 93.13,32.17 VR1.3 ; v2(83.36,103.64) 83.4,103.64 83.4,103.6 83.57,103.77 R11.1 ; C2.1 v2(37.47,121.86) ; R12.1 v2(86.23,104.27) ; v2(180.15,21.36) 180.15,20.51 179.83,20.19 ; R34.2 v2(185.1,66.22) ; R23.2 188.99,93.34 188.29,94.04 188.29,94.04 v2(188.29,94.04) ; R72.2 v2(150.81,9.53) ; C38.2 v2(25.32,26.99) ; D14.1 174.24,14.61 v2(174.22,14.63) ; v2(174.41,11.56) 175.43,10.54 D12.1 ; R42.2 v2(172.92,43.29) ; v2(186,23.79) 186.33,23.46 R61.1 ; R36.1 v2(162.94,51.5) ; R71.2 v2(138.75,9.53) ; R73.2 v2(163,9.53) ; R8.1 v2(48.34,109.33) ; VR2.3 v2(116.89,30.21) ; v2(173.88,17.12) 173.9,17.15 D15.1 ; v2(113.08,38.1) 111.77,38.1 J24.1 ; R1.1 v2(82.04,114.55) ; J25.1 123.8,38.6 v2(123.24,39.17) ; v2(174.41,13.06) 174.43,13.08 D13.1
  L05_SIG2 w0.381: 86.51,72.97 86.29,73.2 v1(85.66,73.2) ; v1(101.66,69.2) 100.59,69.2 100.57,69.19 ; 100.97,71.59 101.59,72.2 v1(101.66,72.2)
  L07_PWR w0.508: 38.55,26.61 38.49,26.67 J23.1 ; J23.2 35.15,25.81 ; J23.2 35.15,27.53 ; J23.2 33.43,27.53 ; J23.2 33.43,25.81 ; 174.87,48.19 TP42.1 ; TP42.1 174.87,49.6 ; TP42.1 176.28,48.19 ; TP42.1 176.28,49.6 ; J23.1 36.83,25.3 36.63,25.1 ; J23.1 36.83,27.89 ; 116.66,25.6 J46.1 ; J46.1 118.29,25.6 ; J46.1 116.66,27.23 ; J46.1 118.29,27.23 ; 109.16,69.34 109.14,69.35 v2(109.14,70.15)
  BOTTOM w0.203: U504.6 22.25,74.35 v2(21.58,73.69) ; U516.20 46.91,17.93 v2(47.47,18.49)
  BOTTOM w0.254: R584.1 61.72,77.23 61.5,77.01 v2(61.5,76.82) ; v2(21.78,68.83) 22.25,69.3 U506.6 ; R586.1 50.04,76.84 v2(49.91,76.71) ; C573.2 54.99,79.76 v2(54.86,79.88) ; C660.2 185.31,10.49 185.52,10.27 v2(185.52,10.27)
  BOTTOM w0.305: U517.24 v2(11.41,10.9)
  BOTTOM w0.381: R716.2 v2(40.77,31.75) ; R703.2 131.9,37.59 v2(131.35,37.04) ; C653.2 171.72,24.65 v2(171.7,24.64) ; v2(135.06,41.08) 135.47,40.68 U512.8 136.79,40.65 C650.2 ; v2(190.82,104.65) 190.82,104.65 191.01,104.46 R533.2 ; C597.1 86.33,73.2 v1(85.66,73.2) ; R776.1 v2(15.88,4.7) ; v1(85.66,83.2) 86.44,82.42 C568.1 ; R684.1 56.17,54.61 55.89,54.33 v2(55.89,53.51) 55.09,54.31 R685.2 ; R706.2 127.15,39.54 127.63,39.05 v2(128.08,39.05) ; C520.2 73.93,112.14 74.08,112.3 v2(74.08,112.52) ; R709.2 v2(40.77,39.37) ; v1(101.66,69.2) 101.66,69.4 101.25,69.81 101.21,69.81 C580.1 ; C582.1 100.85,72.2 v1(101.66,72.2) ; C665.2 19.55,8.53 19.55,9.04 v2(19.05,9.54) 18.2,9.54 18.08,9.43 U522.5 ; R715.2 v2(40.89,34.29) ; v2(74.9,72.86) 75.23,73.19 77.3,73.19 R601.1 ; C564.1 90.66,83.66 v1(90.66,84.2) ; R681.1 v2(61.47,57.34) ; U519.8 101.13,30.44 v2(100.39,31.18) 100.95,31.74 C662.2 ; R704.2 132.72,39.37 v2(133.03,39.69) ; v2(173.59,19.04) 173.73,19.04 173.85,19.16 C655.2 ; C629.2 45.33,67.87 v2(45.43,67.77) ; U520.5 69.65,39.32 70.04,38.93 70.04,38.54 v2(70.48,38.1) ; U511.5 41.41,49.52 41.27,49.66 41.27,50.17 v2(41.02,50.42) 41.4,50.8 C646.2 ; R763.2 22.61,6.86 v2(22.86,6.6) ; v2(20.83,4.06) 20.56,4.33 R774.2 ; R723.2 v2(48.07,26.99) ; R520.1 184.57,103.65 v2(184.56,103.64) ; v2(110.68,33.01) 110.41,33.27 R750.2 ; C556.1 100.84,79.17 101.63,79.17 v1(101.66,79.2) ; R717.2 v2(40.77,29.21) ; R772.2 103.82,22.99 103.82,23.1 v2(103.89,23.1) ; C515.2 185.93,109.47 v2(186.31,109.86) ; v1(85.66,70.2) 85.66,70.33 85.88,70.55 85.88,70.59 C598.1 ; R771.2 v2(111.41,26.62) ; C659.2 43.56,18.67 44.07,19.18 44.69,19.18 v2(44.7,19.17) ; C540.1 100.91,83.95 v1(100.66,84.2) ; C555.1 100.95,81.53 101.57,82.15 101.61,82.15 v1(101.66,82.2) ; R765.1 9.13,8.5 v2(9.26,8.62) ; C562.1 95.44,83.58 95.44,83.98 v1(95.66,84.2) ; C663.2 33.3,7.36 v2(33.21,7.36) ; C674.2 70.1,28.38 v2(69.47,29.02) 69.1,28.65 U521.5 ; R697.2 v2(39.89,45.33) ; v1(85.66,80.2) 86.6,80.2 C570.1 ; R731.2 v2(189.25,13.34) ; U514.5 v2(45.42,25.1) ; R743.2 v2(190.42,11.25) ; R754.2 103.76,34.04 103.74,34.06 v2(103.74,34.31) ; R735.1 v2(132.23,19.29) ; v2(102.68,34.99) 102.49,34.8 R755.2 ; R710.2 v2(41.18,36.83) ; R708.2 v2(40.77,41.91) ; C661.2 v2(109.47,28.7) ; R696.2 v2(46.67,45.91) ; C630.2 31.61,68.47 31.49,68.34 v2(30.75,68.34) ; v2(179.26,111.63) 179.64,112.01 180.09,112.01 180.39,112.32 C509.2 ; U510.5 44.82,43.83 45.21,43.43 45.21,43.22 v2(45.59,42.84) 45.3,42.55 C652.2 ; R515.2 v2(186.63,112.46) ; v2(14.86,14.35) R740.2 ; C648.2 v2(140.04,40.67)
  BOTTOM w0.508: v2(17.34,107.04) 17.99,107.68 R530.2 ; C603.2 v2(20.33,74.73) ; R639.1 v2(64.58,65.66) ; C538.1 75.56,92.19 v2(75.56,93.34) ; U515.24 25.45,26.05 25.32,26.18 v2(25.32,26.99) ; R760.1 v2(43.81,7.49) ; v2(109.14,70.15) 109.14,69.47 R600.2 ; R522.1 171.76,108.53 v2(172.16,108.13) ; R737.2 62.06,19.63 v2(62.45,19.63) ; R504.2 17.53,129.61 17.59,129.67 v2(17.59,129.6) ; U503.5 v2(20.34,106.22) ; v2(67.46,100.46) 67.46,100.78 67.13,101.1 R548.1 ; v2(123.19,67.12) 123.19,67.12 123.44,66.87 R620.1 ; DN504.3 17.75,116.7 17.75,116.13 v2(17.31,115.7) ; v2(65.34,66.55) 65.34,66.55 R638.1 ; R728.2 191.71,18.31 v2(191.66,18.36) ; U523.5 17.97,11.24 v2(18.27,10.95) ; R549.1 65.72,101.47 65.45,101.74 v2(65.45,102) ; C664.2 70.13,37.74 v2(70.48,38.1) ; R507.2 v2(13.03,128.16) ; R672.2 115.71,58.51 115.27,58.95 v2(114.58,58.95) ; R654.1 151.11,58.67 151.09,58.65 v2(150.94,58.65) ; R656.1 151.17,56.64 151.09,56.72 150.94,56.72 v2(150.94,56.72) ; R640.1 v2(65.47,64.77) ; RN503.5 51.97,85.13 v2(52.31,84.79) 51.75,84.22 RN503.6 ; R641.1 v2(66.47,63) ; v2(151.75,53.92) R658.1 ; R762.1 v2(42.55,7.43) ; C604.2 v2(20.35,69.65) ; v2(80.86,120.9) 80.77,120.9 80.52,120.65 R512.1 ; R649.2 v2(169.74,53.47) ; R637.1 v2(66.47,68.44) ; R675.2 110.69,59.18 v2(111.15,58.72) 110.72,58.29 R676.2 ; R729.2 191.59,17.27 v2(191.54,17.32) ; v2(105.89,92.82) 105.46,92.38 C526.1 ; R752.2 106.29,32.78 v2(105.64,33.43) ; C654.1 51.51,27.6 v2(51.51,26.59) 51.51,25.93 51.04,25.46 U513.5 ; v2(189.74,14.86) 189.99,14.61 R730.2 ; C521.2 v2(19.8,103.94) ; R693.2 124.96,52.03 v2(125.25,52.32) ; v2(123.24,39.17) 123.24,38.14 C651.2 ; R726.2 v2(192.18,19.58) ; v2(54.58,107.39) 55,106.97 R528.1 ; C577.1 v2(118.48,69.34) ; RN503.8 51.68,82.51 52.29,83.12 v2(52.29,83.1) 52.29,82.89 51.76,83.42 RN503.7 ; R647.1 v2(172.8,60.62)
P3P3V_CONN: length 100.7
  TOP w0.508: v2(188.51,27.44) 187.52,26.45 R61.2
  L03_SIG1 w0.508: v2(188.51,27.44) 187.83,27.44 187.73,27.53 186.87,27.53 186.37,28.03 186.37,38.55 185.02,39.9 185.02,48.84 185.36,49.18 v2(185.36,52.38)
  L05_SIG2 w0.508: v2(174.77,51.46) 173.36,50.04 168.23,44.92 161.09,44.92 159.09,46.92 146.53,46.92 140.93,52.52 135.62,52.52 134.04,54.11 v2(134.04,54.61) 134.03,54.61 134.03,59.86 v2(133.49,60.4)
  BOTTOM w0.381: R667.2 132.78,55.5 133.67,54.61 v2(134.04,54.61) ; v2(133.49,60.4) 133.02,60.87 R615.2
  BOTTOM w0.508: v2(188.51,27.44) 188.51,27.44 190.1,29.03 J32.2 ; v2(185.36,52.38) 185.29,52.31 180.54,52.31 179.69,51.46 v2(174.77,51.46)
P3P3V_EX: length 132.2
  L03_SIG1 w0.762: TP23.1 188.65,83.77 188.65,80.7 188.06,80.11 188.06,72.49 189.89,70.66 189.89,68.38 189.26,67.74 189.26,65.32 190.32,64.26 190.32,57.87 196.5,51.69 196.5,25.68 195.33,24.51 193.9,24.51 192.37,22.98
  L05_SIG2 w0.762: 178.03,20.35 175.72,18.03 172.49,18.03 171.07,19.46 166.33,19.46 165.43,20.35 130.09,20.35 129.33,21.11 129.33,22.87 128.57,23.63 126.41,23.63 124.85,25.19 123.06,25.19
  BOTTOM w0.508: TP23.1 188.62,85.12 ; TP23.1 187.3,85.12 ; TP23.1 187.3,83.79 ; TP23.1 188.62,83.79
  vias: v2(187.45,82.93) v2(187.71,86.49) v2(188.37,85.8) v2(189.76,22.99) v2(189.92,21.69) v2(190.79,22.56) v2(191.13,21.56)
P3P3V_LP: length 540.2
  TOP w0.508: 183.84,32.68 183.34,33.17 181.62,33.17 R46.1 179.77,32.4 C37.2 ; 183.84,32.68 183.46,32.3 U17.3 U17.6 183.46,24.79 v2(183.9,24.35) 184.73,25.18 U17.7 ; 183.84,32.68 184.73,31.79 U17.2 ; C41.2 164.74,19.05 U19.5 164.8,19.74 165.38,20.32 170.79,20.32 v2(171.93,21.46)
  L03_SIG1 w0.508: v2(139.23,124.45) 139.23,128.21 141.36,130.34 165.07,130.34 168.04,127.36 169.82,127.36 v2(171.39,125.79) 172.39,125.79 175.55,128.96 180.57,128.96 184.1,125.43 187.16,125.43 192,120.59 192,108.2 192.6,107.6 192.6,103.81 v2(192.77,103.63) 192.77,101.86 192.78,101.86 192.78,101.23 192.28,100.74 192.28,98.15 192.76,97.67 192.76,93.58 191.23,92.05 191.23,88.89 191.01,88.67 TP20.1 192.21,87.32 192.21,77.33 191.82,76.94 191.82,74.68 192.4,74.1 v2(192.41,74.1) ; v2(183.9,24.35) 184.48,24.93 187.61,24.93 189.48,26.81 189.48,28.3 188.67,29.11 188.67,30.53 187.4,31.8 187.4,43.13 187.51,43.24 187.51,48.58 186.42,49.67 v2(186.42,51.49) 187.36,52.43 187.36,53.15 186.54,53.98 186.54,66.78 184.27,69.05 182.67,69.05 v2(181.74,69.98) 181.74,71 182.99,72.25 182.99,74.98 185.13,77.12 185.13,79.82 184.18,80.77 v2(183.33,80.77) 180.09,80.77 v2(179.2,81.66)
  L05_SIG2 w0.508: v2(181.74,69.98) 181.74,70.89 183.45,72.61 184.51,72.61 186.01,74.1 v2(192.41,74.1) ; v2(143.84,82.3) 140.03,82.3 136.53,85.8 134.57,85.8 133.53,84.76 v2(132.51,84.76) ; v2(139.23,124.45) 130.48,124.45 124.08,130.86 36.73,130.86 30.25,124.38 21.48,124.38 20.85,125 19.41,125 18.04,126.37 15.95,126.37 v2(14.87,125.3) ; v2(181.28,51.51) 180.5,50.73 177.37,50.73 176.8,50.17 176.8,48.5 175.97,47.67 173.9,47.67 v2(173.69,47.88) 172.87,47.88 168.64,43.65 159.38,43.65 157.44,45.59 146.58,45.59 140.96,51.21 134.72,51.21 130.25,55.68 v2(130.25,57.45) 131.29,57.45 132.62,58.78 132.62,60.51 v2(131.74,61.39) ; v2(183.9,24.35) 183.9,23.9 182.51,22.52 173.9,22.52 172.85,21.46 v2(171.93,21.46)
  BOTTOM w0.381: C548.2 v2(179.2,81.66) ; v2(131.74,61.39) 131.74,61.75 132.16,62.17 C611.2 R614.2 ; v2(192.41,74.1) 192.21,73.91 R587.1 ; v2(192.77,103.63) 192.77,103.64 R532.2 ; R607.1 v2(181.74,69.98)
  BOTTOM w0.508: v2(143.84,82.3) 143.84,77.72 139.57,73.46 139.57,70.94 137.84,69.21 137.6,69.21 136.32,67.93 136.32,67.69 134.92,66.29 129.51,66.29 128.5,65.28 128.5,63.58 128.91,63.17 128.91,62.23 129.82,61.32 130.45,61.32 130.53,61.39 v2(131.74,61.39) ; v2(132.51,84.76) 132.28,84.76 131.64,85.41 C539.2 ; v2(171.39,125.79) 171.39,120.54 R511.2 ; R727.2 191.28,16.51 190.78,17.01 190.78,17.04 190.75,17.07 190.75,19.15 187.88,22.02 186.64,22.02 185.78,22.89 185.36,22.89 v2(183.9,24.35) ; C640.2 166.48,50.07 170.04,50.07 172.24,47.88 v2(173.69,47.88) ; v2(183.33,80.77) 183.73,80.38 R575.2 ; v2(181.28,51.51) 186.4,51.51 v2(186.42,51.49) ; v2(130.25,57.45) 130.25,56.82 130.68,56.39 R666.2 ; v2(14.87,125.3) R506.2 15.24,126.48 R505.2 ; v2(192.77,103.63) 192.79,103.65 192.79,105.23 192.28,105.74 188.93,105.74 188.21,105.03 R535.2
P_CLK1: length 77.6
  TOP w0.193: J2.54 100.53,113.95 100.53,114.75 100.78,115 104.36,115 105.23,114.13 105.23,114.09 105.42,113.89 105.42,108.34 106.13,107.63 106.16,107.63 106.3,107.48 106.3,105.83 106.17,105.7 105.98,105.7 105.85,105.57 105.85,102.63 105.73,102.5 104.95,102.5 104.82,102.63 104.82,106.55 104.95,106.68 TP6.1 ; U11.AE22 v1(105.66,85.2)
  L05_SIG2 w0.102: v1(105.66,85.2) 105.89,85.2 106.27,85.58 106.27,86.36 106.71,86.81 107.63,86.81
  L05_SIG2 w0.155: TP6.1 111.82,106.68 113.16,105.35 113.16,103.01 113.6,102.57 115.69,102.57 117.87,100.39 117.87,89.71 117.59,89.43 117.16,89.43 116.9,89.69 116.9,94.06 116.62,94.34 116.09,94.34 115.87,94.12 115.87,87.34 114.54,86 108.83,86 108.02,86.81 107.63,86.81
P_CLK2: length 79.7
  TOP w0.193: v2(88.71,115.95) 88.71,115.49 88.84,115.37 89.66,115.37 90.09,114.93 90.27,114.93 90.49,114.71 J2.14 ; U11.W25 v1(99.66,88.2)
  L03_SIG1 w0.155: v2(88.71,115.95) 88.98,116.22 88.98,117.39 88.52,117.86 88.52,118.83 90.55,120.86 90.55,122.87 92.95,125.28 101.34,125.28 102.83,123.79 106.99,123.79 107.33,123.45 107.33,119.21 106.94,118.83 106.94,117.91 106.45,117.41 106.45,114.57 106.89,114.13 106.89,112.16 106.94,112.1 106.94,109.91 106.74,109.71 106.74,108.93 107.78,107.9 107.78,106.28 TP8.1
  L05_SIG2 w0.102: v1(99.66,88.2) 99.66,88.64 100.06,89.04 100.06,89.36 100.05,89.37 100.05,89.7
  L05_SIG2 w0.155: 100.05,89.7 100.4,90.05 107.47,90.05 107.63,89.88 110.17,89.88 111.49,91.21 111.49,101.1 110.41,102.18 109.91,102.18 109.36,102.73 109.36,103.16 108.65,103.86 108.65,105.4 TP8.1
P_CLK3: length 79.4
  TOP w0.193: J2.119 121.99,120.79 121.98,120.8 121.98,120.94 121.78,121.13 121.65,121.13 v2(121.27,121.5) ; U11.AF23 v1(106.66,86.2)
  L05_SIG2 w0.155: v1(106.66,86.2) 107.8,85.06 114.97,85.06 118.81,88.9 118.81,100.77 116,103.58 TP11.1 114.1,104.57 114.11,104.58 114.11,105.74 112.15,107.7 107.12,107.7 105.21,109.61 105.21,110.17 104.81,110.56 104.81,116.39 103.09,118.11 103.09,119.57 104.29,120.78 105.04,120.78 108.19,123.92 113.3,123.92 114.15,123.08 114.15,122.66 114.83,121.98 115.5,121.98 115.72,122.2 117.6,122.2 118.29,121.5 v2(121.27,121.5)
P_DATAEN1: length 78.1
  TOP w0.193: J2.87 v2(113.99,121.49) ; U11.AF22 v1(106.66,85.2)
  L05_SIG2 w0.155: v1(106.66,85.2) 106.69,85.17 106.69,84.84 107.41,84.12 107.51,84.12 107.76,83.87 115.28,83.87 119.75,88.34 119.75,101.55 120.36,102.16 120.36,104.88 119.88,105.36 119.49,105.36 TP13.1 117.34,104.11 116.8,104.65 116.8,109.13 116.46,109.47 114.44,109.47 113.55,110.36 111.98,110.36 110.33,108.71 107.45,108.71 106.52,109.64 106.52,110.18 106.15,110.56 105.75,110.95 105.75,116.77 105.56,116.97 105.56,117.16 104.4,118.33 104.39,118.33 104.04,118.68 104.04,119.2 104.66,119.81 105.4,119.81 108.5,122.91 112.3,122.91 113.13,122.09 113.39,122.09 v2(113.99,121.49)
P_DATAEN2: length 77.5
  TOP w0.193: U11.W24 v1(99.66,87.2) ; v2(101.45,123.05) 101.29,123.21 100.66,123.21 100.43,123.43 100.15,123.43 100.07,123.51 99.57,123.51 99.21,123.15 99.21,122.08 98.88,121.74 98.88,121.24 98.99,121.13 J2.47
  L03_SIG1 w0.155: TP9.1 110.33,103.16 110.33,104.53 110.52,104.72 110.52,106.18 110.39,106.3 109.72,106.3 109.59,106.18 109.59,104.92 109.09,104.42 108.23,104.42 107.66,104.99 107.65,104.99 107.1,105.54 107.1,105.55 106.84,105.82 106.84,107.51 105.8,108.54 105.8,109.32 105.8,109.32 105.8,113.89 105.51,114.18 105.51,117.81 105.84,118.14 105.84,120.15 103.14,122.85 101.65,122.85 v2(101.45,123.05)
  L05_SIG2 w0.102: 107.45,88.18 107.07,87.8 106.33,87.8 106.15,87.62 105.49,87.62 105.26,87.85 105.26,89.49 105.12,89.62 102.48,89.62 102.2,89.34 102.2,88.87 101.94,88.62 101.53,88.62 101.27,88.36 101.27,88.23 100.84,87.8 100.42,87.8 99.82,87.2 v1(99.66,87.2)
  L05_SIG2 w0.155: TP9.1 110.32,103.14 111.48,103.14 111.74,102.89 111.74,102.21 112.45,101.5 112.72,101.5 113.03,101.19 115.12,101.19 115.82,100.5 115.82,99.91 115.29,99.38 113.18,99.38 112.45,98.64 112.45,96.38 114.44,94.39 114.44,93.24 114.06,92.86 113.12,92.86 112.76,92.51 112.76,87.73 112.44,87.41 109.36,87.41 108.59,88.18 107.45,88.18
P_INTZ: length 61.8
  TOP w0.193: v2(154.88,108.46) 156.72,110.3 U2.36
  L03_SIG1 w0.155: v2(154.88,108.46) 155.21,108.13 155.21,106.52 154.88,106.19 154.88,75.1 150.3,70.53 150.3,66.15 147.62,63.47 147.62,60.17 148.47,59.33 148.47,57.24 149.95,55.75 v2(150.75,55.75)
  BOTTOM w0.193: R657.1 v2(150.75,55.75)
PACKET_RDY: length 133.9
  TOP w0.193: J14.9 3.83,68.59 2.72,69.7 2.72,85.78 3.2,86.26 5.26,86.26 6.17,85.34 6.17,84.67 J15.9 8.39,82.45 17.74,82.45 18.05,82.14 22.45,82.14 23.93,83.62 24.69,83.62 25.26,83.05 v2(25.68,83.05) 24.46,81.84 24.46,73.8 v2(23.43,72.77) ; U11.F25 v1(85.66,88.2)
  L03_SIG1 w0.155: v2(23.43,72.77) 23.26,72.6 23.26,64.53 TP30.1
  L05_SIG2 w0.102: 80.07,87.42 80.45,87.81 84.83,87.81 85.22,88.2 v1(85.66,88.2)
  L05_SIG2 w0.155: 80.07,87.42 77.34,87.42 75.27,89.49 71.36,89.49 68.29,86.42 66.7,86.42 64.29,88.83 60.82,88.83 60.59,88.6 56.07,88.6 55.46,89.21 54.55,89.21 54.17,88.82 31.45,88.82 v2(25.68,83.05)
  BOTTOM w0.193: U506.2 22.75,72.27 23.24,72.77 v2(23.43,72.77) R603.2
PB_INDEX: length 246.3
  TOP w0.193: TP21.1 126.94,78.36 123.59,78.36 v2(123.59,78.33) ; J15.10 5.77,87.07 3,87.07 2.18,86.26 2.18,67.95 3.54,66.59 J14.10 7.99,62.62 v2(7.99,60.49) ; J24.2 110.47,39.5 110.79,39.82 111.36,39.82 v2(111.9,40.36) ; U11.AE9 v1(105.66,71.2)
  L03_SIG1 w0.102: 107.35,67.86 106.56,68.65 104.59,68.65 104.14,69.1 104.14,70.54 104.34,70.74 105.2,70.74 v1(105.66,71.2) 106.27,71.81 107.63,71.81
  L03_SIG1 w0.155: 107.35,67.86 108.59,66.63 108.59,61.59 107.05,60.06 107.05,59.29 106.76,59 106.76,54.07 109.09,51.74 109.09,47.9 107.97,46.78 107.97,44.89 107.91,44.83 107.91,42.61 110.16,40.36 v2(111.9,40.36) ; 107.63,71.81 107.74,71.91 113.94,71.91 116.24,74.21 119.43,74.21 123.59,78.36 v2(123.59,78.33)
  L05_SIG2 w0.155: v2(65.35,49.71) 63.94,51.13 54.06,51.13 53.72,50.79 51.57,50.79 49.73,52.63 45.85,52.63 43.33,55.14 33.36,55.14 28.01,60.49 v2(7.99,60.49)
  BOTTOM w0.193: v2(111.9,40.36) 110.4,41.86 105.3,41.86 97.45,49.71 v2(65.35,49.71) ; U506.1 22.25,71.99 21.59,72.64 R605.2 19.47,71.66 19.47,66.73 21.13,65.08 21.13,63.52 19.96,62.35 19.96,60.45 19.77,60.27 16.73,60.27 16.51,60.49 v2(7.99,60.49)
PB_IR_ENABLE: length 45
  TOP w0.193: J24.3 109.22,39.49 v2(111.8,42.07) ; U11.AD9 v1(104.66,71.2)
  L05_SIG2 w0.155: v2(111.8,42.07) 110.47,43.4 110.47,44.51 108.24,46.74 107.29,46.74 106.23,47.8 v2(106.23,47.8)
  BOTTOM w0.102: v1(104.66,71.2) 104.22,71.2 103.62,71.8 102.48,71.8 102.41,71.87 102.26,71.87 102.06,71.66 102.06,71.04 102.04,71.02 102.04,70.38 102.06,70.36 102.06,67.01 101.84,66.8 101.42,66.8 101.07,66.45 101.07,62.65 101.49,62.23
  BOTTOM w0.193: v2(106.23,47.8) 103.08,50.94 103.08,51.38 102.07,52.4 101.48,52.4 101.16,52.72 101.16,53.62 101.91,54.37 101.91,55.31 101.77,55.46 101.77,61.95 101.49,62.23
PGOOD: length 58.9
  TOP w0.193: U2.35 155.48,111.29 v2(154.88,110.68)
  L03_SIG1 w0.155: v2(150.94,57.66) 150.25,58.36 150.25,60.28 150.04,60.49 150.04,65.05 150.74,65.75 150.74,70.01 155.31,74.58 155.31,105.7 155.63,106.03 155.63,109.92 v2(154.88,110.68)
  BOTTOM w0.483: v2(150.94,57.66) 151.09,57.66 151.09,57.66 R655.1
PIPESTAT0: length 76.5
  TOP w0.193: J27.38 52.43,28.85 v2(53.98,27.31)
  L03_SIG1 w0.155: v2(69.27,71.64) 69.2,71.57 67.16,71.57 64.62,69.04 64.62,67.49 63.65,66.52 63.65,66.38 63.39,66.12 63.39,64.27 63.65,64.02 63.91,63.76 63.91,62.91 64.49,62.33 64.49,62.15 65.28,61.36 65.28,60.82 65.28,54.58 64.87,54.17 64.2,54.17 63.77,53.75 63.77,51.21 63.44,50.88 62.77,50.88 62.52,50.63 62.52,46.31 62.35,46.14 61.31,46.14 61.14,45.96 61.14,45.63 61.31,45.45 62.36,45.45 62.54,45.27 62.54,44.94 62.36,44.77 61.25,44.77 61.07,44.59 61.07,44.26 61.25,44.08 62.35,44.08 62.52,43.91 62.52,38.72 62.35,38.55 62.04,38.55 61.84,38.75 61.84,43.14 61.67,43.3 61.22,43.3 61.01,43.09 61.01,41.3 60.03,40.32 60.03,36.3 55.39,31.66 55.39,31.16 54.73,30.5 54.73,28.84 53.98,28.09 v2(53.98,27.31)
  BOTTOM w0.193: RN504.14 70.87,71.36 70.59,71.64 v2(69.27,71.64)
PIPESTAT0R: length 12.4
  TOP w0.193: U11.C6 v1(82.66,68.2)
  BOTTOM w0.102: 79.69,67.82 79.82,67.69 80.37,67.69 80.47,67.79 80.47,68.2 80.57,68.3 80.78,68.3 80.88,68.2 80.88,67.79 80.98,67.69 81.18,67.69 81.29,67.79 81.29,68.2 81.39,68.3 81.59,68.3 81.69,68.2 81.69,67.79 81.79,67.69 82.15,67.69 v1(82.66,68.2)
  BOTTOM w0.193: 79.69,67.82 79.34,68.17 79.34,70.03 78.01,71.36 RN504.3
PIPESTAT1: length 78.3
  TOP w0.193: J27.36 53.17,29.85 53.73,29.29 v2(53.73,28.78)
  L03_SIG1 w0.155: v2(68.43,72.31) 68.37,72.26 67.23,72.26 64.19,69.22 64.19,67.67 64.19,67.67 63.22,66.7 63.22,66.56 62.96,66.3 62.96,64.1 63.47,63.58 63.47,62.63 64.85,61.25 64.85,58.27 64.67,58.09 63.65,58.09 63.47,57.91 63.47,57.58 63.65,57.4 64.67,57.4 64.85,57.22 64.85,56.89 64.67,56.72 63.65,56.72 63.47,56.54 63.47,56.21 63.65,56.03 64.67,56.03 64.85,55.85 64.85,55.25 64.48,54.88 63.77,54.88 63.6,54.7 63.54,54.7 63.34,54.51 63.34,51.58 63.22,51.46 62.83,51.46 62.7,51.58 62.7,54.87 62.58,55 62.19,55 62.06,54.87 62.06,50.3 61.89,50.12 60.93,50.12 60.76,49.94 60.76,49.61 60.93,49.44 61.89,49.44 62.06,49.26 62.06,48.93 61.89,48.75 60.5,48.75 60.37,48.62 60.37,48.19 60.5,48.06 61.89,48.06 62.06,47.89 62.06,47 61.87,46.81 60.69,46.81 60.42,46.54 60.42,41.65 59.45,40.68 59.45,36.93 54.98,32.46 54.98,31.6 54.29,30.91 54.29,29.34 v2(53.73,28.78)
  BOTTOM w0.193: v2(68.43,72.31) 69.08,72.31 69.1,72.29 69.63,72.29 69.64,72.31 70.88,72.31 71.17,72.03 72.74,72.03 72.91,71.86 RN504.15
PIPESTAT1R: length 12.6
  TOP w0.193: U11.B5 v1(81.66,67.2)
  BOTTOM w0.102: v1(81.66,67.2) 81.95,67.49 82.24,67.49 82.44,67.69 82.87,67.69 83.07,67.89 83.07,68.64 82.99,68.71 80.2,68.71 79.99,68.92 79.99,70.28 79.69,70.57
  BOTTOM w0.193: RN504.2 78.4,71.86 79.69,70.57
PIPESTAT2: length 76.6
  TOP w0.193: J27.34 53.5,30.48 v2(53.68,30.3)
  L03_SIG1 w0.155: v2(69.33,72.95) 67.29,72.95 63.76,69.41 63.76,67.85 62.79,66.88 62.79,66.74 62.53,66.48 62.53,63.92 62.77,63.68 62.77,62.83 64.38,61.21 64.38,59.06 63.99,58.66 63.25,58.66 62.83,58.23 62.83,55.97 62.37,55.52 61.79,55.52 61.46,55.18 61.46,50.94 61.09,50.57 60.66,50.57 59.67,49.58 59.67,48.26 59.49,48.08 58.81,48.08 58.31,47.57 58.31,46.37 58.65,46.02 59.49,46.02 59.67,45.84 59.67,45.05 58.61,43.99 58.61,37.44 58.42,37.26 58.1,37.26 57.92,37.43 57.92,44.57 57.8,44.7 57.41,44.7 57.24,44.52 57.24,36.54 53.68,32.97 v2(53.68,30.3)
  BOTTOM w0.193: RN504.16 73.34,72.36 73.01,72.69 71.63,72.69 71.25,73.08 69.5,73.08 69.38,72.95 v2(69.33,72.95)
PIPESTAT2R: length 14.7
  TOP w0.193: U11.A4 v1(80.66,66.2)
  L03_SIG1 w0.155: v2(76.76,72.49) 76.9,72.36 76.9,68.29 77.67,67.52 77.67,64.45 78.07,64.05 78.81,64.05 79.57,64.81 79.57,65.44 80.33,66.2 v1(80.66,66.2)
  BOTTOM w0.193: v2(76.76,72.49) 76.72,72.45 76.72,72.45 76.63,72.36 RN504.1
PLLD_VAD: length 10.3
  TOP w0.381: U11.K25 v1(89.66,88.2)
  BOTTOM w0.203: v1(89.66,88.2) 89.43,88.2 88.89,88.73 88.36,88.73 88.16,88.93 88.16,89.42 87.8,89.78
  BOTTOM w0.381: FB506.2 84.07,92.63 85.66,91.04 C535.1 86.5,89.78 87.8,89.78
PLLD_VDD: length 16.5
  TOP w0.381: U11.L22 v1(90.66,85.2)
  BOTTOM w0.102: 91.15,89.66 91.09,89.72
  BOTTOM w0.203: 91.15,89.66 91.15,86.97 90.84,86.66 90.43,86.66 90.16,86.39 90.16,85.71 v1(90.66,85.2) 91.13,85.66 93.12,85.66 C543.1
  BOTTOM w0.381: 91.09,89.72 90.61,90.2 90.61,90.89 89.56,91.94 88.45,91.94 87.65,92.74 87.65,93.33 88.39,94.08 FB503.2
PLLM1_VAD: length 10.5
  TOP w0.381: U11.L24 v1(90.66,87.2)
  BOTTOM w0.203: 88.29,89.88 88.51,89.66 88.84,89.66 89.2,89.3 89.2,88.89 89.41,88.69 89.85,88.69 90.18,88.36 90.18,87.68 v1(90.66,87.2)
  BOTTOM w0.381: 88.29,89.88 88.29,90.31 88.01,90.6 C534.1 87.73,91.03 86.15,92.62 86.15,93.34 85.47,94.01 FB505.2
PLLM1_VDD: length 7.7
  TOP w0.381: U11.L26 v1(90.66,89.2)
  BOTTOM w0.381: FB504.2 86.87,92.71 88.63,90.94 89.3,90.94 C533.1 89.99,89.87 v1(90.66,89.2)
PLLM2_VAD: length 7.7
  TOP w0.381: U11.R25 v1(95.66,88.2)
  BOTTOM w0.254: v1(95.66,88.2) 95.12,88.74 95.12,89.62 95.25,89.75 95.25,90.72 C530.1
  BOTTOM w0.381: FB501.2 96.77,92.65 95.28,91.15 C530.1
PLLM2_VDD: length 9.4
  TOP w0.381: v1(94.66,86.2) U11.P23
  BOTTOM w0.254: C541.1 94.31,88.13 94.11,87.93 94.11,86.75 v1(94.66,86.2)
  BOTTOM w0.381: FB502.2 95,92.28 94.24,91.52 94.24,89.96 C541.1
PLLS_VAD: length 9.9
  TOP w0.381: U11.R23 v1(95.66,86.2)
  BOTTOM w0.254: v1(95.66,86.2) 95.66,86.42 96.15,86.9 96.15,89.45 96.37,89.68
  BOTTOM w0.381: FB500.2 98.3,93.2 97.28,92.18 C529.1 97.28,90.58 96.37,89.68
PLUG_DETECT: length 146.3
  TOP w0.193: J14.7 6.12,70.48 6.12,65.99 12.14,59.97 21.87,59.97 TP31.1 ; U11.F23 v1(85.66,86.2)
  L03_SIG1 w0.155: TP31.1 25.84,63.94 v2(25.84,68.83) 26.65,69.63 26.65,85.44 v2(25.84,86.24) ; J15.7 5.77,76.09 5.77,74.24 4.11,72.59 J14.7
  L05_SIG2 w0.102: v1(85.66,86.2) 85.41,86.2 85.01,85.8 79.94,85.8
  L05_SIG2 w0.155: 79.94,85.8 78.68,87.06 71.05,87.06 69.05,85.06 66.14,85.06 64.89,86.31 59.77,86.31 59.58,86.51 58.71,86.51 58.36,86.16 54.74,86.16 54.22,86.67 52.6,86.67 52.32,86.4 47.11,86.4 38.01,77.3 23.98,77.3 22.94,78.33 22.94,83.34 v2(25.84,86.24)
  BOTTOM w0.193: v2(25.84,68.83) 24.96,67.95 R646.2 24.13,68.73 23.1,68.73 22.75,69.09 U506.5
PM_ADR_0: length 63.8
  TOP w0.193: v2(45.47,62.36) 45.08,62.75 U13.5 ; 61,78.27 61,77.28 60.33,76.61 v2(60.33,76.2) 61.38,75.15 61.38,64.38 63.03,62.74 v2(63.03,61.73) ; U11.C7 v1(82.66,69.2)
  L05_SIG2 w0.155: v2(45.47,62.36) 46.43,61.4 51.07,61.4 52.65,59.81 59.75,59.81 61.67,61.73 v2(63.03,61.73) 70.23,61.73 70.74,61.22 71.24,61.22 71.58,61.57 71.58,62.29 72.19,62.9 72.19,63.29 73.48,64.58 76.38,64.58 81,69.2 v1(82.66,69.2)
PM_ADR_1: length 51.9
  TOP w0.102: 79.69,69.15 80.25,69.7 U11.A7
  TOP w0.193: U13.4 v2(42.01,61.95) ; 79.69,69.15 78.56,68.02 78.56,67.18 77.45,66.07 74.77,66.07 73.57,64.87 73.57,63.59 72.56,62.58 v2(72.56,61.15) ; U14.26 61,60.13 61.69,60.82 v2(62.92,60.82)
  L05_SIG2 w0.155: v2(42.01,61.95) 44.22,61.95 45.21,60.96 50.61,60.96 52.24,59.33 59.99,59.33 61.48,60.82 v2(62.92,60.82)
  BOTTOM w0.193: v2(62.92,60.82) 63.14,60.6 72.01,60.6 v2(72.56,61.15)
PM_ADR_2: length 54.4
  TOP w0.102: U11.B7 81.66,69.2 80.39,69.2 79.69,68.51
  TOP w0.193: 79.69,68.51 79.24,68.05 79.24,66.48 78.69,65.94 78.05,65.94 77.67,65.55 76.91,65.55 v2(74.72,63.36) ; U13.3 v2(42.62,61.14) ; v2(60.39,63.88) 60.67,63.88 61.13,63.42 61.13,60.87 60.49,60.24 U14.25
  BOTTOM w0.193: v2(42.62,61.14) 43.46,60.3 45.85,60.3 46.31,60.76 50.25,60.76 51.14,59.87 56.13,59.87 60.14,63.88 v2(60.39,63.88) 62.74,63.88 65.44,61.17 71.24,61.17 72.62,62.55 73.19,62.55 74,63.36 v2(74.72,63.36)
PM_ADR_3: length 56.6
  TOP w0.193: U14.24 60,60.61 60.39,61.01 v2(60.39,62.96) ; U11.C8 v1(82.66,70.2) ; v2(41.82,58.51) 41.82,59.71 42.45,60.35 U13.2
  L05_SIG2 w0.102: v1(82.66,70.2) 79.96,70.2
  L05_SIG2 w0.155: 79.96,70.2 78.86,69.09 78.17,69.09 78.02,69.24 77.41,69.24 77.4,69.24 77.25,69.24 73.82,65.8 71.53,65.8 70.61,64.88 70.61,64.38 70.05,63.82 67.86,63.82 67.5,64.17 65.72,64.17 65.45,63.91 61.34,63.91 v2(60.39,62.96)
  BOTTOM w0.193: v2(41.82,58.51) 42.1,58.24 46,58.24 47.17,59.41 49.51,59.41 50.56,58.36 57.22,58.36 60.39,61.53 v2(60.39,62.96)
PM_ADR_4: length 55.3
  TOP w0.193: U11.D8 v1(83.66,70.2) ; U13.1 v2(42.64,59.54) ; v2(59.48,62.24) 59.76,61.97 59.76,61.02 59.49,60.76 U14.23 59.53,58.85 v2(59.53,57.44)
  L05_SIG2 w0.102: 81.83,68.75 82.85,68.75 83.22,69.11 83.22,69.52 83.66,69.97 v1(83.66,70.2)
  L05_SIG2 w0.155: 81.83,68.75 81.34,68.75 77.42,64.83 77.15,64.83 76.36,64.04 74.48,64.04 71.94,61.5 71.94,61.42 71.17,60.65 64.06,60.65 63.75,60.34 63.4,60 62.09,60 v2(59.53,57.44)
  BOTTOM w0.193: v2(59.48,62.24) 59.25,62.24 56.45,59.45 50.99,59.45 50.07,60.37 46.65,60.37 45.83,59.54 v2(42.64,59.54)
PM_ADR_5: length 60
  TOP w0.102: 79.69,70.7 79.77,70.7 U11.A8
  TOP w0.193: v2(74.87,68.39) 75.7,68.39 78.01,70.7 79.69,70.7 ; U13.44 v2(34.72,59.54) ; U14.22 59,61.12 v2(59.15,61.27)
  L05_SIG2 w0.155: v2(74.87,68.39) 72.63,66.16 71.29,66.16 70.26,65.13 70.26,64.52 69.91,64.17 68.14,64.17 66.88,65.43 65.2,65.43 64.65,64.89 60.56,64.89 58.83,63.15 58.83,61.59 v2(59.15,61.27)
  BOTTOM w0.193: v2(59.15,61.27) 56.76,58.88 50.82,58.88 49.75,59.95 46.97,59.95 45.93,58.9 42.38,58.9 42,59.28 34.98,59.28 v2(34.72,59.54)
PM_ADR_6: length 64.8
  TOP w0.102: U11.B8 81.66,70.19 80.17,70.19 79.69,69.72
  TOP w0.193: U13.43 v2(33.51,60.35) ; v2(58.22,63.3) 58.23,63.3 58.49,63.03 58.49,61.78 58.43,61.72 58.43,61.22 58.49,61.15 U14.21 ; 79.69,69.72 77.69,67.71 73.65,67.71 72.26,66.32 72.26,63.09 v2(70.99,61.82)
  BOTTOM w0.193: v2(33.51,60.35) 33.53,60.33 35.57,60.33 37.99,62.74 42.96,62.74 44.55,61.15 50.45,61.15 51.29,60.31 55.23,60.31 v2(58.22,63.3) 59.67,64.74 63.35,64.74 66.28,61.82 v2(70.99,61.82)
PM_ADR_7: length 70.6
  TOP w0.193: U14.20 58,60.96 57.9,61.05 57.9,62.56 57.61,62.85 57.61,65.89 v2(57.99,66.26) ; U13.42 35.45,61.14 v2(36.54,62.23) ; U11.C9 v1(82.66,71.2)
  L05_SIG2 w0.102: 79.69,72.49 80.37,71.81 81.15,71.81 81.36,71.6 81.91,71.6 82.31,71.2 v1(82.66,71.2)
  L05_SIG2 w0.155: v2(36.54,62.23) 37.26,62.95 47.66,62.95 48.31,62.3 48.32,62.31 49.02,62.31 49.37,62.66 49.37,64.09 48.08,65.37 48.08,66.76 49.27,67.94 49.78,67.94 51.19,66.53 51.94,66.53 52.2,66.26 v2(57.99,66.26) 59.28,67.55 62.72,67.55 65.05,69.88 66.53,69.88 67.42,68.99 69.69,68.99 71.9,71.2 76.02,71.2 76.29,71.47 77.09,71.47 78.11,72.49 79.69,72.49
PM_ADR_8: length 67.8
  TOP w0.193: U14.10 53,60.45 53.47,60.92 53.47,61.83 v2(53.47,61.83) ; U11.D9 v1(83.66,71.2) ; U13.28 v2(33.48,72.34)
  L05_SIG2 w0.102: 80.18,69.81 82.83,69.81 83.07,70.05 83.07,70.45 83.66,71.04 v1(83.66,71.2)
  L05_SIG2 w0.155: 80.18,69.81 78.21,67.84 76.93,67.84 74.54,65.45 71.79,65.45 70.97,64.62 70.97,64.2 71.48,63.69 71.48,63.19 71.13,62.84 67.87,62.84 66.97,63.74 65.96,63.74 64.97,62.76 61.47,62.76 59.39,60.68 54.64,60.68 53.47,61.85 53.47,61.83 v2(53.47,61.83)
  BOTTOM w0.193: v2(53.47,61.83) 53.35,61.95 48.83,61.95 47.08,63.7 46.04,63.7 45.3,64.44 41.44,64.44 36.42,69.46 36.42,71.11 35.19,72.34 33.49,72.34 v2(33.48,72.34)
PM_ADR_9: length 71.1
  TOP w0.193: U11.E9 v1(84.66,71.2) ; U14.9 52.49,60.56 52.26,60.8 52.26,61.68 53.34,62.76 v2(53.34,62.74) ; U13.27 v2(34.47,73.14)
  L05_SIG2 w0.102: 80.37,69.26 80.71,69.6 82.91,69.6 83.27,69.96 83.27,70.36 83.5,70.59 84.06,70.59 v1(84.66,71.2)
  L05_SIG2 w0.155: v2(53.34,62.74) 53.34,62.76 52.85,62.26 52.85,61.49 54.09,60.24 59.57,60.24 61.65,62.32 69.55,62.32 69.71,62.49 71.28,62.49 71.84,63.05 71.84,63.55 73.33,65.04 76.16,65.04 80.37,69.26
  BOTTOM w0.193: v2(53.34,62.74) 53.34,62.76 52.95,62.37 49.87,62.37 49.38,62.85 49.38,63.61 48.81,64.19 46.32,64.19 45,65.51 41.27,65.51 37.49,69.29 37.49,71.29 35.98,72.8 34.82,72.8 v2(34.47,73.14)
PM_ADR_10: length 64.6
  TOP w0.193: U14.8 52,60.42 51.77,60.65 51.77,62.31 52.64,63.18 52.64,64.51 v2(53.21,65.07) ; U11.A9 v1(80.66,71.2) ; U13.26 v2(33.5,73.94)
  L05_SIG2 w0.155: v2(53.21,65.07) 59.04,65.07 60.44,66.47 63.19,66.47 64.78,68.05 65.79,68.05 66,67.84 67.96,67.84 68.19,68.07 69.2,68.07 70.04,67.22 71.51,67.22 74.77,70.49 76.31,70.49 76.51,70.68 77.3,70.68 78.17,71.54 79.69,71.54 80.03,71.2 v1(80.66,71.2)
  BOTTOM w0.193: v2(53.21,65.07) 52.78,64.65 47.57,64.65 47,65.23 47,65.61 46.29,66.32 41.74,66.32 38.96,69.1 38.96,70.65 36.26,73.36 35.34,73.36 34.75,73.94 v2(33.5,73.94)
PM_ADR_11: length 65.7
  TOP w0.193: v2(51.69,65.93) 51.82,65.8 51.82,63.13 51.06,62.36 51.06,60.77 51.49,60.34 U14.7 ; U13.25 v2(35.6,74.75) ; U11.B9 v1(81.66,71.2)
  L05_SIG2 w0.102: v1(81.66,71.2) 81.33,71.2 80.92,71.6 80.14,71.6 79.69,72.05
  L05_SIG2 w0.155: v2(51.69,65.93) 51.84,65.78 53.34,65.78 53.52,65.61 58.8,65.61 60.21,67.02 62.69,67.02 65.19,69.52 66.38,69.52 67.27,68.63 70.26,68.63 70.46,68.43 71.65,68.43 74.06,70.84 76.16,70.84 76.45,71.13 77.25,71.13 78.18,72.05 79.69,72.05
  BOTTOM w0.193: v2(51.69,65.93) 51.51,65.75 48.39,65.75 48.04,66.1 48.04,66.82 46.35,68.5 45.13,68.5 44.75,68.88 44.75,68.88 44.55,69.09 41.81,69.09 36.17,74.73 35.62,74.73 v2(35.6,74.75)
PM_ADR_12: length 79.6
  TOP w0.193: U14.6 51,60.26 49.43,61.83 49.43,63.11 49.17,63.37 49.17,63.91 49.43,64.17 49.43,66.84 v2(49.73,67.14) ; U13.24 v2(33.57,75.54) ; U11.C10 v1(82.66,72.2)
  L05_SIG2 w0.102: v1(82.66,72.2) 82.66,71.76 83.06,71.36 83.06,71.04 82.83,70.81 79.92,70.81 79.69,71.04
  L05_SIG2 w0.155: 79.69,71.04 78.16,71.04 77.26,70.13 74.92,70.13 71.66,66.87 70.86,66.87 69.91,65.91 69.41,65.91 69.06,66.26 67.09,66.26 65.64,67.71 65.04,67.71 63.19,65.85 60.43,65.85 59.82,65.24 59.06,64.47 51.75,64.47 50.86,65.36 50.86,66.01 v2(49.73,67.14)
  BOTTOM w0.193: v2(49.73,67.14) 51.39,67.14 52.33,66.2 52.33,65.66 51.8,65.13 47.86,65.13 47.52,65.47 47.52,66.27 46.68,67.11 41.69,67.11 39.93,68.87 39.93,69.9 39.93,69.9 39.93,70.31 36.37,73.88 35.56,73.88 34.97,74.47 34.65,74.47 33.57,75.54 v2(33.57,75.54)
PM_ADR_13: length 73.6
  TOP w0.193: v2(48.68,66.51) 48.68,64.35 47.9,63.57 47.9,62.71 50.49,60.12 U14.5 ; U11.D10 v1(83.66,72.2) ; U13.23 v2(34.53,76.35)
  L05_SIG2 w0.102: v1(83.66,72.2) 83.66,71.76 83.27,71.36 83.27,70.94 82.92,70.59 82.5,70.59 82.31,70.41 82.01,70.41 81.83,70.59 79.69,70.59
  L05_SIG2 w0.155: 79.69,70.59 78.22,70.59 77.3,69.67 75.15,69.67 71.99,66.51 71.01,66.51 70.05,65.56 69.39,65.56 68.89,65.06 67.78,65.06 65.7,67.14 65.09,67.14 63.27,65.32 60.49,65.32 59.21,64.04 57.66,64.04 56.45,62.84 54.25,62.84 53.59,63.5 52.11,63.5 49.1,66.51 v2(48.68,66.51)
  BOTTOM w0.193: v2(48.68,66.51) 48.68,68.09 47.66,69.11 46.33,69.11 45.67,69.77 41.73,69.77 36.11,75.39 35.48,75.39 v2(34.53,76.35)
PM_ADR_14: length 75.9
  TOP w0.193: v2(52.11,70.88) 52.79,70.2 52.79,68.76 51.82,67.79 49.05,67.79 48.04,66.78 48.04,64.52 47.29,63.78 47.29,62.56 50,59.86 U14.4 ; U11.E10 v1(84.66,72.2) ; U13.22 v2(45.57,76.35)
  L05_SIG2 w0.102: 79.69,75.82 83.95,75.82 84.2,75.56 84.2,72.66 v1(84.66,72.2)
  L05_SIG2 w0.155: v2(45.57,76.35) 46.21,76.35 47.23,75.33 47.85,75.33 47.86,75.33 47.86,75.33 48.21,74.98 48.21,73.93 46.65,72.36 45.98,72.36 44.85,71.23 44.85,70.47 45.74,69.59 46.79,69.59 47.37,70.17 51.41,70.17 v2(52.11,70.88) 53.07,70.88 53.37,71.18 55.73,71.18 56.01,71.46 56.41,71.46 56.9,70.97 59.48,70.97 63.41,74.9 68.48,74.9 68.61,74.76 78.58,74.76 79.63,75.82 79.69,75.82
PM_ADR_15: length 80.4
  TOP w0.193: v2(47.17,57.82) 47.41,57.58 47.41,56.86 47.92,56.35 48.97,56.35 49.49,56.88 U14.3 ; U13.21 46.03,75.54 46.49,75.09 v2(46.5,75.09) ; U11.C11 v1(82.66,73.2)
  L03_SIG1 w0.155: v2(46.5,75.09) 44.76,73.35 44.76,60.22 v2(47.17,57.82)
  L05_SIG2 w0.102: 79.76,73.31 80.26,72.81 81.83,72.81 82.22,73.2 v1(82.66,73.2)
  L05_SIG2 w0.155: v2(46.5,75.09) 46.5,75.01 43.93,72.44 43.93,72.2 43.56,71.83 43.56,68.45 44.88,67.13 46.44,67.13 48.35,69.04 50.46,69.04 51.55,67.95 54.2,67.95 54.67,68.42 56.25,68.42 57.37,69.55 63.7,69.55 64.82,70.66 67.06,70.66 67.96,69.76 69.37,69.76 71.52,71.91 75.29,71.91 76.7,73.31 79.69,73.31 79.69,73.31 79.76,73.31
PM_ADR_16: length 55.2
  TOP w0.193: v2(47.61,74.74) 48.63,75.76 48.63,76.33 49.2,76.9 49.2,76.9 49.49,77.19 ; U13.20 45.84,74.75 ; U11.D11 v1(83.66,73.2)
  TOP w0.254: 49.49,78.27 49.49,77.19 ; v2(47.61,74.74) 47.6,74.75 47.06,74.75 46.77,74.45 46.13,74.45 45.84,74.75
  BOTTOM w0.102: 79.69,74.44 80.18,74.44 80.41,74.67 82.76,74.67 83.07,74.36 83.07,73.8 v1(83.66,73.2)
  BOTTOM w0.193: 79.69,74.44 67.34,74.44 63.89,70.99 57.51,70.99 56.73,71.76 55.14,71.76 54.78,71.4 54.04,71.4 53.43,70.79 53.43,70.28 53.84,69.87 53.84,69.41 52.83,68.4 52.06,68.4 51.45,69.01 51.45,71.02 51.06,71.41 50.02,71.41 48.39,73.04 48.39,73.93 47.6,74.71 47.6,74.74 v2(47.61,74.74)
PM_ADR_17: length 74.8
  TOP w0.193: U14.19 57.49,62.26 57.09,62.66 57.09,65.14 54.78,67.45 54.78,71.41 54.15,72.04 49.34,72.04 47.44,73.94 v2(47.15,73.94) 47.1,73.94 47.03,73.87 46.07,73.87 46,73.94 U13.19 ; U11.A11 v1(80.66,73.2)
  L05_SIG2 w0.155: v1(80.66,73.2) 80.15,73.71 76.59,73.71 75.15,72.26 70.73,72.26 69.51,71.04 68.85,71.04 66.91,72.98 63.32,72.98 60.66,70.32 60.24,69.9 57.22,69.9 56.22,68.9 54.49,68.9 53.98,68.39 52.16,68.39 52.16,68.38 51.62,68.38 51.23,68.77 50.61,69.39 48.2,69.39 47.29,68.48 45.14,68.48 43.99,69.63 43.99,71.65 44.36,72.03 44.36,72.26 46.05,73.94 v2(47.15,73.94)
PM_ADR_18: length 61
  TOP w0.193: v2(54.08,70.58) 54.08,67.41 56.57,64.92 56.57,62.45 57,62.02 U14.18 ; U13.18 v2(46.09,73.14) ; U11.B11 v1(81.66,73.2)
  L05_SIG2 w0.102: v1(81.66,73.2) 81.63,73.2 81.02,73.81 80.5,73.81 80.24,74.07
  L05_SIG2 w0.155: v2(46.09,73.14) 44.42,71.47 44.42,70.03 45.37,69.09 47.18,69.09 47.85,69.75 51.73,69.75 52.03,70.05 53.56,70.05 v2(54.08,70.58) 55.41,69.25 56.06,69.25 57.06,70.26 60.09,70.26 60.3,70.46 63.9,74.07 80.24,74.07
PM_ADR_19: length 58.1
  TOP w0.193: U11.C12 v1(82.66,74.2)
  L05_SIG2 w0.155: v2(51.34,53.94) 53.2,53.94 54.56,52.59 57.97,52.59 v2(58.88,53.5)
  BOTTOM w0.102: 83.22,62.23 83.22,63.31 83.5,63.59 83.61,63.59 84.06,64.04 84.06,66.49 84.36,66.8 84.82,66.8 85.06,67.04 85.06,69.36 84.83,69.59 82.71,69.59 82.21,70.09 82.21,73.75 v1(82.66,74.2)
  BOTTOM w0.193: R682.1 58.73,56.18 58.94,55.97 58.91,55.93 58.91,53.52 v2(58.88,53.5) 60.56,53.5 66.75,59.69 74.69,59.69 76.35,61.34 80.03,61.34 80.57,61.88 80.97,61.88 81.3,61.55 82.87,61.55 83.22,61.89 83.22,62.23 ; R689.1 52.04,55.09 51.85,54.9 51.85,54.45 v2(51.34,53.94)
PM_ADR_20: length 62.3
  TOP w0.193: U14.12 54,54.12 56.21,51.9 v2(56.21,50.53) ; U11.D12 v1(83.66,74.2)
  BOTTOM w0.102: 85.12,62.23 85.27,62.38 85.27,66.42 85.52,66.68 86.94,66.68 87.19,66.93 87.19,68.46 87.06,68.6 87.06,71.56 86.85,71.77 84.46,71.77 84.27,71.96 84.27,73.59 v1(83.66,74.2)
  BOTTOM w0.193: v2(56.21,50.53) 56.7,51.02 77.35,51.02 82.89,56.56 82.89,59.99 85.12,62.23
PM_ADR_21: length 58.6
  TOP w0.193: U11.E11 v1(84.66,73.2)
  BOTTOM w0.102: 83.86,62.23 83.86,62.39 84.26,62.78 84.26,66.35 84.5,66.59 84.9,66.59 85.26,66.95 85.26,69.45 84.91,69.8 83.42,69.8 83.07,70.15 83.07,71.45 83.42,71.8 83.82,71.8 84.06,72.04 84.06,73.36 83.83,73.59 83.71,73.59 83.27,74.04 83.27,74.36 83.5,74.59 83.83,74.59 84.18,74.24 84.18,74.08 84.66,73.59 v1(84.66,73.2)
  BOTTOM w0.193: R688.1 R687.1 R686.1 54.07,53.88 55.99,51.96 74.2,51.96 79.79,57.55 79.79,59.13 81.59,60.93 82.82,60.93 83.86,61.98 83.86,62.23
PM_ADR_22: length 53.3
  TOP w0.102: v1(80.66,74.2) 79.69,74.2
  TOP w0.193: 79.69,74.2 74.07,74.2 67.32,67.45 67.32,57.83 64.07,54.58 62.5,54.58 60.8,56.29 v2(60.71,56.29) ; v2(47.72,58.55) 47.71,58.55 47.71,59.82 48.15,60.25 48.8,60.25 49,60.06 U14.2 ; U11.A12 v1(80.66,74.2)
  BOTTOM w0.193: v2(60.71,56.29) 59.82,56.29 58.18,57.92 50.06,57.92 R690.1 48.02,58.85 47.71,58.55 v2(47.72,58.55)
PM_BLS0: length 58.5
  TOP w0.102: 79.69,65.63 79.69,67.94 80.46,68.7 U11.A6
  TOP w0.193: v2(73.51,61.91) 73.79,62.19 74.1,62.19 74.63,62.72 74.98,62.72 77.29,65.03 77.88,65.03 78.2,65.35 79.42,65.35 79.69,65.63
  L05_SIG2 w0.155: v2(73.51,61.91) 73.51,61.19 72.16,59.84 64.3,59.84 62.66,58.2 61.28,58.2 59.77,56.7 59.2,56.7 57.54,58.36 52.12,58.36 49.98,60.49 37.43,60.49 35.07,62.86 35.07,63.33 34.82,63.57 v2(33.73,63.57)
  BOTTOM w0.193: v2(33.73,63.57) 33.55,63.75 R643.1
PM_BLS0S: length 2.9
  TOP w0.193: U13.39 v2(30.69,63.55)
  BOTTOM w0.193: v2(30.69,63.55) 31.4,63.55 R643.2
PM_BLS1: length 59.3
  TOP w0.102: U11.B6 81.66,68.2 80.66,68.2 80.11,67.65 80.11,65.12
  TOP w0.193: v2(74.74,61.92) 75.01,62.2 75.2,62.2 75.21,62.21 75.61,62.21 77.17,63.77 78.75,63.77 80.11,65.12
  L05_SIG2 w0.155: v2(34.48,62.74) 37.26,59.96 41.33,59.96 42.34,58.95 43.13,58.95 43.38,59.2 50.57,59.2 51.87,57.9 57.24,57.9 58.91,56.23 59.81,56.23 60.46,56.88 61.08,56.88 61.34,56.62 61.81,56.62 64.6,59.41 72.33,59.41 73.94,61.02 73.94,61.13 v2(74.74,61.92)
  BOTTOM w0.193: R644.1 v2(34.48,62.74)
PM_BLS1S: length 4.6
  TOP w0.193: U13.40 v2(29.79,62.75)
  BOTTOM w0.193: v2(29.79,62.75) 31.01,62.75 31.02,62.74 R644.2
PM_DAT_0: length 53.7
  TOP w0.193: v2(57.78,71.61) 57.81,71.63 58.57,71.63 59,72.06 59,73.67 59.43,74.1 59.43,74.26 59.45,74.28 59.45,75.48 59,75.94 59,78.27 ; U11.B13 v1(81.66,75.2) ; v2(52.15,69.22) 51.24,68.31 48.76,68.31 47.38,66.93 47.38,64.85 46.88,64.35 U13.7
  BOTTOM w0.102: v1(81.66,75.2) 81.2,75.66 80.54,75.66 79.7,74.82 79.69,74.82
  BOTTOM w0.193: v2(52.15,69.22) 52.15,70.05 53.99,71.89 54.66,71.89 54.93,72.15 57.24,72.15 57.78,71.6 v2(57.78,71.61) 57.79,71.6 63.77,71.6 66.98,74.82 79.69,74.82
PM_DAT_1: length 55.7
  TOP w0.193: 58,78.27 58,75.64 58.28,75.36 58.28,74.72 58.12,74.56 58.12,74.55 58.09,74.51 v2(58.09,73.41) 58.09,73.16 56.86,71.93 56.86,70.48 57.64,69.7 v2(57.64,68.93) ; U13.8 46.27,65.14 v2(46.36,65.06) ; U11.C14 v1(82.66,77.2)
  L05_SIG2 w0.155: v2(58.09,73.41) 57.98,73.41 57.98,73.39 58.95,73.39 59.44,73.88 59.44,74.3 60.02,74.88 61.78,74.88 62.67,75.76 68.84,75.76 69.11,75.49 78.22,75.49 79.37,76.64 81.98,76.64 82.54,77.2 v1(82.66,77.2) ; v2(46.36,65.06) 46.36,66.54 48.49,68.68 50.31,68.68 51.71,67.28 52.83,67.28 52.94,67.17 55.89,67.17 v2(57.64,68.93)
PM_DAT_2: length 51.6
  TOP w0.193: 57,78.27 57,74.24 57.19,74.05 v2(57.19,73.26) ; v2(50.79,70.76) 50.15,70.12 49.83,70.12 45.66,65.95 U13.9 ; U11.D14 v1(83.66,77.2)
  L05_SIG2 w0.155: v1(83.66,77.2) 83.66,77.19 82.73,76.25 79.48,76.25 78.36,75.13 68.85,75.13 68.66,75.33 62.85,75.33 60.01,72.49 57.95,72.49 v2(57.19,73.26) 56.86,72.93 56.86,72.36 56.32,71.82 55.87,71.82 55.83,71.79 55.2,71.79 55.03,71.61 53.19,71.61 53.06,71.47 51.87,71.47 51.2,70.8 50.79,70.8 v2(50.79,70.76)
PM_DAT_3: length 52.4
  TOP w0.193: U11.E13 v1(84.66,75.2) ; U13.10 45.73,66.75 49.28,70.3 v2(49.28,70.8) ; v2(56.26,72.77) 56,73.04 56,78.27
  L05_SIG2 w0.155: v2(56.26,72.77) 56.26,72.66 55.81,72.22 55.02,72.22 54.85,72.04 52.92,72.04 52.78,71.9 51.69,71.9 51.15,71.37 50.45,71.37 49.88,70.8 v2(49.28,70.8)
  BOTTOM w0.102: v1(84.66,75.2) 83.82,76.05 80.11,76.05 79.69,75.63
  BOTTOM w0.193: v2(56.26,72.77) 56.43,72.61 57.33,72.61 57.48,72.46 63.89,72.46 66.93,75.51 68.43,75.51 68.74,75.2 79.26,75.2 79.69,75.63
PM_DAT_4: length 47.3
  TOP w0.193: 54.49,78.27 54.49,76.14 54.29,75.94 54.29,75.43 54.63,75.09 54.63,75.08 54.63,73.77 54.42,73.57 v2(54.42,72.64) ; U13.13 46.28,69.14 v2(47.94,70.8) ; U11.A14 v1(80.66,77.2)
  L05_SIG2 w0.155: v1(80.66,77.2) 80.6,77.13 79.23,77.13 77.94,75.84 69.36,75.84 69.02,76.19 62.49,76.19 61.61,75.31 58.93,75.31 58.02,74.39 57.15,74.39 56.12,73.37 56.01,73.37 55.66,73.02 55.66,72.91 55.39,72.64 v2(54.42,72.64) 52.91,72.64 52.6,72.34 51.51,72.34 50.9,71.72 50.3,71.72 50.29,71.72 49.27,71.72 48.36,70.8 v2(47.94,70.8)
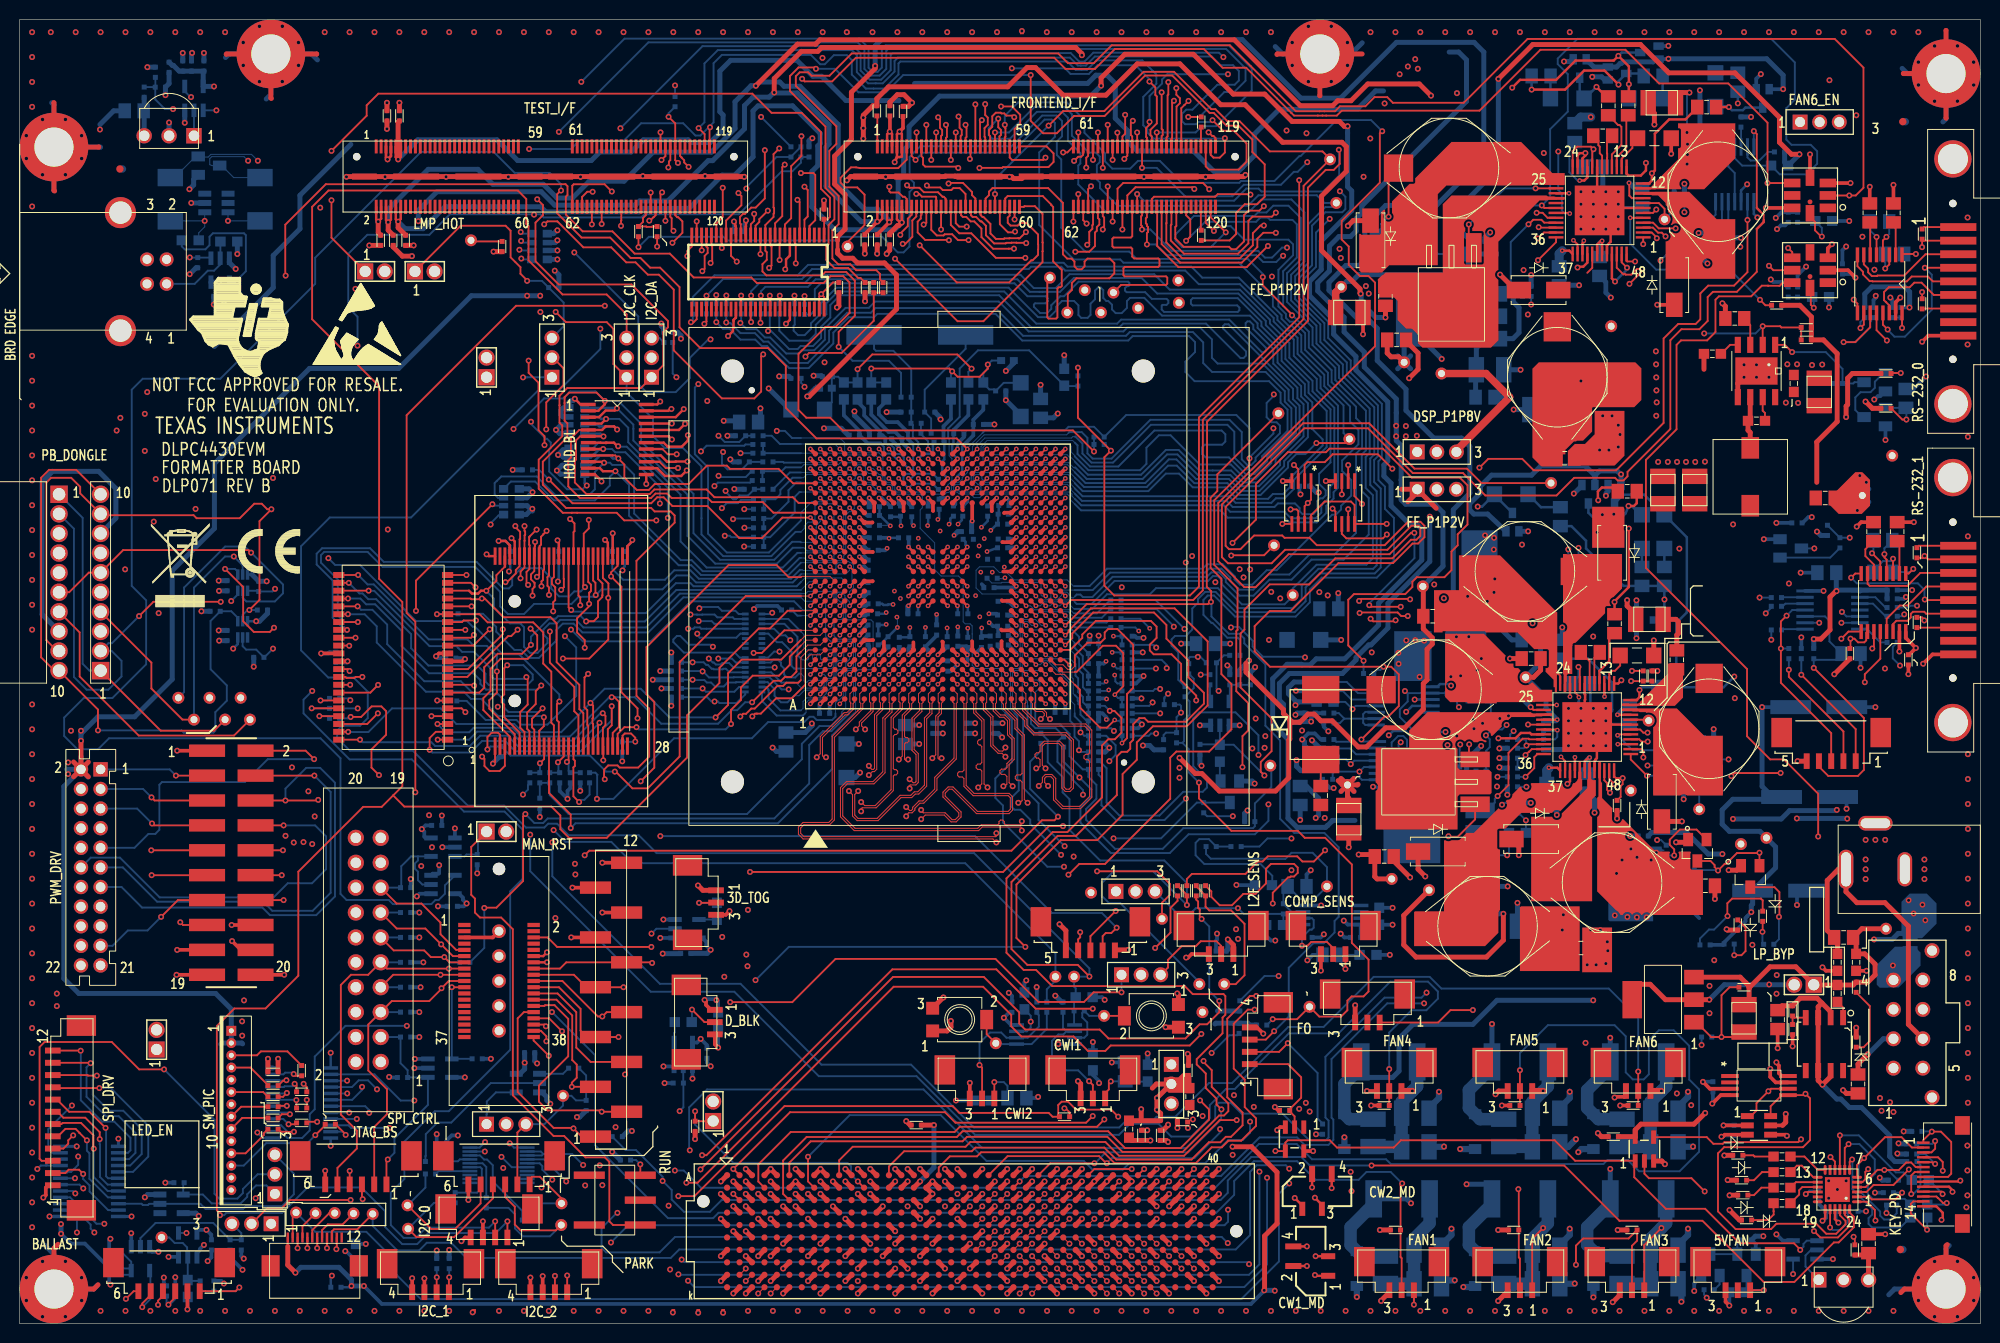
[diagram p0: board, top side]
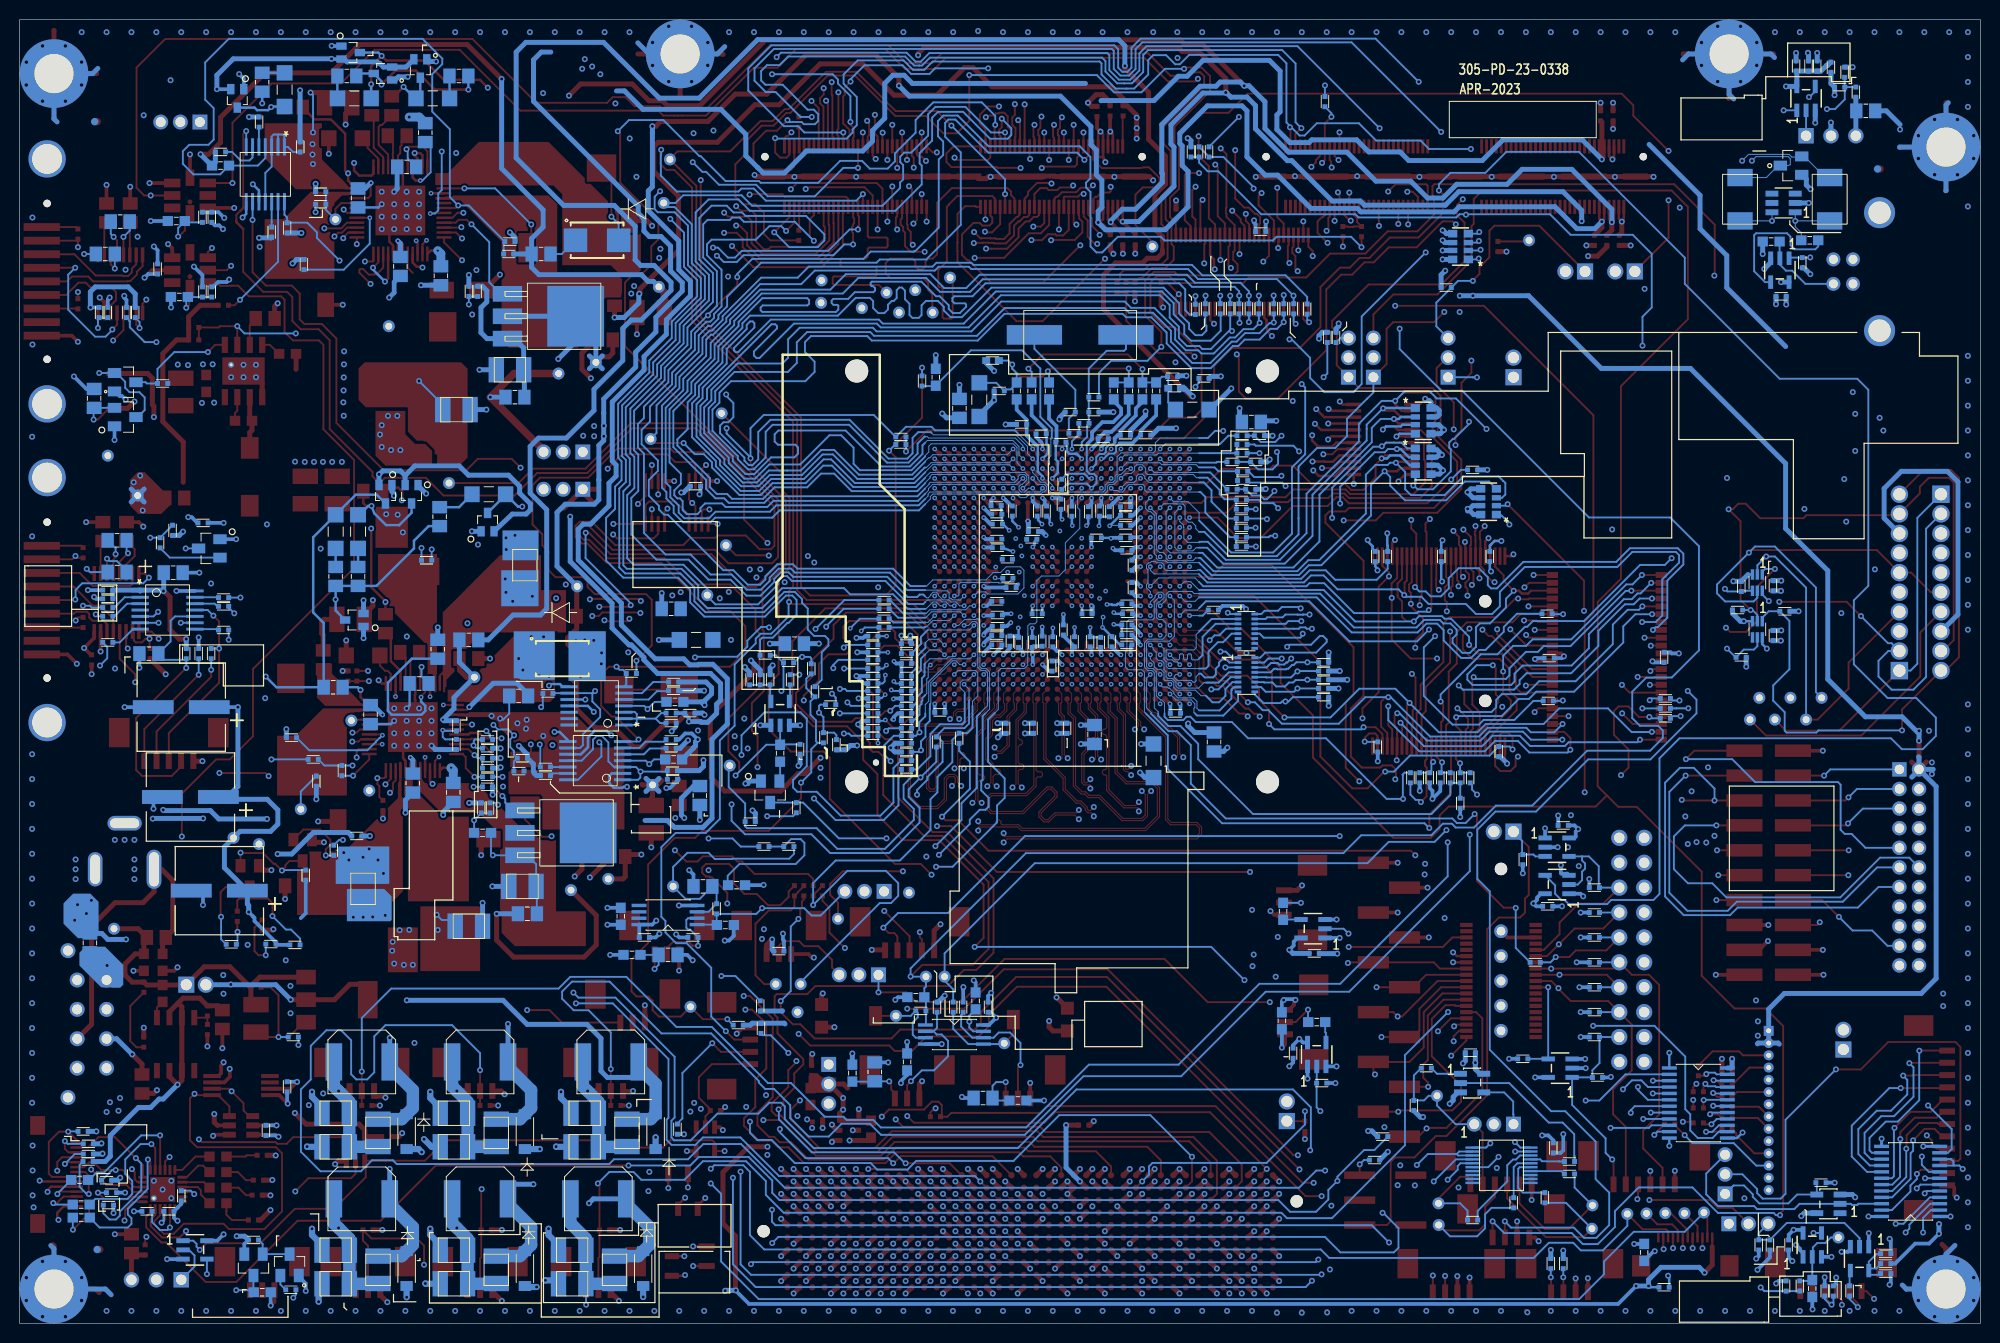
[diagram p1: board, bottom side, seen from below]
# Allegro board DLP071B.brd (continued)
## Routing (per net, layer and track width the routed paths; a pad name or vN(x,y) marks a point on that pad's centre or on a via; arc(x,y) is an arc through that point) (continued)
PM_DAT_5: length 49.8
  TOP w0.193: v2(53.23,75.19) 53.23,75.69 53.38,75.84 53.38,76.79 53.49,76.9 53.49,78.27 ; U13.14 46.04,69.94 v2(46.33,70.23) ; U11.B14 v1(81.66,77.2)
  L05_SIG2 w0.102: 79.69,77.53 80.11,77.53 80.27,77.69 81.19,77.69 81.66,77.21 v1(81.66,77.2)
  L05_SIG2 w0.155: v2(46.33,70.23) 46.47,70.23 48.4,72.15 50.72,72.15 51.33,72.77 52.34,72.77 52.91,73.34 52.91,74.88 v2(53.23,75.19) 53.4,75.02 53.4,73.93 53.85,73.48 55.62,73.48 57.07,74.93 57.07,75.65 58.4,76.98 60.48,76.98 61.33,76.13 61.82,76.13 62.31,76.62 69.2,76.62 69.62,76.2 77.61,76.2 78.94,77.53 79.69,77.53
PM_DAT_6: length 49.5
  TOP w0.193: v2(52.32,74.24) 52.32,74.92 52.49,75.1 52.49,75.11 52.52,75.14 52.52,75.55 52.52,75.55 52.16,75.9 52.16,76.41 52.49,76.74 52.49,78.27 52.54,78.31 52.54,79.29 52.57,79.32 v2(52.57,79.72) ; U13.15 v2(45.46,70.75) ; U11.C15 v1(82.66,78.2)
  L05_SIG2 w0.102: v1(82.66,78.2) 82.47,78.2 81.91,78.76 81.46,78.76 81.41,78.81 80.34,78.81 80.29,78.85 79.69,78.85
  L05_SIG2 w0.155: v2(52.32,74.24) 51.91,74.24 51.31,74.84 50.12,74.84 49.21,73.93 49.21,73.53 46.75,71.07 45.78,71.07 v2(45.46,70.75) ; 79.69,78.85 78.15,78.85 76.56,77.27 70.22,77.27 69.57,77.92 62.93,77.92 62.49,78.36 53.93,78.36 v2(52.57,79.72)
PM_DAT_7: length 53.5
  TOP w0.193: v2(51.49,81.34) 51.49,80.85 51.56,80.79 51.56,80.44 51.51,80.39 51.51,79.85 51.49,79.83 51.49,77.1 51.09,76.69 v2(51.09,76.01) ; U11.D15 v1(83.66,78.2) ; U13.16 45.12,71.54 45.29,71.71 v2(46.55,71.71)
  L05_SIG2 w0.102: 79.69,81.6 80.82,81.6 80.88,81.54 81.45,81.54 81.5,81.59 81.83,81.59 82.06,81.36 82.06,80.77 82.23,80.59 82.83,80.59 83.06,80.36 83.06,80.2 83.67,79.59 83.83,79.59 84.06,79.36 84.06,79.04 83.66,78.64 v1(83.66,78.2)
  L05_SIG2 w0.155: v2(46.55,71.71) 46.63,71.71 48.86,73.94 48.86,74.42 49.47,75.02 49.8,75.02 49.97,75.2 50.29,75.2 v2(51.09,76.01) ; 79.69,81.6 76.79,81.6 75.76,80.57 73.68,80.57 73.17,81.09 64.34,81.09 62.13,83.3 55.96,83.3 54.97,82.31 53.14,82.31 52.85,82.01 52.3,82.01 51.81,81.52 51.67,81.52 v2(51.49,81.34)
PM_DAT_8: length 76.3
  TOP w0.193: U11.E14 v1(84.66,77.2) ; U13.29 v2(34.5,71.54) ; 58.49,78.27 58.49,75.79 58.73,75.55 58.73,74.33 v2(58.77,74.3)
  BOTTOM w0.102: v1(84.66,77.2) 84.66,76.84 84.28,76.45 79.73,76.45 79.69,76.42
  BOTTOM w0.193: 79.69,76.42 78.86,75.59 69,75.59 68.28,76.3 66.99,76.3 65.57,74.88 60.11,74.88 60.11,74.89 60.1,74.88 59.35,74.88 v2(58.77,74.3) 58.59,74.12 57.02,74.12 56.29,73.4 52.48,73.4 51.45,72.36 49.8,72.36 49.01,73.15 49.01,74.62 46.47,77.17 37.03,77.17 35.49,78.7 31.07,78.7 30.73,78.37 30.73,77.6 32.45,75.89 32.45,72.21 33.11,71.55 34.49,71.55 v2(34.5,71.54)
PM_DAT_9: length 77.8
  TOP w0.193: v2(57.67,75.11) 57.49,75.28 57.49,78.27 57.54,78.31 57.54,80.57 58.05,81.09 v2(58.05,81.97) ; U11.C16 v1(82.66,79.2) ; U13.30 v2(33.39,70.75)
  L05_SIG2 w0.102: v1(82.66,79.2) 82.22,79.2 81.82,79.6 81.42,79.6 81.22,79.8 80.44,79.8 80.09,80.15
  L05_SIG2 w0.155: v2(58.05,81.97) 58.82,81.2 62.25,81.2 64.24,79.21 70.08,79.21 70.67,78.62 76.07,78.62 77.59,80.15 80.09,80.15
  BOTTOM w0.193: v2(57.67,75.11) 57.23,74.67 56.57,74.67 56.07,74.17 55.02,74.17 54.22,74.97 54.22,76.03 53.21,77.04 51.15,77.04 50.24,76.13 50.24,75.31 49.91,74.98 49.32,74.98 46.61,77.69 37.14,77.69 35.75,79.08 30.85,79.08 30.29,78.52 30.29,77.41 31.93,75.78 31.93,72 32.89,71.03 33.11,71.03 v2(33.39,70.75)
PM_DAT_10: length 68.4
  TOP w0.193: v2(56.15,82.05) 56.6,81.61 56.6,80.82 56.49,80.72 56.49,78.27 ; U13.31 v2(34.26,69.94) ; U11.D16 v1(83.66,79.2)
  L03_SIG1 w0.155: v2(56.15,82.05) 52.63,82.05 52.09,81.51 52.09,81.1 51.69,80.7 49.92,80.7 49.64,80.42 39.93,80.42 34.11,74.59 33.3,74.59 32.89,74.18 32.89,72.09 34.26,70.72 v2(34.26,69.94)
  L05_SIG2 w0.102: 79.87,80.58 79.94,80.52 80.42,80.52 80.5,80.59 80.83,80.59 81.06,80.36 81.06,80.25 81.5,79.81 82.61,79.81 83.22,79.2 v1(83.66,79.2)
  L05_SIG2 w0.155: v2(56.15,82.05) 56.66,82.56 61.54,82.56 64.37,79.73 70.39,79.73 70.94,79.18 72.99,79.18 73.65,79.84 76.54,79.84 77.27,80.58 79.87,80.58
PM_DAT_11: length 63
  TOP w0.193: v2(55.24,74.83) 55.51,75.11 55.51,75.94 55.49,75.95 55.49,78.27 ; v2(33.62,69.13) 33.6,69.14 U13.32 ; U11.B15 v1(81.66,78.2)
  L05_SIG2 w0.102: v1(81.66,78.2) 81.22,78.2 80.83,78.59 80.5,78.59 80.33,78.42 79.72,78.42
  L05_SIG2 w0.155: v2(33.62,69.13) 35.15,69.13 42.54,76.52 42.54,77.28 44.46,79.2 51.16,79.2 53.18,77.19 53.2,77.19 54.31,76.07 54.31,75.44 54.91,74.83 v2(55.24,74.83) 55.5,75.09 55.5,75.47 57.96,77.92 62.2,77.92 62.64,77.49 69.45,77.49 70.03,76.91 76.95,76.91 78.44,78.4 79.69,78.4 79.72,78.42
PM_DAT_12: length 65.3
  TOP w0.193: v2(54,74.32) 54,75.08 53.84,75.24 53.84,76.12 54,76.28 54,78.27 ; U13.35 33.46,66.75 v2(33.66,66.55) ; U11.A15 v1(80.66,78.2)
  L05_SIG2 w0.155: v1(80.66,78.2) 80.44,78.2 80.21,77.97 78.69,77.97 77.28,76.56 69.87,76.56 69.37,77.06 62.4,77.06 61.95,77.5 58.27,77.5 56.55,75.78 56.55,75.02 55.44,73.91 54.4,73.91 v2(54,74.32) 54,75.14 53.87,75.26 53.87,75.9 53.02,76.75 53,76.75 51.39,78.37 48.53,78.37 48.02,77.86 47.2,77.86 46.68,78.38 44.85,78.38 42.94,76.46 42.94,74.79 41.1,72.95 41.1,72.46 35.19,66.55 v2(33.66,66.55)
PM_DAT_13: length 63.5
  TOP w0.193: v2(52.77,76.16) 53,76.38 53,79.1 53.03,79.13 53.03,79.29 53.18,79.44 53.18,80.24 53.42,80.48 53.42,80.52 v2(53.75,80.84) ; U13.36 33.23,65.95 33.34,65.84 34.15,65.84 34.25,65.95 v2(34.96,65.95) ; U11.A16 v1(80.66,79.2)
  L05_SIG2 w0.155: v2(53.75,80.84) 53.75,79.95 54.91,78.79 62.67,78.79 63.11,78.35 69.63,78.35 70.36,77.62 76.33,77.62 78,79.29 80.15,79.29 80.23,79.2 v1(80.66,79.2) ; v2(34.96,65.95) 35.23,65.95 41.53,72.25 41.53,72.77 42.14,73.37 42.99,73.37 43.48,73.86 43.48,76.39 45.03,77.94 46.5,77.94 47.02,77.43 48.28,77.43 48.71,77.87 51.06,77.87 52.77,76.16 v2(52.77,76.16)
PM_DAT_14: length 66.6
  TOP w0.193: v2(51.87,75.34) 51.7,75.5 51.7,76.66 52,76.95 52,78.27 52.02,78.29 52.02,79.38 51.96,79.44 51.96,80.2 52.02,80.25 52.02,80.27 52.72,80.98 v2(52.73,80.98) ; U11.B16 v1(81.66,79.2) ; U13.37 v2(33.71,65.14)
  L05_SIG2 w0.102: v1(81.66,79.2) 81.22,79.2 80.83,79.59 80.25,79.59 80.12,79.72 79.69,79.72
  L05_SIG2 w0.155: v2(33.71,65.14) 33.76,65.19 35.54,65.19 41.97,71.62 41.97,72.59 42.32,72.94 43.21,72.94 44,73.73 44,76.3 45.21,77.51 46.32,77.51 46.9,76.94 48.64,76.94 49.13,77.42 50.79,77.42 51.87,76.35 v2(51.87,75.34) ; v2(52.73,80.98) 53.04,80.98 53.5,81.44 54.74,81.44 56.96,79.22 62.89,79.22 63.32,78.78 69.86,78.78 70.43,78.21 76.21,78.21 77.72,79.72 79.69,79.72
PM_DAT_15: length 67.6
  TOP w0.193: v2(36.56,65.13) 35.78,64.35 U13.38 ; U11.C17 v1(82.66,80.2) ; v2(50.56,81.34) 50.56,81.24 51.05,80.75 51.05,80.04 51,79.98 51,77.24 50.61,76.86 50.61,76.5 49.72,75.62 v2(49.55,75.62)
  L05_SIG2 w0.102: v1(82.66,80.2) 82.22,80.2 81.61,80.81 80.23,80.81 79.87,81.17
  L05_SIG2 w0.155: 79.87,81.17 77.08,81.17 76.11,80.2 73.4,80.2 72.95,79.75 71.28,79.75 70.73,80.3 64.51,80.3 61.9,82.92 56.17,82.92 55.12,81.87 53.32,81.87 53.02,81.57 52.48,81.57 52.13,81.22 52.13,81.08 51.79,80.74 51.24,80.74 50.64,81.34 v2(50.56,81.34) ; v2(49.55,75.62) 49.43,75.74 47.49,75.74 46.29,76.94 45.25,76.94 44.43,76.12 44.43,73.55 43.5,72.62 43.5,72.38 42.52,71.41 42.52,71.09 v2(36.56,65.13)
PM_OESZ: length 46.8
  TOP w0.193: 59.49,78.27 59.49,76.04 60.06,75.48 60.06,74.03 v2(60.04,74.01) 60.04,69.75 58.11,67.82 v2(55.42,67.82) ; U13.41 v2(30.57,61.95)
  L03_SIG1 w0.155: v2(48.77,62.9) 48.77,63.85 51.75,66.84 54.43,66.84 v2(55.42,67.82)
  L05_SIG2 w0.155: v2(30.57,61.95) 32.79,64.16 35.86,64.16 36.22,63.8 36.95,63.8 37.57,64.42 44.43,64.42 44.8,64.05 47.62,64.05 v2(48.77,62.9)
  BOTTOM w0.193: R645.2 31.58,61.95 v2(30.57,61.95)
PM_OEZ: length 81.5
  TOP w0.102: 79.69,76.13 79.77,76.21 82.66,76.21 U11.C13
  TOP w0.193: v2(33.76,61.86) 34.83,61.86 35.9,62.94 36.89,62.94 37.38,62.46 37.38,60.04 35.89,58.55 35.89,56.7 v2(36.65,55.93) ; v2(63.35,55.3) 64.74,56.69 64.74,63.4 63.94,64.2 63.94,68.98 72.31,77.35 77.21,77.35 78.44,76.13 79.69,76.13 ; U11.C13 v1(82.66,75.2)
  L05_SIG2 w0.155: v2(36.65,55.93) 44.89,55.93 47.62,53.2 53.04,53.2 54.36,51.88 60.13,51.88 63.35,55.1 v2(63.35,55.3)
  BOTTOM w0.193: v2(33.76,61.86) 33.64,61.86 33.5,61.72 R645.1
PM_SRAM_CSSZ: length 2
  TOP w0.193: U13.6 v2(42.59,63.55)
  BOTTOM w0.193: R642.2 42.64,63.5 v2(42.59,63.55)
PM_SRAM_CSZ: length 51.8
  TOP w0.193: U11.D13 v1(83.66,75.2)
  L05_SIG2 w0.155: v1(83.66,75.2) 83.66,75.15 83.19,74.68 79.15,74.68 78.89,74.42 63.75,74.42 59.94,70.61 56.93,70.61 56.42,70.1 v2(55.62,70.1)
  BOTTOM w0.193: R642.1 45.59,63.5 47.54,61.56 50.67,61.56 51.15,61.08 53.84,61.08 56.77,64.01 56.77,68.95 v2(55.62,70.1)
PM_WESZ: length 24.8
  TOP w0.193: U14.13 54.49,61.01 54.23,61.28 54.23,66.49 53.4,67.31 53.4,70.49 52.38,71.52 47.74,71.52 46.91,72.34 46.82,72.34 46.81,72.35 46.28,72.35 46.28,72.34 U13.17 v2(42.56,72.34)
  BOTTOM w0.193: v2(42.56,72.34) 43.63,72.34 R602.2
PM_WEZ: length 44.1
  TOP w0.193: U11.B12 v1(81.66,74.2)
  BOTTOM w0.102: v1(81.66,74.2) 81.12,73.66 80.1,73.66 79.69,74.06
  BOTTOM w0.193: 79.69,74.06 67.7,74.06 64.12,70.48 57.4,70.48 56.51,71.38 55.4,71.38 54.74,70.72 54.74,69.66 52.96,67.88 51.95,67.88 51.14,68.7 50.47,68.7 48.61,70.56 48.61,71.04 47.26,72.39 R602.1
PMD1K2_CP1: length 3.5
  TOP w0.193: U2.18 161.41,119.13 161.18,119.36 161.18,120.05 161.04,120.19 161.04,120.64 C6.1
PMD1K2_CP2: length 3.4
  TOP w0.193: U2.17 161.91,118.89 161.93,118.91 161.93,119.35 161.91,119.37 161.91,120.63 C6.2
PMD1K2_FB_P2P5V: length 25.3
  TOP w0.193: U2.46 162.91,107.69 163.62,106.99 ; R24.1 156.64,91.17 L3.2 ; 163.71,107.1 163.82,106.99 164.39,106.99 164.97,107.57 165.23,107.57 165.35,107.44 165.35,107.19 v2(164.21,106.05)
  L03_SIG1 w0.155: v2(159.26,96.14) 159.26,100.33 164.21,105.28 v2(164.21,106.05)
  BOTTOM w0.193: v2(159.26,96.14) 156.84,93.73 C524.2
PMD1K2_GD_CORE: length 13
  TOP w0.193: U2.26 v2(154.63,115.79) ; Q1.1 147.82,110.25 v2(147.82,112.11)
  BOTTOM w0.193: v2(154.63,115.79) 151.5,115.79 v2(147.82,112.11)
PMD1K2_VCP: length 6.7
  TOP w0.254: U2.21 159.91,116.9 159.6,116.59 v1(159.13,116.59)
  BOTTOM w0.193: C505.1 158.08,119.96 158.08,117.43 158.92,116.59 v1(159.13,116.59)
PMD1K2_VREG: length 37.7
  TOP w0.193: U2.47 163.41,108.24 v2(163.96,107.7) ; U2.20 160.41,119.78 v2(160.54,119.78) 160.28,120.04 158.87,120.04 158.41,119.58 U2.24 ; U2.31 158.05,113.29 v1(158.12,113.22)
  TOP w0.254: U2.45 162.41,106.61 v2(162.74,106.28)
  L05_SIG2 w0.155: v2(163.96,107.7) 163.96,111.71 163.41,112.26 159.01,112.26 158.12,113.15 v1(158.12,113.22) ; v2(156.95,119.55) 156.95,119.63 157.32,120 160.33,120 v2(160.54,119.78)
  BOTTOM w0.193: C513.1 160.41,118.83 160.41,119.78 v2(160.54,119.78) ; v2(156.95,119.55) 156.95,115.62 157.3,115.26 157.3,113.55 157.63,113.22 v1(158.12,113.22)
  BOTTOM w0.254: v2(163.96,107.7) 163.96,107.5 v2(162.74,106.28)
PMD1K_CP1: length 3.5
  TOP w0.193: U15.18 160.14,67.56 C28.1
PMD1K_CP2: length 3.4
  TOP w0.193: U15.17 160.64,65.89 160.63,65.9 160.63,67.91 C28.2
PMD1K_FB_LIN1: length 33.3
  TOP w0.193: U15.31 156.78,60.58 v1(156.84,60.52)
  L05_SIG2 w0.155: v1(156.84,60.52) 155.54,60.52 153.04,63.02 148.89,63.02 146.89,61.02 137.6,61.02 v2(135.95,62.66)
  BOTTOM w0.193: R610.2 156.77,60.44 v1(156.84,60.52) 156.84,59.82 156.6,59.58 R651.1 ; U507.4 136.28,62.99 v2(135.95,62.66) 135.22,63.4 C610.1
PMD1K_FB_MOT2: length 8.7
  TOP w0.193: U2.11 166.83,115.79 167.52,116.48
  TOP w0.508: C1.2 168.94,124.55 168.94,125.3 169.21,125.56 v2(170.33,125.56)
  BOTTOM w0.193: v2(170.33,125.56) 170.08,125.31 v2(170.08,121.49)
  vias: v2(170.13,120.3) v2(170.12,119.24) v2(170.08,118.27)
PMD1K_FB_P2P5V: length 19.3
  TOP w0.193: U15.46 161.64,55.4 161.93,55.12 161.93,54.43 v2(162.22,54.13)
  L03_SIG1 w0.155: v2(162.22,54.13) 162.22,46.44 v2(157.47,41.68)
  BOTTOM w0.193: v2(157.47,41.68) 156.93,41.15 156.21,41.15 C647.2
  vias: v2(157.35,40.13)
PMD1K_FB_P3P3V:
  vias: v2(162.89,45.9) v2(163.45,47.27) v2(164.35,48.4) v2(164.97,47.55) v2(166.42,47.27) v2(166.94,48.02)
PMD1K_FB_P5V: length 1.3
  TOP w0.193: 156.79,66.42 157.14,66.07 U15.24
  vias: v2(147.7,74.17) v2(149.71,73.66) v2(150.39,74.57) v2(150.47,75.95)
PMD1K_GD_CORE: length 34.1
  TOP w0.193: v2(145.75,49.7) 145.75,49.64 146.69,49.64 148.46,51.41 Q2.1 ; U15.26 v1(156.78,63.08)
  L05_SIG2 w0.155: v2(145.75,49.7) 145.82,49.63 153.89,49.63 154.82,50.56 154.82,53.28 154.22,53.88 153.71,53.88 153.01,54.58 153.01,56.27 156.26,59.52 158.39,59.52 158.64,59.78 158.64,61.66 158.24,62.06 157.8,62.06 v1(156.78,63.08)
PMD1K_GM_IN1: length 9.2
  TOP w0.193: U15.8 166.08,61.58 TP33.1 ; v2(164.37,65.52) R32.2 C29.2
  L03_SIG1 w0.155: v2(164.37,65.52) 165.18,65.52 166.17,64.53 TP33.1
PMD1K_GM_IN2: length 6.7
  TOP w0.193: U2.8 167.2,114.29 167.79,113.7 TP3.1
  BOTTOM w0.193: TP3.1 168.77,113.61 R517.2 C511.2
PMD1K_SENSE_MOT1: length 3.5
  TOP w0.193: R31.1 163.26,67.1 162.73,66.57 162.46,66.57 162.14,66.26 U15.14
PMD1K_SENSE_MOT2: length 3.6
  TOP w0.193: U2.14 163.41,118.82 164.51,119.91 164.51,120.37 R6.1
PMD1K_VCP: length 16.3
  TOP w0.193: v1(159.05,63.88) 159.05,63.96 158.64,64.37 U15.21
  BOTTOM w0.254: C609.1 160,67.81 162.43,65.37 162.43,62.62 162.43,62.61 162.43,62.47 162.06,62.1 158.99,62.1 158.62,62.47 158.62,63 159.05,63.43 v1(159.05,63.88)
PMD1K_VREG: length 20.4
  TOP w0.193: v2(162.69,54.99) 162.14,55.53 U15.47 ; v2(159,66.96) 159.14,66.83 U15.20
  L03_SIG1 w0.155: v2(159,66.96) 159,65.65 161.31,63.34 162.69,63.34 163.64,62.39 163.64,57.79 162.69,56.84 v2(162.69,54.99)
  BOTTOM w0.193: v2(159,66.96) 159,65.99 C608.1
PMD_INTZ: length 95
  TOP w0.193: U11.AE8 v1(105.66,70.2) ; v2(153.61,55.75) 154.5,56.64 154.5,57.76 154.82,58.08 U15.36
  L03_SIG1 w0.155: v2(154.32,71.42) 154.32,69.1 152.45,67.23 152.45,64.04 153.09,63.4 153.09,58.96 152.8,58.68 152.8,56.56 v2(153.61,55.75)
  L05_SIG2 w0.102: 107.63,69.26 107.08,69.81 106.5,69.81 106.11,70.2 v1(105.66,70.2)
  L05_SIG2 w0.155: v2(154.32,71.42) 153.92,71.02 148.67,71.02 148.35,71.33 146.03,71.33 145.83,71.13 138.4,71.13 138.2,70.93 137.41,70.93 137.25,71.08 133.03,71.08 132.78,70.84 131,70.84 128.38,68.21 122.82,68.21 121.57,66.96 119.26,66.96 117.62,65.32 111.74,65.32 111,66.07 109.82,66.07 108.66,67.23 108.66,68.23 107.63,69.26 ; v2(153.61,55.75) 153.7,55.66 v2(153.7,54.74) 154.86,54.74 156.4,53.2 163.14,53.2 v2(167.03,49.31)
  BOTTOM w0.193: v2(167.03,49.31) 167.04,49.32 167.41,49.32 R692.1 ; R658.2 v2(153.7,54.74) ; R657.2 v2(153.61,55.75)
POSENSE: length 175.7
  TOP w0.193: v2(107.95,97.5) 107.95,92.39 v2(111.32,89.03) 110.64,88.35 110.64,75.26 111.65,74.26 119.38,74.26 120.29,75.17 120.29,92.41 130.52,102.64 v2(130.52,116.63) ; v2(153.71,58.95) 153.73,58.98 153.73,58.99 153.82,59.08 154.75,59.08 154.75,59.08 U15.34
  L03_SIG1 w0.155: v2(153.71,58.95) 155.6,60.85 155.6,72.21 157.26,73.86 157.26,81.88 157.75,82.38 157.75,93.16 156.69,94.22 156.69,118.17 v2(155.47,119.39)
  L05_SIG2 w0.155: v2(155.47,119.39) 152.22,116.14 131.01,116.14 v2(130.52,116.63)
  BOTTOM w0.193: v2(111.32,89.03) 110.68,89.66 R553.2 ; R653.2 153.55,59.56 153.67,59.44 153.67,58.98 v2(153.71,58.95) 153.43,58.67 R654.2 ; R554.1 v2(107.95,97.5)
POSENSE_FIL: length 28.1
  TOP w0.254: v1(94.66,85.2) U11.P22
  BOTTOM w0.102: 94.81,90.26 94.81,88.51 95.09,88.22 95.09,85.95 94.66,85.51 v1(94.66,85.2)
  BOTTOM w0.193: 94.81,90.26 94.71,90.35 94.71,91.3 95.88,92.47 95.88,97.4 97.75,99.26 102.97,99.26 106.55,95.68 C525.2 106.59,95.62 R554.2
PSENS: length 58.2
  TOP w0.193: U2.34 154.99,111.79 v2(154.95,111.83)
  L03_SIG1 w0.155: v2(152.39,60.43) 152.52,60.55 152.52,62.6 151.35,63.77 151.35,69.52 156.67,74.84 156.67,83.35 157.19,83.87 157.19,91.92 156.26,92.85 156.26,110.52 v2(154.95,111.83)
  BOTTOM w0.193: v2(152.39,60.43) 152.04,60.08 152.04,59.81 151.79,59.56 R653.1
PWR_OFF_RDY: length 270.8
  TOP w0.193: U11.B23 v1(81.66,86.2)
  L03_SIG1 w0.155: v1(81.66,86.2) 79.74,86.2 68.33,97.61 68.33,98.15 64.44,102.03 61.57,102.03 60.2,100.66 58.88,100.66 57.78,101.76 57.78,113.53 59.08,114.83 59.08,119.72 v2(61.28,121.92) ; v2(190.27,66.8) 190.27,67.51 191,68.24 191,68.8 192.84,70.63 192.84,73.61 193.95,74.73 193.95,77.08 193.2,77.84 193.2,80.88 193.81,81.49 193.81,93.52 193.45,93.89 193.45,104.68 193.19,104.94 193.19,108.32 192.72,108.79 192.72,120.87 187.46,126.14 184.3,126.14 179.5,130.94 141.03,130.94 134.68,124.59 129.31,124.59 124.72,129.18 v2(122.79,129.18)
  L05_SIG2 w0.155: v2(190.27,66.8) 190.27,68.41 187.81,70.87 184.16,70.87 v2(183.57,71.47)
  BOTTOM w0.193: v2(122.79,129.18) 122.33,129.63 109.52,129.63 108.61,128.72 108.08,128.72 107.21,129.59 89.04,129.59 88.85,129.4 88.85,127.85 87.88,126.88 86.71,126.88 85.78,127.81 85.78,129.57 85.05,130.29 69.65,130.29 v2(61.28,121.92) ; U505.9 v2(183.57,71.47)
PWR_ON_AC: length 79.2
  TOP w0.193: J30.1 144.68,30.69 145.95,31.96 v2(148.24,31.96)
  L03_SIG1 w0.155: v2(172.85,37.04) 174.92,39.1 174.92,46.76 176.83,48.68 176.83,49.74 182.02,54.92 182.02,63.66 177.73,67.94 177.73,72.06 v2(178.11,72.43)
  L05_SIG2 w0.155: v2(148.24,31.96) 148.65,31.54 167.36,31.54 v2(172.85,37.04)
  BOTTOM w0.193: v2(178.11,72.43) 178.11,72.45 178.68,73.01 R592.1
PWR_ON_RDY: length 272.3
  TOP w0.193: U11.C22 v1(82.66,85.2)
  L03_SIG1 w0.102: v1(82.66,85.2) 82.26,85.6 82.26,90.16
  L03_SIG1 w0.155: v2(185.83,71.47) 185.28,72.02 185.28,73.22 185.96,73.9 185.96,75.2 185.67,75.49 185.67,76.34 186.08,76.74 186.08,81.12 186.23,81.27 186.23,86.74 187.63,88.14 187.63,94.59 188.75,95.71 188.75,101.92 186.49,104.19 186.49,104.79 187.26,105.56 189.16,105.56 191.18,107.58 191.18,114.13 189.71,115.6 189.71,121.76 186.85,124.63 183.93,124.63 180.52,128.04 175.99,128.04 172.87,124.93 169.2,124.93 165.86,128.27 162.62,128.27 161.2,129.69 141.87,129.69 139.98,127.8 139.98,124.3 139.02,123.34 128.82,123.34 123.93,128.23 121.91,128.23 119.07,131.08 68.03,131.08 56.36,119.41 56.36,109.46 v2(56.58,109.25) ; v2(70.47,100.38) 71.36,100.38 71.73,100.01 76.36,100.01 79.07,97.29 79.07,93.43 82.26,90.25 82.26,90.16
  BOTTOM w0.193: v2(70.47,100.38) 70.25,100.38 68.37,98.5 68.37,96.45 66.92,95 63.94,95 63.1,95.83 63.1,102.72 v2(56.58,109.25) ; U505.6 v2(185.83,71.47)
PWRGOOD: length 533.7
  TOP w0.193: v2(128.09,17.58) U18.4 129.11,18.44 129.35,18.68 133.63,18.68 134.38,17.93 140.15,17.93 140.9,18.68 156.58,18.68 158.67,16.59 164.77,16.59 U19.1 164.69,16.46 164.69,14.91 167.92,11.68 171.93,11.68 175.45,8.17 180.98,8.17 181.63,7.53 v2(181.63,7.49) ; U15.35 154.25,58.58 153.98,58.32 153.95,58.32 153.61,57.98 v2(153.61,57.98) ; v2(125.45,88.24) 125.45,87.56 121.85,83.96 121.85,77.39 124.23,75 124.23,70.75 124.1,70.62 124.1,64.49 125.31,63.29 125.31,60.48 124.73,59.91 124.73,56.75 v2(124.73,56.74) ; U11.T26 v1(96.66,89.2) 95.58,90.28 81.27,90.28 78.15,93.4 78.15,97.68 76.33,99.5 69.43,99.5 67.31,101.61 67.31,105.72 65.33,107.7 64.31,107.7 63.32,108.69 62.32,108.69 60.24,110.77 57.32,110.77 54.83,113.26 54.83,115.19 55.21,115.57 v2(55.22,115.57) ; U9.7 131.07,83.37 v2(131.39,83.69) 131.72,84.02 U9.1 ; U10.7 v2(135.52,83.05) ; v2(136.93,83.59) 136.93,83.62 136.14,84.4 136.14,85.91 U10.1
  L03_SIG1 w0.155: v2(128.09,17.58) 129.4,17.58 130.48,16.5 133.5,16.5 140.61,23.6 140.61,24.31 141.26,24.96 141.26,38.46 139.42,40.3 139.42,40.56 134.11,45.87 132.77,45.87 132.09,45.2 129.41,45.2 128.78,45.83 128.78,47.87 125.96,50.69 124.31,52.34 124.31,52.87 124.31,52.87 124.31,56.33 v2(124.73,56.74) ; v2(20.07,123.75) 20.52,123.29 55.16,123.29 55.7,122.76 55.7,121.11 55.22,120.63 v2(55.22,115.57)
  L05_SIG2 w0.155: v2(127.89,91.31) 131.39,87.81 v2(131.39,83.69) 132.71,82.38 134.84,82.38 v2(135.52,83.05) 136.39,83.05 v2(136.93,83.59) ; v2(124.73,56.74) 124.73,56.74 124.83,56.65 125.98,56.65 131.39,62.07 132.96,62.07 134.89,60.13 134.89,56.78 137.9,53.77 144.04,53.77 147.6,50.21 153.86,50.21 154.24,50.59 154.24,51.57 152.57,53.24 152.57,56.94 v2(153.61,57.98)
  BOTTOM w0.102: v1(96.66,89.2) 96.66,89.29 98.21,90.83
  BOTTOM w0.193: v2(127.89,91.31) 127.89,90.78 125.45,88.34 ; U518.1 182.29,8.43 181.96,8.1 181.96,7.82 v2(181.63,7.49) ; v2(20.07,123.75) U500.1 ; v2(153.61,57.98) 153.29,57.66 R655.2 R656.2 ; 125.45,88.34 v2(125.45,88.24) ; 125.45,88.34 125.45,91.32 124.1,92.67 112.87,92.67 R552.2 109.59,91.46 106.99,91.46 106.62,91.1 98.48,91.1 98.21,90.83 ; v2(55.22,115.57) 55.22,116.21 54.07,117.37 50.49,117.37 48.35,119.51 40.94,119.51 30.14,108.72 30.14,106.04 20.47,96.37 12.55,96.37 11.43,95.24 11.43,75.23 12.9,73.76 12.9,67.24 9.46,63.79 6.54,63.79 4.54,61.79 4.54,59.92 5.89,58.57 8,58.57 9.12,59.69 30.69,59.69 32.73,57.65 32.73,43.81 33.34,43.19 37.65,43.19 38.07,42.77 41.99,42.77 42.41,43.19 42.74,43.19 43.38,43.83 43.38,44.68 U510.4
REAL_CWTACH1: length 11.3
  TOP w0.193: v1(162.99,60) 163.08,60.08 U15.5
  BOTTOM w0.193: R647.2 170.47,58.47 164.52,58.47 163.66,59.33 163.66,59.35 163.28,59.72 163.27,59.72 v1(162.99,60)
REAL_CWTACH2: length 11.8
  TOP w0.193: U2.5 v1(164.29,112.79)
  BOTTOM w0.193: v1(164.29,112.79) 164.29,110.15 166.94,107.49 R522.2
RED_LED_EN: length 146.3
  L03_SIG1 w0.155: v2(5.68,13.26) 5.76,13.17 6.74,13.17 11.59,18.02 11.59,75.16 14.27,77.85 14.27,85.74 v2(13.88,86.13) ; v2(51.35,96.5) 51.17,96.68 v2(51.17,108.63)
  L05_SIG2 w0.155: v2(13.88,86.13) 11.72,88.29 11.72,95.54 12.48,96.3 14.74,96.3 15.72,95.32 50.17,95.32 v2(51.35,96.5)
  BOTTOM w0.193: U517.5 5.43,13.5 v2(5.68,13.26) ; J9.1 51.76,96.52 51.74,96.5 v2(51.35,96.5) ; v2(51.17,108.63) 51.26,108.54 RN500.1
RTCK: length 13.4
  TOP w0.193: J27.13 43.85,36.83 v2(43.32,37.37) 41.94,37.37 41.26,38.05 38.15,38.05 J23.11
  BOTTOM w0.193: R707.1 43.85,36.83 v2(43.32,37.37) ; R709.1 J23.11
RTCKR: length 63.6
  TOP w0.193: v2(47.39,42.38) 47.42,42.41 48.63,42.41 51.35,45.13 51.35,51.73 v2(51.58,51.96) ; U11.E4 v1(84.66,66.2)
  BOTTOM w0.102: 84.58,62.23 84.58,62.33 85.06,62.81 85.06,65.8 v1(84.66,66.2)
  BOTTOM w0.193: R707.2 47.39,38.3 v2(47.39,42.38) ; 84.58,62.23 84.58,62.19 82.8,60.41 81.95,60.41 80.54,59 80.54,55.07 76.97,51.51 53.86,51.51 53.4,51.04 52.5,51.04 v2(51.58,51.96)
SCL: length 132.2
  TOP w0.193: J1.115 69.87,121.32 v2(69.26,121.94) ; v2(121.68,122.75) 122.76,121.67 123.85,121.67 125.15,120.37 125.15,118.49 124.36,117.7 121.31,117.7 120.99,118.03 J2.115
  L03_SIG1 w0.155: J10.2 59.9,98.52 57.4,101.02 57.4,116.08 57.91,116.59 57.91,119.75 60.8,122.63 65.35,122.63 66.05,121.94 v2(69.26,121.94)
  BOTTOM w0.193: v2(121.68,122.75) 121.49,122.56 120.24,122.56 120.02,122.34 118.87,122.34 118.55,122.66 118.55,123.37 118.99,123.82 119.63,123.82 122.17,126.36 123.93,126.36 124.37,126.79 124.37,127.76 123.77,128.36 122.5,128.36 121.62,129.24 109.67,129.24 108.76,128.32 108.24,128.32 107.94,128.32 107.14,129.13 89.59,129.13 89.24,128.78 89.24,127.7 88.04,126.51 87.33,126.51 86.54,126.51 86.33,126.71 85.39,127.65 85.39,129.39 84.89,129.89 71.22,129.89 69.85,128.53 69.85,122.53 v2(69.26,121.94)
SCL0: length 552.3
  TOP w0.102: 79.69,72.7 U11.A10
  TOP w0.193: 79.69,72.7 78.34,72.7 76.53,70.89 75.39,70.89 71.38,66.88 71.38,65.33 68.08,62.03 68.08,57.72 59.89,49.53 56.04,49.53 55.15,50.42 55.15,51.81 54.24,52.72 39.24,52.72 38.1,53.86 ; J49.1 v2(49.75,10.4) ; J10.3 61.91,102.93 59.87,104.97 55.38,104.97 51.9,108.44 51.9,111.94 51.68,112.17 51.68,114.71 50.81,115.57 31.5,115.57 29.83,113.9 29.83,102.44 36.66,95.61 36.66,75.96 39.03,73.59 39.03,54.8 38.1,53.86 ; U16.6 178.63,23.93 v2(178.38,23.68) 177.16,22.46 177.16,21.72 176.59,21.14 U20.1 ; 38.1,53.86 36.93,52.69 35.04,52.69 28.42,46.08 28.42,35.46 25.08,32.12 21.9,32.12 20.12,30.34 20.12,11.52 20.43,11.21 v2(20.43,11.03) ; U5.6 178.88,107.44 v2(178.44,107.89) ; U21.23 186.17,11.06 186.63,10.6 186.63,9.92 185.47,8.76 183.68,8.76 v2(183.03,9.41) ; U11.A10 v1(80.66,72.2)
  L03_SIG1 w0.155: v2(153.84,102.92) 153.84,96.18 153.25,95.58 v2(153.25,79.44) 153.25,74.32 149.73,70.8 149.73,66.31 146.81,63.39 v2(146.81,62.87) ; v2(183.03,9.41) 178.38,14.06 v2(178.38,23.68) 184.49,29.79 184.49,37 183.21,38.28 182.86,38.63 182.86,50.35 183.31,50.8 183.31,65.63 182.1,66.84 182.1,67.55 179.64,70 179.64,74.65 v2(180.47,75.48)
  L05_SIG2 w0.102: 107.63,65.86 106.79,66.7 103.44,66.7 103.16,66.98 103.16,67.41 102.83,67.74 102.25,67.74 102.07,67.92 102.07,71.16 102.5,71.59 102.8,71.59 103.06,71.85 103.06,72.36 102.83,72.59 99.47,72.59 99.21,72.86 97.94,72.86 97.05,73.75 93.83,73.75 92.89,74.69 90.25,74.69 89.61,75.33 86.57,75.33 85.94,74.71 85.44,74.71 85.15,74.42 85.15,71.98 84.98,71.81 84.5,71.81 84.27,72.04 84.27,72.15 83.83,72.59 82.42,72.59 82.17,72.34 82.17,72.01 81.97,71.81 81.5,71.81 81.11,72.2 v1(80.66,72.2)
  L05_SIG2 w0.155: v2(146.81,62.87) 141.86,62.87 141.67,63.06 140.35,63.06 138.96,64.44 131.13,64.44 130.57,63.88 126.33,63.88 121.33,58.88 121.33,53.3 119.93,51.89 109.46,51.89 107.87,53.49 107.87,54.18 108.22,54.53 108.65,54.53 110.25,56.13 110.25,63.03 109.95,63.33 109.95,63.54 107.63,65.86 ; v2(153.84,102.92) 165.33,102.92 165.94,102.31 172.85,102.31 v2(178.44,107.89) ; v2(153.25,79.44) 154.33,78.36 166.96,78.36 171.87,73.44 178.44,73.44 v2(180.47,75.48)
  BOTTOM w0.102: 79.69,72.2 v1(80.66,72.2)
  BOTTOM w0.193: v2(20.43,11.03) 20.85,11.03 21.08,11.26 26.76,11.26 29.37,13.87 34.85,13.87 37.27,11.44 37.27,9.83 39.02,8.08 40.55,8.08 41.68,9.21 48.56,9.21 v2(49.75,10.4) ; R612.2 146.63,62.87 v2(146.81,62.87) ; R601.2 79.33,72.2 79.69,72.2
SCL1: length 346
  TOP w0.193: v2(43.81,4.7) 43.79,4.67 J50.1 ; v2(54.68,103.18) 55.72,102.14 59.88,102.14 60.56,101.46 60.56,97.87 J10.1 ; U11.D20 v1(83.66,83.2) ; J2.95 v2(115.99,121.49)
  L03_SIG1 w0.155: v2(57.29,126.66) 57.29,121.49 55.88,120.08 55.88,104.39 v2(54.68,103.18) ; v2(43.81,4.7) 42.18,6.33 25.77,6.33 24.19,7.92 22.28,7.92 19.41,10.79 19.41,62.59 20.83,64.01 20.83,66.44 22.37,67.99 22.37,73.56 22.77,73.96 22.77,80.67 12.35,91.08 v2(9.89,91.08)
  L05_SIG2 w0.155: v2(9.89,91.08) 9.89,91.11 9.68,91.32 9.68,94.49 17.11,101.92 56.51,101.92 J10.1
  BOTTOM w0.102: 79.69,80.74 80.04,81.09 80.04,81.36 80.42,81.74 80.8,81.74 81.13,82.07 81.13,83.37 81.35,83.59 81.93,83.59 81.95,83.61 83.29,83.61 83.66,83.24 v1(83.66,83.2)
  BOTTOM w0.193: v2(57.29,126.66) 61.7,131.06 85.65,131.06 86.59,130.13 86.59,128.09 87.01,127.68 87.51,127.68 87.95,128.11 87.95,129.99 88.34,130.38 123.32,130.38 125.68,128.02 125.68,125.77 122.04,122.13 120.59,122.13 119.95,121.49 v2(115.99,121.49) ; 79.69,80.74 79.15,80.74 76.67,78.27 71.76,78.27 69.55,80.48 69.55,82.13 69.55,82.13 69.55,87.41 67.66,89.3 65.81,89.3 64.6,90.51 64.6,92.27 63.71,93.17 63.71,93.18 62.54,94.34 62.53,94.34 61.91,94.96 J10.1 ; R760.2 v2(43.81,4.7)
SCL2: length 287.7
  TOP w0.193: R3.1 v2(119.2,123.08) ; v2(55.85,4.88) J51.1
  L03_SIG1 w0.155: v2(55,121.55) 54.17,120.72 54.17,114.8 v2(52.47,113.11) ; v2(55.85,4.88) 52.67,8.06 46.35,8.06 45.37,9.04 42.25,9.04 41.28,8.06 36.29,8.06 35.52,8.83 30.8,8.83 29.15,10.48 29.15,16.63 23.97,21.81 23.97,57.37 28.55,61.96 28.55,74.11 32.09,77.64 32.09,97.36 v2(34.46,99.74)
  BOTTOM w0.193: 52.47,113.15 43.89,113.15 41.8,111.05 35.46,111.05 33.52,109.11 33.52,103.63 34.46,102.69 v2(34.46,99.74) ; 52.47,113.15 v2(52.47,113.11) ; 52.47,113.15 53.12,113.15 53.44,112.82 63.42,112.82 63.74,113.15 73.35,113.15 77.74,117.53 78.82,117.53 79.69,118.41 R513.2 R512.2 ; v2(119.2,123.08) 120.35,123.08 122.89,125.62 123.89,125.62 125.04,126.77 125.04,128.03 123.06,130.01 88.59,130.01 88.4,129.82 88.4,127.97 87.72,127.3 86.84,127.3 86.17,127.97 86.17,129.99 85.48,130.68 64.13,130.68 v2(55,121.55)
SCL2_C: length 2
  TOP w0.193: R3.2 120.5,122.01 120.5,120.08 J2.113
SCL_VMON: length 89.1
  TOP w0.193: v2(148.9,87.29) 149.8,88.19 153.27,88.19 154.43,87.03 162.86,87.03 167.69,91.86 167.69,100.47 169.18,101.96 170.96,101.96 171.43,102.43 171.43,105.06 172.24,105.87 174.87,105.87 176.24,107.24 v2(176.24,112.57)
  L03_SIG1 w0.155: v2(141.31,64.51) 141.31,66.13 142.34,67.16 142.74,67.16 144.4,68.82 144.4,73.29 144.17,73.51 144.17,73.9 144.17,74.44 144.87,75.13 144.87,81.22 148.9,85.26 v2(148.9,87.29)
  BOTTOM w0.193: R612.1 145.56,64.29 U507.9 141.52,64.29 ; 141.52,64.29 v2(141.31,64.51) ; 141.52,64.29 141.59,64.23 141.59,63.44 140.78,62.64 140.78,61.85 142.54,60.09 142.54,58.99 142.83,58.7 U509.9 ; U501.9 v2(176.24,112.57)
SDA: length 134
  TOP w0.193: J1.117 70.37,121.97 v2(70.42,122.02) ; J2.117 121.49,119.21 121.78,118.92 122.42,118.92 122.94,119.44 v2(122.94,120.91)
  L05_SIG2 w0.155: v2(51.97,119.8) 51.19,119.03 51.19,113.09 51.76,112.52 51.76,107.73 50.38,106.35 50.38,103.65 51.73,102.31 62.04,102.31 63.29,101.06 63.29,99.68 J11.2
  BOTTOM w0.193: v2(122.94,120.91) 122.9,120.87 115.65,120.87 115.03,121.48 115.03,121.8 114.61,122.23 114.61,125.12 115.95,126.46 115.95,127.41 114.51,128.84 109.84,128.84 108.87,127.88 108.31,127.88 107.72,127.88 106.87,128.73 89.84,128.73 89.64,128.53 89.64,127.41 88.2,125.97 87.1,125.97 86.31,125.97 84.88,127.4 84.88,128.87 84.37,129.38 83.05,129.38 82.12,128.45 81.66,128.45 80.7,129.4 71.63,129.4 70.78,128.56 70.78,122.52 70.42,122.16 v2(70.42,122.02) 70.28,122.02 69.44,121.18 68.93,121.18 67.68,122.43 63.39,122.43 61.63,120.66 57.1,120.66 56.24,119.8 v2(51.97,119.8)
SDA0: length 543.8
  TOP w0.193: U11.B10 v1(81.66,72.2) ; J49.2 v2(48.5,10.4) ; v2(123.72,79.62) 123.63,79.52 123.63,79.52 126.1,82 126.1,85.62 129.36,88.87 133.25,88.87 133.61,89.24 139.05,89.24 142.01,86.28 146.91,86.28 147.69,85.5 147.69,81.5 146.69,80.5 146.69,79.38 146.05,78.74 146.05,76.84 145.34,76.12 142.52,76.12 142.06,75.66 142.06,75.12 141.34,74.4 136.1,74.4 135.52,73.82 135.52,69.16 v2(137.08,67.6) ; U21.22 185.67,11.03 186.25,10.46 186.25,10.1 185.29,9.14 184.28,9.14 183.26,10.16 179.2,10.16 178.66,9.62 175.04,9.62 173.24,11.42 173.24,17.35 173.86,17.97 181.91,17.97 182.63,18.69 182.63,22.96 v2(182.16,23.42) 182.03,23.28 U16.5 179.75,23.28 178.61,22.14 U20.6 ; U5.7 179.85,106.17 179.53,105.85 178.36,105.85 178.35,105.86 177.71,105.86 176.62,104.78 173.33,104.78 172.98,104.43 172.98,101.13 172.13,100.28 169.47,100.28 169.01,99.82 169.01,91.21 165.89,88.09 165.89,77.06 176.2,66.75 176.2,59.89 178.56,57.53 179.96,57.53 183.46,54.03 v2(183.46,49.67)
  L03_SIG1 w0.102: 101.28,75.66 102.9,75.66 103.27,75.3 103.27,73.04 103.5,72.81 105.13,72.81 105.34,72.59 107.11,72.59 107.44,72.27
  L03_SIG1 w0.155: v2(183.46,49.67) 183.46,38.89 184.84,37.51 184.84,27.87 182.16,25.19 v2(182.16,23.42) ; 107.44,72.27 113.79,72.27 116.42,74.89 118.99,74.89 v2(123.72,79.62) ; 101.28,75.66 100.28,74.67 100.28,71.3 99.02,70.04 88.67,70.04 86.01,72.7 82.16,72.7 v1(81.66,72.2) ; J11.3 68.63,96.35 68.63,95.49 69.25,94.87 70.33,94.87 70.79,94.41 70.79,93.51 70.44,93.17 70.44,87.91 69.45,86.92 69.45,86.51 66.41,83.47 66.41,83.3 65.71,82.6 64.11,82.6 56.75,75.25 56.75,75 55.3,73.55 55.3,71.6 56.18,70.72 56.19,70.72 56.19,70.77 v2(56.24,70.77)
  L05_SIG2 w0.102: 79.76,72.9 80.06,72.59 81.2,72.59 81.6,72.2 v1(81.66,72.2)
  L05_SIG2 w0.155: v2(183.46,49.67) 183.46,49.67 183.66,49.87 183.66,58.14 176.48,65.32 165.02,65.32 164.47,64.77 161.93,64.77 160.66,66.04 158.24,66.04 157.1,67.18 152.78,67.18 151.51,65.91 148.34,65.91 147.57,66.68 145.16,66.68 143.76,65.28 139.71,65.28 137.4,67.6 v2(137.08,67.6) ; v2(29.84,64.52) 29.88,64.55 36.09,64.55 36.39,64.24 36.8,64.24 37.4,64.84 44.77,64.84 45.2,64.42 46.65,64.42 47.5,65.26 47.5,67.18 48.64,68.33 50.16,68.33 51.35,67.14 51.56,66.93 52.45,66.93 52.68,66.7 56.79,66.7 58.93,68.83 63.5,68.83 64.9,70.23 66.67,70.23 67.56,69.34 69.54,69.34 71.75,71.55 75.87,71.55 76.15,71.83 76.94,71.83 78.01,72.9 79.76,72.9
  BOTTOM w0.102: v1(81.66,72.2) 81.09,72.77 79.88,72.77 79.69,72.96
  BOTTOM w0.193: 79.69,72.96 78.99,73.66 68.46,73.66 64.37,69.58 57.45,69.58 56.25,70.77 v2(56.24,70.77) ; R549.2 65.27,100.52 J11.3 ; v2(48.5,10.4) 47.87,9.77 41.46,9.77 40.42,8.72 39.16,8.72 37.86,10.02 37.86,13.34 39.24,14.72 39.24,18.54 42.34,21.64 43.77,21.64 50.04,27.91 50.04,44.07 51.31,45.34 51.31,50.36 49.46,52.21 45.32,52.21 40,57.53 33.66,57.53 28.96,62.23 28.96,63.63 v2(29.84,64.52) ; R613.2 v2(137.08,67.6)
SDA1: length 342.6
  TOP w0.193: v2(64.94,81.91) 61.67,81.91 60.9,82.69 56.87,82.69 56.86,82.7 56.33,82.7 56.32,82.69 55.4,82.69 52.95,85.15 52.95,88.11 55.35,90.51 55.35,91.59 55.06,91.88 55.06,93.67 55.06,94.63 55.85,95.42 63.37,95.42 64.45,96.5 J11.1 64.45,96.55 65.65,97.74 65.65,101.13 66.13,101.62 66.13,102.25 62.4,105.99 54.99,105.99 52.62,108.36 52.62,112.29 53.38,113.06 53.38,114.09 v2(52.79,114.67) ; U11.E19 v1(84.66,82.2) ; v2(115.25,126.69) 115.85,126.09 115.85,125.32 116,125.17 116,122.41 115.35,121.76 115.35,121.23 115.49,121.09 J2.93 ; v2(42.55,4.7) 42.54,4.69 J50.2
  L03_SIG1 w0.155: v2(10.27,92.38) 10.07,92.38 9.3,91.61 9.3,90.84 9.65,90.49 12.11,90.49 19.14,83.47 19.14,72.03 18.42,71.31 18.42,62.9 18.91,62.41 18.91,10.56 21.9,7.56 24.04,7.56 25.62,5.98 41.26,5.98 v2(42.55,4.7)
  L05_SIG2 w0.102: 80.16,82.82 80.36,82.62 82.55,82.62 82.58,82.59 82.83,82.59 83.06,82.36 83.06,82.12 83.37,81.81 84.11,81.81 84.5,82.2 v1(84.66,82.2)
  L05_SIG2 w0.155: v2(10.27,92.38) 10.27,94.59 17.26,101.57 55.2,101.57 61.32,95.45 63.39,95.45 J11.1 ; v2(101.21,128.04) 100.96,128.29 88.46,128.29 87.01,126.83 82.28,126.83 81.04,125.59 78.06,125.59 76.6,127.06 69.5,127.06 67.32,124.88 63,124.88 v2(52.79,114.67) ; v2(64.94,81.91) 65.41,81.45 73.15,81.45 73.71,82 75.13,82 75.95,82.82 80.16,82.82
  BOTTOM w0.193: R762.2 v2(42.55,4.7) ; v2(115.25,126.69) 115.25,126.93 113.83,128.35 109.94,128.35 109.06,127.46 107.2,127.46 106.62,128.04 v2(101.21,128.04)
SDA2: length 330.8
  TOP w0.193: R13.2 R12.2 85.77,106.65 85.53,106.65 84.51,107.66 83.11,107.66 82.28,108.5 82.28,109.86 82.51,110.1 82.51,112.05 83.11,112.64 83.11,114.92 82.2,115.83 82.2,122.09 78.57,125.71 78.57,127.25 79.45,128.12 81.09,128.12 v2(81.23,127.99) ; R15.1 123.43,110.48 124.08,111.12 124.08,113.28 124.97,114.17 126.24,114.17 127,114.94 127,118.24 125.74,119.49 125.74,120.76 124.32,122.19 123.1,122.19 121.8,123.49 121.38,123.49 117.56,127.3 114.8,127.3 110.67,123.17 107.55,123.17 105.79,121.41 104.39,121.41 103.13,122.67 v2(103.13,127.35) ; v2(54.6,4.84) J51.2
  L03_SIG1 w0.155: v2(54.6,4.84) 52.68,6.76 28.2,6.76 27.21,7.75 27.21,17.9 23.62,21.49 23.62,58.03 27.87,62.28 27.87,99.16 v2(34.25,105.54)
  L05_SIG2 w0.155: v2(103.13,127.35) 101.39,129.09 83.74,129.09 80.86,126.21 78.21,126.21 76.86,127.56 69.51,127.56 67.18,125.23 36.29,125.23 29.81,118.75 29.81,109.98 v2(34.25,105.54)
  BOTTOM w0.193: v2(81.23,127.99) 83.17,127.99 85.57,125.59 88.37,125.59 90.12,127.35 v2(103.13,127.35)
SDA2_C: length 2.4
  TOP w0.193: R15.2 120.49,111.55 J2.114
SDA_VMON: length 173.7
  TOP w0.193: 177.2,111.65 177.2,107.27 175.16,105.23 172.72,105.23 172.19,104.7 172.19,102.26 171.35,101.42 169.51,101.42 168.38,100.29 168.38,91.24 164.01,86.87 164.01,86.41 163.59,85.99 163.01,85.99 162.74,86.26 158.57,86.26 156.76,84.46 149.51,84.46 147.22,86.75 142.1,86.75 137.53,91.32 131.03,91.32 123.01,83.3 123.01,79.32 123.36,78.98 124.53,78.98 125.92,80.37 128.79,80.37 129.02,80.14 131.56,80.14 132.31,79.39 139.24,79.39 141.63,81.77 142.88,81.77 143.3,81.36 143.3,80.2 142.65,79.56 142.08,79.56 140.09,77.56 134.52,77.56 129.63,72.67 127.52,72.67 125.97,71.13 125.97,68.55 127.54,66.99 v2(139.12,66.99) 139.9,66.99 140.68,66.21 140.68,62.98 139.6,61.9 139.2,61.9 v2(136.87,59.56) ; 177.9,112.55 177.9,113.08 177.52,113.46 ; v2(176.89,121.63) 177.2,121.32 177.2,113.79
  TOP w0.254: 177.52,113.46 177.2,113.79 ; 177.9,112.55 177.9,112.35 177.2,111.65
  BOTTOM w0.193: U507.7 138.13,65.18 R613.1 138.13,66.35 138.45,66.68 138.81,66.68 v2(139.12,66.99) ; U501.7 v2(176.89,121.63) ; v2(136.87,59.56) 137.08,59.35 U509.7
SENSE_PULSE: length 158.9
  TOP w0.193: U11.G25 v1(86.66,88.2)
  L03_SIG1 w0.155: v2(5.33,22.23) 5.33,26.73 4.45,27.61 4.45,54.49 5.5,55.53 9.16,55.53 10.29,56.66 10.29,76.45 v2(10.76,76.92)
  L05_SIG2 w0.102: v1(86.66,88.2) 86.66,87.76 86.27,87.36 86.27,86.25 85.83,85.81 85.5,85.81 85.28,85.59 80.31,85.59 80.26,85.55 79.69,85.55
  L05_SIG2 w0.155: 79.69,85.55 76.22,85.55 76.05,85.72 71.87,85.72 71.48,85.33 71.48,85.2 71.11,84.83 70.15,84.83 69.94,84.62 66.08,84.62 65.89,84.81 54.03,84.81 53.39,85.45 48.49,85.45 47.17,84.12 47.17,82.6 48.04,81.73 v2(48.04,81.5) 46.85,81.5 46.53,81.18 43.94,81.18 39.01,76.25 35.43,76.25 34.93,75.75 34.28,75.75 33.34,76.68 24.09,76.68 22.44,78.33 22.44,78.47 22.09,78.83 21.6,78.83 21.25,78.48 21.25,77.68 21.55,77.38 21.55,76.72 21.2,76.37 11.31,76.37 v2(10.76,76.92)
  BOTTOM w0.193: v2(5.33,22.23) 2.92,19.81 2.92,17.78 3.3,17.4 U517.11 ; v2(48.04,81.5) 48.04,81.62 48.84,82.42 49.28,82.42 RN503.1
SENSE_PULSE_BUF: length 76.3
  TOP w0.193: J33.12 6.21,27.83 v2(6.22,27.81) ; J19.8 v2(26.92,50.8)
  L03_SIG1 w0.155: J18.12 6.26,46.5 4.83,45.08 4.83,35.1 6.22,33.71 v2(6.22,27.81)
  BOTTOM w0.193: U517.14 11.05,17.4 11.3,17.65 11.3,18.92 9.65,20.58 8.41,20.58 6.24,22.76 6.24,27.8 v2(6.22,27.81) ; v2(26.92,50.8) 30.13,50.8 31.26,49.68 31.26,46.33 29.82,44.9 27.34,44.9 25.9,43.45 14.28,43.45 10.23,47.51 7.25,47.51 J18.12
SEQ_SYNC: length 9.7
  TOP w0.193: U11.AB9 v1(102.66,71.2)
  BOTTOM w0.102: 107.37,70.73 107.36,70.74 103.12,70.74 v1(102.66,71.2)
  BOTTOM w0.193: 107.37,70.73 108.06,70.04 108.06,69.31 109,68.38 109,68.33 R631.2 R632.2
SEQ_SYNC_DUAL: length 165.4
  L03_SIG1 w0.155: v2(127.74,106.79) 125.62,108.9 125.62,111.55 126.71,112.64 128.51,112.64 128.84,112.97 128.84,120.75 118.91,130.68 83.28,130.68 81.89,129.3 v2(81.89,129.1)
  L05_SIG2 w0.155: v2(81.89,129.1) 69.66,129.1 v2(66.85,126.29) ; v2(127.74,106.79) 127.31,106.37 127.31,95.44 126.62,94.74 126.62,91.44 127.18,90.88 127.18,82.51 126.63,81.96 126.63,78.79 128.63,76.8 135.42,76.8 138.67,73.55 138.67,71.9 138.05,71.28 137.56,71.28 137.39,71.45 132.89,71.45 132.63,71.2 130.86,71.2 128.23,68.57 122.47,68.57 121.29,67.39 119.94,67.39 119.5,67.83 111.31,67.83 110.91,68.23 110.91,69.3 v2(110.06,70.15)
  BOTTOM w0.193: v2(110.06,70.15) R600.1 R631.1 ; R503.2 v2(66.85,126.29)
SP_CLK: length 7.9
  TOP w0.193: J35.3 24.21,27.34 24.61,27.75 27.31,27.75 28.76,26.3 R53.2
SP_D0: length 4.5
  TOP w0.193: J35.4 23.54,26.09 25.32,24.32 R49.2
SP_D1: length 9
  TOP w0.193: v2(28.96,24.43) 29.29,24.11 R54.2
  L05_SIG2 w0.155: v2(28.96,24.43) 28.96,24.33 28.48,23.84 27.77,23.84 27.5,24.1 22.33,24.1 J35.5
SP_D2: length 3.9
  TOP w0.193: J35.6 24.84,23.6 R50.2
SP_D3: length 9.2
  TOP w0.193: R55.2 v2(29.29,22.8)
  L05_SIG2 w0.155: v2(29.29,22.8) 28.7,23.38 27.98,23.38 27.41,22.81 26.81,22.81 26.34,22.34 J35.7
SP_D4: length 4.1
  TOP w0.193: R51.2 22.59,22.1 J35.8
SP_D5: length 4.2
  TOP w0.193: R52.2 22.7,20.96 J35.9
SP_D6: length 10.7
  TOP w0.193: R63.2 29.4,20.56 v2(30.34,20.56)
  L05_SIG2 w0.155: v2(30.34,20.56) 28.38,18.6 J35.10
SP_D7: length 4.9
  TOP w0.193: R62.2 25.32,19.81 24.9,19.38 24.9,19.2 23.04,17.35 J35.11
SP_FB: length 11.4
  TOP w0.193: v2(30.16,19.2) 31.17,20.21 R64.2
  BOTTOM w0.193: v2(30.16,19.2) 29.34,18.38 25.15,18.38 22.86,16.09 J35.12
SP_STAT_IN: length 95
  L03_SIG1 w0.155: v2(70.87,85.42) 69.5,84.05 69.5,82.13 58.74,71.36 58.74,70.87 56.79,68.92 56.79,67.55 51.41,62.17 51.41,56.42 45.42,50.43 45.42,47.02 43.86,45.46 43.86,40.99 39.5,36.63 v2(39.5,30.35)
  BOTTOM w0.193: R570.2 74.52,85.77 71.22,85.77 v2(70.87,85.42) ; U515.14 26.67,19.55 27.32,18.91 28.81,18.91 29.59,19.69 29.59,21.34 30.1,21.84 30.1,27.21 33.24,30.35 v2(39.5,30.35)
SP_WAVE_CLK: length 103.6
  TOP w0.193: U11.G26 v1(86.66,89.2)
  L03_SIG1 w0.102: v1(86.66,89.2) 86.66,88.84 86.26,88.44 86.26,86.24 85.61,85.59 85.5,85.59 85.27,85.36 85.27,83.83 85.06,83.62 85.06,83.04 84.61,82.59 80.37,82.59
  L03_SIG1 w0.155: 80.37,82.59 78.15,82.59 73.5,77.94 70.31,77.94 62.36,69.99 62.36,68.42 61.39,67.45 61.39,67.32 61.13,67.06 61.13,62.85 60.13,61.85 60.13,57.2 59.78,56.85 59.22,56.85 58.42,56.05 58.42,54.81 59.48,53.75 59.48,52.81 53.12,46.45 53.12,43.69 49.83,40.41 49.83,37.08 49.28,36.53 48.7,36.53 46.87,34.69 46.87,33.54 44.68,31.35 44.68,26.59 40.82,22.73 v2(40.26,22.73)
  BOTTOM w0.193: v2(40.26,22.73) 38.86,22.73 36.19,25.4 U515.2
SP_WAVE_D0: length 89.5
  L03_SIG1 w0.155: v2(33.4,24.75) 32.99,24.75 32.17,23.93 32.17,22.89 32.69,22.38 34.67,22.38 35.08,22.78 38.28,22.78 40.16,24.66 40.6,24.66 42.77,26.83 42.77,32.02 45.06,34.31 45.06,39.46 46.8,41.2 46.8,42.63 47.34,43.17 49.13,43.17 51.37,45.4 51.37,51.04 50.54,51.87 50.54,54.04 52.47,55.97 52.47,57.39 55.68,60.59 55.68,64.83 58.67,67.81 58.67,68.01 58.77,68.11 58.93,68.35 58.93,68.36 58.95,68.38 58.95,68.66 59.8,69.52 59.8,70.92 59.84,70.96 61.87,72.99 70.93,82.04 v2(72.77,82.04)
  BOTTOM w0.193: U515.3 v2(33.4,24.75) ; v2(72.77,82.04) 72.83,82.11 R580.2
SP_WAVE_D1: length 84.1
  L03_SIG1 w0.155: v2(71.63,83.16) 71.05,83.16 59.09,71.21 59.09,69.89 58.24,69.04 58.24,68.68 57.95,68.4 57.95,68.23 51.76,62.04 51.76,56.27 45.78,50.28 45.78,46.87 44.2,45.29 44.2,40.83 40.09,36.72 40.09,28.17 39.07,27.14 39.07,24.98 37.97,23.88 v2(36.45,23.88)
  BOTTOM w0.193: v2(71.63,83.16) 71.63,83.19 72.12,83.67 73.25,83.67 73.59,84.01 R566.2 ; U515.4 33.9,24.1 34.58,24.79 35.53,24.79 v2(36.45,23.88)
SP_WAVE_D2: length 87.1
  L03_SIG1 w0.155: v2(71.29,86.46) 70.84,86.02 70.62,86.02 69.15,84.54 69.15,82.28 58.38,71.51 58.38,71.06 56.33,69.01 56.33,67.67 54.33,65.67 52.96,65.67 52.57,65.28 52.57,64 51.05,62.48 51.05,56.56 45.07,50.58 45.07,47.16 43.37,45.47 43.37,41 38.81,36.44 38.81,28.19 38.32,27.7 38.32,24.86 37.95,24.48 36.12,24.48 35.15,23.52 33.47,23.52 v2(33.41,23.45)
  BOTTOM w0.193: v2(71.29,86.46) 71.42,86.33 74.06,86.33 74.66,86.93 R569.2 ; U515.5 v2(33.41,23.45)
SP_WAVE_D3: length 96.9
  L03_SIG1 w0.155: v2(34.93,24.13) 35.58,24.78 35.58,27.43 36.24,28.09 37.41,28.09 38.23,28.91 38.23,49.66 45.34,56.77 47.12,56.77 47.68,57.33 47.68,57.35 48.39,58.05 48.39,59.31 46.35,61.34 46.35,62.61 45.47,63.5 45.47,65.83 50.05,70.41 50.05,70.97 50.66,71.59 51.97,71.59 54.1,73.72 54.24,73.72 54.59,74.07 54.59,74.56 54.15,75.01 54.15,76.27 54.51,76.64 56.4,76.64 59.11,79.35 59.11,80.17 60.14,81.2 60.68,81.2 63.12,83.65 64.36,83.65 65.2,84.49 66.37,84.49 68.64,86.76 68.64,87.44 69.47,88.27 69.47,88.77 69.49,88.8 v2(69.49,88.96)
  BOTTOM w0.193: v2(34.93,24.13) 34.93,23.81 33.92,22.8 U515.6 ; v2(69.49,88.96) 70.07,89.53 73.91,89.53 74.04,89.66 R561.2
SP_WAVE_D5: length 83.7
  L03_SIG1 w0.155: v2(33.61,21.5) 34.3,21.5 35.22,22.42 38.42,22.42 40.31,24.31 40.93,24.31 43.31,26.68 43.31,31.68 45.62,33.99 45.62,39.08 51.73,45.18 51.73,48.17 53.69,50.13 53.69,54.72 54.95,55.99 55.87,55.99 57.16,57.27 57.16,63.69 59.38,65.91 59.38,67.78 59.46,67.86 59.66,68.17 59.66,68.2 60.52,69.06 60.52,70.63 60.56,70.67 62.04,72.15 70.24,80.35 v2(71.92,80.35)
  BOTTOM w0.193: R582.2 72.59,80.2 72.45,80.35 v2(71.92,80.35) ; U515.8 v2(33.61,21.5)
SSI_3D_TOGGLE: length 56.7
  TOP w0.193: v2(16.38,40.92) 16.66,40.64 J19.15 ; J33.9 3.46,24 v2(8.13,24)
  L03_SIG1 w0.155: v2(8.13,24) 8.13,24.02 9.34,25.22 9.34,43.01 8.86,43.49 7.66,43.49 6.64,44.51 J18.14
  L05_SIG2 w0.155: v2(16.38,40.92) 15.39,39.93 13.51,39.93 9.93,43.5 7.27,43.5 J18.14
  BOTTOM w0.193: v2(8.13,24) 9.28,24 13.12,20.17 13.12,17.02 11.55,15.45 U517.17
SSI_STB_B: length 72.7
  TOP w0.193: J19.14 v2(26.92,43.18) ; J33.8 3.8,22.83 5.05,21.58 7.12,21.58 v2(8.76,19.94)
  L03_SIG1 w0.155: v2(8.76,19.94) 8.76,23.73 9.73,24.69 9.73,48.42 8.62,49.53 7.24,49.53 J18.8
  L05_SIG2 w0.155: J18.8 7.27,49.5 20.6,49.5 v2(26.92,43.18)
  BOTTOM w0.193: U517.18 9.02,14.8 8.82,15 8.82,19.89 v2(8.76,19.94)
SSI_STB_G: length 78.1
  TOP w0.193: v2(8.17,18.8) 8.17,19.51 6.69,20.98 4.46,20.98 3.86,21.58 J33.7 ; J19.12 v2(26.73,45.72)
  L03_SIG1 w0.155: v2(8.17,18.8) 9.17,18.8 10.42,20.05 10.42,51.73 8.66,53.49 7.25,53.49 6.27,52.52 J18.6
  L05_SIG2 w0.155: J18.6 7.26,51.51 9.79,51.51 11.39,49.92 22.53,49.92 v2(26.73,45.72)
  BOTTOM w0.193: U517.19 8.97,14.15 8.2,14.93 8.2,18.24 8.17,18.28 v2(8.17,18.8)
SSI_STB_R: length 81.1
  TOP w0.193: v2(7.56,17.82) 7.52,17.85 7.52,19.18 6.26,20.45 4.38,20.45 4.26,20.33 J33.6 ; J19.10 v2(26.86,48.26)
  L03_SIG1 w0.155: J18.4 5.2,53.46 5.2,51.97 5.67,51.49 8.66,51.49 10.07,50.08 10.07,24.32 9.36,23.43 9.36,19.56 9.14,19.35 8.51,19.35 8.3,19.56 7.81,19.56 7.57,19.31 7.57,17.83 v2(7.56,17.82)
  L05_SIG2 w0.155: J18.4 7.24,53.53 9.25,53.53 12.45,50.33 24.79,50.33 v2(26.86,48.26)
  BOTTOM w0.193: U517.20 8.98,13.5 7.56,14.93 v2(7.56,17.82)
SSI_SUBFRAME: length 60.5
  TOP w0.193: J19.9 v2(13.42,48.26) ; J33.5 3.9,19.08 4.66,19.84 5.71,19.84 6.1,19.44 6.1,19.42 v2(6.86,18.67)
  L03_SIG1 w0.155: J18.21 8.26,26.63 6.86,25.23 v2(6.86,18.67)
  L05_SIG2 w0.155: J18.21 6.99,35.25 5.42,35.25 4.83,35.84 4.83,46.79 5.58,47.54 12.7,47.54 v2(13.42,48.26)
  BOTTOM w0.193: U517.21 9,12.85 7.11,14.74 7.11,17.35 6.86,17.61 v2(6.86,18.67)
SSP0_CLK: length 162.8
  TOP w0.193: v2(166.99,110.7) 167,110.7 167,110.76 166.47,111.29 U2.2 ; v2(165.63,57.73) 165.63,58.38 165.43,58.58 U15.2 ; v2(133.16,48.26) 132.02,47.12 130.84,47.12 130.32,47.64 127.32,47.64 126.79,47.12 126.3,47.12 125.03,45.85 119.57,45.85 119.06,45.34 R38.1
  L03_SIG1 w0.155: v2(166.99,110.7) 166.99,110.5 166.1,109.6 166.1,85.75 172.13,79.71 172.13,62.12 175,59.26 175,57.37 174.56,56.94 167.42,56.94 166.63,57.73 v2(165.63,57.73)
  L05_SIG2 w0.155: v2(165.63,57.73) 166.42,57.73 169.29,54.86 178.95,54.86 182.13,51.68 182.13,50.94 175.21,44.02 172.37,44.02 171.11,42.76 157.28,42.76 156.39,43.65 147.14,43.65 141.26,49.53 134.43,49.53 v2(133.16,48.26)
SSP0_CLK_DMD: length 35.2
  TOP w0.193: J63.B32 v2(112.17,14.48) ; R37.1 118.11,43.11 117.39,42.39 117.39,39.86 v2(115.83,38.3)
  L03_SIG1 w0.155: v2(115.83,38.3) 117.87,36.25 117.87,34.52 113.12,29.77 113.12,24.17 111.26,22.31 111.26,20.81 112.46,19.61 112.46,14.78 v2(112.17,14.48)
SSP0_CLK_DUAL: length 161.5
  TOP w0.193: J1.62 56.37,116.06 56.52,116.21 59.66,116.21 v2(60.4,115.47) ; v2(40.36,54.18) 40.36,71.58 39.47,72.47 39.47,92.64 50.64,103.81 v2(59.69,103.81) ; v2(57.63,47.75) 58.1,48.22 101.17,48.22 104.27,51.32 105.55,51.32 v2(105.92,51.69)
  L03_SIG1 w0.155: v2(59.69,103.81) 60.4,104.52 v2(60.4,115.47)
  L05_SIG2 w0.155: v2(40.36,54.18) 42.34,54.18 44.5,52.02 49.6,52.02 51.35,50.27 51.35,49.65 53.25,47.75 v2(57.63,47.75)
  BOTTOM w0.193: R680.1 104.17,58.4 103.07,57.3 103.07,54.54 v2(105.92,51.69)
SSP0_CSZ0: length 39.8
  TOP w0.193: U11.AC5 v1(103.66,67.2) ; v2(109.9,46.12) 116.03,46.12 117.33,44.82 117.33,43.72 116.52,42.91 TP44.1
  L03_SIG1 w0.155: v2(109.9,46.12) 110.42,46.64 110.42,51.13 110.37,51.18 110.37,52.3 109.92,52.75 109.68,52.98 109.68,54.23 109.18,54.73 109.18,57.34 108.98,57.54 108.98,57.54 v2(108.06,58.47)
  BOTTOM w0.102: v1(103.66,67.2) 104.11,67.2 104.5,67.59 104.83,67.59 107.06,65.36 107.06,65.04 107.06,63.29 107.14,63.2 107.14,63.17
  BOTTOM w0.193: 107.14,63.17 107.14,62.71 107.16,62.69 107.16,61.46 107.6,61.02 107.6,59.84 108.06,59.38 v2(108.06,58.47) 108.23,58.29 R676.1 R677.2
SSP0_CSZ0_DAD1: length 125.1
  TOP w0.193: J63.B24 v2(102.01,14.48)
  L03_SIG1 w0.155: v2(126.37,57.98) 126.37,57.46 126.4,57.43 126.4,56.17 126.37,56.14 126.37,55.51 128.15,53.74 128.15,52.99 130.37,50.76 130.41,50.76 131.09,50.08 135.41,50.08 137.74,47.75 137.74,45.8 138.75,44.8 138.75,44.31 139.32,43.73 140.44,43.73 142.8,41.37 142.8,33.1 v2(143.26,32.64)
  BOTTOM w0.193: v2(143.26,32.64) 139.5,32.64 133.82,26.96 133.82,20.97 134,20.79 134,18.71 133.5,18.21 131.06,18.21 130.3,18.97 126.48,18.97 122.54,15.03 102.56,15.03 v2(102.01,14.48) ; v2(126.37,57.98) 126.36,57.98 126.36,60 124.03,62.33 120.33,62.33 119.71,61.71 119.71,56.85 121.11,55.45 121.11,54.66 120.68,54.23 118.69,54.23 116.26,51.8 112.19,51.8 110.87,53.12 110.87,56.64 110.11,57.4 R677.1
SSP0_CSZ1: length 32.1
  TOP w0.193: U11.AB6 v1(102.66,68.2)
  L03_SIG1 w0.155: TP37.1 108.73,44.49 108.73,46.71 109.56,47.54 109.56,51.89 107.11,54.33 107.11,58.86 107.4,59.14 107.4,59.48 v2(108.21,60.29)
  BOTTOM w0.102: v1(102.66,68.2) 103.07,67.8 104.91,67.8 107.27,65.44 107.27,63.48 107.62,63.12 107.62,62.23
  BOTTOM w0.193: 108.24,60.29 108.59,59.94 R674.2 R675.1 ; 108.24,60.29 v2(108.21,60.29) ; 108.24,60.29 108.24,61.31 107.62,61.93 107.62,62.23
SSP0_CSZ1_DMD: length 98.6
  TOP w0.193: J63.C06 77.88,13.21 77.88,16.61 80.28,19.01 95.6,19.01 96.18,19.6 111.03,19.6 112.75,17.88 118.42,17.88 121.31,20.77 121.31,21.84 v2(120.41,22.74)
  L03_SIG1 w0.155: v2(120.41,22.74) 120.41,25.08 122.2,26.87 122.2,27.92 121.75,28.37 120.09,28.37 119.48,28.98 119.48,35.61 120.05,36.17 120.05,37.76 118.42,39.39 118.42,45.76 111.42,52.76 111.42,56.57 111.16,56.84 v2(111.16,57.35)
  BOTTOM w0.193: v2(111.16,57.35) 111.79,57.99 111.79,58.98 110.83,59.94 R674.1
SSP0_CSZ2: length 112.2
  TOP w0.193: U11.AC3 v1(103.66,65.2)
  L03_SIG1 w0.155: TP41.1 174.1,55.23 174.85,55.23 176.34,56.73 176.34,59.95 174.96,61.34 v2(174.96,63.78)
  L05_SIG2 w0.155: v2(108.46,53.93) 109.79,52.61 119.25,52.61 119.67,53.02 119.67,58.01 126.82,65.16 139.06,65.16 140.38,63.84 141.63,63.84 142.17,64.39 146.57,64.39 146.88,64.69 160.07,64.69 161.42,63.34 164.8,63.34 166.14,64.68 174.05,64.68 v2(174.96,63.78)
  BOTTOM w0.102: 103.16,63.56 103.16,64.7 v1(103.66,65.2)
  BOTTOM w0.193: 103.16,63.56 103.16,61.18 103.62,60.72 105.68,60.72 106.49,59.91 R679.2 106.36,59.83 105.86,59.33 105.86,57.27 107.39,55.74 107.39,55.47 108.46,54.4 v2(108.46,53.93) ; R649.1 171.32,54.24 TP41.1
SSP0_CSZ2_PMD1: length 124.6
  TOP w0.193: v2(166.07,59.35) 165.44,59.35 165.2,59.58 U15.4
  L05_SIG2 w0.155: v2(127.38,52.95) 133.09,47.23 142.59,47.23 154.09,35.73 165.93,35.73 172.62,42.42 174.76,42.42 182.82,50.47 182.82,51.97 175.44,59.35 v2(166.07,59.35)
  BOTTOM w0.193: R679.1 106.49,57.3 v2(108.1,55.69) 109.31,54.48 109.31,53.72 108.2,52.61 108.2,51.08 111.3,47.98 117.32,47.98 119.24,49.9 126.01,49.9 127.38,51.27 v2(127.38,52.95)
SSP0_CSZ3: length 47.6
  TOP w0.193: U11.AB4 v1(102.66,66.2)
  BOTTOM w0.102: 103.6,64.2 103.6,64.38 104.07,64.85 104.07,65.37 103.8,65.63 103.23,65.63 v1(102.66,66.2)
  BOTTOM w0.193: TP34.1 127.67,56.79 127.67,54.71 126,53.03 R693.1 126,50.71 125.8,50.52 118.7,50.52 116.6,48.41 111.73,48.41 108.79,51.36 108.79,52.47 109.83,53.52 109.83,54.94 109.02,55.75 R678.2 108.44,56.52 107.1,57.85 107.1,60.14 106.12,61.12 103.84,61.12 103.6,61.36 103.6,64.2
SSP0_CSZ3_PMD2: length 136
  TOP w0.193: v2(168.92,111.71) 167.19,111.71 166.61,112.29 U2.4
  L03_SIG1 w0.155: v2(137.92,68.45) 135.85,70.52 135.85,81.76 136.17,82.08 136.17,88.87 136.8,89.5 136.8,91.32 136.17,91.95 136.17,116.05 v2(137.08,116.97)
  L05_SIG2 w0.155: v2(137.92,68.45) 137.72,68.25 133.02,68.25 130.82,66.05 127.03,66.05 118.97,57.98 v2(118.97,53.54) ; v2(137.08,116.97) 151.66,116.97 155.9,121.21 164.25,121.21 168.92,116.54 v2(168.92,111.71)
  BOTTOM w0.193: v2(118.97,53.54) 116.78,51.35 111.85,51.35 110.35,52.85 110.35,55.67 110.06,55.96 R678.1
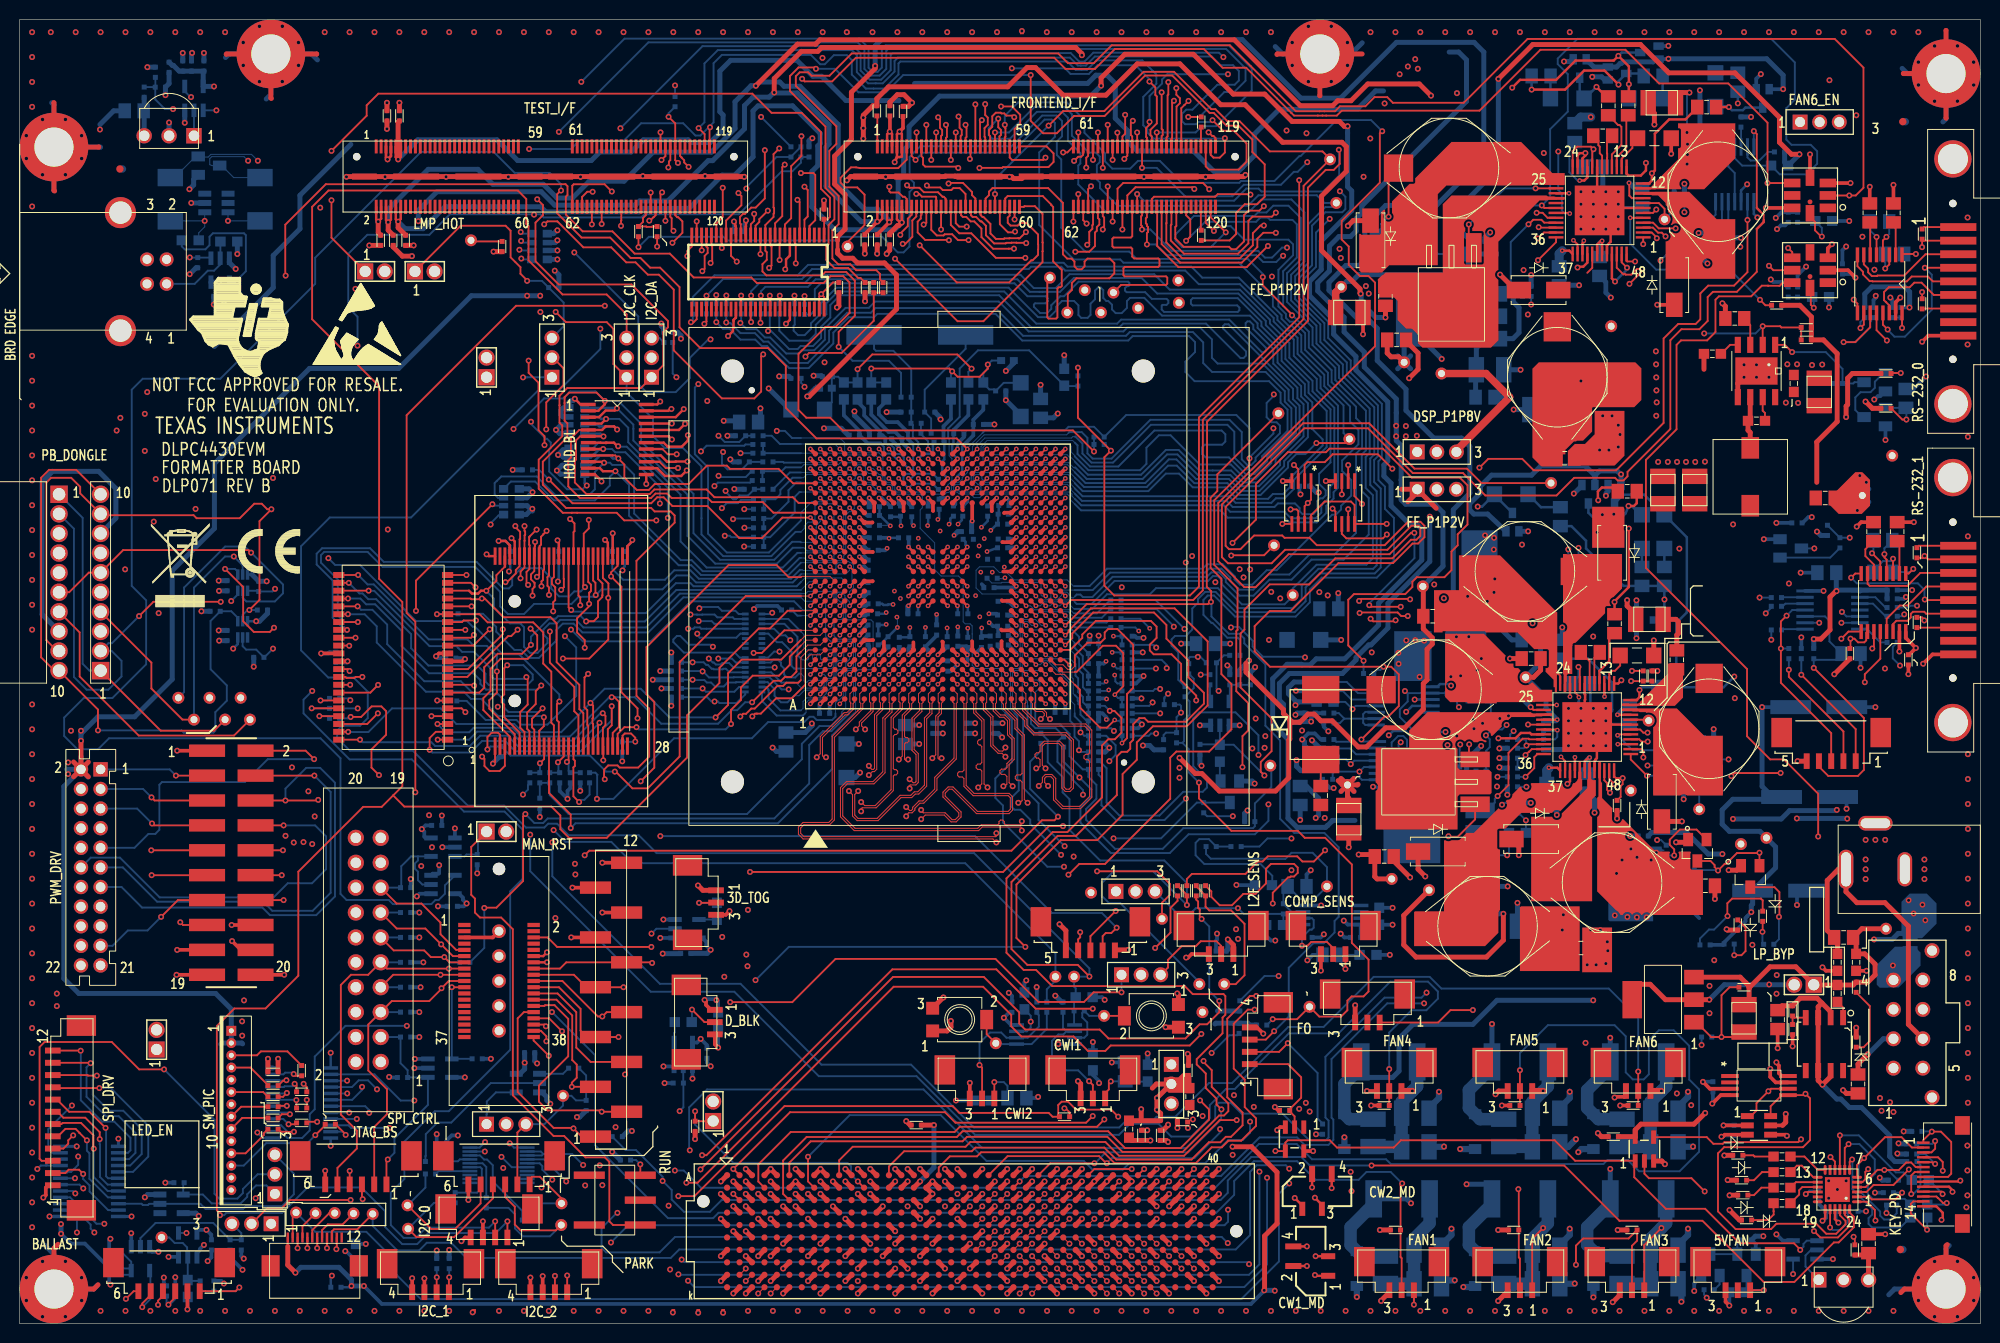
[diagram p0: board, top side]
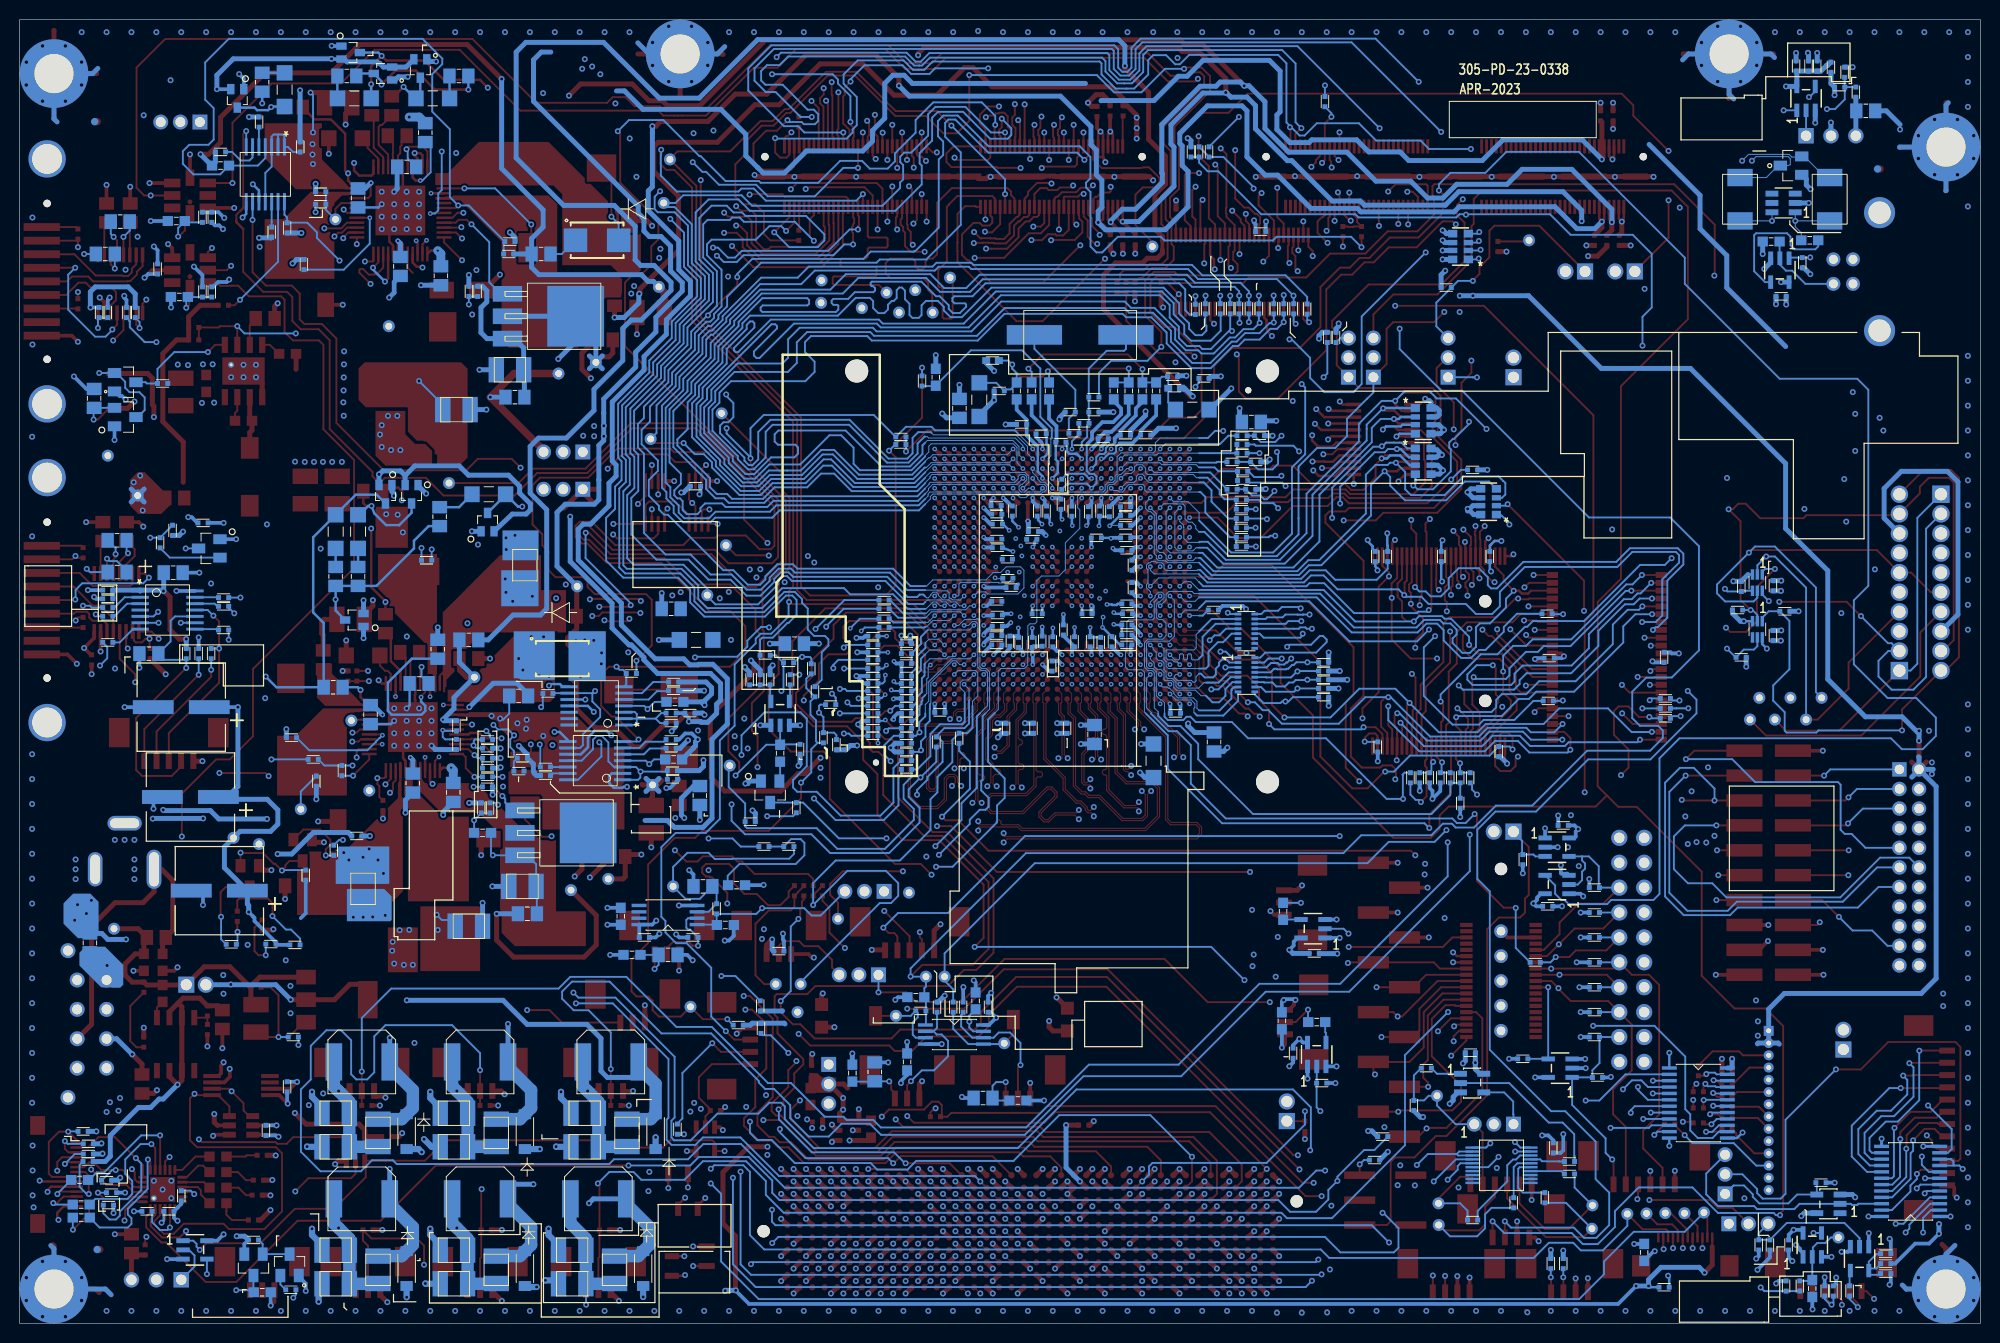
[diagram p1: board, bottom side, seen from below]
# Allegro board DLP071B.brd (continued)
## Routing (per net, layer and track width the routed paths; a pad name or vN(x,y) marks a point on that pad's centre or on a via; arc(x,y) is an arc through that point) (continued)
SSP0_CSZ5/SPD6: length 257.7
  TOP w0.193: v2(112.06,21.08) 111.34,21.81 107.75,21.81 106.94,22.62 106.29,22.62 105.94,22.27 105.94,21.21 R65.2 106.05,21.07 105.36,21.07 104.97,21.47 95.86,21.47 95.17,22.16 78.02,22.16 68.83,12.98 v2(67.19,12.98) ; U11.J23 v1(88.66,86.2)
  L03_SIG1 w0.155: v2(112.06,21.08) 113.39,19.76 113.39,17.81 114.08,17.11 114.08,12.56 115.4,11.25 116.4,11.25 117.67,9.98 122.89,9.98 124.03,11.12 124.03,15.76 124.79,16.52 124.79,18.95 126.87,21.03 128.04,21.03 130.85,23.83 130.85,28.98 130.42,29.41 130.42,32.35 129.92,32.84 129.92,39.88 125.76,44.04 125.76,46.63 121.65,50.74 121.65,52.74 122.52,53.62 122.52,57.31 121.16,58.67 121.16,63.25 120.26,64.15 120.13,64.15 118.75,65.53 118.75,66.45 116.59,68.61 116.59,69.22 115.96,69.84 115.96,71.19 115.95,71.2 115.95,71.88 116.75,72.68 120.23,72.68 122.51,70.4 123.81,70.4 124.16,70.75 124.16,71.93 121.97,74.12 v2(121.97,75.61)
  L05_SIG2 w0.102: v1(88.66,86.2) 88.68,86.2 89.15,85.72 89.15,83.96 90.69,82.42 95.63,82.42 97.28,80.77 97.28,80.52 98.3,79.5 99.06,79.5 101.09,77.47 101.09,76.84 101.73,76.2 107.19,76.2
  L05_SIG2 w0.155: v2(67.19,12.98) 66.11,12.98 60.54,7.41 47.52,7.41 45.61,9.32 42.71,9.32 40.62,7.23 37.15,7.23 35.58,8.81 30.77,8.81 29.17,10.41 29.17,14.85 31.3,16.98 31.95,16.98 34.39,19.43 v2(34.39,20.85) ; v2(121.97,75.61) 121.38,76.2 107.19,76.2
  BOTTOM w0.193: U515.9 v2(34.39,20.85)
SSP0_RXD: length 162.2
  TOP w0.193: v2(127.82,31.03) 130.31,31.03 TP49.1 132.58,31.29 134.78,31.29 135.43,31.94 135.43,32.92 135.86,33.35 137.08,33.35 137.59,33.86 137.59,37.11 135.89,38.81 135.89,46.81 133.17,49.53 131.09,49.53 130.38,50.24 123.6,50.24 120.29,53.55 v2(120.29,55.17) ; J63.B36 v2(117.25,14.48)
  L03_SIG1 w0.155: v2(159.73,28.61) 159.73,33.38 167.7,41.34 167.7,55.26 v2(166.05,56.91)
  L05_SIG2 w0.155: v2(127.82,31.03) 127.28,31.03 124.96,28.71 123.77,28.71 121.14,26.09 119.44,26.09 117.96,27.57 116.98,27.57 115.15,25.74 115.15,21.2 116.41,19.93 116.41,17.93 117.88,16.46 117.88,15.16 117.25,14.52 v2(117.25,14.48) ; v2(159.73,28.61) 158.8,27.68 146.49,27.68 145.27,28.91 145.27,33.26 143.82,34.71 142.18,34.71 138.3,30.83 133.04,30.83 TP49.1
  BOTTOM w0.193: v2(120.29,55.17) 119.25,56.21 119.25,58.57 118.61,59.22 ; v2(127.82,31.03) R712.2 ; R648.2 168.91,56.91 R650.2 v2(166.05,56.91) ; R623.2 119.27,66.26 119.76,65.76 119.76,64.81 R624.2 119.33,63.46 119.33,62.08 118.77,61.52 118.77,59.39 118.61,59.22 ; 118.61,59.22 R671.2
SSP0_RXD_DUAL: length 179.5
  TOP w0.193: J1.74 v2(59.37,112.16)
  L05_SIG2 w0.155: v2(59.37,112.16) 61.39,114.18 61.39,119.48 65.94,124.03 67.54,124.03 67.89,124.38 76.91,124.38 77.55,123.75 82.81,123.75 85.2,126.14 87.73,126.14 89.08,127.48 99.62,127.48 100.02,127.08 101.77,127.08 102.57,126.29 103.43,126.29 104.88,127.74 121.44,127.74 129.36,119.81 129.36,116.26 132.79,112.83 132.79,112.58 133.32,112.05 133.99,112.05 135.31,113.37 135.31,114.86 v2(134.67,115.49)
  BOTTOM w0.193: v2(134.67,115.49) 135.23,114.94 135.23,113.67 134.91,113.35 133.19,113.35 131.83,111.99 131.83,107.94 130.51,106.62 130.51,104.61 133.09,102.04 133.09,100.32 135.38,98.03 135.38,96.81 138.55,93.64 138.55,88.46 138.16,88.08 138.16,85.84 138.84,85.17 138.84,77.11 138.23,76.5 132.6,76.5 131.17,75.08 131.17,73.67 130.06,72.55 124.06,72.55 121.99,74.62 120.92,74.62 120.19,73.89 120.19,73.51 119.61,72.92 119.61,70.78 118.96,70.13 117.86,70.13 117.5,69.77 117.5,69.14 118.19,68.45 118.19,65.65 R624.1
SSP0_TXD: length 178.6
  TOP w0.193: v2(179.63,56.15) 179.62,56.14 174.92,56.14 v2(174.6,55.83) ; U2.3 166.6,111.79 167.12,111.27 167.51,111.27 v2(167.89,110.89) ; v2(127.82,42.83) 127.82,43.93 129.39,45.49 129.56,45.49 129.65,45.59 130,45.59 130.37,45.96 130.37,46.49 130,46.87 127.64,46.87 127.13,46.37 127.13,44.88 126.06,43.81 124.81,43.81 123.66,42.65 122.41,42.65 121.56,43.51 121.56,44.06 R40.1 ; U15.3 v1(163.02,59.08)
  L03_SIG1 w0.155: v2(167.89,110.89) 167.89,110.45 166.78,109.34 166.78,105.05 172.81,99.02 172.81,62.56 175.7,59.67 175.7,56.92 v2(174.6,55.83)
  L05_SIG2 w0.155: v2(179.63,56.15) 179.64,56.15 183.17,52.61 183.17,50.24 175.86,42.92 175.86,42.36 174.35,40.85 173.82,40.85 167.13,34.17 161.27,34.17 149.98,34.17 142.62,41.53 142.62,45.58 141.9,46.31 138.44,46.31 135.57,43.43 128.42,43.43 v2(127.82,42.83) ; v2(174.6,55.83) 171.92,58.51 163.59,58.51 v1(163.02,59.08)
SSP0_TXD_DMD: length 84.2
  TOP w0.193: v2(120.56,41.26) 120.38,41.44 120.38,42.22 120.21,42.39 120.21,42.39 120.21,43.04 120.02,43.23 R39.1 ; v2(69.45,15.7) 89.08,35.34 98.35,35.34 101.96,31.73 101.96,30.59 102.57,29.97 110.16,29.97 111.07,29.06 118.92,29.06 120.36,30.51 121.13,30.51 122.37,31.75 v2(122.37,32.88) ; J63.C02 v2(72.8,13.21)
  L05_SIG2 w0.155: v2(72.8,13.21) 72.18,13.83 72.18,14.98 71.45,15.7 v2(69.45,15.7)
  BOTTOM w0.193: v2(122.37,32.88) 121.35,33.9 121.35,40.48 v2(120.56,41.26)
SSP0_TXD_DUAL: length 165.1
  TOP w0.193: v2(58.45,115.44) 57.89,115.44 57.37,114.92 J1.66
  L05_SIG2 w0.155: v2(58.45,115.44) 58.45,117.65 65.32,124.53 67.46,124.53 67.67,124.73 77.06,124.73 77.23,124.56 83.13,124.56 85.06,126.49 87.24,126.49 88.59,127.83 99.76,127.83 100.16,127.43 102.21,127.43 102.89,126.75 103.38,126.75 104.71,128.09 121.58,128.09 129.71,119.96 129.71,116.59 v2(133.63,112.67)
  BOTTOM w0.193: R619.1 124.47,69.74 124.26,69.95 123.19,69.95 121.67,71.46 121.56,71.46 120.75,72.28 120.75,73.81 121.19,74.25 121.83,74.25 123.98,72.1 130.16,72.1 131.61,73.55 131.61,74.86 132.82,76.07 138.43,76.07 140.18,77.83 140.18,82.17 139.27,83.08 139.27,85.36 138.6,86.02 138.6,87.95 138.95,88.3 138.95,93.81 135.78,96.98 135.78,98.23 133.47,100.53 133.47,102.19 130.89,104.77 130.89,106.44 132.23,107.78 132.23,111.28 v2(133.63,112.67)
SSP1_CLK: length 112.9
  TOP w0.193: v2(23.61,78.63) 23.35,78.89 10.56,78.89 J15.6 7.05,76.59 5.05,74.59 J14.6
  L05_SIG2 w0.155: v2(71.75,88.9) 68.59,85.74 66.42,85.74 64.63,87.53 60.52,87.53 60.2,87.21 55.64,87.21 55.13,87.73 47.47,87.73 38.39,78.65 23.66,78.65 23.62,78.61 v2(23.61,78.63)
  BOTTOM w0.193: TP26.1 16.77,64.4 16.77,75.06 20.95,79.25 22.99,79.25 v2(23.61,78.63) 26.86,75.37 26.86,74.47 26.04,73.65 23.13,73.65 22.75,74.03 U504.5 ; R564.1 R572.2 73.67,87.12 72.2,87.12 71.64,87.69 71.64,88.78 v2(71.75,88.9)
SSP1_CSZ0: length 137.6
  TOP w0.193: v2(25.95,70.97) 25.51,70.54 23.89,70.54 22.8,71.63 22.8,75.12 v2(20.95,76.96) ; J15.1 14.39,60.46 19.82,60.46 TP29.1
  L03_SIG1 w0.155: v2(25.95,70.97) 25.25,70.27 25.25,65.06 21.78,61.59 TP29.1
  L05_SIG2 w0.155: v2(71.29,90.55) 70.61,90.55 70.14,90.07 69.07,90.07 68.53,89.53 66.05,89.53 65.15,90.42 60.71,90.42 60.06,91.07 55.51,91.07 54.74,90.3 20.64,90.3 13.08,82.75 13.08,81.14 17.27,76.96 v2(20.95,76.96)
  BOTTOM w0.193: J14.1 6.43,82.17 6.43,67.28 7.12,66.59 J15.1 ; R560.1 R562.2 74.04,90.55 73.41,89.92 71.92,89.92 v2(71.29,90.55) ; U504.1 22.25,76.69 21.97,76.96 v2(20.95,76.96)
SSP1_DI: length 127.7
  TOP w0.193: v2(20.51,73.61) 13.64,73.61 v2(12.18,72.15) ; U11.F22 v1(85.66,85.2)
  L03_SIG1 w0.155: v2(20.51,73.61) 20.51,72.07 19.37,70.92 TP28.1
  L05_SIG2 w0.102: 80.58,84.29 80.88,84.59 85.06,84.59 v1(85.66,85.2)
  L05_SIG2 w0.155: 80.58,84.29 79.69,84.29 79.65,84.34 75.98,84.34 75.83,84.19 74.71,84.19 74.2,83.68 72.6,83.68 72.22,83.31 72.22,82.92 71.88,82.57 71.14,82.57 70.77,82.94 66.05,82.94 65.81,82.7 63.24,82.7 62.21,83.73 55.89,83.73 54.89,82.74 52.84,82.74 52.54,82.44 52.13,82.44 51.64,81.95 50.01,81.95 48.36,80.29 44.81,80.29 38.67,74.15 35.08,74.15 34.65,74.57 26.41,74.57 v2(26.05,74.93) 21.84,74.93 v2(20.51,73.61)
  BOTTOM w0.193: J14.2 5.54,81.06 5.54,65.94 6.83,64.64 9.04,64.64 10.39,65.99 10.39,67.59 9.39,68.59 J15.2 9.06,69.39 9.42,69.39 v2(12.18,72.15) ; U504.4 24.31,74.74 R604.2 25.78,74.66 v2(26.05,74.93)
SSP1_DO: length 107.8
  TOP w0.193: J15.4 13.44,67.41 13.44,64.76 16.6,61.59 TP27.1
  L05_SIG2 w0.155: J14.4 5.99,76.61 5.99,74.85 J15.4 ; v2(72.01,84.92) 71.57,84.48 70.29,84.48 70.08,84.27 65.94,84.27 65.77,84.44 54.56,84.44 54.31,84.19 48.01,84.19 47.63,83.81 47.63,83.18 48.63,82.18 48.63,81.25 48.03,80.65 44.32,80.65 39.24,75.56 35.43,75.56 34.82,74.95 33.12,74.95 31.74,76.33 23.75,76.33 v2(21.84,78.23)
  BOTTOM w0.193: R565.1 R571.2 74.93,85.09 74.3,84.46 73.44,84.46 73.06,84.07 72.77,84.07 72.01,84.84 v2(72.01,84.92) ; U504.2 22.75,77.33 v2(21.84,78.23) 20.95,78.23 17.78,75.06 TP27.1
SSP2/LED_DIN: length 3.2
  BOTTOM w0.193: U513.1 55.42,25.46 R722.1
SSP2_CLK: length 102.3
  TOP w0.193: U11.K23 v1(89.66,86.2)
  L03_SIG1 w0.102: 79.69,78.92 79.74,78.97 80.34,78.97 80.5,78.81 85.83,78.81 86.06,79.04 86.06,79.46 87.2,80.6 87.2,82.6 88.36,83.77 88.84,83.77 89.09,84.02 89.09,84.38 89.06,84.42 89.06,85.46 89.46,85.87 89.46,86 v1(89.66,86.2)
  L03_SIG1 w0.155: v2(57.48,16.15) 58.12,16.8 60.75,16.8 63.49,19.54 63.49,21.24 66.66,24.41 66.66,28.74 70.47,32.54 70.47,34.85 70.86,35.24 70.86,37.37 75.83,42.34 75.83,51.52 77.58,53.28 77.58,58.92 75.33,61.17 75.33,62.17 74.98,62.52 74.71,62.52 73.9,63.33 73.9,69.25 73.19,69.96 73.19,73.73 73.98,74.51 75,74.51 79.41,78.92 79.69,78.92
  BOTTOM w0.193: 53.42,17.27 53.27,17.13 U516.3 ; 53.42,17.27 56.36,17.27 v2(57.48,16.15) ; 53.42,17.27 53.16,17.53 U516.2
SSP2_CSZ2/SPD7: length 104.5
  TOP w0.193: U11.J24 v1(88.66,87.2)
  L03_SIG1 w0.102: 79.69,81.47 80.01,81.47 80.13,81.59 85.61,81.59 86.1,82.08 86.1,83.79 86.27,83.96 86.27,85.36 86.5,85.59 86.9,85.59 87.27,85.96 87.27,86.36 87.5,86.59 87.76,86.59 88.37,87.2 v1(88.66,87.2)
  L03_SIG1 w0.155: 79.69,81.47 78.67,81.47 73.96,76.75 70.6,76.75 63.4,69.55 63.4,67.99 62.43,67.02 62.43,66.89 62.17,66.63 62.17,56.4 60.87,55.1 60.87,51.99 54.52,45.64 54.52,43.11 51.73,40.32 51.73,35.15 50.27,33.68 50.27,31.81 49.55,31.09 48.6,31.09 47.36,29.84 47.36,25.71 41.59,19.94 v2(37.72,19.94)
  BOTTOM w0.193: U515.10 33.54,20.2 33.81,19.94 v2(37.72,19.94)
SSP2_CSZ_0: length 102.2
  TOP w0.193: U11.J26 v1(88.66,89.2)
  L03_SIG1 w0.102: v1(88.66,89.2) 88.66,88.76 89.06,88.36 89.06,87.04 88.83,86.81 88.26,86.81 88.06,86.6 88.06,86.04 87.83,85.81 87.42,85.81 87.06,85.44 87.06,84.04 86.3,83.28 86.3,81.28 85.83,80.81 80.5,80.81 80.36,80.94 79.69,80.94
  L03_SIG1 w0.155: 79.69,80.94 78.82,80.94 74.26,76.37 73.11,76.37 71.31,74.58 71.31,69.39 72.05,68.65 72.05,62.04 71.37,61.35 71.37,59.76 70.48,58.88 70.48,54.34 72.45,52.38 72.45,43.02 71.8,42.37 71.8,41.15 69.45,38.81 69.45,35.65 65.29,31.49 65.29,27.39 64.34,26.44 64.34,23.92 60.79,20.37 v2(60.79,20.02)
  L05_SIG2 w0.155: v2(54.33,14.66) 54.33,15.6 58.76,20.02 v2(60.79,20.02)
  BOTTOM w0.193: U516.5 53.04,16.33 53.31,16.05 53.31,15.67 v2(54.33,14.66)
SSP2_DIN: length 101.2
  TOP w0.193: U11.K24 v1(89.66,87.2)
  L03_SIG1 w0.102: 79.69,80.59 86.18,80.59 86.59,81 86.59,83.19 87.1,83.69 87.1,83.77 87.27,83.94 87.27,85.36 87.5,85.59 87.91,85.59 88.27,85.95 88.27,86.36 88.5,86.59 88.9,86.59 89.51,87.2 v1(89.66,87.2)
  L03_SIG1 w0.155: J44.2 51.1,18.85 60.52,18.85 62.4,20.73 62.4,21.24 64.9,23.74 64.9,26.36 65.85,27.31 65.85,31.39 69.89,35.43 69.89,38.65 73.13,41.89 73.13,51.57 74.87,53.31 74.87,56.05 71.91,59.01 71.91,61.34 72.46,61.89 72.46,68.74 71.66,69.54 71.66,74.43 73.22,76 74.37,76 78.97,80.59 79.69,80.59
SSP2_DO: length 157.6
  TOP w0.193: U11.J25 v1(88.66,88.2)
  L03_SIG1 w0.155: v2(41.76,51.84) 45.67,55.75 47.78,55.75 48.87,56.85 48.87,59.84 47.12,61.59 47.12,62.49 47.13,62.5 47.13,62.99 47.12,63 47.12,66.04 51.23,70.15 52.35,70.15 52.96,70.76 52.96,72.07 54.25,73.36 54.61,73.36 56.4,75.15 56.4,75.63 63.77,83.01 65.63,83.01 66.02,83.39 66.02,83.58 69,86.55 69,87.02 70.08,88.1 70.08,94.04 v2(70.14,94.1) ; v2(55.75,14.48) 54.52,13.24 48.31,13.24 43.97,17.58 43.97,21.29 48.71,26.03 48.71,26.89 50.81,28.99 50.81,33.67 52.15,35.01 52.15,39.99 54.88,42.72 54.88,45.12 v2(56.64,46.88)
  L05_SIG2 w0.102: 86.56,89.64 86.78,89.64 87.16,89.26 87.16,88.78 87.27,88.67 88.19,88.67 v1(88.66,88.2)
  L05_SIG2 w0.155: v2(41.76,51.84) 44.67,48.93 50.45,48.93 52.5,46.88 v2(56.64,46.88) ; v2(70.14,94.1) 69.84,94.4 69.84,97.15 71.95,99.26 73.85,99.26 79.15,93.96 82.24,93.96 86.56,89.64
  BOTTOM w0.193: U516.4 53.5,16.73 v2(55.75,14.48)
SUBFRAME: length 153.9
  TOP w0.193: U11.D22 v1(83.66,85.2) ; v2(40.43,72.68) 40.43,75.77 v2(48.22,83.57)
  L03_SIG1 w0.155: v2(8.64,10.16) 8.64,11.39 12.83,15.59 12.83,71.11 v2(14.18,72.46)
  L05_SIG2 w0.102: 79.69,84.77 80.77,84.77 80.8,84.8 83.17,84.8 83.57,85.2 v1(83.66,85.2)
  L05_SIG2 w0.155: v2(40.43,72.68) 39.64,72.68 35.32,68.36 32.61,68.36 28.74,72.23 23.89,72.23 23.43,71.78 14.86,71.78 v2(14.18,72.46) ; v2(48.22,83.57) 48.95,82.84 50.77,82.84 51.77,83.84 54.46,83.84 54.72,84.1 62.34,84.1 63.39,83.05 65.55,83.05 65.79,83.29 70.7,83.29 71.18,83.78 72.2,83.78 72.45,84.03 73.76,84.03 74.5,84.77 79.69,84.77
  BOTTOM w0.193: v2(8.64,10.16) 7.84,10.16 5.15,12.85 U517.4 ; RN503.2 48.37,83.42 v2(48.22,83.57)
SW_EN: length 11.6
  TOP w0.193: U7.1 180.06,99.82 v2(180.8,99.09)
  BOTTOM w0.193: Q501.3 187.16,96.01 187.03,95.89 R550.2 185.94,97.37 184.23,99.09 v2(180.8,99.09)
SW_SS: length 2.1
  TOP w0.193: U7.4 174.47,99.82 173.56,98.91 C18.2
SWNODE2_CORE: length 0.8
  TOP w0.254: U2.25 156.72,117.05 156.7,117.06
SWNODE2_P2P5V: length 2.1
  TOP w0.193: 159.9,107.17 160.41,107.68 U2.41
SWNODE_CORE: length 9.8
  TOP w0.193: v2(147.86,59.07) 147.84,59.07 147.84,58.15 Q2.3
  L03_SIG1 w0.155: v2(147.86,59.07) 147.19,59.73 147.19,60.31 146.21,61.3 146.21,64.29 146.98,65.06 v2(146.98,66.06)
  vias: v2(145.99,65.97) v2(146.56,70.04) v2(147.82,70.05) v2(148.67,66.65) v2(149.1,67.82)
SWNODE_MOT: length 4
  TOP w0.193: 167.95,61.62 166.99,62.58 U15.10
SWNODE_MOT2: length 2.9
  TOP w0.193: 168.44,115.15 168.3,115.29 U2.10
TCK: length 135.5
  TOP w0.193: J42.5 32.41,15.85 34.4,17.83 34.4,19.66 32.76,21.3 32.76,34.53 33.79,35.56 35.55,35.56 36.82,36.83 J23.9 37.47,36.19 v2(43.78,36.19) 43.79,36.2 J27.15 ; U11.N24 v1(92.66,87.2)
  L03_SIG1 w0.102: 79.69,79.6 85.91,79.6 87,80.69 87,82.69 88.26,83.95 88.26,85.35 88.51,85.6 88.91,85.6 89.26,85.95 89.26,86.38 89.48,86.59 92.06,86.59 v1(92.66,87.2)
  L03_SIG1 w0.155: 79.69,79.6 79.12,79.6 74.71,75.2 73.52,75.2 72.36,74.05 72.36,69.84 73.15,69.05 73.15,63.11 74.12,62.14 74.12,59.33 75.73,57.73 75.73,52.58 75.13,51.98 75.13,43.03 v2(74.29,42.18)
  L05_SIG2 w0.155: v2(74.29,42.18) 72.81,40.7 69.89,40.7 66.09,36.91 65.39,36.91 64.94,37.36 57.81,37.36 56.65,36.2 51.91,36.2 49.58,38.52 46.12,38.52 v2(43.78,36.19)
  BOTTOM w0.193: R710.1 J23.9
TDI: length 130.7
  TOP w0.193: U11.N25 v1(92.66,88.2) ; J27.19 43.77,34.93 v2(43.03,34.19) 43.03,34.13 41.78,32.88 37.96,32.88 J23.5 35.56,30.48 35.56,25.8 37.47,23.89 37.47,21.34 36.17,20.04 J42.2
  L03_SIG1 w0.102: 79.69,79.99 80.32,79.99 80.5,79.81 85.83,79.81 86.79,80.77 86.79,82.77 88.06,84.04 88.06,85.46 88.41,85.81 88.83,85.81 89.06,86.04 89.06,86.46 89.4,86.81 91.98,86.81 92.19,87.01 92.19,87.73 v1(92.66,88.2)
  L03_SIG1 w0.155: v2(71.67,39.42) 73.66,41.41 73.66,51.57 75.31,53.22 75.31,57.58 73.3,59.59 73.3,61.25 72.8,61.75 72.8,68.91 72.01,69.7 72.01,74.29 73.33,75.61 74.51,75.61 78.89,79.99 79.69,79.99
  L05_SIG2 w0.155: v2(71.67,39.42) 70.08,39.42 66.25,35.59 58.15,35.59 56.42,33.86 45.88,33.86 44.85,34.89 43.73,34.89 v2(43.03,34.19)
  BOTTOM w0.193: R716.1 J23.5
TDO1: length 124.1
  TOP w0.193: v2(33.66,15.55) J42.4 ; U11.N23 v1(92.66,86.2)
  L03_SIG1 w0.102: 79.69,76.81 85.87,76.81 86.49,77.42 86.49,78.42 87.82,79.75 87.82,82.18 88.75,83.11 89.08,83.11 89.37,83.4 89.99,83.4 90.4,83.81 90.83,83.81 91.06,84.04 91.06,85.15 91.5,85.59 92.06,85.59 v1(92.66,86.2)
  L03_SIG1 w0.155: 79.69,76.81 79.48,76.81 79.07,76.4 75.51,72.84 75.51,69.67 76.16,69.02 76.16,67.86 75.43,67.13 75.43,64.72 76.95,63.2 76.95,61.54 79.07,59.43 79.07,51.99 77.48,50.4 77.48,41.82 73.4,37.74 73.4,31.78 67.86,26.24 67.86,23.78 65.14,21.07 65.14,19.33 61.21,15.4 59.01,15.4 v2(57.68,14.07)
  L05_SIG2 w0.155: v2(33.66,15.55) 34.84,14.37 49.55,14.37 51.17,12.76 54.27,12.76 54.93,13.41 57.02,13.41 v2(57.68,14.07)
TDO2: length 117.1
  TOP w0.193: J23.13 38.46,40.28 41.38,40.28 v2(43,38.66) 44.19,37.47 J27.11 ; U11.N22 v1(92.66,85.2)
  L03_SIG1 w0.102: 79.69,76.26 79.9,76.47 85.82,76.47 87.86,78.5 87.86,79.38 88.12,79.63 88.12,81.87 88.84,82.59 89.78,82.59 90.8,83.6 90.91,83.6 91.27,83.96 91.27,84.36 91.62,84.71 92.06,84.71 92.54,85.2 v1(92.66,85.2)
  L03_SIG1 w0.155: 79.69,76.26 76.16,72.73 76.16,70.02 76.51,69.67 76.51,67.71 76.18,67.38 76.18,64.59 77.51,63.25 77.51,61.7 79.43,59.79 79.43,51.46 77.87,49.91 77.87,41.37 v2(74.12,37.62)
  L05_SIG2 w0.155: v2(43,38.66) 45.34,41.01 49.37,41.01 51.29,39.09 55.02,39.09 55.77,38.34 61.52,38.34 65.17,41.99 71.04,41.99 72.06,43.01 74.43,43.01 74.93,42.51 74.93,38.43 v2(74.12,37.62)
  BOTTOM w0.193: R708.1 J23.13
TILT_X: length 128.4
  TOP w0.193: U3.5 v2(178.29,116.33) 178.29,122.49 174.28,126.49 167.23,126.49 163.79,129.93 155.12,129.93 148.92,123.72 134.86,123.72 134.36,123.21 133.26,123.21 132.9,123.21 132.43,123.21 129.99,123.21 129.73,123.47 129.4,123.8 128.25,124.95 125.12,128.09 122.7,128.09 120.79,130.01 111.72,130.01 109.69,127.98 106.67,127.98 105.54,129.11 85.29,129.11 82.88,126.7 80.08,126.7 v2(79.81,126.97)
  L03_SIG1 w0.155: v2(75.63,123.08) 75.93,123.08 v2(79.81,126.97)
  BOTTOM w0.193: R514.2 v2(75.63,123.08)
TILT_Y: length 162.9
  TOP w0.193: R14.2 87.76,106.5 87.76,107.06 87.38,107.44 85.33,107.44 84.72,108.05 83.49,108.05 82.9,108.64 82.9,111.5 83.54,112.14 83.54,115.02 82.6,115.96 82.6,119.61 83.31,120.33 83.31,122.11 79.17,126.25 79.17,127.23 79.57,127.63 80.43,127.63 80.78,127.28 82.6,127.28 84.88,129.55 105.94,129.55 106.93,128.56 109.57,128.56 111.39,130.39 123.45,130.39 125.56,128.28 128.44,125.4 129.85,123.99 130.18,123.66 132.61,123.66 134.17,123.66 134.68,124.16 137.27,124.16 138.2,125.1 139.5,125.1 140.08,124.52 147.3,124.52 153.81,131.03 185.15,131.03 188.08,128.11 188.08,115.85 187.29,115.06 v2(186.63,115.06) U3.2
TMS1: length 130.1
  TOP w0.193: J42.3 34.92,12.75 v2(34.99,12.67) ; v1(93.66,88.2) U11.P25
  L03_SIG1 w0.102: v1(93.66,88.2) 93.66,88.1 93.29,87.72 93.29,83.42 92.6,82.74 91.45,82.74 90.7,81.99 90.7,80.23 89.81,79.35 89.81,78.59 87.04,75.81 81.72,75.81 81.27,75.36 81.27,71.03 81.49,70.81 84.9,70.81 85.26,70.45 85.26,69.54 85.06,69.34 85.06,69.04 84.83,68.81 84.53,68.81 84.26,68.54 84.26,66.95 84.06,66.75 84.06,66.04 83.83,65.81 83.36,65.81 83.06,65.5 83.06,65.04 82.7,64.68 81.48,64.68 81.09,64.3 81.09,63.92 80.84,63.67 80.33,63.67 79.82,63.16 79.82,62.1
  L03_SIG1 w0.155: 79.82,62.1 79.82,60.93 80.22,60.53 80.22,50.41 78.71,48.9 78.71,40 73.94,35.23 73.94,31.69 69.29,27.04 69.29,24.48 66.6,21.79 66.6,18.6 62.1,14.1 v2(59.44,14.1)
  L05_SIG2 w0.155: v2(59.44,14.1) 56.63,11.29 51.58,11.29 49.05,13.82 36.13,13.82 v2(34.99,12.67)
TMS2: length 119.6
  TOP w0.102: U11.P26 v1(93.66,89.2)
  TOP w0.193: J27.17 v2(42.93,35.56) 38.1,35.56 J23.7
  L03_SIG1 w0.102: v1(93.66,89.2) 93.06,88.59 93.06,83.72 92.46,83.12 90.62,83.12 89.36,81.87 89.36,79.2 86.28,76.12 81.64,76.12 81.06,75.54 81.06,70.87 81.33,70.59 84.83,70.59 85.06,70.36 85.06,70.04 84.61,69.59 84.5,69.59 84.06,69.15 84.06,67.04 83.73,66.71 83.16,66.71 83.06,66.61 83.06,66.04 82.72,65.7 81.48,65.7 81.22,65.44 81.22,64.94 80.97,64.69 80.34,64.69 80.21,64.55 80.21,64.43 79.69,63.91
  L03_SIG1 w0.155: 79.69,63.91 79.32,63.54 79.32,60.72 79.79,60.24 79.79,51 78.23,49.45 78.23,40.43 v2(74.24,36.44)
  L05_SIG2 w0.155: v2(42.93,35.56) 44.55,35.56 45.12,36.13 50.31,36.13 50.99,35.46 56.72,35.46 57.4,36.13 66.1,36.13 69.98,40.02 72,40.02 73.17,38.84 73.17,37.51 v2(74.24,36.44)
  BOTTOM w0.193: R715.1 J23.7
TRACECLK: length 77.6
  TOP w0.193: J27.6 53.85,39.37 54.82,38.4 v2(64.43,38.4)
  L03_SIG1 w0.155: v2(64.43,38.4) 64.43,37.72 63.42,36.7 63.01,36.7 62.81,36.91 62.81,37.3 63.68,38.17 63.68,40.27 64.08,40.68 64.56,40.68 65.01,41.13 65.01,48.72 65.14,48.85 65.57,48.85 65.7,48.72 65.7,42.52 65.83,42.38 66.25,42.38 66.4,42.53 66.4,50.31 66.27,50.43 65.14,50.43 65.01,50.56 65.01,51.12 65.14,51.24 66.27,51.24 66.4,51.37 66.4,51.88 66.27,52.01 65.18,52.01 65.06,52.13 65.06,52.64 65.18,52.77 66.27,52.77 66.4,52.9 66.4,60 66.4,61.82 65.73,62.49 65.73,63.51 64.77,64.48 64.77,64.91 65.35,65.49 65.35,65.71 65.94,66.3 65.94,66.8 65.74,67 65.74,67.02 65.74,68.57 67.17,70 68.76,70 v2(69.12,70.36)
  BOTTOM w0.193: RN504.12 73.51,70.36 73.1,69.95 69.37,69.95 69.12,70.2 v2(69.12,70.36)
TRACECLKR: length 12.9
  TOP w0.193: U11.D7 v1(83.66,69.2)
  BOTTOM w0.102: v1(83.66,69.2) 83.27,68.81 83.27,67.74 83.06,67.52 83.06,67.04 82.82,66.8 80.79,66.8 80.79,66.8 79.69,66.8
  BOTTOM w0.193: RN504.5 76.37,70.36 77.24,69.49 77.77,69.49 78.73,68.53 78.73,68 78.73,67.67 78.73,67.07 79,66.8 79.69,66.8
TRACEPKT0: length 78.9
  TOP w0.193: J27.30 51.44,31.75 50.8,31.12 50.8,23.6 54.46,19.94 56.44,19.94 v2(56.49,19.89) 57.33,19.05 J28.1
  L03_SIG1 w0.155: v2(56.49,19.89) 58.8,19.89 63.82,24.91 63.82,26.57 64.75,27.5 64.75,31.53 69.06,35.85 69.06,38.99 71.32,41.24 71.32,42.69 71.84,43.21 71.84,52.27 70.08,54.03 70.08,62.64 v2(70.89,63.44)
  BOTTOM w0.193: R641.2 70.13,63.88 70.57,63.44 v2(70.89,63.44) 71.23,63.44 71.39,63.28 73.12,63.28 73.46,63.62 73.48,63.62 74.02,64.16 RN505.9
TRACEPKT0R: length 10.7
  TOP w0.193: U11.C2 v1(82.66,64.2)
  BOTTOM w0.102: 80.13,62.23 80.21,62.32 80.21,62.75 80.13,62.84 80.13,63.22 80.5,63.59 82.06,63.59 v1(82.66,64.2)
  BOTTOM w0.193: RN505.8 75.72,63.51 77.22,62.01 79.9,62.01 80.13,62.23
TRACEPKT1: length 78.8
  TOP w0.193: J28.2 v2(59.37,21.59) 59.24,21.72 53.86,21.72 52.97,22.62 52.97,24.26 55.95,27.25 55.95,31.06 54.55,32.46 53.61,32.46 53.53,32.39 J27.28
  L03_SIG1 w0.155: v2(69.66,64.77) 69.23,64.34 69.23,53.64 70.87,52 70.87,43.7 70.42,43.25 70.42,41.64 68.27,39.49 68.27,36.22 63.81,31.76 63.81,29.2 59.37,24.76 v2(59.37,21.59)
  BOTTOM w0.193: R640.2 v2(69.66,64.77) 69.99,64.43 72.9,64.43 73.38,64.92 RN505.10
TRACEPKT1R: length 11.8
  TOP w0.193: U11.D3 v1(83.66,65.2)
  BOTTOM w0.102: v1(83.66,65.2) 83.66,65.14 83.45,64.93 82.95,64.93 82.83,64.81 82.71,64.81 82.27,64.36 82.27,64.25 81.83,63.81 80.28,63.81 79.91,63.44 79.91,62.75 79.69,62.53
  BOTTOM w0.193: RN505.7 76.06,64.92 76.11,64.87 76.19,64.87 76.37,64.7 76.37,64.62 76.4,64.58 76.4,63.74 77.6,62.53 79.69,62.53
TRACEPKT2: length 77.3
  TOP w0.193: J28.3 v2(56.32,24.13) 56.32,24.56 56.83,25.06 56.83,26.4 56.36,26.86 56.36,31.41 54.75,33.02 J27.26
  L03_SIG1 w0.155: v2(56.32,24.13) 56.26,24.2 53.85,24.2 53.61,24.43 53.61,26.41 53.85,26.64 60.58,26.64 63.34,29.4 63.34,31.9 67.83,36.39 67.83,40.28 70,42.45 70,43.62 70.36,43.98 70.36,51.96 68.81,53.51 68.81,62.28 68.81,65.49 v2(68.64,65.66)
  BOTTOM w0.193: R639.2 v2(68.64,65.66) 68.68,65.63 69.85,65.63 70.1,65.38 70.53,65.38 70.92,64.98 71.82,64.98 72.2,65.35 72.2,65.38 73.05,65.38 73.09,65.42 RN505.11
TRACEPKT2R: length 14.1
  TOP w0.193: U11.E6 v1(84.66,68.2)
  BOTTOM w0.102: 78.99,64.03 79.49,64.03 80.05,64.59 82,64.59 82.27,64.86 82.27,65.36 82.5,65.59 83.17,65.59 83.27,65.69 83.27,66.39 83.59,66.72 83.99,66.72 84.27,66.99 84.27,67.36 84.66,67.76 v1(84.66,68.2)
  BOTTOM w0.193: RN505.6 76.29,65.42 77,64.7 77,64.01 77.65,63.36 78.32,63.36 78.99,64.03
TRACEPKT3: length 78.9
  TOP w0.193: J27.24 54.87,33.66 56.77,31.75 56.77,28.14 58.24,26.67 J28.4 61.91,25.56 v2(61.75,25.39)
  L03_SIG1 w0.155: v2(61.75,25.39) 61.73,25.39 60.95,24.62 60.95,24.05 61.33,23.68 61.78,23.68 62.85,24.75 62.85,26.66 64.26,28.07 64.26,31.62 68.67,36.03 68.67,39.24 70.95,41.53 70.95,43.08 71.33,43.46 71.33,52.17 69.67,53.83 69.67,63.65 70.2,64.18 71.41,64.18 71.58,64.35 71.58,64.84 71.41,65.01 70.33,65.01 70.14,65.2 70.14,65.55 70.32,65.72 71.37,65.72 71.61,65.97 71.61,66.44 71.31,66.74 69.89,66.74 v2(69.66,66.51)
  BOTTOM w0.193: R638.2 69.62,66.55 v2(69.66,66.51) 69.66,66.55 70.31,65.9 72.83,65.9 72.85,65.92 RN505.12
TRACEPKT3R: length 12.2
  TOP w0.193: U11.D5 v1(83.66,67.2)
  L03_SIG1 w0.102: v1(83.66,67.2) 83.26,67.6 81.48,67.6 81.22,67.35 81.22,66.97 80.97,66.71 79.94,66.71 79.69,66.47
  L03_SIG1 w0.155: v2(78.45,64.68) 78.2,64.68 78.05,64.83 78.05,65.98 78.2,66.13 79.36,66.13 79.69,66.47
  BOTTOM w0.193: v2(78.45,64.68) 77.72,64.68 76.48,65.92 RN505.5
TRACEPKT4: length 78
  TOP w0.193: v2(61.09,29.21) J28.5 57.86,29.21 57.22,29.85 57.22,32.09 55.01,34.29 J27.22
  L03_SIG1 w0.155: v2(61.09,29.21) 59.62,27.75 54.92,27.75 54.77,27.59 54.77,27.2 54.89,27.07 60.14,27.07 62.85,29.78 62.85,33.3 63.52,33.98 64.72,33.98 67.45,36.71 67.45,40.56 68.38,41.48 68.38,42.84 69.81,44.27 69.81,51.98 68.38,53.41 68.38,59.18 68.38,64.92 67.97,65.33 67.97,66.77 v2(68.64,67.44)
  BOTTOM w0.193: R637.2 v2(68.64,67.44) 68.65,67.44 69.76,67.44 70.03,67.18 70.19,67.18 70.59,66.78 70.75,66.78 70.81,66.72 71.72,66.72 71.78,66.78 72.04,66.78 72.4,66.42 RN505.13
TRACEPKT4R: length 13.5
  TOP w0.193: U11.E7 v1(84.66,69.2)
  BOTTOM w0.102: v1(84.66,69.2) 84.38,68.92 84.38,68.79 84.07,68.48 84.07,67.86 83.84,67.63 83.55,67.63 83.51,67.59 83.5,67.59 83.27,67.36 83.27,66.68 83.07,66.48 83.07,65.99 82.87,65.8 82.42,65.8 82.06,65.44 82.06,65.04 81.83,64.81 79.75,64.81 79.18,65.37 78.99,65.37
  BOTTOM w0.193: 78.99,65.37 77.7,65.37 76.66,66.42 RN505.4
TRACEPKT5: length 78.1
  TOP w0.193: J27.20 55.36,34.93 58.98,31.31 v2(59.44,31.31) 59.88,31.75 J28.6
  L03_SIG1 w0.155: v2(59.44,31.31) 57.45,29.32 56.8,29.32 56.06,30.06 56.06,30.43 56.34,30.71 56.71,30.71 57.03,30.4 57.37,30.4 57.56,30.58 57.56,30.97 57.22,31.31 57.22,31.62 57.5,31.9 57.96,31.9 58.26,31.6 58.55,31.6 58.81,31.86 58.81,32.15 58.46,32.5 58.46,32.86 61.28,35.68 61.28,37.02 61.46,37.2 61.94,37.2 62.13,37.02 62.13,34.95 62.32,34.76 62.72,34.76 62.95,34.98 62.95,35.74 63.19,35.99 63.62,35.99 63.82,35.79 63.82,35.35 64,35.16 64.35,35.16 64.52,35.33 64.52,35.77 64.74,35.99 65.65,35.99 66.69,37.02 66.69,41.22 67.52,42.04 67.52,44.48 68.86,45.82 68.86,51.76 67.52,53.1 67.52,59.54 67.52,63.97 66.89,64.59 66.89,65.68 67.06,65.84 67.06,67.38 68.14,68.47 69.65,68.47 v2(70.29,67.82)
  BOTTOM w0.193: v2(70.29,67.82) 70.69,67.42 70.8,67.42 71.01,67.21 71.52,67.21 71.67,67.36 72.37,67.36 72.81,66.92 RN505.14
TRACEPKT5R: length 12.4
  TOP w0.193: U11.C4 v1(82.66,66.2)
  L03_SIG1 w0.102: v1(82.66,66.2) 82.15,66.71 81.48,66.71 81.09,66.33 81.09,65.95 80.74,65.59 80.5,65.59 80.27,65.36 80.27,65.03 78.99,63.76
  L03_SIG1 w0.155: 78.99,63.76 78.87,63.63 77.84,63.63 77.01,64.46 v2(77.01,66.92)
  BOTTOM w0.193: RN505.3 v2(77.01,66.92)
TRACEPKT6: length 77.9
  TOP w0.193: J27.18 56.54,35.56 57.81,34.29 J28.7 v2(61.59,34.29)
  L03_SIG1 w0.155: v2(61.59,34.29) 60.96,34.29 60.07,33.4 60.07,30.87 58.12,28.92 55.35,28.92 55.18,28.74 55.18,28.37 55.33,28.21 58.4,28.21 61.91,31.73 61.91,32.1 61.68,32.34 61.16,32.34 60.95,32.54 60.95,33.05 61.2,33.3 62.12,33.3 63.33,34.5 64.69,34.5 67.07,36.89 67.07,40.9 67.95,41.78 67.95,44.37 69.29,45.72 69.29,51.92 67.95,53.27 67.95,59.36 67.95,64.48 67.46,64.96 67.46,65.63 67.49,65.66 67.49,67.2 68.32,68.03 69.16,68.03 70,67.19 70.63,67.19 v2(71.26,67.82)
  BOTTOM w0.193: RN505.15 73.05,67.42 72.65,67.82 v2(71.26,67.82)
TRACEPKT6R: length 10.4
  TOP w0.193: U11.B4 v1(81.66,66.2)
  BOTTOM w0.102: 79.69,66.28 80,65.97 80,65.55 80.14,65.41 80.3,65.41 80.48,65.59 81.92,65.59 82.22,65.89 82.22,66.03 82.05,66.2 v1(81.66,66.2)
  BOTTOM w0.193: RN505.2 76.6,67.42 76.92,67.73 77.33,67.73 77.65,67.41 77.65,67.12 77.98,66.8 77.98,66.19 78.28,65.89 79.11,65.89 79.49,66.28 79.69,66.28
TRACEPKT7: length 76.8
  TOP w0.193: J27.16 55.12,36.2 55.76,36.83 J28.8 64.45,36.83 v2(64.52,36.77)
  L03_SIG1 w0.155: v2(64.52,36.77) 65.61,36.77 66.32,37.48 66.32,41.48 67.08,42.24 67.08,51.11 67.26,51.28 67.56,51.28 67.75,51.09 67.75,46.03 67.99,45.79 68.23,45.79 68.46,46.02 68.46,51.39 67.08,52.76 67.08,59.71 67.08,63.78 66.38,64.48 66.38,65.78 66.62,66.02 66.62,67.56 67.13,68.06 67.13,68.41 67.54,68.82 69.35,68.82 69.54,69.01 69.54,69.66 69.72,69.84 70.16,69.84 70.33,69.67 70.33,69.2 70.5,69.02 v2(70.71,69.02)
  BOTTOM w0.193: v2(70.71,69.02) 70.5,69.23 68.27,69.23 67.38,70.13 67.04,70.13 66.68,69.76 66.68,69.51 67.76,68.43 72.94,68.43 73.45,67.92 RN505.16
TRACEPKT7R: length 12.5
  TOP w0.193: U11.E8 v1(84.66,70.2)
  L03_SIG1 w0.155: v2(77.51,68.53) 77.37,68.67 77.37,69.32 77.33,69.37 77.33,70.03 77.91,70.62 78.98,70.62 79.88,69.71 84.17,69.71 v1(84.66,70.2)
  BOTTOM w0.193: RN505.1 76.35,67.92 76.96,68.53 v2(77.51,68.53)
TRACESYNC: length 76.8
  TOP w0.193: J27.32 54.01,31.12 v2(55.33,29.8)
  L03_SIG1 w0.155: v2(55.33,29.8) 55.33,30.54 60.7,35.91 60.7,37.18 61.25,37.74 62.26,37.74 62.95,38.43 62.95,49.96 63.13,50.14 63.46,50.14 63.64,49.97 63.64,41.53 63.79,41.38 64.2,41.38 64.33,41.51 64.33,52.88 64.9,53.46 65.33,53.46 65.71,53.84 65.71,60.28 65.71,61.54 64.92,62.33 64.92,62.51 64.34,63.09 64.34,63.94 64.33,63.94 63.83,64.45 63.83,65.95 64.08,66.2 64.08,66.34 65.05,67.31 65.05,67.31 65.05,68.86 67.06,70.86 v2(68.19,70.86)
  BOTTOM w0.193: v2(68.19,70.86) 68.72,70.86 68.86,71 69.39,71 69.52,70.86 70.06,70.86 70.06,70.86 RN504.13
TRACESYNCR: length 10.4
  TOP w0.193: U11.A5 v1(80.66,67.2)
  L03_SIG1 w0.155: v1(80.66,67.2) 78.71,67.2 78.13,67.78 78.13,68.65 78.3,68.83 79.15,68.83 79.37,69.05 79.37,69.42 79.1,69.69 v2(78.61,69.69)
  BOTTOM w0.193: v2(78.61,69.69) 78.11,70.19 77.63,70.19 76.96,70.86 RN504.4
TRSTZ: length 111.9
  TOP w0.193: U11.M23 v1(91.66,86.2) ; J27.21 v2(44.08,34.29)
  L03_SIG1 w0.102: 79.69,78.24 80.05,78.6 85.91,78.6 87.4,80.09 87.4,82.52 88.45,83.56 88.93,83.56 89.17,83.81 89.83,83.81 90.06,84.04 90.06,84.36 89.83,84.59 89.6,84.59 89.27,84.92 89.27,85.37 89.67,85.78 90.93,85.78 91.36,86.2 v1(91.66,86.2)
  L03_SIG1 w0.155: v2(71.88,35.36) 71.88,37.37 76.55,42.05 76.55,51.11 78.27,52.82 78.27,59.24 76.02,61.49 76.02,62.9 74.61,64.31 74.61,67.3 75.46,68.15 75.46,68.65 73.95,70.16 73.95,73.37 74.38,73.81 75.26,73.81 76.37,74.92 78.21,76.76 79.69,78.24
  L05_SIG2 w0.155: v2(71.88,35.36) 71.53,35.01 61.06,35.01 58.85,32.8 52.86,32.8 51.18,31.12 47.25,31.12 v2(44.08,34.29)
  BOTTOM w0.193: R723.1 44.09,26.99 U514.4 v2(44.08,34.29)
TRSTZ_IN: length 21.2
  TOP w0.193: v2(37.55,16.72) 37.41,16.58 J42.1
  BOTTOM w0.193: J23.3 R717.1 38.85,26.54 39.57,25.82 R724.2 39.59,25.1 U514.1 41.64,22.29 38.23,18.87 38.23,17.4 v2(37.55,16.72)
UART0_CTSZ: length 78.5
  TOP w0.193: v2(140.02,87.19) 138.55,88.66 133.93,88.66 133.13,87.86 131.36,87.86 131.07,87.57 U9.2 ; v2(190.46,100.27) 189.41,101.32 U6.12
  L05_SIG2 w0.155: v2(190.46,100.27) 191.95,100.27 192.93,101.25 192.93,101.94 191.76,103.11 186.21,103.11 183.66,100.56 176.52,100.56 164.09,88.13 148.04,88.13 147.11,87.19 v2(140.02,87.19)
UART0_CTSZ_BUF: length 69.8
  TOP w0.193: U11.AE2 v1(105.66,64.2) ; U9.6 130.42,82.88 130.26,83.04 v2(129.64,83.04)
  L03_SIG1 w0.155: v2(127.06,59.91) 127.12,59.91 127.44,60.23 127.44,68.14 126.8,68.78 126.8,74.59 130.06,77.86 130.06,82.53 129.66,82.94 129.66,83.01 v2(129.64,83.04)
  L05_SIG2 w0.102: 107.63,64.03 106.97,64.69 106.16,64.69 v1(105.66,64.2)
  L05_SIG2 w0.155: v2(127.06,59.91) 126.93,60.04 125.25,60.04 122.19,56.98 122.19,52.96 120.27,51.03 109.11,51.03 107.15,52.99 107.15,55.58 109.16,57.59 109.16,62.57 107.7,64.03 107.63,64.03
UART0_CTSZ_CON: length 15.9
  TOP w0.193: U6.13 190.06,101.87 v2(190.54,101.39) ; v2(194.33,107.69) 197.74,107.69 J7.7
  BOTTOM w0.193: v2(190.54,101.39) 190.54,101.35 191.24,100.66 192.3,100.66 195.05,103.4 195.05,106.98 v2(194.33,107.69)
UART0_DCD_CON: length 3.8
  TOP w0.193: R18.1 194.25,111.84 J7.1
UART0_DSR_CON: length 10.1
  TOP w0.193: v2(194.06,109.79) R18.2 194.21,110.45 J7.6 ; R19.2 v2(194.06,105.21)
  L03_SIG1 w0.155: v2(194.06,105.21) 193.67,105.59 193.67,108.21 194.06,108.59 v2(194.06,109.79)
UART0_DTR_CON: length 3.7
  TOP w0.193: J7.4 194.09,103.53 R19.1
UART0_RSTZ_CON: length 10.8
  TOP w0.193: U6.14 190.71,103.85 190.38,104.18 190.38,104.18 190.18,104.38 190.18,105.21 190.67,105.71 192.8,105.71 193.26,106.17 194,106.17 195.25,104.91 J7.8
UART0_RTSZ: length 77.9
  TOP w0.193: v2(133.92,83.12) 134.22,82.83 U10.5 ; U11.AD2 v1(104.66,64.2)
  L03_SIG1 w0.155: v2(133.92,83.12) 133.74,82.94 130.86,82.94 130.03,83.77 129.4,83.77 128.81,83.18 128.81,82.39 129.53,81.67 129.53,77.83 126.32,74.62 126.32,68.55 127.1,67.78 127.1,61.87 126.47,61.24 126.47,59.24 v2(126.99,58.72)
  L05_SIG2 w0.102: v1(104.66,64.2) 104.66,64.19 105.15,63.7 107.53,63.7 107.63,63.6
  L05_SIG2 w0.155: 107.63,63.6 108.81,62.42 108.81,57.74 106.8,55.73 106.8,52.72 108.92,50.6 120.39,50.6 122.71,52.92 122.71,56.88 125.39,59.57 126.14,59.57 v2(126.99,58.72)
UART0_RTSZ_BUF: length 92.4
  TOP w0.193: U6.11 188.76,101.62 187.24,100.1 v2(186.05,100.1) ; U10.3 v2(134.87,84.57)
  L03_SIG1 w0.155: v2(186.05,100.1) 186.05,96.59 184.73,95.28 184.73,90.35 176.86,82.47 176.86,79.41 177.48,78.79 v2(177.48,74.04)
  L05_SIG2 w0.155: v2(134.87,84.57) 136.88,84.57 138.84,82.61 138.84,80.12 139.76,79.21 145.09,79.21 147.57,81.69 158.18,81.69 160.07,79.79 171.73,79.79 v2(177.48,74.04)
  BOTTOM w0.193: R534.2 188.8,102.3 188.8,102.21 188.76,102.17 188.76,101.62 187.24,100.1 v2(186.05,100.1) ; R591.1 v2(177.48,74.04)
UART0_RXD: length 112.6
  TOP w0.193: v2(187.08,104.44) 187.08,104.41 187.46,104.03 U6.9 ; U9.5 v2(128.8,81.56)
  L03_SIG1 w0.155: v2(192.24,72.33) 192.24,73.12 191.19,74.17 191.19,77.04 191.69,77.54 191.69,85.91 189.56,88.04 189.56,92.05 190.2,92.68 190.2,95.66 189.36,96.49 189.36,102.16 v2(187.08,104.44)
  L05_SIG2 w0.155: v2(192.24,72.33) 192.24,72.8 193.64,74.2 193.64,75.25 191.97,76.92 185.22,76.92 181.33,73.03 170.38,73.03 165.49,77.93 132.43,77.93 v2(128.8,81.56)
  BOTTOM w0.193: v2(192.24,72.33) 192.05,72.14 R589.1
UART0_RXD_BUF: length 73.4
  TOP w0.193: v2(129.98,87.57) 130.42,87.13 U9.3 ; U11.AD1 v1(104.66,63.2)
  L03_SIG1 w0.155: v2(125.74,58.65) 125.74,58.67 125.48,58.92 125.48,65.09 124.81,65.76 124.81,67.36 124.8,67.37 124.8,67.95 125.6,68.75 125.6,74.91 126.99,76.3 126.99,82.53 128.16,83.7 128.16,86.25 129.47,87.57 v2(129.98,87.57)
  L05_SIG2 w0.102: 107.46,62.41 107.06,62.81 106.83,62.81 105.5,62.81 105.11,63.2 v1(104.66,63.2)
  L05_SIG2 w0.155: v2(125.74,58.65) 125.77,58.65 125.77,58.62 125.76,58.62 123.14,56 123.14,52.81 120.52,50.19 108.75,50.19 106.44,52.5 106.44,55.88 107.46,56.89 107.46,62.41
UART0_RXD_CON: length 12.7
  TOP w0.193: U6.8 187.46,107.85 188.03,107.28 188.03,107.01 188.71,106.33 188.98,106.33 189.01,106.3 192.5,106.3 193,106.79 194.66,106.79 195.15,106.3 J7.3
UART0_TXD: length 80.3
  TOP w0.193: U10.2 v2(135.52,87.56) ; U11.AB3 v1(102.66,65.2)
  L03_SIG1 w0.155: v2(126.08,61.7) 126.66,62.29 126.66,67.6 125.96,68.3 125.96,74.77 128.89,77.7 128.89,80.15 128.05,80.99 128.05,82.92 132.69,87.56 v2(135.52,87.56)
  L05_SIG2 w0.102: 107.63,65.1 107.02,65.71 103.17,65.71 v1(102.66,65.2)
  L05_SIG2 w0.155: v2(126.08,61.7) 121.76,57.38 121.76,53.14 120.09,51.46 109.22,51.46 107.51,53.17 107.51,54.33 108.07,54.88 108.36,54.88 109.67,56.19 109.67,63.06 107.63,65.1
UART0_TXD_BUF: length 67.8
  TOP w0.193: U10.6 134.87,80.54 135.33,80.08 139.06,80.08 v2(139.46,80.48) ; v2(187.77,101.54) 188.11,101.88 U6.10
  L05_SIG2 w0.155: v2(139.46,80.48) 139.97,79.96 144.23,79.96 150.97,86.7 162.38,86.7 163.1,85.97 171.17,85.97 180.31,95.12 182.72,95.12 187.77,100.17 v2(187.77,101.54)
  BOTTOM w0.193: v2(187.77,101.54) 187.77,102.16 R535.1
UART0_TXD_CON: length 12.2
  TOP w0.193: U6.7 188.11,108.04 188.55,107.6 188.55,107.22 188.93,106.85 189.46,106.85 189.51,106.9 192.24,106.9 194.41,109.07 J7.2
UART1_CTSZ: length 118.1
  TOP w0.193: v2(140.35,71.73) 140.24,71.62 138.07,71.62 v2(137.8,71.88) ; v2(188.21,65.41) 188.21,66.22 189.79,67.8 U12.12 ; U11.E18 v1(84.66,81.2)
  L05_SIG2 w0.102: 107.63,72.7 107.52,72.81 99.82,72.81 98.43,74.2 98.34,74.2 96.75,75.78 89.86,75.78 86.89,78.75 86.89,79.65 86.04,80.5 85.92,80.5 85.83,80.59 85.4,80.59 84.8,81.2 v1(84.66,81.2)
  L05_SIG2 w0.155: v2(188.21,65.41) 187.7,65.41 187.67,65.43 178.46,65.43 173.03,70.85 161.18,70.85 159.87,72.16 154.23,72.16 153.62,71.56 148.62,71.56 148.47,71.72 147.14,71.72 145.91,71.71 145.76,71.56 140.52,71.56 v2(140.35,71.73) ; v2(137.8,71.88) 137.77,71.85 132.78,71.85 132.55,71.62 118.08,71.62 117.22,72.48 107.85,72.48 107.63,72.7
UART1_CTSZ_CON: length 10
  TOP w0.193: U12.13 190.44,71.88 191.79,73.23 192.56,73.23 194.5,75.17 J16.7
UART1_DCD_CON: length 4.3
  TOP w0.193: R29.1 193.72,79.33 J16.1
UART1_DSR_CON: length 13
  TOP w0.193: J16.6 194.65,77.94 v2(194.31,78.28) 194.11,78.09 R29.2 ; v2(194.29,71.71) 194.29,71.78 194.05,72.02 R30.2
  L03_SIG1 w0.155: v2(194.29,71.71) 195.55,72.98 195.55,77.04 v2(194.31,78.28)
UART1_DTR_CON: length 4.2
  TOP w0.193: R30.1 197.71,70.98 J16.4
UART1_RSTZ_CON: length 8.2
  TOP w0.193: J16.8 194.47,72.4 194.28,72.59 193.12,72.59 192.91,72.38 192.91,72.01 192.57,71.68 191.43,71.68 191.09,71.34 U12.14
UART1_RTSZ: length 152.7
  TOP w0.193: v2(141.59,72.16) 140.92,72.16 140.56,72.52 136.73,72.52 v2(136.68,72.47) ; v2(53.98,86.08) 56.39,83.67 64.42,83.67 65.03,84.27 65.69,84.27 66.58,83.38 70.14,83.38 73.41,80.11 75.72,80.11 77.81,82.2 v1(80.66,82.2) U11.A19 ; U12.11 189.14,69.01 v2(188.98,68.85)
  L05_SIG2 w0.102: v1(80.66,82.2) 81.11,82.2 81.5,81.81 82.02,81.81 82.23,81.59 82.83,81.59 83.06,81.36 83.06,80.73 83.19,80.59 84.1,80.59 84.27,80.76 84.27,81.36 84.5,81.59 84.83,81.59 85.27,81.15 85.27,81.04 85.51,80.8 86.03,80.8 87.09,79.73 87.09,79.19 87.46,78.82 87.46,78.58 90,76.04 96.78,76.04 98.42,74.4 98.55,74.4 99.36,73.59 106.83,73.59 107.27,73.15 107.63,73.15
  L05_SIG2 w0.155: 107.63,73.15 107.91,73.15 108.16,72.9 117.7,72.9 118.47,72.13 130.99,72.13 131.33,72.47 v2(136.68,72.47) ; v2(141.59,72.16) 141.62,72.13 153.58,72.13 154.13,72.68 159.96,72.68 161.2,71.44 173.4,71.44 177.02,67.82 187.95,67.82 v2(188.98,68.85)
  BOTTOM w0.193: R573.2 52.98,87.07 v2(53.98,86.08)
UART1_RXD: length 240
  TOP w0.193: v2(114.99,110.07) 114.99,111.23 115.1,111.34 115.1,111.85 114.99,111.96 114.99,112.12 114.88,112.23 114.88,112.73 114.99,112.84 J2.92 ; U11.D19 v1(83.66,82.2) ; v2(136.63,73.7) 136.84,73.91 141.79,73.91 v2(141.83,73.86) ; U12.9 186.55,70.57 v2(185.82,69.84)
  L03_SIG1 w0.155: v2(185.82,69.84) 184.73,70.94 184.73,75.89 185.72,76.88 185.72,86.92 187.25,88.44 187.25,94.95 188.37,96.06 188.37,101.78 186.08,104.07 186.08,105.05 186.95,105.92 187.62,105.92 v2(189.19,107.49) ; v2(134.76,108.69) 134.54,108.91 v2(128.88,108.91)
  L05_SIG2 w0.102: v1(83.66,82.2) 84.11,82.2 84.5,82.59 84.83,82.59 85.06,82.36 85.06,82 85.26,81.8 85.91,81.8 87.87,79.84 87.87,78.85 90.17,76.55 96.85,76.55 98.59,74.81 99.02,74.81 99.23,74.59 106.88,74.59 107.45,74.03
  L05_SIG2 w0.155: v2(185.82,69.84) 185.12,69.14 180.3,69.14 177.14,72.31 162.11,72.31 160.73,73.68 153.91,73.68 153.29,73.06 143.69,73.06 142.89,73.86 v2(141.83,73.86) ; v2(134.76,108.69) 135.83,108.69 139.88,104.65 155.21,104.65 156.24,103.62 166.49,103.62 166.8,103.31 172.03,103.31 173.03,104.31 177.64,108.93 187.75,108.93 v2(189.19,107.49) ; v2(136.63,73.7) 136.48,73.55 130.79,73.55 130.25,73.01 119.56,73.01 118.93,73.65 108.48,73.65 108.1,74.03 107.45,74.03
  BOTTOM w0.193: v2(114.99,110.07) 115.89,110.07 116.99,108.97 126.15,108.97 126.84,108.28 128.18,108.28 128.73,108.83 128.8,108.83 v2(128.88,108.91)
UART1_RXD_CON: length 13.6
  TOP w0.193: v2(186.82,76.07) 187.24,76.49 U12.8 ; v2(194.33,73.84) 194.39,73.79 J16.3
  BOTTOM w0.193: v2(194.33,73.84) 194.29,73.88 194.29,74.82 193.62,75.5 187.39,75.5 v2(186.82,76.07)
UART1_TXD: length 254.3
  TOP w0.193: v2(142.26,80.65) 141.92,80.65 139.74,78.47 129.44,78.47 126.09,75.11 124.91,75.11 122.26,77.76 122.26,83.69 138.25,99.69 138.25,106.18 137.58,106.85 136.71,106.85 135.57,107.99 135.57,109.86 134.85,110.58 134.85,112.47 138.75,116.37 138.75,121.42 138.94,121.62 v2(138.99,121.62) ; U11.C19 v1(82.66,82.2) ; J2.53 100.49,120.98 100.55,121.05 100.55,121.93 100.49,122 v2(100.49,122.27) ; U12.10 188.36,70.44 188.36,69.67 188.16,69.47 187.53,69.47 187.15,69.85 v2(186.75,69.85) 186.75,68.91 R34.1 ; v2(140.87,73.1) 137.83,73.1 v2(137.67,73.27)
  L05_SIG2 w0.102: 107.63,73.6 107.33,73.6 107.12,73.8 99.57,73.8 98.77,74.6 98.51,74.6 96.8,76.31 90.12,76.31 87.66,78.77 87.66,79.55 86.23,80.98 86.23,81.18 86.06,81.35 86.06,81.36 85.83,81.59 85.11,81.59 84.91,81.8 84.42,81.8 84.21,81.59 83.27,81.59 v1(82.66,82.2)
  L05_SIG2 w0.155: v2(186.75,69.85) 185.15,68.25 177.73,68.25 174.11,71.87 161.46,71.87 160.16,73.17 154.01,73.17 153.45,72.61 143.34,72.61 142.84,73.1 v2(140.87,73.1) ; 107.63,73.6 107.97,73.6 108.27,73.29 118.15,73.29 118.83,72.61 130.67,72.61 131.17,73.1 137.51,73.1 v2(137.67,73.27)
  BOTTOM w0.193: v2(137.67,73.27) 137.67,73.46 142.28,78.07 142.28,80.64 v2(142.26,80.65) ; v2(138.99,121.62) 137.85,122.76 134.34,122.76 130.66,119.08 130.53,119.08 127.99,116.54 124.59,116.54 124.41,116.36 118.54,116.36 116.31,118.59 114.07,118.59 113.28,117.81 111.45,117.81 110.72,118.54 110.72,119.35 108.61,121.46 108.61,122.76 106.81,124.56 101.86,124.56 100.49,123.19 v2(100.49,122.27)
UART1_TXD_CON: length 10.9
  TOP w0.193: U12.7 188.49,75.45 188.72,75.23 192.54,75.23 193.87,76.56 J16.2
USB_DAT_N: length 14.7
  L05_SIG2 w0.105: J4.2 14.1,109.43 14.1,110.3 15.1,111.29 19.83,111.29 20.22,111.69 20.22,112.34 20.35,112.47 v2(21.25,112.47)
  BOTTOM w0.108: U502.6 21.25,113.34 v2(21.25,112.47) R518.1
USB_DAT_NS: length 158
  TOP w0.193: U11.C5 v1(82.66,67.2)
  L05_SIG2 w0.102: v1(82.66,67.2) 82.99,67.2 83.11,67.32 83.11,67.47 82.98,67.6 81.51,67.6 81.27,67.36 81.27,65.96 80.91,65.6 80.15,65.6 79.82,65.27 79.82,64.68 78.8,63.66 78.76,63.66
  L05_SIG2 w0.105: v2(23.3,118.61) 23.31,118.61 23.67,118.25 23.67,112.03 16,104.37 9.33,104.37 8.02,103.06 8.02,87.18 9.55,85.65 9.55,70.76 15.05,65.26 24.57,65.26 32.75,57.07 45.27,57.07 46.57,55.77 57.29,55.77 58.37,54.69 61.66,54.69 65.22,58.25 72.96,58.25 76.16,61.46 76.16,62.2 77.62,63.66 78.76,63.66
  BOTTOM w0.108: v2(23.3,118.61) 22.88,119.03 19.6,119.03 19.39,118.82 19.39,118.21 19.62,118.11 DN504.1 20.61,118.11 21.83,116.89 R518.2
USB_DAT_P: length 17.2
  L05_SIG2 w0.105: v2(18.88,112.47) 19.86,112.47 19.97,112.37 19.97,111.79 19.72,111.55 14.99,111.55 13.85,110.4 13.85,109.4 J4.3
  BOTTOM w0.108: v2(18.88,112.47) 18.88,113.34 U502.1 ; v2(18.88,112.47) R519.1 ; v2(18.88,112.47) 18.88,111.86 18.27,111.26 R531.1
USB_DAT_PS: length 158
  TOP w0.193: U11.D6 v1(83.66,68.2)
  L05_SIG2 w0.102: v1(83.66,68.2) 83.27,67.81 81.42,67.81 81.07,67.45 81.07,66.07 81.06,66.06 81.06,66.04 80.83,65.81 80.07,65.81 79.61,65.35 79.61,64.76 78.76,63.91 78.76,63.91
  L05_SIG2 w0.105: 78.76,63.91 77.51,63.91 75.91,62.31 75.91,61.56 72.85,58.5 65.11,58.5 61.55,54.95 58.47,54.95 57.4,56.02 46.68,56.02 45.37,57.33 32.86,57.33 24.67,65.51 15.16,65.51 9.8,70.87 9.8,85.76 8.27,87.29 8.27,102.95 9.43,104.11 16.11,104.11 23.92,111.93 23.92,116.93 24.05,117.06 24.27,117.06 24.37,117.16 24.37,117.36 24.25,117.48 24.05,117.48 23.92,117.61 23.92,118.23 v2(24.3,118.61)
  BOTTOM w0.108: v2(24.3,118.61) 23.65,119.25 19.5,119.25 19.23,118.98 18.28,118.98 DN504.2 17.95,119.05 15.79,116.89 R519.2
USB_ENZ: length 102.1
  TOP w0.193: U11.E25 v1(84.66,88.2)
  L03_SIG1 w0.155: v2(12.76,92.79) 16.53,96.55 16.53,107.92 v2(17.35,108.74)
  L05_SIG2 w0.102: v1(84.66,88.2) 84.06,88.81 84.06,89.36 83.25,90.17 82.82,90.17
  L05_SIG2 w0.155: v2(12.76,92.79) 12.42,93.13 12.42,95.25 12.77,95.6 13.49,95.6 17.09,92 51.22,92 51.83,91.39 52.4,91.39 54.4,93.39 60.12,93.39 60.67,93.94 61.55,93.94 62.04,93.45 65.59,93.45 66.08,93.93 67.92,93.93 69.41,92.44 70.84,92.44 71.41,93.02 73.55,93.02 74.18,92.38 78.03,92.38 79.03,91.38 81.13,91.38 82.34,90.17 82.82,90.17
  BOTTOM w0.193: U503.1 19.45,108.72 R530.1 17.37,108.72 v2(17.35,108.74)
XTAL_IN: length 15.3
  TOP w0.193: U11.M26 v1(91.66,89.2)
  BOTTOM w0.193: X500.1 87.15,99.41 87.35,99.22 89.12,99.22 90.94,97.4 R557.2 C532.1 90.94,91.85 R556.1 91.11,91.63 91.11,90.45 91.66,89.9 v1(91.66,89.2)
XTAL_OUT: length 3.6
  TOP w0.193: U11.N26 v1(92.66,89.2)
  BOTTOM w0.193: R556.2 91.94,91.8 R555.2 91.94,90.71 92.66,89.98 v1(92.66,89.2)
N16773791: length 3.1
  TOP w0.193: R2.2 87.49,123.13 J2.1
N16781966: length 4.3
  TOP w0.193: J1.92 63.87,113.05 63.58,112.76 63.58,112.36 R9.2 63.91,111.9 63.96,111.86 64.49,111.86 64.53,111.9 R10.2
N16804199: length 2.4
  TOP w0.193: v2(177.77,39.94) 177.8,39.97 D11.2
  BOTTOM w0.193: v2(177.77,39.94) 177.77,38.79 R699.1
N16826457: length 8.7
  TOP w0.193: Q4.3 178.99,44.5 179.5,43.99 179.5,41.52 v2(179.45,41.47)
  BOTTOM w0.193: v2(179.45,41.47) 179.45,39.19 R699.2
N16826574: length 11.4
  TOP w0.193: Q4.2 v2(177.47,48.01) 177.44,47.98 175.17,47.98 174.07,46.88 173.93,46.88 v2(173.24,46.19) 172.89,46.55 172.89,46.75 172.48,47.17 Q3.3
  BOTTOM w0.193: R691.2 173.2,46.24 v2(173.24,46.19)
N16826732: length 61.1
  L03_SIG1 w0.155: v2(183.07,79.06) 178.81,74.8 178.81,70.71 178.08,69.99 178.08,68.2 182.36,63.92 182.36,51.15 175.61,44.4 175.61,33.13 171.56,29.09 v2(171.56,28.4)
  BOTTOM w0.193: v2(183.07,79.06) Q503.3 ; R711.1 v2(171.56,28.4)
N16826745: length 7.2
  TOP w0.193: v2(168.77,47.74) 168.77,48.36 168.32,48.81 168.32,49.34 169.35,50.37 171.05,50.37 Q3.2
  BOTTOM w0.193: R692.2 v2(168.77,47.74)
N16826772: length 12.7
  TOP w0.193: J17.1 187.28,60.62 v2(181.74,66.17)
  BOTTOM w0.193: R607.2 v2(181.74,66.17)
N16826808: length 13.3
  TOP w0.193: v2(173.6,29.21) 175.39,29.21 C36.2 ; v2(173.6,29.21) 173.6,33.47 174.41,34.29 R45.1 ; v2(173.6,29.21) 172.54,29.21 171.03,30.72 Q5.1
  BOTTOM w0.193: R711.2 v2(173.6,29.21)
N16827011: length 12
  BOTTOM w0.193: X500.2 96.49,99.42 92.32,95.25 C531.1 92.98,92.3 R555.1
N16827097: length 6.5
  BOTTOM w0.193: Q503.2 184.68,78.12 R574.2
N16827292: length 4
  TOP w0.193: U15.1 164.34,57.53 165.99,55.87 v2(165.99,55.87)
  BOTTOM w0.193: R650.1 165.99,55.87 v2(165.99,55.87)
N16827323: length 2.3
  TOP w0.193: U17.4 181.02,31.19 R46.2 R60.1
N16827429: length 6
  TOP w0.193: D9.1 176.05,40.37 176.05,37.97 175.63,37.56 v2(174.89,37.56)
  BOTTOM w0.193: R700.2 v2(174.89,37.56)
N16827460: length 1.8
  TOP w0.193: R47.2 186,32.21 U17.1
N16827499: length 10.7
  TOP w0.193: v2(174.22,41.55) 174.19,41.57 174.19,42.85 174.68,43.33 177.62,43.33 177.8,43.15 D11.1
  BOTTOM w0.193: v2(174.22,41.55) 172.84,40.17 172.31,40.17 171.4,39.25 R701.2
N16827743: length 7.2
  TOP w0.193: D10.1 188.09,28.17 188.72,28.8 188.72,32.37 R48.2
N16830133: length 17.8
  BOTTOM w0.193: v2(136.66,56.29) 134.04,56.29 R666.1 R667.1 ; v2(136.66,56.29) 137.13,56.75 U509.3 138.51,56.77 139.38,56.77 139.95,57.34 139.95,59.26 140.61,59.92 141.14,59.92 141.52,59.55 141.52,58.57 142.68,57.4 U509.11 ; v2(136.66,56.29) 136.69,56.26 136.69,55.68 136.91,55.45 U509.1
N16830205: length 34.9
  TOP w0.193: U15.30 153.86,61.08 v2(153.86,61.09)
  L05_SIG2 w0.155: v2(153.86,61.09) 153.82,61.05 v2(151.68,61.05) 151.2,60.58 149.22,60.58 148.46,59.81 148.46,58.82 147.93,58.3 143.19,58.3 141.41,60.07 140.8,60.07 137.77,57.05 v2(135.78,57.05)
  BOTTOM w0.193: C634.1 135.29,57.53 v2(135.78,57.05) 136.13,57.4 U509.4 ; v2(151.68,61.05) 151.21,60.58 150.16,60.58 v2(149.57,59.99) 149.96,59.6 149.96,58.78 149.6,58.42 149.6,58.33 149.58,58.31 149.58,58 R661.2 149.59,57.3 R660.1
N16830232: length 3
  BOTTOM w0.193: R611.1 150.06,62.2 150.67,61.59 150.88,61.59 v2(150.98,61.7)
  vias: v2(146.59,59.92) v2(148.29,61.58) v2(148.35,60.67) v2(149.22,61.21) v2(151.87,61.98)
N16830236: length 6.2
  TOP w0.193: D5.2 132.73,64.64 L6.2
N16830344: length 29.9
  L03_SIG1 w0.155: v2(146.94,59.05) 146.94,55.12 149.14,52.92 151.2,52.92 v2(151.21,52.91) 151.73,52.38 v2(151.73,47.75)
  BOTTOM w0.193: R659.2 151.39,53.1 v2(151.21,52.91) ; R662.2 146.89,59 v2(146.94,59.05) ; R702.2 147.24,44.5 C643.2 147.32,46.84 148.23,47.75 Q505.3 v2(151.73,47.75) 151.92,47.93 C642.2
N16830356: length 5
  BOTTOM w0.193: R616.1 135.37,65.43 136.51,64.29 U507.6
N16830372: length 2.7
  TOP w0.193: D5.1 R35.1
N16830397: length 4.9
  BOTTOM w0.193: R617.2 133.86,64.49 134.99,64.49 135.84,63.64 U507.5
N16830529: length 9.5
  BOTTOM w0.193: 137.05,61.69 135.12,61.69 ; 137.05,61.69 137.05,62.15 137.28,62.38 138.33,62.38 U507.3 ; 137.05,61.69 U507.2 ; 137.05,61.69 137.05,61.26 137.27,61.04 U507.1 ; 135.12,61.69 134.67,61.24 R615.1 ; 135.12,61.69 134.56,62.26 R614.1
N16830564: length 4.8
  BOTTOM w0.193: U509.6 136.79,58.7 136.16,59.33 134.29,59.33 R664.1
N16830576: length 38.1
  TOP w0.254: v2(150.84,59.68) 152.58,59.68 153.13,60.23 154.06,60.23 154.21,60.08 U15.32
  L05_SIG2 w0.155: v2(140.87,59.28) 142.48,57.67 148.83,57.67 149.69,58.53 149.69,59.21 150.15,59.68 v2(150.84,59.68) 150.84,59.45 150.3,58.91 150.3,57.91 149.53,57.14 149.53,52.68 150.89,51.32 v2(153.64,51.32)
  BOTTOM w0.193: U509.14 143.04,55.45 140.66,57.84 140.66,59.06 v2(140.87,59.28) ; R659.1 R652.2 v2(153.64,51.32) C642.1
N16830606: length 11.7
  TOP w0.193: U15.33 153.98,59.58 153.91,59.65 153.31,59.65 151.87,58.21 151.87,54.9 v2(150.76,53.8)
  BOTTOM w0.193: v2(150.76,53.8) 150.52,53.56 150.52,53.55 150.47,53.5 150.47,53.12 149.67,52.32 Q505.1
N16830689: length 1.8
  BOTTOM w0.193: R662.1 145.83,56.75 U509.12
N16830707: length 1.9
  BOTTOM w0.193: U509.13 145.62,56.1 R663.2
N16830891: length 4.7
  BOTTOM w0.193: U509.5 136.32,58.05 135.72,58.65 134.09,58.65 R665.2
N16832566: length 4.6
  TOP w0.508: R33.1 169.04,70.23 169.19,70.38 169.19,71.58 168.95,71.82 C26.2
N16836092: length 15.9
  TOP w0.193: J59.1 v2(142.22,1.91)
  BOTTOM w0.193: C669.2 142.22,4.02 v2(142.22,1.91)
  BOTTOM w1.27: R770.2 139.34,4.04 C669.2 R749.1 142.24,8.64 143.82,10.22 L505.1
N16836211: length 8.4
  TOP w0.193: VR2.2 TP62.1
  BOTTOM w0.193: U519.3 108.6,29.14 108.9,29.44 108.9,30.7 108.39,31.21 108.39,31.67 R751.2 109.11,31.37 TP62.1
N16862598: length 3.9
  TOP w0.193: v2(15.18,1.91) 15.18,1.96 15.87,2.64 J48.3
  BOTTOM w0.193: R776.2 15.88,2.48 15.3,1.91 v2(15.18,1.91) 14.99,2.1 R777.2
N16862628: length 2
  BOTTOM w0.193: R668.1 122.43,55.4 Q504.2
N16862652: length 1.7
  BOTTOM w0.193: U508.4 121.41,63.53 R622.2
N16862691: length 1.6
  BOTTOM w0.193: R778.2 13.34,5.31 U524.4
N16862716: length 5.6
  BOTTOM w0.193: R765.2 10.23,7.05 10.6,7.05 11.38,6.28 U524.5 ; C676.2 10.3,4.95 11.24,4.95 11.38,5.09 U524.5 ; U524.5 11.16,5.6 10.6,5.6 10.17,6.03 R766.2
N16862889: length 3.8
  BOTTOM w0.193: C612.2 R618.2 R620.2 123.44,63.53 U508.5
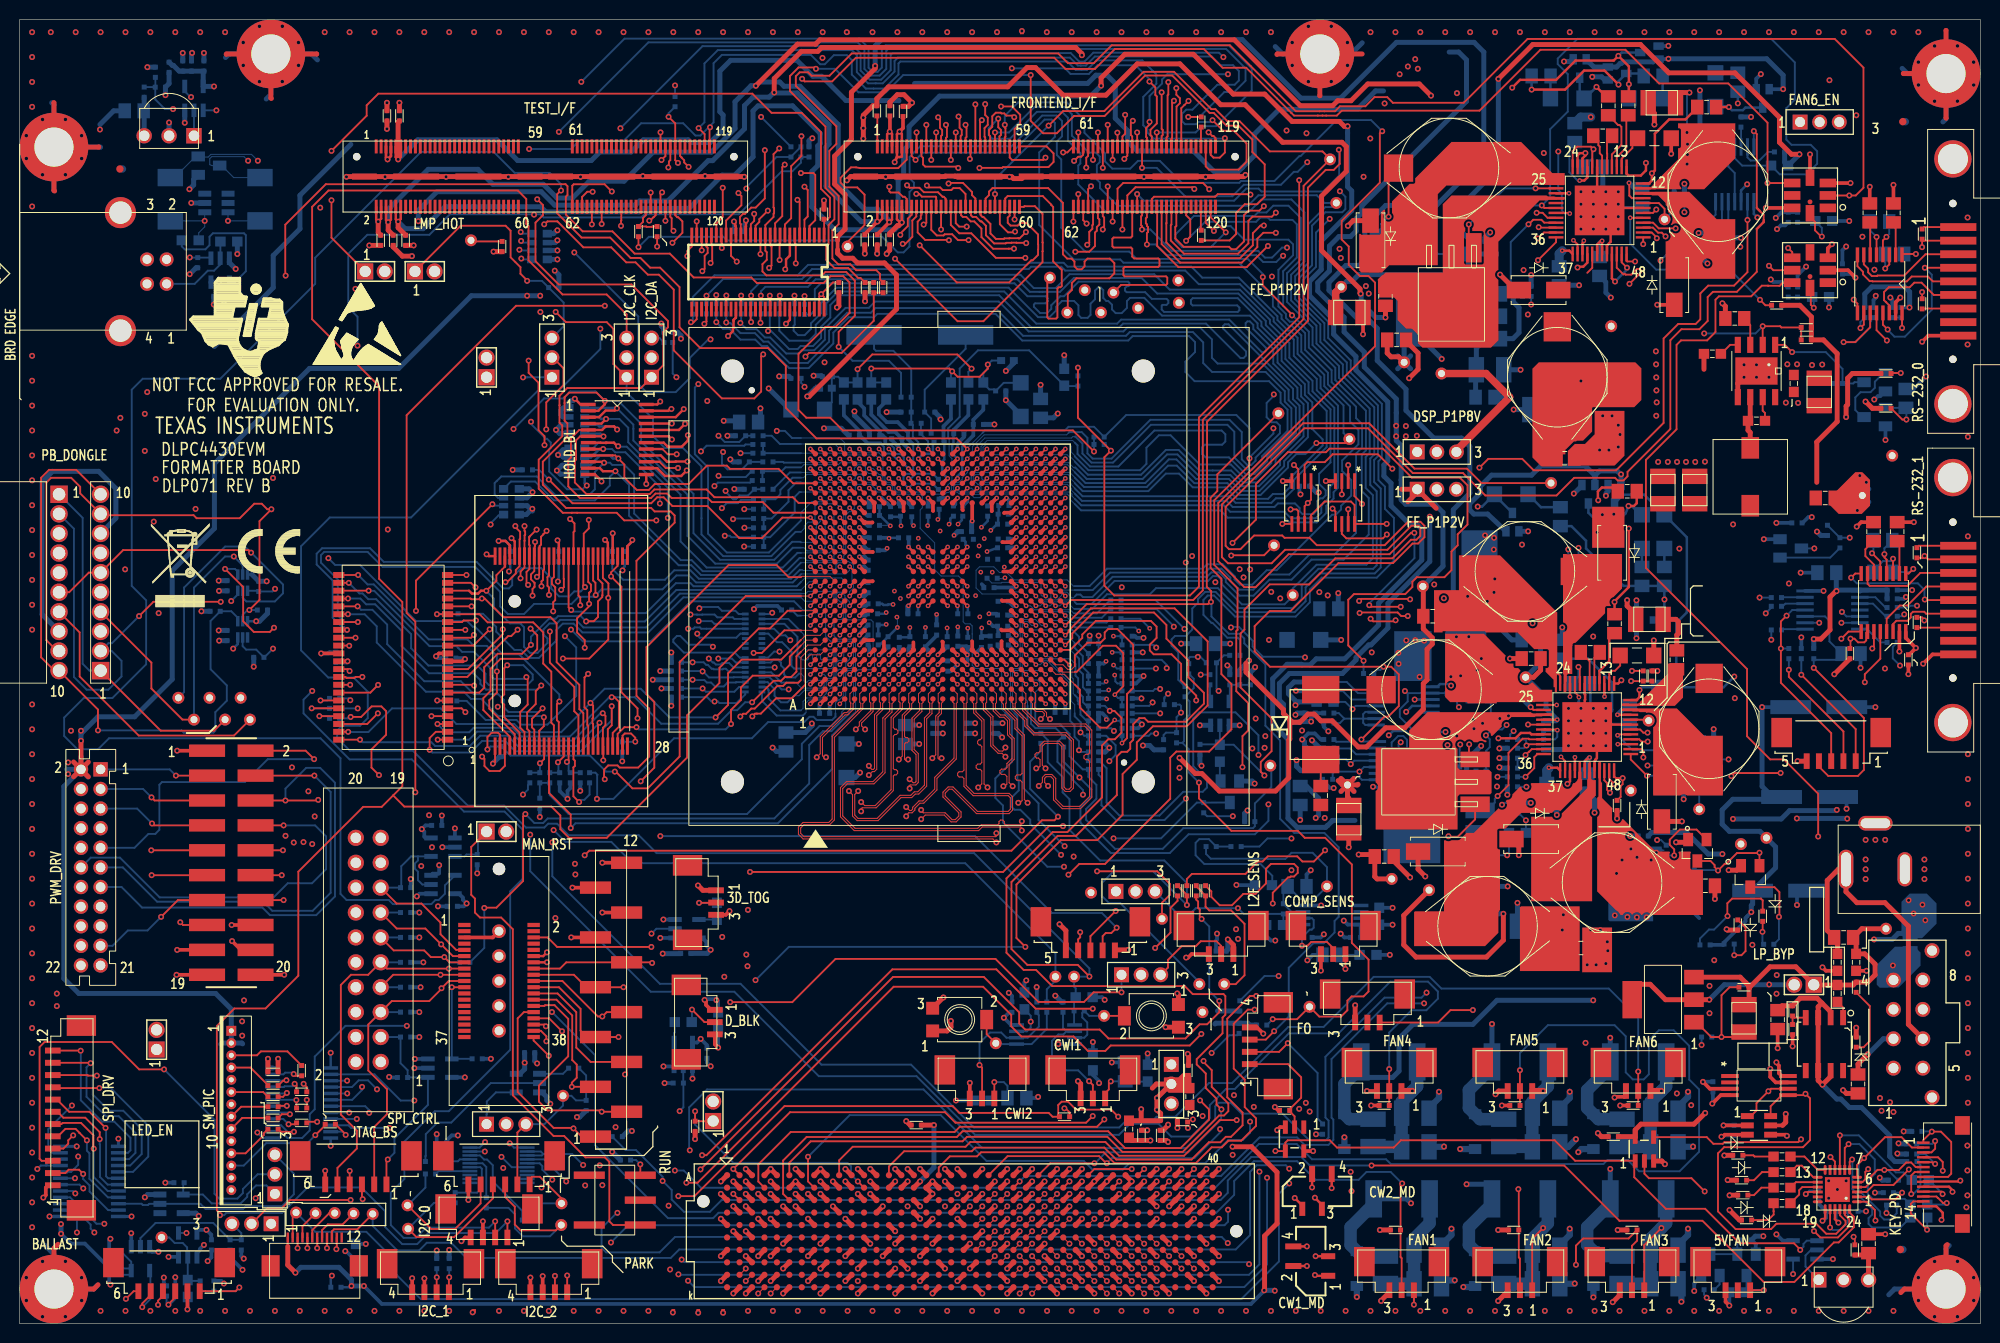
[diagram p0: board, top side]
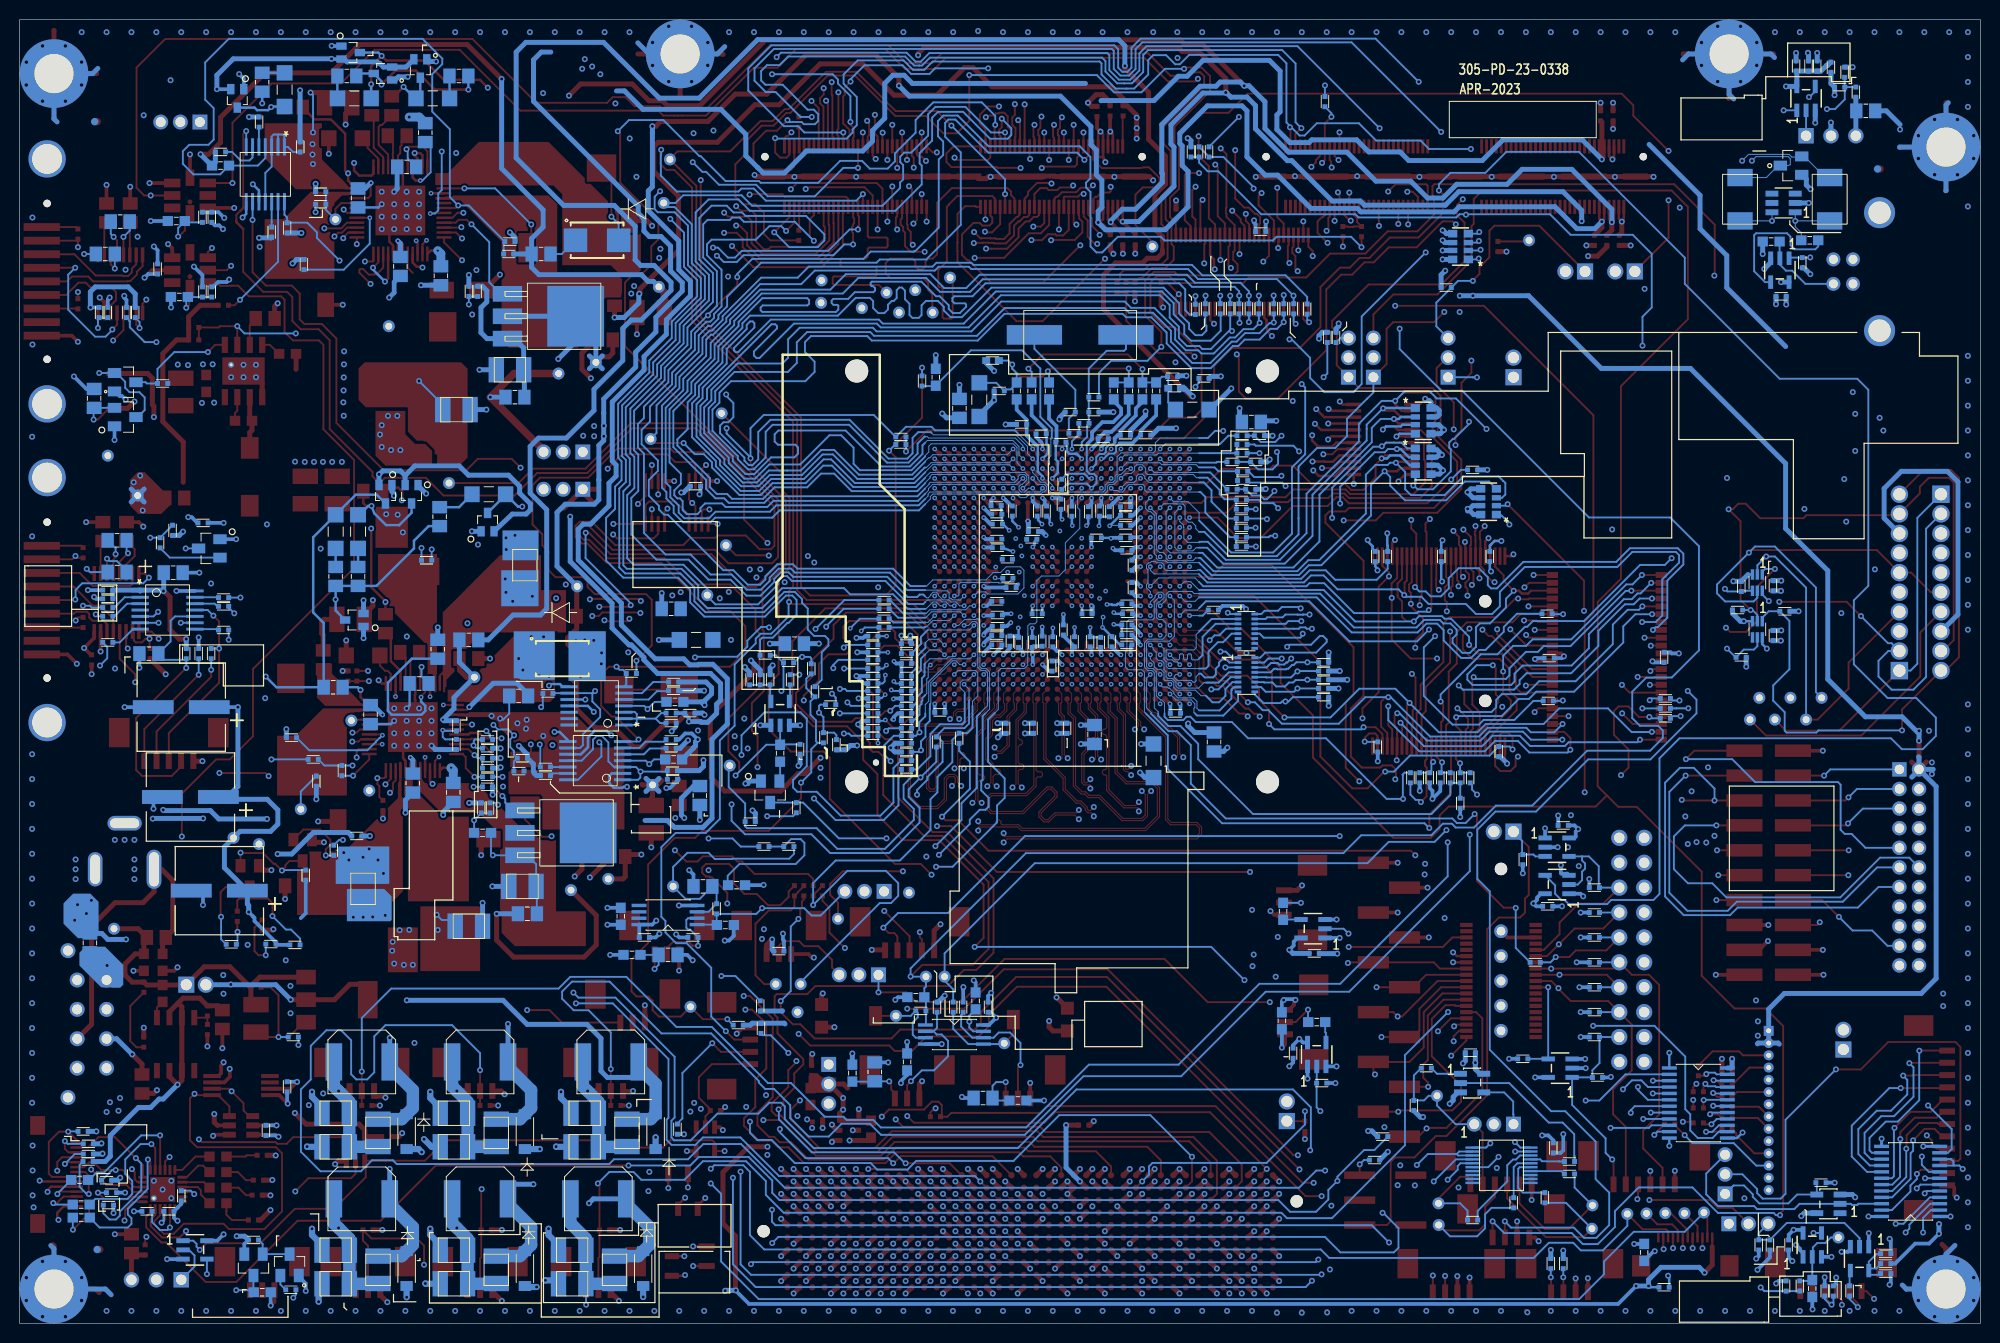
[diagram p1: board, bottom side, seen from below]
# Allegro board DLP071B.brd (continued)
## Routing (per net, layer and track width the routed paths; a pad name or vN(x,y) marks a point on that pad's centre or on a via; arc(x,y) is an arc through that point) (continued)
N16862891: length 122.9
  TOP w0.193: v2(106.43,50.72) 104.99,50.72 100.31,46.05 v2(74.5,46.05)
  L05_SIG2 w0.155: v2(106.43,50.72) 107.67,49.48 v2(111.58,49.48) ; J34.2 17.32,29.94 21.51,34.14 28.06,34.14 30.61,36.68 30.61,38.79 32.36,40.54 41.47,40.54 42.42,41.49 49.66,41.49 51.6,39.55 55.57,39.55 59.95,43.93 72.38,43.93 v2(74.5,46.05)
  BOTTOM w0.193: v2(111.58,49.48) 116.43,49.48 120.08,53.12 R669.2 Q504.3
N16869658: length 79.7
  TOP w0.193: v2(31.81,114.58) 31.81,110.75 J5.1 ; v2(31.81,119.61) 35.4,123.2 35.4,124.26 36.58,125.45 74.74,125.45 76.7,123.49 79.77,123.49 81.74,121.53 81.74,115.75 82.65,114.83 82.65,112.88 82.41,112.64 R1.2 82.06,112.62 U4.1
  L03_SIG1 w0.155: v2(31.81,114.58) v2(31.81,119.61)
N16869662: length 5.5
  TOP w0.193: R11.2 82.95,106.18 v2(81.76,105) ; v2(81.76,105) 82.06,104.7 U4.56 ; v2(81.76,105) 81.76,104.97 81.56,104.77 U4.55
N16888382: length 11.1
  TOP w0.193: J47.8 196.7,14.94 197.03,15.26 197.03,18.51 195.98,19.56 v2(195.05,19.56) 194.18,18.69 J47.1
  BOTTOM w0.193: v2(195.05,19.56) 195.02,19.58 R726.1
N16888389: length 5.9
  TOP w0.193: J47.13 193.16,12.44 192.91,12.18 192.91,11.21 v2(194.56,9.55)
  BOTTOM w0.193: R742.1 194.58,9.57 v2(194.56,9.55)
N16888395: length 4.2
  TOP w0.193: J47.11 196.07,13.44 196.15,13.36 v2(196.15,13.19)
  BOTTOM w0.193: R725.1 196.15,13.22 v2(196.15,13.19)
N16888418: length 4.7
  TOP w0.193: v2(196.57,12.27) 196.2,12.27 195.68,12.79 195.66,12.79 195.52,12.94 J47.12
  BOTTOM w0.193: v2(196.57,12.27) 196.42,12.12 R741.1
N16906032: length 3.4
  TOP w0.193: U12.2 191.74,79.58 C25.1
N16906053: length 4
  TOP w0.193: C24.1 188.27,78.97 188.27,78.28 189.14,77.41 U12.6
N16906057: length 3.2
  TOP w0.193: v2(193.16,76.97) 192.68,76.49 U12.1
  BOTTOM w0.193: v2(193.16,76.97) 192.83,76.64 C546.2
N16906061: length 4.2
  TOP w0.193: U12.3 v2(191.09,78)
  BOTTOM w0.193: v2(191.09,78) 190.85,77.76 190.07,77.76 189.09,76.78 C546.1
N16906093: length 3.8
  TOP w0.193: U12.4 190.44,77.91 190.21,78.14 v2(190.21,78.48)
  BOTTOM w0.193: C545.2 190.21,79.08 v2(190.21,78.48)
N16906098: length 3.8
  TOP w0.193: v2(188.95,78.56) 189.79,77.72 U12.5
  BOTTOM w0.193: v2(188.95,78.56) 189.09,78.7 C545.1
N16906262: length 76.3
  TOP w0.193: U9.8 131.72,82.45 133.11,83.84 135.8,83.84 136.17,83.47 U10.8 139.44,81.56 v2(139.44,81.56) ; U6.16 v2(192.01,101.55)
  L05_SIG2 w0.155: v2(139.44,81.56) 145.07,81.56 150.72,87.21 164.05,87.21 176.51,99.67 183.98,99.67 186.63,102.33 191.23,102.33 v2(192.01,101.55)
  BOTTOM w0.193: R533.1 R532.1 192.01,102.49 v2(192.01,101.55)
N16906414: length 64.4
  TOP w0.193: TP48.1 124.04,34.61 124.94,35.51 124.94,40.76 123.57,42.13 121.34,42.13 120.97,42.51 R40.2 120.61,43.97 120.61,44.01 120.02,44.6 R39.2
  L03_SIG1 w0.155: v2(117.14,64.24) 117.14,64.8 116.51,65.43 114.96,65.43 113.82,64.29 113.82,63.21 115.27,61.76 115.27,58.24 116.76,56.74 116.76,49.82 121.23,45.35 121.23,41.07 120.95,40.79 120.95,39.27 122.87,37.35 TP48.1
  L05_SIG2 w0.155: v2(117.14,64.24) 117.42,64.52 v2(122.3,64.52)
  BOTTOM w0.193: R619.2 122.85,68.15 R621.2 122.09,64.73 v2(122.3,64.52) ; v2(117.14,64.24) 116.78,63.87 116.78,63.77 116.75,63.74 R625.2
N16906499: length 3.4
  TOP w0.193: C8.1 191.36,112.09 U6.2
N16906505: length 8.6
  BOTTOM w0.193: J4.1 17.85,106.05 19.19,107.39 19.83,107.39 20.45,108.01 U503.2 20.48,108.69 R529.2
N16906696: length 3.3
  TOP w0.193: C7.1 188.76,112.28 U6.6
N16906819: length 2.6
  TOP w0.193: v2(193.42,109.09) 192.1,109.09 U6.1
  BOTTOM w0.193: C514.2 v2(193.42,109.09)
N16906911: length 3
  TOP w0.193: U6.3 190.71,108.03 v2(190.3,107.61)
  BOTTOM w0.193: C514.1 v2(190.3,107.61)
N16906913: length 14.4
  BOTTOM w0.193: U503.4 21.96,106.22 23.07,107.33 23.07,111.01 22.88,111.21 19.72,111.21 19.37,110.86 19.37,109.99 18.95,109.57 16.84,109.57 16.54,109.87 R531.2
N16907106: length 3.7
  TOP w0.193: U6.4 190.06,110.48 v2(190.42,110.84)
  BOTTOM w0.193: C507.2 190.7,111.12 v2(190.42,110.84)
N16907207: length 3.7
  TOP w0.193: U6.5 v2(189.41,110.83)
  BOTTOM w0.193: v2(189.41,110.83) 188.77,111.47 C507.1
N16910878: length 4.4
  TOP w0.254: 50,78.27 50,79.17 49.99,79.17 49.99,79.39 49.55,79.82 v2(48.86,79.82)
  BOTTOM w0.254: v2(48.86,79.82) 49.55,79.82 49.91,79.47 49.91,79.47 50.04,79.34 R586.2
N16910921: length 4
  TOP w0.193: U14.16 56,57.45 v2(55.82,57.28)
  BOTTOM w0.193: R683.1 R684.2 56,56.35 56,57.19 55.91,57.28 v2(55.82,57.28)
N16911179: length 3.3
  TOP w0.254: v2(62.5,79.91) 62.5,79.79 61.99,79.29 61.99,78.27
  BOTTOM w0.254: v2(62.5,79.91) 62.5,79.79 61.99,79.29 61.99,79.03 R584.2
N16911537: length 4.4
  TOP w0.193: v2(62.8,59.35) 62.8,59.74 62.36,60.17 61.73,60.17 61.49,59.94 U14.27
  BOTTOM w0.193: R681.2 62.77,59.32 v2(62.8,59.35)
N16912987: length 8.6
  TOP w0.193: v2(57.07,53.19) 56.48,53.77 56.48,56.72 56.64,56.87 56.64,57.4 56.49,57.55 U14.17
  BOTTOM w0.193: v2(57.07,53.19) 57.29,53.41 57.6,53.41 58.14,53.94 R682.2
N16969756: length 298.5
  TOP w0.193: R74.2 187.2,8.7 v2(187.07,8.83)
  L03_SIG1 w0.155: v2(24.07,12.76) 23.24,11.93 21.44,11.93 20.03,13.35 20.03,62.2 21.54,63.71 21.54,66.01 22.84,67.31 22.84,73.02 24.2,74.38 24.2,116.45 16.78,123.88 v2(15.65,123.88)
  L05_SIG2 w0.155: v2(67.53,6.5) 28.41,6.5 27.26,7.65 27.26,10.17 25.45,11.99 24.85,11.99 v2(24.07,12.76) ; v2(125.4,6.04) 127.22,4.22 139.48,4.22 140.27,5.01 179.62,5.01 180.45,4.19 181.46,4.19 186.1,8.83 v2(187.07,8.83)
  BOTTOM w0.193: R508.2 13.82,126.12 R506.1 ; R506.1 13.83,124.86 14.82,123.88 v2(15.65,123.88) ; R506.1 13.84,126.12 R507.1 ; v2(125.4,6.04) 125.2,6.25 67.78,6.25 v2(67.53,6.5)
N16973926: length 14.1
  TOP w0.193: U5.8 182.71,105.55 182.71,103.91 v2(183.01,103.61) ; v2(180.39,109.7) 180.81,109.28 U5.5
  L03_SIG1 w0.155: v2(180.39,109.7) 180.39,106.22 v2(183.01,103.61)
  BOTTOM w0.193: 182.83,104.7 R520.2 ; 182.83,104.7 183.01,104.52 v2(183.01,103.61) ; 182.83,104.7 C516.2 C517.2
N16985744: length 60.8
  TOP w0.193: v2(165.61,110.1) 165.61,110.22 165.61,110.23 U2.1
  L03_SIG1 w0.155: v2(174.32,57.53) 171.45,60.4 171.45,79.43 165.42,85.46 165.42,109.91 v2(165.61,110.1)
  BOTTOM w0.193: R648.1 v2(174.32,57.53)
N17028370: length 3.2
  TOP w0.193: R53.1 28.77,25.26 28.15,25.26 27.97,25.43 v2(27.95,25.43)
  BOTTOM w0.193: v2(27.95,25.43) 27.81,25.57 27.08,25.57 26.91,25.4 U515.23
N17028379: length 2.5
  TOP w0.193: R49.1 26.86,24.75 27.16,24.75 v2(27.21,24.8)
  BOTTOM w0.193: v2(27.21,24.8) 27.16,24.75 U515.22
N17028388: length 3.3
  TOP w0.193: R54.1 28.24,24.24 v2(28.05,24.43)
  BOTTOM w0.193: v2(28.05,24.43) 27.8,24.19 27.03,24.19 26.95,24.1 U515.21
N17028397: length 2.5
  TOP w0.193: v2(27.26,23.5) 26.87,23.11 R50.1
  BOTTOM w0.193: v2(27.26,23.5) 27.21,23.45 U515.20
N17028406: length 3.2
  TOP w0.193: R55.1 28.24,22.76 v2(28.22,22.78)
  BOTTOM w0.193: U515.19 28.19,22.8 28.21,22.78 v2(28.22,22.78)
N17028415: length 2.4
  TOP w0.193: v2(27.25,22.19) 26.46,22.19 R51.1
  BOTTOM w0.193: v2(27.25,22.19) 27.21,22.15 U515.18
N17028424: length 3.2
  TOP w0.193: R52.1 26.74,21.33 v2(27.57,21.33)
  BOTTOM w0.193: v2(27.57,21.33) 27.4,21.5 U515.17
N17028433: length 2.7
  TOP w0.193: R63.1 28.11,20.31 v2(27.43,20.31)
  BOTTOM w0.193: U515.16 26.89,20.85 v2(27.43,20.31)
N17028442: length 4.2
  TOP w0.193: v2(27.98,19.55) 27.86,19.55 27.84,19.53 27.31,19.53 27.29,19.55 26.63,19.55 R62.1
  BOTTOM w0.193: v2(27.98,19.55) 27.86,19.55 27.84,19.53 27.35,19.53 26.67,20.2 U515.15
N17028451: length 3.2
  TOP w0.193: R64.1 33.25,19.27 v2(33.25,19.23)
  BOTTOM w0.193: v2(33.25,19.23) 32.93,19.55 U515.11
N17035653: length 19.1
  TOP w0.193: J60.1 154.28,8.62 v2(155.4,9.73)
  BOTTOM w1.27: R769.2 151.41,4.04 C668.2 R748.1 154.31,8.64 v2(155.4,9.73) 155.88,10.22 L504.1
N17035679: length 19.3
  TOP w0.193: J61.1 165.71,7.98 v2(167.47,9.73)
  BOTTOM w1.27: L503.1 167.95,10.22 v2(167.47,9.73) 166.37,8.64 R747.1 C667.2 163.47,4.04 R768.2
N17035705: length 13.4
  TOP w0.635: J37.1 v2(142.07,23.7)
  BOTTOM w1.27: L502.1 142.55,24.19 v2(142.07,23.7) 140.97,22.61 R720.1 C658.2 138.07,18.01 R734.2
N17035724: length 13.4
  TOP w0.635: J38.1 v2(155.4,23.7)
  BOTTOM w1.27: R733.2 151.41,18.01 C657.2 R719.1 154.31,22.61 v2(155.4,23.7) 155.88,24.19 L501.1
N17035755: length 13.4
  TOP w0.635: J39.1 v2(167.47,23.7)
  BOTTOM w1.27: L500.1 167.95,24.19 v2(167.47,23.7) 166.37,22.61 R718.1 C656.2 163.47,18.01 R732.2
N17036356: length 10.4
  TOP w0.193: VR1.2 98.64,29.5 TP59.1
  BOTTOM w0.193: R753.2 104.78,30.04 103.22,28.49 U519.5 99.65,28.49 TP59.1
N17038227: length 4.1
  TOP w0.193: J52.2 69.85,30.73 v2(68.58,32)
  BOTTOM w0.193: R756.1 68.58,30.76 v2(68.58,32)
N17038557: length 3.6
  TOP w0.193: v2(69.3,42.9) 71.01,42.9 J53.2
  BOTTOM w0.193: R773.1 v2(69.3,42.9)
N17038579: length 1.8
  BOTTOM w0.193: R773.2 71.09,41.2 U520.4
N17060093: length 12.6
  BOTTOM w0.193: R511.1 172.11,119.49 172.63,120.02 U501.1 172.99,121.11 173.17,121.28 173.64,121.28 ; U501.2 173.64,121.28 ; 173.64,121.28 174.09,121.28 174.29,121.08 U501.3 174.29,118.01 174.94,117.36 U501.11
N17060097: length 75.5
  TOP w0.193: U2.30 155.52,113.79 v2(155.27,114.05)
  BOTTOM w0.193: U501.4 174.94,118.87 175.7,118.11 C510.1 179.54,117.22 182.28,117.22 183.35,118.3 183.35,119.58 182.7,120.23 180.74,120.23 180.21,120.76 180.21,123.97 181.08,124.84 181.08,128.63 178.66,131.04 158.9,131.04 156.89,129.03 156.89,128.47 157.92,127.44 157.92,123.62 156.12,121.82 156.12,114.9 v2(155.27,114.05) 154.19,114.05 150.51,110.36 R526.2 150.63,110.24 R525.1
N17060101: length 2.3
  TOP w0.254: 154.59,114.38 154.99,114.79 U2.28
N17060103: length 8.1
  TOP w0.193: v2(139.64,112.9) 139.64,116.84 L1.2
  BOTTOM w0.193: D500.2 138.9,112.16 v2(139.64,112.9)
N17060105: length 3.1
  BOTTOM w0.193: D500.1 144.69,109.09 R527.1
N17060121: length 2
  BOTTOM w0.193: R510.2 175.59,122.02 U501.5
N17060167: length 4.3
  BOTTOM w0.193: U501.6 176.24,118.95 176.56,118.63 177.45,118.63 178.33,119.51 R509.1
N17126992: length 9.1
  TOP w0.193: U11.AC10 v1(103.66,72.2)
  BOTTOM w0.102: v1(103.66,72.2) 104.06,72.59 106.97,72.59 107.58,71.99 107.63,71.99
  BOTTOM w0.193: R597.2 110.39,71.99 107.63,71.99
N17126998: length 5.8
  TOP w0.193: U11.AF10 v1(106.66,72.2)
  BOTTOM w0.102: v1(106.66,72.2) 107.35,71.51 107.63,71.51
  BOTTOM w0.193: 107.63,71.51 107.64,71.5 110.87,71.5 111.25,71.88 R598.2
N17172867: length 7.8
  TOP w0.193: U11.AD10 v1(104.66,72.2)
  BOTTOM w0.102: 107.63,71.05 107.5,71.05 106.85,71.7 105.16,71.7 v1(104.66,72.2)
  BOTTOM w0.193: 107.63,71.05 107.69,70.99 R599.2
N17173381: length 25.5
  BOTTOM w0.193: U512.3 129.74,41.98 R705.2 128.91,44.15 C644.2 129.35,44.58 130.62,43.31 132.08,43.31 TP38.1 133.35,46.55 131.89,48.01 129.73,48.01 129.1,47.37 127.32,47.37 127.28,47.4 121.5,47.4 121.02,47.89 R695.1
N17173524: length 15
  BOTTOM w0.193: R694.1 R695.2 121.3,49.4 120.33,49.4 119.95,49.02 119.95,47.75 120.84,46.86 126.57,46.86 127.77,45.66 127.77,44.74 C645.2
N17223452: length 25.3
  TOP w0.193: v2(98.75,97.82) 98.75,97.39 97.93,96.57 95.67,96.57 v2(95.12,97.12) 94.83,97.41 v2(86.87,97.41)
  BOTTOM w0.193: FB503.1 FB504.1 v2(86.87,97.41) ; C527.1 100.38,95.95 C528.1 99.4,95.28 98.91,95.28 98.3,95.89 FB500.1 98.3,96.94 98.75,97.39 v2(98.75,97.82) 99.16,98.22 R536.2 ; v2(95.12,97.12) 95,97.12 FB502.1
N17234365: length 22.2
  TOP w0.193: v2(97.1,97.39) 95.65,98.84 86.97,98.84 v2(85.47,97.35)
  BOTTOM w0.193: C537.1 82.84,93.95 R558.2 82.84,96.49 C536.1 83.49,96.57 FB506.1 FB505.1 v2(85.47,97.35) ; FB501.1 96.77,97.07 v2(97.1,97.39)
N17385870: length 10.2
  TOP w0.193: U11.AB11 v1(102.66,73.2)
  BOTTOM w0.102: v1(102.66,73.2) 103.11,73.2 103.51,72.8 107.16,72.8 107.53,72.43 107.63,72.43
  BOTTOM w0.193: 107.63,72.43 109.88,72.43 111.24,73.79 R596.2
N17410797: length 15.7
  BOTTOM w0.508: R551.2 148.51,97.21 C522.2 148.59,99.5 149.55,100.46 Q500.3 152.32,100.46 152.94,101.07 152.94,103.62 152.35,104.21 152.35,105.35 152.8,105.8 R524.2
N17410821: length 12.2
  TOP w0.193: v2(153.91,112.13) 153.91,112.11 154.39,112.58 155.23,112.58 155.52,112.29 U2.33
  BOTTOM w0.193: Q500.1 150.92,105.03 152.1,106.21 152.1,110.31 v2(153.91,112.13)
N17410829: length 15
  TOP w0.193: v2(154.74,113.3) 155.34,113.3 155.85,112.79 U2.32
  L03_SIG1 w0.155: v2(154.74,113.3) 154.24,113.3 153.32,112.37 153.32,108.65 154.77,107.2 154.77,106.7 154.18,106.11 v2(154.18,103.94)
  BOTTOM w0.193: R524.1 R523.2 v2(154.18,103.94)
N17418086: length 23.7
  BOTTOM w0.193: U517.22 12.43,12.2 12.56,12.08 13.09,12.08 13.21,12.19 U523.2 18.44,12.19 18.97,11.66 22.77,11.66 23.07,11.96 26.76,11.96 27.97,13.17 27.97,15.28 J41.3
N17418532: length 18.5
  TOP w0.193: v2(7.87,25.27) 6.97,25.27 6.92,25.33 J33.10
  BOTTOM w0.193: v2(7.87,25.27) 7.87,25.26 7.45,24.84 7.45,23.35 9.11,21.69 10.57,21.69 12.45,19.81 12.45,17.27 11.28,16.1 U517.16
N17418535: length 18
  TOP w0.193: v2(7.24,26.54) 7.2,26.58 J33.11
  BOTTOM w0.193: v2(7.24,26.54) 6.82,26.12 6.82,23.11 8.8,21.13 10.11,21.13 11.81,19.43 11.81,17.39 11.17,16.75 U517.15
N17423586: length 12.2
  BOTTOM w0.193: J41.1 25.18,14.07 24.11,14.07 23.21,13.17 23.21,12.91 22.54,12.24 19.59,12.24 18.68,13.14 U523.4 16.68,14.26 R740.1
N17451899: length 2.3
  TOP w0.193: SW1.1 v2(63.31,16.22)
  BOTTOM w0.193: R736.2 62.87,16.66 v2(63.31,16.22)
N17529082: length 1.7
  BOTTOM w0.193: R767.2 173.41,3.98 Q507.2
N17529223: length 4.4
  BOTTOM w0.193: Q507.3 Q506.1 175.21,8.09 R746.1
N17529899: length 4.9
  TOP w0.193: J62.1 v2(177.91,3.38)
  BOTTOM w0.193: v2(177.91,3.38) 176.33,3.38 176.15,3.2 ; 176.15,3.2 C666.2 ; 176.15,3.2 Q506.3
N18108465: length 16.6
  BOTTOM w0.193: U513.2 48.05,24.51 44.03,20.48 42.61,20.48 41.43,19.3 41.43,17.09 41.39,17.06 R738.2
N18206464: length 9.6
  BOTTOM w0.193: U516.18 46.95,17.13 47.37,16.71 47.68,16.71 48.26,16.13 48.26,14.48 51.27,11.47 R758.1
N18206467: length 3.6
  BOTTOM w0.193: R738.1 42.98,16.51 43,16.54 44.7,16.54 44.9,16.73 U516.17
N18206470: length 5
  BOTTOM w0.193: R759.1 47.6,15.95 47.22,16.33 U516.16
N18206473: length 6.2
  BOTTOM w0.193: U516.15 46.99,15.93 47.14,15.77 47.14,13.82 46.66,13.34 R761.1
N18206476: length 3.6
  BOTTOM w0.193: R739.1 42.72,15.53 U516.14
N18206999: length 5.7
  BOTTOM w0.193: U513.4 48.58,23.56 47.65,22.63 47.65,21.35 47.62,21.32 J44.1
N18269038: length 2.9
  TOP w0.193: C16.2 176.42,102.02 176.42,101.94 176.53,101.82 U7.3
N18269088: length 32.2
  TOP w0.193: U7.2 v2(177.8,101.73) 179.58,101.73 179.71,101.6 C17.1 R21.2
  L03_SIG1 w0.155: v2(167.37,108.42) 171.83,103.96 v2(171.83,100.99)
  BOTTOM w0.193: v2(171.83,100.99) 177.06,100.99 v2(177.8,101.73) ; v2(167.37,108.42) 169.67,110.72 169.67,111.3 170.65,112.28 R516.1 172.72,112.83 172.99,113.1 U501.14
N18269114: length 2.6
  BOTTOM w0.193: R521.1 174.29,112.4 174.29,112.4 U501.12
N18269160: length 23.1
  TOP w0.508: R17.1 181.58,103.86 182.77,102.68 C17.2 R21.1 184,100.33 185.39,98.93 185.39,92 183.31,89.92 183.31,85.8
N18269218: length 13
  TOP w0.193: v2(177.52,104.42) 178.08,103.86 R17.2
  BOTTOM w0.193: U501.13 173.64,108.3 v2(177.52,104.42)
N18269262: length 5.3
  TOP w0.193: v2(192.46,92.2) 192.04,92.2 190.9,93.34 R23.1
  BOTTOM w0.193: v2(192.46,92.2) 192.46,93.34 C523.1 Q502.2
N18269320: length 9.5
  TOP w0.193: R22.1 190.94,96.95 v2(191.88,96.95)
  BOTTOM w0.193: v2(191.88,96.95) Q501.2 190.13,96.95 189.24,96.06 189.24,95.44 188.79,95 187.78,95 187.25,94.46 187.25,93.17 187.96,92.46 Q502.3
N18269375: length 5.4
  TOP w0.508: L4.1 176.53,90.88 176.3,91.11 C21.1 176.53,92.3 U7.6
N18374429: length 2.5
  TOP w0.193: C21.2 178.03,92.88 177.8,93.1 U7.7

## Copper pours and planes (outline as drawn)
GND on TOP (solid shape): 162.43,58.29 157.35,58.29 157.35,63.37 162.43,63.37
GND on TOP (solid shape): 163.7,111 158.62,111 158.62,116.08 163.7,116.08
GND on TOP (solid shape): 179.32,95.76 175.01,95.76 175.01,98.55 179.32,98.55
GND on TOP (solid shape): 186.69,12.38 184.15,12.38 184.15,14.92 186.69,14.92
GND on TOP (solid shape): 163.61,83.27 163.65,83.17 163.7,83.08 163.7,81.35 163.63,81.09 163.7,80.83 163.7,79.12 160.4,79.12 160.4,83.31 163.61,83.31
GND on BOTTOM (solid shape): 144.02,65.53 140.21,65.53 140.21,70.61 144.02,70.61
GND on BOTTOM (solid shape): 150.75,77.85 147.07,77.85 147.07,80.9 150.75,80.9
GND on BOTTOM (solid shape): 166.62,41.02 162.18,41.02 162.05,41.15 162.05,43.56 162.81,44.32 166.62,44.32
GND on L02_GND1 (solid shape): 197.14,7.46 199.12,6.53 199.13,6.51 199.14,6.49 199.14,5.59 199.77,4.95 199.77,1.4 198.63,0.25 194.69,0.25 194.18,0.76 193.6,0.76 193.58,0.77 193.56,0.78 193.13,1.34 192.8,1.97 192.72,2.17 192.66,2.37 192.62,2.46 192.63,2.47 192.91,5.28 194.97,7.2
GND on L02_GND1 (solid shape): 5.28,7.09 7.2,5.03 7.44,2.79 6.44,0.78 6.42,0.77 6.4,0.76 5.97,0.76 5.46,0.25 1.52,0.25 0.25,1.52 0.25,5.08 0.76,5.59 0.76,6.4 0.77,6.42 0.78,6.44 1.34,6.87 1.97,7.2 2.17,7.28 2.37,7.34 2.46,7.38
GND on L02_GND1 (solid shape): 7.44,119.29 0.78,117.06 0.77,117.08 0.76,117.1 0.76,117.73 0.25,118.24 0.25,121.54 0.76,122.05 0.76,122.9 0.77,122.92 0.78,122.94 1.34,123.37 1.97,123.7
GND on L02_GND1 (solid shape): 27.81,132.08 28.67,132.08 28.69,132.08 28.71,132.06 27.7,126.07 21.92,127.97 21.85,128.17 21.78,128.37 21.75,128.46 21.75,128.47 21.71,130.36 22.55,132.06 22.56,132.08 22.58,132.08 23.24,132.08 23.88,132.72 27.18,132.72
GND on L02_GND1 (solid shape): 134.87,132.08 135.67,132.08 135.69,132.08 135.71,132.06 134.7,126.07 128.92,127.97 128.85,128.17 128.78,128.37 128.75,128.46 128.75,128.47 128.71,130.36 129.55,132.06 129.56,132.08 129.58,132.08 130.3,132.08 130.94,132.72 134.24,132.72
GND on L02_GND1 (solid shape): 197.14,131.46 199.12,130.53 199.13,130.51 199.14,130.49 199.14,129.67 199.77,129.03 199.77,125.86 199.14,125.22 199.14,124.51 199.13,124.49 199.12,124.47 195.58,123.6 192.8,125.97 192.72,126.17 192.66,126.37 192.62,126.46 192.63,126.47 192.91,129.28 194.97,131.2
GND on L04_GND2 (solid shape): 197.14,7.46 199.12,6.53 199.13,6.51 199.14,6.49 199.14,5.59 199.77,4.95 199.77,1.4 198.63,0.25 194.69,0.25 194.18,0.76 193.6,0.76 193.58,0.77 193.56,0.78 193.13,1.34 192.8,1.97 192.72,2.17 192.66,2.37 192.62,2.46 192.63,2.47 192.91,5.28 194.97,7.2
GND on L04_GND2 (solid shape): 5.28,7.09 7.2,5.03 7.44,2.79 6.44,0.78 6.42,0.77 6.4,0.76 5.97,0.76 5.46,0.25 1.52,0.25 0.25,1.52 0.25,5.08 0.76,5.59 0.76,6.4 0.77,6.42 0.78,6.44 1.34,6.87 1.97,7.2 2.17,7.28 2.37,7.34 2.46,7.38
GND on L04_GND2 (solid shape): 7.44,119.29 0.78,117.06 0.77,117.08 0.76,117.1 0.76,117.73 0.25,118.24 0.25,121.54 0.76,122.05 0.76,122.9 0.77,122.92 0.78,122.94 1.34,123.37 1.97,123.7
GND on L04_GND2 (solid shape): 27.81,132.08 28.67,132.08 28.69,132.08 28.71,132.06 27.7,126.07 21.92,127.97 21.85,128.17 21.78,128.37 21.75,128.46 21.75,128.47 21.71,130.36 22.55,132.06 22.56,132.08 22.58,132.08 23.24,132.08 23.88,132.72 27.18,132.72
GND on L04_GND2 (solid shape): 134.87,132.08 135.67,132.08 135.69,132.08 135.71,132.06 134.7,126.07 128.92,127.97 128.85,128.17 128.78,128.37 128.75,128.46 128.75,128.47 128.71,130.36 129.55,132.06 129.56,132.08 129.58,132.08 130.3,132.08 130.94,132.72 134.24,132.72
GND on L04_GND2 (solid shape): 197.14,131.46 199.12,130.53 199.13,130.51 199.14,130.49 199.14,129.67 199.77,129.03 199.77,125.86 199.14,125.22 199.14,124.51 199.13,124.49 199.12,124.47 195.58,123.6 192.8,125.97 192.72,126.17 192.66,126.37 192.62,126.46 192.63,126.47 192.91,129.28 194.97,131.2
GND on L06_GND3 (solid shape): 197.14,7.46 199.12,6.53 199.13,6.51 199.14,6.49 199.14,5.59 199.77,4.95 199.77,1.4 198.63,0.25 194.69,0.25 194.18,0.76 193.6,0.76 193.58,0.77 193.56,0.78 193.13,1.34 192.8,1.97 192.72,2.17 192.66,2.37 192.62,2.46 192.63,2.47 192.91,5.28 194.97,7.2
GND on L06_GND3 (solid shape): 5.28,7.09 7.2,5.03 7.44,2.79 6.44,0.78 6.42,0.77 6.4,0.76 5.97,0.76 5.46,0.25 1.52,0.25 0.25,1.52 0.25,5.08 0.76,5.59 0.76,6.4 0.77,6.42 0.78,6.44 1.34,6.87 1.97,7.2 2.17,7.28 2.37,7.34 2.46,7.38
GND on L06_GND3 (solid shape): 7.44,119.29 0.78,117.06 0.77,117.08 0.76,117.1 0.76,117.73 0.25,118.24 0.25,121.54 0.76,122.05 0.76,122.9 0.77,122.92 0.78,122.94 1.34,123.37 1.97,123.7
GND on L06_GND3 (solid shape): 27.81,132.08 28.67,132.08 28.69,132.08 28.71,132.06 27.7,126.07 21.92,127.97 21.85,128.17 21.78,128.37 21.75,128.46 21.75,128.47 21.71,130.36 22.55,132.06 22.56,132.08 22.58,132.08 23.24,132.08 23.88,132.72 27.18,132.72
GND on L06_GND3 (solid shape): 134.87,132.08 135.67,132.08 135.69,132.08 135.71,132.06 134.7,126.07 128.92,127.97 128.85,128.17 128.78,128.37 128.75,128.46 128.75,128.47 128.71,130.36 129.55,132.06 129.56,132.08 129.58,132.08 130.3,132.08 130.94,132.72 134.24,132.72
GND on L06_GND3 (solid shape): 197.14,131.46 199.12,130.53 199.13,130.51 199.14,130.49 199.14,129.67 199.77,129.03 199.77,125.86 199.14,125.22 199.14,124.51 199.13,124.49 199.12,124.47 195.58,123.6 192.8,125.97 192.72,126.17 192.66,126.37 192.62,126.46 192.63,126.47 192.91,129.28 194.97,131.2
GND on TOP: 199.16,18.62 199.16,11.42 199.07,11.33 198.39,11.33 198.26,11.46 198.26,13.82 198.51,14.07 198.51,14.96 198.35,15.12 198.35,18.58 198.49,18.72 199.05,18.72
GND on TOP: 166.4,85.7 172.21,85.7 172.21,93.8 174.52,96.11 175.34,96.11 175.34,97.71 175.16,97.89 170.61,97.89 169.47,96.75 169.47,90.65 166.4,87.58
GND on TOP: 0.94,132.21 198.99,132.21 199.18,132.02 199.18,122.54 198.34,121.69 195.02,121.69 191.76,124.96 191.76,130.66 191.02,131.4 138.17,131.4 137.31,130.54 137.31,127.85 134.3,124.84 130.99,124.84 127.88,127.96 127.88,130.14 126.61,131.4 32.45,131.4 30.81,129.76 30.81,126.16 29.19,124.54 20.76,124.54 19.43,125.87 19.43,130.19 18.22,131.4 2.6,131.4 1.61,130.41 1.61,125.7 1.61,125.7 2.42,124.89 6.09,124.89 8.74,122.24 8.74,117.73 6.01,115 2.6,115 1.61,114 1.61,9.4 2.58,8.43 6.23,8.43 8.3,6.36 8.3,2.4 9.04,1.66 188.05,1.66 193.38,6.99 193.42,6.99 194.78,8.35 198.45,8.35 199.09,7.7 199.09,1.24 198.62,0.77 1.35,0.77 0.78,1.34 0.78,5.65 0.8,5.68 0.8,132.08 ; 11 cut-outs
GND on TOP: 179.27,96.19 184.18,96.19 184.96,96.98 184.96,97.64 184.43,98.17 179.02,98.17 179.02,96.44
GND on TOP: 116.04,18.92 116.65,18.92 117.72,19.99 117.72,21.09 117.76,21.14 118.34,21.14 118.38,21.09 118.38,18.97 117.6,18.19 116.01,18.19 115.94,18.27 115.94,18.82
GND on TOP, BOTTOM, L03_SIG1, L05_SIG2: 198.05,58.69 198.05,21.68 198.21,21.53 198.92,21.53 199.05,21.66 199.05,58.76 198.89,58.92 198.28,58.92
GND on BOTTOM: 143.13,60.07 143.13,57.66 143.26,57.53 146.3,57.53 146.43,57.4 146.43,54.74 148.08,54.74 148.08,56.64 147.96,56.77 149.1,56.77 149.22,56.64 149.61,56.64 149.61,60.2 148.72,61.09 144.15,61.09
GND on BOTTOM: 198.05,113.75 198.05,99.48 199.11,99.48 199.11,113.75
GND on BOTTOM: 199.08,21.9 199.08,6.36 198.26,6.36 198.26,13.82 198.51,14.07 198.51,14.96 198.35,15.12 198.35,21.9
GND on BOTTOM: 0.94,132.21 198.99,132.21 199.18,132.02 199.18,122.54 198.34,121.69 195.28,121.69 191.76,125.21 191.76,130.66 191.02,131.4 138.17,131.4 137.31,130.54 137.31,127.85 134.3,124.84 130.99,124.84 127.88,127.96 127.88,130.14 126.61,131.4 32.45,131.4 30.81,129.76 30.81,126.16 29.19,124.54 20.76,124.54 19.43,125.87 19.43,130.19 18.22,131.4 2.6,131.4 1.61,130.41 1.61,125.7 1.61,125.7 2.42,124.89 6.09,124.89 8.74,122.24 8.74,117.73 6.01,115 2.6,115 1.61,114 1.61,9.4 2.58,8.43 6.23,8.43 8.3,6.36 8.3,2.4 9.04,1.66 188.05,1.66 193.38,6.99 193.42,6.99 194.78,8.35 198.45,8.35 199.09,7.7 199.09,1.24 198.62,0.77 1.35,0.77 0.78,1.34 0.78,5.65 0.8,5.68 0.8,132.08 ; 7 cut-outs
GND on BOTTOM: 160.86,118.78 162.57,118.78 163.48,117.87 163.48,115.33 164.3,114.5 166.21,114.5 166.38,114.33 166.38,113.22 166.22,113.07 163.86,113.07 163.55,112.76 163.55,111.24 163.32,111.01 158.84,111.01 158.56,111.29 158.56,115.81 159.02,116.27 160.16,116.27 160.77,116.88 160.77,118.7
GND on BOTTOM: 84.07,83.44 84.23,73.79 87.12,73.79 87.12,66.17 101.98,66.16 101.98,73.03 101.35,73.03 101.35,74.42 101.98,74.42 101.98,83.82 100.97,83.82 100.97,84.46 92.71,84.46 92.71,83.44
GND on BOTTOM: 53.6,13.47 50.47,13.47 48.92,15.02 48.92,15.93 49.15,16.16 49.45,16.16 49.97,15.64 50.98,15.64 51,15.66 52.62,15.66 52.81,15.46 52.81,15.21 53.72,14.3 53.72,13.6
GND on L02_GND1, L04_GND2, L06_GND3: 0.76,0.76 199.24,0.76 199.24,132.23 0.76,132.23 ; 5 cut-outs
GND on L03_SIG1: 0.94,132.21 198.99,132.21 199.18,132.02 199.18,122.54 198.34,121.69 192.45,121.69 191.76,122.39 191.76,130.66 191.02,131.4 138.17,131.4 137.31,130.54 137.31,127.85 134.3,124.84 130.99,124.84 127.88,127.96 127.88,130.14 126.61,131.4 32.45,131.4 30.81,129.76 30.81,126.16 29.19,124.54 20.76,124.54 19.43,125.87 19.43,130.19 18.22,131.4 2.6,131.4 1.61,130.41 1.61,125.7 1.61,125.7 2.42,124.89 6.09,124.89 8.74,122.24 8.74,117.73 6.01,115 2.6,115 1.61,114 1.61,9.4 2.58,8.43 6.23,8.43 8.3,6.36 8.3,2.4 9.04,1.66 188.05,1.66 193.38,6.99 193.42,6.99 194.78,8.35 198.45,8.35 199.09,7.71 199.09,6.13 199.09,1.24 198.62,0.77 1.35,0.77 0.78,1.34 0.78,5.65 0.8,5.68 0.8,132.08 ; 6 cut-outs
GND on L03_SIG1: 199.08,22.26 199.08,6.8 198.26,6.8 198.26,13.82 198.51,14.07 198.51,14.96 198.35,15.12 198.35,22.26
GND on L03_SIG1: 198.13,80.95 198.13,66.2 199.21,66.2 199.21,80.95
GND on L03_SIG1: 198.15,113.7 198.15,98.89 199.2,98.89 199.2,113.7
GND on L05_SIG2: 0.94,132.21 198.99,132.21 199.18,132.02 199.18,122.54 198.34,121.69 195.35,121.69 195.35,123.75 193.39,125.7 193.39,130.2 192.19,131.4 138.17,131.4 137.31,130.54 137.31,127.85 134.3,124.84 130.99,124.84 127.88,127.96 127.88,130.14 126.61,131.4 32.45,131.4 30.81,129.76 30.81,126.16 29.19,124.54 20.76,124.54 19.43,125.87 19.43,130.19 18.22,131.4 2.6,131.4 1.61,130.41 1.61,125.7 1.61,125.7 2.42,124.89 6.09,124.89 8.74,122.24 8.74,117.73 6.01,115 2.6,115 1.61,114 1.61,9.4 2.58,8.43 6.23,8.43 8.3,6.36 8.3,2.4 9.04,1.66 188.05,1.66 193.38,6.99 193.42,6.99 194.78,8.35 198.45,8.35 199.09,7.7 199.09,1.24 198.62,0.77 1.35,0.77 0.78,1.34 0.78,5.65 0.8,5.68 0.8,132.08 ; 9 cut-outs
GND on L05_SIG2: 199.05,21.84 199.05,7.27 198.26,7.27 198.26,13.82 198.51,14.07 198.51,14.96 198.35,15.12 198.35,21.84
P5V on BOTTOM (solid shape): 195.53,42.85 195.53,40.77 194.06,39.29 192.25,39.29 191.95,39.6 191.95,43 192.79,43.84 194.54,43.84
P5V on TOP: 143.81,74.19 143.99,74.37 143.99,74.94 144.1,75.04 144.61,75.04 144.71,75.14 144.71,75.74 144.63,75.83 142.92,75.83 142.76,75.67 142.76,75.67 142.38,75.29 142.38,73.68 142.27,73.56 142.27,71.81 140.41,69.95 140.41,69.17 141.12,68.45 141.12,62.39 140.08,61.35 139.12,61.35 137.14,59.37 136.86,59.37 133.28,62.95 130.61,62.95 125.59,67.97 125.12,67.97 124.84,67.69 124.84,65.33 128.29,61.87 128.29,56.41 127.57,55.69 122.4,55.69 120.04,58.04 118.23,58.04 117.65,57.46 117.65,55.53 118.11,55.07 119.87,55.07 121.64,53.31 128.48,53.31 130.41,55.24 130.41,59.2 130.96,59.76 134.47,59.76 135.89,58.33 138.31,58.33 139.83,59.85 141.43,59.85 144.74,63.16 144.74,70.22 143.81,71.14
P5V on TOP: 123.33,18.29 123.33,14.22 125.87,11.67 125.87,3.34 126.36,2.85 128.17,2.85 128.63,3.31 128.63,9.02 129.23,9.62 129.23,15.41 126.09,18.55 123.58,18.55
P5V on BOTTOM: outline of 147 points within 1.85,69.36 148.49,130.18
P5V on BOTTOM: 38.09,2.79 39.14,2.79 39.41,2.52 39.41,1.88 39.3,1.77 36.26,1.77 35.62,2.42 28.43,2.42 27.56,3.29 27.56,5.56 27.9,5.9 30.29,5.9 30.87,5.33 30.87,3.55 31.22,3.2 32.41,3.2 32.5,3.29 32.5,4.01 32.83,4.34 36.54,4.34
P5V on L03_SIG1: 140.28,89.84 143.46,89.84 144.07,90.45 144.07,94.01 144.6,94.54 144.6,98.96 145.34,99.69 145.34,123.09 143.51,124.92 143.51,126.11 144.09,126.7 144.09,128.96 143.74,129.31 142.09,129.31 140.41,127.63 140.41,124 137.59,121.18 137.59,116.66 136.55,115.62 136.55,99.49 137.64,98.4 141.55,98.4 142.16,97.79 142.16,95.68 139.32,92.84 139.32,90.81
P5V on L03_SIG1: 117.65,57.95 117.65,50.3 122.06,45.89 122.06,41.26 123.61,39.7 123.61,38.54 124.47,37.69 124.47,23.57 122.68,21.78 122.68,18.59 123.11,18.16 123.11,16.85 123.31,16.65 123.95,16.65 124.34,17.04 124.34,20.03 124.05,20.32 124.05,21.64 126.04,23.64 126.04,31.36 125.2,32.2 125.2,40.24 123.54,41.9 123.54,42.42 123.56,42.45 123.56,42.59 122.86,43.29 122.86,46.53 119.33,50.06 119.33,53.91 118.78,54.47 118.78,57.86 118.55,58.09 117.79,58.09
P5V on L03_SIG1: 3.23,71.42 3.23,69.96 4.87,68.32 4.87,65.36 3.3,63.79 3.3,23.04 3.58,22.76 3.58,8.96 3.88,8.66 4.66,8.66 4.99,8.99 4.99,15.87 4.75,16.11 4.75,25.15 4.47,25.43 4.47,60.82 7.16,63.51 7.16,71.27 6.41,72.02 3.82,72.02
P5V on L05_SIG2: 3.16,34.21 3.16,32.1 3.63,31.62 17.69,31.62 20.48,34.41 24.4,34.41 32.8,42.82 48.91,42.82 51.94,39.79 55.59,39.79 60.07,44.27 69.64,44.27 70.05,44.68 70.05,45.29 69.35,45.99 59.88,45.99 55.43,41.54 53.11,41.54 50.43,44.22 47.12,44.22 46.13,45.21 41.16,45.21 40.12,46.25 40.12,48.44 39.64,48.92 32.83,48.92 30.65,46.75 30.65,43.46 24.4,37.2 19.35,37.2 16.82,34.68 3.63,34.68
P5V on L05_SIG2: 123.3,40.66 123.3,38.6 123.9,38 126.15,38 130.79,33.36 139.42,33.36 141.23,35.17 144.04,35.17 145.87,33.34 145.87,29.89 147.34,28.42 155.22,28.42 155.89,29.09 185.9,29.09 187.88,27.11 196.38,27.11 197.54,28.27 197.54,42.21 196.84,42.91 195.03,42.91 193.49,41.37 193.49,37.64 195.27,35.86 195.27,34.19 194.77,33.68 190.51,33.68 189.67,34.53 189.67,39.43 189.21,39.89 176.89,39.89 174.38,37.38 174.38,35.76 169.81,31.19 148.26,31.19 147.44,32.02 147.44,33.66 139.28,41.81 124.45,41.81
P5V on L05_SIG2: 3.68,11.01 3.68,9.06 4.07,8.67 7.34,8.67 12.37,3.64 19.47,3.64 19.86,3.26 34.26,3.26 34.27,3.27 35.58,3.27 35.76,3.45 35.76,5.14 35.3,5.6 24.91,5.6 23.24,7.27 18.19,7.27 14.16,11.3 3.98,11.3
P5V on L05_SIG2: 192.94,40.49 195.63,40.49 197.23,42.09 197.23,56.64 194.74,59.13 194.74,62.41 195.2,62.87 195.2,64.97 198.96,68.73 198.96,78.61 194.39,83.19 194.39,94.87 195.45,95.94 195.45,98.09 198.55,101.19 198.55,111.02 195.05,114.53 195.05,117.53 194.72,117.86 194.72,123.34 192.58,125.48 192.58,129.59 191.2,130.97 139.25,130.97 137.31,129.03 137.31,127.58 139.83,125.07 141.07,125.07 143.56,127.56 157.23,127.56 159.54,125.25 171.55,125.25 172.54,126.24 178.31,126.24 179.4,127.33 184.15,127.33 188.37,123.11 188.37,108.05 193.19,103.23 193.19,100.74 192.05,99.59 189.81,99.59 183.72,93.5 183.72,83.57 189.94,77.34 192.13,77.34 193.93,75.54 193.93,68.81 185.42,60.3 185.42,43.27 186.55,42.14 191.29,42.14
P5V_CONN on BOTTOM (solid shape): 193.9,37.82 193.9,36.5 191.67,34.26 190.63,34.26 190.6,34.24 189.74,34.24 189.43,34.54 189.43,36.58 191.29,38.43 193.29,38.43
P12V on TOP: 163.32,35 167.04,35 168.29,33.75 171.72,33.75 171.72,33.78 172.01,34.07 172.01,34.69 172.16,34.84 172.84,34.84 173.12,34.56 173.12,31.32 172.93,31.13 172.2,31.13 171.97,31.35 171.97,32 171.74,32.23 168.63,32.23 167.16,30.76 163.41,30.76 163.09,31.09 163.09,34.77
P12V on TOP: 69.82,33.43 71.44,33.43 71.8,33.06 71.8,31.7 71.74,31.64 69.91,31.64 69.53,32.02 69.53,33.13
P12V on TOP: 131.91,115.74 131.91,108.59 135.76,104.74 137.83,104.74 138.01,104.92 138.01,105.67 134.62,109.07 134.62,112.82 136.4,114.61 136.4,120.77 135.12,122.05 129.23,122.05 126.43,124.85 123.54,124.85 119.58,128.81 113.48,128.81 110.79,126.13 107.31,126.13 104.53,128.91 101.2,128.91 99.86,127.57 88,127.57 85.38,124.95 85.38,120.41 85.84,119.95 86.44,119.95 86.9,120.41 86.9,123.67 87.19,123.96 87.77,123.96 88.08,124.27 88.08,124.74 89.07,125.73 101.66,125.73 102.93,127 103.67,127 106.18,124.49 111.42,124.49 114.44,127.51 118.14,127.51 122.34,123.3 124.2,123.3 127.75,119.75 133.94,119.75 134.43,119.26 134.43,118.27
P12V on TOP: 4.48,60.95 6.8,60.95 7.51,60.24 7.51,55.86 7.1,55.45 4.55,55.45 4.03,55.97 4.03,60.51
P12V on TOP: 179.58,92.96 184.78,92.96 184.78,94.34 184.3,94.82 182.19,94.82 181.46,95.55 179.88,95.55 179.58,95.25 178.84,95.25 178.77,95.17 178.77,93.78
P12V on BOTTOM: 3.61,58.12 7,58.12 7.57,57.55 7.57,56.03 5.18,53.63 5.18,36.06 6.08,35.15 20.97,35.15 23.04,33.07 23.04,28.02 22.46,27.44 19.09,27.44 15.36,31.17 5.36,31.17 2.77,33.75 2.77,57.28
P12V on BOTTOM: 51.01,105.48 53.25,105.48 53.68,105.05 53.68,102.44 53.08,101.83 47.43,101.83 41.56,95.96 31.14,95.96 21.82,86.64 21.82,81.27 16.43,75.89 16.43,64.45 13.02,61.04 8.63,61.04 6.62,59.03 5.57,59.03 4.78,59.82 4.78,61.08 6.93,63.23 10.39,63.23 13.98,66.81 13.98,77.27 17.99,81.29 17.99,89.64 27.51,99.16 37.17,99.16 43.52,105.52 50.98,105.52
P12V on BOTTOM: 168.32,23.23 168.32,20.07 168.42,19.98 170.52,19.98 170.79,20.24 170.79,23.77 170.53,24.02 169.12,24.02
P12V on BOTTOM: 165.81,91.72 186.77,91.72 186.77,92.56 182.65,96.67 180.97,96.67 179.07,94.77 171.09,94.77 168.68,97.18 166.14,97.18 165.18,96.22 165.18,92.35
P12V on BOTTOM: 136.81,106.23 137.87,106.23 138.09,106.01 138.09,104.57 137.93,104.42 136.45,104.42 136.26,104.61 136.26,105.69
P12V on BOTTOM: 69.5,33.51 71.56,33.51 71.91,33.16 71.91,31.24 71.74,31.07 70.06,31.07 69.25,31.88 69.25,33.26
P12V on BOTTOM: 169.24,45.43 171.65,45.43 172.42,44.66 172.42,40.97 170.93,39.49 170.93,38.3 171.07,38.17 171.72,38.17 171.89,38.34 171.89,39.08 172.32,39.51 173.07,39.51 174.55,40.98 174.55,45.13 174.85,45.43 174.82,45.45 174.82,47.68 172.61,49.89 172.61,55.03 175.27,57.69 175.27,63.68 175.68,64.09 175.67,64.11 175.67,66.5 171.27,70.89 171.27,82.03 165.18,88.12 165.18,94.16 154.96,104.38 154.96,109.83 156,110.87 162.53,110.87 162.83,110.57 162.83,108.43 162.48,108.08 159.36,108.08 158.4,107.13 156.29,107.13 156,106.84 156,104.85 157.47,103.37 167.32,103.37 173.56,97.13 184.41,97.13 185.16,96.38 185.16,94.28 186.78,92.66 186.78,91.47 176.47,81.15 176.47,70.19 182.81,63.85 182.81,56.51 181.81,55.51 181.81,53.37 181.37,52.93 175.08,52.93 174.46,52.32 174.46,51.17 174.69,50.94 178.99,50.94 180.16,49.77 180.16,46.24 179.01,45.09 179.01,42.1 176.2,39.28 174.57,39.28 174.16,38.87 174.16,37.08 174.84,36.41 181.96,36.41 182.69,35.68 182.69,31.07 181.87,30.25 169.69,30.25 167.76,32.18 167.76,43.94
P12V on L03_SIG1: 176.18,43.3 176.18,40.41 177.44,39.15 177.44,33.07 177.75,32.75 181.62,32.75 182.1,33.24 182.1,43.12 181.64,43.58 176.46,43.58
P12V on L03_SIG1: 171.25,34.41 171.25,34.41 167.19,30.35 167.19,12.48 164.82,10.11 145.71,10.11 145.18,9.58 145.18,7.79 145.93,7.04 171.97,7.04 173.23,8.3 173.23,26.37 171.18,28.42 171.18,29.41 173.98,32.21 173.98,34.44 173.57,34.85 171.68,34.85
P12V on L05_SIG2: 145.03,11.7 170.58,11.7 171.5,10.78 171.5,9.59 170.78,8.87 145.09,8.87 144.54,9.43 144.54,11.2
P12V on L05_SIG2: 20.9,31.61 23.24,31.61 24.96,29.9 27.95,29.9 32.34,25.51 51.45,25.51 57.25,31.31 59.76,31.31 63,34.55 70.54,34.55 71.41,33.68 71.41,30.97 70.15,29.72 64.01,29.72 55.56,21.26 31.49,21.26 25.53,27.23 20.67,27.23 20.02,27.88 20.02,30.73
P12V on L05_SIG2: 130.2,25.03 130.2,21.7 130.68,21.22 133.03,21.22 133.59,21.79 171.02,21.79 171.5,22.27 171.5,25.41 170.73,26.19 131.36,26.19
P12V on L05_SIG2: 85.35,123.49 86.66,123.49 87.01,123.14 87.01,114.14 83.19,110.32 83.19,105.14 80.57,102.52 52.2,102.52 51.03,103.69 51.03,105.31 51.56,105.84 60.91,105.84 62.82,103.93 66.8,103.93 69.99,107.12 80.4,107.12 81.82,108.54 81.82,110.87 85.51,114.56 85.51,115.75 83.71,117.56 83.71,121.84
P12V on L07_PWR: 132.84,22.83 130.5,22.83 124.41,16.75 116.95,16.75 114.94,14.74 114.94,11.88 115.94,10.88 127.14,10.88 130.31,14.05 130.31,18.62 131.65,19.95 132.77,19.95 133.51,20.69 133.51,22.17
P12V on L07_PWR: 153.35,64.14 153.35,60.33 155.57,60.33 155.57,54.61 164.15,54.61 168.59,59.06 168.59,123.82 184.47,123.82 184.47,130.81 161.89,130.81 136.32,105.24 136.32,101.6 156.53,101.6 156.53,67.31
(no net) on TOP: 160.66,93.09 160.66,90.7 159.68,89.73 159.68,89.71 158.64,89.71 157.92,89 157.92,87.5 162.69,87.5 163.7,88.52 163.7,93.09
(no net) on TOP: 153.03,42.55 153.03,35.94 159.13,35.94 159.13,42.55
(no net) on TOP: 163.45,62.74 163.45,62.36 165.86,62.36 166.62,61.59 166.62,53.85 173.74,53.85 173.74,59.94 171.83,59.94 169.04,62.74
(no net) on TOP: 164.72,116.08 164.72,115.7 171.83,115.7 175.01,118.87 175.01,122.43 169.16,122.43 169.16,118.75 166.5,116.08
(no net) on TOP: 148.34,50.04 145.29,50.04 145.29,42.04 142.24,42.04 142.24,38.48 149.48,38.48 151,40.01 151,49.91 153.16,52.07 156.97,52.07 159.38,54.48 159.38,57.28 158.88,57.28 158.88,55.37 158.62,55.12 153.42,55.12
(no net) on TOP: 157.61,116.08 145.54,116.08 144.65,115.19 144.65,107.95 139.7,107.95 138.95,107.19 136.83,107.19 136.63,107.39 136.63,111.1 146.05,120.52 153.16,120.52 156.34,117.35 157.61,117.35
(no net) on TOP: 163.7,79.12 160.4,79.12 160.4,83.31 163.7,83.31
(no net) on TOP: 154.31,88.33 155.21,87.43 157.34,87.43 157.42,87.5 157.42,88.65 157.87,88.65 157.87,89.08 158.84,90.04 159.47,90.04 160.39,90.96 160.4,90.96 160.4,93.39 160.48,93.46 164.7,93.46 165.43,94.2 165.43,97.43 164.81,98.04 154.96,98.04 154.31,97.38
(no net) on TOP: 159.38,40.39 159.38,35.81 162.43,35.81 162.43,40.39
(no net) on TOP: 156.34,63.37 145.92,63.37 145.4,63.89 145.4,70.36 149.35,70.36 155.07,64.64 156.34,64.64
(no net) on TOP: 164.72,115.44 164.72,115.06 167.13,115.06 167.89,114.3 167.89,106.55 175.01,106.55 175.01,112.65 173.1,112.65 170.31,115.44
(no net) on TOP: 141.77,60.58 141.73,60.58 141.73,58.75 138.31,58.75 138.31,50.38 146.68,50.38 146.68,53.73 146.91,53.96 150,53.96 150.15,54.12 150.15,56.22 149.9,56.46 146.92,56.46 146.67,56.71 146.67,58.99 146.97,59.28 149.58,59.28 152.15,61.85 156.34,61.85 156.34,62.36 143.55,62.36
(no net) on TOP: 157.35,65.91 157.35,64.39 158.38,64.39 158.38,69.1 163.45,74.17 163.45,78.49 157.43,78.49 157.43,65.84
(no net) on TOP: 163.45,63.37 163.45,62.99 168.83,62.99 169.67,63.83 169.67,67.31 168.15,67.31 168.15,66.29 165.23,63.37
(no net) on TOP: 156.84,72.52 156.84,66.42 157.35,65.91 157.35,64.39 156.46,64.39 156.46,65.66 155.07,67.06 155.07,68.2 152.78,70.48 144.26,70.48 144.27,74.8 146.81,74.8 146.81,78.36 151,78.36
(no net) on TOP: 161.42,57.28 160.91,57.28 160.91,44.07 163.32,41.66 171.7,41.66 171.7,48.13 166.88,48.13 161.42,53.59
(no net) on TOP: 160.78,57.28 159.89,57.28 159.89,54.61 156.97,51.69 154.18,51.69 154.18,43.05 160.4,43.05 160.4,53.47 160.78,53.85
(no net) on TOP: 145.16,113.28 145.16,113.28 145.16,107.2 139.22,107.2 138.53,106.5 138.53,104.84 138.53,104.84 138.72,104.65 140.21,104.65 140.55,104.32 140.55,102.36 141.43,101.47 142.01,101.47 142.64,100.84 142.64,99.98 143.09,99.54 150.08,99.54 150.84,100.29 150.84,110.35 155.04,114.55 157.61,114.55 157.61,115.06 146.05,115.06 145.16,114.17
(no net) on BOTTOM: 147.07,77.85 150.75,77.85 150.75,80.9 147.07,80.9
(no net) on BOTTOM: 150.88,76.84 147.07,76.84 147.07,73.15 150.88,73.15
(no net) on BOTTOM: 167.77,44.83 162.31,44.83 162.31,48.64 167.64,48.64 167.77,48.51
(no net) on BOTTOM: 166.62,44.32 162.81,44.32 162.05,43.56 162.05,41.15 162.18,41.02 166.62,41.02
(no net) on BOTTOM: 144.02,70.61 144.02,65.53 140.21,65.53 140.21,70.61
(no net) on BOTTOM: 145.41,70.61 145.41,65.66 149.61,65.66 149.61,70.61
DMD_P3P3V on TOP (solid shape): 119.53,25.22 119.53,23.57 119.48,23.52 117.2,23.52 116.71,24 116.71,25.04 116.76,25.1 118.19,25.1 118.62,25.53 119.23,25.53
DMD_P3P3V on TOP: 114.34,23.57 112.95,23.57 112.58,23.2 112.58,20.17 112.62,20.12 113.75,20.12 114.03,20.4 116.48,20.4 116.64,20.56 116.64,21.55 116.32,21.87 116.32,22.47 117.22,23.37 119.89,23.37 120.07,23.55 120.07,24.94 119.4,25.61 118.6,25.61 118.29,25.3 115.18,25.3 114.72,24.84 114.72,23.94
DMD_P3P3V on BOTTOM: 119.12,32.87 121.51,32.87 121.99,32.39 122.85,32.39 123.08,32.15 124.73,32.15 124.74,32.13 124.74,31.73 125.6,30.88 126.37,30.88 126.46,30.79 126.46,30.18 126.43,30.15 125.34,30.15 125.14,30.36 123.13,30.36 122.73,29.96 122.73,21.11 120.61,18.99 114.7,18.99 113.53,20.17 113.53,22.29 113.98,22.74 115.05,22.74 115.58,23.27 115.58,23.86 117.03,25.31 118.16,25.31 118.52,25.67 118.52,32.27 ; 2 cut-outs
DMD_P3P3V on L07_PWR: 115.86,25.05 118.58,25.05 119.32,24.32 119.32,21.35 115.75,17.77 68.35,17.77 67.75,18.37 67.75,20.65 68.75,21.65 112.45,21.65
DMDP3P3VA on TOP: 118.63,22.84 119.79,22.84 120.02,22.62 120.02,20.08 119.47,19.54 119.06,19.54 118.85,19.75 118.85,21.4 118.55,21.7 118.55,22.76
DMDP3P3VA on L03_SIG1: 119.73,21.53 118.49,21.53 118.13,21.17 118.13,18.23 120.31,16.05 120.31,11.48 120.54,11.24 122.26,11.24 123.6,12.58 123.6,15.95 122.7,16.85 122.7,17.65 122.71,17.66 122.71,18.17 120.07,20.81 120.07,21.19
DMDP3P3VB on TOP: 113.7,19.52 112.64,19.52 112.61,19.48 112.61,18.39 112.76,18.23 115.55,18.23 115.64,18.32 115.64,18.95 115.53,19.06 113.9,19.06 113.74,19.22 113.74,19.48
DMDP3P3VB on L03_SIG1: 115.81,19.21 114.36,19.21 114.1,18.95 114.1,12.58 115.92,10.76 119.66,10.76 120.1,11.2 120.1,12.09 119.76,12.43 119.6,12.43 119.6,16.08 117.81,17.87 117.66,17.87 117.65,17.86 117.16,17.86
P1P1V on TOP: 85.15,84.71 102.17,84.71 102.17,67.69 85.15,67.69
P1P1V on TOP: 111.76,88.9 111.76,74.93 112.39,74.3 120.65,74.3 120.65,99.12 118.17,101.6 103.5,101.6 99.69,97.79 99.69,94.5 103.98,94.5 107.49,98.01 108.94,98.01 109.39,97.55 109.39,93.44 111.73,91.1 111.73,90.32 111.72,90.3 111.72,88.94
P1P1V on TOP: 126.37,71.12 126.37,68.58 135.89,68.58 135.89,74.3 140.69,74.3 142.6,76.2 146.05,76.2 146.05,78.74 146.69,79.38 146.69,80.65 147.32,81.28 147.32,85.72 146.69,86.36 140.34,86.36 140.34,81.91 143.51,81.91 143.51,80.01 142.88,79.38 142.24,79.38 140.34,77.47 134.62,77.47 129.54,72.39 127.63,72.39
P1P1V on TOP: 131.57,51.05 133.35,51.05 134.24,51.94 137.03,51.94 137.03,55.89 133.91,55.89 133.6,55.59 133.6,53.98 131.57,53.98
P1P1V on BOTTOM: 99.5,77.38 100.02,76.86 100.88,76.86 101.56,76.17 107.06,76.17 107.62,75.61 109.04,75.61 110.68,77.25 119.81,77.25 120.1,77.54 122.78,77.54 124.59,75.73 125.6,75.73 126.62,76.74 126.62,77.66 121.8,82.48 108.2,82.48 106.72,83.96 102.13,83.96 101.48,83.32 101.48,83.31 101.06,82.89 100.65,82.89 100.51,82.75 100.51,82.29 100.6,82.2 101.19,82.2 101.41,82.42 101.87,82.42 102.01,82.28 102.01,81.52 101.51,81.01 100.98,81.01 100.5,80.52 100.5,79.79 100.58,79.71 101.78,79.71 101.98,79.52 101.98,79.12 101.5,78.65 99.87,78.65 99.5,78.28
P1P1V on BOTTOM: 126.87,70.87 126.87,68.45 135.51,68.45 136.91,69.85 136.91,76.33 132.33,76.33
P1P1V on BOTTOM: 130.81,56.9 133.1,56.9 133.1,59.18 133.35,59.18 133.35,60.71 132.97,61.09 132.97,61.21 129.67,61.21 129.67,58.04
P1P1V on BOTTOM: 129.79,55.63 129.79,53.72 131.7,53.72 132.08,53.34 132.08,51.05 133.35,51.05 134.11,51.82 139.06,51.82 139.06,53.34 149.48,53.34 150.37,54.23 151.26,54.23 151.26,55.37 150.5,55.37 149.86,56.01 149.1,56.01 149.1,56.9 147.83,56.9 147.83,54.61 137.79,54.61 136.65,55.75 134.24,55.75 134.24,54.48 133.73,54.48 132.59,55.63
P1P1V on L03_SIG1: 129.54,58.42 132.72,58.42 135.25,60.96 135.25,75.56 129.54,75.56
P1P1V on L05_SIG2: 123.91,77.7 126.65,77.7 128.29,76.05 133.4,76.05 133.94,75.51 133.94,74.09 133.72,73.86 131.73,73.86 130.53,75.06 124,75.06 123.53,75.53 123.53,77.32
P1P1V on L07_PWR: 100.14,75.69 102.46,75.69 102.46,74.79 128.03,74.79 128.9,73.91 145.05,73.91 145.05,86.93 140.65,86.93 134.75,81.03 100.8,81.03 100.77,81 99.34,81 98.87,80.54 98.87,76.96
P1P1V on L07_PWR: 130.18,60.96 130.18,50.17 151.15,50.17 151.15,55.07 145.25,60.96
P1P8V on L07_PWR: 80.32,60.95 80.33,60.96 80.33,63.25 81.85,63.25 82.36,63.75 85.15,63.75 85.15,68.45 86.3,69.6 86.3,75.95 86.17,75.82 84.65,75.82 84.65,78.23 86.68,78.23 86.68,85.22 88.71,85.22 88.71,82.93 92.14,82.93 92.14,84.46 94.74,84.46 95,84.2 95,83.5 96.33,82.17 98.11,82.17 98.11,77.09 99.73,75.46 102.02,75.46 102.02,74.77 127.61,74.77 128.72,73.66 144.46,73.66 145.1,74.3 145.1,87 138.11,87 138.11,87.63 137.48,88.27 137.48,92.08 153.99,92.08 153.99,70.48 152.08,68.58 128.59,68.58 128.63,68.54 121.14,68.54 118.89,70.78 109.11,70.78 108.07,69.74 108.07,66.38 105.98,64.3 105.98,57.33 103.79,55.13 80.9,55.13 80.32,55.71
P2P5V on TOP (solid shape): 162.43,35.81 159.38,35.81 159.38,40.39 162.43,40.39
P2P5V on BOTTOM: 147.64,48.26 150.81,48.26 150.81,51.44 147.07,51.44 147.07,53.21 139.06,53.21 139.06,51.69 134.76,51.69 134.94,44.45 139.38,44.45 140.65,43.18 140.65,34.42 162.88,34.42 162.88,40.64 158.88,40.64 158.88,37.85 150.88,37.85 150.88,40.64 147.64,40.64 ; 1 cut-out
P2P5V_PMD2 on TOP (solid shape): 163.7,88.52 162.69,87.5 157.92,87.5 157.92,89 158.64,89.71 159.68,89.71 159.68,89.73 160.66,90.7 160.66,93.09 163.7,93.09
P2P5V_PMD2 on BOTTOM: 138.75,106.05 152.08,106.05 152.08,101.52 148.69,101.52 148.69,93.34 163.51,93.34 163.51,87.63 147.64,87.63 141.92,93.34 141.92,95.25 138.75,98.43
P3P3V on L03_SIG1: 99.93,82.89 102.25,82.89 102.62,82.52 102.62,77.06 102.11,76.56 99.6,76.56 99.33,76.82 99.33,82.28
P3P3V on L05_SIG2: 85.33,73.54 85.33,69.77 85.69,69.4 92.96,69.4 94.86,67.51 101.54,67.51 101.96,67.93 101.96,72.39 101.87,72.49 100.8,72.49 100.58,72.27 94.85,72.27 93.25,73.87 85.66,73.87
P3P3V on L07_PWR: outline of 106 points within 0.76,0.76 199.24,132.23 ; 11 cut-outs
P3P3V_EX on TOP (solid shape): 188.75,86.06 188.75,83.41 187.91,82.58 185.55,82.58 184.61,83.52 184.61,84.91 185.32,84.91 187.25,86.84 187.96,86.84
P3P3V_EX on BOTTOM: 189.99,20.9 196.8,20.9 198.13,22.23 198.13,56.1 194.77,59.46 194.77,64.57 199.06,68.86 199.06,78.08 195.05,82.09 195.05,86.03 193.9,87.17 186,87.17 185.24,86.41 185.24,83.06 186.16,82.14 191.44,82.14 193.29,80.29 193.29,78.49 195.63,76.15 195.63,71.17 189.56,65.1 189.56,54.66 195.66,48.56 195.66,29.03 194.41,27.79 190.55,27.79 188.19,25.43 188.19,22.71
P3P3V_EX on L03_SIG1: 189.53,21.11 195.07,21.11 197.46,23.5 197.46,55.98 193.19,60.25 193.19,64.82 192.1,65.91 190.45,65.91 190.2,66.17 190.2,67.61 191.57,68.99 191.57,73.18 190.83,73.91 190.83,78.28 191.26,78.71 191.26,85.8 189.46,87.6 187.55,87.6 186.54,86.59 186.54,80.98 187.2,80.31 187.2,54.13 188.7,52.63 188.7,43.38 187.96,42.65 187.96,32.33 189.28,31.01 189.28,29.34 189.94,28.68 189.94,26.52 188.39,24.97 188.39,22.25
P3P3V_EX on L05_SIG2: 125.73,22.99 126.32,22.39 126.32,18.04 128.19,16.17 153.45,16.17 154.56,15.06 177.22,15.06 181.36,19.2 190.68,19.2 192.63,21.16 192.63,22.12 190.42,24.33 185.29,24.33 182.85,21.89 174.35,21.89 173.28,20.83 171.15,20.83 171.14,20.83 130.82,20.83 129.98,21.67 129.98,25.43 128.11,27.31 123.32,27.31 122.2,26.19 119.31,26.19 116.76,23.64 116.76,21.73 117.16,21.33 120.67,21.33 122.2,22.86 122.22,22.86 122.35,22.99
PMD1K2_FB_P2P5V on TOP (solid shape): 165.43,97.43 165.43,94.2 164.7,93.46 160.48,93.46 160.4,93.39 160.4,90.97 159.47,90.04 158.84,90.04 158.76,89.97 158.53,89.97 157.67,89.11 157.67,88.65 157.42,88.65 157.42,87.5 157.34,87.43 155.21,87.43 154.31,88.33 154.31,97.38 154.96,98.04 164.81,98.04
PMD1K2_FB_P2P5V on TOP: 162.43,109.98 163.45,109.98 163.45,108.33 163.96,107.82 165.86,107.82 165.99,107.7 165.99,93.22 160.15,93.22 160.15,98.43 160.91,99.19 160.91,104.65 162.43,106.17
PMD1K_FB_MOT1 on TOP (solid shape): 169.67,63.83 168.83,62.99 163.45,62.99 163.45,63.15 163.48,63.23 163.56,63.26 163.58,63.25 164.15,63.25 164.24,63.22 164.34,63.2 164.93,63.2 165.03,63.22 165.12,63.26 165.23,63.3 165.3,63.4 165.3,63.41 165.5,63.61 165.54,63.66 165.57,63.72 168.15,66.29 168.15,67.31 169.67,67.31
PMD1K_FB_MOT2 on TOP (solid shape): 175.01,118.87 171.83,115.7 170.21,115.7 170.12,115.76 170.15,115.87 170.27,116.05 170.32,116.26 169.81,116.76 169.3,116.26 169.35,116.05 169.48,115.87 169.5,115.76 169.41,115.7 164.72,115.7 164.72,115.86 164.75,115.93 164.83,115.96 164.85,115.96 165.42,115.96 165.51,115.92 165.61,115.91 166.2,115.91 166.3,115.92 166.39,115.96 166.5,116.01 166.57,116.11 166.57,116.12 166.77,116.32 166.81,116.36 166.84,116.42 169.16,118.75 169.16,119.89 169.25,119.89 169.4,119.95 169.46,120.09 169.46,121.72 169.4,121.86 169.25,121.92 169.16,121.92 169.16,122.43 175.01,122.43
PMD1K_FB_MOT2 on BOTTOM: 168.53,126.11 171.2,126.11 171.2,117.35 168.4,117.35 168.28,117.47 168.28,125.98 168.4,125.98
PMD1K_FB_P2P5V on TOP (solid shape): 159.13,35.94 153.03,35.94 153.03,42.46 153.09,42.5 153.15,42.55 159.13,42.55
PMD1K_FB_P2P5V on BOTTOM: 154.43,42.55 158.5,42.55 158.62,42.42 158.62,38.1 154.56,38.1 154.43,38.23
PMD1K_FB_P3P3V on TOP (solid shape): outline of 276 points within 160.91,41.66 171.7,57.28
PMD1K_FB_P3P3V on BOTTOM (solid shape): 167.5,48.53 167.56,48.38 167.7,48.32 167.77,48.32 167.77,48.2 167.7,48.2 167.56,48.14 167.5,47.99 167.5,47.49 167.56,47.34 167.7,47.28 167.77,47.28 167.77,44.83 162.31,44.83 162.31,48.64 167.5,48.64
PMD1K_FB_P5V on TOP (solid shape): outline of 162 points within 144.26,64.39 157.02,78.36
PMD1K_FB_P5V on BOTTOM (solid shape): 150.88,73.15 147.07,73.15 147.07,76.84 150.88,76.84
SWNODE2_CORE on TOP (solid shape): 156.34,117.35 157.61,117.35 157.61,116.22 157.57,116.15 157.5,116.12 157.48,116.12 156.84,116.12 156.77,116.14 156.72,116.14 155,116.14 154.83,116.26 154.63,116.3 154.39,116.24 154.21,116.08 145.54,116.08 144.65,115.19 144.65,107.95 139.7,107.95 138.95,107.19 137.66,107.19 137.62,107.2 137.58,107.2 136.85,107.2 136.63,107.43 136.63,111.1 136.65,111.12 136.72,111.15 136.79,111.12 136.86,111.07 136.94,111.05 138.65,111.05 138.79,111.11 138.85,111.25 138.85,113.32 139.11,113.59 139.22,113.61 139.29,113.51 139.29,113.27 139.17,113.1 139.13,112.9 139.64,112.39 140.14,112.9 140.1,113.1 139.99,113.27 139.99,114.46 141.78,116.26 142.15,116.26 142.29,116.32 142.35,116.46 142.35,116.83 146.05,120.52 153.16,120.52
SWNODE2_P2P5V on TOP: 160.15,109.98 160.66,109.98 160.66,98.93 154.94,98.93 154.94,107.95 160.15,107.95
SWNODE_CORE on TOP (solid shape): outline of 142 points within 145.4,63.37 156.34,70.36
SWNODE_CORE on BOTTOM (solid shape): 149.61,65.8 149.26,65.8 149.06,65.77 148.9,65.66 145.41,65.66 145.41,70.61 149.61,70.61
SWNODE_MOT on TOP (solid shape): 171.83,59.94 173.74,59.94 173.74,53.85 170.07,53.85 169.74,53.98 169.4,53.85 166.62,53.85 166.62,60.82 166.89,61.11 166.98,61.49 166.74,62.07 166.17,62.31 166.07,62.3 165.97,62.28 165.94,62.28 165.86,62.36 165.24,62.36 165.18,62.4 165.1,62.41 164.53,62.41 164.44,62.45 164.34,62.47 163.45,62.47 163.45,62.74 168.94,62.74 169.04,62.74
SWNODE_MOT2 on TOP (solid shape): outline of 275 points within 164.72,106.55 175.01,115.44
SWNODE_P2P5V on TOP (solid shape): outline of 282 points within 142.24,38.48 159.38,57.28
